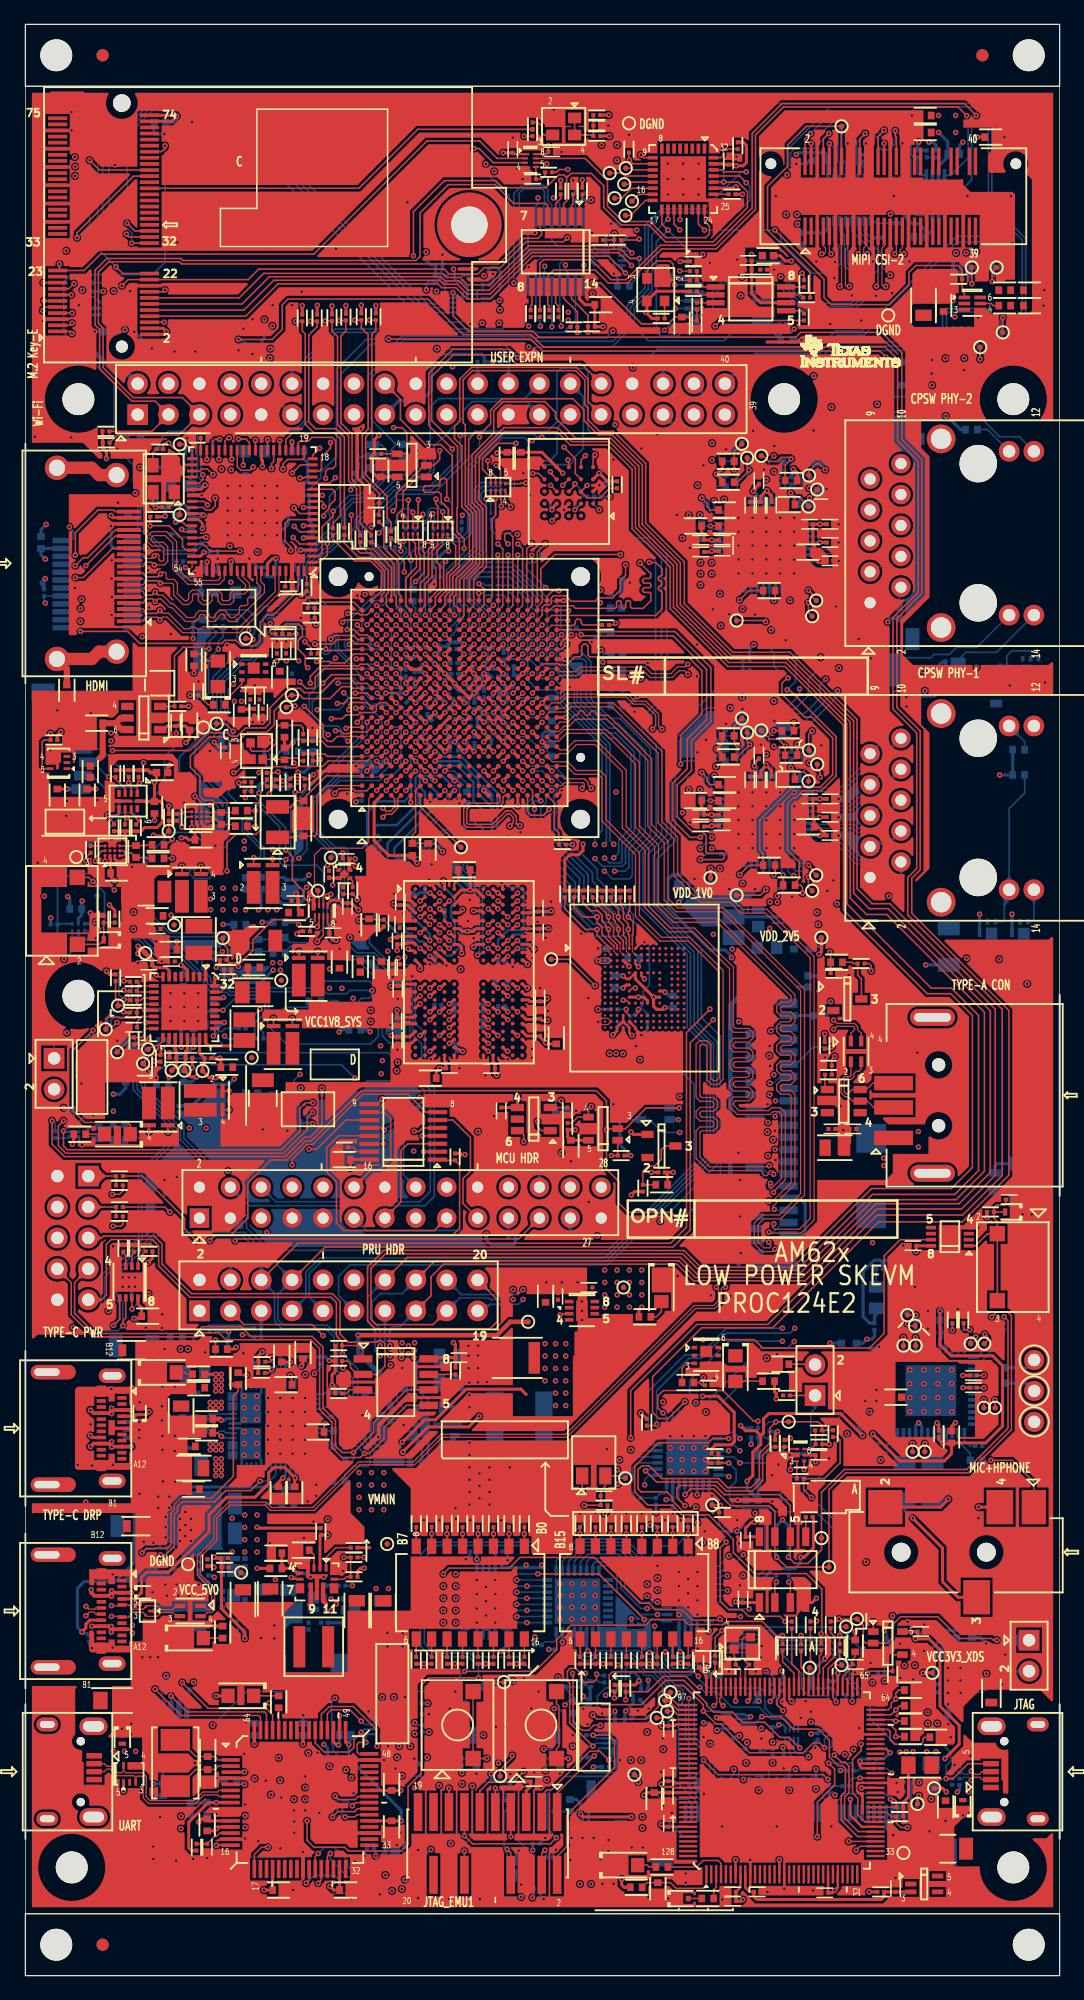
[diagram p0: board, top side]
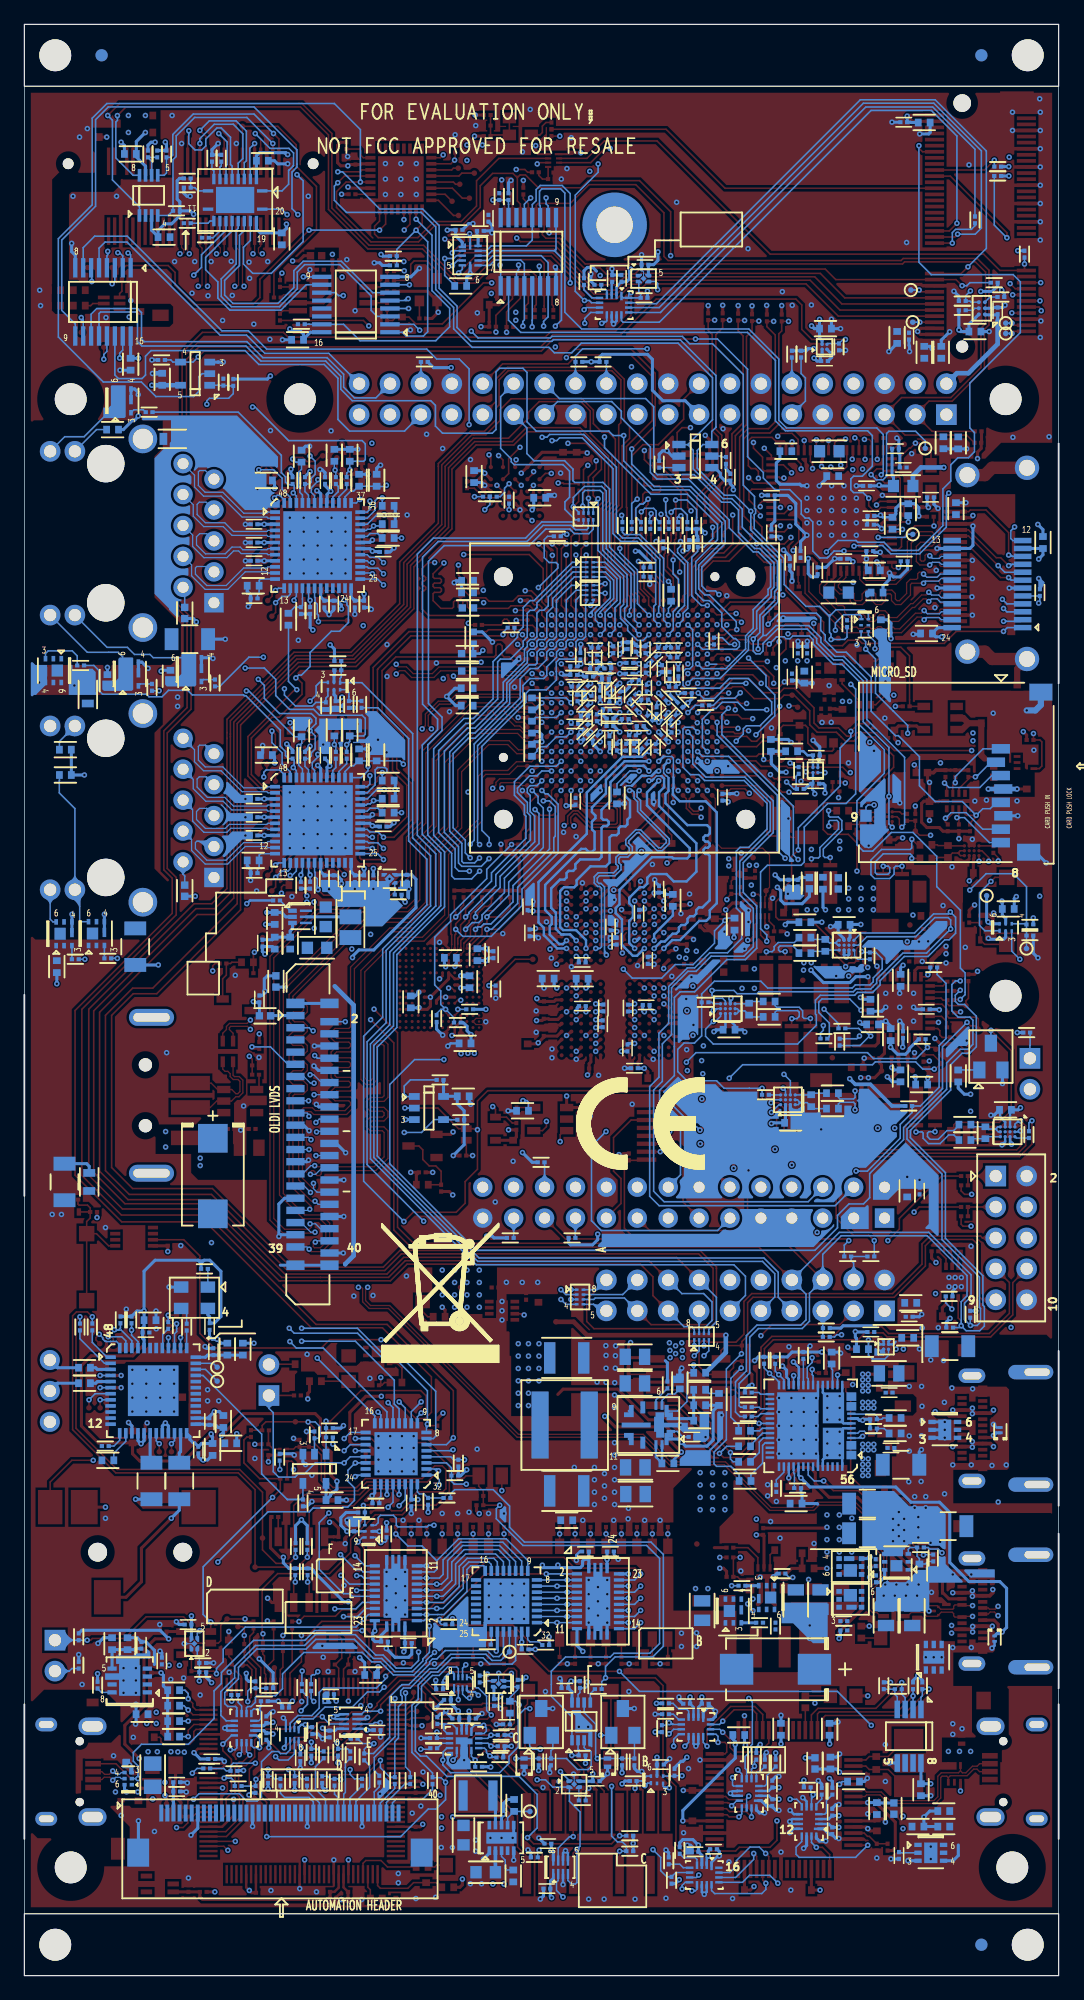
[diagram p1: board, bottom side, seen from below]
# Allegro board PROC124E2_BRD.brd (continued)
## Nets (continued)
LM61460_SW: C405.2 L9.1 U67.10(SW)
LM61460_VCC: C400.1 U67.2(VCC)
LPDDR4_CA0: U12.F5(DDR0_A0) U20.H2(CA0)
LPDDR4_CA1: U12.G5(DDR0_A1) U20.J2(CA1)
LPDDR4_CA2: U12.G4(DDR0_A2) U20.H9(CA2)
LPDDR4_CA3: U12.H4(DDR0_A3) U20.H10(CA3)
LPDDR4_CA4: U12.J5(DDR0_A4) U20.H11(CA4)
LPDDR4_CA5: U12.H5(DDR0_A5) U20.J11(CA5)
LPDDR4_CAL0: R375.1 U12.K4(DDR0_CAL0)
LPDDR4_CK_N: U12.K1(DDR0_CK0_N) U20.J9(CK_C)
LPDDR4_CK_P: U12.J1(DDR0_CK0) U20.J8(CK_T)
LPDDR4_CKE: U12.G3(DDR0_CKE0) U20.J4(CKE)
LPDDR4_CS: U12.H3(DDR0_CS0_N) U20.H4(CS)
LPDDR4_CS1_N: TP30.1(TP) U12.G1(DDR0_CS1_N)
LPDDR4_DMI0: U12.E3(DDR0_DM0) U20.C3(DMI0)
LPDDR4_DMI1: U12.R4(DDR0_DM1) U20.C10(DMI1)
LPDDR4_DQ0: U12.C2(DDR0_DQ0) U20.B2(DQ0)
LPDDR4_DQ1: U12.E4(DDR0_DQ1) U20.C2(DQ1)
LPDDR4_DQ2: U12.D3(DDR0_DQ2) U20.E2(DQ2)
LPDDR4_DQ3: U12.E5(DDR0_DQ3) U20.F2(DQ3)
LPDDR4_DQ4: U12.D2(DDR0_DQ4) U20.F4(DQ4)
LPDDR4_DQ5: U12.F3(DDR0_DQ5) U20.E4(DQ5)
LPDDR4_DQ6: U12.F1(DDR0_DQ6) U20.C4(DQ6)
LPDDR4_DQ7: U12.F2(DDR0_DQ7) U20.B4(DQ7)
LPDDR4_DQ8: U12.R3(DDR0_DQ8) U20.B11(DQ8)
LPDDR4_DQ9: U12.R2(DDR0_DQ9) U20.C11(DQ9)
LPDDR4_DQ10: U12.T2(DDR0_DQ10) U20.E11(DQ10)
LPDDR4_DQ11: U12.U2(DDR0_DQ11) U20.F11(DQ11)
LPDDR4_DQ12: U12.U3(DDR0_DQ12) U20.F9(DQ12)
LPDDR4_DQ13: U12.U4(DDR0_DQ13) U20.E9(DQ13)
LPDDR4_DQ14: U12.T4(DDR0_DQ14) U20.C9(DQ14)
LPDDR4_DQ15: U12.T5(DDR0_DQ15) U20.B9(DQ15)
LPDDR4_DQS0_N: U12.E1(DDR0_DQS0_N) U20.E3(DQS0_C)
LPDDR4_DQS0_P: U12.D1(DDR0_DQS0) U20.D3(DQS0_T)
LPDDR4_DQS1_N: U12.R1(DDR0_DQS1_N) U20.E10(DQS1_C)
LPDDR4_DQS1_P: U12.T1(DDR0_DQS1) U20.D10(DQS1_T)
LPDDR4_ODT_CA: R384.1 U20.G2(ODT_CA)
LPDDR4_RESET_N: R93.1 R94.2 U12.G2(DDR0_RESET0_N) U20.T11(RESET_N)
LPDDR4_ZQ: R100.2 U20.A5(ZQ)
LVDS_SHIELD: FL17.1 J22.SH1 J22.SH2 J22.SH3 J22.SH4
M2_LED1#: J2.6(LED_1#) TP94.1(TP)
M2_LED2#: J2.16(LED_2#) TP93.1(TP)
MCASP1_ACLKX: RA1.3 RA4.3 U12.K17(GPMC0_BE0N_CLE)
MCASP1_ACLKX_AUD: TP60.1(TP) U39.3(1B2) U66.38(BCLK)
MCASP1_ACLKX_BT: J2.8(PCM_CLK/I2S_SCK) U40.5(A4)
MCASP1_ACLKX_BUF: RA1.6 U39.4(1A) U40.7(B4)
MCASP1_ACLKX_HDMI: U11.45(SCK) U39.2(1B1)
MCASP1_AFSX: RA1.2 RA4.2 U12.P21(GPMC0_WAIT0)
MCASP1_AFSX_AUD: TP57.1(TP) U39.6(2B2) U66.39(WCLK)
MCASP1_AFSX_BT: J2.10(PCM_SYNC/I2S_WS) U40.4(A3)
MCASP1_AFSX_BUF: RA1.7 U39.7(2A) U40.8(B3)
MCASP1_AFSX_HDMI: U11.44(WS) U39.5(2B1)
MCASP1_AXR0: RA1.1 RA4.1 U12.J17(GPMC0_WEN)
MCASP1_AXR0_AUD: TP61.1(TP) U39.10(3B2) U66.40(DIN)
MCASP1_AXR0_BT: J2.12(PCM_IN/I2S_SD_IN) R281.2 U40.3(A2)
MCASP1_AXR0_BUF: RA1.8 U39.9(3A) U40.9(B2)
MCASP1_AXR0_HDMI: U11.41(SD0) U39.11(3B1)
MCASP1_AXR2: RA1.4 RA4.4 U12.K20(GPMC0_ADVN_ALE)
MCASP1_AXR2_AUD: R427.1 TP55.1(TP) U39.13(4B2)
MCASP1_AXR2_BT: J2.14(PCM_OUT/I2S_SD_OUT) U40.2(A1)
MCASP1_AXR2_BUF: RA1.5 U39.12(4A) U40.10(B1)
MCASP1_BUF_BT_EN: R10.2 U70.20(P23)
MCASP1_BUF_BT_EN_1V8: R10.1 R11.2 U40.12(OE)
MCASP1_FET_EN: R259.1 R260.2 U39.15(O\E\) U70.19(P22)
MCASP1_FET_SEL: J12.1 R172.1 U39.1(S) U70.21(P24)
MCU_GPIO0_15: J10.10 R584.2
MCU_GPIO0_15_R: R584.1 R585.2 U12.D5(MCU_MCAN1_TX)
MCU_GPIO0_16: J10.11 U12.D6(MCU_MCAN1_RX)
MCU_I2C0_SCL: J10.24 R416.2 U12.B9(MCU_I2C0_SCL)
MCU_I2C0_SDA: J10.21 R419.2 U12.A10(MCU_I2C0_SDA)
MCU_MCAN0_RX: J10.22 U12.C4(MCU_MCAN0_RX)
MCU_MCAN0_TX: J10.16 U12.C5(MCU_MCAN0_TX)
MCU_OSC0_XI: R70.2 R71.2 U12.A5(MCU_OSC0_XI)
MCU_OSC0_XO: R65.2 R66.2 U12.A6(MCU_OSC0_XO)
MCU_PORZ: R183.1 R471.2 TP71.1(TP) U12.B2(MCU_PORZ) U72.4(Y)
MCU_RESETSTATZ: J10.23 R420.1 TP20.1(TP) U12.A12(MCU_RESETSTATZ)
MCU_RESETZ: R496.2 TP82.1(TP) U12.C9(MCU_RESETZ) U81.7(1Y)
MCU_SAFETY_ERRORZ_1V8: TP36.1(TP) U12.B1(MCU_ERRORN) U19.3(A2)
MCU_SAFETY_ERRORZ_3V3: J10.26 U19.6(B2)
MCU_SPI0_CLK: J10.18 U12.B7(MCU_SPI0_CLK)
MCU_SPI0_CS1: J10.8 U12.C8(MCU_SPI0_CS1)
MCU_SPI0_D0: J10.6 U12.E8(MCU_SPI0_D0)
MCU_SPI0_D1: J10.4 U12.D8(MCU_SPI0_D1)
MCU_UART0_CTS: U12.B8(MCU_UART0_CTSN) U26.9(3A)
MCU_UART0_CTS_3V3: U26.11(3B1) U83.9(2A2)
MCU_UART0_CTS_CONN: J10.12 U26.10(3B2)
MCU_UART0_MUX_OE: R140.1 U26.15(O\E\)
MCU_UART0_MUX_SEL: J8.2 R142.2 U26.1(S)
MCU_UART0_RTS: U12.D7(MCU_UART0_RTSN) U26.12(4A)
MCU_UART0_RTS_3V3: U26.14(4B1) U83.7(1A2)
MCU_UART0_RTS_CONN: J10.17 U26.13(4B2)
MCU_UART0_RX_3V3: U26.2(1B1) U83.8(2A1)
MCU_UART0_RXD: U12.A8(MCU_UART0_RXD) U26.4(1A)
MCU_UART0_RXD_CONN: J10.13 U26.3(1B2)
MCU_UART0_TX_3V3: R516.2 U26.5(2B1) U83.6(1A1)
MCU_UART0_TXD: U12.B6(MCU_UART0_TXD) U26.7(2A)
MCU_UART0_TXD_CONN: J10.19 U26.6(2B2)
MFP0: R156.1 R426.2 U66.45(MFP0)
MFP1: R157.1 R425.2 U66.46(MFP1)
MFP2: TP58.1(TP) U66.47(MFP2)
MFP3: TP59.1(TP) U66.48(MFP3)
MIC_IN: C404.1 J14.1 R458.1 U66.12(MICDET)
MMC0_CLK: R91.1 R400.1 R401.2 U21.M6(CLK)
MMC1_CLK: J21.5(CLK) R49.1 R51.1 R88.1 U15.6(IO4)
MMC1_CLK_R: R49.2 U12.A20(MMC1_CLK)
MMC1_CMD: J21.3(CMD) R73.1 U12.C18(MMC1_CMD) U15.1(IO1)
MMC1_D0: J21.7(DAT0) R90.1 U12.A19(MMC1_DAT0) U15.8(IO6)
MMC1_D1: J21.8(DAT1) R89.1 U12.B19(MMC1_DAT1) U15.7(IO5)
MMC1_D2: J21.1(DAT2) R74.1 U12.B20(MMC1_DAT2) U15.2(IO2)
MMC1_D3: J21.2(CD/DAT3) R75.1 U12.C19(MMC1_DAT3) U15.3(IO3)
MMC1_SD_EN: R462.1 U52.1(A) U70.4(P03)
MMC1_SD_LS_EN: R61.1 U13.3(ON) U52.4(Y)
MMC1_SDCD: J21.9(CD) R67.1 U12.C15(MMC1_SDCD) U14.5(IO2)
MMC2_CLK: J2.9(SDIO_CLK/SYSCLK) R40.2 R272.1 R282.1
MMC2_CMD: R275.2 U12.C21(MMC2_CMD)
MMC2_D0: R277.2 U12.B21(MMC2_DAT0)
MMC2_D1: R276.2 U12.D21(MMC2_DAT1)
MMC2_D2: R274.2 U12.E19(MMC2_DAT2)
MMC2_D3: R273.2 U12.E20(MMC2_DAT3)
OLDI_RESETN: J22.8 R412.2 U62.4(Y)
OSC0: C154.2 U36.88(OSC0) Y3.3
OSC1: C153.2 U36.89(OSC1) Y3.1
OSPI0_CSN0: R334.2 U12.F19(OSPI0_CSN0)
OSPI0_LBCLK: R307.2 R318.1
OSPI0_LBCLKO_R: R318.2 U12.G18(OSPI0_LBCLKO)
OSPI_CLK: R309.1 R316.1 U10.B2(CLK)
OSPI_CS: R37.1 R334.1 U10.C2(C\S\)
OSPI_DQ0: R324.1 RA2.4 U10.D3(IO0)
OSPI_DQ1: R326.1 RA2.3 U10.D2(IO1)
OSPI_DQ2: R323.1 RA2.1 U10.C4(IO2/W\P\)
OSPI_DQ3: R325.1 RA2.2 U10.D4(IO3)
OSPI_DQ4: R321.1 RA3.4 U10.D5(IO4)
OSPI_DQ5: R322.1 RA3.2 U10.E3(IO5)
OSPI_DQ6: R320.1 RA3.3 U10.E2(IO6)
OSPI_DQ7: R319.1 RA3.1 U10.E1(IO7)
OSPI_DQS: R308.1 U10.C3(DS)
OSPI_DQS_SOC: R304.1 R305.1 R307.1 R308.2 U12.H20(OSPI0_DQS)
OSPI_RSTN: R35.1 U8.4(Y) U10.A4(R\E\S\E\T\)
P2_PP_EXT_ENABLE: R476.1 U68.49(GPIO17/PP_EXT2)
PD_GPIO0: R166.2 U68.16(GPIO0)
PD_HRESET: R466.1 U68.44(HRESET)
PD_M_I2C3_IRQ: R436.2 U68.23(I\2\C\3\_\I\R\Q\/GPIO7)
PD_M_I2C3_SCL: R146.1 R164.2 U68.21(I2C3_SCL/GPIO5)
PD_M_I2C3_SDA: R150.1 R161.2 U68.22(I2C3_SDA/GPIO6)
PD_MS_I2C1_IRQ: R443.2 U68.29(I\2\C\1\_\I\R\Q\)
PD_MS_I2C1_SCL: R144.1 R439.2 U68.27(I2C1_SCL)
PD_MS_I2C1_SDA: R148.1 R438.2 U68.28(I2C1_SDA)
PD_S_I2C2_SCL: R446.2 U68.32(I2C2_SCL)
PD_S_I2C2_SDA: R447.2 U68.33(I2C2_SDA)
PD_SPI_CLK: J23.7 R461.2 U30.6(CLK)
PD_SPI_MISO: J23.5 R160.2 R453.2 U30.2(DO(IO1))
PD_SPI_MOSI: J23.8 R459.2 U30.5(DI(IO0))
PD_SPI_SS: J23.9 R158.2 R464.2 U30.1(C\S\)
PD_VIN_3V3: C131.2 U68.5(VIN_3V3)
PMIC_GPO1: R577.2 U22.8(GPO1)
PMIC_INT_B: R122.1 R126.2 TP45.1(TP) U22.11(NINT)
PMIC_MODE: R117.1 R590.1 TP25.1(TP) TP42.1(TP) U12.C7(PMIC_LPM_EN0)
PMIC_POWERGOOD: R130.1 TP50.1(TP) U22.18(NRSTOUT) U89.1(A)
PMIC_STBY: R591.1 U22.31(MODE/STBY)
PORZ_OUT: R181.2 R345.1 TP18.1(TP) U12.E13(PORZ_OUT) U31.3(B) U52.6(C) U128.3(B)
PP1_CABLE: C125.1 U68.25(PP1_CABLE)
PP2_CABLE: R465.2 U68.46(PP2_CABLE)
PR0_PRU0_GPO0: J11.13 RA8.7 U12.K19(GPMC0_AD0)
PR0_PRU0_GPO1: J11.14 RA8.5 U12.L19(GPMC0_AD1)
PR0_PRU0_GPO2: J11.15 RA8.8 U12.L20(GPMC0_AD2)
PR0_PRU0_GPO3: J11.16 RA8.6 U12.L21(GPMC0_AD3)
PR0_PRU0_GPO4: J11.17 RA7.6 U12.M21(GPMC0_AD4)
PR0_PRU0_GPO5: J11.18 RA7.7 U12.L17(GPMC0_AD5)
PR0_PRU0_GPO6: J11.19 RA7.5 U12.L18(GPMC0_AD6)
PR0_PRU0_GPO7: J11.20 RA7.8 U12.M20(GPMC0_AD7)
PR0_PRU0_GPO11: J11.7 RA4.8
PR0_PRU0_GPO12: J11.9 RA4.7
PR0_PRU0_GPO14: J11.11 RA4.6
PRU_3V3_EN: R435.2 R589.1 U3.20(P23) U65.B2(ON)
PRU_DETECT: J11.3 R463.1 U70.3(P02)
PRU_INTN: J11.5 R432.2 R433.2
PRU_RESETZ: J11.4 R420.2 R421.2
PUSH BUTTON: SW1.3 U59.1(A)
RESETSTATZ: R174.1 R175.2 R403.1 R421.1 R455.1 R660.1 TP66.1(TP) U3.28(R\E\S\E\T\) U4.3(R\E\S\E\T\) U8.2(B) U12.E14(RESETSTATZ) U25.2(B) U47.2(B) U52.3(B) U62.2(B) U70.28(R\E\S\E\T\) U71.2(B)
SEL_XDS: U76.4(Y) U79.5(OE) U82.4(O\E\) U84.1(1\O\E\) U84.16(2\O\E\)
SEL_XDS110_INV: J19.8 R490.2 R492.1 U76.2(A) U80.2(A) U85.5(OE) U87.1(1\O\E\) U87.16(2\O\E\) U90.2(A) U95.4(O\E\)
SLOW_CLK: J2.50(SUSCLK_32KHZ) R1.2 R2.2
SOC_CLKIN: C16.1 R21.2 R28.2 R71.1
SOC_DVDD1V8: C86.1 C237.1 C238.1 C248.1 C293.1 C305.2 FL10.1 R121.3 U12.H9(VMON_1P8_SOC) U12.H15(VDDSHV6#H15) U12.H16(VDDSHV6#H16) U12.K15(VDDSHV1#K15) U12.K16(VDDSHV1#K16) U12.N7(VDDSHV4#N7) U12.P7(VDDSHV4#P7)
SOC_DVDD3V3: C71.1 C75.1 C236.1 C244.1 C247.1 C252.1 C259.1 C260.2 C261.1 C267.1 C272.1 C279.1 C289.1 C290.1 C291.1 R101.3 U12.F10(VDDSHV_MCU#F10) U12.F12(VDDSHV0#F12) U12.G10(VDDSHV_MCU#G10) U12.G13(VDDSHV0#G13) U12.K11(VMON_3P3_SOC) U12.N15(VDDSHV3#N15) U12.N16(VDDSHV3#N16) U12.R10(VDDA_3P3_USB) U12.R14(VDDSHV2#R14) U12.R15(VDDSHV2#R15)
SOC_EMU0: R239.2 U12.D9(EMU0) U79.2(A1) U85.2(A1)
SOC_EMU1: R238.2 U12.B10(EMU1) U79.3(A2) U85.3(A2)
SOC_GPIO1_49: R59.2 R60.1 U12.B15(MMC1_SDWP)
SOC_I2C0_SCL: J3.28 J11.6 J22.2 R125.1 R431.2 R446.1 U12.E12(I2C0_SCL) U28.6(SCL)
SOC_I2C0_SCL_PMIC: R125.2 U22.10(SCL)
SOC_I2C0_SDA: J3.27 J11.8 J22.3 R123.1 R424.2 R447.1 U12.D14(I2C0_SDA) U28.5(SDA)
SOC_I2C0_SDA_PMIC: R123.2 U22.9(SDA)
SOC_I2C1_SCL: R429.1 R474.2 TP74.1(TP) U3.29(SCL) U11.1(CSCL) U12.A17(I2C1_SCL) U16.A1(SCL) U16.C3(A1) U17.A1(SCL) U24.1(SCL) U32.7(SCLB) U48.1(SCL) U58.A1(SCL) U60.A1(SCL) U61.A1(SCL) U61.C3(A1) U63.A1(SCL) U70.29(SCL)
SOC_I2C1_SDA: R428.1 R473.2 TP72.1(TP) U3.30(SDA) U11.2(CSDA) U12.A16(I2C1_SDA) U16.A2(SDA) U17.A2(SDA) U24.6(SDA) U32.6(SDAB) U48.6(SDA) U58.A2(SDA) U60.A2(SDA) U60.B3(A0) U61.A2(SDA) U61.B3(A0) U63.A2(SDA) U70.30(SDA)
SOC_I2C1_TA_SCL: R480.2 R503.1 R540.1 U32.2(SCLA)
SOC_I2C1_TA_SDA: R479.2 R502.1 R545.1 U32.3(SDAA)
SOC_I2C2_SCL: R30.2 U4.12(SCL) U12.H18(GPMC0_CSN2)
SOC_I2C2_SDA: R29.2 U4.13(SDA) U12.H19(GPMC0_CSN3)
SOC_MMC0_CLK: R91.2 U12.Y1(MMC0_CLK)
SOC_MMC0_CMD: R398.2 U12.V3(MMC0_CMD) U21.M5(CMD)
SOC_MMC0_DAT0: R109.2 U12.V2(MMC0_DAT0) U21.A3(DAT0)
SOC_MMC0_DAT1: R111.2 U12.V1(MMC0_DAT1) U21.A4(DAT1)
SOC_MMC0_DAT2: R113.2 U12.W2(MMC0_DAT2) U21.A5(DAT2)
SOC_MMC0_DAT3: R107.2 U12.W1(MMC0_DAT3) U21.B2(DAT3)
SOC_MMC0_DAT4: R108.2 U12.Y2(MMC0_DAT4) U21.B3(DAT4)
SOC_MMC0_DAT5: R110.2 U12.W3(MMC0_DAT5) U21.B4(DAT5)
SOC_MMC0_DAT6: R112.2 U12.W4(MMC0_DAT6) U21.B5(DAT6)
SOC_MMC0_DAT7: R114.2 U12.V4(MMC0_DAT7) U21.B6(DAT7)
SOC_MMC2_CLK: R40.1 U12.E21(MMC2_CLK)
SOC_OSPI_DQ0: RA2.5 U12.F18(OSPI0_D0)
SOC_OSPI_DQ1: RA2.6 U12.G17(OSPI0_D1)
SOC_OSPI_DQ2: RA2.8 U12.F21(OSPI0_D2)
SOC_OSPI_DQ3: RA2.7 U12.F20(OSPI0_D3)
SOC_OSPI_DQ4: RA3.5 U12.G21(OSPI0_D4)
SOC_OSPI_DQ5: RA3.7 U12.H21(OSPI0_D5)
SOC_OSPI_DQ6: RA3.6 U12.G20(OSPI0_D6)
SOC_OSPI_DQ7: RA3.8 U12.J21(OSPI0_D7)
SOC_PORZ: R538.2 U72.3(B) U89.4(Y)
SOC_RGMII_MDC: R102.1 R644.1 U12.V17(MDIO0_MDC)
SOC_RGMII_MDIO: R98.1 R646.1 U12.U16(MDIO0_MDIO)
SOC_SPI0_CLK: U12.D12(SPI0_CLK) U43.4(1A)
SOC_SPI0_CS0: U12.C11(SPI0_CS0) U43.9(3A)
SOC_SPI0_D0: U12.C12(SPI0_D0) U43.7(2A)
SOC_SPI2_CLK: U12.D16(MCASP0_ACLKR) U42.7(2A) U44.8(2A1)
SOC_SPI2_CS0: U12.D15(MCASP0_AFSR) U42.4(1A) U44.6(1A1)
SOC_SPI2_D0: U12.B18(MCASP0_AXR3) U42.9(3A) U44.7(1A2)
SOC_SPI2_D1: U12.B17(MCASP0_AXR2) U42.12(4A) U44.9(2A2)
SOC_TCK: R508.1 R522.1 U12.C10(TCK)
SOC_TDI: U12.D10(TDI) U84.6(1A1) U87.9(2A2)
SOC_TDO: R359.1 U82.2(A1) U95.2(A1)
SOC_TDO_R: R359.2 U12.E10(TDO)
SOC_TMS: U12.B11(TMS) U84.8(2A1) U87.8(2A1)
SOC_TRST#: R519.1 U12.A11(TRSTN) U84.9(2A2) U87.6(1A1)
SOC_UART0_RX_3V3: U12.A13(UART0_RXD) U92.8(2A1)
SOC_UART0_TX_3V3: R554.2 U12.E11(UART0_TXD) U92.6(1A1)
SOC_UART1_CTS: TP12.1(TP) U42.10(3B2) U96.9(2A2)
SOC_UART1_CTS_BT: J2.34(UART_CTS) U44.14(1B2)
SOC_UART1_RTS: TP13.1(TP) U42.13(4B2) U96.7(1A2)
SOC_UART1_RTS_BT: J2.36(UART_RTS) U44.12(2B2)
SOC_UART1_RX_BT: J2.22(UART_RXD) U44.15(1B1)
SOC_UART1_RXD: TP9.1(TP) U42.3(1B2) U96.8(2A1)
SOC_UART1_TX_BT: R261.2 U44.13(2B1)
SOC_UART1_TXD: R566.2 TP10.1(TP) U42.6(2B2) U96.6(1A1)
SOC_USB0_DM: L5.4(OUT2) U12.AA11(USB0_DM)
SOC_USB0_DP: L5.1(IN1) U12.Y10(USB0_DP)
SOC_USB0_DRVVBUS: R166.1 R475.1 R592.1 U12.D17(USB0_DRVVBUS)
SOC_USB0_RCALIB: R366.1 U12.T8(USB0_RCALIB)
SOC_USB0_VBUS: R143.1 R145.1 U12.V10(USB0_VBUS)
SOC_USB1_DM: L4.1(IN1) U12.W8(USB1_DM)
SOC_USB1_DP: L4.4(OUT2) U12.W9(USB1_DP)
SOC_USB1_DRVVBUS: R131.1 R132.1 U12.E16(USB1_DRVVBUS)
SOC_USB1_RCALIB: R361.1 U12.V9(USB1_RCALIB)
SOC_USB1_VBUS: R118.1 R120.1 U12.U9(USB1_VBUS)
SOC_VDDSHV5_SDIO: C257.1 FL9.2 U12.F14(VDDSHV5#F14) U12.G14(VDDSHV5#G14)
SOC_VOUT0_DATA0: U11.32(D0) U12.R21(VOUT0_DATA0)
SOC_VOUT0_DATA1: U11.31(D1) U12.P18(VOUT0_DATA1)
SOC_VOUT0_DATA2: U11.30(D2) U12.R18(VOUT0_DATA2)
SOC_VOUT0_DATA3: U11.29(D3) U12.R19(VOUT0_DATA3)
SOC_VOUT0_DATA4: U11.28(D4) U12.R20(VOUT0_DATA4)
SOC_VOUT0_DATA5: U11.27(D5) U12.T20(VOUT0_DATA5)
SOC_VOUT0_DATA6: U11.25(D6) U12.T21(VOUT0_DATA6)
SOC_VOUT0_DATA7: U11.24(D7) U12.T19(VOUT0_DATA7)
SOC_VOUT0_DATA8: U11.23(D8) U12.U21(VOUT0_DATA8)
SOC_VOUT0_DATA9: U11.20(D9) U12.R17(VOUT0_DATA9)
SOC_VOUT0_DATA10: U11.19(D10) U12.T18(VOUT0_DATA10)
SOC_VOUT0_DATA11: U11.18(D11) U12.U20(VOUT0_DATA11)
SOC_VOUT0_DATA12: U11.17(D12) U12.U19(VOUT0_DATA12)
SOC_VOUT0_DATA13: U11.16(D13) U12.V21(VOUT0_DATA13)
SOC_VOUT0_DATA14: U11.15(D14) U12.U18(VOUT0_DATA14)
SOC_VOUT0_DATA15: U11.14(D15) U12.V20(VOUT0_DATA15)
SOC_VOUT0_DATA16: RA6.8 U11.13(D16) U12.N20(GPMC0_AD8)
SOC_VOUT0_DATA17: RA6.7 U11.11(D17) U12.N21(GPMC0_AD9)
SOC_VOUT0_DATA18: RA5.8 U11.10(D18) U12.M17(GPMC0_AD10)
SOC_VOUT0_DATA19: RA5.5 U11.9(D19) U12.N18(GPMC0_AD11)
SOC_VOUT0_DATA20: RA5.7 U11.8(D20) U12.N17(GPMC0_AD12)
SOC_VOUT0_DATA21: RA5.6 U11.7(D21) U12.N19(GPMC0_AD13)
SOC_VOUT0_DATA22: RA6.6 U11.6(D22) U12.P19(GPMC0_AD14)
SOC_VOUT0_DATA23: RA6.5 U11.4(D23) U12.P20(GPMC0_AD15)
SOC_VOUT0_DE: U11.33(DE) U12.T17(VOUT0_DE)
SOC_VOUT0_HSYNC: U11.34(HSYNC) U12.W21(VOUT0_HSYNC)
SOC_VOUT0_PCLK: R329.1 U12.U17(VOUT0_PCLK)
SOC_VOUT0_VSYNC: U11.35(VSYNC) U12.T16(VOUT0_VSYNC)
SOC_WARM_RESETZ: R527.1 TP89.1(TP) U12.E15(RESET_REQZ) U81.2(3Y)
SOC_WLAN_SDIO_RST: U2.7(B1) U3.24(P27)
SPI0_FET_OE: R292.2 U3.18(P21) U43.15(O\E\)
SPI0_FET_SEL: R263.1 R264.2 U3.17(P20) U43.1(S)
SPI_HOLDN: R163.2 U30.7(H\O\L\D\(IO3))
SPI_WPN: R171.2 U30.3(W\P\(IO2))
SW_2V5: L8.1 U57.5(SW)
SYS_BOOTMODE0: R191.1 SW3.1 U74.1(P00) U75.10(A8)
SYS_BOOTMODE1: R190.1 SW3.2 U74.2(P01) U75.9(A7)
SYS_BOOTMODE2: R189.1 SW3.3 U74.3(P02) U75.8(A6)
SYS_BOOTMODE3: R188.1 SW3.4 U74.4(P03) U75.7(A5)
SYS_BOOTMODE4: R187.1 SW3.5 U74.5(P04) U75.6(A4)
SYS_BOOTMODE5: R186.1 SW3.6 U74.6(P05) U75.5(A3)
SYS_BOOTMODE6: R185.1 SW3.7 U74.7(P06) U75.4(A2)
SYS_BOOTMODE7: R184.1 SW3.8 U74.8(P07) U75.3(A1)
SYS_BOOTMODE8: R199.1 SW4.1 U73.10(A8) U74.9(P10)
SYS_BOOTMODE9: R198.1 SW4.2 U73.9(A7) U74.10(P11)
SYS_BOOTMODE10: R197.1 SW4.3 U73.8(A6) U74.11(P12)
SYS_BOOTMODE11: R196.1 SW4.4 U73.7(A5) U74.12(P13)
SYS_BOOTMODE12: R195.1 SW4.5 U73.6(A4) U74.13(P14)
SYS_BOOTMODE13: R194.1 SW4.6 U73.5(A3) U74.14(P15)
SYS_BOOTMODE14: R193.1 SW4.7 U73.4(A2) U74.15(P16)
SYS_BOOTMODE15: R192.1 SW4.8 U73.3(A1) U74.16(P17)
SYSBOOT_BUF_ENZ: R175.1 R181.1 U34.1(A)
TCA6424_EXP_INT: R489.1 U74.32(I\N\T\)
TEMP_DIODE_P: TP21.1(TP) U12.F8(RSVD3)
TEST_GPIO1: Q12.1(G) R212.2 R543.1 R551.1
TEST_GPIO2: R216.2 R524.1 R526.1 U70.18(P21)
TEST_GPIO3: J16.1 R213.2 R485.1 R552.1 TP77.1(TP) U34.2(B)
TEST_GPIO4: R219.2 R520.1 R529.1 TP78.1(TP) U74.28(R\E\S\E\T\)
TEST_PORZN: R211.2 R542.1 R550.1 U72.6(C)
TEST_POWERDOWN: R207.1 R217.2 R541.1 R549.1 U59.3(B)
TEST_WARMRESETN: Q13.1(G) R218.2 R523.1 R525.1
TM4C129_TCK: TP86.1(TP) U36.100(PC0/TCK/SWCLK)
TM4C129_TDI: TP84.1(TP) U36.98(PC2/TDI)
TM4C129_TDO: TP83.1(TP) U36.97(PC3/TDO/SWO)
TM4C129_TMS: TP85.1(TP) U36.99(PC1/TMS/SWDIO)
TMP1_ADD0: R302.1 U48.5(ADD0)
TMP1_ADD1: R303.1 U48.3(ADD1)
TMP2_ADD1: R137.1 U24.3(ADD1)
TPS65219 EN: R379.1 R382.2 R405.1 TP100.1(TP) U59.4(Y)
TPS65219_GPO: R128.1 TP47.1(TP) U22.16(GPIO)
TPS65219_GPO2: R404.1 R411.2 R588.1 TP48.1(TP) U22.17(GPO2) U29.3(ON)
TPS630702_EN: R207.2 R210.1 R577.1 R578.1 U33.14(EN)
TS_INT#: J22.9 R151.2 U70.16(P17)
UART1_FET_BUF_EN: R289.1 U41.2(A) U44.1(1\O\E\) U44.16(2\O\E\) U70.11(P12)
UART1_FET_BUF_EN_INV: U41.4(Y) U42.15(O\E\)
UART1_FET_SEL: R179.1 R180.2 U42.1(S) U70.22(P25)
UART_SHIELD: J17.6(SH1) J17.7(SH2) J17.8(SH3) J17.9(SH4) R242.2
USB_DM: J2.5(USB_D-) TP95.1(TP)
USB_DP: J2.3(USB_D+) TP96.1(TP)
USB_TYPEA_EARTH: C376.1 J9.SH1 J9.SH2 R417.1
USB_TYPEACONN1_DM: J9.2(D-) L4.2(IN2) U23.5(D1)
USB_TYPEACONN1_DP: J9.3(D+) L4.3(OUT1) U23.6(D2)
USB_TYPEC1_EARTH: C387.1 J13.SH1 J13.SH2 J13.SH3 J13.SH4 R159.1
USB_TYPEC2_EARTH: C416.1 J15.SH1 J15.SH2 J15.SH3 J15.SH4 R201.1
USBC_CONN1_CC1: C121.1 D5.1(CATHODE) J13.A5(CC1) U68.24(C1_CC1)
USBC_CONN1_CC2: C120.1 D10.1(CATHODE) J13.B5(CC2) U68.26(C1_CC2)
USBC_CONN2_CC1: C139.1 D6.1(CATHODE) J15.A5(CC1) U68.45(C2_CC1)
USBC_CONN2_CC2: C138.1 D11.1(CATHODE) J15.B5(CC2) U68.47(C2_CC2)
USBC_CONN2_DM: D7.3(IO2) J15.A7(D-_1) J15.B7(D-_2) L5.3(OUT1)
USBC_CONN2_DP: D7.2(IO1) J15.A6(D+_1) J15.B6(D+_2) L5.2(IN2)
VHDMI_AVCC_1V2: C220.1 C221.1 C223.1 FB3.1 U11.60(AVCC12_1) U11.66(AVCC12_2)
VHDMI_CVCC_1V2: C197.1 C205.1 C206.1 C214.1 C215.1 C219.1 FB2.1 U11.5(CVCC12_1) U11.12(CVCC12_2) U11.26(CVCC12_3) U11.42(CVCC12_4) U11.47(CVCC12_5) U11.53(CVCC12_6)
VHDMI_IOVCC_3V3: C198.1 C213.1 C222.1 FB1.1 R41.1 R48.1 R310.1 R317.1 U11.3(IOVCC1) U11.21(IOVCC2) U11.46(IOVCC3)
VLDO_CSI_1V8: R19.1 U7.5(OUT2)
VLDO_CSI_3V3: R16.1 U7.6(OUT1)
VMAIN: C128.1 C136.1 C137.1 C147.1 C148.1 C391.1 C395.1 C406.1 C410.1 C422.1 C475.1 R203.1 R442.1 R565.1 TP73.1(TP) U33.12(VIN) U67.8(VIN1) U67.12(VIN2) U68.1(PP_HV2) U68.11(PP_HV1) U93.2(VIN)
VPHY_3V3_FT4232: C456.2 FL19.1 U37.4(VPHY)
VPLL_3V3_FT4232: C464.2 FL20.1 R251.2 U37.9(VPLL)
VPP_1V8: C68.2 TP33.1(TP) U12.F7(VPP) U18.1(OUT)
VPP_LDO_EN: R103.1 R104.1 U70.5(P04)
VSEL_SD_SOC: R127.1 TP46.1(TP) U12.M19(GPMC0_CLK) U22.12(VSEL_SD/VSEL_DDR)
WKUP_LFOSCO_XI: C62.1 U12.A2(WKUP_LFOSC0_XI) Y2.1
WKUP_LFOSCO_XO: C53.1 U12.A3(WKUP_LFOSC0_XO) Y2.2
WKUP_UART0_CTS_3V3: U12.A7(WKUP_UART0_CTSN) U91.9(2A2)
WKUP_UART0_RTS_3V3: U12.B4(WKUP_UART0_RTSN) U91.7(1A2)
WKUP_UART0_RX_3V3: U12.B5(WKUP_UART0_RXD) U91.8(2A1)
WKUP_UART0_TX_3V3: R528.2 U12.C6(WKUP_UART0_TXD) U91.6(1A1)
WL_LT_EN: R595.1 U3.9(P10)
WLAN_EN: J2.56(W_DISABLE1#) R257.1 U2.6(B2)
WLAN_EN_SOC: U2.3(A2) U12.D20(MMC2_SDCD)
WLAN_IRQ: J2.62(ALERT#) R333.1 U12.C20(MMC2_SDWP)
WLAN_SDIO_RST: J2.23(SDIO_RESET#/TX_BLANKING) R262.1 U2.2(A1)
XDS110_DIR: R509.2 U84.4(1DIR) U84.5(2DIR)
XDS110_EMU0: R250.2 U36.42(PF0) U85.7(B1)
XDS110_EMU1: R249.2 U36.43(PF1) U85.6(B2)
XDS110_TCK: U36.35(PA2/SSI0CLK) U84.14(1B2)
XDS110_TDI: U36.38(PA5/SSI0XDAT1) U84.15(1B1)
XDS110_TDO: U36.37(PA4/SSI0XDAT0) U82.7(B1)
XDS110_TMS: U36.36(PA3/SSI0FSS) U84.13(2B1)
XDS110_TRST#: U36.40(PA6) U84.12(2B2)
XDS_RSTN: R497.1 R504.1 TP79.1(TP) U36.70(R\S\T\)
XDS_SHIELD: C168.2 J18.6(SH1) J18.7(SH2) J18.8(SH3) J18.9(SH4) R241.2
XDS_USB_DM: J18.2(D-) U36.93(PL7/USB0DM) U88.5(IO4)
XDS_USB_DP: J18.3(D+) U36.94(PL6/USB0DP) U88.4(IO3)
XDS_USB_ID: J18.4(ID) R220.2 U88.2(IO2)
XDS_USB_VBUS: C163.1 C440.1 D9.2 J18.1(VBUS) R253.1 R493.1 R498.1 TP90.1(TP) U78.1(IN1) U78.2(IN2) U88.6(VCC)
XDS_VREF: C169.1 C173.2 R255.2 U36.9(VREFA+) U38.3(CATHODE)
N15951745: C5.1 R581.2 R582.2 U1.1(TRI-STATE) U1.4(VDD)
N15952254: R1.1 U1.3(OUTPUT)
N16839912: C341.1 R391.1 U58.D3(IN+)
N16839940: C371.1 R408.1 U61.D3(IN+)
N16839975: C358.1 R396.1 U60.D3(IN+)
N16856152: C157.1 U37.3(OSCO) Y4.2
N16856224: C156.1 U37.2(OSCI) Y4.1
N16857368: C474.2 U94.2(NR/FB)
N16878333: R556.2 U92.5(2DIR)
N16878339: R557.1 U92.4(1DIR)
N16878497: R124.1 TP43.1(TP) U21.H5(DS)
N16893179: R513.2 U83.5(2DIR)
N16893185: R510.1 U83.4(1DIR)
N16894003: R533.2 U91.5(2DIR)
N16894009: R534.1 U91.4(1DIR)
N16906426: C43.2 R70.1 Y1.1
N16906432: C41.2 R65.1 Y1.3
N16927060: R48.2 U11.72(CI2CA)
N16927228: R47.1 U11.69(IO_SEL)
N16927289: R32.2 U11.36(SPDIF)
N16929458: TP65.1(TP) U66.7(LINE2L+)
N16929460: TP64.1(TP) U66.8(LINE2L-)
N16929474: R427.2 U66.41(DOUT)
N16929699: C124.1 U66.4(LINE1L-)
N16929703: C126.1 U66.6(LINE1R-)
N16929744: TP69.1(TP) U66.19(HPLCOM)
N16929747: TP68.1(TP) U66.22(HPRCOM)
N16929749: TP102.1(TP) U66.35(GPIO1)
N16929751: TP103.1(TP) U66.34(GPIO2)
N16931396: R291.2 U45.B2(CL)
N16931420: R288.1 U45.C1(OC)
N16943223: R17.1 U6.2(1G)
N16947096: R27.1 U5.1(TRI-STATE)
N16990175: J24.27 R550.2
N16990176: J24.30 R551.2
N16990179: J24.31 R526.2
N16990180: J24.32 R552.2
N16990215: R200.1 U32.5(EN)
N16990246: J24.26 R549.2
N16990247: J24.28 R525.2
N16990252: J24.33 R529.2
N16994873: R494.2 U80.4(Y)
N16994875: R558.2 U90.4(Y)
N16995245: C444.1 R512.2
N16997746: R247.1 U36.59(RBAIS)
N17012627: R385.2 U57.1(EN)
N17029933: LD8.2(ANODE) R165.2
N17030208: R508.2 U84.7(1A2)
N17031262: LD9.2(ANODE) R214.2
N17078351: R225.1 SW3.13
N17078353: R226.1 SW3.14
N17078355: R227.1 SW3.15
N17078357: R228.1 SW3.16
N17078758: R231.1 SW4.11
N17078760: R232.1 SW4.12
N17078762: R233.1 SW4.13
N17078764: R234.1 SW4.14
N17078766: R229.1 SW4.9
N17078768: R230.1 SW4.10
N17078770: R235.1 SW4.15
N17078778: R236.1 SW4.16
N17078974: J16.2 R491.2
N17084256: R221.1 SW3.9
N17084257: R222.1 SW3.10
N17084258: R223.1 SW3.11
N17084259: R224.1 SW3.12
N17110597: TP34.1(TP) U55.13(VDDA1P8#13)
N17133547: FL16.2 J7.2(VCC)
N17137240: J7.11 R365.2
N17140854: R383.2 U56.3(EN)
N17153379: R92.2 R106.1
N17153381: R96.2 R106.4
N17153415: R136.1 R415.2
N17153417: R136.4 R413.2
N17153507: R84.2 R101.1
N17153509: R87.2 R101.4
N17153511: C58.2 R87.1 U16.D1(BUS) U16.D2(IN-)
N17153515: C58.1 R84.1 U16.D3(IN+)
N17153617: R121.1 R391.2
N17153619: R121.4 R388.2
N17153623: R134.1 R408.2
N17153625: R134.4 R410.2
N17153667: R129.1 R396.2
N17153669: R129.4 R399.2
N17153681: C65.1 R92.1 U17.D3(IN+)
N17153685: C65.2 R96.1 U17.D1(BUS) U17.D2(IN-)
N17153701: C374.2 R413.1 U63.D1(BUS) U63.D2(IN-)
N17153703: C374.1 R415.1 U63.D3(IN+)
N17153749: C341.2 R388.1 U58.D1(BUS) U58.D2(IN-)
N17153787: C371.2 R410.1 U61.D1(BUS) U61.D2(IN-)
N17153799: C358.2 R399.1 U60.D1(BUS) U60.D2(IN-)
N17153878: R414.1 U63.A3(ALERT)
N17153949: R392.1 U58.A3(ALERT)
N17153951: R409.1 U61.A3(ALERT)
N17154063: R397.1 U60.A3(ALERT)
N17167245: R377.2 U55.32(RX_CLK)
N17253649: L10.1 U93.9(SW)
N17253673: R559.1 TP104.1(TP) U93.7(PG)
N17253694: R565.2 U93.3(EN)
N17269599: R174.2 R178.1 U31.6(C)
N17275147: R430.2 U64.3(OUTPUT)
N17277957: C396.1 R444.2
N17285208: R342.1 U50.5(LS_OE) U50.12(CT_HPD)
N17337952: R103.2 U18.3(EN)
N17370891: R437.2 U68.17(GPIO1)
N17378539: LD10.1(CATHODE) R243.2
N17479799: R498.2 U78.8(EN)
N17479805: C429.2 R486.1 R487.2 U78.5(NR/FB)
N17479881: C152.2 R215.1 U36.68(VBAT)
N17481587: LD11.2(ANODE) R252.2
N17481598: C151.2 R493.2 U36.96(PB1/USB0VBUS)
N17481613: R220.1 U36.95(PB0/USB0ID)
N17481619: R253.2 R254.1 U36.1(PD0/AIN15)
N17481621: R246.2 R518.1 U36.60(PK7)
N17481627: R256.1 U36.3(PD2/AIN13)
N17481631: LD12.2(ANODE) R256.2
N17481633: R240.2 R507.1 U36.63(PK4)
N17481635: R245.2 R515.1 U36.61(PK6)
N17481637: R252.1 U36.4(PD3/AIN12)
N17481641: R244.2 R511.1 U36.62(PK5)
N17492093: R116.2 U19.5(OE)
N17492111: J8.1 R402.1
N17498937: R428.2 U66.2(SDA)
N17498940: R429.2 U66.1(SCL)
N17653582: Q5.3(G) R352.2
N17726648: D3.3(C) R145.2 R147.1
N17796705: Q6.3(G) R393.2
N17796716: Q7.3(G) R394.2
N17827086: J23.1 R144.2 R146.2
N17827089: J23.3 R148.2 R150.2
N17849698: C143.1 Q10.1(S1) Q10.2(S2) Q10.5(S3) Q10.6(S4) Q10.8(S5) Q11.1(S1) Q11.2(S2) Q11.5(S3) Q11.6(S4) Q11.8(S5) R477.1
N17850096: C143.2 C144.2 C425.2 Q10.3(G) Q11.3(G) R208.2 R477.2 R482.1 R484.2
N17935978: Q9.3(G) R475.2 R476.2 R478.1
N17936309: Q9.1(D1) Q9.2(D2) Q9.5(D3) Q9.6(D4) Q9.8(D5) R482.2
N18374616: R553.2 U36.49(PG0)
N18374619: R536.2 U36.50(PG1)
N18374622: R502.2 U36.81(PL0)
N18374625: R503.2 U36.82(PL1)
N18374804: J24.36 R540.2
N18374807: J24.37 R544.2
N18374810: J24.38 R545.2
N18374813: J24.39 R546.2
N18516151: R95.1 U17.A3(ALERT)
N18520654: R85.1 U16.A3(ALERT)
N18571509: R564.2 U96.5(2DIR)
N18571515: R561.1 U96.4(1DIR)
N18576337: R372.2 U55.39(GPIO_0)
N18576340: R371.2 U55.40(GPIO_1)
N18736007: C404.2 U66.14(MIC3R)
N18736028: R458.2 U66.13(MICBIAS)
N18902581: R422.2 U64.1(INH)
N18904630: LD3.1(CATHODE) Q1.1(D1) Q1.2(D2) Q1.5(D3) Q1.6(D4) Q1.8(D5)
N18904632: Q1.3(G) R60.2
N18904656: LD3.2(ANODE) R56.1
N18904815: LD7.1(CATHODE) Q3.1(D1) Q3.2(D2) Q3.5(D3) Q3.6(D4) Q3.8(D5)
N18904817: Q3.3(G) R168.2
N18904841: LD7.2(ANODE) R167.1
N19081973: R39.1 U9.1(INH)
N19082749: R34.1 U9.3(OUTPUT)
N19361213: R403.2 U22.28(MODE/RESET)
N19361868: L3.1 U22.27(LX_B3)
N19361874: L2.1 U22.29(LX_B2)
N19361880: L1.1 U22.2(LX_B1_1) U22.3(LX_B1_2)
N19361937: C69.2 D1.2 R105.2 SW1.2
N19362078: C96.1 U22.14(VDD1P8)
N19806973: R522.2 U87.7(1A2)
N20199452: D2.3(C) R118.2 R119.1
N20506305: L6.1 U33.11(L1)
N20506307: L6.2 U33.9(L2)
N20506388: R481.1 U33.6(FB2)
N20506392: R203.2 U33.1(PS/SYNC)
N20506511: C142.1 U33.3(VAUX)
N20878915: R8.2 U4.1(A0)
N20878927: R7.1 U4.2(A1)
N20878931: R25.2 U4.11(I\N\T\)
N20900570: R21.1 U6.3(Y0)
N20900572: R15.1 U6.8(Y1)
N20900574: R26.1 U6.5(Y2)
N20900809: R18.1 U6.7(Y3)
N20933818: R280.2 U44.4(1DIR)
N20933822: R278.1 U44.5(2DIR)
N20936712: J12.2 R162.2
N21016640: TP29.1(TP) U55.48(VDDA1P8#48)
N21029653: R5.2 R595.2 U2.5(OE)
N21030238: LD6.2(ANODE) R155.1
N21068099: R132.2 U23.1(EN)
N21079949: TP37.1(TP) U55.14(XO)
N21083676: R459.1 U68.37(SPI_MOSI/GPIO9)
N21083677: R453.1 U68.36(SPI_MISO/GPIO8)
N21083678: R464.1 U68.39(S\P\I\_\S\S\/GPIO11)
N21083679: R461.1 U68.38(SPI_CLK/GPIO10)
N21117349: LD5.1(CATHODE) Q8.3(COLLECTOR)
N21117357: LD5.2(ANODE) R139.1
N21117537: Q8.1(BASE) R406.2
N21197992: TP8.1(TP) U3.16(P17)
N21197993: TP7.1(TP) U3.15(P16)
N21197994: TP5.1(TP) U3.13(P14)
N21197995: TP6.1(TP) U3.14(P15)
N21197996: TP4.1(TP) U3.12(P13)
N21198784: TP3.1(TP) U3.11(P12)
N21608525: J2.32(UART_TXD) R261.1
N21763900: R570.2 U98.13(B7)
N21763905: R569.2 U98.12(B8)
N21763910: R572.2 U98.9(A8)
N21763915: R571.2 U98.8(A7)
N21834326: R217.1 U36.78(PM0)
N21834328: R211.1 U36.77(PM1)
N21834330: R218.1 U36.76(PM2)
N21834332: R212.1 U36.74(PM4)
N21834361: R216.1 U36.73(PM5)
N21834363: R213.1 U36.72(PM6)
N21834365: R219.1 U36.71(PM7)
N21834376: TP80.1(TP) U36.75(PM3)
N22163762: C507.1 R587.1 U125.B1(VOUT)
N22221349: Q15.3(G) R592.2
N22221705: C532.2 Q14.1(D1) Q14.2(D2) Q14.5(D3) Q14.6(D4) Q14.8(D5)
N22234960: Q15.1(D1) Q15.2(D2) Q15.5(D3) Q15.6(D4) Q15.8(D5) R593.1 R594.1
N22235133: Q14.3(G) R594.2
N22622854: FL22.2 J27.2(VCC)
N22622886: R628.2 U127.40(GPIO_1)
N22622904: R627.2 U127.39(GPIO_0)
N22623025: R632.2 U127.32(RX_CLK)
N22623655: TP125.1(TP) U127.48(VDDA1P8#48)
N22623691: TP126.1(TP) U127.14(XO)
N22623898: TP127.1(TP) U127.13(VDDA1P8#13)
N22624142: Q19.3(G) R629.2
N22624353: Q20.3(G) R641.2
N22624355: Q21.3(G) R651.2
N22624429: J27.11 R647.2
N22624465: R657.1 R660.2 U128.6(C)
N22727847: R316.2 U12.G19(OSPI0_CLK)

Pads without a net: D2 2; D3 2; J1 1 3 25 26 27 28 29 31 33 35 37 39; J2 21 35 37 38 40 41 42 43 44 46 47 48 49 52 53 55 58 59 60 61 64 65 66 67 68 70 71 73 SH3; J5 14; J11 10 12; J13 A2 A3 A6 A7 A8 A10 A11 B2 B3 B6 B7 B8 B10 B11; J15 A2 A3 A8 A10 A11 B2 B3 B8 B10 B11; J17 4; J19 17 18 19; J22 4 5; J23 4 6; J24 4 5 6 8 9 10 11 12 13 14 15 17 18 19 20 21 22 23 24 29 35; U3 1 2 3 4 5 6 7 8 21 22; U10 A2 A3 A5 B1 B5 C5; U12 A9 B3 C3 E6 E9 E17 H2 J2 J3 J4 K2 K5 L2 L3 L4 L5 M1 M2 M3 M4 M5 N1 N2 N3 N4 N5 P2 P4 P5 R6 T13 T14; U13 4; U14 2 3; U15 4 9; U16 B2 C2; U17 B2 C2; U20 A1 A2 A8 A11 A12 AA1 AA2 AA4 AA9 AA11 AA12 AB1 AB2 AB11 AB12 B1 B12 G11 H3 J5 K5 K8 N5 N8 P2 P4 P5 P8 P9 P11 R2 R3 R4 R9 R10 R11 T2 U2 U4 U9 U11 V2 V3 V4 V9 V10 V11 W3 W10 Y2 Y3 Y4 Y9 Y10 Y11; U21 A1 A2 A7 A8 A9 A10 A11 A12 A13 A14 B1 B7 B8 B9 B10 B11 B12 B13 B14 C1 C3 C5 C7 C8 C9 C10 C11 C12 C13 C14 D1 D2 D3 D4 D12 D13 D14 E1 E2 E3 E5 E8 E9 E10 E12 E13 E14 F1 F2 F3 F10 F12 F13 F14 G1 G2 G3 G10 G12 G13 G14 H1 H2 H3 H12 H13 H14 J1 J2 J3 J12 J13 J14 K1 K2 K3 K6 K7 K10 K12 K13 K14 L1 L2 L3 L12 L13 L14 M1 M2 M3 M7 M8 M9 M10 M11 M12 M13 M14 N1 N3 N6 N7 N8 N9 N10 N11 N12 N13 N14 P1 P2 P7 P8 P9 P10 P11 P12 P13 P14; U24 5; U27 2 3 5 6; U29 6; U35 2; U36 2 5 6 11 12 13 14 15 18 19 20 21 22 23 24 25 27 29 30 31 32 33 34 41 44 45 46 53 54 56 57 65 67 83 84 85 86 91 92 102 103 104 105 106 107 108 109 110 111 112 116 117 118 119 120 121 123 124 125 126 127 128; U37 18 19 21 22 23 24 30 32 33 34 36 43 44 45 46 55 57 58 59; U38 2 4 5; U39 14; U41 1; U43 12 13 14; U55 20 21 22 23; U58 B2 C2; U60 B2 C2; U61 B2 C2; U63 B2 C2; U66 9 10 11 27 28 29 30 31 32; U68 18 30 31 34 40 41 42 43 48 50 53 54 55; U70 23; U74 17 18 19 20 21 22 23 24; U76 1; U78 7; U86 6 7; U88 1; U93 4; U94 5; U127 20 21 22 23

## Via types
v1: diameter 0.457, hole 0.203, TOP to BOTTOM, 2718 vias

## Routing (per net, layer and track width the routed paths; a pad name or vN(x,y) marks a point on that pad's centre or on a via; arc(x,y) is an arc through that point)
3V3_SYS_EN: length 1.8
  BOTTOM w0.127: U67.7 33.09,47.28 32.15,48.22 R442.2
AGND_AUD: length 11.7
  TOP w0.254: v1(76.44,45.42) 76.11,45.09 C133.2 ; C126.2 v1(77.05,48.29) ; C124.2 v1(77.05,49.29) ; v1(74.91,45.4) 75.07,45.24 C132.2 ; J14.4 v1(78.33,38.48)
  BOTTOM w0.254: U66.20 73.66,45.15 v1(73.41,45.4) 73.16,45.15 U66.21 ; v1(76.44,45.42) 76.16,45.15 U66.15 ; C402.2 69.57,42.73 69.94,42.35 v1(70.3,42.35) 70.45,42.35 70.7,42.61 C403.2 ; C399.2 68.96,46.32 v1(69.38,46.32) 69.79,45.91 C398.2 U66.26
  vias: v1(72.7,49.76) v1(72.7,48.61) v1(72.7,47.47) v1(72.7,46.33) v1(73.84,49.76) v1(73.84,48.61) v1(73.84,47.47) v1(73.84,46.33) v1(74.98,49.76) v1(74.98,48.61) v1(74.98,47.47) v1(74.98,46.33) v1(76.12,49.76) v1(76.12,48.61) v1(76.12,47.47) v1(76.12,46.33)
DGND: length 883.2
  TOP w0.102: 47.36,78.62 47.87,78.62 U21.N2 47.88,78.11 47.3,78.11 v1(47.08,78.34) 47.36,78.62
  TOP w0.178: U2.4 40.55,148.55 v1(40.41,148.41)
  TOP w0.203: U36.10 v1(59.57,9.51) ; U36.17 v1(62.37,7.15) ; U21.N5 U21.P6 50.13,77.73 v1(50.62,77.24) ; U31.2 v1(62.82,42.75) ; U17.C1 7.35,91.69 7.99,91.04 C67.2 ; v1(50.88,84.87) 50.64,84.87 50.13,84.37 U21.A6 ; U36.80 62.37,22.68 v1(62.21,22.51) ; v1(50.88,81.86) 50.63,82.11 U21.E7 ; Y1.4 17.8,99.89 17.51,99.6 v1(17.27,99.6) ; U36.114 55.51,15.43 55.77,15.17 v1(55.77,14.94) ; U36.58 68.89,19.83 68.53,20.19 v1(68.53,20.33) ; U36.48 v1(71.61,15.83) ; U11.43 v1(14.49,121.58) ; U36.55 70.74,18.63 v1(71.06,18.31) ; D5.2 v1(9.39,47.09) ; v1(68.17,24.91) 67.97,24.71 U36.66 ; D6.2 v1(10.45,31.48) ; D7.1 v1(10.66,29.95)
  TOP w0.254: v1(13.9,115.2) 14.09,115.38 U11.55 ; v1(9.5,87.88) 9.5,87.44 9.91,87.04 C77.1 ; U21.G5 49.38,81.36 v1(49.13,81.11) ; U12.P15 v1(38.47,108.53) ; U12.W10 42.07,104.14 v1(42.47,104.54) U12.Y11 ; U12.K6 v1(34.47,100.54) U12.J6 ; v1(40.93,123.4) 40.83,123.4 40.73,123.5 C18.2 ; v1(55.9,42.38) 56.17,42.11 R180.1 ; J5.5 v1(7.12,113.24) ; U20.N9 v1(38.84,81.11) ; R206.2 v1(20.1,35.49) ; v1(78.29,136.18) 78.44,136.18 78.47,136.2 U7.4 ; v1(61.76,51.03) R162.1 61.26,50.22 61,49.97 57.62,49.97 57.54,50.05 57.54,50.05 57.3,50.29 Q3.4 Q3.7 56.05,49.61 v1(56.6,49.06) 56.41,48.86 R170.1 ; U12.A4 v1(27.16,99.34) ; C55.2 54.59,95.97 C52.2 ; C55.2 55.23,95.34 C60.2 ; C55.2 54.87,95.35 54.62,95.1 v1(54.62,94.7) ; v1(1.46,135.9) 1.6,136.04 J2.7 ; U20.V12 40.87,78.19 40.98,78.07 41.38,78.07 41.72,77.73 C97.1 42.69,77.73 v1(42.94,77.48) 42.96,77.5 C98.2 ; U12.AA12 44.1,105.74 44.19,105.82 v1(44.72,105.82) ; v1(68.17,24.91) 68.52,25.26 C152.1 ; v1(21.98,101.28) 21.54,100.84 C43.1 21.3,100.84 C41.1 ; C141.2 v1(58.63,35.48) ; R143.2 v1(51.44,65.97) ; U11.70 v1(21.91,114.53) 21.91,114.11 21.88,114.08 R47.2 ; v1(13.06,96.32) 13.76,96.32 14.08,96 U16.B3 ; U20.AB3 v1(33.32,75.26) 32.78,74.73 C106.2 ; C54.1 v1(10.61,94.88) ; v1(27.46,85.74) 27.46,85.82 R115.2 29.1,85.82 C533.2 ; J1.SH1 v1(61.67,146.14) ; Y3.2 60.24,26.81 v1(60.51,27.08) 60.51,28.24 60.17,28.58 58.44,28.58 58.24,28.39 Y3.4 ; R194.2 48.12,37.73 v1(48.46,38.06) 48.46,39.19 48.25,39.4 C140.1 ; U20.G1 30.63,85.34 C83.1 30.17,85.26 v1(30.01,85.1) ; C82.2 17.53,85.33 18.26,86.05 18.64,86.05 v1(18.75,86.16) ; v1(59.75,119.74) 59.53,119.96 C586.2 ; U20.Y1 31.71,76.56 C99.1 30.57,76.09 30.57,76.09 v1(30.57,76.05) ; C153.1 v1(57.82,24.98) ; R195.2 v1(49.39,37.96) ; U12.T9 v1(39.27,103.73) U12.T10 ; U20.T8 v1(38.04,79.16) ; U11.63 v1(18.41,116.38) ; U20.W9 v1(38.84,77.21) ; v1(74.31,11.84) C168.1 72.51,10.42 TP92.1 ; J2.57 v1(1.51,148.54) ; v1(35.67,74.53) 35.67,74.52 C104.1 35.12,74.91 35.24,75.03 U20.AB5 ; C587.2 64.17,117.78 63.84,117.46 C566.2 ; U33.10 23.96,32.72 23.94,32.75 ; v1(41.87,143.14) 41.63,143.37 U4.7 ; U20.T10 v1(39.64,79.16) ; C162.2 52.3,14.05 v1(52.41,13.93) 52.59,13.93 52.85,14.18 C161.2 ; J2.SH2 v1(1.56,154.14) ; J2.39 v1(1.51,144.04) ; U12.Y6 v1(42.47,101.33) ; SW6.1 41.11,17.39 v1(41.82,16.68) ; R633.1 62.27,120.34 62.04,120.11 v1(62.04,119.74) ; C57.2 66.41,95.14 v1(66.83,95.14) ; v1(33.39,91.26) 33.09,91.56 R94.1 ; v1(9.88,78.29) 9.88,78.29 U22.15 ; U20.J12 41.23,84.04 v1(41.69,83.57) ; U20.G5 v1(34.84,85.66) ; U24.2 44.06,70.35 44.45,70.74 R137.2 44.96,70.74 v1(45.25,71.03) ; U12.M11 U12.N12 v1(37.67,106.13) U12.P13 v1(37.67,106.94) ; U12.M11 U12.L12 v1(35.27,106.13) U12.K13 v1(34.47,106.93) 34.47,106.94 U12.J14 v1(33.67,107.73) ; U12.M11 v1(36.87,105.33) ; U12.F4 v1(31.27,98.94) ; R247.2 v1(76.05,19.58) ; U12.L16 v1(36.07,109.34) ; C103.1 16.06,75.27 v1(15.98,75.35) C102.2 ; v1(13.71,74.58) 13.73,74.59 C101.2 ; v1(72.97,24.33) 73.22,24.07 R240.1 R244.1 R245.1 R246.1 ; C14.2 75.46,139.01 75.45,139.02 75.45,139.07 75.7,139.33 R13.2 ; C14.2 75.15,137.96 C13.2 72.66,137.96 72.27,137.58 72.27,136.61 72.02,136.35 TP11.1 ; C14.2 76.16,137.65 v1(76.25,137.57) ; R198.2 v1(52.57,37.4) R197.2 ; C6.1 58.33,149.3 v1(58.43,149.4) ; v1(30.33,88.83) 30.33,88.73 30.59,88.48 C72.1 31.5,88.48 U20.C1 ; C39.2 v1(5.38,103.68) ; U37.1 v1(18,18.21) ; R5.1 v1(40.87,147.55) ; U12.F11 v1(32.07,104.54) ; C51.2 66.41,96.64 v1(66.83,96.64) ; U20.C5 35.67,88.36 v1(36.52,88.36) 36.94,87.94 U20.C8 ; J19.12 v1(37.35,6.28) ; U12.P16 v1(38.47,109.33) ; U20.G12 42.09,85.34 C80.1 42.57,85.42 v1(42.75,85.24) ; U37.13 15.82,12.21 v1(15.69,12.08) 15.5,11.89 C165.1 ; v1(30.01,78.08) C95.1 30.94,78.08 31.04,78.19 U20.V1 ; U12.V11 41.27,104.93 v1(40.87,104.53) U12.U10 ; C84.1 v1(11.48,84.93) ; C69.1 5.57,87.05 v1(5.34,87.27) ; C11.1 v1(61.53,140.11) ; R77.1 62.27,97.79 62.04,97.55 v1(62.04,97.18) ; U20.G10 v1(38.84,85.66) ; U20.E12 41.54,86.64 41.63,86.55 v1(42.09,86.55) ; R140.2 25.73,67.83 C113.1 25.73,66.37 v1(25.49,66.13) ; C158.2 52.42,16.54 v1(52.24,16.72) ; U20.J1 31.86,84.19 31.6,84.19 v1(31.45,84.34) ; v1(25.74,18.93) 25.59,18.93 25.32,19.2 U37.51 ; R637.1 R631.1 57.94,118.31 57.88,118.25 57.88,118.23 57.55,117.91 C569.2 C577.2 ; v1(36.13,67.43) 35.84,67.43 35.75,67.52 R142.1 ; U5.2 v1(52.53,140.22) ; v1(9.26,83.17) 9.28,83.17 9.46,82.99 C87.2 ; R254.2 51.42,6.66 v1(51.19,6.44) ; C174.2 64.92,6.81 v1(64.73,7) ; v1(32.27,10.32) J19.20 v1(32.27,6.36) ; C149.2 58.98,31.8 v1(58.72,32.05) ; U12.J12 v1(33.67,106.13) ; U12.F13 v1(31.27,106.13) ; v1(77.42,146.14) J1.SH3 v1(71.37,146.14) J1.SH2 ; v1(22.98,45.16) 23.48,44.65 C130.2 ; v1(50.2,76.34) 49.74,76.34 49.13,76.95 U21.P4 ; U12.P3 v1(37.67,98.93) ; U20.V8 v1(38.04,77.86) ; v1(7.56,76.79) 7.56,77.38 8.06,77.88 C96.2 ; U37.25 v1(22.82,10.15) ; U12.V19 v1(41.67,111.73) ; U12.W13 v1(42.47,106.93) 42.87,107.33 U12.Y14 ; U21.K8 51.13,80.08 50.85,80.36 v1(50.38,80.36) U21.J5 ; C164.2 52.85,13.07 v1(53.13,13.35) ; J18.5 v1(77.67,18.05) ; v1(32.87,106.94) U12.H13 v1(32.87,106.13) ; 23.94,32.75 24.5,32.75 v1(24.52,32.72) ; 23.94,32.75 v1(23.44,32.75) ; J2.45 v1(1.51,145.54) ; v1(7.18,41.95) J13.A12 v1(8.7,41.95) ; J1.24 v1(72.08,150.47) ; LD6.1 v1(53.6,57.46) ; v1(79.82,151.69) C4.2 v1(80.46,151) ; v1(39.27,105.34) U12.T12 v1(40.07,106.13) ; v1(34.6,82.95) 34.6,83.17 34.44,83.34 U20.K4 34.04,83.71 33.72,84.04 U20.J3 ; U18.5 25.89,90.15 U18.2 24.99,90.15 C68.1 ; v1(18.06,11.26) 18.01,11.21 U37.15 ; C574.2 66.41,117.69 v1(66.83,117.69) ; C59.2 C56.2 57.55,95.35 57.88,95.68 57.88,95.69 57.94,95.75 R83.1 R81.1 ; C568.2 60.44,120.19 v1(60.9,119.74) 61.33,120.17 C565.2 ; R153.2 R152.2 7.31,60.01 v1(7.2,59.9) ; C66.2 v1(26.09,92.2) ; C10.1 C8.1 59.06,140.93 v1(58.5,140.93) ; v1(10.73,84.95) 10.55,85.12 C79.1 ; U27.4 v1(78.33,61.44) ; C49.1 5.84,96.48 5.91,96.54 v1(5.93,96.54) ; C63.2 66.41,93.64 v1(66.83,93.64) ; U29.5 46.78,53.85 v1(45.74,53.85) ; U20.E5 36.36,86.64 v1(36.37,86.62) 36.39,86.64 U20.E8 ; R176.2 61.62,44.47 61.81,44.66 v1(61.81,44.69) ; C172.2 C175.2 57.41,6.12 v1(57.28,6.25) ; J13.B12 6.88,48 v1(7.07,48.19) 7.32,47.95 J13.A1 8.45,47.95 v1(8.77,48.27) ; U20.D9 v1(38.04,87.61) ; v1(8.76,91.06) 8.76,90.82 8.51,90.56 C67.2 ; v1(30.42,17) 30.1,16.68 C160.1 ; U12.M18 v1(36.87,110.93) ; v1(8,57.34) 7.76,57.58 U28.4 ; C18.2 C17.1 ; C18.2 42.43,124.13 U10.E5 ; C7.1 v1(44.07,149.78) ; v1(18.28,82.1) C89.1 ; v1(66.83,119.19) 66.41,119.19 C584.2 ; U12.F9 v1(32.07,102.94) ; v1(32.44,86.96) 32.52,86.96 U20.D2 ; C163.2 v1(75.62,12.71) ; D3.1 49.97,69.09 v1(49.77,69.29) ; U10.C1 v1(47.16,122.4) ; U12.H1 v1(33.27,96.4) ; U20.Y5 v1(34.84,76.56) ; C47.2 61.33,97.61 v1(60.9,97.18) 60.44,97.64 C46.2 ; v1(52.58,80.77) 52.58,80.77 52.49,80.86 U21.H10 ; J19.16 v1(34.81,6.28) ; U32.4 64.65,30.64 v1(65.01,31) ; v1(49.62,82.89) 49.14,83.36 U21.C4 ; U30.4 27.74,46.07 v1(27.71,46.03) ; v1(1.51,153.04) J2.75 v1(3.79,153.04) ; v1(70.55,23.05) 70.78,22.82 70.78,22.46 70.54,22.23 U36.64 ; C100.2 v1(11.85,75.8) ; U12.T3 39.31,98.17 v1(39.31,98.15) ; U12.M16 v1(36.87,109.33) ; v1(20.43,51.71) 20.73,51.71 C121.2 ; v1(41.64,76.11) 41.32,76.43 41.3,76.43 U20.Y12 ; U12.R5 v1(39.27,100.53) ; C115.2 72.19,59.95 72.19,59.96 v1(72.15,59.96) ; U20.N11 v1(40.44,81.11) ; 67.14,69.54 C109.2 ; 67.14,69.54 66.98,69.7 v1(66.98,71.42) 66.58,71.83 U23.2 ; 67.14,69.54 67.23,69.44 v1(67.22,69.44) 67.32,69.54 C110.2 67.73,68.4 C111.2 ; v1(53.54,119.96) 53.54,119.32 53.8,119.06 C572.2 ; 66.82,82.19 66.82,81.58 D2.1 ; 66.82,82.19 66.86,82.16 v1(67.67,82.16) ; 66.82,82.19 66.73,82.28 R120.2 ; C61.2 63.84,94.9 64.17,95.22 C50.2 ; R11.1 46.92,142.79 v1(46.57,143.14) ; U13.2 11.87,103.29 11.97,103.2 C38.2 13.42,103.2 C40.2 v1(14.28,103.28) ; v1(8.7,32.95) J15.A1 v1(7.18,32.95) 6.29,32.95 J15.B12 ; C3.1 v1(40.06,150.95) ; U20.A10 v1(39.14,89.74) ; U12.P6 v1(38.47,100.54) ; U12.W7 v1(41.67,102.13) ; v1(15.61,92.8) 15.4,92.8 C64.2 14.92,93.83 14.81,93.94 14.81,94.33 14.48,94.66 U16.C1 ; v1(3.79,151.54) J2.69 v1(1.51,151.54) ; v1(20.66,109.58) 20.67,109.57 C26.2 C27.2 21.43,109.57 v1(21.42,109.58) ; R156.2 76.19,54.48 76.44,54.73 v1(76.62,54.73) 76.89,54.73 77.1,54.52 R157.2 ; U12.T15 v1(40.07,108.53) ; C573.2 66.41,116.19 v1(66.83,116.19) ; v1(54.62,117.26) 54.62,117.65 54.87,117.91 C576.2 ; R183.2 58.18,38.04 58.48,37.74 v1(58.48,37.41) ; U20.P12 41.06,80.57 C93.1 v1(42.29,81.11) ; U12.D11 v1(30.47,104.54) ; C78.2 30.76,86.97 31.01,87.22 v1(31.04,87.22) ; C169.2 v1(71.51,8.02) 71.67,8.18 U38.1 ; v1(1.7,83.59) 1.73,83.62 SW1.1 ; R196.2 v1(50.66,37.96) ; U37.11 15.77,13.21 v1(15.69,13.29) 15.69,13.46 15.94,13.71 U37.10 ; C53.2 C62.2 ; v1(22.63,111.5) 22.63,111.5 R51.2 ; J5.11 v1(7.09,116.24) ; C90.1 30.18,82.01 v1(30.18,82.01) 30.12,82.01 29.82,82.31 C88.2 ; U12.K3 v1(35.27,98.13) ; U12.R8 39.27,102.14 v1(39.27,102.13) ; C159.2 42.38,15.64 v1(42.38,15.45) ; R184.2 v1(32.75,37.4) R185.2 v1(34.02,37.4) R186.2 ; J1.12 v1(67.58,150.47) ; C5.2 v1(47.9,151.94) ; U12.G9 v1(32.87,102.94) ; C135.2 65.78,42.75 v1(66.05,42.48) ; C171.1 v1(26.8,6.33) ; U12.L14 v1(36.07,107.73) ; R191.2 R190.2 v1(39.1,37.4) R189.2 ; U12.AA21 v1(44.24,112.94) ; U12.T6 v1(39.27,101.34) U12.R7 ; Q4.3 v1(47.79,43.24) ; v1(26.45,97.08) 26.91,97.08 27.05,96.94 U12.A1 ; U20.K2 v1(33.24,83.06) ; v1(55.33,146.28) 55.81,145.8 U3.25 ; 19.23,105.8 19.24,105.79 C34.1 C33.2 18.48,105.77 18.48,105.78 ; U20.K9 v1(38.84,83.71) ; R66.1 v1(23.6,102.47) ; R7.2 45.01,147.44 v1(45.01,147.44) ; U20.G8 36.96,85.34 v1(36.84,85.21) ; C155.1 52.4,19.52 v1(52.4,19.52) ; U12.J10 v1(34.47,104.53) ; U20.T5 v1(34.84,79.16) ; C81.1 25.55,86.48 v1(25.49,86.54) ; R187.2 v1(36.56,37.4) R188.2 ; C15.1 v1(47.77,136.56) ; v1(12.07,125) 12.24,124.84 U9.2 ; R237.1 v1(71.91,24.45) ; U12.J16 v1(33.67,109.33) ; v1(8.61,138.34) 9.06,138.79 J2.18 ; J5.17 7.23,119.24 v1(7.04,119.05) ; R199.2 v1(53.87,37.4) ; U12.U5 v1(40.07,100.53) ; U12.R16 v1(39.27,109.33) ; C48.1 v1(3.42,96.48) ; U20.A3 v1(33.2,90.01) ; U12.Y4 v1(43.27,98.94) ; Y1.2 19.96,101.24 v1(20.18,101.46) ; U20.J10 v1(39.64,84.36) ; R201.2 9.91,36.83 v1(11.53,36.83) ; C44.2 60.29,100.68 60.37,100.76 60.37,101.04 v1(60.44,101.11) ; C2.2 C1.2 v1(72.86,152.77) ; C75.2 22.43,87.49 C71.2 22.43,88.67 v1(22.25,88.85) ; U20.AB10 v1(39.64,75.26) ; v1(44.27,120.38) 44.27,120.5 U10.B3 ; U20.N4 v1(34.04,81.11) ; J13.B1 v1(5.48,41.9) ; v1(5.48,26.9) J15.B1 6.29,26.95 v1(7.18,26.95) J15.A12 v1(8.7,26.95) ; C151.1 55.46,26.01 55.46,26.63 55.26,26.83 v1(55.26,26.86) ; U20.W11 v1(40.44,77.21) ; C170.1 v1(22.01,7.03) ; C107.2 v1(19.52,69.5) ; J5.8 v1(7.09,114.74) ; v1(22.89,35.93) 22.61,35.93 22.35,35.68 C142.2 22.35,34.55 23.21,33.69 U33.4 ; C154.1 v1(60.03,24.98) ; v1(43.2,88.21) 42.96,88.21 42.7,87.95 C74.2 42.14,87.94 U20.C12 ; D9.1 v1(77.05,13.16) ; v1(25.49,87.49) 25.95,87.49 25.99,87.53 C73.2 ; v1(37.8,73.95) 38.03,74.17 C105.1 37.64,74.89 U20.AB8 ; C119.2 11.1,54.16 v1(11.25,54.31) ; v1(35.27,104.53) U12.L10 ; SW5.1 v1(34.25,16.77) ; v1(15.8,116.36) 15.41,115.97 U11.57 ; U12.AA15 v1(44.37,108.13) ; J2.1 v1(1.51,134.54) ; U12.A21 v1(27.27,113.33) ; v1(23.2,38.95) 22.97,39.17 C139.2 21.59,39.17 21.58,39.18 C138.2 ; C42.2 15.74,100.31 15.46,100.59 v1(15.17,100.59) ; U20.V5 v1(34.84,77.86) ; C125.2 20.93,47.98 20.95,47.96 v1(20.95,47.44) ; R192.2 v1(45.58,37.96) ; J9.4 v1(73.31,75.8) ; U14.4 v1(2.04,100.65) ; v1(56.25,140.67) 55.69,140.67 55.57,140.79 C9.1 ; v1(69.45,25.68) 69.68,25.91 U34.3 ; v1(43.42,153.27) 43.42,152.48 ; U17.C3 7.35,93.08 v1(7.1,93.33) 6.95,93.18 U17.B3 ; U12.Y3 v1(43.27,98.14) ; U12.P1 v1(37.67,97.34) ; U20.P3 v1(33.24,80.46) ; v1(1.02,91.39) 1.73,90.68 SW1.4 ; U12.AA9 v1(44.41,103.34) ; U12.U8 40.07,102.93 v1(40.07,102.94) ; SW5.4 v1(35.32,23.33) ; v1(31.79,82.07) 31.21,82.07 30.78,82.5 C91.1 ; C120.2 v1(22.16,51.65) ; v1(36.87,100.54) U12.M6 v1(36.07,100.53) U12.L6 ; U12.L1 v1(35.67,96.27) ; J1.16 v1(69.08,150.47) ; C108.1 38.66,70.74 v1(38.51,70.59) ; U12.T7 v1(40.07,101.34) ; U20.P1 31.04,80.79 31,80.75 C92.1 v1(30.61,80.21) ; SW6.4 v1(42.18,23.33) ; U20.W4 v1(34.04,77.21) ; R59.1 v1(14.23,106.29) ; U37.5 v1(15.72,16.21) 15.46,15.95 C157.2 v1(14.24,15.95) ; U12.V14 41.27,107.33 v1(40.87,106.93) U12.U13 ; C150.2 v1(73.87,28.84) ; U20.Y8 v1(38.04,76.56) ; U6.4 v1(57.82,136.74) ; U33.15 25.95,33.06 v1(26.12,33.23) ; C45.2 59.53,97.41 v1(59.75,97.18) ; J19.10 v1(38.62,6.28) ; U12.F15 v1(31.27,108.53) ; v1(83.67,137.16) R20.2 C12.2 v1(83.74,138.43) ; R193.2 v1(46.85,37.96) ; U12.N6 v1(37.67,100.54) ; U20.P10 v1(39.64,80.46) ; U20.G3 v1(34.04,85.01) ; v1(42.94,79.23) 42.4,79.23 C94.1 42.2,79.26 41.26,79.26 41.15,79.37 40.98,79.37 40.87,79.49 U20.T12 ; U12.N14 v1(37.67,107.73) ; U12.G6 v1(32.07,101.33) ; U20.D11 v1(40.44,87.61) ; J2.33 v1(1.51,142.54) ; U20.W2 v1(32.44,77.21) ; U20.D4 v1(34.04,87.61) ; U12.M9 v1(36.07,102.94) ; U20.T3 v1(33.24,79.16) ; U20.T1 v1(32.44,79.81) ; R32.1 v1(13.3,126.28) ; U15.5 v1(6.89,96.47) ; U12.G16 v1(32.07,109.33) ; U20.K11 v1(40.04,82.85) ; C85.2 v1(11.21,83.3) ; C563.2 60.29,123.23 60.37,123.31 60.37,123.44 60.62,123.7 v1(60.71,123.7) ; U26.8 v1(35.05,71.57) ; C173.1 v1(60.99,6.88) ; U20.N2 v1(32.44,81.11) ; R131.2 v1(65.71,75.41) ; J1.SH4 v1(81,146.14) ; v1(32.19,125.23) 32.43,124.99 U8.3 ; J2.51 v1(1.51,147.04) ; U12.K8 v1(34.47,102.14) ; v1(49.6,151.19) R4.2 ; v1(53.27,135.16) 53.35,135.24 R28.1 54.34,135.24 54.48,135.38 C16.2 ; C156.2 v1(14.24,18.98) ; U37.35 29.4,11.71 29.42,11.73 C166.1 v1(30.82,11.73) ; U12.P10 v1(37.67,103.74) ; U12.AA1 v1(44.07,97.33) ; U12.D4 v1(29.67,99.73) ; U12.E2 v1(30.47,97.34) ; LD12.1 v1(52.82,6.33) ; R241.1 v1(80.25,23.91) ; U37.47 v1(29.48,17.71) ; C112.2 v1(44.83,66.89) ; J2.63 v1(1.51,150.04) ; C167.1 v1(14.95,9.66) ; J5.2 v1(7.09,111.74) ; U12.H6 v1(32.87,100.54) ; U12.D19 v1(29.67,111.73)
  TOP w0.305: C78.2 31.18,86.61 31.2,86.64 U20.E1
  TOP w0.381: v1(25.82,84.33) 25.82,84.28 25.81,84.27 C86.2
  TOP w0.508: FL6.1 2.62,104.32 v1(2.62,103.91)
  BOTTOM w0.086: 71.71,27.27 U76.3 ; v1(39.86,16.55) 39.82,16.51 U90.3 ; U41.3 34.11,139.93 34.27,140.09 ; U80.3 v1(46.02,24.83)
  BOTTOM w0.178: U85.4 63.51,20.96 v1(63.72,21.17) ; U79.4 48.64,23.44 48.5,23.3 47.96,23.3 v1(47.69,23.03)
  BOTTOM w0.203: v1(4.66,68.23) 4.65,68.23 4.39,68.49 U63.C3 ; U92.10 21.9,12.86 v1(22.1,12.66) 21.9,12.46 U92.11 ; U95.6 40.73,10.06 v1(40.53,10.26) 40.33,10.06 U95.5 ; U95.3 v1(40.73,7.48) ; C418.1 39.34,34.83 39.63,34.54 v1(39.63,34.11) ; U82.6 59.4,21.07 v1(59.6,21.27) 59.52,21.36 59.3,21.36 59.29,21.37 59.19,21.37 59.08,21.47 U82.5 ; U63.C1 4.39,70.1 4.81,70.52 4.81,71.06 C372.2 ; v1(22.07,13.57) 21.76,13.26 U92.9 ; U91.10 26.41,15.17 26.43,15.15 26.8,15.15 v1(26.98,14.97) 26.78,14.77 U91.11 ; v1(50.2,76.34) 49.97,76.57 C365.2 ; U87.11 48.66,17.9 v1(48.86,17.7) 49.06,17.9 U87.10 ; D10.2 5.1,45.02 v1(5.35,45.28) ; U44.10 36.73,135.8 v1(36.58,135.65) 36.33,135.9 U44.11 ; v1(36.19,34.2) 36.19,34.24 36.55,34.6 C419.2 ; U92.7 20.71,14.31 v1(21.03,14.62) ; U83.11 29.61,19.04 v1(29.81,18.84) 30.01,19.04 U83.10 ; v1(22.1,11.75) 21.79,12.06 U92.12 ; U68.20 19.78,47.59 v1(19.93,47.44) ; R513.1 v1(33.16,21.47) ; U60.C1 26.99,78.42 26.6,78.03 C362.2 ; C507.2 19.63,99.77 19.79,99.62 U125.A1 ; v1(19.93,42.87) 19.78,42.72 U68.51 ; U96.11 28.92,6.88 v1(29.12,6.68) 29.32,6.88 U96.10 ; v1(56.8,21.21) 56.93,21.07 U82.3 ; D11.2 5.27,27.11 v1(5.48,26.9) ; U84.11 68.33,20.13 v1(68.53,20.33) 68.33,20.53 U84.10 ; U96.1 28.52,9.31 27.99,9.84 v1(27.88,9.84)
  BOTTOM w0.254: C432.1 40.86,24.27 v1(40.98,24.4) ; v1(57.59,125.35) R643.1 R649.1 ; v1(51.19,24.25) 51.19,23.56 C433.1 ; 28.77,22.27 v1(28.2,21.7) 28.2,21.29 28.46,21.03 U83.16 ; 28.77,22.27 28.77,22.08 29.21,21.64 U83.1 ; 28.77,22.27 C438.1 ; C324.2 v1(57.84,89.25) ; C345.2 49.5,83 v1(49.62,82.89) ; v1(18.06,11.26) 18.3,11.26 18.61,11.57 C469.1 18.86,11.62 19.3,12.06 U92.1 ; v1(9.99,117.21) U50.14 7.3,117.21 7.04,117.47 v1(7.04,119.05) ; v1(37.1,28.99) 37.11,28.98 U75.13 ; J21.6 v1(3.36,95.26) ; v1(71.87,27.27) 71.71,27.27 ; v1(8.96,135.01) 9.64,134.32 C191.2 ; v1(11.92,79.54) 11.75,79.36 C359.2 ; v1(36.07,102.94) 35.9,103.1 C295.2 ; C367.1 v1(35.67,74.53) ; C349.2 38.67,81.21 38.77,81.11 v1(38.84,81.11) ; C461.1 v1(10.51,14.78) ; C578.2 v1(57.84,111.81) ; C268.2 33.78,106.03 v1(33.67,106.13) ; v1(61.16,76.35) 61.16,76.35 J22.6 ; Q5.7 Q5.4 v1(83.79,106.21) ; R478.2 11.51,32.77 v1(11.51,32.12) ; v1(74.25,150.58) 74.59,150.58 74.84,150.33 R576.1 ; v1(61.75,12.25) J24.25 ; R488.2 47.24,27.44 47.13,27.55 U74.25 47.13,28.99 v1(46.83,29.3) ; C570.2 60.34,112.16 v1(59.96,111.78) 59.58,112.16 C583.2 ; Q6.7 Q6.4 v1(78.42,87.17) ; U73.13 55.22,33.17 v1(55.23,33.16) ; v1(56.32,89.25) C326.2 C325.2 ; C449.1 60.39,19.57 v1(60.49,19.47) 60.87,19.85 C448.1 ; C456.1 18.26,17.95 v1(18,18.21) ; v1(33.24,79.16) 33.32,79.16 33.62,79.46 C353.1 ; R635.1 56.05,123.8 55.79,124.05 v1(55.73,124.05) ; C564.2 56.64,112.37 v1(56.49,112.22) ; v1(13.7,152.23) 13.69,152.22 C176.1 ; v1(76.36,17.3) 76.17,17.1 U88.3 ; v1(56.25,140.67) 55.79,140.67 55.57,140.46 R264.1 ; v1(21.98,101.28) 22.23,101.53 C311.2 ; v1(15.72,16.21) 15.72,16.2 15.98,15.94 R548.1 ; J22.10 60.84,74.35 v1(61.2,74.71) ; v1(46.53,109.52) 47.37,110.36 C25.2 ; v1(47.16,122.4) 47.39,122.63 C203.2 ; C177.2 10.56,151.38 10.68,151.26 v1(11.42,151.26) ; J22.16 60.79,71.35 v1(61,71.56) ; C364.2 12.79,78.11 v1(13.07,78.39) ; C222.2 22.09,115.38 21.91,115.2 v1(21.91,114.53) ; C445.1 v1(22.82,21.38) ; v1(61.55,103.06) 61.89,103.06 R364.1 ; v1(24.17,13.36) 24.59,13.36 24.84,13.62 U91.16 ; v1(61.59,69.39) 62.05,69.85 J22.19 ; U92.16 19.91,11.31 19.66,11.05 v1(19.14,11.05) ; v1(18.06,14.06) 18.3,14.06 18.61,13.75 C466.1 ; J22.28 v1(58.75,65.35) ; C363.1 13.8,77.99 v1(14.21,78.39) 14.28,78.32 14.6,78.32 C361.1 ; v1(54.62,94.7) 54.95,94.37 C60.2 ; C334.1 22.26,86.52 22.46,86.32 v1(22.46,86.32) ; C476.1 42.33,6.55 v1(42.6,6.28) ; J24.7 70.75,12.1 v1(71.31,11.54) ; U61.C1 22.05,71.15 21.54,70.64 C373.2 21.54,69.77 21.53,69.77 v1(21.53,69.39) ; R303.2 32.83,124.95 32.55,125.23 v1(32.19,125.23) 31.76,124.8 U48.2 ; v1(54.62,117.26) 54.95,116.93 C567.2 ; R659.2 59.52,106.82 59.55,106.78 U128.2 ; v1(75.62,12.71) 75.62,10.13 J24.41 ; C181.1 v1(63.79,134.35) ; R571.1 R572.1 69.58,149.97 v1(69.08,150.47) ; C219.2 v1(15.8,116.36) 15.8,115.58 R339.2 ; C382.2 v1(74.18,54.58) ; v1(77.05,150.58) 76.78,150.31 C477.1 ; v1(39.27,109.33) 39.3,109.3 C244.2 ; C287.2 37.45,103.82 37.53,103.74 v1(37.67,103.74) ; v1(34.84,79.16) 34.92,79.16 34.94,79.19 C357.1 ; v1(54.99,90.08) 55.31,89.75 U56.2 ; v1(7.56,125.39) C196.2 9.46,125.39 C195.1 ; C412.2 v1(58.54,39.06) ; C480.1 64.44,149.06 64.18,148.8 v1(63.36,148.8) ; C285.2 v1(39.27,103.73) 39.27,103.43 C289.2 ; v1(20.69,122.36) 21.15,122.36 21.27,122.49 22.9,122.49 23.2,122.79 23.2,124.24 22.91,124.53 C198.2 ; v1(61.55,125.61) 61.89,125.61 R638.1 ; v1(61.65,66.98) 61.78,66.85 J22.25 ; C296.2 40.07,102.83 v1(40.07,102.94) ; C307.2 36.15,100.62 v1(36.07,100.53) 35.99,100.61 35.55,100.61 C309.2 ; v1(38.44,139.76) 38.44,139.16 R280.1 ; v1(16.63,122.36) 16.07,122.36 C205.2 ; v1(10.75,73.74) 10.77,73.73 C369.1 ; C270.2 36.7,105.51 v1(36.87,105.33) 36.89,105.32 ; J22.34 v1(58.75,62.35) ; v1(20.66,109.58) 20.67,109.57 C26.2 C27.2 21.43,109.57 v1(21.42,109.58) ; v1(42.75,85.24) 42.88,85.36 C337.1 ; v1(75.83,22.29) 75.81,22.27 C440.2 75.81,20.7 v1(75.86,20.66) ; v1(24.02,18.32) 24.14,18.2 R533.1 ; C360.2 37.94,77.89 37.95,77.88 38.02,77.88 v1(38.04,77.86) ; C247.2 37.88,107.94 v1(37.67,107.73) 37.67,107.65 ; R450.2 v1(29.01,44.23) 29.03,44.24 C400.2 ; Q20.7 Q20.4 75.34,107.88 v1(74.83,107.37) ; v1(13.71,74.58) 13.52,74.39 C368.1 ; v1(52.4,19.52) 52.39,19.51 R519.2 ; Q12.3 v1(41.58,21.94) ; v1(9.99,113.96) U50.19 ; v1(11.25,54.31) 11.45,54.11 C381.1 ; 34.27,140.09 C182.1 v1(34.27,141.33) ; v1(18.13,20.84) 18.25,20.72 C446.1 ; v1(61.89,41.97) 62.11,42.19 U71.3 ; C474.1 v1(13.78,9.59) ; C178.1 46.57,143.75 v1(46.57,143.14) 46.73,143.3 C180.1 ; R509.1 v1(64.12,22.54) 63.81,22.22 C439.2 ; J22.40 v1(58.79,59.35) ; v1(18.67,136.04) C186.2 v1(17.92,135.26) ; R338.2 12.42,115.49 13.03,114.87 13.58,114.87 v1(13.9,115.2) 13.9,114.66 14.43,114.13 C227.2 ; C574.2 66.78,117.7 66.79,117.69 v1(66.83,117.69) ; v1(76.85,24.24) 77.17,24.57 U78.6 ; v1(38.47,109.33) 38.44,109.31 38.39,109.26 C236.2 ; U43.8 53.23,139.52 v1(52.53,140.22) ; C430.1 v1(43.01,26.8) ; C383.2 69.78,53.02 69.78,52.49 69.57,52.27 v1(69.16,52.27) 68.83,51.94 C388.2 ; v1(7.62,120.97) C212.2 ; 39.27,102.14 39.49,101.92 39.49,101.56 v1(39.27,101.34) 39.09,101.51 C303.2 ; 39.27,102.14 v1(39.27,102.13) ; 39.27,102.14 39.27,102.18 C299.2 ; v1(12.25,133.38) 12.25,133.84 12.3,133.89 C188.1 ; C354.1 14.54,79.2 v1(14.21,79.54) ; R296.1 v1(74.52,132.69) ; C269.2 v1(39.27,105.34) ; v1(39.27,105.34) 39.43,105.34 C277.2 ; v1(39.27,105.34) 39.17,105.34 C275.2 ; v1(11.28,43.19) 11.28,43.18 11.45,43 C407.2 ; v1(20.96,10.45) 20.71,10.7 U92.14 ; C338.2 v1(73.99,83.01) ; C355.1 39.57,79.49 39.57,79.24 v1(39.64,79.16) ; C240.2 36.71,109.17 v1(36.87,109.33) ; C230.2 14.61,106.66 v1(14.23,106.29) ; v1(39.1,26.63) 39.58,27.11 U75.11 ; C192.2 18.66,132.91 v1(18.66,133.18) 19.04,133.57 U46.B1 ; R563.1 43.37,10.09 v1(43.61,10.34) ; U73.12 53.72,33.17 v1(53.71,33.16) ; C473.1 30.16,10.36 v1(30.52,10.72) ; C426.1 72.27,28.83 v1(72.51,29.07) ; R661.2 60.17,104.07 59.92,104.07 59.87,104.11 C588.2 59.03,104.11 v1(58.93,104.01) ; C208.1 10.25,120.84 v1(9.92,120.51) ; C281.2 34.3,104.7 v1(34.47,104.53) ; C378.2 v1(11.43,65.35) ; v1(41.82,16.68) 41.82,17.17 C454.1 ; R435.1 16.61,52.34 16.71,52.44 v1(16.71,52.9) 16.67,52.86 C384.2 ; v1(42.29,81.11) 42.44,81.26 C348.2 ; C465.1 10.59,13.52 v1(11.07,13.03) C467.2 C468.1 ; R305.2 33.55,114.33 v1(33.61,114.27) ; J22.37 63.94,60.85 v1(64.08,60.71) 64.08,63.37 63.61,63.85 J22.31 ; v1(34.25,16.77) 34.61,16.77 34.86,17.02 C455.1 ; v1(1.7,83.59) 2.08,83.97 R379.2 ; C249.2 35.99,107.81 v1(36.07,107.73) ; C460.1 23.53,16.06 23.23,16.37 v1(22.99,16.37) ; v1(47.38,21.53) 47.48,21.53 C442.1 ; v1(8.51,56.58) 8.56,56.53 8.56,56.39 8.72,56.22 R423.2 ; v1(66.83,95.14) 66.79,95.14 66.78,95.14 C57.2 ; R455.2 v1(61.81,44.69) ; v1(19.2,97.13) 19.2,97.76 19.33,97.89 C531.2 ; R362.1 R363.1 v1(57.59,102.8) ; v1(25.79,77.5) 25.97,77.68 C362.2 ; v1(69.5,108.18) 69.55,108.24 Q21.4 Q21.7 ; v1(49.13,81.11) 49.1,81.14 C351.2 ; C323.2 59.58,89.61 v1(59.96,89.23) 60.34,89.61 C322.2 ; U58.C1 17.66,85.06 17.66,85.18 18.12,85.64 C335.2 18.36,86.3 18.51,86.16 v1(18.75,86.16) ; C220.2 21.21,117.78 v1(20.69,118.3) 21.6,119.21 21.6,120.91 22.26,121.57 C206.2 23.33,119.45 23.61,119.17 C215.2 ; R375.2 35.7,96.24 v1(35.67,96.27) ; v1(71.06,18.31) 70.54,17.79 C453.1 ; C189.2 13.78,133.55 13.79,133.55 v1(13.95,133.38) ; v1(32.27,10.32) 32.04,10.09 R564.1 ; v1(58.6,67.59) 59.36,68.35 J22.22 ; C187.2 v1(5.71,135.03) ; v1(13.07,80.68) 13.07,81.18 C350.1 ; C300.2 31.81,102.67 v1(32.07,102.94) C291.2 ; C258.2 34.49,106.92 v1(34.47,106.93) ; v1(37.67,103.74) 37.17,103.24 C294.2 37.15,103.23 C297.2 ; v1(37.67,103.74) 37.82,103.59 C292.2 ; v1(55.94,101.5) 56.05,101.4 R368.1 ; U70.25 56.2,39.64 v1(56.43,39.42) 56.39,39.38 R470.1 ; C255.2 37.67,107.59 37.67,107.65 ; v1(66.83,96.64) 66.79,96.64 66.78,96.64 C51.2 ; C417.1 58.23,37.05 58.48,37.3 v1(58.48,37.41) ; U45.B1 5.4,136.94 5.34,137.01 C185.2 4.59,137.01 v1(4.4,137.19) ; v1(60.28,22.55) 60.11,22.72 C434.1 ; C343.2 46.84,84.13 v1(47.07,84.36) 47.09,84.34 C344.2 ; v1(71.69,15.08) 71.76,15.08 71.81,15.12 C462.2 ; C436.1 46.08,22.16 v1(45.85,21.93) ; C267.2 31.45,105.95 v1(31.27,106.13) 31.25,106.15 C257.2 ; C356.1 37.93,79.2 37.97,79.16 v1(38.04,79.16) ; U39.8 41.31,140.26 v1(41.36,140.32) ; C328.2 C327.2 22.2,88.9 v1(22.25,88.85) ; v1(32.07,101.33) 32.09,101.33 C302.2 ; J21.SH4 15.61,92.8 v1(15.61,92.8) ; U40.6 v1(48.36,139.78) 48.65,139.49 R281.1 ; C271.2 36.89,105.32 ; 36.89,105.32 36.89,104.62 36.92,104.59 C282.2 ; C444.2 v1(46.21,20.64) ; U42.8 80.81,141.29 81.11,141.59 v1(81.11,142.27) ; C202.2 19.06,122.98 v1(19.67,122.36) ; v1(36.84,85.21) 36.8,85.24 C339.1 ; C272.2 30.15,104.86 30.15,104.86 v1(30.47,104.54) 30.84,104.16 30.91,104.16 ; U72.2 v1(55.83,36.49) ; C563.2 60.29,123.44 60.54,123.7 v1(60.71,123.7) ; v1(34.84,76.56) 35.34,76.56 C366.2 ; C312.2 65.42,100.42 v1(65.42,101.03) ; v1(11.96,110.17) 11.41,110.17 C232.1 ; v1(20.18,101.46) 19.63,100.91 C507.2 ; v1(38.67,20.43) 38.49,20.25 U81.4 ; C308.2 34.72,100.62 34.67,100.57 34.64,100.57 34.55,100.47 34.48,100.54 v1(34.47,100.54) 34.24,100.76 C306.2 ; v1(33.67,109.33) 33.91,109.33 33.94,109.31 33.94,109.23 33.97,109.2 33.97,109.18 34.64,109.18 C238.2 34.97,109.51 C234.2 35.9,109.51 v1(36.07,109.34) ; v1(17.92,51.12) 17.93,51.12 17.93,51.08 18.06,51.21 R437.1 ; v1(1.71,119.19) 1.29,118.76 C217.2 ; C28.2 49.61,105.73 v1(50.29,105.05) 49.54,104.3 C31.2 ; v1(27.88,9.84) 27.88,10.18 C472.1 ; C273.2 37.68,106.13 v1(37.67,106.13) 37.53,106.28 C264.2 37.53,106.79 v1(37.67,106.94) 37.68,106.93 37.99,106.93 38.23,106.69 C261.2 ; C452.1 v1(62.32,17.03) ; C290.2 v1(32.87,102.94) 33.03,103.1 C293.2 33.04,103.45 C288.2 ; v1(57.25,12.25) J24.34 ; 50.62,77.33 v1(50.62,77.24) 51.12,77.74 R400.2 ; R411.1 44.55,71.03 v1(45.25,71.03) ; C266.2 40.07,105.91 v1(40.07,106.13) ; U62.3 v1(53.67,70.31) ; v1(73.85,26.65) 73.7,26.5 C431.2 ; C246.2 31.35,108.45 v1(31.27,108.53) ; v1(48.32,71.56) 48.44,71.68 C370.2 ; v1(23.44,32.75) 23.17,33.02 R481.2 ; v1(60.44,101.11) 60.29,100.95 C44.2 ; U47.3 69.07,132.52 69.07,132.52 v1(68.65,132.52) ; Q19.7 Q19.4 75.93,130.31 75.64,130.02 v1(75.64,129.84) ; C459.2 71.67,15.89 v1(71.61,15.83) ; R636.2 66.68,113.7 66.4,113.41 C562.1 66.4,112.65 v1(66.6,112.45) ; R290.1 8.2,137.93 v1(8.61,138.34) ; C265.2 35.06,106.34 v1(35.27,106.13) 35.27,105.84 35.65,105.47 C274.2 ; 37.67,107.65 37.62,107.65 C253.2 ; C336.1 36.59,86.41 v1(36.37,86.62) ; v1(40.87,106.93) 40.75,106.82 40.14,106.82 C259.2 C252.2 ; R354.2 v1(80.89,105.96) ; C377.1 v1(12.45,65.6) ; C213.2 15.71,119.2 C214.2 ; C389.2 70.01,51.52 v1(70.15,51.66) ; C286.2 v1(35.27,104.53) 35.17,104.63 C279.2 ; C190.1 10.57,133.81 v1(10.4,133.64) ; v1(49.67,114.41) 49.52,114.56 C225.2 C226.2 ; v1(65.84,122.1) 65.59,122.34 C579.2 ; Q8.2 v1(4.62,73.26) ; C201.2 13.05,124.94 13.13,125.02 C197.2 13.13,126.11 v1(13.3,126.28) ; C451.1 64.91,19.16 v1(64.91,18.72) ; v1(66.83,93.64) 66.79,93.64 66.78,93.64 C63.2 ; v1(20.27,106.15) 20.27,106.16 C263.2 21.22,106.16 21.42,106.36 21.51,106.36 21.52,106.37 C262.2 ; C310.2 32.93,100.59 v1(32.87,100.54) ; D12.1 v1(43.93,16.6) ; C278.2 v1(32.07,104.54) ; C450.2 25.82,19.75 25.82,19.01 v1(25.74,18.93) ; R456.1 v1(59.65,43.65) ; C413.1 v1(53.2,37.96) ; U93.1 46.78,10.06 v1(47.27,9.57) ; R491.1 v1(80.53,26.37) ; R441.2 31.13,49.75 v1(30.98,49.9) ; C76.2 3.65,88.45 v1(3.48,88.62) ; v1(53.4,89.24) 53.56,89.4 C321.2 ; R460.2 62.93,42.86 v1(62.82,42.75) ; v1(44.87,11.31) 44.78,11.4 U93.6 ; v1(34.04,87.61) 34.12,87.53 C332.1 ; U65.B1 14.38,51.44 14.64,51.19 v1(14.77,51.19) ; v1(31.2,22.88) 31.2,22.64 30.9,22.34 C437.1 ; R378.2 66.68,91.14 66.4,90.86 C320.1 66.4,89.96 v1(66.41,89.95) ; v1(78.95,27.29) 78.49,27.75 R486.2 ; v1(5.57,70.67) 5.29,70.67 C372.2 ; v1(61.37,38.94) 61.76,38.54 R469.1 ; v1(19.16,87.54) 19.36,87.74 C329.2 ; v1(33.24,83.06) 33.73,83.06 C346.1 ; C301.2 34.74,101.87 v1(34.47,102.14) 34.67,102.33 C298.2 ; C237.2 32.23,109.16 32.23,109.18 v1(32.07,109.33) 31.85,109.12 C235.2 ; U64.2 v1(73.11,56.55) ; v1(64.56,21.68) 64.59,21.64 64.75,21.64 65.1,21.3 C443.1 ; v1(5.77,85.2) 5.69,85.12 4.52,85.12 4.35,85.28 U59.2 ; C314.2 26.98,97.07 26.97,97.08 v1(26.45,97.08) ; v1(22.99,13.57) 23.23,13.57 23.53,13.88 C463.1 23.99,13.93 24.43,14.37 U91.1 ; v1(45.01,147.44) 45.21,147.24 R260.1 ; C471.1 v1(42.72,11.31) ; C193.1 v1(77.14,131.85) ; R504.2 64.55,24.88 v1(65.69,26.02) ; R574.1 71.89,146.39 71.64,146.14 v1(71.37,146.14) ; C457.1 v1(31.97,17.82) ; U69.2 v1(9.36,44.83) ; v1(32.87,106.94) 32.74,107.07 C254.2 32.59,107.07 C260.1 ; v1(38.62,28.99) 38.61,28.98 U75.12 ; v1(36.71,140.18) 36.71,140.16 36.69,140.16 C183.1 C184.1 ; R293.1 v1(17.51,133.49) ; v1(66.25,12.25) J24.16 ; v1(48.13,143.89) 48.49,143.89 C179.1 ; v1(52.58,80.77) 52.88,80.47 C352.2 ; FL17.2 65.03,82.11 65.28,81.86 65.28,80.89 v1(65.24,80.85) 65.25,80.85 65.25,80.71 65.46,80.5 C379.1 ; v1(20.46,28.76) 21.24,28.76 21.6,29.12 C420.2 C421.2 ; U94.3 v1(12.39,9.44) ; v1(1.02,91.39) 1.89,92.27 J21.SH2 ; R366.2 43.07,101.33 v1(42.47,101.33) 42.47,101.91 42.73,102.18 43.15,102.18 R361.2 ; v1(19.75,16.01) 19.47,15.73 R556.1 ; C571.2 v1(68.49,109.76) ; U67.3 v1(31.09,45.22) ; D13.1 v1(37.07,16.6) 37.7,15.97 C458.1 ; C573.2 66.78,116.2 66.79,116.19 v1(66.83,116.19) ; v1(42.47,104.54) 43.05,103.96 R356.1 ; C256.2 33.84,107.57 v1(33.67,107.73) 33.47,107.94 ; C428.1 53.16,26.41 53.43,26.15 54.54,26.15 v1(55.26,26.86) 55.23,26.9 55.23,27 55.12,27.1 C427.2 ; v1(66.83,119.19) 66.79,119.19 66.78,119.2 C584.2 ; U69.1 v1(9.36,45.48) ; R514.1 50.81,21.5 50.63,21.5 v1(50.34,21.78) 50.34,21.64 C441.1 ; R490.1 v1(69.45,25.68) ; C447.1 v1(55.73,19.59) ; v1(33.2,90.01) 33.12,89.93 33.12,89.79 C330.1 ; v1(37.67,100.54) 38.29,101.15 C304.2 ; U69.3 v1(9.36,44.18) ; R517.1 v1(44.98,19.76) ; v1(43.2,88.21) 43.5,88.21 C331.1 ; C204.1 26.97,123.38 27.34,123.75 R302.2 ; C221.2 18.39,116.37 v1(18.41,116.38) 19.13,115.66 C223.2 ; C305.1 36.9,101.22 36.9,100.57 v1(36.87,100.54) ; C347.1 38.87,83.61 38.84,83.64 v1(38.84,83.71) ; v1(81.09,87.17) Q7.4 Q7.7 ; U86.5 v1(13.92,17.46) ; Q13.3 v1(34.87,21.94) ; U93.5 v1(44.78,9.48) ; U73.11 v1(51.95,33.65) ; C435.1 v1(51.22,21.94) ; U50.6 v1(4.06,113.96)
  BOTTOM w0.381: v1(15.17,100.59) 15.29,100.59 15.61,100.27 J21.SH3 ; v1(74.47,131.58) 74.46,131.6 C194.2 ; v1(41.44,121.57) 41.96,121.57 C209.2
  BOTTOM w0.508: v1(2.62,103.91) 1.91,103.91 1.46,104.36 J21.SH1
  vias: v1(0.79,126.39) v1(3.76,126.34) v1(4.3,41.94) v1(4.97,38.9) v1(7.37,148.72) v1(7.67,84.46) v1(7.94,20.28) v1(8,56.58) v1(8.51,57.34) v1(8.7,20.69) v1(8.7,19.82) v1(9.01,57.34) v1(9.01,56.58) v1(9.38,39.57) v1(9.46,50.52) v1(9.61,26.15) v1(9.74,35.63) v1(9.89,53.22) v1(10.06,115.42) v1(10.17,112.35) v1(10.26,26.15) v1(10.51,50.57) v1(10.52,35.55) v1(10.51,10.6) v1(10.51,9.58) v1(10.92,39.34) v1(10.92,38.43) v1(10.91,26.15) v1(11.21,53.2) v1(11.26,48.4) v1(11.23,46.76) v1(11.23,45.59) v1(11.26,44.33) v1(11.3,40.59) v1(11.44,51.47) v1(11.53,37.67) v1(11.53,35.99) v1(11.63,31.21) v1(11.83,39.34) v1(11.83,38.43) v1(11.92,80.68) v1(11.92,78.39) v1(12.28,48.4) v1(12.28,44.33) v1(12.28,43.08) v1(12.32,40.56) v1(12.42,32.12) v1(12.5,142.34) v1(12.55,31.21) v1(12.7,37.51) v1(12.7,36.6) v1(12.7,35.68) v1(13.07,79.54) v1(13.13,38.07) v1(13.16,37.01) v1(13.13,36.09) v1(13.34,32.12) v1(13.46,31.21) v1(13.61,37.51) v1(13.61,36.6) v1(13.61,35.68) v1(14.21,80.68) v1(14.25,32.12) v1(14.38,31.21) v1(16.57,109.28) v1(16.63,121.35) v1(16.63,120.33) v1(16.63,119.31) v1(16.63,118.3) v1(17.64,122.36) v1(17.64,121.35) v1(17.64,120.33) v1(17.64,119.31) v1(17.64,118.3) v1(18.09,87.54) v1(18.66,122.36) v1(18.66,121.35) v1(18.66,120.33) v1(18.66,119.31) v1(18.66,118.3) v1(18.69,102.93) v1(18.86,105.95) v1(19.36,27.72) v1(19.44,102.92) v1(19.67,121.35) v1(19.67,120.33) v1(19.67,119.31) v1(19.67,118.3) v1(19.93,46.3) v1(19.93,45.16) v1(19.93,44.01) v1(20.03,22.39) v1(20.32,137.21) v1(20.46,27.69) v1(20.69,121.35) v1(20.69,120.33) v1(20.69,119.31) v1(20.95,46.3) v1(20.95,45.16) v1(20.95,44.01) v1(20.95,42.87) v1(21.89,137.19) v1(21.96,47.44) v1(21.96,46.3) v1(21.96,45.16) v1(21.96,44.01) v1(21.96,42.87) v1(22.21,95.03) v1(22.71,138.3) v1(22.98,47.44) v1(22.98,46.3) v1(22.98,44.01) v1(22.98,42.87) v1(23.51,88.49) v1(23.67,37.3) v1(23.92,40.32) v1(23.92,39.41) v1(25.12,30.94) v1(25.12,29.97) v1(25.26,89.57) v1(25.53,141.83) v1(25.55,30.53) v1(27.09,9.34) v1(27.58,127.05) v1(29.75,28.15) v1(29.75,27.03) v1(31,28.13) v1(31,27.03) v1(31.39,145.64) v1(35.1,132.13) v1(35.36,38.38) v1(35.38,37.52) v1(36.41,51.72) v1(36.42,50.91) v1(36.43,49.89) v1(36.48,48.7) v1(36.5,47.69) v1(36.5,46.67) v1(36.5,43.77) v1(36.5,42.76) v1(36.5,41.74) v1(36.5,40.73) v1(36.5,39.71) v1(36.5,38.69) v1(37.1,32.5) v1(37.1,31.33) v1(37.1,30.16) v1(37.21,51.74) v1(37.2,50.94) v1(37.2,49.89) v1(37.2,48.73) v1(37.32,41.23) v1(37.32,40.22) v1(37.32,39.2) v1(37.86,31.91) v1(37.86,30.74) v1(37.86,29.58) v1(37.93,48.75) v1(38.15,41.74) v1(38.15,40.73) v1(38.15,39.71) v1(38.15,38.69) v1(38.62,32.5) v1(38.62,31.33) v1(38.62,30.16) v1(39.43,20.43) v1(39.66,93.55) v1(39.8,41.74) v1(40.69,93.9) v1(41.64,75.38) v1(42.81,56.94) v1(43.93,32.19) v1(43.93,31.23) v1(43.93,30.26) v1(43.93,29.3) v1(44.08,56.94) v1(44.9,32.19) v1(44.9,31.23) v1(44.9,30.26) v1(44.9,29.3) v1(45.39,56.94) v1(45.68,85.58) v1(45.74,55.37) v1(45.74,54.61) v1(45.78,11.31) v1(45.86,32.19) v1(45.86,31.23) v1(45.86,30.26) v1(45.86,29.3) v1(46.26,80.28) v1(46.3,63.54) v1(46.7,11.31) v1(46.83,32.19) v1(46.83,31.23) v1(46.83,30.26) v1(47.43,7.55) v1(47.92,11.14) v1(47.92,10.22) v1(48.34,124.51) v1(48.34,7.55) v1(48.54,97.21) v1(49.82,10.53) v1(50.06,103.81) v1(50.62,125.43) v1(50.74,10.53) v1(51.14,107.81) v1(51.94,126.59) v1(52.79,148.82) v1(52.79,147.55) v1(52.79,146.28) v1(53,44.31) v1(53,43.34) v1(53,42.38) v1(53,41.41) v1(53.71,31.99) v1(53.71,30.82) v1(53.71,29.65) v1(53.97,44.31) v1(53.97,43.34) v1(53.97,42.38) v1(53.97,41.41) v1(54.06,148.82) v1(54.06,147.55) v1(54.06,146.28) v1(54.27,8.39) v1(54.27,7.63) v1(54.47,32.57) v1(54.47,31.4) v1(54.47,30.24) v1(54.93,44.31) v1(54.93,43.34) v1(54.93,42.38) v1(54.93,41.41) v1(55.19,109.32) v1(55.19,106.71) v1(55.23,100.47) v1(55.23,31.99) v1(55.23,30.82) v1(55.23,29.65) v1(55.33,148.82) v1(55.33,147.55) v1(55.9,44.31) v1(55.9,43.34) v1(55.9,41.41) v1(56.35,55.86) v1(56.54,85.52) v1(57.92,55.81) v1(58.61,119.74) v1(58.61,118.59) v1(58.61,117.45) v1(58.61,116.31) v1(58.61,115.16) v1(58.61,97.18) v1(58.61,96.04) v1(58.61,94.89) v1(58.61,93.75) v1(58.61,92.61) v1(59.75,118.59) v1(59.75,117.45) v1(59.75,116.31) v1(59.75,115.16) v1(59.75,96.04) v1(59.75,94.89) v1(59.75,93.75) v1(59.75,92.61) v1(59.79,126.87) v1(60.44,26.15) v1(60.9,118.59) v1(60.9,117.45) v1(60.9,116.31) v1(60.9,115.16) v1(60.9,96.04) v1(60.9,94.89) v1(60.9,93.75) v1(60.9,92.61) v1(61.17,86.01) v1(61.37,41.1) v1(62.04,118.59) v1(62.04,117.45) v1(62.04,116.31) v1(62.04,115.16) v1(62.04,96.04) v1(62.04,94.89) v1(62.04,93.75) v1(62.04,92.61) v1(62.48,109.68) v1(63.01,88.62) v1(63.18,119.74) v1(63.18,118.59) v1(63.18,117.45) v1(63.18,116.31) v1(63.18,115.16) v1(63.18,97.18) v1(63.18,96.04) v1(63.18,94.89) v1(63.18,93.75) v1(63.18,92.61) v1(64.77,126.9) v1(64.82,134.39) v1(65,140.78) v1(65.91,89.08) v1(66.14,135.64) v1(66.49,139.4) v1(66.53,140.73) v1(67.91,137.99) v1(68,140.8) v1(68.71,135.94) v1(69.03,47.2) v1(69.65,140.78) v1(69.62,60.2) v1(69.91,137.97) v1(69.94,48.12) v1(69.94,47.2) v1(71,140.78) v1(71.22,138.18) v1(72.4,105.01) v1(72.4,104.24) v1(72.65,140.78) v1(74.16,53.12) v1(75.83,25.26) v1(75.83,24.24) v1(75.83,23.23) v1(76.85,25.26) v1(76.85,23.23) v1(78.33,37.56) v1(81.95,62.52) v1(82.71,62.52)
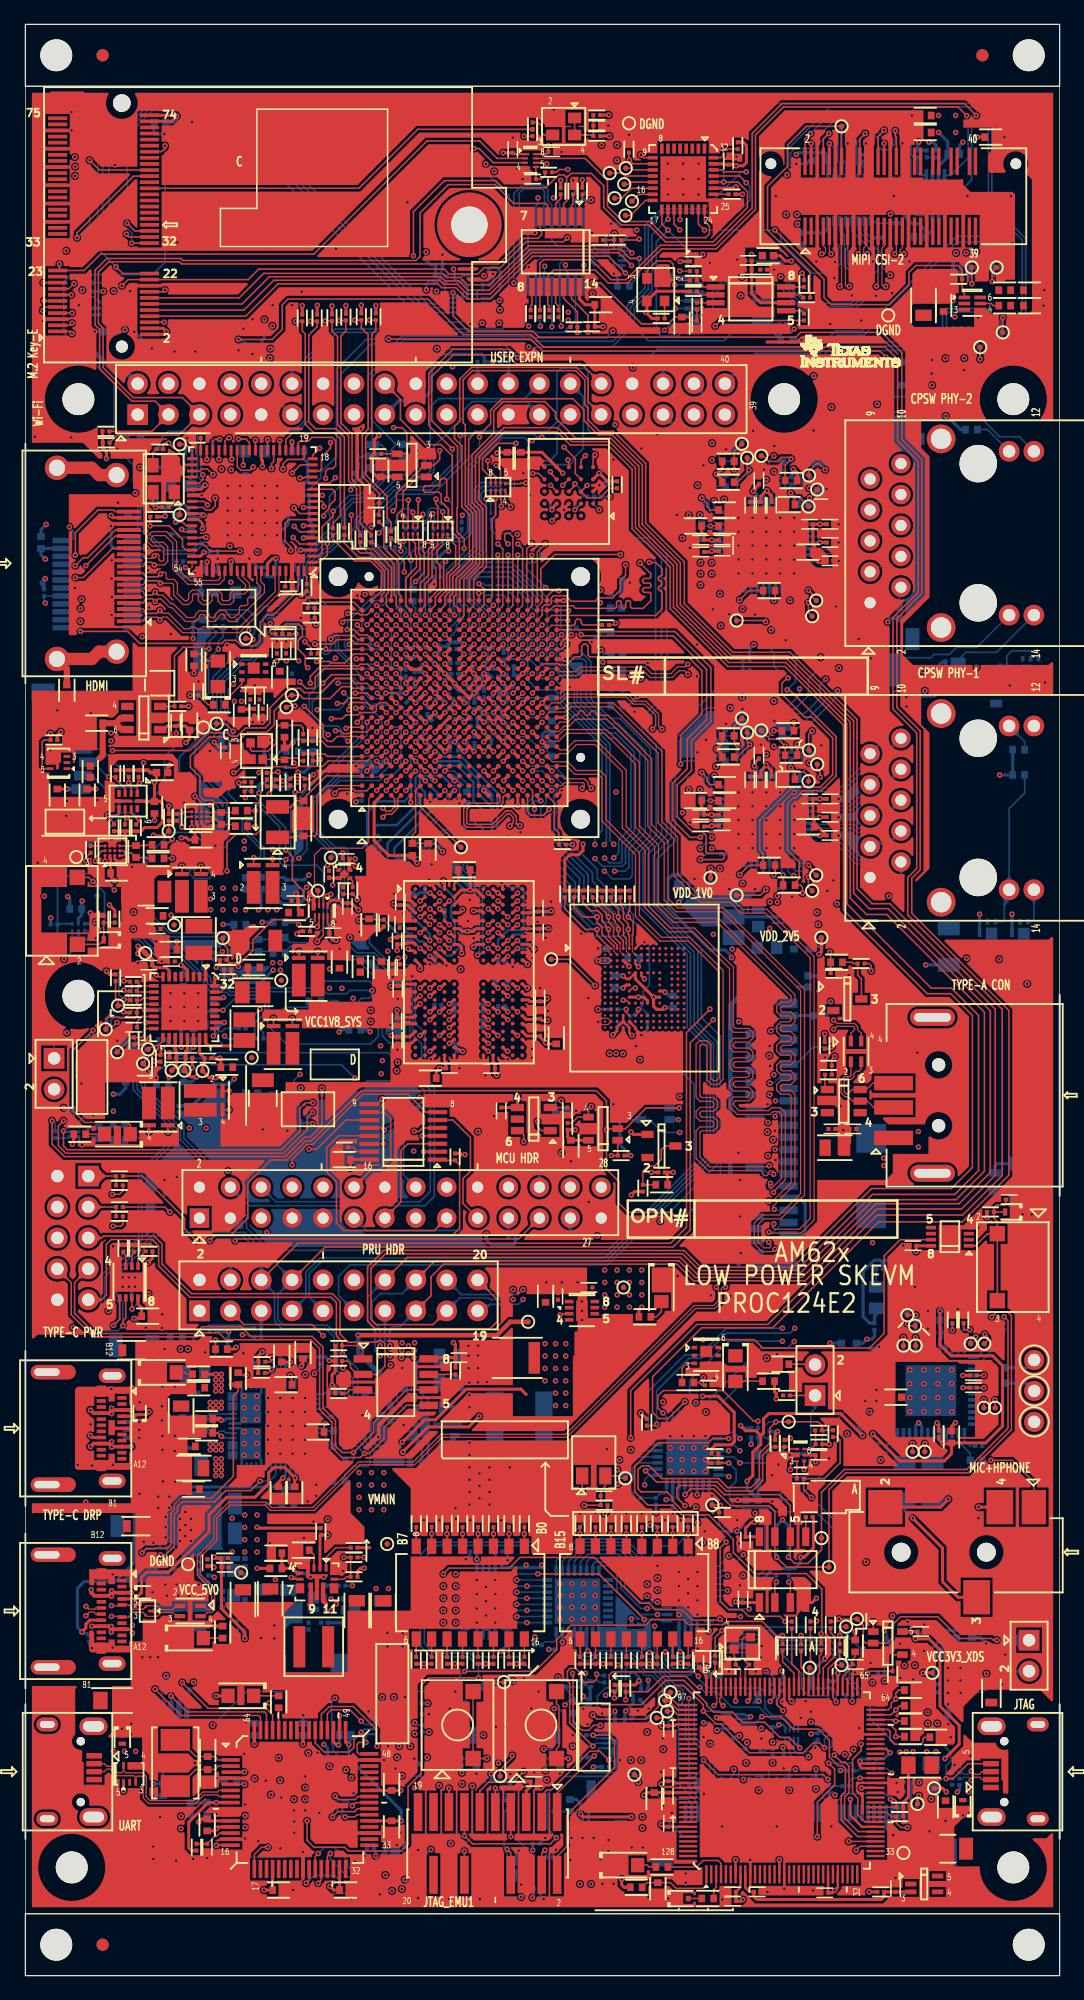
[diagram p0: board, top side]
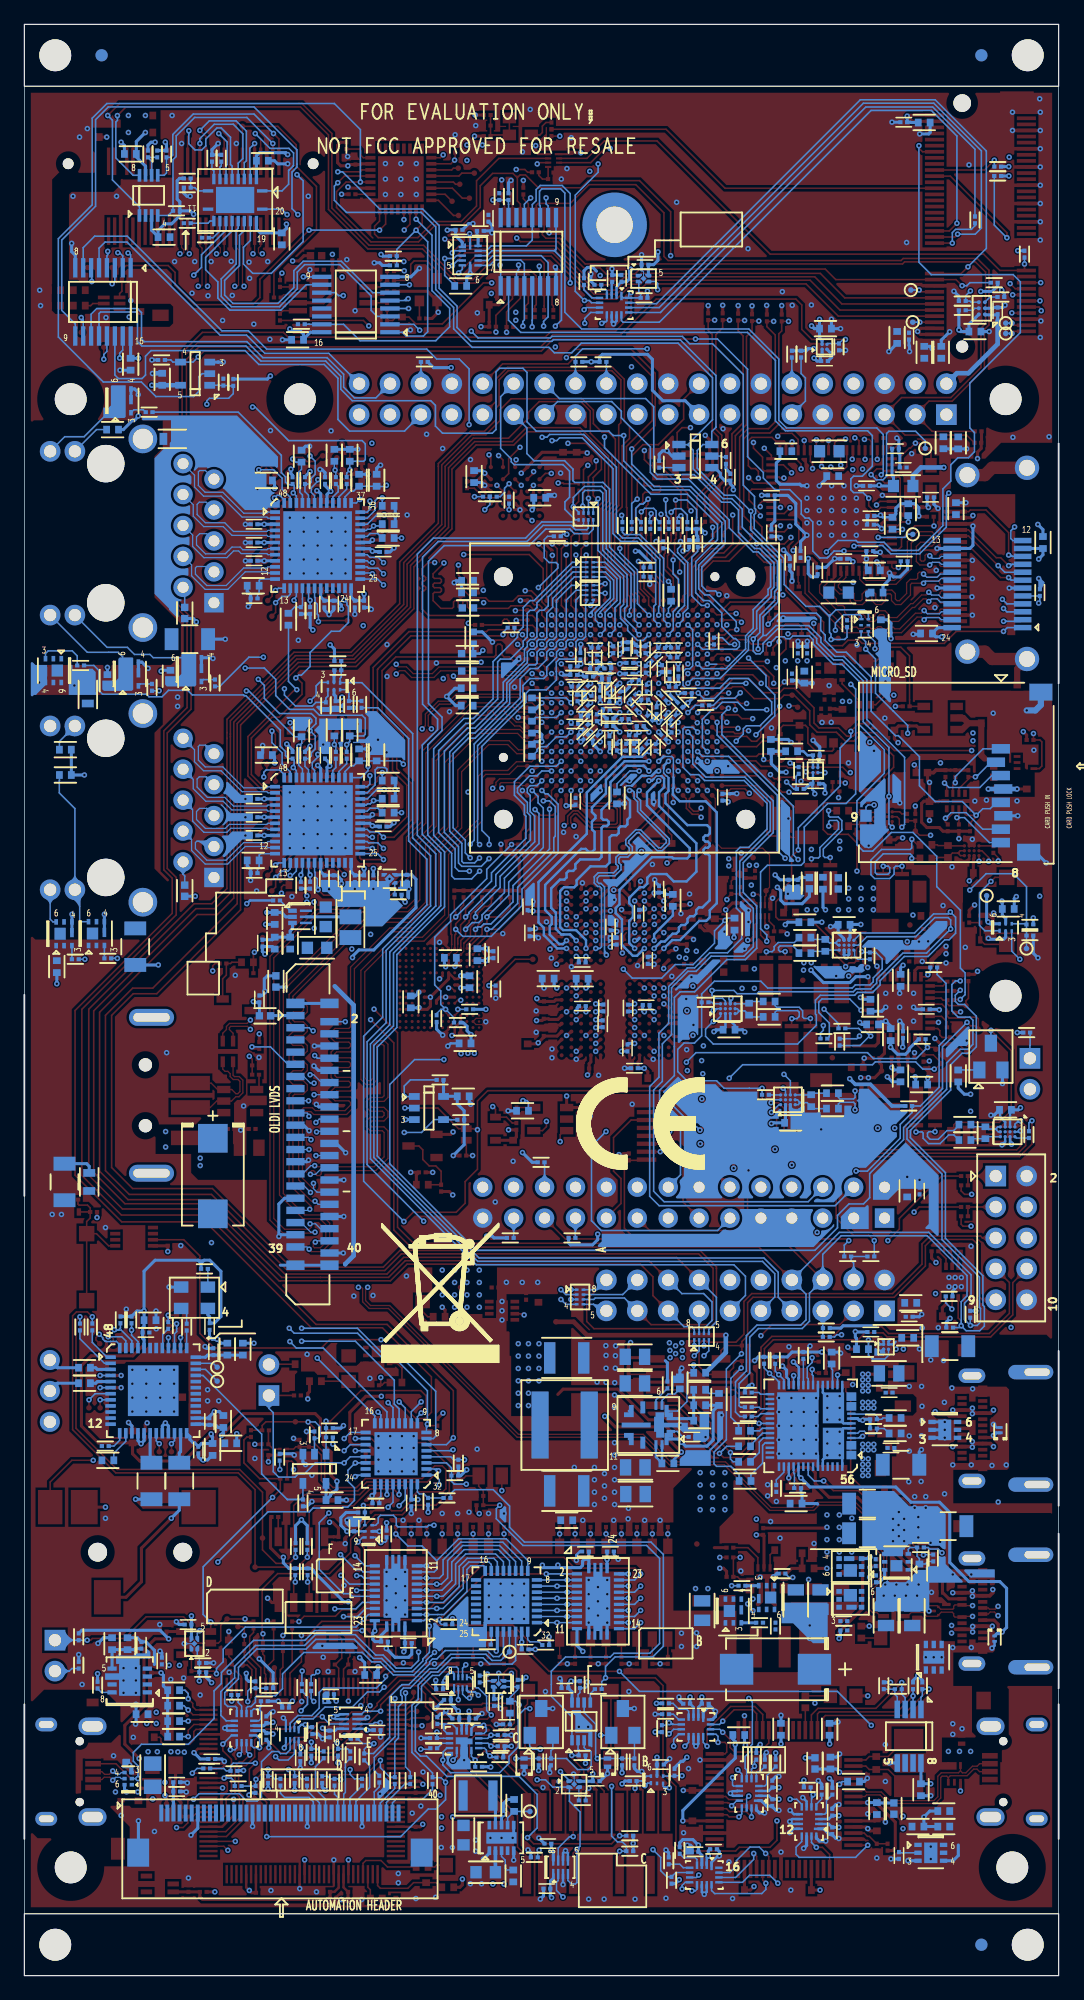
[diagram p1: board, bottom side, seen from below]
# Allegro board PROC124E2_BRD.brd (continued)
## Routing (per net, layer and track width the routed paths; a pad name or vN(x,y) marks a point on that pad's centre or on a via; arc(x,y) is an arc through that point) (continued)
VBUS_5V0_TYPEA1: length 1.1
  TOP w0.132: R119.2 69.32,83.13 69.52,82.93 v1(69.52,82.52)
  BOTTOM w0.132: C375.1 69.53,68.79
  vias: v1(73.39,69.33) v1(73.39,68.06)
VBUS_TYPEC1: length 8.5
  TOP w0.254: R165.1 v1(15.65,49.39) v1(16.1,49.39)
  TOP w0.305: v1(5.35,46.45) 5.6,46.2 J13.B9 6.88,46.2 7.13,46.45 J13.A4 v1(8.7,46.45) ; v1(5.35,43.45) 5.6,43.7 J13.B4 6.88,43.7 7.13,43.45 J13.A9 v1(8.7,43.45)
  vias: v1(7.09,46.61) v1(7.09,46.15) v1(7.09,43.86) v1(7.09,43.4) v1(15.65,48.94) v1(15.65,48.48) v1(15.65,48.02) v1(16.1,48.94) v1(16.1,48.48) v1(16.1,48.02)
VBUS_TYPEC2: length 8.6
  TOP w0.254: R214.1 v1(15.57,28.71) ; v1(49.79,64.12) 50.07,64.4 R147.2
  TOP w0.305: v1(8.7,31.45) J15.A4 7.09,31.45 6.84,31.2 J15.B9 5.67,31.2 5.41,31.45 v1(5.41,31.71) ; v1(5.45,28.7) J15.B4 6.84,28.7 7.09,28.45 J15.A9 8.48,28.45
  vias: v1(7.09,31.61) v1(7.09,31.15) v1(7.07,28.68) v1(7.07,28.22) v1(8.8,28.76) v1(8.8,28.13) v1(15.19,43.64) v1(15.19,43.18) v1(15.65,43.64) v1(15.65,43.18) v1(16.1,43.64) v1(16.1,43.18)
VCC1V1: length 8.1
  TOP w0.254: 16.86,76.36 15.07,76.36 14.82,76.62 U22.24
  BOTTOM w0.305: v1(17.17,73.66) 16.71,73.2 15.47,73.2 13.69,71.42 R578.2
VCC1V8_CLKBUF: length 12.7
  TOP w0.254: R17.2 54.19,138.33 54.18,138.34 51.87,138.34 U5.4 51.08,136.7 v1(50.99,136.61) 51.49,136.1 R27.2 ; v1(53.81,140.78) 53.86,140.78 53.88,140.79 C9.2 ; C8.2 C10.2 59.68,138.13 60.42,137.39 U6.6
  vias: v1(59.68,141.37)
VCC1V8_SYS: length 77.6
  TOP w0.152: 25.09,88.33 24.84,88.08 U19.1
  TOP w0.178: C3.2 40.17,149.6 U2.1
  TOP w0.203: v1(50.38,82.86) 50.13,83.11 U21.C6 ; U21.M4 U21.N4 ; U21.N4 U21.P3 48.63,77.57 48.35,77.28 v1(48.29,77.28) ; U21.N4 U21.P5 49.63,77.45 v1(49.86,77.22)
  TOP w0.254: v1(45.83,92.92) 45.83,92.41 45.48,92.06 44.74,92.06 44.33,91.65 R107.1 R108.1 R109.1 R110.1 R111.1 R112.1 R113.1 R114.1 ; C3.2 v1(39.27,149.71) ; FL1.1 62.02,141.25 62.45,140.83 v1(62.95,140.83) ; U25.5 C112.1 44.56,68.88 R138.1 v1(45.21,69.47) ; U22.32 15.57,81.92 v1(15.68,82.04) ; U10.D1 v1(47.16,123.4) 47.83,122.72 R37.2 ; v1(44.16,123.4) U10.E4 42.45,125.11 C18.1 C17.2 38.8,125.11 v1(38.74,125.06) ; R582.1 v1(48.01,151.08) ; U22.20 v1(12.82,76.26) ; U8.5 C19.1 28.91,123.09 28.43,123.56 28.43,124.74 R35.2 28.68,126.14 v1(29.04,126.5) ; v1(27.37,87.54) 26.81,88.09 C73.1 26.07,88.09 25.84,88.33 25.09,88.33 ; R283.2 v1(26.34,137.16) ; v1(23.99,137.18) 23.98,137.18 R285.2 ; R282.2 v1(27.61,137.19) ; v1(22.31,85.56) 22.52,85.77 R116.1 ; v1(43.27,120.38) 43.27,120.5 U10.B4 ; v1(25.2,137.13) R286.2 ; v1(28.8,137.16) R284.2 ; R287.2 v1(22.76,137.16)
  L05_PWR02 w0.254: v1(48.01,151.08) 44.35,151.08
  BOTTOM w0.203: U72.5 C417.2 ; U44.2 36.33,138.69 36.22,138.8 36.22,138.82 C184.2
  BOTTOM w0.254: R471.1 58.56,38.04 58.99,37.61 58.99,36.99 v1(58.48,36.49) C417.2 ; 48.92,78.27 48.61,77.96 48.61,77.61 v1(48.29,77.28) C365.1 ; v1(43.27,120.38) 43.14,120.51 C209.1 ; R332.2 30.35,117.88 R333.2 29.66,118.21 29.75,118.3 R326.2 ; C184.2 35.52,139.11 35.26,139.36 35.26,140.07 v1(35.18,140.15) ; R326.2 29.38,118.82 v1(29.06,118.5) ; R326.2 R325.2 ; v1(20.36,82.58) 19.33,81.56 17.15,81.56 16.67,82.04 v1(15.68,82.04) ; C364.1 12.79,76.29 v1(12.82,76.26) ; C203.1 47.37,123.61 v1(47.16,123.4) ; R398.1 v1(47.07,79.36) ; v1(50.38,82.86) 50.48,82.96 C345.1 ; U40.1 49.01,142.35 49.56,142.9 C179.2 50.22,143.38 v1(50.24,143.36) ; R434.2 v1(66.13,51.94) ; R262.2 v1(3.36,141.67) ; v1(34.78,116.99) 34.48,116.99 33.6,116.11 33.6,116.11 33.55,116.06 R304.2
  vias: v1(20.33,83.19) v1(20.94,83.19) v1(20.96,82.58) v1(48.02,75.75) v1(48.55,75.75) v1(49.11,75.73) v1(57.15,110.87)
VCC2V5_PG: length 14.7
  L05_PWR02 w0.381: v1(53.71,88.17) 57.85,88.17 58.71,87.31 64.54,87.31 64.55,87.32 v1(65.07,87.32)
  BOTTOM w0.254: U57.2 63.51,86.96 63.88,87.32 R386.1 v1(65.07,87.32) ; v1(53.71,88.17) 54,88.46 R383.1
VCC3V3_EXP: length 32.5
  L04_PWR01 w0.381: v1(49.92,132.06) 47.66,134.32 40.19,134.32 v1(38.41,132.55)
  BOTTOM w0.254: R294.1 R295.1 20.75,133.45 20.58,133.62 v1(20.12,133.62) ; R298.1 39.14,132.55 v1(38.41,132.55) 37.74,132.55 R299.1 37.73,132.93 37.5,133.16 33.79,133.16 33.39,132.75 33.39,130.21 32.52,129.35 30.69,129.35 J3.17 ; U46.A1 19.44,133.14 19.57,133 19.57,132.66 C192.1 19.85,132.6 v1(20.1,132.85) ; v1(49.92,132.06) 51.38,132.06 R297.1
VCC3V3_PRU: length 4.7
  BOTTOM w0.203: 14.8,51.95 14.69,51.85 U65.A1 14.38,52.13 14.5,52.25
  BOTTOM w0.254: R432.1 17.9,53.18 17.71,53.38 15.08,53.38
VCC3V3_TA: length 7.8
  TOP w0.254: v1(45.63,13.27) 45.86,13.04 v1(49.8,13.04) ; TP91.1 73.32,14.66 v1(73.44,14.78)
  BOTTOM w0.254: R559.2 45.3,14.47 45.63,14.14 v1(45.63,13.27) 45.78,13.12 U93.8
  vias: v1(50.71,13.04) v1(50.71,12.13) v1(73.44,15.88) v1(74.45,14.51)
VCC3V3_XDS: length 50.9
  TOP w0.203: U36.79 62.77,22.75 v1(62.97,22.55) ; U36.51 68.77,17.03 68.56,17.23 v1(68.56,17.6) 68.74,17.43 U36.52 ; U36.47 68.72,15.43 v1(68.71,15.42) ; U36.16 v1(61.97,9.51) ; C158.1 53.29,15.98 53.44,15.83 U36.113 ; U36.101 53.48,20.63 53.37,20.52 C155.2 ; U36.28 66.77,7.25 v1(66.51,7) ; C164.1 U36.122 ; U36.26 C174.1 ; C172.1 58.77,7.25 U36.8 ; U36.7 v1(58.37,9.51) ; U36.90 v1(58.37,22.55) ; v1(67.8,14.48) 67.8,13.17 68.74,12.23 U36.39 ; v1(66.76,24.82) 66.76,24.77 66.77,24.76 U36.69
  TOP w0.254: v1(58.96,6.25) 58.83,6.12 C175.1 C172.1 ; v1(52.26,12.43) 52.46,12.23 C164.1 ; v1(52.25,15.72) 52.5,15.98 C158.1 ; R248.1 72.57,14.67 72.12,14.22 R249.1 R250.1 ; C174.1 66.32,6.81 v1(66.51,7) ; TP81.1 v1(73.77,24.87) ; C155.2 v1(52.32,20.52) ; R255.1 v1(69.34,6.88) ; R215.2 v1(68.2,28.26)
  BOTTOM w0.178: U85.8 62.46,18.93 v1(62.26,18.73)
  BOTTOM w0.203: U82.8 59.31,20.27 59.45,20.13 C449.2
  BOTTOM w0.254: v1(66.76,24.82) 66.76,24.37 66.56,24.17 R497.2 ; v1(73.77,24.87) 73.58,24.68 73.58,23.8 R507.2 R511.2 R515.2 R518.2 ; C453.2 68.76,17.79 v1(68.56,17.6) ; v1(62.97,22.55) 63.25,22.27 C439.1 ; U84.2 65.32,20.13 C451.2 64.64,19.92 v1(64.57,19.85) ; v1(62.26,18.73) 62.32,18.66 C452.2 ; R487.1 75.71,27.75 C429.1 75.01,27.42 74.31,26.72 74.31,25.55 ; v1(60.49,20.33) 60.29,20.13 C449.2
  vias: v1(71.85,18.35) v1(72.25,25.49) v1(72.38,18.38) v1(72.95,18.39) v1(73.1,25.49)
VCC3V3_XDS_TA: length 66.1
  TOP w0.254: U32.1 58.99,30.64 C149.1 58.45,30.63 v1(58.37,30.71) ; v1(63.71,34.36) 64,34.36 64.77,35.13 64.77,37.59 R200.2 ; R231.2 v1(47.49,25.61) R230.2 R229.2 ; v1(75.56,17.83) 76.74,19.01 76.74,20.56 75.17,22.13 75.17,26.75 74.27,27.66 v1(73.14,27.66) 73.31,27.83 C150.1 U34.5 ; R221.2 v1(32.75,25.61) R222.2 ; R235.2 53.37,25.61 53.38,25.63 53.76,25.63 53.82,25.69 v1(53.85,25.69) 53.91,25.69 53.98,25.61 R236.2 ; R225.2 v1(37.83,25.61) R226.2 ; R234.2 v1(51.3,25.61) R233.2 R232.2 ; R228.2 v1(40.37,25.61) R227.2 ; R223.2 v1(35.29,25.61) R224.2
  BOTTOM w0.254: C418.2 38.61,34.19 ; 38.61,34.19 38.98,34.19 39.13,34.04 39.13,33.69 39.31,33.51 42.55,33.51 ; 38.61,34.19 U75.1 ; v1(49.81,29.31) 49.81,29.03 49.83,29.01 R483.2 ; R520.2 58.42,19.7 v1(58.67,19.7) ; R542.2 v1(62.78,15.23) ; v1(66.99,16.85) 67.46,16.85 R537.1 ; v1(63.71,34.36) 63.71,33.9 63.25,33.44 R479.1 R480.1 61.41,33.44 61.23,33.26 61.23,33.2 58.74,30.71 v1(58.37,30.71) ; U74.31 v1(44.13,27.39) C430.2 ; R541.2 v1(64.97,15.34) ; R524.2 v1(59.23,17.48) ; v1(66.54,14.84) 66.37,15.01 R555.1 ; U74.27 46.13,26.74 v1(46.22,26.65) ; R489.2 v1(41.87,27.82) ; v1(61.41,17.49) R523.2 ; J24.3 72.75,14.28 72.76,14.29 C462.1 C459.1 ; v1(73.14,27.66) 73.85,28.36 80.27,28.36 R485.2 ; R543.2 60.52,15.49 v1(60.26,15.22) ; U73.1 C428.2 53.72,26.7 v1(53.82,26.61)
  vias: v1(41.16,33.71) v1(42.43,33.71) v1(74.07,18.39) v1(74.83,18.39)
VCC5V0_EXP: length 9.1
  BOTTOM w0.254: U45.A1 6.02,136.4 5.06,136.4 C185.1 5.01,135.97
  BOTTOM w0.381: J3.2 8.36,131.61 7.41,131.61 5.01,134.01 5.01,135.97
VCC_0V85: length 3.6
  TOP w0.254: TP51.1 12.41,74.72 C100.1 12.41,75.88 12.37,75.91 12.37,76.04 12.32,76.1 U22.19
  BOTTOM w0.254: v1(11.8,73.82) 11.75,73.78 C369.2
VCC_1V8_AUD: length 3.9
  BOTTOM w0.254: R434.1 C388.1 C389.1 69.94,50.96 70.11,50.79 U66.36
VCC_1V8_FT4232: length 36.1
  TOP w0.254: v1(30.88,12.71) C166.2 U37.37 ; U37.49 26.32,19.19 26.53,18.98 v1(26.58,18.98) ; v1(14.24,12.62) 14.49,12.87 C165.2 15.1,12.71 U37.12 ; U37.64 v1(18.82,19.03)
  L05_PWR02 w0.254: v1(26.58,18.98) 25.46,20.1 22.64,20.1 21.57,19.03 v1(18.82,19.03) 16.68,19.03 13.78,16.14 13.78,13.07 v1(14.24,12.62)
  BOTTOM w0.254: v1(30.88,12.71) 30.88,13.56 26.58,17.87 v1(26.58,18.98) 26.58,19.24 26.78,19.44 C450.1 ; C446.2 v1(18.82,19.03)
VCC_3V3_AUD: length 80.4
  TOP w0.254: 60.43,44.36 60.43,43.64 59.78,42.99 59.78,41.07 v1(59.31,40.6) ; 60.43,44.36 60.03,44.76 59.19,44.76 v1(58.77,45.17) ; 60.43,44.36 60.66,44.59 60.66,45.73 61.1,46.16 67,46.16 v1(68.8,44.36) ; C133.1 78.92,43.76 80.31,45.14 80.31,50.1 79.5,50.9 76.08,50.9 75.16,51.83 v1(75.16,54.58) ; C133.1 76.04,43.69 v1(75.41,43.69) 75.07,44.03 C132.1 ; C133.1 76.11,42.86 75.51,42.27 71.87,42.27 v1(69.65,44.49)
  BOTTOM w0.254: v1(59.31,40.6) 59.31,39.95 59.56,39.71 59.64,39.71 59.84,39.51 59.84,39.43 C412.1 U71.5 ; v1(75.16,54.58) 75.16,57.85 74.25,58.76 70.73,58.76 70.48,58.5 ; v1(75.16,54.58) C382.1 75.16,53.32 75.29,53.2 C385.1 75.29,52.36 75.16,52.23 U66.44 ; v1(75.16,54.58) 75.74,54.58 R426.1 R425.1 ; U66.17 75.16,43.94 v1(75.41,43.69) 75.66,43.94 U66.16 ; R451.2 58.98,44.97 v1(58.77,45.17) ; U64.4 69.92,54.27 69.77,54.12 C383.1 69.38,53.59 68.84,54.13 68.84,57.84 69.76,58.76 70.22,58.76 70.48,58.5 ; v1(69.65,44.49) 69.65,44.33 69.53,44.21 C402.1 70.44,43.71 C403.1 70.7,43.46 71.03,43.78 71.14,43.78 71.39,44.04 71.39,44.27 U66.24 ; v1(68.8,44.36) 68.64,44.51 C399.1 69.07,45.02 69.28,45.23 C398.1 70.16,45.23 70.22,45.29 U66.25 ; 70.48,58.5 R422.1
VCC_3V3_FB: length 4.5
  BOTTOM w0.254: C396.2 R445.2 29.99,45.61 ; 29.99,45.61 30.13,45.75 U67.4 ; 29.99,45.61 R450.1
VCC_3V3_FT4232: length 23.7
  TOP w0.254: U37.20 C170.2 v1(19.61,7.03) ; U37.31 C171.2 25.33,7.03 v1(25.03,7.33) ; v1(30.85,15.21) C160.2 U37.42 ; LD10.2 v1(15.69,22.98) ; U37.50 v1(25.82,21.34) ; U37.56 v1(22.82,19.03)
  BOTTOM w0.203: C469.2 18.89,12.46 U92.2 ; U96.2 28.92,9.71 v1(28.79,9.84) ; U83.2 29.61,22.05 C438.2 ; U91.2 23.82,14.77 C463.2
  BOTTOM w0.254: C472.2 28.79,10.23 v1(28.79,9.84) ; C469.2 v1(18.06,12.18) ; R500.2 11.96,24.24 v1(11.57,24.64) 11.2,24.27 R501.2 ; FL19.2 v1(20.82,17.89) ; v1(10.51,15.76) C461.2 U86.8 ; R499.2 v1(13.82,24.09) ; C463.2 v1(22.99,14.49) ; C438.2 v1(29.33,22.88) ; C445.2 v1(22.82,19.03)
  vias: v1(12.79,13.09) v1(12.79,12.08)
VCC_3V3_MAIN: length 108.4
  TOP w0.254: v1(12.79,82.98) 12.81,82.98 12.82,82.97 12.94,82.97 13.32,82.59 U22.4 ; R105.1 7.35,87.49 v1(6.91,87.93) ; v1(27.85,33.46) 27.54,33.46 27.29,33.21 R210.2 ; U22.26 v1(16.35,78.29) ; v1(30.98,43.81) 32.82,45.65 33.72,45.65 36.23,48.17 40.73,48.17 41.16,47.74 ; U22.22 v1(13.82,76.25) ; U22.30 16.19,80.29 16.24,80.34 v1(16.29,80.34) ; v1(12.44,84.93) 12.46,84.91 C84.2 ; v1(9.81,79.32) 9.82,79.31 9.87,79.31 9.9,79.29 U22.13
  TOP w0.381: v1(27.35,52.6) 38.76,52.6 39.86,53.7 TP56.1
  L03_SIG1 w0.254: v1(26.68,85.26) 26.31,85.63 26.31,87.71 25.73,88.29 24.64,88.29 23.55,89.38 v1(23.11,89.38)
  L04_PWR01 w0.381: v1(16.35,78.29) 16.85,78.79 19.71,78.79 20.35,79.43 26.93,79.43 27.46,79.96 27.46,84.49 v1(26.68,85.26)
  L06_SIG2 w0.254: v1(27.85,33.46) 30.24,35.85 30.24,43.06 v1(30.98,43.81) ; v1(20.04,97.06) 20.04,97.05 20.9,96.19 20.9,90.35 21.87,89.38 v1(23.11,89.38)
  BOTTOM w0.203: v1(20.04,97.06) 20.04,97.21 20.24,97.41 C531.1 20.19,97.95 U125.B2
  BOTTOM w0.254: C361.2 16.18,78.12 v1(16.35,78.29) ; v1(12.79,82.98) 12.99,82.78 C350.2 ; R382.1 v1(2.08,86.87) ; C359.1 9.85,79.36 v1(9.81,79.32) ; R404.2 11.51,76.91 12.28,76.14 12.28,75.98 12.58,75.68 13.24,75.68 v1(13.82,76.25) 13.8,76.26 C363.2 ; v1(26.68,85.26) 26.68,85.83 R387.1 ; U67.1 31.24,44.07 v1(30.98,43.81) 30.66,43.49 28.9,43.49 28.39,43.99 28.39,46.39 27.95,46.83 R444.1 27.93,46.85 R445.1 ; C354.2 16.09,80.18 16.24,80.34 v1(16.29,80.34) ; v1(4.66,88.25) 4.63,88.25 C76.1 4.63,87.1 4.35,86.83 U59.5 ; v1(23.11,89.38) 22.83,89.1 22.83,88.32 22.56,88.04 21.08,88.04 20.48,88.64 FL14.1 ; C531.1 20.42,97.89 20.85,97.46 R586.1
  BOTTOM w0.381: R440.1 27.35,51.18 v1(27.35,52.6)
  vias: v1(42.71,51.9) v1(42.71,50.88) v1(42.71,49.87) v1(42.71,48.85) v1(43.57,51.9) v1(43.57,50.88) v1(43.57,49.87) v1(43.57,48.85) v1(43.57,47.84) v1(43.57,46.82) v1(44.41,51.9) v1(44.41,50.88) v1(44.41,49.87) v1(44.41,48.85) v1(44.41,47.84) v1(44.41,46.82)
VCC_3V3_MAIN_PG: length 148
  L03_SIG1 w0.254: v1(5.79,86.54) 3.71,86.54 0.71,83.54 0.71,55.47 2.95,53.24 v1(3.91,53.24)
  L04_PWR01 w0.381: v1(66.72,88.04) 66.72,87.52 66.74,87.5 66.74,83.96 64.75,81.97 58.96,81.97 57.64,80.65 57.64,69.12 56.83,68.31 42.02,68.31 40.34,66.63 34.6,66.63 33.38,65.41 33.38,50.83 31.86,49.31 30.83,49.31 v1(29.99,50.15)
  L05_PWR02 w0.254: v1(3.91,53.24) 4.41,52.74 11.95,52.74 12.56,53.35 25.86,53.35 29.07,50.15 v1(29.99,50.15)
  BOTTOM w0.127: U67.5 31.32,46.37 30.54,47.15 30.54,49.41 30.44,49.51 R440.2
  BOTTOM w0.132: v1(29.99,50.15) R440.2
  BOTTOM w0.203: R385.1 66.46,88.3 v1(66.72,88.04)
  BOTTOM w0.254: TP101.1 5.92,86.66 v1(5.79,86.54) 5.64,86.39 U59.6
VCC_3V3_SYS: length 277.9
  TOP w0.152: 24.99,86.28 24.84,86.43 U19.8
  TOP w0.178: C7.2 42.79,149.6 U2.8
  TOP w0.203: C81.2 24.99,86.28 ; v1(49.13,82.11) 49.38,81.86 U21.F5 U21.E6
  TOP w0.254: v1(7.34,89.92) 7.01,90.25 C67.1 7.01,91.48 7,91.49 7,91.71 6.95,91.77 U17.B1 ; J2.72 12.02,152.29 v1(12.45,152.72) 12.37,152.79 J2.74 ; C577.1 v1(56.4,116.99) 56.33,116.93 C567.1 ; v1(52.57,79.5) 52.42,79.36 51.88,79.36 51.63,79.61 U21.K9 v1(51.63,80.36) ; v1(59.82,121.9) 59.97,122.06 59.97,122.19 C563.1 ; v1(25.55,85.04) 25.3,85.04 24.99,85.35 C81.2 ; R645.2 57.28,123.79 v1(56.79,123.3) 57.28,122.82 R642.2 ; J2.4 11.33,135.29 v1(11.59,135.04) 11.35,134.79 J2.2 ; U31.5 C135.1 v1(64.94,42.21) ; v1(12.82,93.45) 12.83,93.46 13.24,93.46 13.42,93.28 C64.1 13.94,93.83 14.15,94.04 14.15,94.49 14.08,94.57 U16.B1 ; v1(40.43,72.24) U24.4 C108.2 ; v1(59.9,99.35) 59.97,99.42 59.97,99.63 C44.1 ; C59.1 v1(56.4,94.44) 56.33,94.37 C60.1 ; R56.2 v1(13.86,107) ; C7.2 v1(42.98,150.3) ; U3.27 58.31,146.8 v1(58.4,146.9) ; v1(10.63,75.12) 10.68,75.07 R130.2 ; R581.1 v1(47.95,152.81) ; U18.4 C66.1 ; U13.1 11.38,102.34 11.68,102.64 C38.1 13.16,102.64 C40.1 13.5,101.57 v1(13.19,101.27) ; v1(3.87,68.28) 3.98,68.39 R139.2 ; R182.1 47.84,38.17 v1(47.61,37.95) ; R64.2 57.28,101.23 v1(56.79,100.75) 57.28,100.27 R69.2 ; R589.2 17.17,51.46 v1(17.32,51.61) ; R591.2 16.89,82.35 17.15,82.09 v1(17.26,82.09) ; v1(50.43,24.23) 50.43,24.19 50.12,23.87 R239.1 R238.1 ; R8.1 v1(45.77,147.48) ; v1(55.66,47.58) 56.93,47.58 58.25,46.26 58.25,44.31 58.26,44.3 58.26,43.92 58.25,43.91 58.25,43.85 58,43.6 56.72,43.6 56.39,43.27 R179.2 ; R141.2 v1(49.75,67.35) ; U32.8 59.58,36.04 C141.1 59.18,36.75 59.66,37.24 v1(59.92,37.24) ; v1(51.63,80.36) 50.13,81.86 U21.E6 ; v1(51.63,80.36) U21.J10 ; R31.1 6.34,125.92 R33.1 6.36,125.43 6.67,125.13 v1(6.67,124.6) ; R39.2 10.72,120.6 v1(10.7,120.58) 10.49,120.8 U9.4 ; R128.2 9.69,76.49 v1(10.17,76.97) ; v1(6.66,82.48) 6.91,82.24 R122.2 ; U4.14 45.53,137.7 46.01,137.23 C15.2 46.79,135.83 46.8,135.82 R29.1 v1(47.47,135.43) ; R167.2 61.56,47.97 61.71,47.82 v1(61.71,47.37) ; R650.2 63.43,123.44 63.14,123.72 v1(63.09,123.72) ; R9.2 v1(58.93,146.3) ; v1(8.06,79.16) 8.12,79.1 R127.2 ; R68.2 63.43,101.14 v1(63.44,101.15) ; R86.2 v1(11.78,96.06) ; R154.1 10.44,58.93 v1(10.08,58.57) ; R61.2 v1(13.42,104.25) ; v1(26.71,66.32) C113.2 U26.16 ; U3.31 57.33,148.8 57.39,148.74 C6.2 58.31,148.74 v1(58.41,148.64) 59,148.64 59.26,148.9 59.26,150.32 59,150.57 R3.2 ; v1(2.91,102.17) 2.63,101.89 R67.2 ; U28.8 9.26,55.15 9.56,54.85 C119.1 9.4,54.01 8.95,54.01 v1(8.93,53.98) ; v1(41.06,15.95) C159.1 41.51,15.53 41.16,15.18 J19.5 ; R155.2 50.42,54.66 50.47,54.7 50.47,54.71 v1(50.66,54.9) ; v1(62.88,44.13) 62.74,44 R177.2 ; R6.1 v1(43.99,147.44) ; R178.2 v1(66.06,43.64) ; R173.2 v1(50.6,46.2) ; R151.1 v1(65.69,77.34)
  BOTTOM w0.178: 49.79,23.15 49.69,23.26 U79.1 ; 49.79,24.9 49.69,24.79 U79.8 ; U85.1 62.46,20.4 62.24,20.61 v1(61.91,20.61)
  BOTTOM w0.203: U83.3 30.01,22.05 C437.2 ; U63.B1 3.99,70.99 C372.1 ; U87.3 49.06,20.63 ; v1(3.87,68.28) 3.99,68.41 U63.B3 ; v1(50.43,24.23) 50.43,24.49 50.02,24.9 49.79,24.9 ; 13.8,52.27 13.98,52.09 U65.A2 13.61,51.85 13.4,52.05 ; v1(56.84,20.17) 56.95,20.27 U82.1 ; C460.2 23.82,15.17 U91.3 ; U44.3 36.73,139.07 C183.2 ; U87.2 48.66,20.6 ; C466.2 18.89,12.86 U92.3 ; U60.B1 27.39,77.88 C362.1 ; C476.2 41.77,7.78 41.53,8.02 U95.1 ; 47.71,142.07 U40.11
  BOTTOM w0.254: U84.3 65.32,20.53 C443.2 64.64,20.74 v1(64.57,20.81) ; v1(38.29,16.58) C458.2 U90.5 ; C437.2 v1(30.29,22.88) ; U128.5 59.55,105.21 59.43,105.08 C588.1 59.16,104.67 58.9,104.93 v1(58.9,105) ; U48.4 28.26,123.85 27.8,123.38 27.8,123.14 27.44,122.78 C204.2 26.99,122.51 26.76,122.28 26.76,122.06 v1(26.73,122.03) ; R531.1 42.74,16.85 v1(42.73,16.85) ; R647.1 76.86,126.97 76.07,127.76 75.92,127.76 75.64,128.04 v1(75.64,128.09) ; U55.19 60.65,90.68 C322.1 C323.1 59.31,90.37 58.94,90 v1(58.94,89.7) ; v1(48.45,21.72) C442.2 48.45,20.81 48.66,20.6 ; v1(28.33,77.53) 28.18,77.68 C362.1 ; v1(63.44,101.15) 62.95,100.67 R369.2 ; v1(8.93,53.98) 9.23,53.68 R431.1 ; 62.05,134.41 62.05,134.81 62.31,135.06 63,135.06 v1(63.18,135.24) ; 62.05,134.41 61.49,134.97 U43.16 ; 62.05,134.41 C181.2 ; R370.2 61.94,100.55 v1(61.52,100.97) ; U75.23 v1(35.37,32.99) ; 1.54,114.65 1.29,114.39 R342.2 1.54,114.65 ; 1.54,114.65 v1(1.64,114.74) ; R289.2 v1(33.79,138.34) ; R457.2 v1(67.54,44.51) ; v1(43.78,24.5) 43.99,24.29 R495.2 ; R557.2 18.59,15.95 v1(18.84,16.19) ; R652.2 R630.1 61.52,110.74 v1(61.29,110.52) ; U127.41 60.13,120.97 60.13,121.65 59.87,121.9 v1(59.82,121.9) 60.29,122.37 C563.1 ; v1(18.06,13.14) C466.2 ; C44.1 59.97,99.63 59.97,99.42 v1(59.9,99.35) 60.01,99.35 60.13,99.23 60.13,98.41 U55.41 ; v1(46.67,17.13) 46.69,17.15 46.89,17.15 46.9,17.15 R535.2 ; C230.1 14.06,111.35 13.78,111.07 13.78,110.27 13.78,110.27 v1(13.78,109.81) ; C180.2 47.8,142.9 47.71,142.81 47.71,142.07 ; C60.1 55.94,94.37 55.97,94.41 56.37,94.41 v1(56.4,94.44) 56.61,94.64 U55.30 ; v1(35.88,15.75) 35.64,15.99 R547.1 ; U89.5 C457.2 v1(33.01,17.93) ; 37.98,139.98 38.29,140.29 38.73,140.29 39.01,140.01 R278.2 ; R462.2 49.33,41.08 R463.2 49.13,41.07 v1(48.65,41.55) ; R554.1 v1(20.94,16.04) ; R648.2 62.95,123.22 63.09,123.36 63.09,123.72 v1(63.09,123.72) ; R468.2 v1(51.82,38.06) ; U127.19 60.65,113.23 C570.1 C583.1 59.31,112.93 58.94,112.56 v1(58.94,112.25) ; v1(26.93,80.27) 26.99,80.22 U60.C3 ; v1(70.87,111.18) 70.87,111.21 71.12,111.46 71.81,111.46 FL22.1 ; v1(47.01,60.73) 46.55,60.73 46.41,60.59 R418.2 ; R402.2 v1(3.4,77.45) ; 49.79,23.15 49.95,22.99 C435.2 49.95,22.35 v1(49.34,21.74) 49.26,21.66 C441.2 49.26,20.83 49.06,20.63 ; FL16.1 71.81,88.65 v1(70.95,88.65) ; R510.2 v1(33.05,22.36) ; v1(64.42,122.16) 64.42,122.21 64.44,122.22 64.44,122.63 C579.1 ; v1(75.62,132.83) C193.2 U42.16 ; C372.1 3.31,71.11 v1(3.14,71.28) ; R527.2 v1(38.88,17.44) ; v1(80.07,98.61) R373.2 R365.1 ; U50.24 9.88,110.71 9.89,110.71 9.93,110.71 10.37,110.27 C232.2 10.09,109.96 v1(9.61,109.96) ; C208.2 10.81,120.69 v1(10.7,120.58) ; U70.31 C413.2 v1(52.66,39.1) ; R474.1 61.75,36.96 v1(62.23,37.44) 62.71,36.96 R473.1 ; C433.2 50.59,24.09 50.46,24.23 v1(50.43,24.23) ; R634.2 61.94,123.11 v1(61.52,123.53) ; v1(75.05,151.38) 75.8,150.63 C477.2 75.8,149.37 75.04,148.61 U97.7 ; R407.2 50.56,72.72 50.55,72.71 U62.5 50.53,72.22 C370.1 49.42,71.59 48.85,71.03 48.85,70.68 R412.1 48.85,68.25 v1(49.75,67.35) ; R492.2 70.06,24.51 v1(69.61,24.06) ; v1(61.91,20.61) 61.71,20.41 C448.2 ; v1(23.61,69.99) 23.55,70.04 C373.1 22.45,70.11 U61.B1 ; R530.2 45.64,18.31 45.53,18.42 R521.2 v1(44.98,18.84) ; U98.19 65.93,143.44 65.61,143.13 C479.2 63.82,143.13 63.46,143.49 v1(63.46,143.85) ; R658.2 59.52,108.95 v1(59.87,109.3) ; 53.17,79.49 52.59,79.49 v1(52.57,79.5) ; R496.1 v1(40.07,24.19) 40.3,23.96 C432.2 39.99,23.31 U81.8 ; v1(73.76,107.14) 73.69,107.21 R655.2 ; v1(12.45,152.72) 12.45,152.72 C176.2 12.18,152.22 12.15,152.2 C177.1 ; v1(6.4,138.32) 5.46,138.32 5.01,138.77 R279.2 ; v1(44.06,67.6) 43.26,66.8 R416.1 ; U95.8 41.53,10.13 v1(41.69,10.3) C471.2 ; C186.1 19.65,134.51 19.44,134.3 U46.A2 ; C186.1 20.08,135.26 v1(20.31,135.49) ; C186.1 v1(19.65,136.02) ; v1(16.26,86.33) 17.11,86.33 C335.1 17.14,85.26 17.23,85.17 U58.B1 ; v1(71.27,29.54) C426.2 U76.5 ; R374.2 54.52,98.06 v1(54.52,97.41) 54.52,96.75 R376.2 ; U41.5 33.71,139.62 C182.2 33.28,140.52 32.93,140.88 v1(32.93,141.56) ; U73.24 55.22,28.4 55.68,27.94 C427.1 56.18,27.43 56.36,27.61 56.36,28.15 v1(56.2,28.32) U73.23 ; R263.2 55.55,141.22 v1(55.69,141.36) ; R654.1 v1(56.79,123.3) ; U58.B3 17.23,83.88 v1(17.45,83.66) 17.63,83.84 U58.C3 ; R257.2 v1(4.1,148.57) ; C460.2 v1(22.99,15.45) ; v1(66.18,80) 66.12,79.94 C379.2 FL18.2 ; v1(23.25,18.3) R534.2 ; v1(31.18,7.88) 31.51,7.55 R566.1 ; U80.5 C436.2 46.08,22.72 v1(45.85,22.95) ; C334.2 v1(19.46,86.52) ; R538.1 31.57,17.06 31.03,17.6 30.88,17.6 v1(30.55,17.93) ; R395.2 v1(82.33,81.46) ; R424.1 v1(6.82,54.6) ; C567.1 55.94,116.93 55.97,116.96 56.37,116.96 v1(56.4,116.99) 56.61,117.2 U127.30 ; R301.2 65.03,131.12 v1(64.78,131.38) ; R381.1 R380.2 ; v1(37.88,60.9) 37.88,60.44 38.31,60.02 40.11,60.02 40.27,60.19 R419.1 ; R562.1 v1(34.96,10.86) R560.1 ; R367.1 v1(56.79,100.75) ; R657.2 v1(57.93,104.13) ; R653.2 54.52,119.31 v1(54.52,119.96) 54.52,120.62 R640.2 ; R472.2 v1(55.23,37.2) ; R656.2 v1(78.17,107.44) ; v1(41.67,6.41) 41.77,6.52 C476.2 ; C419.1 v1(37.11,34.2) U75.24 ; R532.1 v1(35.88,16.66) ; v1(64.42,99.6) 64.42,99.65 64.44,99.67 64.44,100.07 C312.1 ; R561.2 31.14,10.92 30.89,11.17 30.06,11.17 v1(29.6,10.72) C473.2 29.32,9.89 U96.3 ; U70.27 v1(55.2,39.51) ; v1(56.84,20.17) C447.2 ; v1(4.09,147.8) R258.2
  BOTTOM w0.381: 53.17,79.49 C352.1 ; U47.5 C194.1 v1(74.53,130.62) ; C351.1 49.12,82.12 v1(49.13,82.11)
  vias: v1(12.76,51.46) v1(13.36,51.46) v1(16.11,123.73) v1(16.93,123.68) v1(27.11,91.73) v1(27.11,91.14) v1(37.68,139.63) v1(44.61,136.61) v1(44.61,135.96) v1(47.36,150.35) v1(47.61,57.95) v1(47.61,56.93) v1(47.61,55.91) v1(47.61,54.9) v1(48.63,150.35) v1(48.63,149.08) v1(48.63,57.95) v1(48.63,56.93) v1(48.63,55.91) v1(48.63,54.9) v1(49.64,57.95) v1(49.64,56.93) v1(49.64,55.91) v1(49.64,54.9) v1(50.66,57.95) v1(50.66,56.93) v1(50.66,55.91) v1(61.2,88.17) v1(61.78,88.68) v1(61.78,88.17) v1(75.05,152.77) v1(76.45,152.77) v1(76.45,151.38)
VCC_5V0: length 16.3
  TOP w0.254: v1(19.04,36.82) 19.11,36.76 R202.2 ; 19.28,33.45 R209.1
  BOTTOM w0.254: R291.1 v1(8.2,135.16) 8.06,135.03 C187.1 7.37,135.63 U45.A2 ; 19.8,38.72 19.85,38.77 C414.1 21.09,39.56 21.17,39.65 R465.1 ; v1(4.68,138.43) 4.68,138.36 4.47,138.15 R288.2 ; v1(1.64,116.34) 1.29,116.69 C217.1 U50.11
  vias: v1(16.99,37.57) v1(17.01,34.79) v1(18.02,37.84) v1(18.02,36.82) v1(18.02,35.81) v1(18.02,34.79) v1(19.04,37.84) v1(19.04,35.81) v1(19.04,34.79) v1(19.05,33.45) v1(20.55,32.54) v1(70.55,67.14) v1(70.55,66.53) v1(76.39,136.23)
VCC_5V0_FB: length 2.9
  TOP w0.254: R206.1 21.08,33.45 R209.2 21.94,33.45 22.33,33.06 U33.5
VCC_5V0_HDMICONN: length 1.5
  TOP w0.254: J5.18 7.23,119.74 v1(7.04,119.92)
VCC_5V0_PG: length 31.6
  TOP w0.254: U33.2 24.21,36.13 R202.1 v1(24.84,36.2)
  L04_PWR01 w0.254: v1(24.84,36.2) 30.43,36.2 31.98,34.65 31.98,22.4 32.56,21.82 32.56,19.76 32.44,19.63 32.44,15.87 v1(31.99,15.43)
  BOTTOM w0.127: 32.38,15.43 32.51,15.55 U89.3
  BOTTOM w0.254: v1(31.99,15.43) 32.38,15.43
VCC_CORE: length 6.6
  TOP w0.254: v1(14.94,82.91) 14.82,82.79 U22.1
  L06_SIG2 w0.254: v1(11.97,87.11) 15.24,83.84 15.24,83.21 v1(14.94,82.91)
VCC_CSI_IO: length 41.2
  TOP w0.254: C4.1 v1(78.23,151)
  L06_SIG2 w0.254: v1(63.36,149.56) 66.19,149.56 v1(71.09,144.66) 73.42,146.98 ; 73.42,146.98 73.81,146.59 76.24,146.59 78.23,148.59 v1(78.23,151) ; 73.42,146.98 v1(73.42,150.58)
  BOTTOM w0.254: v1(73.42,150.58) 73.32,150.48 R567.1 R575.2 ; v1(63.36,149.56) 63.51,149.72 65.67,149.72 65.93,149.46 C480.2 U98.2 ; R568.1 72.22,145.68 72.44,145.9 72.44,147.41 72.25,147.61 R573.2 ; R568.1 71.37,144.94 v1(71.09,144.66) ; R568.1 72.22,144.55 72.89,143.87 73.46,143.87 74.01,143.33 74.01,142.82 ; 74.01,142.82 74.54,143.35 U97.3 ; 74.01,142.82 C478.2
VDD1_LPDDR4_1V8: length 11.4
  TOP w0.254: U20.F12 41.28,85.99 41.28,85.98 C80.2 42.19,86 v1(42.99,86) ; v1(34.84,85.01) 34.52,85.34 U20.G4 ; U20.U12 41.15,78.53 41.87,78.53 41.92,78.58 C94.2 42.45,78.44 v1(42.91,78.44) ; U20.T9 v1(38.84,79.16) ; 31.45,85.99 U20.F1 ; v1(30.54,79.25) C95.2 30.94,78.64 31.02,78.72 31.9,78.72 32.02,78.84 U20.U1 ; U20.T4 v1(34.04,79.16) ; U20.G9 v1(38.04,85.01)
  BOTTOM w0.254: v1(34.04,79.16) 34.12,79.16 34.18,79.22 C353.2 ; v1(34.84,85.01) 34.67,85.01 34.46,85.21 ; C355.2 38.86,79.26 38.84,79.24 v1(38.84,79.16) ; v1(42.99,86) 43.07,85.92 C337.2
  vias: v1(29.78,84.13) v1(30.64,83.56) v1(31.18,83.66)
VDD_1V0: length 31.3
  TOP w0.254: C47.1 61.33,98.96 v1(60.89,99.4) 60.89,99.4 60.44,98.95 C46.1 C45.1 ; C572.1 55.57,118.55 55.77,118.35 C576.1 v1(56.4,117.91) C569.1 ; C586.1 C568.1 60.44,121.5 60.89,121.96 v1(60.96,121.96) 60.96,121.89 61.33,121.52 C565.1 ; TP35.1 56.3,90.91 v1(56.32,90.93) ; C57.1 v1(65.29,95.14) ; C52.1 55.57,95.99 55.77,95.79 C55.1 v1(56.4,95.35) C56.1 ; C574.1 v1(65.29,117.7)
  L05_PWR02 w0.254: v1(56.4,117.91) 56.72,117.91 57.71,116.92 57.71,115.49 57.08,114.86 v1(57.08,113.48)
  BOTTOM w0.254: U55.24 58.15,90.67 C324.1 C325.1 v1(57.08,90.93) ; C574.1 v1(65.29,117.7) U127.6 ; C326.1 v1(56.32,90.93) ; C57.1 v1(65.29,95.14) U55.6 ; v1(56.4,95.35) 56.59,95.16 57.38,95.16 U55.31 ; U127.31 57.38,117.72 56.59,117.72 v1(56.4,117.91) ; U127.24 58.15,113.23 C578.1 C564.1 v1(57.08,113.48) ; v1(60.89,99.4) 60.89,99.4 60.65,99.15 U55.42 ; U127.42 60.65,121.7 60.9,121.96 v1(60.96,121.96)
VDD_1V2: length 22.2
  TOP w0.254: v1(16.27,73.74) v1(15.63,73.74) 15.12,73.74 TP53.1 14.56,74.79 14.72,74.96 C102.1 14.71,75.35 14.32,75.75 U22.23
  L05_PWR02 w0.508: v1(9.44,123.87) 13.83,119.47 13.83,116.11 14.84,115.1 16.24,115.1 16.88,114.45 v1(16.88,114.44)
  BOTTOM w0.381: 15.72,113.59 15.72,113.36 ; FB2.2 11.97,123.2 11.31,123.87 v1(9.44,123.87)
  vias: v1(7.04,102.06) v1(7.04,101.42)
VDD_2V5: length 31.5
  TOP w0.254: v1(65.29,93.64) C63.1 65.13,94.35 C61.1 64.82,94.9 64.73,95 C50.1 v1(65.29,96.64) C51.1 ; v1(65.29,116.2) C573.1 65.13,116.91 C566.1 64.82,117.46 64.73,117.55 C587.1 v1(65.29,119.2) C584.1 ; v1(65.23,83.9) 65.41,84.08 TP40.1
  BOTTOM w0.254: R389.1 64.63,84.52 C340.1 65.44,84.11 v1(65.23,83.9) ; U127.9 v1(65.29,116.2) C573.1 ; U55.3 v1(65.29,96.64) C51.1 ; v1(58.03,83.61) 58.02,83.62 58.02,83.73 57.51,84.24 56.28,84.24 52.82,87.71 52.82,90.05 53.17,90.4 C321.1 54.46,90.4 ; C63.1 v1(65.29,93.64) U55.9 ; U127.3 v1(65.29,119.2) C584.1 ; R386.2 v1(65.17,86.34)
  vias: v1(58.09,84.32)
VDD_2V5_FB: length 3.6
  BOTTOM w0.254: C340.2 64.63,85.08 R389.2 R390.1 63.15,85.8 62.96,85.99 U57.3
VDD_CANUART: length 14.4
  TOP w0.254: C42.1 15.94,100.87 v1(15.52,101.3) ; U12.H8 v1(32.87,102.14)
  L06_SIG2 w0.254: v1(22.4,98.84) 22.66,99.09 22.66,99.67 21.99,100.34 18.77,100.34 17.81,101.3 v1(15.52,101.3)
  BOTTOM w0.254: C302.1 32.68,101.94 v1(32.87,102.14) ; 23.61,100.55 23.23,100.55 23.23,100.56 R587.2 ; 23.61,100.55 C311.1 ; 23.61,100.55 23.61,99.53 22.92,98.84 v1(22.4,98.84)
VDD_CANUART_EN: length 7
  L06_SIG2 w0.107: v1(19.2,98.81) 19.76,99.36 21.03,99.36 22.35,98.04 22.35,98.03 v1(22.36,98.03)
  BOTTOM w0.132: v1(19.2,98.81) 19.28,98.81 19.28,98.81 U125.A2 ; v1(22.36,98.03) 22.35,98.03 22.35,98.04 21.77,97.46 R586.2 21.57,97.52 21.57,98.49 R588.2
VDD_CORE: length 18.3
  TOP w0.254: U12.M12 v1(36.87,106.14) U12.N13 37.27,106.54 v1(36.87,106.94) U12.M14 ; U12.L11 v1(36.07,104.54) ; U12.P8 v1(38.47,102.14) ; U12.K14 v1(34.47,107.73) ; U12.J13 v1(33.67,106.93) ; U12.M8 v1(36.07,102.14) ; U12.M14 v1(36.87,107.74) ; U12.M14 v1(36.07,106.93) U12.L13 ; U12.N9 v1(37.67,102.94) ; U12.K10 v1(35.27,103.73) ; U12.P11 v1(38.47,104.54) ; U12.P12 v1(38.47,106.13) ; U12.J9 v1(34.47,103.73) ; U12.J11 v1(33.67,105.34) U12.H12 ; U12.N11 v1(37.67,104.54) ; U12.H14 v1(32.87,107.73)
  BOTTOM w0.254: C253.1 36.77,107.63 v1(36.87,107.74) ; v1(34.47,107.73) 34.55,107.81 C249.1 ; v1(36.07,102.14) 36.56,102.63 C297.1 ; v1(38.47,102.14) 38.47,102.09 C303.1 ; v1(33.67,106.93) 33.75,107.01 C256.1 ; v1(37.67,102.94) 37.76,103.03 C292.1 ; C282.1 v1(36.07,104.54) 36.05,104.55 C274.1 ; C254.1 32.76,107.63 v1(32.87,107.73) ; v1(33.67,105.34) 33.8,105.47 C268.1 ; v1(37.67,104.54) 37.68,104.54 C273.1 ; C258.1 36.05,106.92 v1(36.07,106.93) ; C285.1 v1(38.47,104.54) ; 38.67,105.93 v1(38.47,106.13) ; v1(34.47,103.73) 34.67,103.94 ; C271.1 37.13,105.88 v1(36.87,106.14) 36.97,106.23 C264.1
  vias: v1(15.22,89.32) v1(15.22,88.43) v1(15.22,87.54) v1(16.24,89.32) v1(16.24,88.43) v1(16.24,87.54) v1(17.26,89.32) v1(17.26,88.43) v1(17.26,87.54) v1(20.68,107.98) v1(21.45,107.98) v1(22.46,107.98)
VDD_LPDDR4: length 72.4
  TOP w0.254: v1(39.64,75.91) 39.57,75.91 U20.AA10 ; U20.N3 v1(33.24,81.11) ; U12.K9 33.99,102.46 v1(33.67,102.13) U12.J8 ; U20.N12 v1(41.24,81.11) ; U12.L8 v1(35.27,102.14) ; U12.K7 v1(34.47,101.34) ; U20.W8 v1(38.04,77.21) ; U20.A9 v1(38.84,88.91) U20.B10 ; v1(34.36,89.88) 34.44,89.79 U20.A4 ; U20.R1 v1(32.44,80.46) ; v1(36.56,89.15) 36.56,89.61 36.56,89.61 R100.1 ; v1(36.56,89.15) 35.81,89.15 U20.B5 ; v1(36.56,89.15) 37.06,89.15 37.32,88.89 37.34,88.89 U20.B8 ; U20.K10 v1(39.64,83.71) ; v1(32.46,82.71) 32.46,82.97 U20.K1 ; U20.U10 v1(39.64,78.51) ; U20.R8 37.97,79.81 v1(38.04,79.81) ; U20.AA8 v1(38.04,75.91) ; v1(42.88,80.25) 42.65,80.01 C93.2 41.46,80.01 41.34,80.14 U20.R12 ; U12.C1 28.66,96.33 28.66,93.2 29.85,92.01 31.26,92.01 31.26,92.01 R93.2 31.8,91.76 v1(32.18,91.38) ; U20.K12 40.95,83.39 v1(41.27,83.07) ; v1(30.55,84.2) C83.2 31.17,84.7 31.26,84.8 31.43,84.8 31.45,84.82 31.91,84.82 U20.H1 ; U20.D5 35.67,87.29 35.92,87.54 v1(35.92,87.55) ; v1(30.29,88.03) 30.34,88.03 30.45,87.92 C72.2 31.41,87.92 U20.D1 ; U20.AA5 v1(35.93,75.91) ; v1(30.06,77.22) 30.16,77.12 C99.2 31.62,77.12 U20.W1 ; U20.R5 v1(34.84,79.81) ; U20.F8 37.03,85.99 36.82,85.78 36.8,85.78 36.78,85.76 v1(36.32,85.76) 36.24,85.76 36.22,85.78 35.88,85.78 35.68,85.99 U20.F5 ; U20.D12 41.66,87.29 41.76,87.39 C74.1 43.16,87.39 v1(43.2,87.44) ; C98.1 42.86,76.52 v1(42.77,76.62) 42.32,77.07 C97.2 41.21,77.17 U20.W12 ; v1(30.06,81.26) 30.11,81.31 C92.2 31,81.31 31.13,81.44 U20.N1 ; U20.U8 v1(38.04,78.51) ; U20.H8 37.05,84.69 v1(36.85,84.48) ; U20.H12 41.42,84.69 v1(41.8,84.31) ; U12.L7 v1(35.27,101.34) ; v1(36.83,87.44) 37.49,87.44 U20.D8 ; U20.F3 v1(34.04,85.66) ; U20.K3 v1(33.24,83.71) ; U20.AB4 34.44,75.16 34.56,75.04 C104.2 v1(34.06,74.52) 33.76,74.23 C106.1 ; U20.H5 35.6,84.69 35.85,84.43 v1(35.85,83.99) ; U20.U3 v1(33.24,78.51) ; U20.W5 v1(34.84,77.21) ; U20.U5 v1(34.84,78.51) ; U20.AA3 v1(33.24,75.91) ; U20.F10 v1(38.84,86.31) ; v1(33.24,88.91) U20.B3 ; U20.N10 v1(39.64,81.11) ; v1(38.72,73.97) 38.59,74.11 C105.2 38.59,74.9 38.44,75.04 U20.AB9 ; U12.U1 v1(40.47,96.09)
  BOTTOM w0.203: C366.1 v1(35.93,75.91)
  BOTTOM w0.254: C309.1 35.43,101.17 v1(35.27,101.34) 35.04,101.34 C308.1 34.72,101.34 v1(34.47,101.34) ; C316.1 39.78,96.09 v1(40.47,96.09) ; C356.2 37.91,79.76 37.97,79.81 v1(38.04,79.81) ; v1(35.27,102.14) 35.3,102.11 C301.1 ; v1(39.64,83.71) 39.57,83.71 39.43,83.58 C347.2 ; v1(33.24,88.91) 33.21,88.95 C330.2 32.4,88.95 32.25,88.8 R384.2 ; v1(33.67,102.13) 34.11,102.57 C298.1 ; v1(34.84,79.81) 34.92,79.81 34.99,79.75 C357.2 ; C349.1 39.65,81.19 39.64,81.19 v1(39.64,81.11) ; v1(27.16,96.4) 27.27,96.51 C314.1 ; v1(43.2,87.44) 43.57,87.44 C331.2 ; C346.2 33.72,83.71 v1(33.24,83.71) ; v1(36.32,85.76) 36.41,85.76 36.49,85.85 C336.2 ; C360.1 37.91,78.45 37.97,78.51 v1(38.04,78.51) ; v1(34.06,74.52) 34.58,74.52 C367.2 ; C339.2 36.64,84.68 v1(36.85,84.48) ; v1(41.24,81.11) 41.46,81.33 C348.1
  vias: v1(29.19,76.36) v1(29.24,74.07) v1(29.34,75.15)
VDD_MMC1: length 6.4
  TOP w0.508: 7.41,102.86 C39.1 6.36,100.24 6.08,99.96 ; 7.41,102.86 7.93,102.34 U13.6 ; 7.41,102.86 7.84,103.29 U13.5
VDD_MMC1_SD: length 3.9
  TOP w0.254: C49.2 v1(5.78,97.46) ; C48.2 v1(3.42,97.46)
  BOTTOM w0.381: v1(3.42,97.46) J21.4 v1(5.78,97.46)
VDDA1V8: length 5.3
  TOP w0.254: v1(14.08,73.82) 13.59,73.82 TP52.1 13.08,74.79 13.17,74.88 C101.1 13.17,75.9 13.32,76.05 U22.21
  BOTTOM w0.254: C368.2 13.67,73.41 v1(14.08,73.82)
VDDA_1V8: length 0.9
  TOP w0.254: U12.R11 v1(39.27,104.54)
  BOTTOM w0.254: v1(39.27,104.54) 39.4,104.66 C277.1
  vias: v1(13.47,69.6) v1(14.87,69.6) v1(49.73,106.73) v1(50.57,106.53)
VDDA_1V8_FB1: length 5.3
  TOP w0.254: U12.M7 v1(36.07,101.34) ; U12.F16 v1(31.27,109.34) ; U12.K12 v1(34.47,106.13) ; U12.N10 v1(36.87,103.74) ; U12.H10 v1(33.67,104.53) ; U12.P14 v1(38.47,107.73)
  BOTTOM w0.254: C235.1 31.27,109.08 v1(31.27,109.34) ; v1(33.67,104.53) 33.74,104.6 C281.1 ; v1(36.07,101.34) 36.15,101.34 C307.1 ; v1(36.87,103.74) 36.87,104 C287.1 ; v1(38.47,107.73) 38.47,107.35 C255.1 ; v1(34.47,106.13) 34.5,106.17 C265.1
  vias: v1(47.28,113.78) v1(47.25,112.76)
VDDA_1V8_FB2: length 3.1
  TOP w0.254: v1(39.27,102.94) U12.R9 v1(38.47,102.94) U12.P9 ; U12.R12 v1(38.47,105.34)
  BOTTOM w0.254: v1(38.47,102.94) 38.66,102.75 C299.1 ; C296.1 39.35,102.94 v1(39.27,102.94) ; C275.1 38.47,105.2 v1(38.47,105.34)
  vias: v1(47.46,107.87)
VDDA_1V8_FB_OSC: length 2.6
  TOP w0.254: U12.J7 v1(33.67,101.34)
  BOTTOM w0.203: v1(47.32,108.84) 47.58,108.58 FL4.2 48.12,108.6 C25.1
  BOTTOM w0.254: C306.1 33.83,101.17 v1(33.67,101.34)
VDDA_DDR_PLL0: length 0.9
  TOP w0.254: U12.L9 v1(35.27,102.94)
  BOTTOM w0.254: C295.1 35.34,103.01 v1(35.27,102.94)
  vias: v1(17.99,93.18) v1(17.99,92.54)
VDDA_SYS_MON: length 34.2
  TOP w0.127: R115.1 27.56,86.8 v1(27.42,86.66) ; U12.F6 v1(32.07,100.53)
  TOP w0.132: C533.1 28.31,86.73 R115.1
  L06_SIG2 w0.107: v1(35.77,82.66) 35.43,83.01 35.43,90.12 32.45,93.09 32.45,100.15 v1(32.07,100.53)
  BOTTOM w0.127: v1(27.42,86.66) 27.23,86.85 R387.2
  BOTTOM w0.132: v1(27.42,86.66) 28.28,85.8 28.28,84.79 30.03,83.04 31.51,83.04 32.62,81.92 35.04,81.92 v1(35.77,82.66)
VDDC_1V2: length 5.6
  TOP w0.203: U36.87 59.57,22.75 v1(59.37,22.55)
  TOP w0.254: v1(50.84,14.82) 51.05,15.03 C162.1 C161.1 U36.115
  BOTTOM w0.254: v1(59.37,22.55) 59.55,22.73 C434.2
VDDIM: length 3.9
  TOP w0.102: 47.89,83.12 47.31,83.12 v1(47.07,83.36) 47.31,83.6 47.89,83.6 U21.C2 47.89,83.12
  BOTTOM w0.254: C344.1 v1(47.07,83.36) 46.86,83.57 C343.1
VDDR_CORE: length 5.9
  TOP w0.254: U12.H11 v1(32.87,104.54) ; C35.1 18.35,104.05 18.31,104 C37.1 ; U12.M10 v1(36.07,103.74) ; U12.M13 v1(36.07,106.14)
  BOTTOM w0.254: v1(32.87,104.54) 33.04,104.36 C288.1 ; v1(36.07,103.74) 36.09,103.74 C294.1 ; C270.1 36.24,105.96 v1(36.07,106.14) ; v1(7.23,72.39) 7.75,72.39 8.25,72.9 R406.1
  vias: v1(7.23,70.99) v1(17.18,104.66) v1(17.76,104.66)
VDDSHV_CANUART: length 224.1
  TOP w0.254: U27.8 73.23,59.94 C115.1 v1(73.21,59.47) ; U12.G7 v1(32.87,101.34) U12.H7 ; R80.1 21.04,98.23 v1(21.18,98.09) ; R149.1 v1(79.03,62.26) ; R117.2 15.99,83.1 15.69,82.8 v1(15.69,82.8)
  L03_SIG1 w0.254: v1(24.84,37.49) 24.84,41.55 23.9,42.49 23.9,47.52 23.34,48.08 21.97,48.08 21.26,48.79 21.26,52.17 20.65,52.79 20.65,57.54 19.47,58.72 17.66,58.72 17.66,58.73 13.62,58.73 10.9,61.45 10.9,65.96 14.25,69.32 14.25,72.62 14.94,73.3 14.94,82.14 15.59,82.8 v1(15.69,82.8)
  L04_PWR01 w0.254: 30.84,36.78 33.27,34.34 33.27,26.9 34.16,26.01 34.16,21.18 33.16,20.18 v1(33.16,20) ; 30.84,36.78 40.03,36.78 42.6,39.34 51.18,39.34 52.17,40.34 56.13,40.34 56.93,41.14 56.93,45.07 59.61,47.75 59.61,56.24 62.85,59.47 v1(73.21,59.47) ; 30.84,36.78 25.55,36.78 v1(24.84,37.49) 24.08,36.73 24.08,32.93 24.06,32.91 24.06,32.53 24.08,32.52 24.08,19.43 v1(24.52,18.98) ; 17.51,100.35 18.08,99.77 18.08,98.93 18.92,98.09 v1(21.18,98.09) ; v1(23.3,90.4) 23.3,90.08 24.21,89.18 24.21,86.97 25.12,86.06 27.13,86.06 27.27,86.2 28.03,86.2 28.4,85.83 28.4,82.12 27.99,81.71 27.99,79.65 26.64,78.31 23.7,78.31 22.86,77.47 18.92,77.47 18.76,77.63 15.92,77.63 15.22,78.32 15.22,82.34 v1(15.69,82.8)
  L05_PWR02 w0.254: v1(79.03,62.26) 76.01,62.26 v1(73.21,59.47)
  L06_SIG2 w0.254: v1(21.18,98.09) 21.18,97.54 23.04,95.68 23.04,90.67 v1(23.3,90.4)
  BOTTOM w0.254: R516.1 v1(33.16,20) ; v1(23.3,90.4) 22.9,90 C327.1 C328.1 21.25,90.18 FL14.2 ; v1(32.87,101.34) 33.05,101.15 C310.1 ; R528.1 24.85,18.69 24.59,18.95 24.54,18.95 24.54,18.98 v1(24.52,18.98)
VDDSHV_SDIO: length 19.2
  TOP w0.254: R89.2 R90.2 9.5,93.99 9.81,94.29 10.83,94.29 11.26,94.73 11.26,96.27 11.08,96.45 10.65,96.45 C54.2 ; R89.2 R88.2 ; R89.2 v1(8.2,93.38) ; R75.2 8.09,99 8.09,99 R74.2 8.89,99 8.89,99.01 R73.2 ; U22.7 11.82,82.55 11.58,82.79 10.63,82.79 C87.1 10.42,83.32 ; C54.2 9.86,96.42 9.82,96.47 U15.10 ; C54.2 v1(10.61,98) 10.78,98.17 FL9.1 ; v1(9.26,83.93) v1(9.26,84.54)
  TOP w0.305: FL9.1 10.29,98.8 10.09,99.01 R73.2
  TOP w0.381: 10.42,83.32 10.42,83.42 TP41.1 9.33,84.51 9.28,84.51 v1(9.26,84.54)
ADCIN1: length 3.8
  BOTTOM w0.127: R454.1 14.33,44.93 R452.2 14.94,44.64 15.06,44.52 15.78,44.52 15.97,44.71 16.34,44.71 16.5,44.56 U68.6
ADCIN2: length 3.5
  BOTTOM w0.127: R448.1 14.44,45.8 14.54,45.69 R449.2 14.94,45.95 15.11,46.12 17,46.12 U68.10
ADDR_IO_EXP: length 1.6
  BOTTOM w0.127: R470.2 55.83,39.24 55.7,39.36 U70.26
ADDR_IO_EXP1: length 1.2
  TOP w0.132: U3.26 R9.1
AUD_RSTN: length 17.5
  BOTTOM w0.127: U71.4 62.11,39.11 63.4,39.11 ; 65.49,41.21 65.49,44.47 69.36,48.33 69.36,48.33 69.65,48.62 69.65,48.63 70.31,49.29 U66.33
  BOTTOM w0.132: 65.49,41.21 63.39,39.1 R469.2
AUDIO_EXT_REFCLK1: length 1.1
  TOP w0.127: U12.C16 v1(28.87,109.33)
  BOTTOM w0.127: R348.2 28.86,109.33 v1(28.87,109.33)
AUDIO_MSTRCLK: length 1.4
  BOTTOM w0.127: R430.1 U66.37
BOOTMODE0: length 28.8
  L03_SIG1 w0.107: v1(34.35,28.99) 33.9,28.99 30.37,32.52 30.37,41.1 31.53,42.26 31.53,45.4 29.52,47.41 29.52,50.49 v1(29.95,50.91)
  BOTTOM w0.132: v1(29.95,50.91) 29.55,51.31 RA8.2 ; v1(34.35,28.99) 34.85,28.49 U75.14
BOOTMODE1: length 28.1
  L03_SIG1 w0.107: v1(29.15,50.91) 29.15,46.72 30.12,45.75 30.12,32.41 33.94,28.6 34.97,28.6 v1(35.37,28.99)
  BOTTOM w0.132: v1(29.15,50.91) 28.75,51.31 RA8.4 ; U75.15 v1(35.37,28.99)
BOOTMODE2: length 27.7
  L03_SIG1 w0.107: v1(29.95,51.73) 30.39,51.28 30.39,47.15 31.86,45.68 31.86,42.27 30.63,41.04 30.63,32.59 33.22,29.99 v1(34.35,29.99)
  BOTTOM w0.132: U75.16 34.85,29.49 v1(34.35,29.99) ; RA8.1 v1(29.95,51.73)
BOOTMODE3: length 30.4
  L03_SIG1 w0.107: v1(29.15,51.73) 28.69,51.27 28.69,46.68 29.89,45.47 29.89,32.32 33.84,28.37 35.31,28.37 35.77,28.83 35.77,29.6 v1(35.37,29.99)
  BOTTOM w0.132: RA8.3 v1(29.15,51.73) ; U75.17 v1(35.37,29.99)
BOOTMODE4: length 35.1
  L03_SIG1 w0.107: v1(40.09,55.54) 40.09,54.6 38.53,53.04 34.84,53.04 32.89,51.09 32.89,41.12 31.13,39.36 31.13,32.72 32.86,30.99 v1(34.35,30.99)
  BOTTOM w0.132: RA7.3 v1(40.09,55.54) ; v1(34.35,30.99) 34.85,30.49 U75.18
BOOTMODE5: length 36.5
  L03_SIG1 w0.107: v1(40.9,56.34) 40.5,55.94 40.5,54.66 38.63,52.79 34.95,52.79 33.15,50.99 33.15,41.02 31.39,39.26 31.39,32.89 32.78,31.5 34.86,31.5 v1(35.37,30.99)
  BOTTOM w0.132: RA7.2 40.5,55.94 v1(40.9,56.34) ; U75.19 v1(35.37,30.99)
BOOTMODE6: length 35
  L03_SIG1 w0.107: v1(40.9,55.54) 40.9,54.7 38.74,52.53 35.05,52.53 33.4,50.88 33.4,40.91 31.64,39.14 31.64,33.12 32.77,31.99 v1(34.35,31.99)
  BOTTOM w0.132: RA7.4 40.5,55.14 v1(40.9,55.54) ; v1(34.35,31.99) 34.85,31.49 U75.20
BOOTMODE7: length 38.2
  L03_SIG1 w0.107: v1(35.37,31.99) 35.77,31.59 35.77,30.67 35.65,30.54 33,30.54 30.88,32.66 30.88,39.47 32.64,41.23 32.64,51.2 34.74,53.3 38.42,53.3 39.69,54.56 39.69,55.94 v1(40.09,56.34)
  BOTTOM w0.132: U75.21 v1(35.37,31.99) ; RA7.1 v1(40.09,56.34)
BOOTMODE8: length 103.5
  L06_SIG2 w0.107: v1(48.36,91.8) 47.97,92.19 46.47,92.19 45.19,90.9 45.19,78.26 46.66,76.78 50.9,76.78 51.82,75.87 51.82,73.94 50.5,72.62 50.5,59.69 51.77,58.42 51.77,54.89 59.57,47.09 59.57,45.1 60.21,44.46 60.21,40.04 59.4,39.23 59.4,34.42 59.12,34.15 58.18,34.15 v1(57.83,34.49)
  BOTTOM w0.127: U73.14 57,33.65 v1(57.83,34.49)
  BOTTOM w0.132: RA6.1 40.04,114.18 41.27,112.95 41.27,109.97 41.51,109.73 41.83,109.73 42.07,109.49 42.07,109.17 42.31,108.93 42.63,108.93 42.87,108.7 42.87,107.79 43,107.65 43.52,107.65 45.12,106.06 45.12,104.46 47.96,101.63 48.51,101.63 49.76,100.38 49.76,94.27 48.76,93.27 48.76,92.21 v1(48.36,91.8)
BOOTMODE9: length 100.2
  L06_SIG2 w0.107: v1(59.01,34.58) 59.01,39.3 59.95,40.24 59.95,42.8 59.26,43.49 59.26,47.03 51.51,54.78 51.51,58.31 50.24,59.58 50.24,72.72 51.49,73.97 51.49,75.57 51.18,75.87 49.91,75.87 49.5,76.28 46.69,76.28 44.91,78.05 44.91,90.98 46.37,92.44 47.87,92.44 v1(48.35,92.92)
  BOTTOM w0.127: v1(59.01,34.58) 57.77,33.33 57.34,33.33 57.16,33.15 U73.15
  BOTTOM w0.132: RA6.2 39.65,113.78 40.47,112.97 40.47,110.07 40.47,110.06 40.47,109.97 40.71,109.73 41.03,109.73 41.27,109.49 41.27,109.17 41.51,108.93 41.83,108.93 42.07,108.69 42.07,108.09 42.81,107.35 43.42,107.35 44.25,106.52 44.25,104.93 48.01,101.18 48.01,101.16 48.03,101.13 48.03,93.24 v1(48.35,92.92)
BOOTMODE10: length 107.3
  L06_SIG2 w0.107: v1(47.58,90.71) 46.35,89.48 46.35,82.27 45.75,81.66 45.75,78.67 46.49,77.92 51.01,77.92 52.39,76.55 52.39,73.79 51.03,72.43 51.03,59.95 52.27,58.7 52.27,55.1 60.72,46.65 60.72,35.38 59,33.66 58.51,33.66 v1(57.69,32.85)
  BOTTOM w0.127: v1(57.69,32.85) 57.3,32.85 57.1,32.65 U73.16
  BOTTOM w0.132: RA5.1 39.97,116.08 43.11,112.93 43.43,112.93 44,112.36 44,110.76 44.47,110.29 44.47,109.93 46.48,107.92 46.48,104.86 48.09,103.25 48.87,103.25 51.36,100.76 51.36,93.66 49.88,92.18 49.88,90.32 49.64,90.08 48.24,90.08 47.61,90.71 v1(47.58,90.71)
BOOTMODE11: length 102.5
  L06_SIG2 w0.107: v1(58.99,32.88) 58.99,33.29 60.98,35.28 60.98,48.71 54.79,54.89 54.79,60.04 51.85,62.98 51.85,72.89 52.65,73.7 52.65,76.86 51.33,78.18 48.49,78.18 47.52,79.15 47.52,89.94 47.97,90.38 47.97,91.42 v1(47.59,91.79)
  BOTTOM w0.127: v1(58.99,32.88) 58.27,32.15 U73.17
  BOTTOM w0.132: RA5.4 39.8,114.88 41.58,113.1 41.58,112.39 42.07,111.9 42.07,109.92 42.26,109.73 42.73,109.73 42.87,109.59 42.87,109.17 43.11,108.94 43.43,108.94 43.67,108.7 43.67,107.84 45.35,106.15 45.35,104.66 47.96,102.06 48.48,102.06 50.04,100.49 50.04,93.99 49.04,92.99 49.04,91.52 48.91,91.39 48,91.39 v1(47.59,91.79)
BOOTMODE12: length 104.7
  L06_SIG2 w0.107: v1(57.69,31.63) 58.84,31.63 59.6,32.39 59.6,33.51 61.81,35.72 61.81,41.31 61.3,41.82 61.3,48.75 55.05,55 55.05,60.14 52.1,63.09 52.1,72.79 53.06,73.75 53.06,76.94 51.56,78.44 48.59,78.44 47.9,79.12 47.9,85.24 48.31,85.65 48.31,90.6 v1(48.42,90.71)
  BOTTOM w0.127: 57.09,31.65 U73.18
  BOTTOM w0.132: v1(57.69,31.63) 57.67,31.65 57.09,31.65 ; v1(48.42,90.71) 49.29,90.71 49.6,91.03 49.6,92.53 50.95,93.88 50.95,100.61 48.72,102.84 48.1,102.84 46.1,104.84 46.1,107.9 45.88,108.13 45.05,108.13 44,109.18 44,109.61 43.67,109.94 43.67,111.89 43.43,112.13 43.11,112.13 42.87,112.37 42.87,112.74 39.94,115.68 RA5.2
BOOTMODE13: length 108.4
  L06_SIG2 w0.107: v1(46.81,91.74) 46.1,91.04 46.1,82.37 45.49,81.76 45.49,78.56 46.39,77.67 50.8,77.67 52.13,76.34 52.13,73.9 50.77,72.54 50.77,59.84 52.02,58.6 52.02,55 59.82,47.19 59.82,45.25 60.47,44.6 60.47,39.92 59.97,39.42 59.97,38 v1(59.97,38)
  BOTTOM w0.127: 58.04,31.15 U73.19
  BOTTOM w0.132: v1(46.81,91.74) 47.44,91.11 49.05,91.11 49.32,91.38 49.32,92.74 50.48,93.9 50.48,100.57 48.59,102.46 47.96,102.46 45.64,104.78 45.64,106.22 43.9,107.97 43.9,108.92 43.67,109.16 43.67,109.5 43.43,109.74 43.11,109.74 42.87,109.97 42.87,111.91 42.64,112.14 42.31,112.14 41.95,112.5 41.95,113.24 39.91,115.28 RA5.3 ; v1(59.97,38) 60.77,37.21 60.77,33.37 58.76,31.37 58.26,31.37 58.04,31.15
BOOTMODE14: length 104.7
  L06_SIG2 w0.107: v1(59.49,30.12) 61.08,31.72 61.08,34.6 63.28,36.8 63.28,47.12 55.3,55.1 55.3,61.16 52.36,64.1 52.36,72.68 53.32,73.65 53.32,77.31 51.91,78.72 48.71,78.72 48.26,79.17 48.26,84.73 49.12,85.6 49.12,87.58 48.9,87.81 48.9,93.11 48.7,93.3 47.99,93.3 v1(47.58,92.9)
  BOTTOM w0.127: v1(59.49,30.12) 57.75,30.12 57.22,30.65 U73.20
  BOTTOM w0.132: v1(47.58,92.9) 47.75,93.06 47.75,101.02 44.02,104.75 44.02,105.96 43.45,106.53 42.31,106.53 42.07,106.78 42.07,107.48 41.27,108.28 41.27,108.7 41.03,108.93 40.67,108.93 40.47,109.12 40.47,109.56 40.3,109.73 39.87,109.73 39.67,109.92 39.67,112.97 39.26,113.38 RA6.3
BOOTMODE15: length 107.4
  L06_SIG2 w0.107: v1(46.8,92.9) 47.51,93.61 48.76,93.61 49.15,93.21 49.15,88.01 49.96,87.2 49.96,85.73 48.51,84.28 48.51,79.43 48.96,78.98 52.21,78.98 53.58,77.61 53.58,73.49 52.61,72.52 52.61,64.23 55.55,61.29 55.55,55.21 63.62,47.14 63.62,36.78 61.34,34.5 61.34,31.21 59.61,29.49 v1(58.77,29.49)
  BOTTOM w0.127: U73.21 56.96,30.15 57.62,29.49 v1(58.77,29.49)
  BOTTOM w0.132: v1(46.8,92.9) 46.8,93.46 47.4,94.06 47.4,100.97 43.78,104.58 43.78,105.31 43.49,105.6 42.1,105.6 41.27,106.42 41.27,107.1 41.28,107.11 41.28,107.88 41.03,108.13 39.82,108.13 39.67,108.28 39.67,109.55 39.48,109.74 39.11,109.74 38.87,109.97 38.87,112.73 38.79,112.81 RA6.4
BOOTMODE_I2C_SCL: length 34.4
  TOP w0.127: v1(55.74,17.69) 56.92,16.51 58.85,16.51 59.18,16.51 59.18,16.51 65.58,16.51 v1(65.97,16.12)
  BOTTOM w0.127: v1(65.97,16.12) 66,16.09 R555.2 R553.1 ; v1(55.74,17.69) 55.74,17.08 54.96,16.3 R544.1
  BOTTOM w0.132: R544.1 54.56,19.22 54.26,19.51 54.26,22.09 53.95,22.4 53.95,22.94 54.07,23.06 54.07,23.39 53.84,23.62 53.28,23.62 51.69,25.21 51.13,25.21 49.95,26.4 47.07,26.4 46.56,25.89 45.84,25.89 TP87.1 U74.29
BOOTMODE_I2C_SDA: length 50.7
  TOP w0.127: TP88.1 50.38,16.18 v1(50.38,15.89)
  TOP w0.132: v1(65.09,11.42) 65.09,11.81 65.08,11.81 65.08,14.23 66.51,15.66 66.51,16.96 v1(66.01,17.45)
  BOTTOM w0.127: R536.1 68.61,17.02 68.41,16.82 R537.2 68.06,17.23 67.84,17.45 v1(66.01,17.45) ; R546.1 51.42,16.26 50.75,16.26 v1(50.38,15.89)
  BOTTOM w0.132: v1(65.09,11.42) 54.07,11.42 51.81,13.68 51.15,13.68 50.38,14.45 v1(50.38,15.89) ; R546.1 51.46,16.64 53.15,18.33 53.15,22.2 52.98,22.36 52.98,22.36 52.64,22.71 52.64,23.87 51.57,24.93 51.02,24.93 49.85,26.1 47.29,26.1 46.78,25.59 44.91,25.59 44.63,25.88 U74.30
BOOTMODEON: length 47.6
  TOP w0.127: U34.4 71.45,26.36 71.27,26.18 R237.2 69.42,25.01 v1(69.21,24.79)
  TOP w0.132: v1(34.35,32.99) 34.82,33.47 39.77,33.47 40.65,34.35 46.75,34.35 50.51,30.59 51.25,30.59 51.78,30.06 53.97,30.06 54.83,29.2 57.02,29.2 v1(57.1,29.28)
  BOTTOM w0.127: U73.22 56.72,29.65 v1(57.1,29.28)
  BOTTOM w0.132: v1(57.1,29.28) 57.75,28.63 66.84,28.63 68.66,26.81 68.66,25.78 69.21,25.23 v1(69.21,24.79) ; U75.22 34.85,32.49 v1(34.35,32.99)
BT_EN_SOC: length 89.4
  TOP w0.127: U12.E7 v1(31.27,102.13)
  TOP w0.132: v1(4.25,142.73) 4.25,143.14 8.9,147.79 J2.54
  L06_SIG2 w0.107: v1(31.27,102.13) 31.27,102.39 30.89,102.78 30.89,103.06 30.61,103.34 30.33,103.34 30.08,103.58 30.08,103.86 29.83,104.12 29.17,104.12 28.45,103.41 28.45,102.78 28.23,102.55 27.11,102.55 26.5,103.16 25.89,103.16 25.43,103.62 24.99,103.62 24.1,102.73 24.1,101.35 24.8,100.64 24.8,99.88 24.32,99.4 23.93,99.4 23.72,99.6 23.72,100.3 22.16,101.86 18.42,101.86 17.68,102.6 16.83,102.6 16.65,102.42 13.53,102.42 12.54,103.41 10.02,103.41 2.93,110.5 2.93,120.28 1.36,121.85 1.36,131.2 2.42,132.26 2.42,141.33 3.82,142.73 v1(4.25,142.73)
  BOTTOM w0.132: R258.1 5.29,143.77 v1(4.25,142.73)
BT_UART_WAKE_SOC: length 170.1
  TOP w0.132: v1(44.54,142.71) 44.24,142.41 41.17,142.41 39.01,140.26 37.69,140.26 37.19,139.75 34.82,139.75 34.42,140.16 19.18,140.16 18.31,139.29 J2.20 8.43,139.29 v1(7.93,138.79)
  L06_SIG2 w0.107: v1(44.54,142.71) 46.47,144.64 59.69,144.64 65.61,138.72 65.61,127.61 67.22,126 67.22,114.92 65.96,113.67 65.96,107.49 66.16,107.29 66.16,106.01 66.11,105.97 66.11,91.39 67.48,90.02 67.48,88.67 68.85,87.31 68.85,58.24 63.26,52.65 62.76,52.65 v1(62.21,52.1)
  BOTTOM w0.132: U70.12 54.2,46.55 54.6,46.94 54.6,48.91 57.79,52.1 v1(62.21,52.1) ; v1(7.93,138.79) 7.54,138.79 7.29,139.04 R279.1
CAN_FD_WKUP_HDR_INH: length 38.8
  TOP w0.132: v1(18.08,96.75) 18.02,96.82 R82.1
  L06_SIG2 w0.107: v1(18.08,96.75) 18.49,96.34 19.02,96.34 19.85,95.52 19.85,89.29 21.46,87.68 21.46,80.87 18.93,78.34 18.93,72.35 18.04,71.46 18.04,63.56 J10.5
CAN_FD_WKUP_SW_INH: length 118.9
  TOP w0.132: U27.7 71.9,60.44 70.57,59.11 70.57,52.75 69.37,51.55 60.6,51.55 59.91,52.23 v1(55.69,52.23) ; v1(17.54,97.95) 17.56,97.95 17.64,98.03 R78.2
  L03_SIG1 w0.107: v1(55.69,52.23) 55.48,52.43 55.48,63.05 52.81,65.72 52.81,67.87 50.07,70.61 46.56,70.61 43.65,73.52 33,73.52 31.1,75.42 30.34,75.42 30.18,75.27 30.18,74.66 v1(30.52,74.33)
  L06_SIG2 w0.107: v1(30.52,74.33) 29.8,73.62 28.53,73.62 27.57,74.58 27.57,80.73 25.03,83.27 25.03,88.33 24.69,88.67 24.69,89.86 27.55,92.72 27.55,96.6 26.06,98.09 26.06,102.18 25.97,102.28 25.97,102.31 25.64,102.63 24.78,102.63 24.49,102.34 24.49,101.59 25.26,100.82 25.26,99.67 23.23,97.65 22.2,97.65 21.37,98.48 20.8,98.48 20.28,97.95 v1(17.54,97.95)
CAP_VDDS0: length 1.7
  TOP w0.254: U12.G12 v1(32.07,105.34)
  BOTTOM w0.254: C284.1 31.31,104.57 v1(32.07,105.34)
CAP_VDDS1: length 1.4
  TOP w0.254: U12.L15 v1(36.07,108.53)
  BOTTOM w0.254: v1(36.07,108.53) 35.66,108.95 C234.1
CAP_VDDS2: length 0.9
  TOP w0.254: U12.R13 v1(39.27,106.14)
  BOTTOM w0.254: C266.1 39.46,105.95 v1(39.27,106.14)
CAP_VDDS3: length 0.9
  TOP w0.254: U12.M15 v1(36.87,108.53)
  BOTTOM w0.254: C240.1 36.79,108.61 v1(36.87,108.53)
CAP_VDDS4: length 0.9
  TOP w0.254: U12.N8 v1(37.67,102.14)
  BOTTOM w0.254: C304.1 37.89,101.92 v1(37.67,102.14)
CAP_VDDS5: length 0.9
  TOP w0.254: U12.G15 v1(32.07,108.53)
  BOTTOM w0.254: v1(32.07,108.53) 31.91,108.37 C246.1
CAP_VDDS6: length 0.9
  TOP w0.254: U12.J15 v1(33.67,108.53)
  BOTTOM w0.254: v1(33.67,108.53) 33.75,108.62 C239.1
CAP_VDDS_CANUART: length 0.8
  TOP w0.254: U12.G8 v1(32.07,102.14)
  BOTTOM w0.254: v1(32.07,102.14) 31.85,102.14 C300.1
CAP_VDDS_MCU: length 0.9
  TOP w0.254: U12.G11 v1(32.87,105.33)
  BOTTOM w0.254: C278.1 v1(32.87,105.33)
CBOOT: length 3.3
  BOTTOM w0.203: 32.61,42.11 33.09,42.6 U67.13 ; 32.61,42.11 32.61,42.59 32.59,42.6 U67.14 ; 32.61,42.11 C405.1
CH1_LVDS_A0N: length 63.4
  TOP w0.105: U12.AA2 44.07,97.74 44.31,97.98 45.82,97.98 45.92,97.87 45.92,97.69 v1(45.75,97.52)
  L03_SIG1 w0.081: v1(61.19,73.3) 61.07,73.63 60.94,73.69 53.59,73.69 52.87,74.41 51.58,74.41 51.28,74.71 51.28,75.12 51.58,75.42 52.87,75.42 53.01,75.55 53.01,75.75 52.87,75.88 51.58,75.88 51.28,76.17 51.28,76.59 51.58,76.89 52.87,76.89 53.01,77.02 53.01,77.21 52.87,77.35 51.58,77.35 51.28,77.64 51.28,78.06 51.58,78.35 52.87,78.35 53.01,78.49 53.01,81.8 53.25,82.04 53.75,82.04 54.02,81.77 54.02,77.42 54.1,77.34 54.49,77.34 54.57,77.42 54.57,82.6 49.21,87.96 49.21,89.04 49.07,89.18 47.69,89.18 47.4,89.47 47.4,89.89 47.69,90.18 49.07,90.18 49.21,90.32 49.21,94.86 47.45,96.61 46.49,96.61 46.16,96.94 46.16,97.4 46.04,97.52 v1(45.75,97.52)
  BOTTOM w0.105: J22.11 62.04,73.85 61.49,73.3 v1(61.19,73.3)
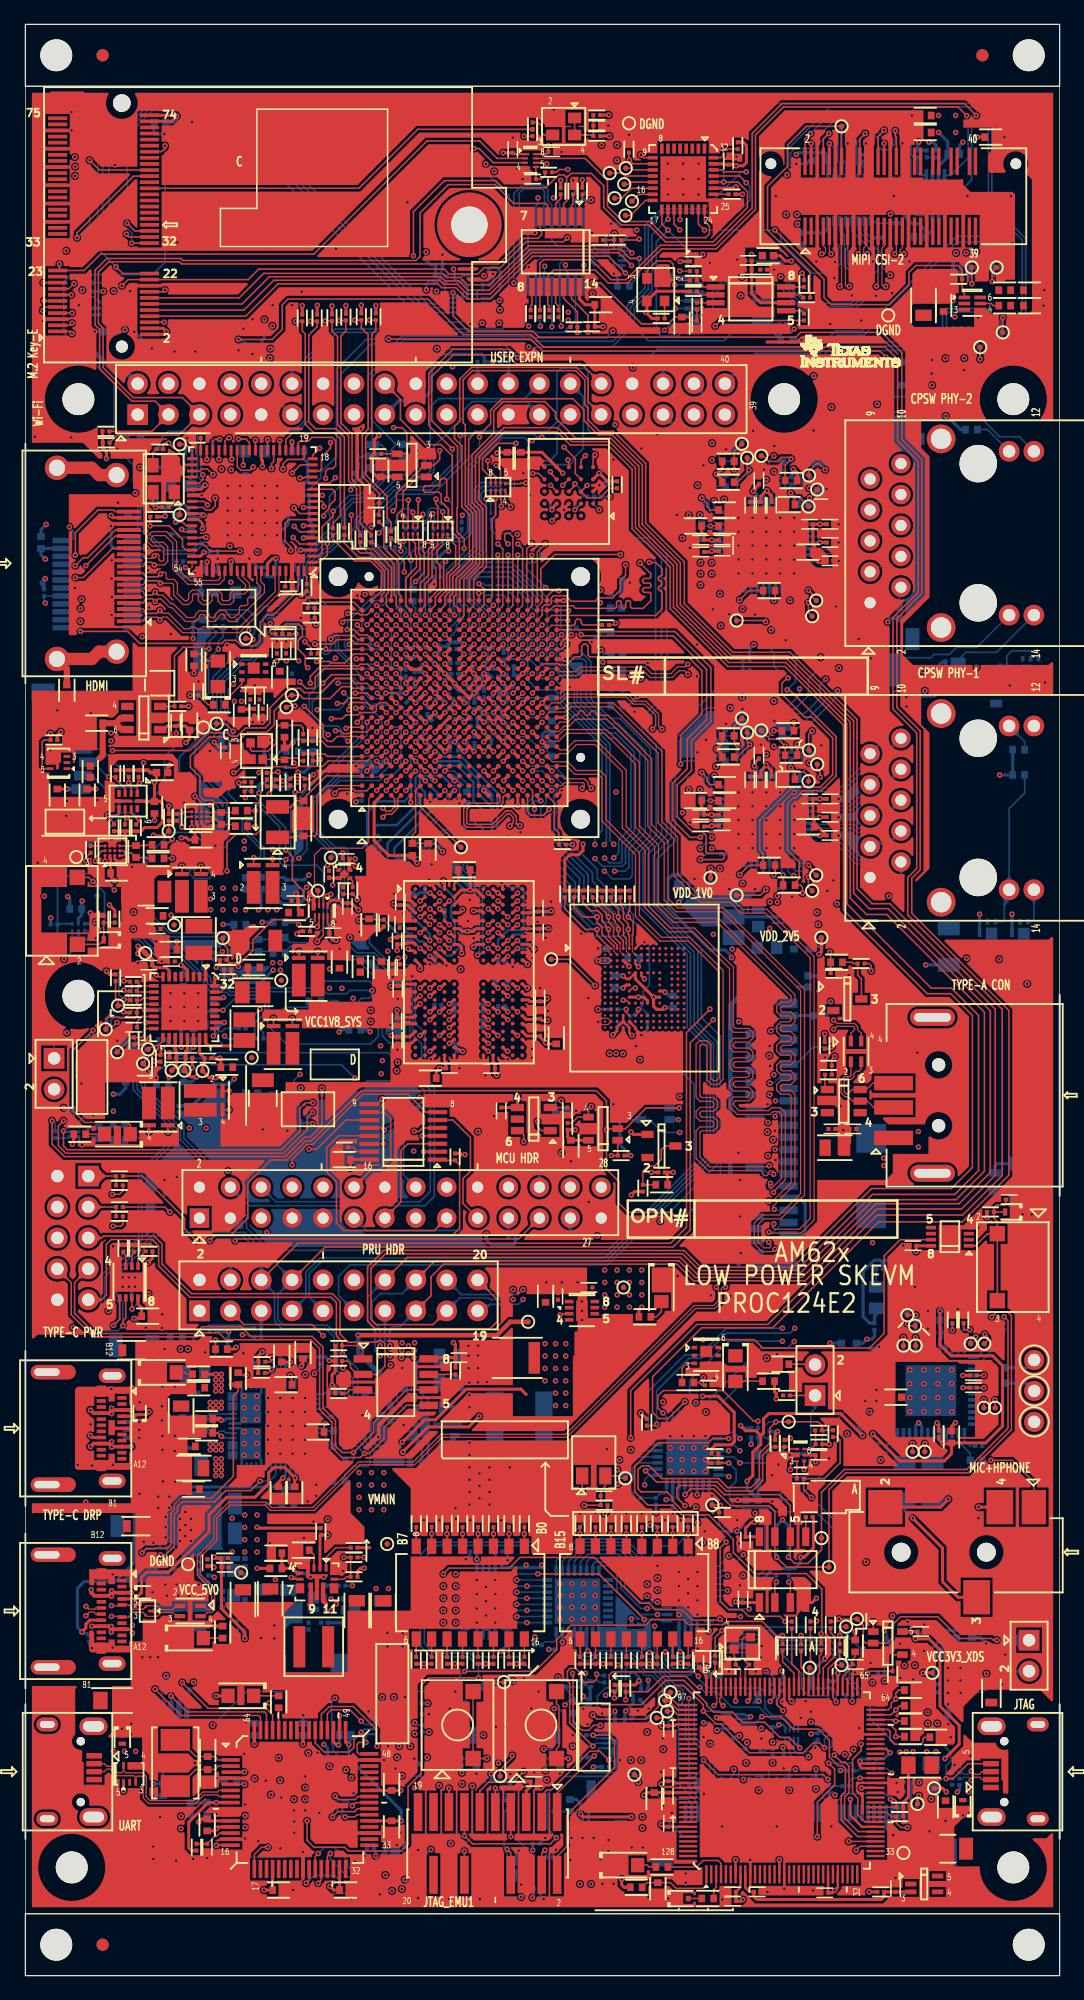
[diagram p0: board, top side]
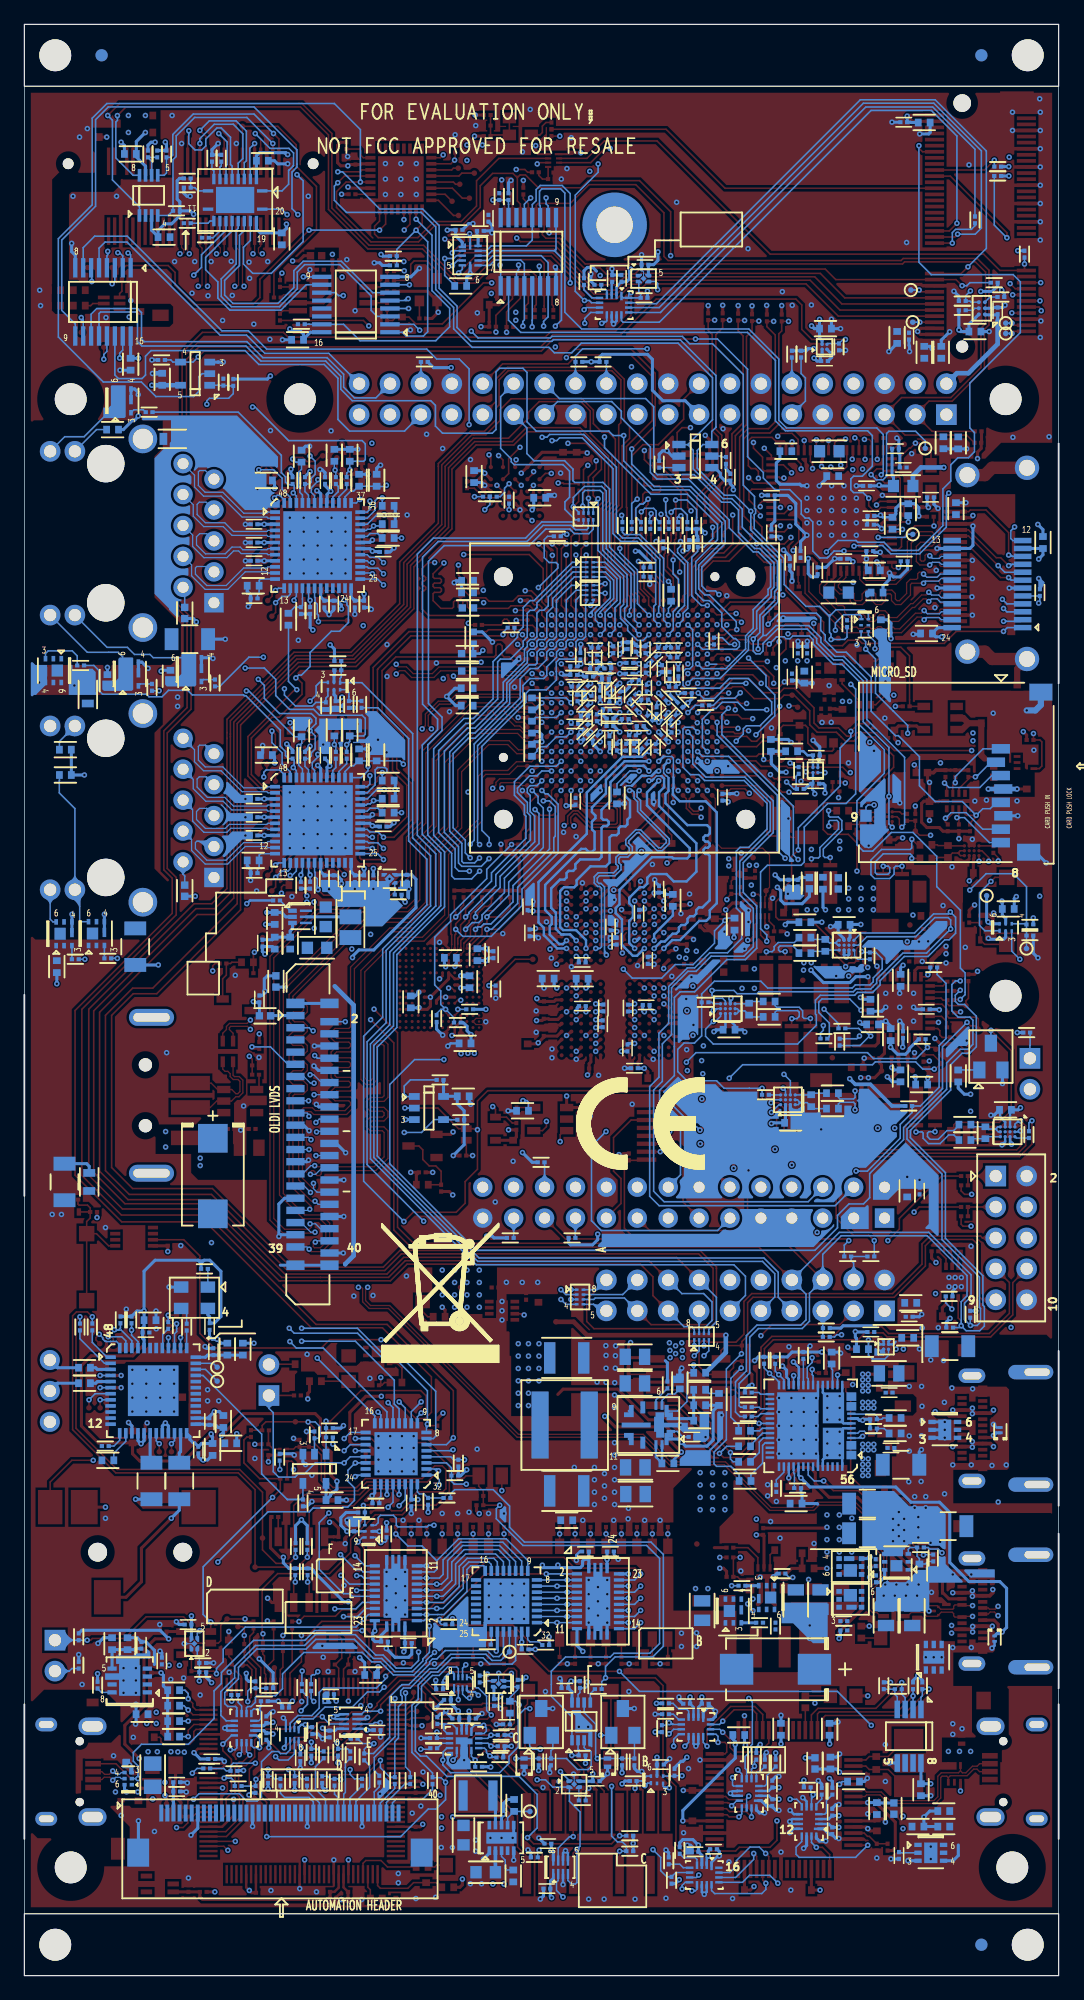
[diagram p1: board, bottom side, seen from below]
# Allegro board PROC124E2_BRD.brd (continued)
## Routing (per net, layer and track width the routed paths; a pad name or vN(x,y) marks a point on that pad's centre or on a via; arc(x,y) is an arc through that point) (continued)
CH1_LVDS_A0P: length 63.5
  TOP w0.105: v1(46.51,97.52) 46.24,97.79 46.24,98 45.95,98.29 44.31,98.29 44.07,98.53 U12.AA3
  L03_SIG1 w0.081: v1(46.51,97.52) 46.43,97.44 46.43,97.06 46.6,96.88 47.57,96.88 49.48,94.97 49.48,90.21 49.18,89.91 47.8,89.91 47.67,89.78 47.67,89.59 47.8,89.45 49.18,89.45 49.48,89.16 49.48,88.07 54.84,82.71 54.84,77.3 54.6,77.06 53.99,77.06 53.75,77.3 53.75,81.66 53.64,81.77 53.36,81.77 53.28,81.69 53.28,78.38 52.99,78.08 51.69,78.08 51.55,77.95 51.55,77.76 51.69,77.62 52.99,77.62 53.28,77.33 53.28,76.91 52.99,76.61 51.69,76.61 51.55,76.48 51.55,76.29 51.69,76.15 52.99,76.15 53.28,75.86 53.28,75.44 52.99,75.15 51.69,75.15 51.55,75.01 51.55,74.82 51.69,74.68 52.99,74.68 53.71,73.96 61,73.96 61.19,73.88 61.19,73.88 v1(61.52,73.99)
  BOTTOM w0.105: J22.12 60.57,73.35 61.21,73.99 v1(61.52,73.99)
CH1_LVDS_A1N: length 63.5
  TOP w0.102: U12.V5 41.27,100.13 v1(41.67,99.74)
  L03_SIG1 w0.081: v1(61.19,72.35) 61.19,72.3 61.27,72.22 61.55,72.22 61.68,72.36 61.68,72.58 61.82,72.72 62.01,72.72 62.14,72.58 62.14,72.36 62.28,72.22 62.52,72.22 62.64,72.34 62.64,73.67 62.36,73.95 62.36,74.67 62.64,74.95 62.64,75.59 61.39,76.84 60.45,76.84 60.32,76.7 60.32,74.74 60.02,74.45 59.61,74.45 59.31,74.74 59.31,76.7 59.18,76.84 58.98,76.84 58.85,76.7 58.85,74.74 58.55,74.45 58.14,74.45 57.84,74.74 57.84,76.7 57.71,76.84 57.52,76.84 57.38,76.7 57.38,74.74 57.09,74.45 56.67,74.45 56.37,74.74 56.37,76.7 56.24,76.84 55.7,76.84 55.35,77.18 55.35,82.85 50.07,88.14 50.07,96.82 48.29,98.6 44.42,98.6 44.15,98.88 44.15,100.81 43.99,100.97 43.38,100.97 43.27,100.86 43.27,99.48 42.78,98.99 42.16,98.99 41.67,99.48 v1(41.67,99.74)
  BOTTOM w0.105: J22.14 v1(61.19,72.35)
CH1_LVDS_A1P: length 63.5
  TOP w0.102: U12.V6 v1(41.67,100.54)
  L03_SIG1 w0.081: v1(41.67,100.54) 42.04,100.17 42.04,99.54 42.32,99.26 42.67,99.26 43,99.59 43,100.97 43.27,101.24 44.11,101.24 44.42,100.93 44.42,98.99 44.53,98.87 48.4,98.87 50.34,96.94 50.34,88.25 55.62,82.96 55.62,77.29 55.81,77.11 56.35,77.11 56.65,76.81 56.65,74.85 56.78,74.72 56.97,74.72 57.11,74.85 57.11,76.81 57.4,77.11 57.82,77.11 58.11,76.81 58.11,74.85 58.25,74.72 58.44,74.72 58.58,74.85 58.58,76.81 58.87,77.11 59.29,77.11 59.58,76.81 59.58,74.85 59.72,74.72 59.91,74.72 60.05,74.85 60.05,76.81 60.34,77.11 61.5,77.11 62.91,75.7 62.91,74.83 62.63,74.56 62.63,74.06 62.91,73.78 62.91,72.23 62.63,71.95 61.68,71.95 61.64,71.91 v1(61.64,71.85)
  BOTTOM w0.105: v1(61.64,71.85) 62.72,71.85 J22.15
CH1_LVDS_A2N: length 63.1
  TOP w0.102: v1(40.87,101.34) 40.47,101.73 U12.U7
  L03_SIG1 w0.081: v1(60.99,69.29) 61.11,69.29 61.24,69.17 61.24,68.98 60.88,68.62 55.41,68.62 55.09,68.94 55.09,70.49 55.27,70.67 61.05,70.67 61.42,71.04 61.97,71.04 62.03,71.1 63.25,71.1 63.87,71.72 63.87,71.95 63.87,76.01 51.07,88.81 51.07,97.67 46.79,101.95 42.08,101.95 41.2,101.07 41.13,101.07 v1(40.87,101.34)
  BOTTOM w0.105: J22.20 60.93,69.35 v1(60.99,69.29)
CH1_LVDS_A2P: length 63.1
  TOP w0.102: U12.U6 v1(40.87,100.54)
  L03_SIG1 w0.081: v1(40.87,100.54) 41.13,100.8 41.25,100.8 41.31,100.8 42.19,101.68 46.68,101.68 50.8,97.56 50.8,88.7 63.6,75.9 63.6,71.83 63.14,71.37 61.92,71.37 61.86,71.31 61.31,71.31 60.94,70.94 55.16,70.94 54.82,70.6 54.82,68.83 55.3,68.35 61.14,68.35 v1(61.44,68.66)
  BOTTOM w0.105: v1(61.44,68.66) 61.64,68.85 J22.21
CH1_LVDS_A3N: length 62.8
  TOP w0.102: U12.W6 42.07,100.94 v1(42.47,100.54)
  L06_SIG2 w0.081: v1(42.47,100.54) 42.75,100.25 43.1,100.25 44.46,101.62 48.07,101.62 50.16,99.52 50.16,90.91 55.47,85.61 55.47,76.89 55.6,76.75 56.7,76.75 57,76.46 57,76.04 56.7,75.75 55.6,75.75 55.47,75.61 55.47,75.42 55.6,75.29 56.7,75.29 57,74.99 57,74.58 56.7,74.28 55.6,74.28 55.47,74.15 55.47,73.95 55.6,73.82 56.7,73.82 57,73.52 57,73.11 56.7,72.81 55.6,72.81 55.47,72.68 55.47,72.49 55.6,72.35 56.7,72.35 57,72.06 57,71.64 56.7,71.34 55.6,71.34 55.47,71.21 55.47,71.02 55.6,70.88 56.7,70.88 57,70.59 57,70.17 56.7,69.88 55.6,69.88 55.47,69.74 55.47,69.38 56.47,68.38 60.99,68.38 61.49,67.88 61.49,67.88 61.51,67.85 v1(61.61,67.85)
  BOTTOM w0.105: J22.23 v1(61.61,67.85)
CH1_LVDS_A3P: length 62.9
  TOP w0.102: U12.W5 42.07,100.14 v1(42.47,99.74)
  L06_SIG2 w0.081: v1(61.03,67.35) 61.24,67.55 61.24,67.74 60.88,68.11 56.35,68.11 55.19,69.27 55.19,69.85 55.49,70.15 56.59,70.15 56.73,70.28 56.73,70.48 56.59,70.61 55.49,70.61 55.19,70.9 55.19,71.32 55.49,71.62 56.59,71.62 56.73,71.75 56.73,71.94 56.59,72.08 55.49,72.08 55.19,72.37 55.19,72.79 55.49,73.08 56.59,73.08 56.73,73.22 56.73,73.41 56.59,73.55 55.49,73.55 55.19,73.84 55.19,74.26 55.49,74.55 56.59,74.55 56.73,74.69 56.73,74.88 56.59,75.01 55.49,75.01 55.19,75.31 55.19,75.73 55.49,76.02 56.59,76.02 56.73,76.16 56.73,76.35 56.59,76.48 55.49,76.48 55.19,76.78 55.19,85.5 49.89,90.8 49.89,99.41 47.95,101.35 44.58,101.35 43.21,99.98 42.72,99.98 v1(42.47,99.74)
  BOTTOM w0.105: v1(61.03,67.35) 61.04,67.35 61.04,67.35 J22.24
CH1_LVDS_CLKN: length 63.1
  TOP w0.102: U12.V7 v1(40.87,102.13)
  L03_SIG1 w0.081: v1(61.61,70.57) 61.42,70.38 61.42,70.2 61.52,70.1 61.95,70.1 62.09,70.23 62.09,70.5 62.22,70.64 62.41,70.64 62.55,70.5 62.55,70.23 62.68,70.1 64.15,70.1 64.49,70.44 64.49,76.46 65,76.97 65,77.16 64.86,77.3 64.67,77.3 64.16,76.79 63.75,76.79 63.45,77.08 63.45,77.5 63.96,78.01 63.96,78.2 63.82,78.34 63.63,78.34 63.12,77.83 62.71,77.83 62.41,78.12 62.41,78.54 62.92,79.05 62.92,79.24 62.78,79.38 62.59,79.38 62.08,78.87 61.67,78.87 61.37,79.16 61.37,79.58 61.88,80.09 61.88,80.28 61.75,80.41 61.55,80.41 61.05,79.91 60.63,79.91 60.33,80.2 60.33,80.62 60.84,81.13 60.84,81.32 60.71,81.45 60.52,81.45 60.01,80.94 59.59,80.94 59.3,81.24 59.3,81.66 59.8,82.16 59.8,82.36 59.67,82.49 59.48,82.49 58.97,81.98 58.55,81.98 51.66,88.87 51.66,98.63 48.06,102.23 42.27,102.23 42.02,102.48 41.53,102.48 41.45,102.4 41.13,102.4 v1(40.87,102.13)
  BOTTOM w0.105: v1(61.61,70.57) 61.61,70.7 61.76,70.85 J22.17
CH1_LVDS_CLKP: length 63.2
  TOP w0.102: U12.V8 v1(40.87,102.93)
  L03_SIG1 w0.081: v1(40.87,102.93) 41.13,102.67 41.33,102.67 41.41,102.75 42.13,102.75 42.38,102.51 48.17,102.51 51.94,98.74 51.94,88.98 58.66,82.26 58.86,82.26 59.36,82.76 59.78,82.76 60.08,82.47 60.08,82.05 59.57,81.54 59.57,81.35 59.7,81.22 59.89,81.22 60.4,81.72 60.82,81.72 61.11,81.43 61.11,81.01 60.61,80.5 60.61,80.31 60.74,80.18 60.93,80.18 61.44,80.69 61.86,80.69 62.15,80.39 62.15,79.97 61.64,79.47 61.64,79.27 61.78,79.14 61.97,79.14 62.48,79.65 62.9,79.65 63.19,79.35 63.19,78.94 62.68,78.43 62.68,78.24 62.82,78.1 63.01,78.1 63.52,78.61 63.94,78.61 64.23,78.31 64.23,77.9 63.72,77.39 63.72,77.2 63.86,77.06 64.05,77.06 64.56,77.57 64.98,77.57 65.27,77.27 65.27,76.86 64.76,76.35 64.76,70.32 64.26,69.82 61.28,69.82 v1(61.04,70.07)
  BOTTOM w0.105: J22.18 60.76,70.35 v1(61.04,70.07)
CH2_LVDS_A0N: length 62.6
  TOP w0.105: U12.AA4 44.47,99.34 45.15,98.66 47.08,98.66 47.38,98.36 47.38,94.83 50.14,92.08 50.14,86.98 52.15,84.96 54.49,84.96 57.02,82.43 57.02,73.74 56.79,73.51 56.53,73.51 56.34,73.7 56.34,76.49 56.05,76.78 55.41,76.78 55.12,76.49 55.12,72.13 55.45,71.8 56.44,71.8 56.58,71.66 56.58,71.46 56.44,71.32 55.45,71.32 55.12,70.99 55.12,70.52 55.45,70.19 56.44,70.19 56.58,70.05 56.58,69.85 56.44,69.71 55.45,69.71 55.12,69.38 55.12,67.12 56.12,66.12 60.46,66.12 60.6,65.97 60.6,65.84 60.73,65.71 60.95,65.71 61.09,65.85 61.09,65.97 61.23,66.12 61.39,66.12 61.49,66.01 v1(61.49,65.81)
  BOTTOM w0.105: v1(61.49,65.81) 61.06,65.81 60.52,66.35 J22.26
CH2_LVDS_A0P: length 62.7
  TOP w0.105: v1(61.14,66.52) 61.05,66.43 56.25,66.43 55.43,67.25 55.43,69.25 55.58,69.39 56.57,69.39 56.9,69.72 56.9,70.18 56.57,70.51 55.58,70.51 55.43,70.65 55.43,70.86 55.58,71 56.57,71 56.9,71.33 56.9,71.79 56.57,72.12 55.58,72.12 55.43,72.26 55.43,76.36 55.54,76.47 55.92,76.47 56.02,76.36 56.02,73.57 56.4,73.19 56.93,73.19 57.34,73.6 57.34,82.56 54.62,85.28 52.29,85.28 50.46,87.11 50.46,92.21 47.7,94.96 47.7,98.49 47.21,98.98 45.28,98.98 44.56,99.69 43.31,99.69 U12.Y5
  BOTTOM w0.105: v1(61.14,66.52) 61.47,66.52 62.14,65.85 J22.27
CH2_LVDS_A1N: length 63.1
  TOP w0.105: U12.AA6 43.93,100.67 44.39,100.67 45.15,101.43 46.96,101.43 49.38,99.01 49.38,94.4 51.24,92.53 51.24,87.83 53.03,86.04 54.97,86.04 58.19,82.82 58.19,77.94 58.33,77.79 59.46,77.79 59.79,77.46 59.79,77 59.46,76.67 58.33,76.67 58.19,76.53 58.19,76.33 58.33,76.18 59.46,76.18 59.79,75.86 59.79,75.39 59.46,75.06 58.33,75.06 58.19,74.92 58.19,74.72 58.33,74.58 59.46,74.58 59.79,74.25 59.79,73.78 59.46,73.46 58.33,73.46 58.19,73.31 58.19,73.11 58.33,72.97 59.46,72.97 59.79,72.64 59.79,72.18 59.46,71.85 58.33,71.85 58.19,71.71 58.19,71.5 58.65,71.04 61.09,71.04 61.32,71.28 62.05,71.28 62.46,70.87 62.46,65.36 61.48,64.39 v1(61.48,64.32)
  BOTTOM w0.105: v1(61.48,64.32) 62.01,64.85 J22.29
CH2_LVDS_A1P: length 63.2
  TOP w0.105: U12.AA5 43.89,100.36 44.52,100.36 45.28,101.11 46.83,101.11 49.06,98.88 49.06,94.27 50.93,92.4 50.93,87.69 52.89,85.73 54.84,85.73 57.87,82.69 57.87,77.8 58.2,77.48 59.33,77.48 59.47,77.33 59.47,77.13 59.33,76.99 58.2,76.99 57.87,76.66 57.87,76.2 58.2,75.87 59.33,75.87 59.47,75.72 59.47,75.52 59.33,75.38 58.2,75.38 57.87,75.05 57.87,74.59 58.2,74.26 59.33,74.26 59.47,74.12 59.47,73.92 59.33,73.77 58.2,73.77 57.87,73.44 57.87,72.98 58.2,72.65 59.33,72.65 59.47,72.51 59.47,72.31 59.33,72.17 58.2,72.17 57.87,71.84 57.87,71.37 58.52,70.73 61.22,70.73 61.45,70.96 61.92,70.96 62.14,70.73 62.14,65.49 61.34,64.69 61.19,64.69 61.1,64.78 61.1,64.93 v1(61.24,65.07)
  BOTTOM w0.105: J22.30 60.95,64.35 61.24,64.64 v1(61.24,65.07)
CH2_LVDS_A2N: length 62.9
  TOP w0.105: v1(61.11,61.06) 61.19,60.99 63.75,60.99 64.82,62.06 64.82,83.71 60.95,87.58 58.92,87.58 58.02,88.48 55.59,88.48 53.6,90.47 53.6,93.51 52.32,94.79 52.32,100.53 48.33,104.53 44.7,104.53 44.26,104.1 43.71,104.1 U12.AA10
  BOTTOM w0.105: J22.35 62.26,61.85 61.47,61.06 v1(61.11,61.06)
CH2_LVDS_A2P: length 62.8
  TOP w0.105: v1(61.52,61.75) 61.4,61.63 61.4,61.48 61.58,61.3 63.61,61.3 64.5,62.19 64.5,83.58 60.82,87.26 58.79,87.26 57.89,88.16 55.46,88.16 53.28,90.34 53.28,93.38 52.01,94.66 52.01,100.4 48.2,104.21 44.83,104.21 44.39,103.78 43.07,103.78 42.87,103.58 U12.Y9
  BOTTOM w0.105: v1(61.52,61.75) 61.06,61.75 60.66,61.35 J22.36
CH2_LVDS_A3N: length 63
  TOP w0.105: v1(61.09,60.25) 61.15,60.25 61.26,60.14 61.26,59.88 61.15,59.78 60.69,59.78 60.22,60.24 60.22,61.68 60.7,62.16 62.08,62.16 64.03,64.11 64.03,81.03 57.36,87.69 53.6,87.69 52.82,88.48 52.82,93.18 51.47,94.53 51.47,99.94 47.9,103.51 47.06,103.51 46.92,103.66 46.92,103.74 46.77,103.89 46.57,103.89 46.43,103.74 46.43,103.66 46.29,103.51 46.08,103.51 45.94,103.66 45.94,103.74 45.8,103.89 45.6,103.89 45.46,103.74 45.46,103.66 45.31,103.51 45.13,103.51 44.57,102.95 43.92,102.95 43.67,102.7 U12.AA8
  BOTTOM w0.105: v1(61.09,60.25) 60.99,60.35 J22.38
CH2_LVDS_A3P: length 63
  TOP w0.105: v1(61.59,59.66) 61.39,59.46 60.55,59.46 59.91,60.11 59.91,61.81 60.57,62.47 61.95,62.47 63.71,64.24 63.71,80.9 57.23,87.38 53.47,87.38 52.5,88.35 52.5,93.05 51.16,94.4 51.16,99.8 47.76,103.2 45.27,103.2 44.7,102.63 44.28,102.63 43.82,102.18 43.23,102.18 U12.Y8
  BOTTOM w0.105: v1(61.59,59.66) 61.78,59.85 J22.39
CH2_LVDS_CLKN: length 63.3
  TOP w0.105: U12.Y7 43.23,101.38 43.82,101.38 44.47,102.03 47.61,102.03 50.14,99.5 50.14,94.3 51.71,92.73 51.71,88.02 53.22,86.51 56.85,86.51 62.93,80.44 62.93,80.08 62.78,79.94 62.08,79.94 61.75,79.61 61.75,79.15 62.08,78.82 62.78,78.82 62.93,78.68 62.93,78.48 62.78,78.33 62.08,78.33 61.75,78.01 61.75,77.54 62.08,77.21 62.78,77.21 62.93,77.07 62.93,76.87 62.78,76.73 62.08,76.73 61.75,76.4 61.75,75.93 62.08,75.6 62.78,75.6 62.93,75.46 62.93,75.26 62.78,75.12 62.08,75.12 61.75,74.79 61.75,74.33 62.08,74 62.78,74 62.93,73.85 62.93,73.65 62.78,73.51 62.08,73.51 61.75,73.18 61.75,72.72 62.08,72.39 62.78,72.39 62.93,72.25 62.93,65.13 61.4,63.6 v1(61.11,63.6)
  BOTTOM w0.105: v1(61.11,63.6) 60.86,63.35 J22.32
CH2_LVDS_CLKP: length 63.3
  TOP w0.105: U12.AA7 44.28,102.35 47.74,102.35 50.46,99.63 50.46,94.43 52.03,92.86 52.03,88.15 53.35,86.83 56.98,86.83 63.24,80.57 63.24,79.95 62.92,79.62 62.21,79.62 62.06,79.48 62.06,79.28 62.21,79.14 62.92,79.14 63.24,78.81 63.24,78.35 62.92,78.02 62.21,78.02 62.06,77.87 62.06,77.67 62.21,77.53 62.92,77.53 63.24,77.2 63.24,76.74 62.92,76.41 62.21,76.41 62.06,76.27 62.06,76.06 62.21,75.92 62.92,75.92 63.24,75.59 63.24,75.13 62.92,74.8 62.21,74.8 62.06,74.66 62.06,74.46 62.21,74.31 62.92,74.31 63.24,73.99 63.24,73.52 62.92,73.19 62.21,73.19 62.06,73.05 62.06,72.85 62.21,72.71 62.92,72.71 63.24,72.38 63.24,65 61.44,63.2 61.44,63.04 v1(61.54,62.94)
  BOTTOM w0.105: v1(61.54,62.94) 61.64,62.85 J22.33
CLKOUT0: length 2.5
  TOP w0.132: U6.1 55.73,138.69 55.19,139.23 R14.2 R12.2
CLKOUT_OSC: length 5.7
  TOP w0.132: U5.3 51.08,140.01 51.9,140.83 52.97,140.83 53.25,140.55 53.25,139.68 53.7,139.23 R14.1
COM_SDIO_CMD: length 49.7
  TOP w0.132: v1(1.43,136.74) 1.43,136.86 1.61,137.04 J2.11 ; v1(23.42,135.86) R285.1 23.98,135.43 23.29,134.75 23.29,127.61 23.85,127.05 25.53,127.05 26.21,126.37 R275.1
  L03_SIG1 w0.107: v1(23.42,135.86) 22.63,135.08 18.82,135.08 18.09,135.8 13.11,135.8 12.41,136.5 5.66,136.5 5.24,136.08 5.24,135.33 4.99,135.08 4.67,135.08 4.46,135.29 4.46,136.5 4.01,136.96 2.63,136.96 2.29,136.62 2.29,135.96 1.71,135.38 1.24,135.38 0.97,135.65 0.97,136.27 v1(1.43,136.74)
COM_SDIO_D0: length 48.2
  TOP w0.132: v1(22.2,135.86) R287.1 22.76,135.08 23,134.84 23,127.42 23.72,126.7 25.4,126.7 25.88,126.21 25.88,119.89 25.27,119.28 R277.1 ; v1(1.53,137.55) 1.54,137.54 J2.13
  L03_SIG1 w0.107: v1(22.2,135.86) 22.2,136.35 21.97,136.58 21.47,136.58 21.26,136.79 21.26,137.59 21.03,137.82 17.51,137.82 17.32,137.63 17.32,137.02 17.16,136.86 16.84,136.86 16.68,137.02 16.68,137.63 16.49,137.82 16.16,137.82 15.31,136.96 5.55,136.96 4.8,137.72 4.19,137.72 4.02,137.55 3.29,137.55 2.94,137.91 2.94,138.31 2.77,138.48 1.17,138.48 0.91,138.22 0.91,137.71 1.07,137.55 v1(1.53,137.55)
COM_SDIO_D1: length 51
  TOP w0.132: R276.1 27.51,118.59 27.23,118.87 27.23,122.1 26.57,122.76 26.57,126.47 25.65,127.38 25.65,134.62 25.2,135.08 R286.1 v1(24.64,135.89) ; J2.15 v1(3.78,138.04)
  L03_SIG1 w0.107: v1(24.64,135.89) 24.03,135.89 23.88,135.74 23.88,135.24 24,135.13 25.15,135.13 25.37,135.36 25.37,136.27 24.59,137.06 24.59,137.54 24.38,137.75 22.46,137.75 21.66,138.55 15.98,138.55 14.95,137.51 14.46,137.51 14.27,137.7 14.27,138.41 14.13,138.55 13.78,138.55 13.63,138.41 13.63,137.7 13.45,137.51 13.18,137.51 12.99,137.7 12.99,138.41 12.84,138.56 12.5,138.56 12.35,138.41 12.35,137.7 12.17,137.51 5.63,137.51 5.1,138.04 v1(3.78,138.04)
COM_SDIO_D2: length 46.7
  TOP w0.132: R274.1 30.05,119.38 29.72,119.71 29.72,121.51 27.97,123.27 27.97,126.37 28.47,126.87 28.47,134.8 28.8,135.13 R284.1 v1(28.27,135.97) ; v1(3.99,138.96) 3.57,138.54 J2.17
  L03_SIG1 w0.107: v1(28.27,135.97) 28.09,135.97 24.42,139.63 4.66,139.63 v1(3.99,138.96)
COM_SDIO_D3: length 49.6
  TOP w0.132: v1(25.81,135.94) R283.1 26.34,135.08 25.93,134.67 25.93,127.53 26.85,126.62 26.85,122.87 27.51,122.21 27.51,119.28 28.42,118.36 R273.1 ; J2.19 v1(1.47,139.04)
  L03_SIG1 w0.107: v1(25.81,135.94) 25.81,137.19 23.69,139.31 11,139.31 10.7,139.01 10.7,138.41 10.48,138.19 9.84,138.19 9.64,138.39 9.64,138.96 9.3,139.31 4.97,139.31 4.17,138.51 3.58,138.51 2.52,139.56 1.99,139.56 v1(1.47,139.04)
CONN_MCU_PORZ: length 40.5
  L03_SIG1 w0.107: J10.28 51.75,64.76 54.37,62.14 54.37,57.41 51.77,54.82 51.77,46.06 52.44,45.39 52.44,40.6 53.05,39.99 53.05,39.15 54.29,37.91 55.81,37.91 56.24,37.48 56.24,36.11 v1(55.7,35.57)
  BOTTOM w0.127: R472.1 55.23,35.7 55.33,35.6 55.52,35.6 55.55,35.57 v1(55.7,35.57) 56.11,35.99 U72.1
CONN_MCU_RESETZ: length 25.6
  TOP w0.127: Q4.1 v1(45.76,39.83)
  L03_SIG1 w0.107: v1(45.76,39.83) 44.97,40.62 44.97,59.36 44.79,59.55 J10.25
  BOTTOM w0.132: J10.25 R418.1
CPSW1_GPIO_0: length 3
  BOTTOM w0.127: Q7.6 82.65,86.54 82.88,86.78 J7.14
CPSW1_LED_ACT: length 13.4
  BOTTOM w0.127: Q6.6 80.36,86.56 80.45,86.65 80.45,88.79 J7.13
  BOTTOM w0.132: J7.13 80.85,95.86 82.13,97.14 82.13,98.11 82.12,98.12 R373.1
CPSW2_GPIO_0: length 7.8
  BOTTOM w0.127: 78.08,108.69 79.82,108.69 J27.14
  BOTTOM w0.132: Q20.6 76.92,108.32 77.29,108.69 78.08,108.69
CPSW2_LED_1000: length 6.9
  BOTTOM w0.127: 76.85,130.08 77.11,130.08
  BOTTOM w0.132: Q19.1 78.11,128.36 80.09,126.39 81.68,126.39 J27.12
CPSW2_LED_ACT: length 10.6
  BOTTOM w0.127: J27.13 78.2,109.09 76.53,109.09 75.95,108.51 74.68,108.51 74.41,108.24 Q21.6
CPSW_ETH1_D0N: length 10
  BOTTOM w0.105: U55.2 64.98,97.14 65.07,97.23 67.1,97.23 68.82,98.95 70.27,98.95 71.02,99.7 71.02,100.68 J7.10
CPSW_ETH1_D0P: length 10
  BOTTOM w0.105: U55.1 64.98,97.64 65.07,97.55 66.97,97.55 68.69,99.27 70.14,99.27 70.7,99.83 70.7,100.95 70.59,101.06 70.12,101.06 J7.9
CPSW_ETH1_D1M: length 9.4
  BOTTOM w0.105: J7.8 71.12,98.24 71.12,97.48 70.09,96.45 68.66,96.45 67.94,95.73 65.07,95.73 64.98,95.64 U55.5
CPSW_ETH1_D1P: length 9.5
  BOTTOM w0.105: U55.4 64.98,96.14 65.07,96.05 67.81,96.05 68.53,96.77 69.96,96.77 70.8,97.61 70.8,98.28 70.62,98.46 70.06,98.46 J7.7
CPSW_ETH1_D2M: length 9.4
  BOTTOM w0.105: J7.6 71.17,95.75 71.17,94.82 70.25,93.9 68.36,93.9 68.02,94.23 65.07,94.23 64.98,94.14 U55.8
CPSW_ETH1_D2P: length 9.4
  BOTTOM w0.105: U55.7 64.98,94.64 65.07,94.55 68.15,94.55 68.49,94.22 70.11,94.22 70.85,94.95 70.85,95.61 70.59,95.87 70.01,95.87 J7.5
CPSW_ETH1_D3M: length 9.8
  BOTTOM w0.105: U55.11 64.98,92.64 65.07,92.73 66.85,92.73 68.28,91.3 70.14,91.3 71.26,92.41 71.26,93.3 J7.4
CPSW_ETH1_D3P: length 9.8
  BOTTOM w0.105: U55.10 64.98,93.14 65.07,93.05 66.98,93.05 68.42,91.61 70.01,91.61 70.94,92.55 70.94,93.06 70.82,93.18 69.86,93.18 J7.3
CPSW_ETH1_GPIO_0: length 52.1
  TOP w0.132: v1(58.51,101.11) 58.26,101.36 R64.1 58.26,102.62 TP23.1
  L06_SIG2 w0.107: v1(80.02,83.48) 78.49,83.48 77.78,84.18 73.64,84.18 68.28,89.54 68.28,90.86 67.88,91.27 67.88,106.42 66.9,107.39 v1(66.85,107.39)
  BOTTOM w0.127: R372.1 v1(58.51,101.11)
  BOTTOM w0.132: v1(80.02,83.48) 80.14,83.48 80.14,83.48 R394.1 ; v1(66.85,107.39) 65.28,107.39 64.34,106.45 64.34,105.13 63.21,104 61.22,104 60.74,103.51 57.24,103.51 56.98,103.25 56.98,101.95 57.11,101.82 R64.1 58.26,101.36 v1(58.51,101.11)
CPSW_ETH1_GPIO_1: length 4.1
  TOP w0.132: TP26.1 59.32,101.31 v1(59.53,101.11) 58.51,100.09 R69.1
  BOTTOM w0.127: R362.2 v1(59.53,101.11) 59.4,100.98 R371.1
CPSW_ETH1_LED0: length 6.2
  TOP w0.132: v1(64.65,102.22) 64.37,101.94 64.37,100.68 TP27.1
  BOTTOM w0.132: U55.47 63.15,98.86 63.81,99.53 63.81,100.42 64.65,101.26 v1(64.65,102.22)
CPSW_ETH1_LED_1000: length 27.2
  TOP w0.132: 63.25,98.85 R77.2 ; 63.25,98.85 64.01,98.85 64.36,98.49 TP28.1 ; 63.25,98.85 63.25,98.87 v1(62.9,99.22)
  BOTTOM w0.132: R352.1 79.28,107.6 78.87,107.19 78.87,105.54 78.57,105.24 74.97,105.24 74.75,105.03 73.69,105.03 73.15,105.56 71.58,105.56 71.2,105.18 66.98,105.18 66.92,105.12 66.79,105.12 63.97,102.3 63.97,100.97 63.54,100.54 63.54,100.2 63.29,99.95 R369.1 62.82,99.82 62.82,99.3 v1(62.9,99.22) 62.65,98.97 U55.46
CPSW_ETH1_LED_ACT: length 41.9
  TOP w0.127: TP24.1 61.2,101.55 61.86,101.55 v1(62.45,100.96) R68.1
  L06_SIG2 w0.107: v1(77.35,83.55) 73.72,83.55 68.01,89.26 68.01,90.76 67.45,91.32 67.45,104.82 v1(66.75,105.51)
  BOTTOM w0.127: R364.2 62.2,101.73 62.2,101.21 v1(62.45,100.96) 62.45,99.4 62.15,99.1 U55.45
  BOTTOM w0.132: R364.2 62.78,101.75 66.55,105.51 v1(66.75,105.51) ; R393.1 v1(77.35,83.55)
CPSW_ETH2_D0N: length 10
  BOTTOM w0.105: U127.2 64.98,119.7 65.07,119.79 67.1,119.79 68.82,121.51 70.27,121.51 71.02,122.26 71.02,123.24 J27.10
CPSW_ETH2_D0P: length 10
  BOTTOM w0.105: U127.1 64.98,120.2 65.07,120.11 66.97,120.11 68.69,121.83 70.14,121.83 70.7,122.39 70.7,123.51 70.59,123.61 70.12,123.61 J27.9
CPSW_ETH2_D1M: length 9.5
  BOTTOM w0.105: U127.5 64.98,118.2 65.07,118.29 67.94,118.29 68.66,119.01 70.26,119.01 71.12,119.87 71.12,120.8 J27.8
CPSW_ETH2_D1P: length 9.6
  BOTTOM w0.105: U127.4 64.98,118.7 65.07,118.61 67.81,118.61 68.53,119.33 70.13,119.33 70.8,120 70.8,120.84 70.62,121.02 70.06,121.02 J27.7
CPSW_ETH2_D2M: length 9.6
  BOTTOM w0.105: J27.6 71.17,118.31 71.17,117.38 70.25,116.46 68.36,116.46 67.81,117.01 67.39,117.01 67.18,116.79 65.07,116.79 64.98,116.7 U127.8
CPSW_ETH2_D2P: length 9.6
  BOTTOM w0.105: J27.5 70.01,118.42 70.59,118.42 70.85,118.17 70.85,117.51 70.11,116.77 68.49,116.77 67.94,117.32 67.26,117.32 67.04,117.11 65.07,117.11 64.98,117.2 U127.7
CPSW_ETH2_D3M: length 9.8
  BOTTOM w0.105: J27.4 71.26,115.86 71.26,114.97 70.14,113.85 68.28,113.85 66.85,115.29 65.07,115.29 64.98,115.2 U127.11
CPSW_ETH2_D3P: length 9.8
  BOTTOM w0.105: J27.3 69.86,115.73 70.82,115.73 70.94,115.62 70.94,115.1 70.01,114.17 68.42,114.17 66.98,115.61 65.07,115.61 64.98,115.7 U127.10
CPSW_ETH2_GPIO_0: length 45.5
  TOP w0.132: TP121.1 58.26,125.18 R645.1 58.26,123.74 58.24,123.72 v1(58.24,123.67)
  L06_SIG2 w0.107: v1(66.24,128.83) 67.84,127.23 67.84,112.27 67.74,112.17 67.74,109.45 69.11,108.08 69.11,108.02 69.34,107.8 69.39,107.8 71.67,105.53 v1(73.93,105.53)
  BOTTOM w0.127: v1(58.24,123.67) 58.51,123.41 R627.1
  BOTTOM w0.132: v1(58.24,123.67) 58.24,123.72 58.26,123.74 R645.1 57.11,124.37 56.98,124.51 56.98,125.81 57.24,126.07 63.28,126.07 66.04,128.83 v1(66.24,128.83) ; R641.1 v1(73.93,105.53)
CPSW_ETH2_GPIO_1: length 4.1
  TOP w0.132: R642.1 58.51,122.65 59.46,123.6 v1(59.46,123.65) 59.46,123.73 59.32,123.87 TP122.1
  BOTTOM w0.127: R649.2 59.53,123.71 v1(59.46,123.65) 59.46,123.6 59.4,123.54 R628.1
CPSW_ETH2_LED0: length 6.7
  TOP w0.132: v1(65.74,123.67) 65.23,124.18 65.02,124.18 64.37,123.53 64.37,123.23 TP123.1
  BOTTOM w0.132: U127.47 63.15,121.41 63.81,122.08 63.81,122.98 64.51,123.67 v1(65.74,123.67)
CPSW_ETH2_LED_1000: length 19.4
  TOP w0.132: 63.25,121.4 R633.2 ; 63.25,121.4 63.66,121.4 64.36,120.7 TP119.1 ; 63.25,121.4 63.25,121.43 v1(62.9,121.78)
  BOTTOM w0.132: U127.46 62.65,121.52 v1(62.9,121.78) 62.82,121.85 62.82,122.38 R648.1 63.01,122.45 63.32,122.45 63.54,122.67 63.54,123.1 63.88,123.44 63.88,124.87 67.42,128.41 R629.1
CPSW_ETH2_LED_ACT: length 32.2
  TOP w0.132: TP120.1 60.62,124.82 61.09,124.36 61.8,124.36 62.13,124.69 62.81,124.69 v1(62.94,124.56) 62.45,124.07 R650.1
  L06_SIG2 w0.107: v1(62.94,124.56) 64.92,122.58 64.92,119.35 64.64,119.08 64.64,117.63 65.94,116.33 65.94,114 65.71,113.77 65.71,108.63 v1(65.35,108.28)
  BOTTOM w0.132: R651.1 68.94,105.88 66.55,108.28 v1(65.35,108.28) ; U127.45 62.15,121.61 62.36,121.82 62.36,122.17 62.45,122.27 62.45,123.48 62.23,123.7 62.23,124.29 R638.2 62.68,124.3 v1(62.94,124.56)
CPSW_RGMII1_ETH1_CLK: length 64.4
  TOP w0.132: v1(63.83,139.83) 63.99,139.67 R15.2
  L06_SIG2 w0.107: v1(63.15,90.36) 62.57,90.94 62.57,97.64 62.42,97.79 62.42,99.42 64.27,101.28 64.27,103.57 62.61,105.23 62.45,105.23 62.23,105.45 62.23,105.62 60.06,107.78 58.84,107.78 53.26,113.36 53.26,118.74 53.98,119.46 53.98,122.71 54.76,123.49 54.76,124.46 55.58,125.27 56.57,125.27 56.85,125.55 56.85,126.48 56.3,127.03 56.3,131.71 58.3,133.71 60.17,133.71 63.83,137.37 v1(63.83,139.83)
  BOTTOM w0.127: v1(63.15,90.36) 63.12,90.4 62.97,90.4 62.65,90.72 U55.15
CPSW_RGMII1_ETH1_CLK_OUT: length 4.9
  TOP w0.132: v1(60.86,89.19) 60.4,88.74 TP38.1
  BOTTOM w0.127: U55.18 61.15,90.66 61.1,90.61 61.1,90.26 60.93,90.08 60.93,89.26 v1(60.86,89.19)
CPSW_RGMII1_ETH1_RBIAS: length 2.9
  BOTTOM w0.132: U55.12 65.58,92.14 65.69,92.03 65.69,91.61 R378.1 65.7,91.01 65.84,90.88 C320.2
CPSW_RGMII1_ETH2_RBIAS: length 2.9
  BOTTOM w0.132: C562.2 65.84,113.44 65.7,113.57 R636.1 65.69,114.16 65.69,114.59 65.58,114.7 U127.12
CPSW_RGMII1_MDC: length 2.4
  TOP w0.127: R102.2 v1(62.28,90.4)
  BOTTOM w0.127: R380.1 v1(62.28,90.4) 62.15,90.53 U55.16
CPSW_RGMII1_MDIO: length 2.5
  TOP w0.132: R98.2 61.61,90.49 v1(61.52,90.4)
  BOTTOM w0.127: U55.17 61.65,90.53 v1(61.52,90.4) R381.2
CPSW_RGMII1_RD0: length 32.2
  TOP w0.127: R83.2 v1(56.3,96.51) ; v1(42.47,108.53) U12.W15
  L06_SIG2 w0.107: v1(42.47,108.53) 42.47,107.97 42.8,107.65 45.03,107.65 45.69,108.31 47.9,108.31 48.04,108.16 48.04,107.86 48.19,107.72 48.39,107.72 48.53,107.86 48.53,108.16 48.68,108.31 48.88,108.31 49.02,108.16 49.02,107.86 49.16,107.72 49.37,107.72 49.51,107.86 49.51,108.16 49.65,108.31 50.01,108.31 51,107.32 51.2,107.32 51.36,107.47 51.56,107.47 51.7,107.33 51.7,107.12 51.55,106.97 51.55,106.77 51.69,106.63 51.89,106.63 52.05,106.78 52.25,106.78 52.39,106.64 52.39,106.43 52.24,106.28 52.24,106.08 52.38,105.94 52.58,105.94 52.74,106.09 52.94,106.09 53.08,105.95 53.08,105.75 52.93,105.59 52.93,105.39 53.07,105.25 53.27,105.25 53.43,105.4 53.63,105.4 53.77,105.26 53.77,105.06 53.62,104.9 53.62,104.7 54.31,104.01 54.31,98.42 54.13,98.25 54.13,96.56 54.46,96.24 56.16,96.24 56.3,96.38 v1(56.3,96.51)
  BOTTOM w0.127: R376.1 55.74,96.51 v1(56.3,96.51) 56.57,96.24 56.8,96.24 56.89,96.14 U55.33
CPSW_RGMII1_RD1: length 30.3
  TOP w0.127: U12.Y16 v1(43.27,109.33)
  L06_SIG2 w0.107: v1(55.43,97.41) 55.45,97.38 56.01,97.38 56.21,97.59 56.21,98.22 56.03,98.4 55.35,98.4 55.17,98.58 55.17,99.8 56.54,101.17 56.54,104.17 56.07,104.64 55.87,104.64 55.84,104.61 55.64,104.61 55.5,104.75 55.5,104.95 55.52,104.98 55.52,105.18 55.38,105.33 55.18,105.33 55.15,105.3 54.95,105.3 54.81,105.44 54.81,105.64 54.83,105.67 54.83,105.87 54.69,106.02 54.49,106.02 54.46,105.99 54.26,105.99 54.12,106.13 54.12,106.33 54.14,106.36 54.14,106.56 54,106.71 53.8,106.71 53.77,106.68 53.57,106.68 53.43,106.82 53.43,107.02 53.45,107.05 53.45,107.25 53.31,107.4 53.11,107.4 53.08,107.37 52.88,107.37 52.74,107.51 52.74,107.71 52.76,107.74 52.76,107.94 52.62,108.09 52.42,108.09 52.39,108.06 52.19,108.06 52.05,108.2 52.05,108.4 52.07,108.43 52.07,108.63 51.93,108.77 51.73,108.77 51.7,108.75 51.5,108.75 51.36,108.89 51.36,109.09 51.38,109.12 51.38,109.32 51.24,109.46 51.04,109.46 51.01,109.44 50.81,109.44 50.67,109.58 50.67,109.78 50.69,109.81 50.69,110.01 50.57,110.13 46.38,110.13 46,109.75 43.69,109.75 v1(43.27,109.33)
  BOTTOM w0.127: v1(55.43,97.41) 56.05,97.41 56.81,96.64 U55.34
CPSW_RGMII1_RD2: length 33.5
  TOP w0.127: R81.2 56.3,97.81 ; U12.AA17 v1(44.07,110.13)
  TOP w0.132: v1(55.59,98.81) 56.02,98.38 56.02,98.09 56.3,97.81
  L06_SIG2 w0.107: v1(55.59,98.81) 55.59,99.75 55.94,100.1 56.79,100.1 57.2,100.51 57.2,105.27 55.15,107.32 54.28,107.32 50.91,110.69 50.53,110.69 50.39,110.83 50.39,111.13 50.25,111.28 50.04,111.28 49.9,111.13 49.9,110.83 49.76,110.69 49.56,110.69 49.41,110.83 49.41,111.13 49.27,111.28 49.07,111.28 48.93,111.13 48.93,110.83 48.78,110.69 47.9,110.69 47.57,111.02 46.88,111.02 46.74,110.88 46.74,110.66 46.59,110.52 46.39,110.52 46.25,110.66 46.25,110.88 46.11,111.02 44.96,111.02 v1(44.07,110.13)
  BOTTOM w0.127: U55.35 56.82,97.14 56.17,97.79 56.17,97.94
  BOTTOM w0.132: R374.1 v1(55.59,98.81) 55.58,98.8 55.3,98.8 55.2,98.89 55.2,99.09 55.33,99.22 55.97,99.22 56.17,99.02 56.17,97.94
CPSW_RGMII1_RD3: length 30.7
  TOP w0.127: v1(43.27,108.53) U12.Y15
  L06_SIG2 w0.107: v1(56.6,98.56) 56.6,97.09 56.41,96.9 55.29,96.9 54.9,97.29 54.9,97.95 54.69,98.16 54.69,100.48 55.35,101.14 55.2,101.29 55.08,101.29 54.94,101.43 54.94,101.63 55.08,101.77 55.2,101.77 55.35,101.92 55.35,102.12 55.2,102.26 55.08,102.26 54.94,102.4 54.94,102.61 55.08,102.75 55.2,102.75 55.35,102.89 55.35,103.09 55.2,103.24 55.08,103.24 54.94,103.38 54.94,103.58 55.08,103.72 55.2,103.72 55.35,103.87 55.35,104.34 50.32,109.37 49.49,109.37 49.35,109.23 49.35,108.91 49.21,108.76 49,108.76 48.86,108.91 48.86,109.23 48.72,109.37 48.52,109.37 48.37,109.23 48.37,108.91 48.23,108.76 48.03,108.76 47.89,108.91 47.89,109.23 47.74,109.37 47.04,109.37 46.41,108.75 44.18,108.75 43.97,108.53 v1(43.27,108.53)
  BOTTOM w0.127: U55.36 56.82,97.64 56.6,97.87 v1(56.6,98.56)
CPSW_RGMII1_RESETN: length 69.1
  TOP w0.127: v1(64,41.56) U31.4
  L03_SIG1 w0.107: v1(64,41.56) 64,42.67 67.63,46.3 67.63,73.86 68.96,75.19 68.96,80.29 65.89,83.36 65.05,83.36 62.45,85.97 62.45,88.2 62.26,88.4 62.26,88.75 61.82,89.19 61.43,89.19 60.16,90.46 60.16,99.06 60.39,99.29 60.39,99.81 v1(60.88,100.31)
  BOTTOM w0.127: U55.43 61.15,98.99 61.34,99.18 61.34,99.62 60.88,100.07 v1(60.88,100.31) ; v1(64,41.56) 64.02,41.58 R460.1
CPSW_RGMII1_RX_CTL: length 30.4
  TOP w0.127: 42.47,107.73 U12.W14
  TOP w0.132: 42.47,107.73 43.82,107.73 43.91,107.64 44.47,107.64 45.14,108.31 45.58,108.31 45.73,108.46 45.73,109.2 45.88,109.35 46.09,109.35 46.24,109.2 46.24,108.46 46.39,108.31 54.47,108.31 55.6,107.17 55.6,103.58 53.85,101.83 v1(53.85,99.49)
  BOTTOM w0.127: U55.38 58.65,98.89 58.17,99.37 57.93,99.37 57.53,99.77 R367.2 R368.2 55.36,99.77 55.36,99.77 54.13,99.77 v1(53.85,99.49)
CPSW_RGMII1_RXC: length 28.6
  TOP w0.132: v1(44.46,109.33) 44.06,108.94 U12.AA16
  L06_SIG2 w0.107: v1(54,95.51) 53.48,96.04 53.48,97.68 53.11,98.04 53.11,100.01 53.55,100.44 53.55,103.45 50.88,106.12 47.57,106.12 47.18,106.52 42.31,106.52 42.07,106.75 42.07,107.12 41.29,107.91 41.29,108.69 41.52,108.92 43.66,108.92 44.07,109.33 v1(44.46,109.33)
  BOTTOM w0.127: R377.1 v1(54,95.51)
CPSW_RGMII1_TD0: length 37.5
  TOP w0.127: U12.U14 v1(40.87,107.73)
  L06_SIG2 w0.107: v1(40.87,107.73) 41.29,107.32 41.29,105.93 41.47,105.75 43.77,105.75 44.23,106.21 46.92,106.21 47.34,105.79 50.67,105.79 53.22,103.25 53.22,100.58 52.79,100.14 52.79,94.25 54.96,92.08 58.01,92.08 58.16,92.22 58.16,93.59 58.02,93.73 57.64,93.73 57.49,93.58 57.49,92.69 57.39,92.58 57.09,92.58 56.96,92.72 56.96,93.36 56.82,93.49 v1(56.4,93.49)
  BOTTOM w0.127: v1(56.4,93.49) 56.68,93.49 56.83,93.64 U55.28
CPSW_RGMII1_TD1: length 37.5
  TOP w0.127: v1(44.58,111.3) 44.55,111.34 U12.AA19
  L06_SIG2 w0.107: v1(44.58,111.3) 44.91,111.63 50.53,111.63 53.93,108.23 54.7,108.23 57.53,105.4 57.53,103.76 58.01,103.28 58.01,98.34 57.68,98.01 57.68,95.94 56.57,94.82 55.78,94.82 55.25,95.34 54.6,95.34 54.25,95 53.4,95 53.17,94.78 53.17,94.32 54.92,92.58 v1(55.48,92.58)
  BOTTOM w0.127: U55.27 56.82,93.14 56.71,93.04 55.94,93.04 v1(55.48,92.58)
CPSW_RGMII1_TD2: length 37.9
  TOP w0.127: U12.Y17 v1(43.27,110.13)
  L06_SIG2 w0.107: v1(43.27,110.13) 43.99,110.86 43.99,112.15 44.38,112.53 46.65,112.53 46.96,112.22 51.18,112.22 58.47,104.93 58.47,102.51 58.89,102.09 58.89,100.79 58.38,100.28 58.38,98.96 58.74,98.61 59.46,98.61 59.68,98.39 59.68,98.05 59.48,97.85 58.52,97.85 58.14,97.47 58.14,95.5 56.69,94.05 56.23,94.05 56.01,93.84 56.01,92.96 v1(56.4,92.58)
  BOTTOM w0.127: U55.26 56.46,92.64 v1(56.4,92.58)
CPSW_RGMII1_TD3: length 37.7
  TOP w0.127: 44.29,110.53 U12.AA18
  TOP w0.132: v1(55.48,91.66) 57.3,91.66 57.44,91.8 57.44,92.02 57.29,92.18 56.08,92.18 55.94,92.32 55.94,93.64 55.66,93.92 54.82,93.92 53.57,95.17 53.57,97.79 54.74,98.97 54.74,101.4 56.33,102.99 56.33,107.44 53.38,110.39 47.02,110.39 46.87,110.53 44.29,110.53
  BOTTOM w0.127: v1(55.48,91.66) 55.96,92.14 U55.25
CPSW_RGMII1_TX_CTL: length 37.6
  TOP w0.127: U12.V15 v1(41.67,108.53)
  L06_SIG2 w0.107: v1(56.76,99.32) 56.76,99.61 56.93,99.79 57.4,99.79 57.63,99.56 57.63,98.69 56.97,98.03 56.97,96.48 56.4,95.91 54.2,95.91 53.81,96.31 53.81,97.82 53.44,98.18 53.44,99.87 53.87,100.3 53.87,103.89 50.39,107.37 49.04,107.37 48.92,107.24 48.92,106.97 48.79,106.85 48.61,106.85 48.49,106.97 48.49,107.24 48.36,107.37 48.19,107.37 48.06,107.24 48.06,106.97 47.94,106.85 47.76,106.85 47.64,106.97 47.64,107.24 47.51,107.37 47.33,107.37 47.21,107.24 47.21,106.97 47.08,106.85 46.91,106.85 46.78,106.97 46.78,107.24 46.66,107.37 46.48,107.37 46.36,107.24 46.36,106.97 46.23,106.85 46.05,106.85 45.93,106.97 45.93,107.24 45.8,107.37 45.63,107.37 45.5,107.24 45.5,106.97 45.38,106.85 45.2,106.85 45.08,106.97 45.08,107.24 44.95,107.37 44.77,107.37 44.65,107.24 44.65,106.97 44.52,106.85 44.35,106.85 44.22,106.97 44.22,107.24 44.1,107.37 42.29,107.37 41.67,107.99 v1(41.67,108.53)
  BOTTOM w0.127: U55.37 57.31,98.39 56.99,98.71 56.99,98.72 56.76,98.95 v1(56.76,99.32)
CPSW_RGMII1_TXC: length 30.8
  TOP w0.132: v1(45.67,110.13) 45.77,110.03 53.24,110.03 55.95,107.32 55.95,107.29 55.98,107.26 55.98,103.14 54.39,101.55 54.39,99.12 53.22,97.94 53.22,94.91 54.63,93.49 v1(55.48,93.49)
  BOTTOM w0.127: U55.29 56.82,94.14 56.6,93.93 55.92,93.93 v1(55.48,93.49) ; v1(45.67,110.13) 45.67,110.31 R346.2
CPSW_RGMII2_ETH2_CLK: length 39.8
  TOP w0.132: v1(56.69,135.49) 57.14,135.94 R26.2
  L03_SIG1 w0.107: v1(56.44,124.49) 56.02,124.9 56.02,134.82 v1(56.69,135.49)
  L06_SIG2 w0.107: v1(56.44,124.49) 56.44,123.49 56.41,123.46 56.41,123.15 56.44,123.12 56.44,122.43 55.96,121.95 55.96,121.54 55.97,121.53 55.97,121.21 55.96,121.19 55.96,119.26 55.92,119.22 55.92,119.04 55.45,118.57 55.45,116.64 55.02,116.21 55.02,113.82 55.68,113.16 56.86,113.16 56.92,113.1 57.24,113.1 57.29,113.16 57.91,113.16 58.27,113.51 62.28,113.51 v1(62.84,112.95)
  BOTTOM w0.127: U127.15 62.65,113.27 62.84,113.08 v1(62.84,112.95)
CPSW_RGMII2_ETH2_CLK_OUT: length 5.3
  TOP w0.132: v1(60.83,111.2) 60.74,111.29 TP124.1
  BOTTOM w0.127: v1(60.83,111.2) 60.83,111.72 60.93,111.82 60.93,112.64 61.1,112.81 61.1,113.17 61.15,113.21 U127.18
CPSW_RGMII2_MDC: length 2.8
  BOTTOM w0.127: U127.16 62.15,112.52 R652.1
  BOTTOM w0.132: R652.1 62.79,112.39 R644.2
CPSW_RGMII2_MDIO: length 2.5
  TOP w0.132: R646.2 61.61,113.05 v1(61.52,112.95)
  BOTTOM w0.127: U127.17 61.65,113.08 v1(61.52,112.95) R630.2
CPSW_RGMII2_RD0: length 31.1
  TOP w0.127: R631.2 v1(56.3,119.06) ; U12.W18 v1(42.47,110.93)
  L03_SIG1 w0.107: v1(42.47,110.93) 42.11,110.58 41.52,110.58 41.31,110.79 41.31,111.97 43.18,113.84 43.18,115.44 44.81,117.07 47.7,117.07 48.49,116.28 49.5,116.28 50.29,115.49 51.28,115.49 52.13,116.34 52.13,117.07 51.8,117.4 50.24,117.4 49.94,117.7 49.94,118.11 50.24,118.41 52.07,118.41 52.48,118.82 56.06,118.82 v1(56.3,119.06)
  BOTTOM w0.127: R653.1 55.74,119.06 v1(56.3,119.06) 56.57,118.79 56.8,118.79 56.89,118.7 U127.33
CPSW_RGMII2_RD1: length 30.2
  TOP w0.127: U12.Y20 43.1,112.13 43.46,112.5 45.01,112.5 45.22,112.29 48.47,112.29 48.58,112.4 48.58,112.82 48.7,112.93 48.85,112.93 48.97,112.82 48.97,112.4 49.08,112.29 49.23,112.29 49.35,112.4 49.35,112.82 49.46,112.93 49.62,112.93 49.73,112.82 49.73,112.4 49.84,112.29 50.77,112.29 51.41,112.93 51.41,113.5 51.3,113.61 50.84,113.61 50.72,113.72 50.72,113.88 50.84,113.99 51.3,113.99 51.41,114.1 51.41,114.26 51.3,114.37 50.84,114.37 50.72,114.48 50.72,114.64 50.84,114.75 51.3,114.75 51.41,114.86 51.41,115.13 v1(50.52,116.02)
  L03_SIG1 w0.107: v1(50.52,116.02) 50.19,116.02 49.2,117.02 49.2,119.3 50.11,120.22 52.02,120.22 52.53,120.73 54.67,120.73 v1(55.43,119.96)
  BOTTOM w0.127: U127.34 56.81,119.2 56.05,119.96 v1(55.43,119.96)
CPSW_RGMII2_RD2: length 32.5
  TOP w0.127: U12.Y19 43.24,111.71 ; R637.2 56.3,120.37
  TOP w0.132: 56.3,120.37 56.02,120.65 56.02,120.94 v1(55.59,121.37) ; v1(51.28,116.06) 51.81,116.06 52.32,115.54 52.32,115.05 52.21,114.94 52.14,114.94 52.02,114.82 52.02,114.66 52.14,114.54 52.21,114.54 52.32,114.43 52.32,114.26 52.21,114.15 52.14,114.15 52.02,114.03 52.02,113.87 52.14,113.75 52.21,113.75 52.32,113.63 52.32,112.24 51.79,111.71 43.24,111.71
  L03_SIG1 w0.107: v1(55.59,121.37) 56.01,120.95 56.01,119.91 55.32,119.23 52.22,119.23 51.77,118.77 49.89,118.77 49.61,118.49 49.61,117.5 51.05,116.06 v1(51.28,116.06)
  BOTTOM w0.127: U127.35 56.82,119.7 56.17,120.35 56.17,120.5
  BOTTOM w0.132: R640.1 v1(55.59,121.37) 55.93,121.37 56.17,121.13 56.17,120.5
CPSW_RGMII2_RD3: length 29.7
  TOP w0.127: 42.47,112.83 42.07,112.43 U12.W20
  TOP w0.132: 42.47,112.83 42.47,113.73 42.36,113.84 42.36,115.56 43.51,116.71 v1(48.89,116.71)
  L03_SIG1 w0.107: v1(56.6,121.11) 55.77,121.95 55.18,121.95 55.09,121.85 55.09,121.23 54.99,121.13 54.86,121.13 54.77,121.23 54.77,121.85 54.67,121.95 54.54,121.95 54.45,121.85 54.45,121.23 54.35,121.13 54.22,121.13 54.13,121.23 54.13,121.85 54.03,121.95 53.9,121.95 53.81,121.85 53.81,121.23 53.71,121.13 53.58,121.13 53.49,121.23 53.49,121.85 53.39,121.95 53.24,121.95 51.77,120.47 49.91,120.47 48.89,119.46 48.89,119.24 48.8,119.15 48.53,119.15 48.44,119.06 48.44,118.92 48.53,118.83 48.8,118.83 48.89,118.74 48.89,118.6 48.8,118.51 48.53,118.51 48.44,118.42 48.44,118.28 48.53,118.19 48.8,118.19 48.89,118.1 v1(48.89,116.71)
  BOTTOM w0.127: v1(56.6,121.11) 56.6,120.42 56.82,120.2 U127.36
CPSW_RGMII2_RESETN: length 27.2
  L06_SIG2 w0.107: v1(63.63,105.69) 62.99,106.32 62.99,106.34 63.07,106.42 63.07,106.74 62.99,106.82 62.99,110.72 63.68,111.4 63.68,114.1 64.11,114.53 64.11,119.46 63.37,120.19 63.37,120.65 61.16,122.86 v1(60.88,122.86)
  BOTTOM w0.127: U127.43 61.15,121.55 61.42,121.82 61.42,122.2 60.88,122.73 v1(60.88,122.86)
  BOTTOM w0.132: U128.4 60.05,105.09 60.22,104.92 R661.1 61.03,104.57 61.32,104.28 61.35,104.28 61.35,104.28 62.72,104.28 63.63,105.18 v1(63.63,105.69)
CPSW_RGMII2_RX_CTL: length 30.1
  TOP w0.127: 42.47,111.73 U12.W19
  TOP w0.132: 42.47,111.73 42.47,112.37 42.68,112.58 43.09,112.58 43.23,112.73 43.23,113.16 43.41,113.33 44.4,113.33 44.85,112.88 46.81,112.88 47.09,113.16 48.26,113.16 48.89,113.79 48.89,114.58 49.33,115.01 v1(49.33,115.85)
  L03_SIG1 w0.107: v1(55.24,122.4) 55.35,122.3 56.11,122.3 57.02,121.39 57.02,119.13 56.39,118.49 53.67,118.49 52.53,117.35 52.53,116.26 51.44,115.17 50.03,115.17 49.35,115.85 v1(49.33,115.85)
  BOTTOM w0.127: R635.2 R654.2 57.53,122.32 57.93,121.93 58.17,121.93 58.65,121.45 U127.38
  BOTTOM w0.132: R635.2 56.02,122.3 55.35,122.3 v1(55.24,122.4)
CPSW_RGMII2_RXC: length 27.7
  TOP w0.127: U12.V18 v1(41.67,110.93)
  L03_SIG1 w0.107: v1(54,118.07) 54,117.35 53.92,117.26 53.92,117.13 54.2,116.84 54.2,116.71 54.11,116.62 53.98,116.62 53.69,116.91 53.56,116.91 53.46,116.81 53.46,116.68 53.75,116.39 53.75,116.26 53.66,116.17 53.52,116.17 53.24,116.45 53.1,116.45 53.01,116.36 53.01,116.23 53.3,115.94 53.3,115.81 53.2,115.71 53.07,115.71 52.78,116 52.65,116 52.56,115.91 52.56,115.77 52.84,115.49 52.84,115.35 52.75,115.26 52.62,115.26 52.33,115.55 52.2,115.55 52.11,115.45 52.11,115.32 52.39,115.03 52.39,114.9 52.3,114.81 52.17,114.81 51.88,115.09 51.75,115.09 51.49,114.83 49.48,114.83 49.01,115.31 48.87,115.31 48.59,115.02 48.45,115.02 48.36,115.11 48.36,115.25 48.65,115.53 48.65,115.67 48.55,115.76 48.42,115.76 48.13,115.47 48,115.47 47.91,115.57 47.91,115.7 48.19,115.99 48.19,116.12 48.1,116.21 47.97,116.21 47.68,115.93 47.55,115.93 47.46,116.02 47.46,116.15 47.74,116.44 47.74,116.57 47.57,116.74 45.03,116.74 43.46,115.17 43.46,112.57 41.82,110.93 v1(41.67,110.93)
  BOTTOM w0.127: R632.1 v1(54,118.07)
CPSW_RGMII2_TD0: length 21.3
  TOP w0.132: v1(44.65,112.11) 44.65,112.11 44.65,112.13 U12.AA20
  L03_SIG1 w0.107: v1(44.65,112.11) 44.65,112.11 44.89,112.34 47.59,112.34 47.68,112.44 47.68,112.83 47.77,112.93 47.91,112.93 48,112.83 48,112.44 48.09,112.34 48.23,112.34 48.32,112.44 48.32,112.89 48.41,112.98 48.55,112.98 48.64,112.89 48.64,112.44 48.73,112.34 48.87,112.34 48.96,112.44 48.96,112.89 49.05,112.98 49.19,112.98 49.28,112.89 49.28,112.44 49.37,112.34 49.51,112.34 49.6,112.44 49.6,112.89 49.69,112.98 49.83,112.98 49.92,112.89 49.92,112.44 50.01,112.34 50.15,112.34 50.24,112.44 50.24,112.96 50.33,113.06 50.47,113.06 50.56,112.96 50.56,112.44 50.65,112.34 50.93,112.34 55.22,116.64 55.81,116.64 v1(56.4,116.05)
  BOTTOM w0.127: U127.28 56.83,116.2 56.68,116.05 v1(56.4,116.05)
CPSW_RGMII2_TD1: length 21.4
  TOP w0.127: v1(40.87,108.53) U12.U15
  L03_SIG1 w0.107: v1(40.87,108.53) 41.31,108.98 41.31,109.48 41.61,109.78 41.82,109.78 42.11,110.07 42.11,110.28 42.41,110.58 42.62,110.58 42.99,110.94 44.85,110.94 45.95,112.04 51.54,112.04 52.05,112.55 52.18,112.55 52.29,112.44 52.42,112.44 52.52,112.54 52.52,112.67 52.41,112.78 52.41,112.91 52.5,113 52.63,113 52.74,112.9 52.87,112.9 52.97,112.99 52.97,113.12 52.86,113.23 52.86,113.36 54.63,115.13 v1(55.48,115.13)
  BOTTOM w0.127: v1(55.48,115.13) 55.94,115.59 56.71,115.59 56.82,115.7 U127.27
CPSW_RGMII2_TD2: length 21.5
  TOP w0.127: U12.W17 v1(42.47,110.13)
  L03_SIG1 w0.107: v1(56.4,115.13) 55.95,114.68 55.3,114.68 54.33,113.72 54.33,113.59 54.73,113.18 54.73,113.05 54.64,112.96 54.51,112.96 54.11,113.36 53.97,113.36 53.88,113.27 53.88,113.13 54.28,112.73 54.28,112.6 54.19,112.51 54.05,112.51 53.65,112.91 53.52,112.91 53.43,112.81 53.43,112.68 53.83,112.28 53.83,112.15 53.73,112.05 53.6,112.05 53.2,112.45 53.07,112.45 52.35,111.73 46.58,111.73 45.39,110.54 42.88,110.54 v1(42.47,110.13)
  BOTTOM w0.127: v1(56.4,115.13) 56.46,115.2 U127.26
CPSW_RGMII2_TD3: length 21.4
  TOP w0.127: U12.V16 v1(41.67,109.33)
  L03_SIG1 w0.107: v1(41.67,109.33) 42.03,108.98 45.15,108.98 47.65,111.48 49.72,111.48 49.81,111.39 49.81,111.14 49.9,111.05 50.04,111.05 50.13,111.14 50.13,111.39 50.22,111.48 50.36,111.48 50.45,111.39 50.45,111.14 50.54,111.05 50.68,111.05 50.77,111.14 50.77,111.39 50.86,111.48 51,111.48 51.09,111.39 51.09,111.14 51.18,111.05 51.32,111.05 51.41,111.14 51.41,111.39 51.5,111.48 53.9,111.48 55.48,113.07 v1(55.48,114.22)
  BOTTOM w0.127: U127.25 55.96,114.7 v1(55.48,114.22)
CPSW_RGMII2_TX_CTL: length 21.6
  TOP w0.132: v1(43.84,113.74) 43.33,113.74 42.87,113.28 U12.Y21
  L03_SIG1 w0.107: v1(43.84,113.74) 44.17,113.74 45.09,112.83 46.41,112.83 46.81,113.23 47.6,113.23 48.16,113.79 51.84,113.79 55.52,117.48 56.69,117.48 57.43,118.21 v1(57.43,121.23)
  BOTTOM w0.127: v1(57.43,121.23) 57.71,120.95 U127.37
CPSW_RGMII2_TXC: length 16
  TOP w0.132: R43.2 48.38,110.93 48.51,111.06 v1(48.51,111.07)
  L03_SIG1 w0.107: v1(48.51,111.07) 48.92,110.67 53.49,110.67 57.12,114.3 57.12,115.24 56.77,115.6 55.94,115.6 v1(55.48,116.05)
  BOTTOM w0.127: v1(55.48,116.05) 55.92,116.48 56.6,116.48 56.82,116.7 U127.29
CPSW_RGMII2_TXC_R: length 5.3
  TOP w0.127: R43.1 45.82,110.93 45.7,111.06 45.7,111.26 45.55,111.4 45.34,111.4 45.19,111.26 45.19,111.05 45.04,110.9 43.23,110.9 U12.Y18
CPSW_RGMII_INTN: length 38.4
  TOP w0.127: v1(61.52,102.25) R63.2
  L06_SIG2 w0.107: v1(61.52,124.8) 61.52,124.74 63.83,122.43 63.83,120.75 64.36,120.22 64.36,114.43 63.93,114 63.93,112.09 64.82,111.2 64.82,107.42 v1(65.77,106.46)
  BOTTOM w0.127: v1(61.52,102.25) 61.1,101.83 61.1,100.75 61.42,100.43 61.42,100.18 61.64,99.95 R370.1 61.94,99.32 61.65,99.03 U55.44 ; U127.44 61.65,121.59 61.94,121.88 R634.1 61.58,122.51 61.43,122.65 61.43,122.97 61.1,123.3 61.1,124.38 v1(61.52,124.8)
  BOTTOM w0.132: v1(65.77,106.46) 65.28,105.97 65.28,104.9 64.03,103.66 61.42,103.66 61.04,103.28 61.04,102.82 61.52,102.34 v1(61.52,102.25)
CPSW_RGMII_INTN/PRU_INTN: length 224.4
  TOP w0.127: v1(63.16,102.9) R63.1
  TOP w0.132: R55.1 23.46,109.07 v1(22.97,109.56)
  L03_SIG1 w0.107: 7.86,94.54 8.08,94.32 9.84,94.32 10.17,94.65 10.17,98.68 10.43,98.95 10.43,104.48 14.44,108.49 16.34,108.49 16.97,109.11 18.96,109.11 19.82,109.97 21.59,109.97 22,109.56 v1(22.97,109.56) ; 7.86,94.54 7.86,96.17 6.46,97.57 6.46,99.09 7.91,100.55 7.91,105.91 11.15,109.14 11.15,110.31 14.49,113.65 14.49,115.32 13.98,115.83 13.98,119.89 13.01,120.85 13.01,125.31 15.78,128.07 15.78,128.65 16.48,129.35 27.37,129.35 28.18,130.16 28.18,131.2 30.83,133.85 30.83,141.5 31.22,141.89 32.23,141.89 32.51,141.61 32.51,137.87 32.73,137.65 35.44,137.65 36.91,139.12 38.81,139.12 39.78,140.08 40.99,140.08 43.55,137.52 48.15,137.52 49.57,136.1 57.03,136.1 57.26,135.87 57.26,135.44 56.31,134.49 56.31,125.98 v1(56.44,125.86) ; 7.86,94.54 7.61,94.29 6.51,94.29 4.12,91.9 4.12,89.47 6.3,87.29 6.3,83.46 7.29,82.47 7.29,79.87 7.05,79.62 7.05,76.28 7.75,75.58 7.75,59.15 7.14,58.54 7.14,56.44 7.75,55.83 9.93,55.83 v1(10.12,56.02)
  L06_SIG2 w0.107: v1(10.12,56.02) 12.79,53.35 17.13,53.35 v1(17.84,52.64) ; v1(63.16,102.9) 63.16,104.12 62.38,104.9 62.32,104.9 61.9,105.32 61.9,105.38 60.27,107.01 58.93,107.01 52.93,113 52.93,117 52.58,117.36 52.58,121.97 54.08,123.47 54.08,124.49 55.45,125.86 v1(56.44,125.86)
  BOTTOM w0.127: R433.1 18.41,52.46 18.23,52.64 v1(17.84,52.64)
CPSW_RGMII_TXC_R: length 3.9
  TOP w0.127: U12.W16 v1(42.47,109.33)
  L03_SIG1 w0.107: v1(44.87,110.13) 44.47,109.74 42.87,109.74 v1(42.47,109.33)
  BOTTOM w0.132: v1(44.87,110.13) 44.72,110.28 R346.1
CSI0_RXCLKN: length 68.1
  TOP w0.105: U12.AA14 43.91,107.09 45.22,107.09 45.61,107.48 50.92,107.48 51.47,106.93 53.04,106.93 53.6,107.49 54.23,107.49 v1(54.44,107.7) ; v1(66.21,141.42) 66.08,141.55 J1.7
  L03_SIG1 w0.081: v1(54.44,107.7) 54.75,107.39 56.11,107.39 60.4,111.68 60.4,114.48 60.2,114.68 60.2,122.4 60.02,122.58 60.02,125.48 61.18,126.64 63.54,126.64 65.25,128.35 65.25,132.29 65.08,132.46 64.39,132.46 64.02,132.83 64.02,133.31 64.3,133.59 65.24,133.59 65.38,133.73 65.38,134.86 65.08,135.16 63.86,135.16 63.53,135.49 63.53,138.48 63.86,138.81 64.33,138.81 64.66,138.48 64.66,136.46 64.84,136.29 65.08,136.29 65.25,136.46 65.25,138.91 64.3,139.86 64.3,141.95 64.75,142.39 65.63,142.39 66.12,141.91 66.12,141.51 v1(66.21,141.42)
CSI0_RXCLKP: length 68.1
  TOP w0.105: v1(54.44,106.91) 54.17,107.18 53.73,107.18 53.17,106.62 51.34,106.62 50.79,107.16 45.74,107.16 45.35,106.78 43.91,106.78 U12.AA13 ; v1(65.45,141.42) 65.65,141.42 65.76,141.52 65.76,141.88 65.58,142.06 J1.5
  L03_SIG1 w0.081: v1(65.45,141.42) 65.68,141.42 65.76,141.5 65.76,141.88 65.52,142.12 64.86,142.12 64.58,141.84 64.58,139.97 65.52,139.02 65.52,136.35 65.19,136.02 64.72,136.02 64.39,136.35 64.39,138.37 64.22,138.54 63.97,138.54 63.8,138.37 63.8,135.6 63.97,135.43 65.19,135.43 65.65,134.97 65.65,133.62 65.35,133.32 64.41,133.32 64.29,133.2 64.29,132.95 64.5,132.73 65.19,132.73 65.52,132.4 65.52,128.23 63.66,126.37 61.29,126.37 60.29,125.37 60.29,122.69 60.47,122.52 60.47,114.79 60.67,114.59 60.67,111.57 56.22,107.12 54.65,107.12 v1(54.44,106.91)
CSI0_RXN0: length 68.1
  TOP w0.102: U12.Y13 v1(43.27,106.93)
  TOP w0.105: v1(67.71,138.75) 67.5,138.75 67.39,138.85 67.39,141.74 67.58,141.93 J1.11
  L03_SIG1 w0.081: v1(67.71,138.75) 67.71,138.44 67.6,138.33 67.44,138.33 67.34,138.44 67.34,139.04 67.54,139.25 68.39,139.25 68.59,139.05 68.59,137.52 68.88,137.22 69.95,137.22 70.09,137.09 70.09,136.9 69.95,136.76 67.32,136.76 66.8,136.25 66.8,135.73 67.13,135.4 68.08,135.4 68.26,135.23 68.26,134.98 68.08,134.81 67.13,134.81 66.8,134.48 66.8,128.37 63.97,125.54 62.9,125.54 62.05,124.69 62.05,122.02 61.29,121.26 61.29,114.5 61.98,113.82 61.98,110.16 60.17,108.36 58.47,108.36 56.34,106.22 52.02,106.22 50.76,107.49 49.52,107.49 48.71,106.67 43.44,106.67 43.27,106.84 v1(43.27,106.93)
CSI0_RXN1: length 68.2
  TOP w0.102: U12.V13 v1(41.67,106.93)
  TOP w0.105: v1(69.21,141.42) 69,141.42 68.89,141.52 68.89,141.88 69.08,142.07 J1.15
  L03_SIG1 w0.081: v1(69.21,141.42) 69.21,141.59 69.1,141.7 68.92,141.7 68.84,141.62 68.84,140.59 68.38,140.13 67.59,140.13 66.96,140.76 66.96,142.16 66.11,143.01 63.84,143.01 62.55,141.72 62.55,140.27 62.84,139.99 62.84,136.78 62.48,136.42 61.98,136.42 61.62,136.78 61.35,136.78 61.15,136.58 61.15,136.31 61.51,135.95 61.51,135.45 61.15,135.09 60.65,135.09 60.29,135.45 60.02,135.45 59.23,134.66 59.23,125.69 58.89,125.36 58.89,121.75 59.3,121.35 59.3,114.72 59.58,114.44 59.58,111.95 56.15,108.52 49.64,108.52 48.26,107.13 46.91,107.13 46.72,107.33 41.79,107.33 41.67,107.2 v1(41.67,106.93)
CSI0_RXN2: length 68.2
  TOP w0.102: U12.U12 v1(40.07,105.34)
  TOP w0.105: v1(70.71,138.75) 70.5,138.75 70.39,138.85 70.39,141.87 70.58,142.06 J1.19
  L03_SIG1 w0.081: v1(70.71,138.75) 70.55,138.75 70.35,138.95 70.35,139.82 70.56,140.03 71.35,140.03 71.7,139.67 71.7,136.88 67.74,132.92 67.74,128.09 63.65,124 63.65,121.72 62.48,120.55 62.48,114.66 63.3,113.84 63.3,109.86 60.8,107.36 58.76,107.36 56.81,105.41 51.16,105.41 50.77,105.79 45.69,105.79 45.38,105.48 44.1,105.48 43.87,105.71 42.33,105.71 42,106.04 41.27,106.04 40.95,105.71 40.45,105.71 v1(40.07,105.34)
CSI0_RXN3: length 68.1
  TOP w0.102: U12.W12 v1(41.67,105.34)
  TOP w0.105: v1(72.21,141.42) 72,141.42 71.89,141.52 71.89,141.74 72.08,141.93 J1.23
  L03_SIG1 w0.081: v1(41.67,105.34) 41.67,105.15 41.75,105.07 42.13,105.07 42.21,105.15 43.39,105.15 43.61,104.93 48.09,104.93 48.45,104.56 57.22,104.56 59.1,106.45 61.11,106.45 64.83,110.17 64.83,114.06 63.93,114.96 63.93,119.84 64.93,120.84 64.93,124.04 68.66,127.76 68.66,131.57 69.65,132.56 69.65,133.3 73.13,136.78 73.13,142.03 72.73,142.43 72.01,142.43 71.83,142.24 71.83,141.13 71.91,141.05 72.13,141.05 72.21,141.13 v1(72.21,141.42)
CSI0_RXP0: length 68.1
  TOP w0.102: U12.Y12 v1(43.27,106.13)
  TOP w0.105: v1(66.95,138.75) 67.08,138.88 J1.9
  L03_SIG1 w0.081: v1(66.95,138.75) 67.06,138.87 67.06,139.16 67.43,139.52 68.5,139.52 68.86,139.17 68.86,137.63 68.99,137.49 70.06,137.49 70.36,137.2 70.36,136.78 70.06,136.49 67.43,136.49 67.07,136.13 67.07,135.84 67.25,135.67 68.2,135.67 68.53,135.34 68.53,134.87 68.2,134.54 67.25,134.54 67.07,134.36 67.07,128.26 64.09,125.27 63.02,125.27 62.32,124.58 62.32,121.91 61.56,121.15 61.56,114.62 62.25,113.93 62.25,110.05 60.29,108.08 58.58,108.08 56.45,105.95 51.91,105.95 50.64,107.21 49.64,107.21 48.82,106.4 43.53,106.4 v1(43.27,106.13)
CSI0_RXP1: length 68.2
  TOP w0.102: U12.V12 v1(40.87,106.13)
  TOP w0.105: v1(68.45,141.42) 68.58,141.55 J1.13
  L03_SIG1 w0.081: v1(68.45,141.42) 68.56,141.3 68.56,140.7 68.27,140.4 67.7,140.4 67.23,140.87 67.23,142.27 66.22,143.28 63.73,143.28 62.28,141.84 62.28,140.16 62.56,139.87 62.56,136.89 62.37,136.69 62.09,136.69 61.73,137.05 61.23,137.05 60.88,136.7 60.88,136.2 61.24,135.84 61.24,135.56 61.04,135.37 60.77,135.37 60.41,135.73 59.91,135.73 58.95,134.77 58.95,125.81 58.62,125.48 58.62,121.64 59.03,121.23 59.03,114.6 59.31,114.33 59.31,112.06 56.03,108.79 49.53,108.79 48.15,107.4 47.03,107.4 46.83,107.6 41.66,107.6 41.25,107.19 41.25,106.51 v1(40.87,106.13)
CSI0_RXP2: length 68.1
  TOP w0.102: U12.U11 v1(40.87,105.33)
  TOP w0.105: J1.17 70.08,138.88 v1(69.95,138.75)
  L03_SIG1 w0.081: v1(40.87,105.33) 40.97,105.33 41.4,105.77 41.88,105.77 42.21,105.44 43.76,105.44 43.99,105.2 45.49,105.2 45.81,105.52 50.66,105.52 51.04,105.14 56.93,105.14 58.87,107.09 60.91,107.09 63.57,109.74 63.57,113.96 62.76,114.77 62.76,120.44 63.92,121.6 63.92,123.89 68.01,127.98 68.01,132.81 71.98,136.77 71.98,139.79 71.46,140.3 70.45,140.3 70.08,139.93 70.08,138.88 v1(69.95,138.75)
CSI0_RXP3: length 68.1
  TOP w0.102: U12.W11 v1(41.67,104.54)
  TOP w0.105: J1.21 71.58,141.55 v1(71.45,141.42)
  L03_SIG1 w0.081: v1(71.45,141.42) 71.56,141.53 71.56,142.36 71.9,142.7 72.85,142.7 73.4,142.14 73.4,136.67 69.92,133.19 69.92,132.45 68.93,131.46 68.93,127.65 65.2,123.92 65.2,120.72 64.2,119.72 64.2,115.07 65.1,114.18 65.1,110.05 61.23,106.18 59.22,106.18 57.33,104.29 48.34,104.29 47.97,104.66 43.5,104.66 43.27,104.88 42.33,104.88 42.25,104.8 41.93,104.8 v1(41.67,104.54)
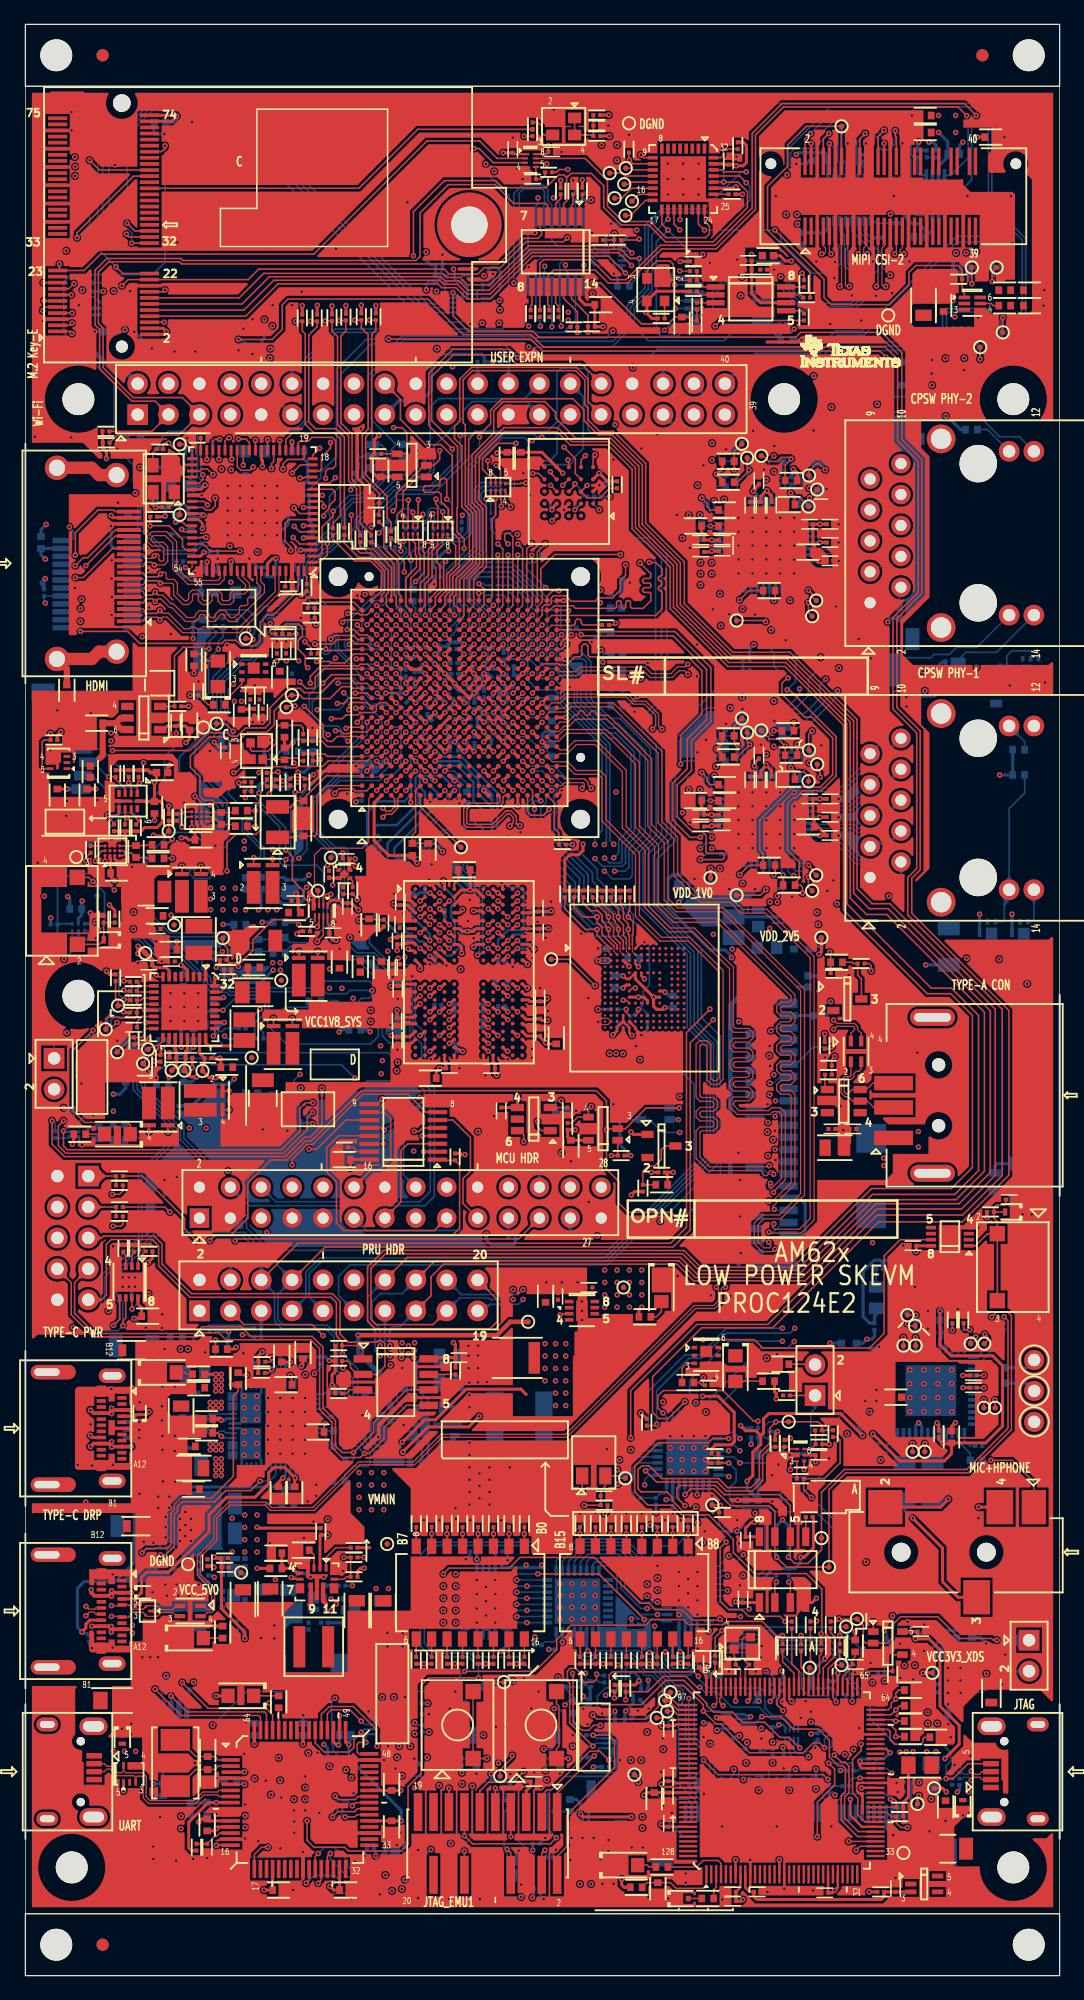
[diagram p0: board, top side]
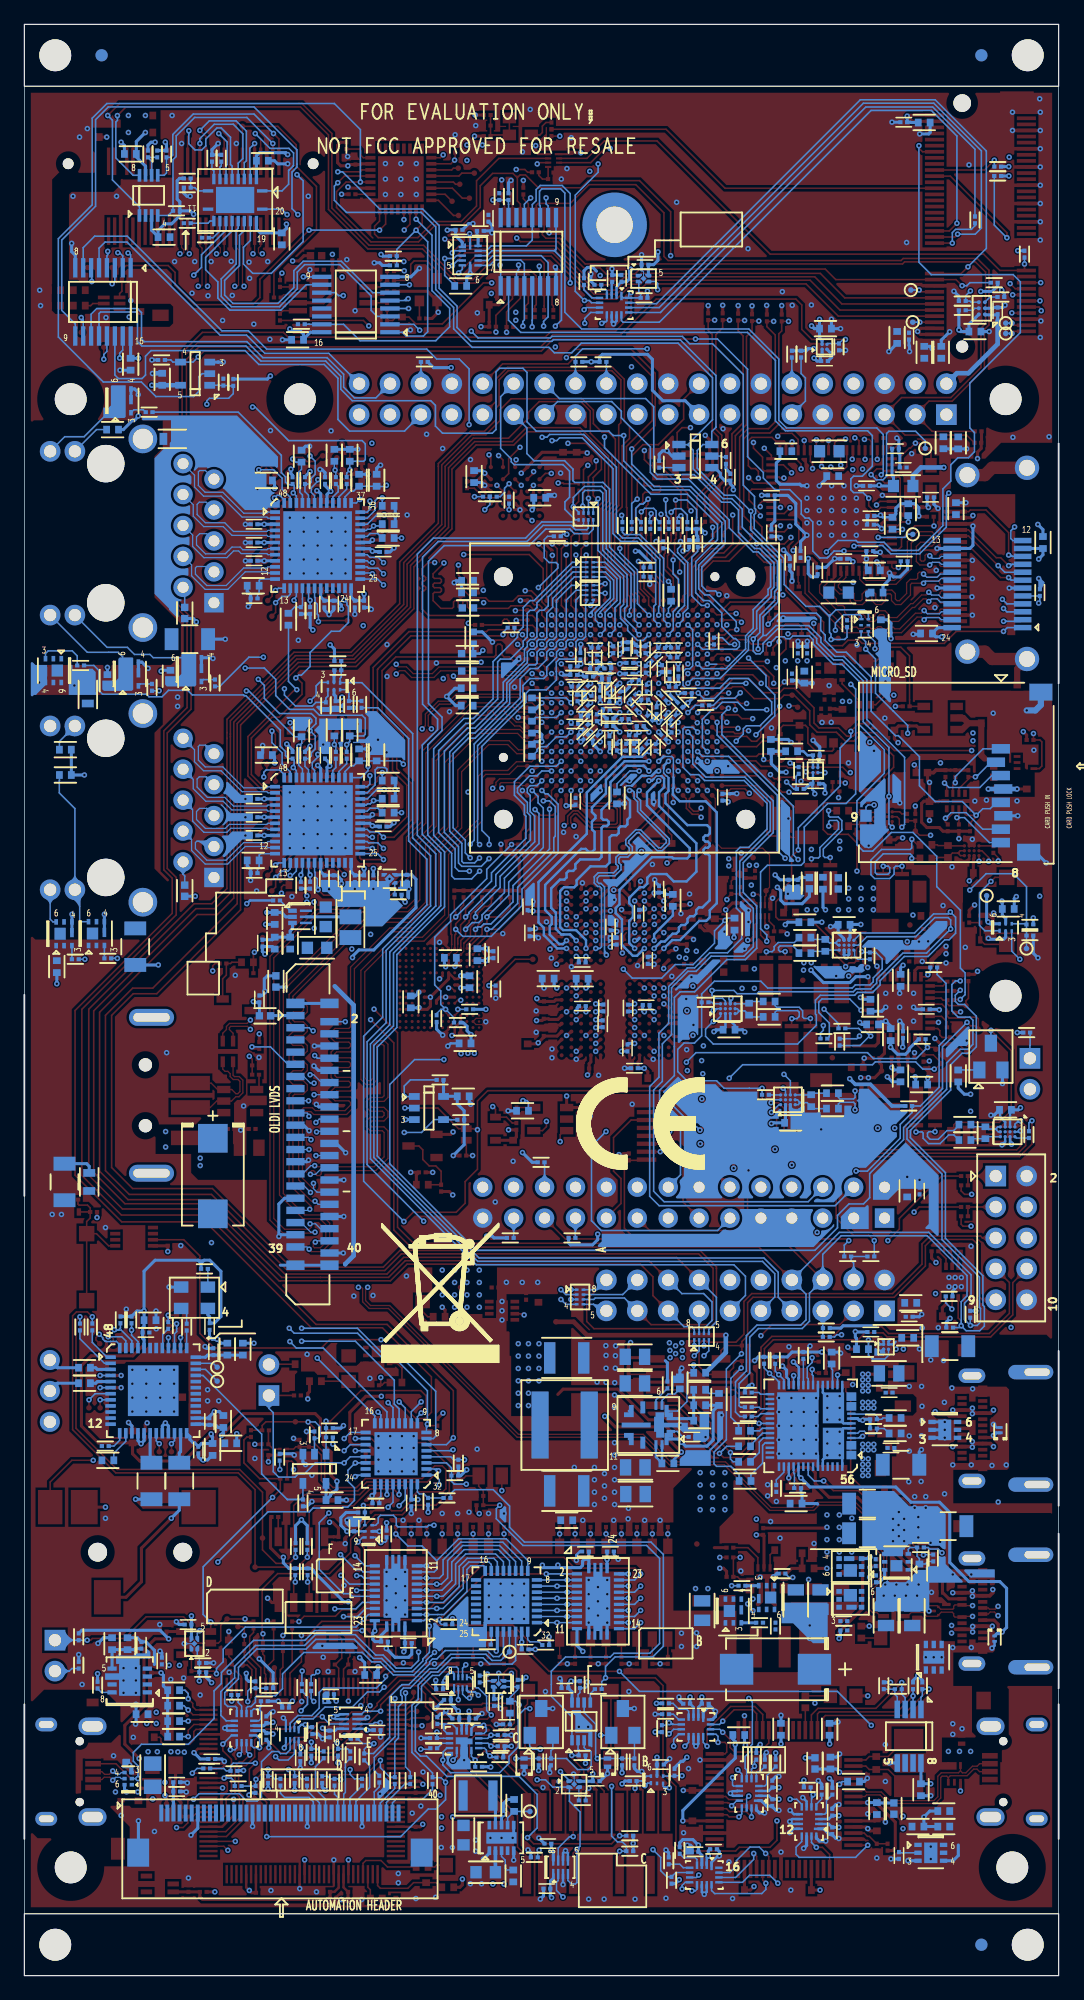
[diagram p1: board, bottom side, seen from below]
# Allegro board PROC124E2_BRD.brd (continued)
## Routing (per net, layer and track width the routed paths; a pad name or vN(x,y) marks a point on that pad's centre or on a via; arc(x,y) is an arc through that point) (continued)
CSI0_RXRCALIB: length 3.9
  TOP w0.132: v1(40.07,104.54) U12.T11
  BOTTOM w0.132: R356.2 40.47,104.94 v1(40.07,104.54)
CSI_GPIO0: length 134
  L06_SIG2 w0.107: v1(63.18,52.08) 63.79,52.08 69.1,57.39 69.1,87.59 67.75,88.94 67.75,90.13 66.37,91.51 66.37,105.86 66.47,105.97 66.47,107.34 66.22,107.59 66.22,113.56 67.51,114.86 67.51,126.62 65.86,128.27 65.86,130.27 70.52,134.93 75.63,134.93 78.88,138.18 78.88,142.4 77.89,143.39 64.65,143.39 v1(63.41,144.64)
  BOTTOM w0.132: U70.14 55.2,46.31 60.44,51.55 62.65,51.55 v1(63.18,52.08) ; U98.20 63.85,145.08 v1(63.41,144.64)
CSI_GPIO0_BUFF: length 11.4
  TOP w0.132: v1(66.02,151.29) 65.58,150.84 J1.6
  BOTTOM w0.132: U98.1 63.83,146.58 63.28,147.13 63.28,148.26 63.27,148.27 63.26,148.27 62.91,148.62 62.91,148.63 62.87,148.66 62.87,149.69 63.26,150.07 64.81,150.07 v1(66.02,151.29)
CSI_GPIO1: length 165
  L03_SIG1 w0.107: v1(62.6,147.91) 62.87,147.63 71.85,147.63 75.84,143.64 75.84,136.23 76.56,135.52 76.56,131.66 74.87,129.98 73.14,129.98 71.97,128.8 71.97,126.63 70.54,125.2 70.54,112.29 69.95,111.71 69.95,110.44 70.27,110.12 70.27,106.03 65.92,101.69 65.92,100.47 64.88,99.42 64.88,92.83 65.24,92.47 65.24,88.81 70.59,83.46 70.59,75.23 68.75,73.39 68.75,59.31 73.67,54.39 73.67,51.29 70.72,48.34 70.72,44.89 66.02,40.19 57.93,40.19 56.51,41.61 56.51,45.72 v1(55.94,46.29)
  BOTTOM w0.132: v1(62.6,147.91) 62.09,147.4 62.09,142.43 64.7,139.81 66.23,139.81 66.99,140.57 66.99,141.94 66.43,142.51 U98.18 ; U70.15 55.7,46.05 v1(55.94,46.29)
CSI_GPIO1_BUFF: length 4.6
  TOP w0.132: J1.8 v1(66.08,150.47)
  BOTTOM w0.132: U98.3 66.43,148.44 66.47,148.49 66.47,150.07 v1(66.08,150.47)
CSI_GPIO2: length 23.9
  BOTTOM w0.132: U98.17 66.93,143.33 67.32,142.93 67.32,140.45 68.54,139.23 68.54,138.02 67.86,137.35 64.15,137.35 62.85,138.64 62.85,140.03 62.08,140.8 58.95,140.8 56.37,138.22 U43.6
CSI_GPIO2_BUFF: length 11.2
  TOP w0.132: J1.18 70.08,151.05 v1(70.58,151.55)
  BOTTOM w0.132: U98.4 66.93,148.88 66.75,149.06 66.75,151.49 67.6,152.33 69.79,152.33 v1(70.58,151.55)
CSI_GPIO3: length 25.7
  BOTTOM w0.132: U43.3 56.01,136.27 56.5,136.76 56.5,137.96 59.06,140.52 61.96,140.52 62.57,139.91 62.57,138.53 64.03,137.07 67.98,137.07 68.82,137.91 68.82,139.35 67.6,140.57 67.6,143.33 67.43,143.51 U98.16
CSI_GPIO3_BUFF: length 10.1
  TOP w0.132: J1.20 v1(70.58,150.47)
  BOTTOM w0.132: U98.5 67.43,148.85 67.04,149.24 67.04,151.27 67.83,152.05 69.39,152.05 70.58,150.87 v1(70.58,150.47)
CSI_GPIO4: length 17.5
  BOTTOM w0.132: U43.10 61.83,138.87 63.92,136.79 68.11,136.79 69.1,137.78 69.1,139.1 70.1,140.1 70.1,141.12 67.93,143.29 U98.15
CSI_GPIO4_BUFF: length 12.1
  TOP w0.132: v1(71.49,151.52) 71.49,151.12 71.58,151.03 J1.22
  BOTTOM w0.132: v1(71.49,151.52) 71.49,150.45 70.98,149.94 70.42,149.94 70.09,150.28 70.09,150.83 69.17,151.75 68.82,151.75 68.06,150.99 68.06,148.75 67.93,148.62 U98.6
CSI_I2C2_NINT1: length 1.9
  TOP w0.132: R22.2 41.52,137.13 41.63,137.24 U4.8
CSI_I2C2_SCL: length 53.9
  TOP w0.132: R24.2 43.05,137.13 42.93,137.24 U4.10 42.93,139.6 43.42,140.09 46.82,140.09 47.9,139.01 49.48,139.01 52.28,141.81 56.76,141.81 60,145.05 60,151.18 62.3,153.48 76.64,153.48 v1(77.35,152.76)
  BOTTOM w0.132: v1(77.35,152.76) 77.35,152.37 77.48,152.24 77.48,149.28 76.06,147.86 U97.8
CSI_I2C2_SCL_BUFF: length 16.5
  TOP w0.132: J1.2 64.08,150.84 v1(64.52,151.29)
  BOTTOM w0.132: U97.5 73.51,147.86 73.32,148.05 R567.2 72.99,149.33 72.8,149.52 72.8,151.21 71.12,152.89 66.12,152.89 v1(64.52,151.29)
CSI_I2C2_SDA: length 59.8
  TOP w0.132: v1(78.15,152.77) 77.17,153.75 62.42,153.75 62.42,153.76 62.19,153.76 59.73,151.29 59.73,145.17 56.67,142.11 52.19,142.11 49.36,139.29 48.13,139.29 46.49,140.93 42.58,140.93 42.28,140.64 U4.9 42.28,137.13 42.29,137.13 R23.2
  BOTTOM w0.132: v1(78.15,152.77) 77.76,152.38 77.76,147.48 75.54,145.26 U97.1
CSI_I2C2_SDA_BUFF: length 18.6
  TOP w0.132: J1.4 v1(64.58,150.47)
  BOTTOM w0.132: U97.4 73.17,144.56 72.79,144.94 R568.2 72.78,149.14 72.52,149.41 72.52,151.09 71,152.61 66.72,152.61 v1(64.58,150.47)
CSI_I2C_LT_EN: length 2.4
  BOTTOM w0.132: R575.1 R576.2 74.84,149.32 74.54,149.02 U97.6
CSI_LT_EN: length 2.3
  BOTTOM w0.132: R573.1 R574.2 70.99,146.85 70.72,146.58 U98.10
CSI_REFCLK: length 22.6
  TOP w0.132: J1.10 TP2.1 64.18,151.88 62.66,150.37 62.66,148.61 61,146.95 61,143.37 64.49,139.88 R18.2
CSI_RSTZ: length 50.4
  TOP w0.132: U3.10 49.95,148.8 v1(49.64,149.11) 49.6,149.15 R4.1
  L06_SIG2 w0.107: v1(49.64,149.11) 49.64,147.18 51.1,145.72 60.78,145.72 63.62,142.88 78.04,142.88 78.62,142.3 78.62,141.28 77,139.66 v1(71.08,139.66)
  BOTTOM w0.132: v1(71.08,139.66) 70.44,140.29 70.44,141.33 68.43,143.35 U98.14
CSI_RSTZ_BUFF: length 6.5
  TOP w0.132: J1.14 68.58,150.84 v1(69.02,151.29)
  BOTTOM w0.132: v1(69.02,151.29) 68.34,150.6 68.34,148.74 68.43,148.65 U98.7
CSI_VLDO_SEL: length 30.9
  TOP w0.132: U3.23 55.31,143.86 v1(55.81,143.36) ; v1(61.61,143.36) 65.64,139.32 65.64,137.82 66.21,137.24 71.03,137.24 72.61,138.83 72.61,139.88 73.18,140.45 76.63,140.45 76.98,140.1 R13.1 76.98,138.34 77.17,138.15 U7.1
  BOTTOM w0.132: v1(55.81,143.36) v1(61.61,143.36)
DEBOUNCE_CAN_FD_WKUP: length 12.9
  TOP w0.127: U27.1 78.07,59.94 79.07,60.94 SW2.2 ; SW2.2 SW2.3 ; SW2.2 79.88,61.93
  TOP w0.132: 79.88,61.93 79.59,62.22 R149.2 ; D4.2 R149.2 ; R149.2 79.59,63.05 79.81,63.28 80.5,63.28 80.6,63.37 80.6,63.72 C114.2
DEBOUNCE_GPIO_INT_MCU: length 17.8
  TOP w0.127: v1(44.62,17.83) 44.54,17.83 44.53,17.83 SW6.2 43.65,18.63 43.85,18.83 43.85,22.1 43.65,22.3 SW6.3
  BOTTOM w0.127: v1(44.62,17.83) 44.54,17.83 44.53,17.83 D12.2 R531.2 C454.2 ; U81.3 38.99,18.72 38.82,18.55 38.57,18.55 38.42,18.4 38.42,17.18 38.67,16.93 39.54,16.93 40.44,17.83 C454.2 ; C454.2 41.72,18.48 41.57,18.63 Q12.2
DEBOUNCE_MCU_RESETZ: length 44.8
  TOP w0.127: v1(45.93,38.64) R182.2 C140.2 47.28,39.81 47.66,40.19 Q4.2 48.7,41.04 48.9,40.85 TP70.1
  BOTTOM w0.127: 41.7,23.91 41.7,22.95 39.99,21.24 U81.1
  BOTTOM w0.132: 41.7,23.91 41.7,25 40.52,26.17 36.85,26.17 36.54,26.48 33.6,26.48 32.79,27.28 32.79,34.26 33.86,35.33 44.02,35.33 46.21,37.52 46.21,38.36 v1(45.93,38.64)
DEBOUNCE_SOC_WARMRESETN: length 16.6
  TOP w0.127: v1(37.91,17.83) SW5.2 SW5.3
  BOTTOM w0.127: U81.6 38.99,21.6 38.05,20.66 38.05,17.97 v1(37.91,17.83) D13.2 R532.2 C455.2 Q13.2
DIR: length 15.6
  TOP w0.132: v1(42.11,32.99) 47.13,32.99 v1(50.87,29.25)
  BOTTOM w0.127: U73.2 52.16,29.15 52.06,29.25 v1(50.87,29.25) 50.87,28.99 50.72,28.85 R483.1 ; U75.2 v1(42.11,32.99)
DRAIN1: length 3.2
  BOTTOM w0.203: U68.19 19.38,47.88 19.09,47.6 v1(19.01,47.6) ; v1(18,47.6) 17.78,47.81 U68.15 ; v1(18,45.66) 17.69,45.36 U68.8
  vias: v1(18,46.63) v1(19.01,46.63) v1(19.01,45.66)
DRAIN2: length 3.2
  BOTTOM w0.203: v1(18,42.74) 17.78,42.52 U68.56 ; v1(19.01,42.74) 19.38,42.37 U68.52 ; U68.7 17.71,44.96 v1(18,44.67)
  vias: v1(18,43.71) v1(19.01,44.67) v1(19.01,43.71)
EEPROM_A0: length 1.5
  TOP w0.132: R154.2 9.87,59.49 9.26,58.88 U28.1
EEPROM_A1: length 1.3
  TOP w0.132: R153.1 8.92,59.36 8.76,59.19 U28.2
EEPROM_A2: length 1.3
  TOP w0.132: U28.3 8.26,59.13 8.03,59.36 R152.1
EEPROM_VDD: length 2.1
  BOTTOM w0.254: J22.1 64.74,78.85 FL18.1
EEPROM_WP: length 2.2
  TOP w0.132: U28.7 8.76,54.76 v1(8.77,54.75)
  BOTTOM w0.132: v1(8.77,54.75) 9.28,55.25 R423.1
EMMC_RSTN: length 13.3
  TOP w0.127: U21.K5 49.38,80.11 v1(49.13,80.11)
  TOP w0.132: R138.2 44.9,70.03 45.38,70.51 U25.4 46.28,71.14 v1(46.51,71.37)
  L03_SIG1 w0.107: v1(49.13,80.11) 47.78,78.76 47.78,77.72 46.51,76.46 v1(46.51,71.37)
ETH_CAN_INH: length 0.8
  TOP w0.132: R78.1 R82.2
ETH_CAN_INH_PMIC: length 54.8
  TOP w0.127: v1(15.44,77.17) 15.44,77.22 15.57,77.34 U22.25
  TOP w0.132: R76.1 20.69,98.79 v1(20.76,98.87)
  L06_SIG2 w0.107: v1(15.44,77.17) 15.44,77.01 15.98,76.48 16.94,76.48 17.12,76.66 17.12,81.69 16.88,81.94 16.88,85.56 17.66,86.34 17.66,92.16 16.65,93.18 16.65,95.64 14.67,97.62 11.95,97.62 10.63,98.94 9.76,98.94 9.28,99.42 9.28,102.09 9.97,102.78 12.46,102.78 13,102.23 13,102.23 13.16,102.07 13.69,101.54 13.92,101.31 13.92,100.33 15.9,98.35 20.24,98.35 v1(20.76,98.87)
  BOTTOM w0.132: 15.48,77.17 15.85,77.53 16.17,77.53 16.44,77.8 R590.2 ; 15.48,77.17 v1(15.44,77.17) ; 15.48,77.17 15.54,77.17 16.32,76.39 17.66,76.39 17.66,76.39 R405.2
ETH_CAN_INH_SOC: length 2
  TOP w0.132: R585.1 21.7,97.67 R80.2 R79.1
EXP_CLKOUT0: length 22
  TOP w0.132: R52.1 20.26,110.19 20.13,110.32 v1(20.13,111.06)
  L06_SIG2 w0.107: v1(20.13,111.06) 20.13,113.55 15.38,118.3 15.38,119.84 14.1,121.12 14.1,124.44 15.12,125.46 15.12,126.35 15.95,127.18 15.95,127.3 J3.7
EXP_EHRPWM1_B: length 68.7
  TOP w0.127: U12.D18 v1(29.67,110.93)
  L03_SIG1 w0.107: v1(29.67,110.93) 30.03,111.29 30.03,111.88 28.98,112.94 25,112.94 23.85,114.09 17.92,114.09 16.2,115.81 16.2,116.84 15.69,117.35 15.69,120.73 16.01,121.05 16.01,121.51 15.5,122.02 14.34,122.02 13.9,122.46 13.9,124.81 14.66,125.57 23.14,125.57 23.87,126.3 26.07,126.3 28.95,123.41 38.95,123.41 39.32,123.78 39.32,124.21 40.24,125.13 42.52,125.13 43.71,126.32 49.09,126.32 49.87,127.1 J3.33
EXP_GPIO0_14: length 84
  TOP w0.132: U19.7 24.49,85.45 v1(23.99,84.95)
  L06_SIG2 w0.107: v1(17.08,106.05) 15.2,107.93 13.2,107.93 9.15,111.98 9.15,120.96 10.03,121.84 10.03,126.71 10.71,127.39 10.71,128.64 11.44,129.37 12.18,129.37 13.03,130.22 13.03,131.32 14.18,132.47 19.94,132.47 20.05,132.36 33.01,132.36 J3.22
  BOTTOM w0.132: v1(17.08,106.05) 16.68,105.66 16.68,97.06 17.48,96.27 18.97,96.27 20.9,94.34 20.9,91.46 21.17,91.19 23.94,91.19 24.5,90.64 24.5,85.99 23.99,85.48 v1(23.99,84.95)
EXP_GPIO0_14_LT: length 35.7
  TOP w0.127: U19.2 24.49,88.62 24.67,88.81 v1(25.1,88.81) ; U12.E18 v1(30.47,110.93)
  L06_SIG2 w0.107: v1(25.1,88.81) 25.51,88.81 27.82,91.12 27.82,96.68 26.5,98 v1(26.5,101.38)
  BOTTOM w0.132: v1(26.5,101.38) 25.92,101.96 25.92,102.4 25.66,102.65 24.55,102.65 23.58,103.62 23.58,104.61 25.51,106.53 27.06,106.53 27.86,105.74 30.63,105.74 30.87,105.97 30.87,107.1 30.63,107.33 30.31,107.33 30.07,107.57 30.07,110.54 v1(30.47,110.93)
EXP_GPIO0_32: length 17.1
  BOTTOM w0.132: RA4.5 39.72,119.57 40.57,120.42 40.57,121.04 40.19,121.42 40.19,123.55 40.74,124.1 44.75,124.1 44.98,124.33 44.98,124.56 45.86,125.43 45.86,129.67 J3.30
EXP_GPIO0_33: length 34.3
  TOP w0.132: U12.K21 34.87,113.29 35.11,113.53 35.11,114.85 36.49,116.23 36.49,120.01 35.87,120.63 35.87,125.64 35.26,126.25 35.26,127.24 35.7,127.67 35.7,131.12 36.67,132.09 45.29,132.09 46.26,131.12 46.26,129.27 J3.31
EXP_GPIO0_36: length 24.9
  TOP w0.127: U12.K18 v1(34.47,110.93)
  BOTTOM w0.132: v1(34.47,110.93) 34.87,111.33 34.87,115.29 36.9,117.32 36.9,122.09 37.45,122.64 39.78,122.64 39.91,122.77 39.91,123.67 39.91,123.73 40.6,124.42 43.11,124.42 43.7,125 43.7,127.11 J3.29
EXP_GPIO0_38: length 59.5
  TOP w0.127: U12.P17 v1(38.47,110.13)
  L06_SIG2 w0.107: v1(38.47,110.13) 38.47,110.39 38.85,110.78 38.85,112.7 38.46,113.09 35.85,113.09 31.9,117.04 31.9,118.13 30.54,119.49 30.54,119.92 30.68,120.06 30.68,120.47 30.4,120.75 30.17,120.75 30.08,120.66 26.62,120.66 26.39,120.43 26.39,118.63 24.97,117.22 23.34,117.22 22.98,117.58 20.95,117.58 20.72,117.82 16.56,117.82 16.19,118.19 16.19,123.1 15.45,123.84 15.45,126.22 16.38,127.15 25.81,127.15 26.29,126.66 27.74,126.66 28.06,126.99 28.06,129.69 J3.16
EXP_GPIO0_39: length 22.5
  TOP w0.127: U12.J20 34.47,112.53
  TOP w0.132: 34.47,112.53 34.47,113.27 34.87,113.67 34.87,114.95 35.66,115.74 35.66,117.96 35.08,118.54 35.08,124.82 34.16,125.74 32.9,125.74 30.82,127.82 30.82,129.47 J3.18
EXP_GPIO0_40/PR0_ECAP0_IN_APWM_: length 37.9
  TOP w0.127: U12.J19 v1(33.67,111.73)
  TOP w0.132: v1(36.06,117.21) 36.06,117.99 35.48,118.58 35.48,120.56 35.52,120.6 35.52,125.59 33.39,127.72 33.39,131.33 35.16,133.1 39.58,133.1 40.31,132.37 45.7,132.37 J3.32
  BOTTOM w0.127: v1(36.06,117.21) 36.06,116.89 34.62,115.44 34.62,112.68 v1(33.67,111.73)
EXP_GPIO0_41: length 76.1
  TOP w0.127: U12.J18 v1(33.67,110.93)
  L03_SIG1 w0.107: v1(33.67,110.93) 33.24,111.36 31.84,111.36 31.68,111.52 31.68,111.9 29.3,114.29 29.3,115.25 27.92,116.63 25.15,116.63 25.04,116.51 24.79,116.51 23.33,115.05 17.35,115.05 16.5,115.9 16.5,117.01 16.1,117.41 16.1,120.83 16.23,120.96 16.23,121.62 15,122.85 14.43,122.85 14.18,123.1 14.18,124.52 14.98,125.32 23.54,125.32 23.83,125.03 26.95,125.03 28.8,123.19 39.04,123.19 39.54,123.69 39.54,123.97 40.48,124.91 42.67,124.91 43.67,125.92 52.66,125.92 J3.37
EXP_GPIO0_42: length 48.2
  TOP w0.127: U12.H17 v1(32.87,110.13)
  L06_SIG2 w0.107: J3.13 23.2,129.47 16.32,129.47 15.58,128.73 15.58,127.64 14.54,126.6 14.54,125.84 13.35,124.65 13.35,120.65 13.67,120.33 13.67,116.58 19.39,110.86 19.39,110.13 20.57,108.95 23.93,108.95 24.37,109.39 25.47,109.39 25.83,109.75 29.83,109.75 30.05,109.98 30.05,110.26 30.31,110.52 30.63,110.52 30.85,110.29 30.85,110.01 31.11,109.75 31.43,109.75 31.68,110.01 31.68,110.29 31.91,110.52 32.49,110.52 v1(32.87,110.13)
EXP_GPIO1_22: length 54.5
  TOP w0.132: v1(23.42,106.14) 23.42,106.71 24.29,107.58 27.39,107.58 27.52,107.71 28.1,107.71 U12.B14
  L06_SIG2 w0.107: J3.15 25.54,129.68 24.04,129.68 23.12,130.59 23.12,131.04 22.36,131.81 18.62,131.81 18.42,132.01 16.32,132.01 15.58,131.27 15.58,130.52 14.74,129.69 14,129.69 13.03,128.72 13.03,127.68 12.2,126.85 11.49,126.85 10.88,126.23 10.88,124.44 11.24,124.07 11.24,120.34 11.08,120.18 11.08,115.96 20.22,106.82 22.55,106.82 22.83,106.53 23.02,106.53 v1(23.42,106.14)
EXP_HAT_DETECT: length 104.1
  TOP w0.127: R173.1 51.75,45.17 v1(51.88,45.3)
  L06_SIG2 w0.107: J3.39 57.49,125.89 57.17,125.58 57.17,125.42 56.63,124.87 55.89,124.87 55.09,124.07 55.09,123.36 54.74,123.01 54.74,120.29 54.9,120.12 54.9,118.76 54.74,118.59 54.74,118.11 53.9,117.27 53.9,113.28 58.9,108.28 60.09,108.28 62.38,106 62.77,106 62.99,105.77 62.99,105.38 65.86,102.51 65.86,91.28 67.23,89.91 67.23,88.5 68.59,87.14 68.59,58.53 v1(63.23,53.17)
  BOTTOM w0.127: v1(51.88,45.3) 51.95,45.22 U70.8
  BOTTOM w0.132: v1(51.88,45.3) 51.88,48.04 54.54,50.71 55.56,50.71 57.62,52.76 62.82,52.76 v1(63.23,53.17)
EXP_I2C2_NINT0: length 2
  TOP w0.132: R6.2 43.99,145.94 43.58,145.53 U4.4
EXP_I2C2_SCL: length 65.3
  TOP w0.127: J3.5 12.63,126.53 7.56,126.53 R33.2
  TOP w0.132: J3.5 12.91,129.61 8.85,129.61 6.38,132.07 6.38,135.31 6,135.69 6,139.91 6.84,140.75 12.66,140.75 12.83,140.58 38.91,140.58 41.01,142.69 42.13,142.69 42.43,142.99 42.43,143.21 42.28,143.36 U4.6
EXP_I2C2_SDA: length 64.9
  TOP w0.127: J3.3 10.4,126.83 R31.2
  TOP w0.132: U4.5 42.93,145.4 42.78,145.55 40.13,145.55 38.59,147.09 34.75,147.09 32.44,144.78 32.44,141.2 32.1,140.86 12.94,140.86 12.78,141.03 6.69,141.03 5.72,140.06 5.72,135.57 6.1,135.19 6.1,131.96 8.75,129.31 10.66,129.31 J3.3
EXP_PS_3V3_EN: length 177.5
  TOP w0.132: v1(49.74,44.17) 49.74,48.04 55.19,53.49 61.03,53.49 70.01,62.47 77.02,62.47 80.27,65.72 80.27,66.86 80.27,79.37 72.52,87.12 72.52,90.2 73.26,90.93 73.26,102.05 71.3,104.01 71.3,111.55 73.38,113.63 73.38,124.36 71.68,126.06 71.68,132.74 70.65,133.77 42.57,133.77 41.56,134.77 35.99,134.77 33.07,137.69 21.59,137.69 21.11,137.21 21.11,135.2 20.28,134.38 v1(17.52,134.38)
  BOTTOM w0.127: v1(17.52,134.38) 17.72,134.38 R293.2 18.97,134.05 U46.B2 ; U70.6 50.31,43.61 v1(49.74,44.17)
EXP_PS_5V0_EN: length 191.1
  L06_SIG2 w0.107: v1(7.25,138.36) 7.25,138.95 12.7,144.4 31.75,144.4 32.46,143.69 32.46,139.95 33.22,139.19 38.41,139.19 41.14,141.92 60.9,141.92 62.97,139.85 62.97,137.84 59.84,134.72 56.97,134.72 53.82,131.57 53.82,123.57 52.32,122.07 52.32,117.25 52.68,116.89 52.68,112.81 59.11,106.38 60.45,106.38 62.33,104.5 62.33,101.56 61.9,101.13 61.9,99.77 61.52,99.39 61.52,91.87 61.13,91.48 61.13,90.23 61.44,89.92 64.09,89.92 64.53,89.48 66.51,89.48 66.88,89.1 66.88,88.43 68.34,86.97 68.34,59.29 v1(62.21,53.17)
  BOTTOM w0.127: U45.C2 7.2,137.44 7.29,137.53 R290.2
  BOTTOM w0.132: R290.2 7.64,137.97 v1(7.25,138.36) ; v1(62.21,53.17) 57.63,53.17 55.44,50.99 54.19,50.99 51.19,47.99 51.19,44.31 51.39,44.11 U70.7
EXP_SPI0_CLK: length 24.2
  L03_SIG1 w0.107: J3.23 38.41,129.45 38.41,131.53 38.87,131.99 42.68,131.99 44.66,133.97 44.66,134.98 46.64,136.97 48.22,136.97 49.56,135.62 52.03,135.62 v1(52.51,135.14)
  BOTTOM w0.132: v1(52.51,135.14) 53,135.62 U43.2
EXP_SPI0_CS0: length 28.3
  L06_SIG2 w0.107: J3.24 40.62,134.2 46.8,134.2 48.22,135.62 55.76,135.62 58.12,137.98 v1(58.79,137.98)
  BOTTOM w0.127: R299.2 J3.24
  BOTTOM w0.132: v1(58.79,137.98) 59.18,137.98 59.42,138.22 U43.11
EXP_SPI0_CS1: length 87
  TOP w0.127: U12.D13 v1(29.67,106.93)
  L06_SIG2 w0.107: v1(29.67,106.93) 30.05,106.55 30.05,105.23 29.78,104.96 26.03,104.96 26.01,104.98 26,104.98 25.87,105.12 25.37,105.12 25.22,104.96 21.93,104.96 20.96,103.99 17.05,103.99 16.79,104.25 15.2,104.25 13.75,105.7 12.96,105.7 8.04,110.63 8.04,111.47 6.03,113.48 6.03,125.74 7.93,127.64 7.93,131.09 9.67,132.83 10.83,132.83 13.66,135.65 18.38,135.65 19.18,134.85 21.01,134.85 21.91,133.95 33.48,133.95 v1(33.82,133.61)
  BOTTOM w0.127: J3.26 R298.2
  BOTTOM w0.132: v1(33.82,133.61) 39.12,133.61 39.71,133.02 R298.2
EXP_SPI0_D0: length 31.9
  L06_SIG2 w0.107: J3.19 33.16,127.14 35.49,127.14 35.8,127.44 35.8,131.81 38.44,134.45 44.08,134.45 45.52,135.9 53.43,135.9 54.06,136.53 54.06,137.18 53.52,137.73 v1(53.45,137.73)
  BOTTOM w0.132: v1(53.45,137.73) 53.61,137.57 U43.5
EXP_SPI0_D1: length 67.5
  TOP w0.132: v1(22.54,106.26) 23.07,105.72 23.68,105.72 23.82,105.86 23.82,106.64 24.51,107.34 U12.A14
  L06_SIG2 w0.107: J3.21 33.28,129.55 33.28,131.04 32.26,132.06 18.66,132.06 18.5,132.22 14.29,132.22 13.24,131.17 13.24,130.13 12.82,129.71 12.82,127.77 12.16,127.11 11.39,127.11 10.28,126 10.28,121.66 9.41,120.78 9.41,112.09 13.31,108.19 18.45,108.19 20.08,106.56 22.23,106.56 v1(22.54,106.26)
EXP_SPI2_CLK: length 28
  BOTTOM w0.127: U42.5 78.86,141.88
  BOTTOM w0.132: J3.40 59.98,133.24 65.24,133.24 66.74,134.73 68.91,134.73 76.56,142.38 78.36,142.38 78.86,141.88
EXP_SPI2_CS0/EHRPWM0_A: length 75.7
  L03_SIG1 w0.107: J3.12 21.93,132.39 22.59,133.05 29.6,133.05 30.61,134.06 30.61,142.06 32.57,144.02 32.57,145.83 34.92,148.18 v1(38.53,148.18)
  L06_SIG2 w0.107: v1(77.32,141.5) 77.22,141.5 76.6,142.12 63.62,142.12 60.55,145.19 49.76,145.19 48.41,146.53 40.18,146.53 v1(38.53,148.18)
  BOTTOM w0.127: R294.2 J3.12
  BOTTOM w0.132: v1(77.32,141.5) 77.17,141.5 76.91,141.24 U42.2
EXP_SPI2_CS1: length 45
  TOP w0.127: U12.C17 v1(29.67,110.13)
  L06_SIG2 w0.107: v1(29.67,110.13) 29.29,110.52 28.53,110.52 28.16,110.15 22.86,110.15 22.47,109.77 21.95,109.77 21.42,110.29 20.09,110.29 19.64,110.74 19.64,112.76 16.29,116.11 16.29,116.42 15.39,117.32 15.01,117.32 14.12,118.21 14.12,120.41 13.76,120.77 13.76,124.63 14.79,125.66 14.79,126.49 15.79,127.49 15.79,128.64 16.41,129.26 20.87,129.26 J3.11
  BOTTOM w0.127: J3.11 20.81,129.32 20.81,131.23 21.16,131.58 R295.2
EXP_SPI2_CS2: length 76.8
  TOP w0.127: U12.A18 v1(27.27,110.93)
  L03_SIG1 w0.107: J3.36 51.14,129.47 49.63,129.47 48.59,128.44 48.59,127.76 48.82,127.53 48.82,127.03 48.39,126.6 43.68,126.6 42.45,125.37 40.16,125.37 39.09,124.3 39.09,123.87 38.86,123.64 29.14,123.64 25.9,126.88 15.31,126.88 13.57,125.14 13.57,121.89 14.27,121.19 15.14,121.19 15.37,120.96 15.37,114.95 16.52,113.8 23.76,113.8 25.08,112.48 27.09,112.48 27.44,112.12 28.99,112.12 29.23,111.88 29.23,111.59 29.02,111.38 28.7,111.38 28.56,111.51 27.85,111.51 27.27,110.94 v1(27.27,110.93)
  BOTTOM w0.127: J3.36 R297.2
EXP_SPI2_D0: length 32
  BOTTOM w0.127: 79.05,136.91 79.51,136.46 U42.11
  BOTTOM w0.132: 79.05,136.91 75.7,136.91 75.37,136.59 75.37,134.43 75.14,134.2 66.71,134.2 65.4,132.88 60.13,132.88 58.76,131.52 58.76,130.46 57.88,129.58 56.11,129.58 J3.38
EXP_SPI2_D1/ECAP2_IN_APWM_OUT: length 35.6
  BOTTOM w0.132: U42.14 77.56,131.46 77.27,131.17 75.33,131.17 75.04,131.45 75.04,133 74.58,133.46 66.87,133.46 65.73,132.32 60.36,132.32 59.23,131.19 59.23,127.81 58.28,126.86 53.75,126.86 J3.35
EXP_UART5_RXD: length 43.8
  TOP w0.127: U12.B13 v1(28.07,106.93)
  L06_SIG2 w0.107: J3.10 18.33,131.8 16.41,131.8 15.79,131.18 15.79,130.44 14.83,129.48 14.09,129.48 13.24,128.63 13.24,127.53 12.31,126.6 11.6,126.6 11.13,126.13 11.13,124.54 12.06,123.61 12.06,119.68 11.72,119.34 11.72,115.68 20.31,107.09 22.63,107.09 22.94,106.79 23.46,106.79 23.61,106.93 v1(28.07,106.93)
EXP_UART5_TXD: length 38.8
  TOP w0.132: U12.A15 v1(27.19,108.13)
  L06_SIG2 w0.107: J3.8 15.37,129.27 15.37,127.79 15.36,127.78 15.36,127.77 14.79,127.19 14.77,127.19 14.64,127.05 13.12,127.05 12.41,126.34 11.71,126.34 11.39,126.02 11.39,124.65 12.39,123.64 12.39,120.19 12.74,119.84 12.74,119.23 12.43,118.92 12.43,115.33 20.41,107.35 22.74,107.35 23.04,107.04 23.36,107.04 23.59,107.27 26.32,107.27 v1(27.19,108.13)
EXT_CLKOUT0: length 72.2
  TOP w0.102: v1(53.78,140.01) 53.8,139.99 54.29,139.99 R12.1
  TOP w0.132: v1(22.24,110.2) 22.24,110.19 R53.1
  L03_SIG1 w0.107: v1(22.24,110.2) 22.67,110.63 25.08,110.63 25.97,109.73 33.87,109.73 35.39,108.21 35.39,107.84 35.87,107.35 39.71,107.35 40.49,108.13 43.74,108.13 44.2,108.59 46.28,108.59 47.96,110.26 55.09,110.26 58.04,113.21 58.04,121.21 57.45,121.79 57.45,124.51 57.15,124.82 57.15,125.99 58.59,127.43 58.59,136.98 56.25,139.33 54.47,139.33 v1(53.78,140.01)
EXT_CLKOUT0_R: length 14
  TOP w0.127: U12.C14 v1(28.87,107.73)
  TOP w0.132: v1(23.2,107.43) 23,107.63 23,108.37 22.41,108.95 22.41,109.64 22.77,109.99 22.77,110.68 22.44,111.01 21.4,111.01 21.12,110.73 R52.2
  L06_SIG2 w0.107: v1(23.2,107.43) 23.3,107.53 26.04,107.53 27.03,108.52 27.35,108.52 27.7,108.52 28.49,107.73 v1(28.87,107.73)
  BOTTOM w0.132: 28.1,107.71 28.84,107.71 v1(28.87,107.73)
EXTINTN: length 52.4
  TOP w0.127: v1(8.08,80.17) 8.54,80.17 R126.1
  TOP w0.132: U12.B16 28.04,109.36 27.16,109.36 26.79,109.73 25.61,109.73 25.24,109.36 v1(23.78,109.36) 24.02,109.12 R55.2
  BOTTOM w0.132: v1(8.08,80.17) 7.69,80.57 7.69,80.77 7.69,82.36 8.08,82.75 8.08,87.5 10.02,89.44 10.02,91.93 11.97,93.89 13.75,93.89 15.28,92.36 16.06,92.36 16.58,92.88 16.58,96.49 14.33,98.75 14.33,100.69 16.38,102.74 16.38,106.27 17.81,107.7 18.52,107.7 20.18,109.36 20.18,109.71 20.48,110.02 21.86,110.02 22.08,109.8 22.41,109.8 22.56,109.96 23.18,109.96 v1(23.78,109.36)
FT4232_DO: length 2.7
  BOTTOM w0.127: R499.1 R506.2 13.46,23.12 13.46,23.11 13.26,22.91 U86.4
FT4232_EECLK: length 11.5
  TOP w0.127: v1(11.96,22.97) 13.27,21.66 19.66,21.66 19.82,21.5 U37.62
  BOTTOM w0.127: U86.2 v1(11.96,22.97) R500.1
FT4232_EECS: length 12.9
  TOP w0.127: v1(10.66,23.53) 12.82,21.36 19.17,21.36 19.32,21.22 U37.63
  BOTTOM w0.127: U86.1 11.31,22.87 11.2,22.98 R501.1 v1(10.66,23.53)
FT4232_EEDATA: length 12.1
  TOP w0.127: v1(12.9,24.07) 15.02,21.95 19.78,21.95 20.32,21.42 U37.61
  BOTTOM w0.127: U86.3 12.61,22.83 12.9,23.12 R506.1 v1(12.9,24.07)
FT4232_MCU_UART0_CTS_3V3: length 9.2
  TOP w0.127: v1(28.89,18.84) 28.89,20.17 26.95,22.11 24.98,22.11 24.32,21.45 U37.53
  BOTTOM w0.127: U83.12 29.21,19.16 v1(28.89,18.84)
FT4232_MCU_UART0_RTS_3V3: length 7.3
  TOP w0.127: U37.54 23.82,19.11 24.56,18.36 26.62,18.36 27,18.74 27,19.38 v1(27.6,19.99)
  BOTTOM w0.127: U83.14 27.85,20.23 v1(27.6,19.99)
FT4232_MCU_UART0_RX_3V3: length 3.7
  TOP w0.127: U37.48 27.42,18.21 27.28,18.36 27.28,19.02 27.42,19.16 v1(27.99,19.16)
  BOTTOM w0.127: U83.13 28.17,19.83 27.99,19.66 v1(27.99,19.16)
FT4232_MCU_UART0_TX_3V3: length 5.8
  TOP w0.127: v1(27.6,20.9) 26.67,21.83 25.14,21.83 24.82,21.51 U37.52
  BOTTOM w0.127: U83.15 27.87,20.63 v1(27.6,20.9)
FT4232_REF: length 1.9
  TOP w0.127: U37.6 v1(18.01,15.71)
  BOTTOM w0.127: R548.2 17.78,15.94 v1(18.01,15.71)
FT4232_RESET: length 3.2
  TOP w0.127: U37.14 15.98,11.71 15.71,11.44 15.56,11.44 C167.2 R251.1
FT4232_SOC_UART0_RX_3V3: length 9.3
  TOP w0.147: U37.16 v1(15.69,10.71)
  BOTTOM w0.127: v1(15.69,10.71) 16.69,9.71 21.32,9.71 21.58,9.97 21.58,10.55 21.11,11.02 U92.13
FT4232_SOC_UART0_TX_3V3: length 3.6
  TOP w0.127: U37.17 18.82,9.95 19.41,10.54 v1(19.91,10.54)
  BOTTOM w0.127: U92.15 20.31,10.94 v1(19.91,10.54)
FT4232_SOC_UART1_CTS_3V3: length 7
  TOP w0.127: v1(24.06,7.59) 24.32,7.85 U37.28
  BOTTOM w0.127: v1(24.06,7.59) 24.06,7.08 24.4,6.74 28.27,6.74 28.52,6.99 U96.12
FT4232_SOC_UART1_RTS_3V3: length 5.3
  TOP w0.127: v1(25.06,10.04) 24.82,9.79 U37.29
  BOTTOM w0.127: U96.14 26.54,8.06 25.06,9.55 v1(25.06,10.04)
FT4232_SOC_UART1_RX_3V3: length 6.6
  TOP w0.127: v1(23.08,7.59) 23.32,7.83 U37.26
  BOTTOM w0.127: v1(23.08,7.59) 23.73,8.24 25.41,8.24 25.98,7.66 U96.13
FT4232_SOC_UART1_TX_3V3: length 6.6
  TOP w0.127: v1(24.08,10.04) 23.82,9.78 U37.27
  BOTTOM w0.127: U96.15 27.02,8.46 26.48,9 26.48,9.45 25.36,10.56 24.61,10.56 v1(24.08,10.04)
FT4232_USB_DM: length 14.4
  TOP w0.11: 8.07,16.82 U35.5 ; 8.07,16.82 8.23,16.66 9.64,16.66 9.93,16.37 9.93,14.69 10.25,14.38 13.87,14.38 14.58,15.08 15.79,15.08 15.92,15.21 U37.7 ; 8.07,16.82 7.9,16.66 7.62,16.66 7.08,17.2 6.7,17.2 6.5,17.4 J17.2
FT4232_USB_DP: length 14.3
  TOP w0.11: U37.8 15.92,14.71 15.79,14.84 14.68,14.84 13.97,14.14 10.15,14.14 9.69,14.59 9.69,16.27 9.58,16.38 9.19,16.38 9.07,16.26 ; 9.07,16.26 8.9,16.42 7.52,16.42 6.98,16.96 6.7,16.96 6.5,16.75 J17.3 ; 9.07,16.26 U35.3
FT4232_USB_VBUS: length 3
  TOP w0.254: U35.1 v1(8.07,15.17)
  BOTTOM w0.254: 8.24,10.73 8.24,9.87 8.67,9.44 U94.4
  vias: v1(7.23,18.42) v1(8.15,18.42) v1(9.06,18.42)
FT4232_WKUP_UART0_CTS_3V3: length 2.3
  TOP w0.127: v1(26.88,13.95) 27.12,14.19 27.19,14.19 27.22,14.21 U37.40
  BOTTOM w0.127: v1(26.88,13.95) 26.45,14.37 U91.12
FT4232_WKUP_UART0_RTS_3V3: length 4.1
  TOP w0.127: U37.41 27.35,14.71 27.11,14.46 25.74,14.46 v1(25.46,14.74)
  BOTTOM w0.127: U91.14 25.64,14.57 v1(25.46,14.74)
FT4232_WKUP_UART0_RX_3V3: length 2.9
  TOP w0.127: v1(26.28,13.04) 27.07,13.04 27.24,13.21 U37.38
  BOTTOM w0.127: U91.13 26.04,13.28 v1(26.28,13.04)
FT4232_WKUP_UART0_TX_3V3: length 4
  TOP w0.127: v1(25.24,13.04) 25.68,13.47 27.06,13.47 27.3,13.71 U37.39
  BOTTOM w0.127: U91.15 v1(25.24,13.04)
FT_PWREN#: length 1.8
  TOP w0.127: U37.60 R243.1
GPIO1_23_INTN: length 191.9
  TOP w0.127: U12.C13 v1(28.87,106.93)
  TOP w0.132: v1(37.24,24.46) 33.15,24.46 32.51,23.82 32.51,16.6 31.45,15.54 31.45,10.79 30.9,10.24 26.55,10.24 26.24,10.55 23.72,10.55 23.15,11.11 v1(23.15,12.71)
  L03_SIG1 w0.107: v1(23.15,12.71) 22.72,12.28 19.68,12.28 18.38,13.57 18,13.57 16.94,14.64 16.94,32.6 16.15,33.39 16.15,39.17 14.29,41.02 14.29,41.04 14.29,41.05 14.29,46.93 10.93,50.28 10.93,50.84 10.29,51.49 10.29,55.62 10.52,55.85 10.52,56.51 7.97,59.06 7.97,77.69 8.52,78.24 8.52,81.18 8.73,81.39 8.73,82.2 7.27,83.66 7.27,87.36 7.92,88.01 7.92,89.66 11.09,92.82 12.74,92.82 14.64,94.72 14.64,97.7 12.01,100.33 12.01,104.19 13.38,105.56 14.41,105.56 17.29,108.44 19.24,108.44 19.4,108.6 23.91,108.6 24.66,107.85 26.91,107.85 27.47,107.29 28.22,107.29 28.58,106.93 v1(28.87,106.93)
  BOTTOM w0.127: v1(37.24,24.46) 37.55,24.14 R505.2
  BOTTOM w0.132: R467.1 49.98,39.56 49.63,39.91 46.47,39.91 45.12,38.57 45.12,36.83 43.9,35.61 33.5,35.61 32.49,34.59 32.49,27.05 33.36,26.17 36.45,26.17 37.24,25.39 v1(37.24,24.46)
GPIO_AUD_RSTN: length 14.7
  TOP w0.127: v1(52.38,46.21) 51.98,46.61 51.98,47.61 52.42,48.05 57.33,48.05 59.85,45.54 v1(60.21,45.54)
  BOTTOM w0.127: v1(52.38,46.21) 52.7,45.9 U70.9 ; v1(60.21,45.54) R451.1 R456.2 U71.1
GPIO_CPSW1_RST: length 17
  TOP w0.127: 56.85,40.55 57.59,39.81 59.75,39.81 60.59,40.66 60.59,42.75 61.28,43.44 R176.1 R177.1 62.68,43.44 62.87,43.25 U31.1
  TOP w0.132: 56.85,40.55 51.87,40.55 v1(50.96,41.46)
  BOTTOM w0.127: U70.2 51.11,41.61 v1(50.96,41.46)
GPIO_CPSW2_RST: length 78.1
  L03_SIG1 w0.107: v1(50.9,40.31) 51.48,40.89 51.48,61.26 v1(52.18,61.96)
  BOTTOM w0.127: U70.1 51.27,41.11 50.9,40.74 v1(50.9,40.31)
  BOTTOM w0.132: R658.1 R659.1 58.96,106.63 59.05,106.53 U128.1 57.27,106.19 53.09,102.01 53.09,93.45 51.61,91.97 51.61,87.86 55.27,84.2 55.27,78.26 56.83,76.69 56.83,66.61 v1(52.18,61.96)
GPIO_EMMC_RSTN: length 28.5
  TOP w0.132: U25.1 R141.1 v1(48.16,67.35)
  L03_SIG1 w0.107: v1(48.16,67.35) 49.21,66.3 50.57,66.3 54.59,62.28 54.59,57.31 52.38,55.11 v1(52.38,47.13)
  BOTTOM w0.127: v1(52.38,47.13) 53.2,46.31 U70.10
GPIO_HDMI_RSTN: length 120.3
  L03_SIG1 w0.107: v1(70,129.06) 70,127.37 66.7,124.06 66.7,121.01 65.93,120.25 65.93,108.01 64.55,106.62 64.55,105.8 63.83,105.08 61.09,105.08 57.26,101.25 57.26,98.59 55.87,97.19 55.87,90.67 64.47,82.07 65.55,82.07 67.72,79.9 67.72,75.53 65.54,73.36 65.54,54.62 66.51,53.65 66.51,47.36 65.42,46.27 58.77,46.27 58.2,46.84 58.2,49.18 57.49,49.89 55.79,49.89 55.11,49.21 v1(55.11,47.06)
  BOTTOM w0.127: v1(70,129.06) 70,129.34 69.79,129.55 68.21,129.55 67.83,129.93 R301.1 68.17,130.56 68.2,130.59 R300.2 68.98,130.59 69.01,130.62 U47.1
  BOTTOM w0.132: U70.13 54.7,46.65 v1(55.11,47.06)
GPIO_MCU: length 1.3
  BOTTOM w0.127: U81.5 38.49,23.15 R505.1
GPIO_OLDI_RSTN: length 178.3
  TOP w0.132: U3.19 53.31,143.84 v1(53.78,143.37)
  L03_SIG1 w0.107: v1(53.78,72.2) 54.34,71.64 54.34,68.34 60.3,62.38 63.07,62.38 64.34,63.65 64.34,68.73 65.25,69.65 65.25,73.48 67.44,75.67 67.44,79.78 65.41,81.81 64.41,81.81 64.38,81.84 64.37,81.84 55.64,90.57 55.64,90.58 55.05,91.18 55.05,97.55 54.85,97.75 54.85,101.23 56.83,103.21 58.89,103.21 61.04,105.36 61.77,105.36 62.59,106.18 62.85,106.18 64.82,108.15 64.82,108.36 65.71,109.25 65.71,120.35 66.47,121.11 66.47,124.16 69.6,127.28 69.6,129.62 73.41,133.43 73.41,135.51 74.05,136.15 74.05,142.86 71.85,145.06 62.08,145.06 57.09,140.07 55.06,140.07 53.85,141.28 52.16,141.28 49.46,138.59 43.92,138.59 40.9,141.61 40.9,145.73 43.06,147.89 48.27,147.89 52.38,143.77 53.38,143.77 v1(53.78,143.37)
  BOTTOM w0.132: U62.1 52.96,72.2 v1(53.78,72.2) 53.78,73.06 53.27,73.57 R407.1
GPIO_OSPI_RSTN: length 16.7
  TOP w0.127: U12.F17 v1(31.27,110.13)
  TOP w0.132: U8.1 32.24,123.09 31.04,121.88 31.04,120.47 30.57,120 30.57,117.7 30.87,117.4 v1(30.87,117)
  L06_SIG2 w0.107: v1(30.87,117) 30.87,116.47 31.73,115.6 31.73,114.79 30.87,113.93 30.87,110.7 31.27,110.3 v1(31.27,110.13)
  BOTTOM w0.132: v1(30.87,117) 30.85,117.03 30.46,117.03 30.37,117.12 R332.1
HDMI_AUDD1: length 3.9
  TOP w0.132: TP16.1 12.68,120.6 13.02,120.93 13.02,122.98 13.12,123.08 U11.40
HDMI_AUDD2: length 11.2
  TOP w0.132: U11.39 14.33,123.58 14.5,123.75 14.94,123.75 v1(15.41,123.28)
  BOTTOM w0.132: TP15.1 10.97,126.05 11.75,126.84 13.96,126.84 14.14,126.66 14.14,123.15 14.43,122.85 14.99,122.85 v1(15.41,123.28)
HDMI_AUDD3: length 1.9
  TOP w0.127: U11.37 13.71,125.23 13.3,125.64 ; 13.17,125.77 13.16,125.78
  TOP w0.132: 13.3,125.64 13.17,125.77 TP14.1
HDMI_CEC: length 24.7
  TOP w0.132: U11.71 22.41,113.77 20.38,111.74 19.9,111.74 19.31,111.16 19.31,109.58 18.96,109.23 17.76,109.23 17.32,109.68 16.41,109.68 16.15,109.42 9.4,109.42 8.41,110.4 v1(4.53,110.4)
  BOTTOM w0.132: U50.1 4.22,110.71 v1(4.53,110.4)
HDMI_CEC_D: length 4.1
  TOP w0.132: U11.50 14.39,118.08 14.44,118.13 v1(14.83,118.13)
  BOTTOM w0.132: v1(14.83,118.13) 12.63,118.13 12.38,118.38 TP17.1
HDMI_CLK+: length 18.5
  TOP w0.105: J5.10 9.68,115.74 9.78,115.84 9.78,115.97 9.89,116.08 10.37,116.08 v1(10.6,115.86) 11.41,115.86 11.7,116.15 11.7,117.37 11.34,117.72 10.54,117.72 10.34,117.92 10.34,118.07 10.54,118.27 11.49,118.27 12.11,117.65 12.11,115.52 13.37,114.27 15.95,114.27 16.34,114.67 16.34,115.31 U11.59
  BOTTOM w0.105: v1(10.6,115.86) 10.37,116.08 9.81,116.08 9.64,115.91 U50.16
HDMI_CLK-: length 18.5
  TOP w0.105: U11.58 15.92,115.38 16.02,115.27 16.02,114.8 15.81,114.59 13.5,114.59 12.43,115.65 12.43,117.78 11.62,118.59 10.41,118.59 10.03,118.2 10.03,117.79 10.41,117.41 11.21,117.41 11.38,117.24 11.38,116.28 11.27,116.17 11.09,116.17 10.98,116.28 10.98,116.64 10.87,116.75 10.73,116.75 v1(10.6,116.62) 10.37,116.4 9.89,116.4 9.78,116.5 9.78,116.63 9.68,116.74 J5.12
  BOTTOM w0.105: U50.15 9.64,116.56 9.81,116.4 10.37,116.4 v1(10.6,116.62)
HDMI_CONN_I2CSCL: length 6.8
  TOP w0.127: J5.15 7.41,118.24 v1(4.97,115.8)
  BOTTOM w0.127: v1(4.97,115.8) 4.43,115.26 U50.8
HDMI_CONN_I2CSDA: length 6.8
  TOP w0.127: J5.16 7.41,118.74 5.13,116.45 4.76,116.45 v1(4.11,115.8)
  BOTTOM w0.127: v1(4.11,115.8) 4,115.91 U50.9
HDMI_CONNCEC: length 6.6
  TOP w0.127: v1(4.11,114.82) 4.77,114.82 7.18,117.24 J5.13
  BOTTOM w0.127: v1(4.11,114.82) 3.9,114.61 U50.7
HDMI_EARTH: length 40
  TOP w0.508: FL6.2 3.41,107.33 J5.22
  TOP w1.016: J5.23 5.46,123.84 6.06,123.24 J5.21 ; J5.20 6.06,108.74 5.46,108.14 J5.22
  L03_SIG1 w0.508: J5.20 6.04,108.74 5.44,108.14 J5.22 1.03,109.71 1.03,122.26 J5.23 5.44,123.84 6.04,123.24 J5.21
HDMI_EXTSWING: length 1.6
  TOP w0.127: U11.56 14.91,116.05 14.9,116.06 14.9,116.07 v1(14.94,116.11)
  BOTTOM w0.127: v1(14.94,116.11) 14.66,115.83 R339.1
HDMI_HPD: length 16.2
  TOP w0.102: U11.54 13.71,115.69 13.57,115.55 13.29,115.55 13.2,115.65 v1(13.17,115.65)
  L03_SIG1 w0.107: v1(13.17,115.65) 11.15,117.66 7.56,117.66 6.45,116.56 6.45,114.07 5.42,113.04 v1(4.62,113.04)
  BOTTOM w0.132: U50.4 4.24,112.66 v1(4.62,113.04) ; v1(13.17,115.65) 13.17,115.68 12.98,115.87 R338.1
HDMI_I2C_SCL: length 19.7
  TOP w0.127: U11.49 13.04,118.58 v1(12.84,118.78)
  L03_SIG1 w0.107: v1(12.84,118.78) 12.84,119.62 12.63,119.82 12.2,119.82 10.49,118.11 7.32,118.11 6.01,116.8 6.01,116.61 6.01,114.34 5.46,113.8 4.44,113.8 3.97,113.33 3.97,111.79 v1(4.53,111.23)
  BOTTOM w0.127: v1(12.84,118.78) 12.86,118.75 13.04,118.75 13.08,118.79 R317.2
  BOTTOM w0.132: U50.2 3.09,111.23 v1(4.53,111.23)
HDMI_I2C_SDA: length 16.9
  TOP w0.127: 13.22,119.08 U11.48
  TOP w0.132: 13.22,119.08 13.01,119.28 13.01,119.29 12.91,119.39 v1(12.35,119.39)
  L03_SIG1 w0.107: v1(4.53,112.28) 4.2,112.61 4.2,113.19 4.58,113.57 5.55,113.57 6.23,114.25 6.23,116.71 7.41,117.89 10.85,117.89 v1(12.35,119.39)
  BOTTOM w0.127: R310.2 12.36,119.4 v1(12.35,119.39)
  BOTTOM w0.132: U50.3 2.96,112 4.25,112 v1(4.53,112.28)
HDMI_INTN: length 210.5
  TOP w0.132: v1(10.25,119.06) 10.27,119.08 ; 10.27,119.08 R41.2 ; 10.27,119.08 11.81,119.08 12.91,117.98 12.91,117.37 13.2,117.08 U11.52
  L03_SIG1 w0.107: v1(10.25,119.06) 9.52,118.34 7.23,118.34 5.75,116.86 5.75,115.65 5.42,115.32 3.87,115.32 3.49,114.94 3.49,110.52 4.02,109.99 5.12,109.99 5.62,110.5 10.09,110.5 10.57,110.03 10.57,109.38 7.34,106.15 7.34,103.02 5.19,100.87 5.19,93.79 3.63,92.23 3.63,90.73 v1(1.56,88.65)
  L06_SIG2 w0.107: v1(58.72,44.11) 58.3,43.7 58.3,40.78 57.82,40.29 57.82,38.59 57.13,37.91 57.13,30.11 58.95,28.3 58.95,25.5 54.42,20.97 54.42,19.69 52.69,17.96 51.41,17.96 50.14,19.23 41.93,19.23 40.41,17.7 39.86,17.7 39.64,17.93 39.64,19.44 39.08,20 37.94,20 37.81,20.13 35.95,20.13 35.32,19.49 35.32,15.15 34.33,14.16 28.41,14.16 27.01,15.55 25.31,15.55 17.33,23.53 17.33,29.94 13.28,33.99 9.42,33.99 8.62,34.79 8.62,41.05 7.14,42.53 5.73,42.53 4.97,43.29 4.97,53.48 6.23,54.75 6.23,66.3 5.29,67.24 2.58,67.24 1.15,68.66 1.15,85.05 2.83,86.72 2.83,88.27 2.45,88.65 v1(1.56,88.65)
  BOTTOM w0.127: U70.17 58.22,44.61 v1(58.72,44.11)
HDMI_MSTRCLK: length 33.6
  TOP w0.127: U11.38 13.15,124.08 12.99,124.24 12.99,124.75 12.28,125.46 12.18,125.46 v1(11.77,125.86)
  TOP w0.132: R34.2 11.32,125.73 11.45,125.86 v1(11.77,125.86)
  L06_SIG2 w0.107: v1(26.63,109.33) 25.77,109.33 24.84,108.4 24.44,108.4 24.22,108.63 23.53,108.63 23.39,108.49 20.49,108.49 19.01,109.97 19.01,110.73 13.29,116.46 13.29,120.04 12.81,120.52 12.81,125.17 12.11,125.86 v1(11.77,125.86)
  BOTTOM w0.132: v1(26.63,109.33) 27.09,109.33 27.64,109.89 R348.1
HDMI_PCLK: length 25.7
  TOP w0.127: U11.22 21.41,126.16 21.91,126.66 22.84,126.66 v1(23.08,126.42)
  L06_SIG2 w0.107: v1(40.42,118.37) 40.42,118.76 38.24,120.94 38.24,122.06 35.63,124.67 34.79,124.67 34.59,124.87 33.89,124.87 33.14,125.61 32.03,125.61 31.47,125.05 24.04,125.05 23.81,125.28 23.81,125.7 v1(23.08,126.42)
  BOTTOM w0.132: R329.2 40.76,118.37 v1(40.42,118.37)
HDMI_RSTN: length 75
  TOP w0.132: v1(70.71,132.94) 70.23,133.43 42.51,133.43 41.52,134.42 v1(29.84,134.42) ; v1(17.64,117) 15.2,117 14.62,117.58 U11.51
  BOTTOM w0.127: R296.2 72.98,132.69 72.97,132.7 72.79,132.52 U47.4
  BOTTOM w0.132: U47.4 71.14,132.52 v1(70.71,132.94) ; v1(29.84,134.42) 28.04,134.42 25.56,131.94 25.56,124.75 24.27,123.45 24.27,123 23.31,122.04 22.09,122.04 21.15,121.1 21.15,120.03 20.83,119.71 20.52,119.71 20.2,119.39 20.2,117 19.64,116.43 19.02,116.43 18.92,116.53 18.92,116.53 18.69,116.76 18.69,116.76 18.45,117 v1(17.64,117)
HDMI_TX0+: length 19.1
  TOP w0.105: U11.62 17.8,115.28 17.8,114.96 18.42,114.35 18.42,113.9 18.01,113.49 17.24,113.49 17.13,113.38 17.13,112.9 16.84,112.61 16.12,112.61 15.83,112.9 15.83,113.34 15.69,113.48 15.49,113.48 15.35,113.34 15.35,112.93 15.02,112.61 14.55,112.61 14.22,112.93 14.22,113.34 14.08,113.48 13.84,113.48 13.74,113.38 13.74,112.93 13.41,112.61 12.96,112.61 12.18,113.38 12.18,114.25 12.07,114.36 v1(11.1,114.36) 10.88,114.58 9.89,114.58 9.78,114.47 9.78,114.34 9.68,114.24 J5.7
  BOTTOM w0.105: U50.18 8.9,114.76 9.64,114.76 9.86,114.53 10.93,114.53 v1(11.1,114.36)
HDMI_TX0-: length 19.1
  TOP w0.105: U11.61 17.48,115.3 17.48,114.83 18.1,114.22 18.1,114.03 17.88,113.8 17.11,113.8 16.81,113.51 16.81,113.03 16.71,112.92 16.25,112.92 16.15,113.03 16.15,113.47 15.82,113.8 15.36,113.8 15.03,113.47 15.03,113.07 14.89,112.92 14.68,112.92 14.54,113.07 14.54,113.47 14.21,113.8 13.71,113.8 13.42,113.51 13.42,113.07 13.28,112.92 13.09,112.92 12.49,113.52 12.49,114.38 12.2,114.67 11.69,114.67 11.58,114.78 11.58,115.14 11.46,115.27 11.25,115.27 v1(11.1,115.12) 10.88,114.9 9.89,114.9 9.78,115 9.78,115.11 9.66,115.24 J5.9
  BOTTOM w0.105: U50.17 8.78,115.26 8.93,115.11 9.73,115.11 10,114.85 10.83,114.85 v1(11.1,115.12)
HDMI_TX1+: length 18.6
  TOP w0.105: U11.65 19.34,115.31 19.34,114.5 19.64,114.2 19.64,113.57 17.29,111.22 16.73,111.22 16.4,111.55 16.4,111.65 16.23,111.82 16.08,111.82 15.91,111.65 15.91,111.55 15.58,111.22 15.12,111.22 14.79,111.55 14.79,111.68 14.68,111.78 14.41,111.78 14.3,111.68 14.3,111.55 13.98,111.22 13.16,111.22 12.02,112.36 11.84,112.36 11.13,113.08 10.9,113.08 v1(10.67,112.86) 10.45,113.08 9.89,113.08 9.78,112.97 9.78,112.84 9.68,112.74 J5.4
  BOTTOM w0.105: v1(10.67,112.86) 10.46,113.07 9.99,113.07 9.73,112.81 8.93,112.81 8.78,112.66 U50.21
HDMI_TX1-: length 18.6
  TOP w0.105: U11.64 19.02,115.26 19.02,114.37 19.33,114.07 19.33,113.71 18.83,113.21 18.63,113.21 18.61,113.22 18.41,113.22 18.26,113.08 18.26,112.88 18.28,112.86 18.28,112.66 18.14,112.52 17.73,112.52 17.59,112.38 17.59,111.97 17.16,111.54 16.86,111.54 16.72,111.68 16.72,111.78 16.36,112.14 15.95,112.14 15.59,111.78 15.59,111.68 15.45,111.54 15.25,111.54 15.11,111.68 15.11,111.81 14.82,112.1 14.28,112.1 13.99,111.81 13.99,111.68 13.84,111.54 13.29,111.54 12.15,112.68 11.97,112.68 11.26,113.4 10.9,113.4 v1(10.67,113.62) 10.45,113.4 9.84,113.4 9.74,113.5 9.74,113.61 9.61,113.74 J5.6
  BOTTOM w0.105: U50.20 8.9,113.17 9.64,113.17 9.86,113.39 10.44,113.39 v1(10.67,113.62)
HDMI_TX2+: length 18.9
  TOP w0.105: J5.1 9.68,111.24 9.78,111.34 9.78,111.47 9.89,111.58 10.83,111.58 v1(11.05,111.36) 11.28,111.58 11.64,111.58 12.92,110.29 17.59,110.29 20.84,113.54 20.84,115.02 20.91,115.09 U11.68
  BOTTOM w0.105: v1(11.05,111.36) 10.88,111.53 9.81,111.53 9.64,111.36 U50.23
HDMI_TX2-: length 19
  TOP w0.105: U11.67 20.41,115.2 20.52,115.08 20.52,113.67 17.46,110.61 17.06,110.61 16.92,110.75 16.59,110.75 16.45,110.61 16.02,110.61 15.88,110.75 15.54,110.75 15.4,110.61 15.04,110.61 14.87,110.79 14.61,110.79 14.43,110.61 14.07,110.61 13.94,110.75 13.59,110.75 13.46,110.61 13.05,110.61 11.77,111.9 11.28,111.9 v1(11.05,112.12) 10.83,111.9 9.89,111.9 9.78,112 9.78,112.13 9.68,112.24 J5.3
  BOTTOM w0.105: v1(11.05,112.12) 10.78,111.85 9.81,111.85 9.64,112.01 U50.22
HDMICONN_HPD: length 8.3
  TOP w0.127: v1(4.11,116.67) 4.11,118.51 5.97,120.37 7.25,120.37 7.39,120.24 J5.19
  BOTTOM w0.127: v1(4.11,116.67) 4,116.56 U50.10
HFOSC0_CLKOUT_32K: length 102.4
  TOP w0.127: 28.07,106.13 U12.B12
  TOP w0.132: R2.1 v1(41,151.08) ; 28.07,106.13 27.13,106.13 26.73,106.53 25.46,106.53 24.29,105.37 22.93,105.37 22.57,105.72 21.7,105.72 20.1,104.13 20.1,102.88 19.69,102.47 18.09,102.47 17.42,101.8 16.91,101.8 16.63,102.08 14.96,102.08 13.5,100.62 v1(7.15,100.62)
  L03_SIG1 w0.107: v1(41,151.08) 41,150.34 39.9,149.25 37.44,149.25 36.9,148.71 34.76,148.71 32.28,146.23 32.28,144.14 30.32,142.18 30.32,134.18 29.69,133.55 22.12,133.55 20.9,132.33 14,132.33 13.07,131.4 13.07,127.26 12.72,126.91 12.72,120.74 13.6,119.86 13.6,115.51 13.45,115.35 13.45,113.02 10.86,110.43 10.86,109.26 7.62,106.03 7.62,101.1 v1(7.15,100.62)
HPLOUT: length 6.8
  TOP w0.254: v1(75.86,39.13) 75.21,38.48 J14.2
  BOTTOM w0.254: C408.2 v1(75.86,39.13)
HPLOUT_C: length 2.5
  BOTTOM w0.254: U66.18 74.66,42.23 C408.1
HPROUT: length 11.4
  TOP w0.254: J14.3 76.64,31.08 75.38,32.34 75.38,35.11 v1(72.92,37.56)
  BOTTOM w0.254: v1(72.92,37.56) 72.27,38.22 C409.2
HPROUT_C: length 2.5
  BOTTOM w0.254: U66.23 72.16,43.03 72.27,42.93 C409.1
INA_ALERT: length 87.7
  TOP w0.127: v1(4.96,91.55) 4.96,91.81 R95.2 ; R85.2 11.78,94.85 R86.1 11.78,94.4 11.78,94.4 TP31.1
  TOP w0.132: TP31.1 11.43,93.66 v1(10.53,93.66) ; v1(2.19,70.21) 2.19,68.29 3.21,67.27 21.36,67.27 22.96,68.87 23.4,68.87 24.37,69.84 v1(24.37,72.88)
  L06_SIG2 w0.107: v1(16.19,84.11) 15.73,84.56 15.73,90.48 13.45,92.77 11.41,92.77 v1(10.53,93.66) 9.64,92.77 6.18,92.77 v1(4.96,91.55)
  BOTTOM w0.127: v1(2.19,70.21) 2.27,70.21 2.44,70.04 R414.2 ; R409.2 v1(24.37,72.88) ; R397.2 29.34,80.27
  BOTTOM w0.132: 29.34,80.27 29.34,80.62 28.29,81.67 24.47,81.67 23.91,81.11 16.96,81.11 16.71,81.36 15.5,81.36 15.23,81.63 15.23,81.94 14.5,82.67 14.5,83.51 15.02,84.03 R392.2 16.11,84.03 v1(16.19,84.11) ; R397.2 29.34,77.18 29.93,76.59 30.79,76.59 31.3,76.08 31.3,74.25 30.54,73.49 28.1,73.49 27.49,72.88 25.41,72.88 25.41,72.88 v1(24.37,72.88)
IO_EXP1_INTN: length 2.5
  TOP w0.132: R3.1 57.45,150.01 57.35,149.91 57.35,149.51 57.14,149.3 U3.32
IO_EXP_ADDR: length 1.1
  BOTTOM w0.127: U74.26 46.63,27.24 R488.1
IO_EXP_INTN: length 3
  BOTTOM w0.127: R467.2 R468.1 52.15,39.56 52.53,39.56 52.7,39.73 U70.32
IO_EXP_TEST_LED: length 11.6
  TOP w0.132: 55.84,48.49 55.71,48.62 v1(55.71,49.12) ; 55.84,48.49 R170.2 ; 55.84,48.49 55.62,48.49 55.4,48.71 R168.1
  L03_SIG1 w0.107: v1(55.71,49.12) 56.73,48.1 56.73,42.07 v1(57.81,40.99)
  BOTTOM w0.127: v1(57.81,40.99) 57.69,41.11 U70.24
JTAG_CTI_RTCK: length 3.1
  TOP w0.127: J19.9 v1(38.62,15.39)
  BOTTOM w0.127: R558.1 38.87,15.15 v1(38.62,15.39)
JTAG_CTI_TCK: length 17.5
  TOP w0.132: v1(40.94,16.75) 40.08,15.89 38.08,15.89 37.35,15.16 J19.11
  L03_SIG1 w0.107: v1(44.34,22.24) 40.94,18.84 v1(40.94,16.75)
  BOTTOM w0.127: v1(40.94,16.75) 40.21,16.02 U90.1 ; v1(44.34,22.24) 44.64,22.54 R512.1 45.09,22.85 44.46,23.49 R495.1 U80.1
JTAG_DIR: length 3.1
  BOTTOM w0.127: U87.5 50.24,19.89 50.52,20.16 50.52,20.68 ; 50.52,20.68 50.01,20.68 50.01,20.67 49.86,20.67 49.46,20.27 U87.4 ; 50.52,20.68 R514.2
JTAG_EMU0: length 35.9
  TOP w0.127: J19.13 v1(36.08,11.49)
  TOP w0.132: v1(43.65,11.34) 43.14,10.83 36.74,10.83 v1(36.08,11.49)
  BOTTOM w0.127: U79.7 49.34,25.22 49.46,25.35 50.22,25.35 50.9,24.66 51.46,24.66 52.36,23.76 52.36,22.59 52.87,22.09 ; R560.2 v1(36.08,11.49)
  BOTTOM w0.132: 52.87,22.09 52.87,18.45 52.45,18.03 51.94,18.03 50.28,16.37 44.33,16.37 42.86,14.89 42.86,12.12 v1(43.65,11.34)
JTAG_EMU1: length 27.1
  TOP w0.127: J19.14 v1(36.08,10.22)
  L03_SIG1 w0.107: v1(36.74,15.55) 37.07,15.88 39,15.88 39.46,16.34 39.46,18.53 45.18,24.25 47.43,24.25 v1(48.72,25.54)
  BOTTOM w0.127: v1(36.08,10.22) R562.2
  BOTTOM w0.132: v1(48.72,25.54) 48.72,25.52 48.99,25.25 U79.6 ; v1(36.74,15.55) 36.74,11.46 36.26,10.98 35.85,10.98 35.52,10.66 R562.2
JTAG_EMU_RSTN: length 3.9
  TOP w0.127: J19.15 v1(34.81,15.38)
  BOTTOM w0.127: v1(34.81,15.38) 34.68,15.5 R547.2 34.25,15.99 33.85,16.39 U89.6
JTAG_TCK: length 13.1
  TOP w0.132: v1(46.65,18.84) 44.73,20.76 44.73,24.02 44.55,24.21 44.55,25.01 44.77,25.23 45.23,25.23 45.62,24.84 45.62,24.38 45.91,24.1 46.67,24.1 46.95,24.37 v1(46.95,24.77)
  BOTTOM w0.127: R494.1 47.07,24.64 v1(46.95,24.77) ; R521.1 v1(46.65,18.84) 46.9,19.09 U87.14
JTAG_TDI: length 10.2
  TOP w0.127: v1(47.94,17.7) 47.21,18.44 46.4,18.44 43.23,15.26 42.87,15.26 42.43,14.82 J19.3
  BOTTOM w0.127: R535.1 v1(47.94,17.7) 48.26,18.02 U87.12
JTAG_TDIS: length 2.8
  TOP w0.127: J19.4 42.43,10.04 v1(42.7,10.31)
  BOTTOM w0.127: R563.2 42.81,10.2 v1(42.7,10.31)
JTAG_TDO: length 4.7
  TOP w0.127: J19.7 v1(39.89,11.41)
  BOTTOM w0.127: U95.7 41.13,10.48 40.2,11.41 v1(39.89,11.41)
JTAG_TMS: length 7.8
  TOP w0.127: J19.1 43.7,15 v1(46.75,18.04)
  BOTTOM w0.127: U87.13 47.19,18.69 47.02,18.52 47.02,18.32 v1(46.75,18.04) 46.63,17.93 46.21,17.93 R530.1
JTAG_TRST#: length 16.6
  TOP w0.127: J19.2 43.7,9.79 44.48,10.57 44.48,13.16 46.41,15.1
  TOP w0.132: v1(46.65,19.76) 47.94,19.76 48.42,19.27 48.42,17.1 46.41,15.1
  BOTTOM w0.127: U87.15 46.92,19.49 v1(46.65,19.76) R517.2
LDO_1V8: length 1.6
  TOP w0.127: v1(24.63,45.36) 24.55,45.28 C130.1
  BOTTOM w0.127: U68.35 v1(24.63,45.36)
LDO_3V3: length 20.9
  TOP w0.254: R160.1 25.47,49.62 25.21,49.36 v1(25.21,48.49) 25.47,48.23 R171.1 ; R160.1 25.02,50.48 v1(24.98,50.51) ; R160.1 R158.1 ; 35.34,50.75 33.25,50.75 U30.8 ; 35.34,50.75 35.34,51.83 v1(35.18,51.99) ; 35.34,50.75 C122.1 35.35,50.36 35.35,50.36 35.35,50.35 35.35,50.35 R163.1 ; v1(19.46,51.22) 19.13,50.89 19.13,50.45 R161.1 19.16,50.03 19.13,50 R164.1
  TOP w0.381: C129.2 15.99,45.73 v1(16.11,45.61)
  BOTTOM w0.254: v1(25.21,48.49) 25.44,48.49 25.78,48.14 R443.1 ; R452.1 R449.1 16.02,45.69 v1(16.11,45.61) 16.38,45.61 16.52,45.76 U68.9 ; v1(19.46,51.22) R436.1 21.9,51.22 22.3,50.81 R439.1 R438.1 24.68,50.81 v1(24.98,50.51)
LINE1L+: length 2.6
  BOTTOM w0.254: C392.1 82.27,49.93 TP62.1
LINE1L+_C: length 1.7
  BOTTOM w0.254: C392.2 79.14,49.93 79,49.79 U66.3
LINE1R+: length 2.6
  BOTTOM w0.254: C394.1 82.27,48.66 TP63.1
LINE1R+_C: length 1.7
  BOTTOM w0.254: C394.2 79.13,48.66 78.99,48.79 U66.5
LM61460_RT: length 2.3
  BOTTOM w0.127: R441.1 31.55,47.76 32.09,47.76 32.59,47.26 U67.6
LM61460_SW: length 8.7
  TOP w0.254: v1(31.01,43) 33.08,45.07 36.44,45.07 v1(37.3,45.93)
  BOTTOM w0.203: C405.2 31.63,42.38 v1(31.01,43)
LM61460_VCC: length 1.7
  BOTTOM w0.127: C400.1 30.89,44.24 31.34,44.7 U67.2
LPDDR4_CA0: length 23.5
  TOP w0.203: U12.F5 v1(32.07,99.74) ; U20.H2 v1(33.24,84.36)
  BOTTOM w0.127: 32.45,99.17 32.45,99.11 32.46,99.1 32.46,98.77 32.23,98.54 32.21,98.54 32.06,98.39 32.06,98.37
  BOTTOM w0.203: 32.06,98.37 32.06,97.3 32.31,97.04 32.31,96.3 30.5,94.49 28.88,94.49 28.66,94.27 28.66,93.81 28.83,93.65 29.04,93.65 29.18,93.5 29.18,93.29 29.04,93.14 28.83,93.14 28.68,92.99 28.68,92.78 28.83,92.63 29.04,92.63 29.18,92.48 29.18,92.27 29.04,92.12 28.83,92.12 28.68,91.97 28.68,88.32 29.27,87.73 29.57,87.73 29.78,87.52 29.78,87.22 29.99,87.01 30.29,87.01 30.5,86.8 30.5,86.5 30.71,86.29 31.01,86.29 31.22,86.08 31.22,85.78 31.43,85.57 31.72,85.57 32.37,84.93 32.68,84.93 v1(33.24,84.36) ; v1(32.07,99.74) 32.08,99.74 32.45,99.36 32.45,99.17
LPDDR4_CA1: length 23.4
  TOP w0.203: U12.G5 v1(32.87,99.74) ; v1(32.44,84.36) U20.J2
  BOTTOM w0.127: 31.65,98.42 31.66,98.43 31.66,99.1 31.66,99.1 31.66,100 31.8,100.13 32.48,100.13
  BOTTOM w0.203: v1(32.44,84.36) 31.75,85.05 31.11,85.05 29.54,86.63 28.96,86.63 28.67,86.91 28.67,87.49 28.1,88.07 28.1,95.54 29,96.45 31.15,96.45 31.7,97 31.7,97.51 31.65,97.57 31.65,98.42 ; 32.48,100.13 v1(32.87,99.74)
LPDDR4_CA2: length 23.4
  TOP w0.203: U20.H9 v1(38.84,84.36) ; U12.G4 v1(32.87,98.94)
  BOTTOM w0.127: 35.55,96.82 35.59,96.86 35.59,96.9 35.67,96.98 35.67,97.57 35.51,97.73 35.07,97.73 ; 33.44,98.55 33.5,98.55 33.51,98.54 33.83,98.54 33.84,98.55 33.89,98.55
  BOTTOM w0.203: v1(38.84,84.36) 38.84,85.05 39.66,85.87 40.72,85.87 40.96,86.11 40.96,89.08 40.66,89.39 39.81,89.39 39.61,89.58 39.61,89.96 38.47,91.1 37.21,91.1 36.9,91.4 36.9,93.48 36.71,93.67 36.32,93.67 36.16,93.83 36.16,94.22 35.99,94.39 35.6,94.39 35.44,94.55 35.44,94.94 35.22,95.16 35.22,96.49 35.55,96.82 ; 35.07,97.73 34.25,98.55 33.89,98.55 ; v1(32.87,98.94) 33.05,98.94 33.44,98.55
LPDDR4_CA3: length 23.5
  TOP w0.203: U12.H4 v1(33.67,98.94) ; U20.H10 v1(39.64,85.01)
  BOTTOM w0.203: v1(39.64,85.01) 40.14,85.51 40.7,85.51 40.87,85.51 41.32,85.96 41.32,87.31 41.7,87.69 41.7,89.29 40.98,90.01 40.61,90.01 40.44,90.19 40.44,90.56 40.26,90.73 39.89,90.73 39.72,90.91 39.72,91.28 39.32,91.67 37.77,91.67 37.57,91.88 37.57,94.27 37.42,94.42 37.13,94.42 36.98,94.56 36.98,94.77 37.13,94.92 37.42,94.92 37.57,95.07 37.57,95.75 36.83,96.48 36.83,98.02 35.48,99.37 34.1,99.37 v1(33.67,98.94)
LPDDR4_CA4: length 23.4
  TOP w0.203: U12.J5 v1(33.67,99.74) ; U20.H11 v1(40.44,85.01)
  BOTTOM w0.203: v1(40.44,85.01) 40.74,84.72 41.04,84.72 41.83,85.5 41.83,86.2 41.66,86.37 41.66,86.97 42.2,87.51 42.2,89.58 39.24,92.54 38.87,92.54 38.63,92.3 38.34,92.3 38.14,92.5 38.14,93.93 38.35,94.15 38.35,94.77 38.07,95.06 38.07,95.28 38.35,95.57 38.35,95.94 37.21,97.09 37.21,98.2 35.67,99.74 v1(33.67,99.74)
LPDDR4_CA5: length 23.4
  TOP w0.203: U12.H5 v1(33.67,100.53) ; U20.J11 v1(40.44,84.36)
  BOTTOM w0.203: v1(40.44,84.36) 41.21,84.36 42.31,85.46 42.31,86.06 42.75,86.49 42.75,89.81 38.78,93.77 38.78,97.17 35.84,100.11 34.65,100.11 34.65,100.1 34.29,100.1 34.29,100.11 34.24,100.11 33.82,100.53 v1(33.67,100.53)
LPDDR4_CAL0: length 3.5
  TOP w0.127: U12.K4 v1(34.47,98.94)
  BOTTOM w0.132: R375.1 36.29,97.89 35.25,98.94 v1(34.47,98.94)
LPDDR4_CK_N: length 23.5
  TOP w0.131: U20.J9 v1(38.04,84.36)
  TOP w0.135: U12.K1 v1(35.27,97.34)
  BOTTOM w0.135: v1(35.27,97.34) 35.02,97.34 34.89,97.2 34.89,96.7 34.6,96.42 34.6,95.62 32.24,93.26 32.24,93.07 32.69,92.63 32.88,92.63 34.36,94.11 34.75,94.11 35.57,93.29 35.57,92.9 35.28,92.61 35.28,92.34 35.5,92.12 36.11,92.12 36.39,91.84 36.39,91.31 36.21,91.12 36.21,90.93 36.57,90.58 37.84,90.58 38.16,90.25 38.16,89.73 37.88,89.46 37.72,89.46 37.57,89.31 37.57,84.5 37.7,84.36 v1(38.04,84.36)
LPDDR4_CK_P: length 23.4
  TOP w0.131: U20.J8 v1(37.17,83.82)
  TOP w0.135: U12.J1 v1(34.47,97.34)
  BOTTOM w0.135: v1(34.47,97.34) 34.64,97.16 34.64,96.8 34.36,96.52 34.36,95.72 32,93.36 32,92.97 32.58,92.38 32.98,92.38 34.46,93.87 34.65,93.87 35.33,93.19 35.33,93 35.04,92.71 35.04,92.24 35.4,91.87 36.01,91.87 36.15,91.74 36.15,91.41 35.96,91.22 35.96,90.83 36.46,90.33 37.74,90.33 37.92,90.15 37.92,89.84 37.78,89.7 37.62,89.7 37.32,89.41 37.32,83.98 v1(37.17,83.82)
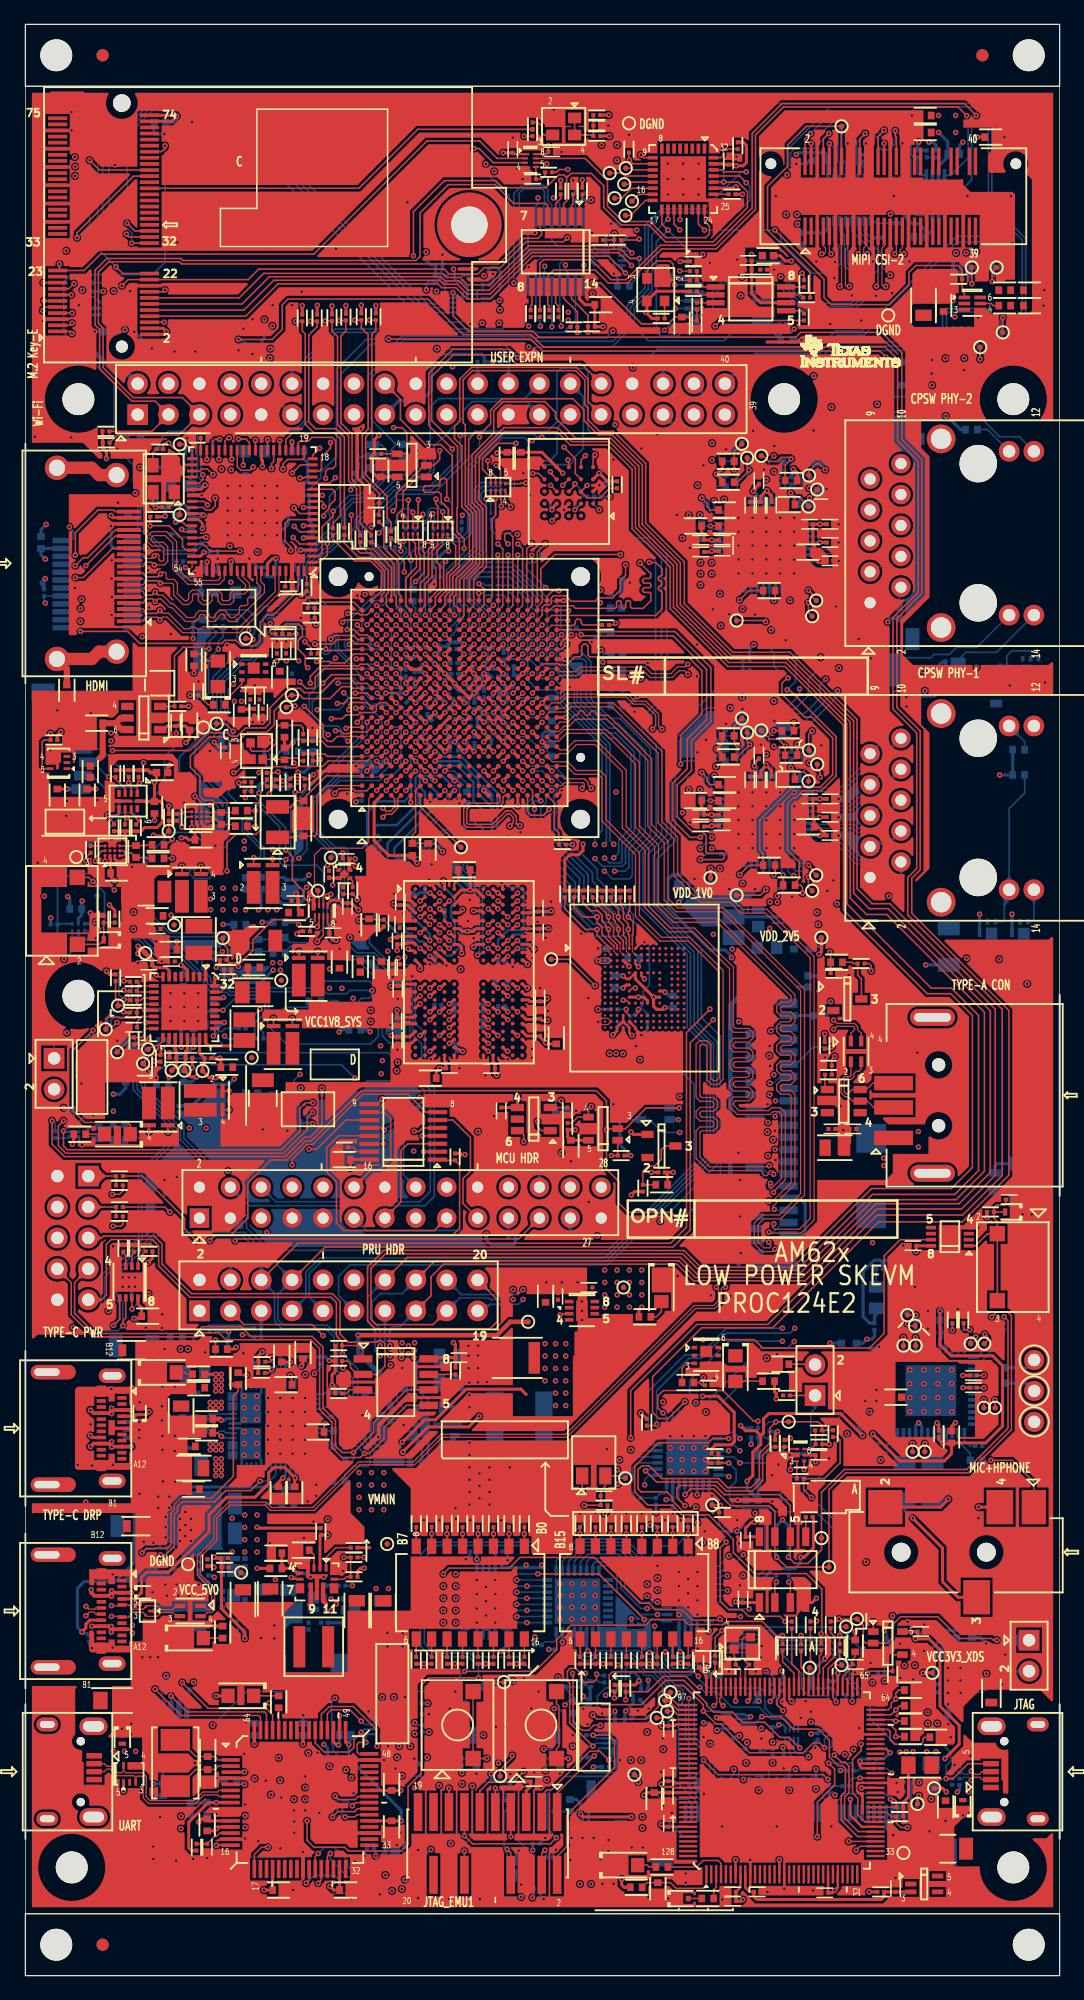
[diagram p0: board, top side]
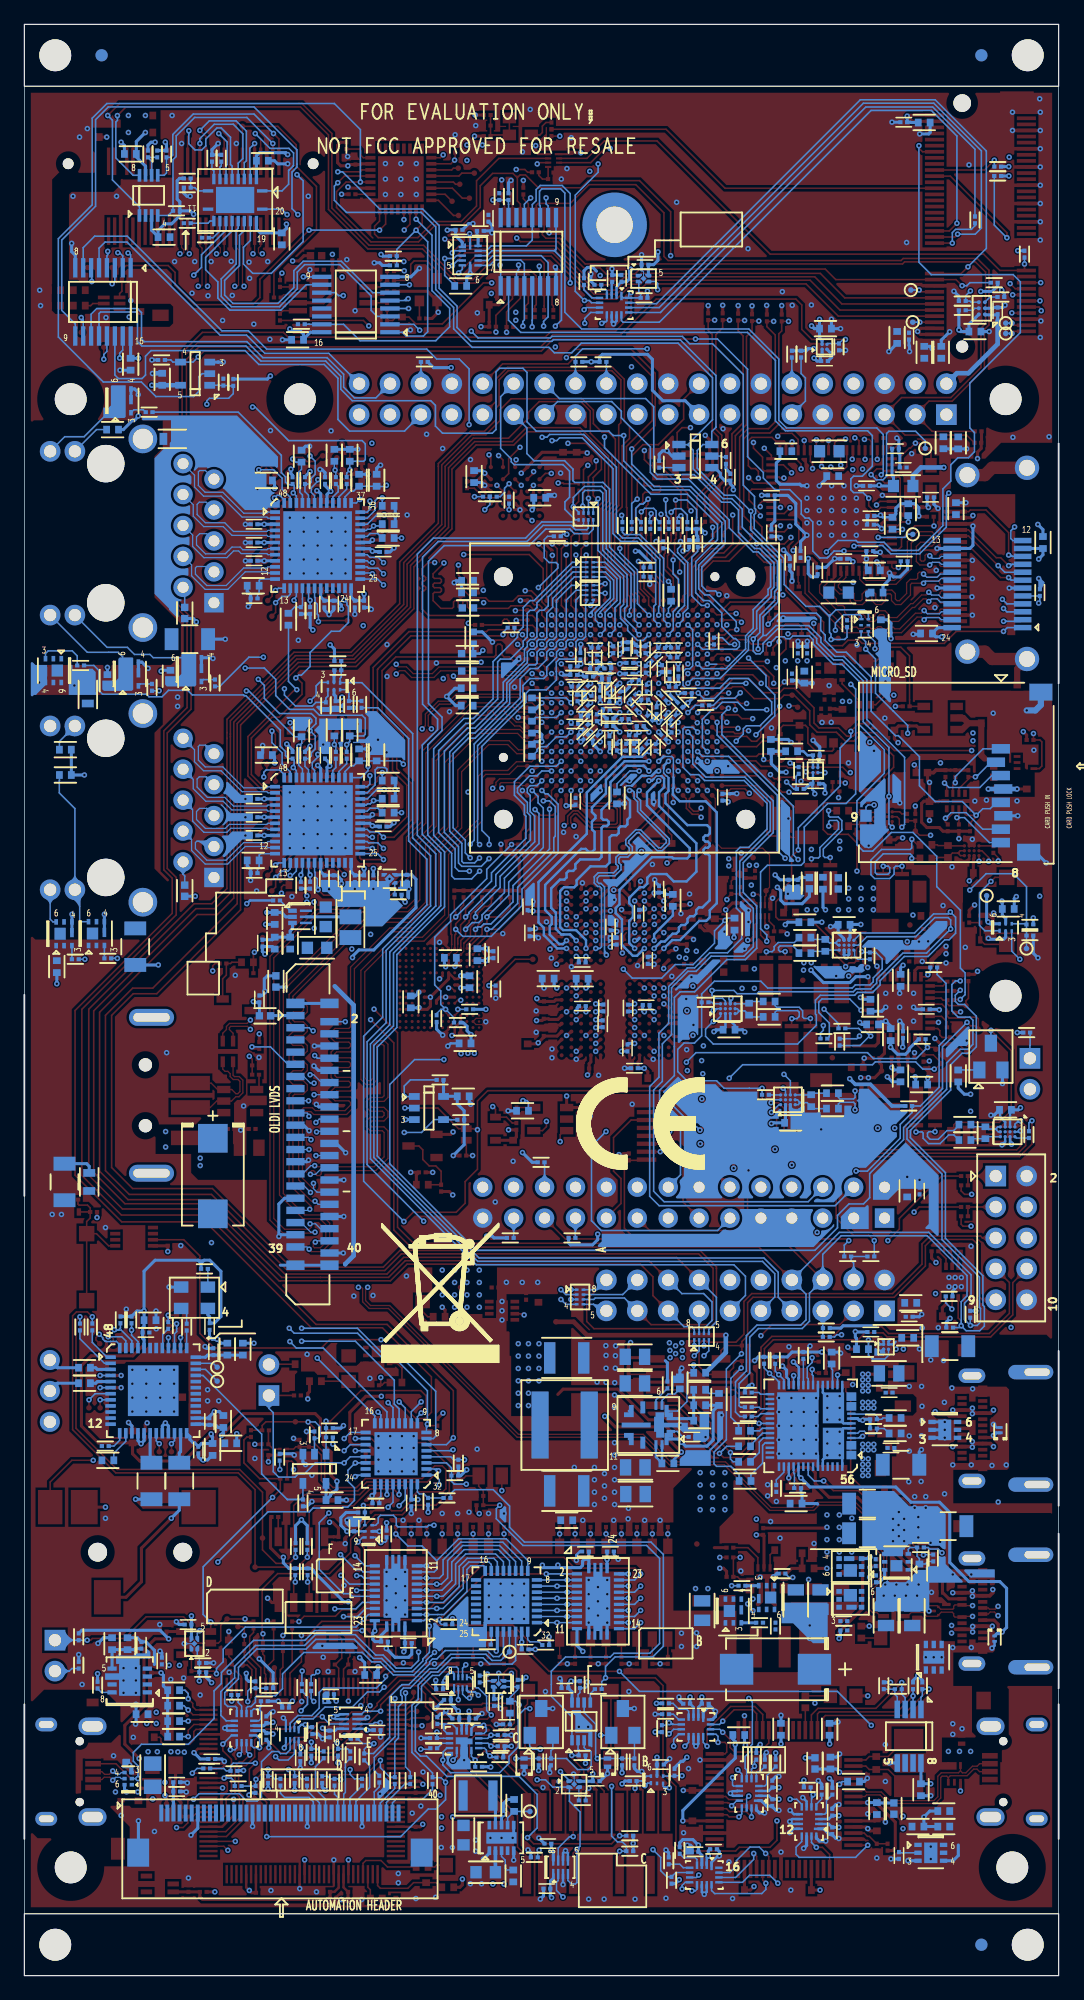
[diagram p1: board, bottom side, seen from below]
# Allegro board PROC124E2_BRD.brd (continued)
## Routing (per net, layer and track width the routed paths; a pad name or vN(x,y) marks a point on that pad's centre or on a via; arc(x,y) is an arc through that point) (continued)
LPDDR4_CKE: length 23.4
  TOP w0.203: U20.J4 v1(34.04,84.36) ; U12.G3 v1(32.87,98.14)
  BOTTOM w0.203: v1(34.04,84.36) 34.64,83.76 34.99,83.76 35.89,84.66 35.89,86.75 36.4,87.26 36.4,87.68 36.09,87.99 36.09,89.18 33.41,91.85 31.76,91.85 31.66,91.75 30.52,91.75 30.32,91.96 30.32,92.6 33.83,96.11 33.83,97.17 v1(32.87,98.14)
LPDDR4_CS: length 23.4
  TOP w0.203: U12.H3 v1(33.67,98.14) ; U20.H4 v1(34.84,84.36)
  BOTTOM w0.127: 32.63,98.52 32.7,98.52 32.71,98.53 33.03,98.53 33.3,98.26
  BOTTOM w0.203: 32.63,98.52 32.42,98.32 32.42,97.61 32.84,97.19 32.84,96.07 29.77,93 29.77,90.67 30.57,89.87 31.63,89.87 32.23,90.47 33.51,90.47 33.81,90.17 33.81,89.69 34.11,89.39 34.42,89.39 35.29,88.52 35.29,88.08 34.99,87.78 34.99,86.92 35.29,86.63 35.29,84.81 v1(34.84,84.36) ; 33.3,98.26 33.43,98.14 v1(33.67,98.14)
LPDDR4_CS1_N: length 5.6
  TOP w0.132: U12.G1 32.47,96 TP30.1
LPDDR4_DMI0: length 21.1
  TOP w0.203: U12.E3 v1(30.47,98.14) ; U20.C3 v1(34.04,88.26)
  L03_SIG1 w0.173: v1(30.47,98.14) 30.83,97.78 31.43,97.78 31.71,97.49 31.71,97.15 31.09,96.53 31.09,94.15 31.28,93.96 31.56,93.96 31.95,94.35 31.95,94.79 32.09,94.93 32.36,94.93 32.49,94.79 32.49,94.38 32.68,94.2 32.84,94.2 32.97,94.06 32.97,93.79 32.83,93.65 32.01,93.65 31.87,93.51 31.87,93.27 32.04,93.1 32.94,93.1 33.13,92.91 33.13,92.76 32.85,92.48 31.86,92.48 31.71,92.33 31.71,92.1 31.9,91.91 32.64,91.91 32.83,91.72 32.83,90.8 33.02,90.61 33.56,90.61 33.87,90.3 34.52,90.3 34.77,90.05 34.77,88.99 v1(34.04,88.26)
LPDDR4_DMI1: length 20.4
  TOP w0.203: U20.C10 v1(38.84,88.26) ; U12.R4 v1(38.47,98.94)
  L03_SIG1 w0.173: v1(38.47,98.94) 38.26,98.94 37.79,98.47 37.79,97.98 38.31,97.47 38.31,97.12 38.03,96.84 37.6,96.84 37.49,96.73 37.49,96.46 37.6,96.35 38.19,96.35 38.42,96.58 38.69,96.58 38.86,96.41 38.86,96.11 38.67,95.92 37.81,95.92 37.68,95.78 37.68,95.59 37.87,95.4 39.13,95.4 39.32,95.2 39.32,95.02 39.23,94.92 38.83,94.92 38.67,94.76 38.67,94.58 38.92,94.33 39.26,94.33 39.45,94.14 39.45,93.96 39.35,93.86 39.18,93.86 39.03,93.7 39.03,93.41 39.24,93.2 39.38,93.2 39.55,93.02 39.55,92.78 39.31,92.54 39.31,92.3 39.62,91.99 39.62,91.75 39.33,91.46 39.33,91.22 39.59,90.96 39.59,90.71 39.39,90.5 39.39,90.18 39.65,89.92 39.65,89.61 39.26,89.22 39.26,88.59 39.5,88.35 39.5,88.1 39.36,87.97 39.14,87.97 v1(38.84,88.26)
LPDDR4_DQ0: length 21.1
  TOP w0.203: U20.B2 v1(32.44,88.26) ; U12.C2 v1(28.87,97.34)
  L03_SIG1 w0.173: v1(28.87,97.34) 28.87,97.08 29.06,96.89 29.47,96.89 29.64,96.72 29.64,96.45 29.54,96.34 28.76,96.34 28.57,96.15 28.57,88.97 29.07,88.46 29.57,88.46 29.79,88.24 29.79,87.77 29.98,87.58 30.36,87.58 30.59,87.35 30.59,86.81 30.91,86.49 31.35,86.49 31.56,86.7 31.56,87.27 31.4,87.43 31.4,87.64 31.54,87.78 31.73,87.78 31.87,87.92 31.87,88.14 31.68,88.33 31.4,88.33 31.24,88.18 30.97,88.18 30.76,88.39 30.76,88.66 30.95,88.85 31.85,88.85 v1(32.44,88.26)
LPDDR4_DQ1: length 21.1
  TOP w0.203: U20.C2 v1(32.44,87.61) ; U12.E4 v1(31.27,99.73)
  L03_SIG1 w0.173: v1(31.27,99.73) 30.85,99.31 29.03,99.31 28.09,98.38 28.09,88.79 30.78,86.11 31.57,86.11 31.92,86.45 31.92,87.45 32.08,87.61 v1(32.44,87.61)
LPDDR4_DQ2: length 21.1
  TOP w0.203: U12.D3 v1(29.67,98.14) ; U20.E2 v1(33.22,86.34)
  L03_SIG1 w0.173: v1(29.67,98.14) 30.08,98.55 30.64,98.55 31.01,98.18 31.45,98.18 32.01,97.62 32.01,97.01 32.22,96.8 32.22,96.62 32.53,96.32 32.7,96.32 33.06,95.96 33.82,95.96 35.72,94.06 35.72,93.39 35.44,93.11 34.83,93.11 34.7,92.97 34.7,92.78 34.84,92.63 35.53,92.63 35.7,92.47 35.7,92.24 35.54,92.09 35.13,92.09 34.94,91.9 34.94,91.34 35.77,90.51 35.77,89.86 35.48,89.57 35.48,88.85 35.26,88.62 35.26,87.99 34.3,87.04 33.92,87.04 v1(33.22,86.34)
LPDDR4_DQ3: length 21.1
  TOP w0.203: U12.E5 v1(30.47,99.74) ; U20.F2 v1(32.44,85.66)
  L03_SIG1 w0.173: v1(30.47,99.74) 30.07,100.13 28.67,100.13 27.62,99.08 27.62,88.61 30.56,85.66 v1(32.44,85.66)
LPDDR4_DQ4: length 21.1
  TOP w0.203: U12.D2 v1(29.67,97.34) ; U20.F4 v1(34.04,86.31)
  L03_SIG1 w0.173: v1(34.04,86.31) 35.58,87.85 35.58,88.36 35.8,88.59 35.8,89.41 36.22,89.83 36.22,94.14 33.52,96.85 32.77,96.85 32.29,97.33 32.29,97.73 32.12,97.9 32.12,98.13 31.74,98.51 31.08,98.51 30.7,98.89 29.25,98.89 28.98,98.62 28.98,98.02 v1(29.67,97.34)
LPDDR4_DQ5: length 21.1
  TOP w0.203: U20.E4 v1(34.84,86.31) ; U12.F3 31.67,98.54 v1(32.07,98.93)
  L03_SIG1 w0.173: v1(34.84,86.31) 35,86.15 35.25,86.15 35.42,86.32 35.42,86.93 35.59,87.1 35.79,87.1 35.93,86.96 35.93,86.38 36.12,86.18 36.6,86.18 36.79,86.38 36.79,86.85 36.41,87.22 36.41,87.88 36.11,88.19 36.11,89.28 36.78,89.96 36.78,94.22 34.95,96.06 34.95,96.33 35.19,96.58 35.19,96.78 34.99,96.98 34.72,96.98 34.43,96.68 34.16,96.68 33.12,97.72 32.7,97.72 32.46,97.96 32.46,98.55 v1(32.07,98.93)
LPDDR4_DQ6: length 21.1
  TOP w0.203: U12.F1 v1(31.67,96.35) ; U20.C4 v1(34.84,88.26)
  L03_SIG1 w0.173: v1(31.67,96.35) 31.43,96.11 31.43,95.37 31.59,95.21 31.83,95.21 32.03,95.4 32.03,95.76 32.17,95.9 32.55,95.9 32.82,95.64 32.82,94.98 33.01,94.79 33.2,94.79 33.29,94.88 33.29,95.39 33.48,95.58 33.68,95.58 34.03,95.24 34.03,94.97 33.81,94.75 33.81,94.55 34,94.36 34.3,94.36 34.44,94.51 34.7,94.51 34.8,94.41 34.8,94.13 34.93,94.01 35.21,94.01 35.3,93.91 35.3,93.63 35.17,93.5 34.67,93.5 34.31,93.86 33.5,93.86 33.38,93.74 33.38,93.49 33.54,93.34 34.09,93.34 34.23,93.19 34.23,92.96 34.04,92.77 33.79,92.77 33.49,92.47 33.49,92.02 33.69,91.83 34.33,91.83 34.47,91.69 34.47,91.45 34.38,91.35 34.13,91.35 33.94,91.16 33.94,90.95 34.13,90.76 34.77,90.76 35.26,90.27 35.26,90 35.12,89.86 35.12,88.88 34.84,88.61 v1(34.84,88.26)
LPDDR4_DQ7: length 21.1
  TOP w0.203: U20.B4 v1(34.04,88.91) ; U12.F2 v1(31.27,97.34)
  L03_SIG1 w0.173: v1(31.27,97.34) 30.83,96.89 30.25,96.89 30.11,96.76 30.11,96.49 30.22,96.38 30.48,96.38 30.67,96.18 30.67,96 30.53,95.85 30.53,95.64 30.67,95.5 30.67,94.1 30.48,93.91 29.81,93.91 29.65,93.76 29.65,93.54 29.81,93.39 31.02,93.39 31.21,93.19 31.21,92.93 31.02,92.73 29.84,92.73 29.65,92.54 29.65,92.27 29.84,92.08 31.08,92.08 31.32,91.84 31.32,91.57 31.11,91.37 31.11,91.09 31.3,90.9 32.16,90.9 32.35,90.7 32.35,90.51 32.16,90.32 31.25,90.32 31.07,90.14 31.07,89.96 31.25,89.78 32.4,89.78 32.79,89.4 33.32,89.4 33.63,89.7 33.9,89.7 34.23,89.37 34.23,89.1 v1(34.04,88.91)
LPDDR4_DQ8: length 20.4
  TOP w0.203: v1(38.46,98.12) U12.R3 ; U20.B11 v1(40.44,88.91)
  L03_SIG1 w0.173: v1(40.44,88.91) 40.69,89.16 41.76,89.16 41.88,89.28 41.88,89.46 41.76,89.58 40.88,89.58 40.74,89.73 40.74,89.9 40.86,90.03 41.61,90.03 41.76,90.18 41.76,90.32 41.62,90.45 40.88,90.45 40.69,90.65 40.69,93.35 41.15,93.81 41.15,94.08 41.35,94.27 41.35,94.57 40.74,95.18 40.48,95.18 40.23,94.93 39.84,94.93 39.67,95.1 39.67,95.33 39.33,95.66 39.33,96.58 38.7,97.21 38.7,97.5 38.94,97.74 39.59,97.74 39.78,97.93 40.23,97.93 40.4,98.1 40.4,98.3 40.26,98.44 39.98,98.44 39.85,98.57 38.67,98.57 38.46,98.36 v1(38.46,98.12)
LPDDR4_DQ9: length 20.4
  TOP w0.203: v1(39.27,97.33) 38.87,97.73 U12.R2 ; U20.C11 v1(40.44,88.26)
  L03_SIG1 w0.173: v1(39.27,97.33) 39.5,97.33 39.69,97.14 39.69,96.63 39.86,96.46 39.86,96.13 39.74,96.01 39.74,95.74 40.02,95.46 40.33,95.46 40.49,95.62 40.76,95.62 41.88,94.51 41.88,94.12 41.18,93.42 41.18,93.03 41.37,92.84 42.24,92.84 42.43,92.65 42.43,92.43 42.28,92.28 41.35,92.28 41.16,92.09 41.16,91.97 41.29,91.83 42.25,91.83 42.43,91.65 42.43,91.52 42.29,91.38 41.29,91.38 41.15,91.24 41.15,91.1 41.31,90.95 42.2,90.95 42.41,90.74 42.41,90.35 42.22,90.17 42.22,89.8 42.39,89.62 42.39,89.27 42.04,88.92 42.04,88.22 41.91,88.09 41.71,88.09 41.56,88.24 41.56,88.58 41.4,88.74 40.92,88.74 v1(40.44,88.26)
LPDDR4_DQ10: length 20.4
  TOP w0.203: U20.E11 v1(40.44,86.96) ; v1(40.07,97.33) 40.07,97.34 U12.T2
  L03_SIG1 w0.173: v1(40.44,86.96) 40.72,86.96 40.88,86.8 40.88,86.38 41,86.26 41.19,86.26 41.32,86.39 41.32,86.95 40.87,87.4 40.87,88.13 40.99,88.25 41.15,88.25 41.33,88.07 41.33,87.64 41.52,87.45 42.18,87.45 42.37,87.64 42.37,88.68 42.89,89.2 42.89,93.12 42.7,93.31 42.03,93.31 41.87,93.47 41.87,93.69 42.01,93.84 42.19,93.84 42.32,93.96 42.32,94.61 42.18,94.75 42.18,95.15 41.99,95.34 41.54,95.34 41.01,95.87 41.01,96.14 41.2,96.33 41.39,96.33 41.51,96.45 41.51,96.62 41.26,96.86 40.83,96.86 40.56,96.6 40.26,96.6 40.07,96.79 v1(40.07,97.33)
LPDDR4_DQ11: length 20.4
  TOP w0.203: U12.U2 40.49,97.74 v1(40.9,97.33) ; U20.F11 v1(40.44,86.31)
  L03_SIG1 w0.173: v1(40.44,86.31) 40.36,86.31 40.24,86.2 40.24,86.01 40.43,85.82 40.81,85.82 40.92,85.93 41.19,85.93 41.27,85.85 41.5,85.85 41.67,86.03 41.67,86.78 41.96,87.07 42.23,87.07 42.42,86.88 42.59,86.88 42.75,87.04 42.75,88.4 43.38,89.03 43.38,93.47 43.19,93.66 42.87,93.66 42.68,93.85 42.68,94.25 42.77,94.34 43.17,94.34 43.36,94.53 43.36,94.66 43.17,94.85 42.71,94.85 42.59,94.96 42.59,95.13 42.72,95.25 43.29,95.25 43.53,95.5 43.53,95.85 43.11,96.27 42.82,96.27 42.52,95.97 42.25,95.97 41.86,96.37 41.86,96.78 41.3,97.33 v1(40.9,97.33)
LPDDR4_DQ12: length 20.4
  TOP w0.203: U12.U3 v1(40.87,98.14) ; U20.F9 v1(38.04,85.66)
  L03_SIG1 w0.173: v1(40.87,98.14) 41.06,98.14 42.27,96.92 42.92,96.92 43.84,96 43.84,87.45 41.85,85.46 39.37,85.46 39.1,85.19 38.51,85.19 v1(38.04,85.66)
LPDDR4_DQ13: length 20.4
  TOP w0.203: U12.U4 v1(40.87,98.94) ; U20.E9 v1(38.04,86.31)
  L03_SIG1 w0.173: v1(38.04,86.31) 37.33,87.03 37.33,94.35 36.3,95.38 36.3,99.65 36.69,100.04 38.72,100.04 38.81,100.13 39.67,100.13 v1(40.87,98.94)
LPDDR4_DQ14: length 20.4
  TOP w0.203: U12.T4 v1(40.07,98.94) ; v1(38.84,87.61) 38.52,87.94 U20.C9
  L03_SIG1 w0.173: v1(40.07,98.94) 39.99,98.85 39.14,98.85 38.62,99.37 37.45,99.37 37.22,99.14 37.22,98.68 37.45,98.45 37.45,97.82 37.08,97.44 37.08,95.65 37.68,95.04 38.05,95.04 38.28,94.82 38.28,94.45 38.66,94.06 38.66,93.13 38.87,92.92 38.87,90.28 38.73,90.14 38.73,89.39 38.44,89.1 38.44,88.26 38.25,88.07 38.1,88.07 37.96,88.2 37.76,88.2 37.63,88.08 37.63,87.23 38.12,86.74 38.39,86.74 38.65,87 38.65,87.42 v1(38.84,87.61)
LPDDR4_DQ15: length 20.4
  TOP w0.203: U12.T5 v1(39.27,99.74) ; U20.B9 v1(38.04,88.91)
  L03_SIG1 w0.173: v1(39.27,99.74) 39.58,99.74 39.75,99.56 39.75,99.32 39.57,99.14 39.26,99.14 38.65,99.75 36.99,99.75 36.66,99.43 36.66,98.69 37.04,98.31 37.04,97.92 36.69,97.56 36.69,95.54 37.72,94.51 37.72,94.2 37.91,94.01 38.12,94.01 38.27,93.87 38.27,93.52 38.12,93.38 37.98,93.38 37.78,93.19 37.78,93.03 37.96,92.86 38.13,92.86 38.28,92.71 38.28,92.51 38.13,92.36 37.94,92.36 37.8,92.22 37.8,92.01 37.94,91.87 38.24,91.87 38.38,91.72 38.38,91.52 38.24,91.37 37.94,91.37 37.8,91.23 37.8,91.02 37.94,90.88 38.24,90.88 38.38,90.73 38.38,90.53 38.21,90.36 37.97,90.36 37.83,90.21 37.83,90.01 37.97,89.86 38.2,89.86 38.34,89.72 38.34,89.57 38.23,89.46 37.91,89.46 37.8,89.35 37.8,89.16 v1(38.04,88.91)
LPDDR4_DQS0_N: length 21.1
  TOP w0.131: v1(29.38,95.13) 29.63,95.38 30.1,95.38 30.59,95.87 30.59,96.66 U12.E1 ; U20.E3 v1(33.24,86.96)
  L03_SIG1 w0.114: v1(33.24,86.96) 32.87,87.34 32.87,88.43 32.07,89.23 30.7,89.23 30.41,89.52 30.41,91.32 30.32,91.42 30.02,91.42 29.93,91.32 29.93,89.15 29.68,88.9 29.25,88.9 28.99,89.16 28.99,89.39 28.99,89.39 28.99,94.37 29.24,94.62 29.91,94.62 30.02,94.73 30.02,95.23 29.91,95.34 29.59,95.34 v1(29.38,95.13)
LPDDR4_DQS0_P: length 21.1
  TOP w0.131: U12.D1 30.35,96.66 30.35,95.98 30,95.63 29.65,95.63 v1(29.38,95.9) ; U20.D3 v1(33.24,87.61)
  L03_SIG1 w0.114: v1(33.24,87.61) 33.29,87.57 33.49,87.57 33.6,87.68 33.6,87.89 33.49,88 33.21,88 33.1,88.11 33.1,88.53 32.16,89.46 30.79,89.46 30.64,89.61 30.64,91.42 30.41,91.64 29.93,91.64 29.7,91.42 29.7,89.24 29.59,89.13 29.34,89.13 29.22,89.25 29.22,89.3 29.22,94.27 29.33,94.39 30,94.39 30.25,94.64 30.25,95.32 30,95.57 29.71,95.57 v1(29.38,95.9)
LPDDR4_DQS1_N: length 20.4
  TOP w0.131: U20.E10 v1(39.64,86.31) ; v1(39.83,94.43) 40.1,94.71 40.1,95.12 39.79,95.43 39.61,95.43 38.49,94.31 36.3,94.31 36.03,94.59 36.03,95.89 36.43,96.29 38.87,96.29 39,96.42 39,96.81 U12.R1
  L03_SIG1 w0.114: v1(39.64,86.31) 39.64,86.47 39.53,86.59 39.16,86.59 38.95,86.8 38.95,87.16 39.43,87.65 39.6,87.65 39.81,87.86 39.81,89.26 40.05,89.49 40.05,94.21 v1(39.83,94.43)
LPDDR4_DQS1_P: length 20.4
  TOP w0.131: v1(40.64,94.46) 40.49,94.46 40.35,94.61 40.35,95.22 39.89,95.67 39.69,95.67 39.69,95.67 39.51,95.67 38.39,94.56 36.4,94.56 36.27,94.69 36.27,95.79 36.53,96.05 38.97,96.05 39.24,96.32 39.24,96.78 39.4,96.94 U12.T1 ; U20.D10 v1(39.64,86.96)
  L03_SIG1 w0.114: v1(39.64,86.96) 39.5,86.81 39.26,86.81 39.18,86.89 39.18,87.07 39.53,87.42 39.69,87.42 40.04,87.77 40.04,89.15 40.27,89.39 40.27,94.24 40.49,94.46 v1(40.64,94.46)
LPDDR4_ODT_CA: length 4
  TOP w0.203: U20.G2 v1(33.24,85.01)
  BOTTOM w0.203: v1(33.24,85.01) 33.24,85.53 31.7,87.07 R384.1
LPDDR4_RESET_N: length 24.8
  TOP w0.127: U20.T11 v1(40.44,79.16) ; v1(34.28,92.32) 33.62,92.99 R94.2 R93.1 31.8,93.68 32.07,93.94 32.07,97.33 U12.G2
  L06_SIG2 w0.107: v1(40.44,79.16) 39.92,79.69 39.3,79.69 38.44,80.55 38.44,86.6 37.53,87.51 37.53,89.9 35.1,92.32 v1(34.28,92.32)
LPDDR4_ZQ: length 1.7
  TOP w0.203: U20.A5 35.24,89.7 35.58,90.03 R100.2
LVDS_SHIELD: length 31.5
  BOTTOM w0.254: 63.45,81.2 63.46,81.19 FL17.1 ; J22.SH2 J22.SH1 ; J22.SH4 J22.SH3 63.96,58.35
  BOTTOM w0.381: 59.49,81.25 57.94,79.71 57.94,59.13 58.62,58.45 58.62,58.42
M2_LED1#: length 1.8
  TOP w0.132: J2.6 v1(11.41,135.79)
  BOTTOM w0.132: v1(11.41,135.79) 11.99,135.79 TP94.1
M2_LED2#: length 2
  TOP w0.132: v1(11.47,138.44) 11.32,138.29 J2.16
  BOTTOM w0.132: v1(11.47,138.44) TP93.1
MCASP1_ACLKX: length 18.4
  TOP w0.127: U12.K17 v1(34.47,110.13)
  TOP w0.132: RA1.3 39.05,121.26 39.12,121.19 v1(39.12,120.68)
  BOTTOM w0.132: v1(34.47,110.13) 34.75,110.42 34.75,110.54 35.67,111.46 35.67,112.29 35.47,112.49 35.47,115.06 37.46,117.06 37.46,121.76 37.68,121.98 38.91,121.98 39.12,121.77 v1(39.12,120.68) 39.12,120.67 39.05,120.61 RA4.3
MCASP1_ACLKX_AUD: length 147.9
  TOP w0.127: TP60.1 v1(72.16,52.41)
  L03_SIG1 w0.107: v1(44.38,140.5) 44.08,140.8 44.08,144.92 45.39,146.23 48.42,146.23 52.36,142.29 57.27,142.29 61.65,146.67 71.55,146.67 72.31,145.91 72.31,145.86 74.95,143.23 74.95,135.78 74.42,135.26 74.42,133.54 74.42,133.17 71.07,129.82 71.07,127.17 67.63,123.73 67.63,111.39 67.71,111.31 67.71,104.97 65.36,102.62 65.32,102.62 65.32,102.62 65.13,102.62 65.13,102.62 64.36,102.62 62.84,101.1 62.84,100.16 60.44,97.75 60.44,90.5 61.52,89.42 62.04,89.42 62.63,88.83 62.63,88.34 69.22,81.75 69.22,75.12 67.85,73.76 67.85,56.71 v1(72.16,52.41)
  BOTTOM w0.127: U66.38 v1(72.16,52.41)
  BOTTOM w0.132: v1(44.38,140.5) 44.38,140.1 44.56,139.93 U39.3
MCASP1_ACLKX_BT: length 43.5
  TOP w0.132: J2.8 18.11,136.29 20.75,138.94 33.91,138.94 34.21,138.63 35.38,138.63 36.32,137.69 38.18,137.69 41.71,141.22 47.92,141.22 v1(49.31,139.84)
  BOTTOM w0.132: U40.5 49.01,140.14 v1(49.31,139.84)
MCASP1_ACLKX_BUF: length 43.4
  TOP w0.132: v1(38.69,124.04) 39.05,123.68 RA1.6
  L03_SIG1 w0.107: v1(44.03,135.47) 44.03,136.4 40.94,139.48 40.01,139.48 39.14,138.61 37.2,138.61 30.88,132.29 30.88,127.65 32.88,125.65 34.21,125.65 36,123.86 38.14,123.86 38.31,124.04 v1(38.69,124.04)
  BOTTOM w0.132: U40.7 46.75,140.46 46.31,140.9 44.21,140.9 43.91,140.6 U39.4 43.91,135.98 44.03,135.86 v1(44.03,135.47)
MCASP1_ACLKX_HDMI: length 49.7
  TOP w0.132: v1(15.61,121.33) 15.61,120.72 15.27,120.38 14.82,120.38 14.62,120.58 U11.45
  BOTTOM w0.132: v1(15.61,121.33) 16.07,121.8 16.85,121.8 17.08,122.03 17.08,122.92 16.85,123.15 16.14,123.15 15.31,123.97 15.31,126.49 15.7,126.88 22.26,126.88 22.46,126.88 23.28,127.69 23.28,132.66 25.58,134.96 44.21,134.96 45.21,135.96 U39.2
MCASP1_AFSX: length 10.5
  TOP w0.132: RA1.2 38.65,121.34 v1(38.64,121.33) 38.64,119.94 38.37,119.67 38.37,113.23 U12.P21
  BOTTOM w0.132: RA4.2 38.64,120.12 v1(38.64,121.33)
MCASP1_AFSX_AUD: length 153.4
  TOP w0.127: v1(72.49,53.54) 72.65,53.38 TP57.1
  L03_SIG1 w0.107: v1(42.68,140.39) 41.12,141.95 41.12,145.62 42.53,147.02 48.57,147.02 52.64,142.96 56.8,142.96 61.25,147.4 71.76,147.4 75.62,143.55 75.62,136.14 76.27,135.49 76.27,131.69 74.78,130.2 73.05,130.2 71.74,128.89 71.74,126.86 68.3,123.42 68.3,111.77 70.05,110.02 70.05,106.27 63.97,100.19 63.97,92.73 64.96,91.73 64.96,88.61 70.37,83.2 70.37,75.33 68.53,73.49 68.53,57.5 v1(72.49,53.54)
  BOTTOM w0.127: U66.39 72.66,52.71 72.48,52.89 72.48,53.14 72.49,53.15 v1(72.49,53.54)
  BOTTOM w0.132: v1(42.68,140.39) 42.68,140 42.61,139.92 U39.6
MCASP1_AFSX_BT: length 43.9
  TOP w0.132: v1(49.82,140.45) 48.76,141.5 41.59,141.5 38.19,138.1 36.31,138.1 35.5,138.91 34.37,138.91 34.04,139.24 20.42,139.24 17.97,136.79 J2.10
  BOTTOM w0.132: U40.4 49.4,140.86 v1(49.82,140.45)
MCASP1_AFSX_BUF: length 38.8
  TOP w0.132: RA1.7 38.65,123.09 38.01,123.73 v1(38.01,124.42)
  L03_SIG1 w0.107: v1(42.33,135.47) 39.44,138.35 37.36,138.35 33.16,134.15 33.16,127.05 34.42,125.78 36.64,125.78 v1(38.01,124.42)
  BOTTOM w0.132: v1(42.33,135.47) 42.33,135.86 41.96,136.23 U39.7 41.96,140.69 42.53,141.26 46.49,141.26 46.89,140.86 U40.8
MCASP1_AFSX_HDMI: length 65.6
  TOP w0.132: U11.44 14.68,121.08 v1(14.97,120.79)
  L03_SIG1 w0.107: v1(43.27,135.41) 43.62,135.06 44.28,135.06 45.02,135.8 45.02,136.91 44.64,137.3 43.44,137.3 40.94,139.8 39.9,139.8 38.93,138.83 37.03,138.83 35.62,137.42 32.63,137.42 32.29,137.77 32.29,141.42 32.04,141.66 31.43,141.66 31.17,141.4 31.17,133.87 28.48,131.19 28.48,126.93 28.08,126.53 26.56,126.53 25.99,127.1 15.12,127.1 13.24,125.21 13.24,121.91 14.36,120.79 v1(14.97,120.79)
  BOTTOM w0.132: v1(43.27,135.41) 43.27,135.95 43.26,135.96 U39.5
MCASP1_AXR0: length 17.1
  TOP w0.127: U12.J17 v1(33.67,110.13)
  TOP w0.132: v1(37.86,121.29) 37.98,121.29 38.25,121.56 RA1.1
  BOTTOM w0.132: RA4.1 38.25,120.9 v1(37.86,121.29) 37.86,117.05 35.75,114.94 35.75,112.62 36,112.37 36,111.46 35.42,110.88 35.42,110.47 34.6,109.66 34.14,109.66 v1(33.67,110.13)
MCASP1_AXR0_AUD: length 147
  TOP w0.127: TP61.1 v1(73.16,52.41)
  L03_SIG1 w0.107: v1(42.12,146.01) 42.53,145.6 43.8,145.6 44.65,146.45 48.51,146.45 52.46,142.51 57.13,142.51 61.57,146.95 71.58,146.95 75.17,143.37 75.17,132.75 74.57,132.16 74.14,132.16 71.3,129.31 71.3,127.07 67.85,123.63 67.85,111.5 69.04,110.32 69.04,108.58 68.74,108.28 68.74,105.67 61.38,98.31 61.38,91.98 62.72,90.64 62.72,89.47 63.5,88.69 63.5,88.29 64.94,86.85 65.96,86.85 69.92,82.89 69.92,75.51 68.08,73.67 68.08,56.86 72.05,52.89 72.68,52.89 v1(73.16,52.41)
  BOTTOM w0.127: U66.40 v1(73.16,52.41)
  BOTTOM w0.132: v1(42.12,146.01) 42.12,145.51 41.96,145.35 U39.10
MCASP1_AXR0_BT: length 47.5
  TOP w0.132: J2.12 17.81,137.29 20.04,139.52 34.16,139.52 34.49,139.19 35.61,139.19 36.38,138.43 38.12,138.43 41.47,141.78 48.94,141.78 49.69,141.03 v1(50.45,141.03)
  BOTTOM w0.132: U40.3 49.48,141.26 49.72,141.03 v1(50.45,141.03) 50.45,139.64 49.63,138.81 R281.2
MCASP1_AXR0_BUF: length 46.8
  TOP w0.132: v1(40.33,125.85) 38.85,125.85 37.58,124.57 37.58,123.71 38.24,123.05 38.25,123.05 RA1.8
  L03_SIG1 w0.107: v1(40.33,125.85) 37.31,125.85 37.15,126.01 34.52,126.01 33.38,127.14 33.38,134.05 37.38,138.05 39.16,138.05 41.36,135.85 v1(41.36,135.47)
  BOTTOM w0.132: U40.9 46.97,141.26 46.57,141.66 41.45,141.66 ; v1(41.36,135.47) 40.86,135.97 40.86,141.07 41.45,141.66 ; 41.45,141.66 41.31,141.8 U39.9
MCASP1_AXR0_HDMI: length 52.3
  TOP w0.127: U11.41 14.29,122.58 14.58,122.87 v1(14.58,123.27)
  BOTTOM w0.132: v1(14.58,123.27) 14.42,123.43 14.42,126.58 14.94,127.11 22.36,127.11 23,127.75 23,132.77 25.46,135.24 39.2,135.24 40.58,136.62 40.58,146.4 40.92,146.74 42.47,146.74 42.66,146.56 42.66,145.4 42.61,145.35 U39.11
MCASP1_AXR2: length 17.9
  TOP w0.127: U12.K20 v1(35.27,111.74)
  TOP w0.132: v1(39.89,120.63) 39.45,121.07 RA1.4
  BOTTOM w0.132: v1(35.27,111.74) 35.27,112.22 35.15,112.34 35.15,115.16 37.18,117.2 37.18,121.94 37.55,122.31 38.97,122.31 39.89,121.4 39.89,121.03 39.89,121.03 v1(39.89,120.63) 39.45,120.19 RA4.4
MCASP1_AXR2_AUD: length 145
  TOP w0.127: v1(73.18,54.24) 73.17,54.25 TP55.1
  L03_SIG1 w0.107: v1(73.18,54.24) 73.18,53.29 73.03,53.14 72.23,53.14 68.3,57.07 68.3,73.58 70.14,75.42 70.14,83.11 64.3,88.96 64.3,89.47 63.74,90.02 63.74,100.28 68.96,105.5 68.96,108.19 69.27,108.49 69.27,110.49 68.08,111.68 68.08,123.53 71.52,126.97 71.52,129.15 73.46,131.09 74.9,131.09 76.05,132.23 76.05,135.39 75.39,136.05 75.39,143.46 71.68,147.18 61.48,147.18 57.03,142.73 52.55,142.73 48.48,146.8 44.19,146.8 v1(43.39,146)
  BOTTOM w0.127: R427.1 v1(73.18,54.24)
  BOTTOM w0.132: U39.13 43.91,145.49 v1(43.39,146)
MCASP1_AXR2_BT: length 43.3
  TOP w0.132: J2.14 17.57,137.79 19.58,139.8 34.28,139.8 34.61,139.47 35.73,139.47 36.34,138.86 38.16,138.86 41.36,142.06 49.27,142.06 v1(49.84,141.49)
  BOTTOM w0.132: U40.2 49.67,141.66 v1(49.84,141.49)
MCASP1_AXR2_BUF: length 40.1
  TOP w0.132: v1(41.13,122.59) 40.74,122.59 40.68,122.53 RA1.5
  L03_SIG1 w0.107: v1(41.36,133.77) 42.83,135.24 42.83,136.33 v1(40.14,139.02)
  L06_SIG2 w0.107: v1(41.36,133.77) 41.36,132.62 40.88,132.14 40.88,124.14 40.55,123.81 40.55,123.18 v1(41.13,122.59)
  BOTTOM w0.132: U40.10 47.03,141.66 46.63,142.06 43.74,142.06 43.26,142.55 U39.12 43.26,145.46 42.94,145.77 42.94,146.68 42.6,147.02 40.81,147.02 40.14,146.36 v1(40.14,139.02)
MCASP1_BUF_BT_EN: length 152.1
  TOP w0.132: v1(50.44,142.62) 50.36,142.54 R10.2
  L03_SIG1 w0.107: v1(50.44,142.62) 51.3,141.77 58.15,141.77 61.89,145.5 72.04,145.5 74.5,143.04 74.5,135.97 73.97,135.44 73.97,133.36 70.62,130.01 70.62,127.36 67.18,123.92 67.18,120.73 66.42,119.96 66.42,113.23 67.01,112.65 67.01,111.38 67.26,111.12 67.26,105.22 65.2,103.16 64.22,103.16 62.91,101.85 59.7,101.85 59.13,101.27 59.13,90.32 59.45,90 59.45,88.92 62,86.36 62,85.68 64.81,82.88 65.68,82.88 68.45,80.11 68.45,75.32 66.27,73.14 66.27,54.83 67.18,53.92 67.18,46.48 63.92,43.21 59.35,43.21 59.05,43.51 58.2,43.51 v1(57.8,43.11)
  BOTTOM w0.127: U70.20 v1(57.8,43.11)
MCASP1_BUF_BT_EN_1V8: length 2.5
  TOP w0.132: v1(48.41,143.07) 48.4,143.07 48.41,143.06 48.41,142.56 R10.1 48.04,142.54 48.03,142.54 R11.2
  BOTTOM w0.132: U40.12 48.36,143.03 48.4,143.07 v1(48.41,143.07)
MCASP1_FET_EN: length 158.7
  L03_SIG1 w0.107: v1(58.72,43.11) 59.46,42.37 63.39,42.37 67.41,46.39 67.41,54.05 66.5,54.96 66.5,73.05 68.71,75.26 68.71,80.23 65.8,83.13 64.9,83.13 62.23,85.8 62.23,86.6 60.34,88.49 60.34,89.61 59.37,90.59 59.37,94.73 59.35,94.75 59.35,99.89 60.06,100.59 60.06,101.27 60.34,101.55 62.98,101.55 64.27,102.84 65.22,102.84 67.48,105.1 67.48,111.22 67.41,111.29 67.41,123.83 70.85,127.27 70.85,129.92 74.2,133.27 74.2,133.45 74.2,135.35 74.72,135.87 74.72,143.14 72.13,145.73 61.8,145.73 58.14,142.06 52.22,142.06 50.16,144.13 49.23,144.13 47.53,145.83 v1(46.49,145.83)
  BOTTOM w0.127: v1(58.72,43.11) 58.22,43.61 U70.19
  BOTTOM w0.132: v1(46.49,145.83) R259.1 R260.2 45.21,145.49 45.21,145.48 U39.15
MCASP1_FET_SEL: length 176.7
  TOP w0.132: R172.1 64.89,47.65 J12.1
  L03_SIG1 w0.107: v1(45.91,140.5) 47.02,139.39 49.85,139.39 52,141.54 53.91,141.54 55.16,140.29 56.99,140.29 61.99,145.28 71.95,145.28 74.28,142.95 74.28,136.06 73.66,135.44 73.66,133.36 71.15,130.85 71.15,130.85 70.4,130.1 70.4,127.45 66.95,124.01 66.95,120.9 66.16,120.11 66.16,107.91 64.77,106.53 64.77,105.69 63.09,104.01 60.85,104.01 57.92,101.08 57.92,90.12 61.78,86.26 61.78,85.59 64.74,82.63 65.62,82.63 68.22,80.02 68.22,75.41 66.05,73.24 66.05,54.74 66.96,53.83 66.96,46.78 63.68,43.5 60.5,43.5 59.49,44.51 57.64,44.51 57.4,44.28 57.4,42.95 57.73,42.62 58.21,42.62 v1(58.72,42.11)
  BOTTOM w0.127: U70.21 58.22,42.61 v1(58.72,42.11)
  BOTTOM w0.132: v1(58.72,42.11) 61.09,42.11 61.99,41.21 62.48,41.21 62.74,40.95 64.1,40.95 64.55,41.39 64.55,46.24 64.9,46.59 J12.1 ; v1(45.91,140.5) 45.91,140.1 45.86,140.05 U39.1
MCU_GPIO0_15: length 39.2
  TOP w0.132: R584.2 22.96,97.43 22.72,97.2 v1(22.16,97.2)
  L03_SIG1 w0.107: J10.10 23.2,66.02 21.22,66.02 20.39,66.85 20.39,76.73 19.99,77.13 19.99,82.41 19.61,82.79 19.61,83.92 18.19,85.34 18.19,86.33 18.48,86.63 18.48,87.93 18.27,88.13 18.27,92.03 20.7,94.45 20.7,94.98 22.16,96.44 v1(22.16,97.2)
MCU_GPIO0_15_R: length 12.1
  TOP w0.127: U12.D5 v1(30.47,100.53)
  TOP w0.132: R585.2 21.89,98.43 22.84,98.43 R584.1 23.37,98.3 23.7,98.63 23.7,98.64 v1(23.69,98.64)
  L03_SIG1 w0.107: v1(30.47,100.53) 30.07,100.94 28.7,100.94 28.5,101.14 28.5,101.14 28.47,101.17 28.47,101.5 28.47,101.51 28.47,101.51 28.24,101.73 27.79,101.73 27.53,101.47 27.53,100.51 27.41,100.38 26.04,100.38 24.28,98.63 23.7,98.63 23.7,98.64 v1(23.69,98.64)
MCU_GPIO0_16: length 55.3
  TOP w0.127: U12.D6 v1(30.47,101.33)
  L06_SIG2 w0.107: v1(30.47,101.33) 30.89,100.92 30.89,90.57 32.84,88.61 32.84,86.5 32.84,86.5 32.84,86.18 32.84,86.17 32.84,74.73 37.2,70.38 v1(37.2,69.33)
  BOTTOM w0.132: J10.11 28.03,61.2 37.59,61.2 38.39,62 38.39,68.13 v1(37.2,69.33)
MCU_I2C0_SCL: length 62.8
  TOP w0.132: U12.B9 v1(28.07,102.94)
  L03_SIG1 w0.107: v1(22.48,91.77) 21.72,91.01 21.72,88.84 21.93,88.63 21.93,83.96 22.98,82.91 22.98,77.35 21.49,75.86 21.49,71.17 23.33,69.34 24.21,69.34 25.72,70.85 33.82,70.85 38.87,65.79 41.21,65.79 J10.24
  BOTTOM w0.132: R416.2 42.25,66.47 42.25,66.46 J10.24 ; v1(28.07,102.94) 28.07,101.9 23.12,96.95 23.12,92.41 v1(22.48,91.77)
MCU_I2C0_SDA: length 63.8
  TOP w0.132: U12.A10 27.31,104.13 27.26,104.09 v1(27.14,104.09)
  L03_SIG1 w0.107: J10.21 38.46,63.46 38.46,65.69 33.56,70.6 25.78,70.6 24.3,69.12 23.08,69.12 21.27,70.93 21.27,75.95 22.62,77.3 22.62,82.87 22.6,82.88 22.6,82.91 21.69,83.83 21.69,88.52 21.38,88.82 21.38,91.64 v1(21.41,91.67)
  BOTTOM w0.132: v1(21.41,91.67) 21.8,92.06 21.8,96.05 27.67,101.91 27.67,103.56 v1(27.14,104.09) ; J10.21 39.71,60.93 39.71,60.92 R419.2
MCU_MCAN0_RX: length 41.2
  TOP w0.127: U12.C4 v1(28.87,99.73)
  L06_SIG2 w0.107: v1(28.87,99.73) 29.27,99.33 29.27,96.4 28.97,96.1 28.97,84.34 31.82,81.48 31.82,76.97 31.99,76.8 31.99,71.92 32.68,71.23 34.3,71.23 39.71,65.82 J10.22
MCU_MCAN0_TX: length 47.7
  TOP w0.127: U12.C5 v1(29.67,100.53)
  BOTTOM w0.132: J10.16 31.07,65.77 31.07,69.43 32.79,71.14 32.79,72.71 31.58,73.92 31.58,76.28 31.58,76.29 31.58,80.33 31.11,80.8 29.91,80.8 27.26,83.45 25.74,83.45 24.81,84.38 24.81,87.85 25.92,88.96 25.92,91.41 23.45,93.87 23.45,96.48 27.12,100.14 29.27,100.14 v1(29.67,100.53)
MCU_OSC0_XI: length 4.9
  TOP w0.127: R70.2 R71.2
  TOP w0.132: U12.A5 24.83,100.13 24.63,100.33 R71.2
MCU_OSC0_XO: length 5
  TOP w0.127: U12.A6 24.81,100.94 24.35,101.4 R66.2 R65.2
MCU_PORZ: length 91.6
  TOP w0.127: TP71.1 57.11,38.65 v1(57.14,38.62) 57.01,38.49 R183.1
  TOP w0.132: v1(25.42,97.11) 25.78,97.48 26.93,97.48 27.1,97.31 28.04,97.31 U12.B2
  L03_SIG1 w0.107: v1(57.14,38.62) 57.14,39.41 55.4,41.15 55.4,44.41 54.62,45.19 54.62,56.4 55.26,57.04 55.26,62.96 52.59,65.63 52.59,67.77 49.98,70.38 44.91,70.38 42.22,73.07 29.67,73.07 28.33,74.41 28.33,76.72 29.21,77.6 29.21,83.44 26.87,85.79 26.87,88.62 23.81,91.68 23.81,96.45 24.47,97.11 v1(25.42,97.11)
  BOTTOM w0.127: v1(57.14,38.62) 57.01,38.49 R183.1 U72.4
MCU_RESETSTATZ: length 93.4
  TOP w0.132: v1(16.57,90.71) 16.57,93.02 17.29,93.73 18.96,93.73 19.35,94.12 19.35,96.19 19.21,96.33 15.55,96.33 15.33,96.54 14.68,96.54 14.35,96.88 14.35,98.45 13.56,99.24 13.56,100.18 15.11,101.73 16.48,101.73 16.81,101.4 17.53,101.4 17.87,101.73 17.87,101.74 18.03,101.89 18.27,102.12 19.84,102.12 20.46,102.74 20.46,103.89 21.73,105.16 TP20.1 22.56,105.16 22.85,104.88 25.03,104.88 26,105.86 26.79,105.86 26.92,105.74 27.28,105.74 U12.A12 ; v1(17.24,60.37) 17.38,60.5 40.53,60.5 J10.23
  L03_SIG1 w0.107: v1(17.24,60.37) 17.96,61.09 17.96,80.06 16.33,81.69 16.33,83.34 15.65,84.02 15.65,89.79 v1(16.57,90.71)
  BOTTOM w0.132: R420.1 17.62,59.99 v1(17.24,60.37)
MCU_RESETZ: length 119
  TOP w0.132: v1(28.89,102.98) 28.92,102.98 U12.C9 ; TP82.1 39.31,24.11 v1(38.72,24.11)
  L06_SIG2 w0.107: v1(28.89,102.98) 29.27,102.6 29.27,100.26 29.16,100.15 28.68,100.15 28.48,99.96 28.48,97.06 28.58,96.96 28.58,84.24 31.63,81.19 31.63,76.82 31.74,76.71 31.74,71.81 33.69,69.86 33.69,67.88 31.68,65.87 26.27,65.87 25.96,65.56 25.96,52.54 33.08,45.42 49.04,45.42 50.15,44.31 50.15,40.5 49.95,40.3 49.95,32.65 49.36,32.06 49.36,29.04 45.55,25.23 39.84,25.23 v1(38.72,24.11)
  BOTTOM w0.127: v1(38.72,24.11) 38.72,23.76 38.85,23.63 R496.2 39.34,23.24 39.49,23.09 U81.7
MCU_SAFETY_ERRORZ_1V8: length 13.1
  TOP w0.102: U12.B1 28.22,96.68 28.22,93.11 27.7,92.59 24.32,92.59 23.76,92.03 23.76,89.39 TP36.1
  TOP w0.127: TP36.1 24.04,88.71 24.14,88.61 U19.3
MCU_SAFETY_ERRORZ_3V3: length 43.8
  TOP w0.127: U19.6 24.14,86.29 v1(23.99,86.14)
  L03_SIG1 w0.107: J10.26 43.54,66 38.98,66 33.91,71.07 25.63,71.07 24.12,69.56 23.42,69.56 21.71,71.27 21.71,75.76 23.21,77.25 23.21,85.36 v1(23.99,86.14)
MCU_SPI0_CLK: length 57.5
  TOP w0.132: v1(28.08,101.35) 28.09,101.35 U12.B7
  L03_SIG1 w0.107: v1(28.08,101.35) 28.08,101.14 28.46,100.77 28.46,100.39 27.98,99.91 26.36,99.91 21.21,94.77 21.21,94.24 19.56,92.59 19.56,90.23 21.4,88.4 21.4,83.71 22.31,82.79 22.31,77.4 20.98,76.07 20.98,70.78 22.94,68.83 24.42,68.83 25.9,70.31 33.33,70.31 34.63,69.01 J10.18
MCU_SPI0_CS1: length 48.5
  TOP w0.127: U12.C8 28.88,102.14 v1(28.86,102.14)
  L03_SIG1 w0.107: v1(28.86,102.14) 28.47,102.54 27.1,102.54 26.57,102.01 26.07,102.01 25.37,101.3 25.33,101.3 25.32,101.3 23.34,101.3 22.07,100.03 21.36,100.03 20.16,98.83 20.16,98.39 19.63,97.87 19.63,96.97 18.06,95.4 18.06,94.29 17.02,93.24 17.02,91.77 17.7,91.08 17.7,87.15 17.53,86.97 17.53,85.62 19.38,83.77 19.38,82.7 19.76,82.32 19.76,77.05 20.17,76.64 20.17,66.52 J10.8
MCU_SPI0_D0: length 64.6
  TOP w0.127: U12.E8 v1(30.47,102.14)
  BOTTOM w0.132: v1(30.47,102.14) 30.07,101.73 30.07,99.51 28.99,98.43 25.79,98.43 23.71,96.35 23.71,94.01 26.2,91.52 26.2,88.76 25.09,87.65 25.09,84.49 25.86,83.73 28.55,83.73 29.8,82.48 30.46,82.48 31.81,81.13 31.81,77.28 32.57,76.53 32.57,73.44 33.28,72.73 33.28,64.42 32.42,63.56 20.58,63.56 J10.6
MCU_SPI0_D1: length 69.2
  TOP w0.127: U12.D8 v1(29.67,102.14)
  BOTTOM w0.132: J10.4 18.37,63.24 32.83,63.24 33.61,64.01 33.61,73.02 32.85,73.78 32.85,77.41 32.05,78.21 32.05,81.23 30.52,82.76 29.92,82.76 28.67,84.01 27.21,84.01 26.05,85.17 26.05,87.24 26.48,87.68 26.48,92.36 26.18,92.67 25.46,92.67 23.97,94.16 23.97,96.28 25.84,98.15 29.09,98.15 29.57,98.64 30.26,98.64 30.87,99.25 30.87,102.39 30.73,102.53 30.07,102.53 v1(29.67,102.14)
MCU_UART0_CTS: length 38
  TOP w0.132: U26.9 28.89,71.57 v1(29.32,72) ; U12.B8 28.08,102.14 26.73,102.14 26.6,102.01 26.12,102.01 25.88,102.24 v1(25.49,102.24)
  L06_SIG2 w0.107: v1(29.32,72) 26.29,75.04 26.29,79.15 24.57,80.86 24.57,88.41 24.36,88.62 24.36,90.81 23.88,91.29 23.88,96.72 25.82,98.66 25.82,100.3 25.82,101.91 v1(25.49,102.24)
MCU_UART0_CTS_3V3: length 66.5
  TOP w0.132: U26.11 26.33,70.27 23.93,67.87 v1(23.31,67.87)
  L03_SIG1 w0.107: v1(30.72,18.84) 30.45,18.84 27.19,22.11 24.77,22.11 24.09,22.79 24.09,30.62 26.58,33.11 26.58,34.78 26.04,35.31 26.04,46.15 26.98,47.09 26.98,51.65 28.13,52.79 28.13,66.76 27.02,67.87 v1(23.31,67.87)
  BOTTOM w0.127: U83.9 30.41,19.16 v1(30.72,18.84)
MCU_UART0_CTS_CONN: length 9.2
  TOP w0.132: J10.12 28.48,66.23 29.15,66.23 30.02,67.1 30.02,70.38 29.48,70.92 U26.10
MCU_UART0_MUX_OE: length 1.9
  TOP w0.132: R140.1 26.93,68.04 27.3,67.67 U26.15
MCU_UART0_MUX_SEL: length 49.1
  TOP w0.132: v1(19.85,61.04) 20.11,60.78 35.08,60.78 35.69,61.39 35.69,66.59 R142.2 33.92,66.96 U26.1
  L06_SIG2 w0.107: v1(19.85,61.04) 18.39,59.59 13.92,59.59 6.01,67.5 6.01,71.23 5.27,71.97 3.19,71.97 J8.2
MCU_UART0_RTS: length 36.4
  TOP w0.127: U12.D7 v1(29.67,101.34)
  TOP w0.132: v1(29.48,69.44) 29.3,69.62 U26.12
  L06_SIG2 w0.107: v1(29.67,101.34) 30.05,100.95 30.05,90.64 31.91,88.78 31.91,82.49 32.17,82.23 32.17,81.53 32.04,81.39 32.04,77.07 32.54,76.57 32.54,72.29 v1(32.39,72.14)
  BOTTOM w0.132: v1(32.39,72.14) 29.97,69.72 29.76,69.72 v1(29.48,69.44)
MCU_UART0_RTS_3V3: length 56.6
  TOP w0.132: U26.14 29.45,68.32 v1(29.45,68.32)
  L03_SIG1 w0.107: v1(29.45,68.32) 30.77,67 30.77,54.09 30.03,53.35 29.52,53.35 27.87,51.69 27.87,46.94 26.49,45.57 26.49,36.29 28.31,34.47 28.31,33.06 27.83,32.57 27.83,23.14 31.11,19.86 v1(32.01,19.86)
  BOTTOM w0.127: U83.7 31.64,20.23 v1(32.01,19.86)
MCU_UART0_RTS_CONN: length 20.1
  TOP w0.132: U26.13 25.74,68.97 24.77,68 24.77,66 25.57,65.2 25.57,61.82 26.19,61.2 33.61,61.2 J10.17
MCU_UART0_RX_3V3: length 59.5
  TOP w0.132: v1(32.74,67.67) U26.2
  L03_SIG1 w0.107: v1(31.64,18.84) 32.5,19.7 32.5,20.87 32.2,21.17 30.49,21.17 28.36,23.31 28.36,32.44 28.87,32.96 28.87,42.9 28.31,43.46 28.31,51.5 29.37,52.56 32.9,52.56 33.59,53.25 33.59,66.82 v1(32.74,67.67)
  BOTTOM w0.127: v1(31.64,18.84) 31.64,19.42 31.22,19.83 U83.8
MCU_UART0_RXD: length 38.7
  TOP w0.132: U12.A8 26.45,102.53 v1(26.35,102.44) ; U26.4 v1(32.62,68.97)
  L06_SIG2 w0.107: v1(32.62,68.97) 32.62,69.35 31.23,70.75 31.23,76.42 30.71,76.94 30.71,78.13 29.37,79.47 29.37,80.58 28.08,81.87 28.08,96.78 27.57,97.29 27.57,101.22 v1(26.35,102.44)
MCU_UART0_RXD_CONN: length 9.3
  TOP w0.132: J10.13 30.86,63.53 30.86,67.76 31.42,68.32 U26.3
MCU_UART0_TX_3V3: length 60.1
  TOP w0.132: v1(31.96,69.34) 32.35,69.34 32.63,69.62 U26.5
  L03_SIG1 w0.107: v1(32.01,20.77) 30.57,20.77 28.13,23.21 28.13,32.55 28.54,32.96 28.54,34.6 27.9,35.24 27.9,41.58 28.4,42.08 28.4,42.98 28.09,43.29 28.09,51.6 29.33,52.84 32.47,52.84 33.31,53.68 33.31,65.24 32.31,66.23 32.31,68.54 31.96,68.89 v1(31.96,69.34)
  BOTTOM w0.127: R516.2 32.22,20.56 v1(32.01,20.77) 31.87,20.63 U83.6
MCU_UART0_TXD: length 56
  TOP w0.127: v1(28.08,100.54) U12.B6
  TOP w0.132: U26.7 32.9,70.92 31.42,72.4 27.74,72.4 23.6,68.27 23.15,68.27 21.93,67.05 v1(21.93,66.58)
  L03_SIG1 w0.107: v1(28.08,100.54) 27.7,100.16 26.19,100.16 20.92,94.89 20.92,94.36 19.27,92.71 19.27,90.11 21.09,88.29 21.09,83.61 21.42,83.28 21.42,77.35 20.69,76.62 20.69,67.82 v1(21.93,66.58)
MCU_UART0_TXD_CONN: length 10.7
  TOP w0.132: J10.19 35.97,63.42 35.97,65.46 36.58,66.08 36.58,68.82 35.13,70.27 U26.6
MFP0: length 2.8
  TOP w0.127: R156.1 v1(76.19,53.02)
  BOTTOM w0.127: U66.45 75.66,52.07 76.19,52.6 v1(76.19,53.02) R156.1
MFP1: length 4
  TOP w0.127: R157.1 77.1,53.15 77.21,53.04 v1(77.61,53.04)
  BOTTOM w0.127: 77.28,53.02 77.04,53.02 76.16,52.14 U66.46 ; 77.28,53.02 77.58,53.02 v1(77.61,53.04) ; 77.28,53.02 77.1,53.19 R157.1
MFP2: length 3.1
  TOP w0.127: v1(78.11,52.47) 77.82,52.47 77.69,52.33 TP58.1
  BOTTOM w0.127: v1(78.11,52.47) 76.99,52.47 76.66,52.14 U66.47
MFP3: length 3.4
  TOP w0.127: TP59.1 79.12,52.21 79.12,52.4 v1(78.84,52.67)
  BOTTOM w0.127: v1(78.84,52.67) 78.56,52.4 78.56,52.29 78.38,52.11 78.3,52.11 78.27,52.07 77.94,52.07 77.93,52.09 77.43,52.09 77.16,51.82 U66.48
MIC_IN: length 6.3
  TOP w0.127: v1(79.34,42.32) 81.09,42.32 82.88,40.54 J14.1
MMC0_CLK: length 20.1
  TOP w0.127: v1(50.38,79.36) 50.38,79.11 U21.M6
  TOP w0.132: R91.1 v1(44.96,92.9)
  BOTTOM w0.127: R400.1 51.12,79.01 50.77,79.36 v1(50.38,79.36) 49.69,78.67 R401.2
  BOTTOM w0.132: v1(44.96,92.9) 47,90.86 47,90.1 49.97,87.13 49.97,86.59 51.28,85.28 51.28,81.37 50.78,80.87 50.78,79.76 v1(50.38,79.36)
MMC1_CLK: length 34.5
  TOP w0.127: R88.1 7.28,94.67 6.78,95.17 v1(6.78,95.29) 7.57,95.29 7.7,95.42 U15.6
  TOP w0.132: v1(23.88,110.98) 23.88,111.4 R51.1 23.78,112.3 R49.1
  BOTTOM w0.127: v1(6.78,95.29) 6.23,95.84 5.62,95.84 5.11,96.36 J21.5
  BOTTOM w0.132: v1(23.88,110.98) 22.96,111.9 19.91,111.9 19.55,111.54 19.55,110.48 19.18,110.11 19.18,109.66 18.22,108.7 17.46,108.7 15.41,106.64 15.41,103.84 13.41,101.84 13.17,101.84 11.44,100.11 11.44,97.72 10.14,96.43 7.91,96.43 v1(6.78,95.29)
MMC1_CLK_R: length 5.1
  TOP w0.132: U12.A20 27,112.81 23.35,112.81 23.2,112.66 R49.2
MMC1_CMD: length 37.9
  TOP w0.127: U12.C18 v1(28.87,110.93) ; R73.1 9.3,98.03 v1(9.38,97.95) 9.2,97.77 U15.1
  L03_SIG1 w0.107: v1(9.38,97.95) 9.38,99.29 9.33,99.34 9.33,104.6 15.52,110.79 17.83,110.79 18.98,111.94 24.35,111.94 26.1,110.19 27.03,110.19 27.67,110.83 27.67,111.06 27.93,111.31 28.4,111.31 28.78,110.93 v1(28.87,110.93)
  BOTTOM w0.127: v1(9.38,97.95) 9.01,97.58 6.47,97.58 5.5,98.56 J21.3
MMC1_D0: length 39.6
  TOP w0.127: U15.8 8.7,95.46 9.1,95.06 v1(9.3,95.06) 9.3,94.74 R90.1
  TOP w0.132: v1(26.07,111.15) 26.25,111.34 U12.A19
  L03_SIG1 w0.107: v1(9.3,95.06) 9,95.36 9,105.59 14.48,111.08 17.71,111.08 18.86,112.23 24.34,112.23 25.42,111.15 v1(26.07,111.15)
  BOTTOM w0.127: v1(9.3,95.06) 8.85,95.51 7.59,95.51 6.24,94.16 J21.7
MMC1_D1: length 40.1
  TOP w0.127: U15.7 8.2,95.28 v1(8.37,95.11) 8.2,94.94 R89.1
  TOP w0.132: v1(28.08,110.96) 28.09,110.96 U12.B19
  L03_SIG1 w0.107: v1(28.08,110.96) 28.08,110.95 27.12,109.99 26.02,109.99 24.58,111.43 23.36,111.43 22.95,111.03 21.78,111.03 21.32,111.49 19.9,111.49 18.4,109.99 15.54,109.99 10.14,104.6 10.14,99.07 9.88,98.8 9.88,95.09 9.46,94.67 8.8,94.67 v1(8.37,95.11)
  BOTTOM w0.127: J21.8 5.69,93.06 7.74,95.11 v1(8.37,95.11)
MMC1_D2: length 37.5
  TOP w0.127: U15.2 8.7,97.77 v1(8.49,97.98) 8.49,97.98 R74.1
  TOP w0.132: U12.B20 28.1,111.76 27.52,111.76 27.41,111.87 v1(26.5,111.87)
  L03_SIG1 w0.107: v1(8.49,97.98) 8.49,105.55 15.47,112.52 24.46,112.52 25.1,111.87 v1(26.5,111.87)
  BOTTOM w0.127: J21.1 6.21,100.76 8.49,98.47 v1(8.49,97.98)
MMC1_D3: length 37.6
  TOP w0.127: U12.C19 v1(28.87,111.73) ; U15.3 8.2,97.49 7.42,98.26 R75.1 7.4,98.46 v1(6.84,98.46)
  L03_SIG1 w0.107: v1(28.87,111.73) 27.32,111.73 26.78,112.28 24.98,112.28 24.42,112.83 14.08,112.83 11.44,110.19 11.44,109.03 8.2,105.79 8.2,99.82 v1(6.84,98.46)
  BOTTOM w0.127: J21.2 5.57,99.66 6.77,98.46 v1(6.84,98.46)
MMC1_SD_EN: length 115.5
  L03_SIG1 w0.107: v1(20.32,92.49) 20.89,93.07 21.94,93.07 22.93,92.07 22.93,91.39 22.63,91.09 22.63,88.52 24.41,86.74 24.41,86 23.43,85.02 23.43,77.16 21.94,75.67 21.94,71.63 23.13,70.44 24.67,70.44 25.53,71.3 34,71.3 39.07,66.23 44.89,66.23 45.92,65.2 45.92,61.93 46.62,61.22 46.62,44.99 48.82,42.79 v1(48.82,42.37) ; v1(18.35,110.5) 15.64,110.5 9.71,104.57 v1(9.71,99.6)
  L06_SIG2 w0.107: v1(20.32,92.49) 20.32,92.51 20.5,92.68 20.5,95.75 19.5,96.75 18.77,96.75 18.25,97.27 15.54,97.27 12.9,99.9 10.01,99.9 v1(9.71,99.6)
  BOTTOM w0.127: v1(48.82,42.37) 48.82,42.37 R462.1 49.71,42.37 49.95,42.61 U70.4
  BOTTOM w0.132: U52.1 16.21,111.66 16.32,111.77 17.66,111.77 18.35,111.08 v1(18.35,110.5)
MMC1_SD_LS_EN: length 10.2
  TOP w0.127: 12.25,104.78 R61.1 12.25,104.24 U13.3
  TOP w0.132: v1(15.1,108.98) 14.7,108.98 14.58,109.1 12.96,109.1 12.25,108.39 12.25,104.78
  BOTTOM w0.132: U52.4 15.64,110.1 15.1,109.56 v1(15.1,108.98)
MMC1_SDCD: length 55.8
  TOP w0.127: U12.C15 v1(28.87,108.53)
  TOP w0.132: v1(2.07,102.01) R67.1 1.54,101.48 1.38,101.33 1.38,99.34 1.59,99.13 U14.5
  L03_SIG1 w0.107: v1(28.87,108.53) 29.31,108.09 29.82,108.09 30.11,107.8 30.11,107.59 30.32,107.37 30.54,107.37 30.83,107.08 30.83,105.99 30.62,105.78 30.32,105.78 30.03,106.07 30.03,106.28 29.8,106.51 27.9,106.51 26.86,107.55 23.73,107.55 23.46,107.82 22.86,107.82 22.51,107.48 16.95,107.48 14.79,105.31 14.79,99.15 15.17,98.77 v1(15.17,96.15)
  L06_SIG2 w0.107: v1(2.07,102.01) 2.88,102.83 7.83,102.83 8.43,102.23 8.43,98.88 8.88,98.44 8.88,97.78 9.95,96.7 13.43,96.7 13.99,96.15 v1(15.17,96.15)
  BOTTOM w0.127: v1(15.17,96.15) 15.66,96.15 15.84,95.98 J21.9
MMC2_CLK: length 49.5
  TOP w0.132: v1(27.05,135.97) R282.1 27.61,135.33 28.17,134.77 28.17,127 27.69,126.52 27.69,123.14 29.08,121.74 R272.1 29.06,120.93 R40.2 ; J2.9 3.83,136.54 v1(3.85,136.56)
  L03_SIG1 w0.107: v1(3.85,136.56) 3.49,136.56 3.27,136.34 3.27,135.91 2.62,135.26 2.62,134.01 2.98,133.64 5.48,133.64 7.7,135.87 9.34,135.87 11.12,134.1 16.27,134.1 17,134.82 26.72,134.82 27.05,135.15 v1(27.05,135.97)
MMC2_CMD: length 7.5
  TOP w0.132: R275.2 26.21,117.65 27.38,116.48 28.41,116.48 29.49,115.41 29.49,113.59 29.27,113.37 U12.C21
MMC2_D0: length 8.1
  TOP w0.132: U12.B21 29.25,113.72 29.25,115.31 28.39,116.18 27.08,116.18 25.27,117.98 R277.2
MMC2_D1: length 6.4
  TOP w0.132: R276.2 27.51,117.36 27.67,117.19 28.54,117.19 30.07,115.67 30.07,113.31 30.07,113.31 U12.D21
MMC2_D2: length 7.6
  TOP w0.127: U12.E19 v1(30.47,111.73)
  TOP w0.132: v1(31.14,115.28) 31.14,115.28 31.14,116.1 30.04,117.2 30.04,118.06 R274.2
  L06_SIG2 w0.107: v1(30.47,111.73) 30.47,114.61 v1(31.14,115.28)
MMC2_D3: length 6.7
  TOP w0.132: U12.E20 30.48,112.53 30.48,113.23 30.3,113.4 30.3,115.93 28.51,117.73 R273.2
Net_4: length 91.1
  TOP w0.132: 27.67,103.34 v1(27.27,102.94)
  L06_SIG2 w0.107: v1(46.62,138.16) 46.21,138.57 39.42,138.57 37.53,136.68 13.87,136.68 11.82,134.63 10.65,134.63 7.51,131.49 7.51,127.96 5.52,125.97 5.52,108.84 10.29,104.07 12.86,104.07 13.21,103.72 16.57,103.72 16.85,103.44 20.51,103.44 20.97,102.98 23.96,102.98 24.8,103.82 25.9,103.82 26.35,103.36 26.84,103.36 v1(27.27,102.94)
OLDI_RESETN: length 29
  L06_SIG2 w0.107: v1(61.14,75.57) 62.53,74.17 62.53,64.47 62.01,63.94 61.32,63.94 61.08,64.19 58.84,64.19 v1(53.78,69.25)
  BOTTOM w0.132: v1(61.14,75.57) 60.92,75.35 J22.8 ; v1(53.78,69.25) 52.36,69.25 51.3,70.31 U62.4 49.94,70.31 49.92,70.29 R412.2
OSC0: length 5
  TOP w0.127: U36.88 59.17,25.25 C154.2 59.43,25.55 58.92,26.07 58.92,27.66 59.06,27.8 Y3.3
OSC1: length 3.3
  TOP w0.127: Y3.1 58.24,26.21 58.38,26.07 C153.2 58.77,25.17 U36.89
OSPI0_CSN0: length 7.3
  TOP w0.127: U12.F19 v1(31.27,111.73)
  BOTTOM w0.132: R334.2 32.06,117.23 30.74,115.91 30.74,112.53 31.27,112.01 v1(31.27,111.73)
OSPI0_LBCLK: length 15.6
  L03_SIG1 w0.107: v1(35.91,119.93) 40.15,119.93 41.28,121.06 41.47,121.06 41.89,121.49 41.89,121.69 43.03,122.83 44.66,122.83 44.79,122.96 46.22,122.96 46.72,122.46 46.72,122.11 47.36,121.47 v1(48.01,121.47)
  BOTTOM w0.132: R318.1 35.85,119.87 v1(35.91,119.93) ; R307.2 v1(48.01,121.47)
OSPI0_LBCLKO_R: length 10.7
  TOP w0.127: U12.G18 v1(32.07,110.93)
  BOTTOM w0.132: v1(32.07,110.93) 32.47,111.33 32.47,116.4 34.42,118.35 35.66,118.35 35.85,118.54 R318.2
OSPI_CLK: length 25.4
  TOP w0.132: v1(32.07,114.5) 32.78,115.21 32.78,116.87 32.68,116.97 32.68,118.05 32.67,118.06 v1(32.67,120.02) ; U10.B2 v1(45.16,120.4)
  L03_SIG1 w0.107: v1(45.16,120.4) 45.5,120.73 45.5,121.15 45.18,121.47 44.15,121.47 43.45,120.76 43.11,120.76 42.83,120.49 42.83,120.13 43.03,119.94 43.53,119.94 43.69,119.77 43.69,119.26 43.43,119 41.55,119 41.3,119.25 33.23,119.25 32.67,119.8 v1(32.67,120.02)
  BOTTOM w0.132: R309.1 v1(45.16,120.4) ; v1(32.07,114.5) 31.85,114.29 R316.1
OSPI_CS: length 21.3
  TOP w0.132: v1(46.16,122.4) U10.C2 46.19,121.37 47.23,121.37 48.03,122.16 R37.1
  L03_SIG1 w0.107: v1(46.16,122.4) 46.16,120.09 45.35,119.27 44.71,119.27 43.79,118.35 40.96,118.35 40.59,117.97 40.26,117.97 40.03,118.19 34.17,118.19 33.77,117.79 v1(33.08,117.79)
  BOTTOM w0.132: R334.1 33.03,117.79 v1(33.08,117.79)
OSPI_DQ0: length 21.7
  TOP w0.132: U10.D3 v1(44.16,122.4) ; v1(31.05,119.9) RA2.4
  L03_SIG1 w0.107: v1(31.05,119.9) 31.56,119.9 31.7,119.75 32.01,119.75 32.85,118.92 40.96,118.92 41.22,118.66 43.65,118.66 44.7,119.71 45.28,119.71 45.84,120.28 45.84,121.67 45.47,122.05 44.51,122.05 v1(44.16,122.4)
  BOTTOM w0.132: v1(31.05,119.9) 31.17,119.91 31.34,119.76 31.34,119.44 R324.1
OSPI_DQ1: length 23.5
  TOP w0.132: v1(44.26,125.52) 45.2,124.59 45.2,123.36 U10.D2 ; v1(31.48,121.19) 31.48,120.8 31.45,120.76 RA2.3
  L03_SIG1 w0.107: v1(31.48,121.19) 31.48,121.58 32.82,122.92 39.09,122.92 39.85,123.68 39.85,123.93 40.61,124.69 43.43,124.69 v1(44.26,125.52)
  BOTTOM w0.132: R326.1 29.75,119.78 29.75,119.78 29.75,120.41 30.54,121.19 v1(31.48,121.19)
OSPI_DQ2: length 29
  TOP w0.132: v1(32.29,121.22) 32.29,120.82 32.27,120.8 32.27,119.3 32.25,119.28 RA2.1 ; U10.C4 v1(43.16,122.4)
  L03_SIG1 w0.107: v1(43.16,122.4) 43.46,122.1 43.46,121.23 43.37,121.14 43.24,121.14 43.14,121.25 43.14,121.8 43.06,121.88 42.91,121.88 42.86,121.83 42.86,120.92 42.79,120.85 42.67,120.85 42.61,120.91 42.61,121.83 42.55,121.88 42.4,121.88 42.31,121.79 42.31,119.63 42.22,119.54 42.12,119.54 42.05,119.62 42.05,120.84 41.98,120.9 41.83,120.9 41.77,120.84 41.77,120.45 41.63,120.31 40.99,120.31 40.88,120.2 40.88,120.03 40.98,119.93 41.66,119.93 41.77,119.82 41.77,119.64 41.66,119.54 33.38,119.54 33.08,119.84 33.08,120.18 32.99,120.27 32.99,121.86 32.87,121.99 32.66,121.99 32.29,121.62 v1(32.29,121.22)
  BOTTOM w0.132: R323.1 32.04,119.72 32.24,119.92 32.24,120.15 32.29,120.2 v1(32.29,121.22)
OSPI_DQ3: length 28.3
  TOP w0.132: v1(31.84,120.19) 31.84,119.64 31.85,119.64 RA2.2 ; v1(43.15,123.52) 43.15,123.52 43.16,123.5 43.16,123.39 U10.D4
  L03_SIG1 w0.107: v1(43.15,123.52) 42.84,123.83 42.66,123.83 42.55,123.71 42.55,123.32 42.46,123.23 42.25,123.23 42.13,123.36 42.13,123.72 41.95,123.9 40.88,123.9 40.52,123.54 40.52,123.4 39.35,122.23 35.31,122.23 35.17,122.09 35.17,121.15 34.88,120.86 33.54,120.86 33.33,121.07 33.33,122.39 33.14,122.58 32.87,122.58 31.89,121.6 31.89,120.91 31.75,120.77 31.32,120.77 31.07,121.01 31.07,121.63 31.95,122.51 31.95,122.67 31.8,122.82 31.64,122.82 30.63,121.82 30.63,121.09 31.53,120.19 v1(31.84,120.19)
  BOTTOM w0.132: v1(31.84,120.19) 31.55,120.48 31.02,120.48 30.51,119.97 R325.1
OSPI_DQ4: length 27.9
  TOP w0.132: v1(33.49,120.07) 33.48,120.07 33.3,119.89 33.3,119.58 33.49,119.39 RA3.4 ; U10.D5 42.18,123.38 v1(41.69,123.38)
  L03_SIG1 w0.107: v1(33.49,120.07) 34.05,120.63 34.97,120.63 35.42,121.08 35.42,121.75 35.64,121.98 38.39,121.98 38.44,121.93 38.44,121.8 38.36,121.73 35.94,121.73 35.82,121.61 35.82,121.5 35.92,121.4 37.37,121.4 37.46,121.31 37.46,121.17 37.4,121.12 35.85,121.12 35.8,121.07 35.8,120.95 35.85,120.89 36.64,120.89 36.74,120.8 36.74,120.54 36.83,120.45 36.96,120.45 37.06,120.54 37.06,120.8 37.15,120.89 37.28,120.89 37.38,120.8 37.38,120.54 37.47,120.45 37.6,120.45 37.7,120.54 37.7,120.8 37.79,120.89 37.92,120.89 38.02,120.8 38.02,120.54 38.11,120.45 38.25,120.45 38.34,120.54 38.34,120.8 38.43,120.89 38.76,120.89 39.51,121.64 39.51,122.02 39.61,122.12 39.77,122.12 39.85,122.04 39.85,121.46 39.93,121.39 40.03,121.39 40.11,121.46 40.11,122.28 40.2,122.37 40.33,122.37 40.42,122.28 40.42,121.91 40.52,121.8 40.67,121.8 40.78,121.91 40.78,122.38 40.73,122.42 40.73,122.78 40.94,122.99 41.3,122.99 v1(41.69,123.38)
  BOTTOM w0.132: R321.1 33.63,119.44 33.63,119.67 33.48,119.93 33.49,119.97 33.47,120.01 v1(33.49,120.07)
OSPI_DQ5: length 29.3
  TOP w0.132: v1(44.59,124.49) 44.66,124.42 U10.E3 ; v1(34.3,120.23) 34.3,119.78 34.3,119.77 34.3,119.59 34.29,119.59 RA3.2
  L03_SIG1 w0.107: v1(44.59,124.49) 45.07,124.01 48.68,124.01 49,124.32 49.63,124.32 49.87,124.08 49.87,123.63 49.67,123.43 47.99,123.43 47.46,122.89 46.82,122.89 46.28,123.43 45.16,123.43 44.6,124 43.91,124 43.54,123.64 43.54,123.36 43.28,123.09 42.91,123.09 41.91,122.09 41.41,122.09 40.29,120.97 40.29,120.47 40.05,120.23 36.18,120.23 36.08,120.33 35.74,120.33 35.29,119.89 34.64,119.89 v1(34.3,120.23)
  BOTTOM w0.132: v1(34.3,120.23) 34.02,120.51 33.28,120.51 33.08,120.31 33.08,119.67 32.8,119.39 R322.1
OSPI_DQ6: length 28.6
  TOP w0.132: v1(46.03,124.84) 45.66,124.48 U10.E2 ; RA3.3 33.89,120.69 33.77,120.82 33.77,120.85 33.74,120.87 v1(33.74,121.27)
  L03_SIG1 w0.107: v1(46.03,124.84) 46.48,124.38 47.42,124.38 48.03,124.99 49.25,124.99 49.41,125.15 49.41,125.5 49.25,125.65 45.54,125.65 45.01,125.12 44.22,125.12 43.56,124.46 43.53,124.46 40.82,124.46 40.08,123.72 40.08,123.59 39.18,122.7 34.05,122.7 33.74,122.38 v1(33.74,121.27)
  BOTTOM w0.132: R320.1 34.32,119.39 34.74,119.81 34.74,120.52 34.4,120.86 34.15,120.86 34.05,120.96 v1(33.74,121.27)
OSPI_DQ7: length 28.8
  TOP w0.132: v1(46.81,124.91) 46.66,124.76 U10.E1 ; RA3.1 34.69,119.25 34.78,119.34 34.78,120.43 34.17,121.04 34.17,121.65 33.99,121.83 32.83,121.83 32.72,121.93 32.72,122.23 32.85,122.36 33.97,122.36 34.07,122.46 34.07,122.83 34.2,122.96 34.5,122.96 34.63,122.83 v1(34.63,121.27)
  L03_SIG1 w0.107: v1(34.63,121.27) 34.34,121.27 34.08,121.52 34.08,122.21 34.33,122.46 39.26,122.46 40.3,123.5 40.3,123.63 40.81,124.14 43.58,124.14 44.34,124.9 45.29,124.9 45.82,125.42 47.11,125.42 47.27,125.26 47.27,125.04 47.14,124.91 v1(46.81,124.91)
  BOTTOM w0.132: R319.1 35.09,120.91 v1(34.63,121.27)
OSPI_DQS: length 2.5
  TOP w0.132: U10.C3 45.16,122.4 v1(45.16,122.53)
  BOTTOM w0.132: R308.1 45.89,121.47 45.53,121.82 45.53,122.16 v1(45.16,122.53)
OSPI_DQS_SOC: length 29.4
  TOP w0.132: U12.H20 33.69,112.56 33.69,113.21 34.38,113.9 34.38,115.99 v1(34.53,116.15)
  L03_SIG1 w0.107: v1(34.53,116.15) 34.17,116.51 34.17,117.36 34.79,117.97 39.83,117.97 40.09,117.71 40.09,117.42 40.31,117.2 40.63,117.2 41.44,118.02 44.69,118.02 44.83,118.16 44.83,118.48 44.98,118.62 45.18,118.62 45.32,118.49 45.32,118.16 45.46,118.02 45.66,118.02 45.81,118.16 45.81,118.48 45.95,118.62 46.16,118.62 46.29,118.49 46.29,118.16 46.44,118.02 47.42,118.02 47.73,118.33 47.73,118.96 47.54,119.15 46.89,119.15 46.75,119.29 46.75,119.52 46.91,119.67 47.55,119.67 47.73,119.85 47.73,120.22 47.55,120.4 v1(47.16,120.4)
  BOTTOM w0.132: v1(34.53,116.15) 34.24,116.15 34.11,116.01 R304.1 R305.1 ; R308.2 46.74,120.82 v1(47.16,120.4)
OSPI_RSTN: length 23
  TOP w0.132: v1(30.26,127.14) 30.95,127.14 31.35,126.73 31.35,125.17 31.17,124.99 U8.4 R35.1 ; U10.A4 43.27,119.51 v1(43.27,119.5)
  L06_SIG2 w0.107: v1(43.27,119.5) 42.51,119.5 41.82,120.19 41.82,121.73 41.6,121.96 40.77,121.96 39.22,123.51 39.22,124.05 38.85,124.42 38.55,124.42 36.04,126.93 30.85,126.93 30.64,127.14 v1(30.26,127.14)
P2_PP_EXT_ENABLE: length 15.4
  TOP w0.132: v1(11.11,34.55) 11.51,34.55 12.24,35.29 12.24,37.88 12.51,38.15 12.51,38.54 12.88,38.91 15.54,38.91 16.47,39.84 18.51,39.84 v1(19.3,40.63)
  BOTTOM w0.127: v1(11.11,34.55) 11.09,34.58 R476.1 ; U68.49 20.58,41.12 20.08,40.63 v1(19.3,40.63)
PD_GPIO0: length 1.6
  TOP w0.132: R166.2 17.68,49.34 v1(18.17,49.34)
  BOTTOM w0.132: U68.16 18.17,48.51 v1(18.17,49.34)
PD_HRESET: length 1.8
  BOTTOM w0.127: R466.1 23.2,40.72 22.58,41.34 U68.44
PD_M_I2C3_IRQ: length 2.2
  BOTTOM w0.127: R436.2 U68.23
PD_M_I2C3_SCL: length 28.5
  TOP w0.132: R146.1 8.01,64.45 7.73,64.17 v1(7.15,64.17) ; v1(20.25,49.79) 19.95,49.49 R164.2
  L06_SIG2 w0.107: v1(20.25,49.79) 17.74,49.79 16.01,51.52 15.33,51.52 14.51,52.33 9.59,52.33 8.09,53.84 8.09,54.49 6.56,56.02 6.56,63.58 v1(7.15,64.17)
  BOTTOM w0.127: U68.21 20.18,49.28 20.25,49.36 v1(20.25,49.79)
PD_M_I2C3_SDA: length 26.4
  TOP w0.132: v1(20.26,50.75) 20.23,50.73 20.23,50.55 20.1,50.42 R161.2 ; R150.1 8.01,61.71 7.86,61.55 v1(7.2,61.55)
  L06_SIG2 w0.107: v1(7.2,61.55) 6.82,61.17 6.82,56.12 8.34,54.6 8.34,53.95 9.67,52.61 14.68,52.61 15.47,51.82 16.29,51.82 17.37,50.74 20.24,50.74 v1(20.26,50.75)
  BOTTOM w0.127: v1(20.26,50.75) 20.26,50.36 20.66,49.95 20.66,49.11 20.58,49.03 U68.22
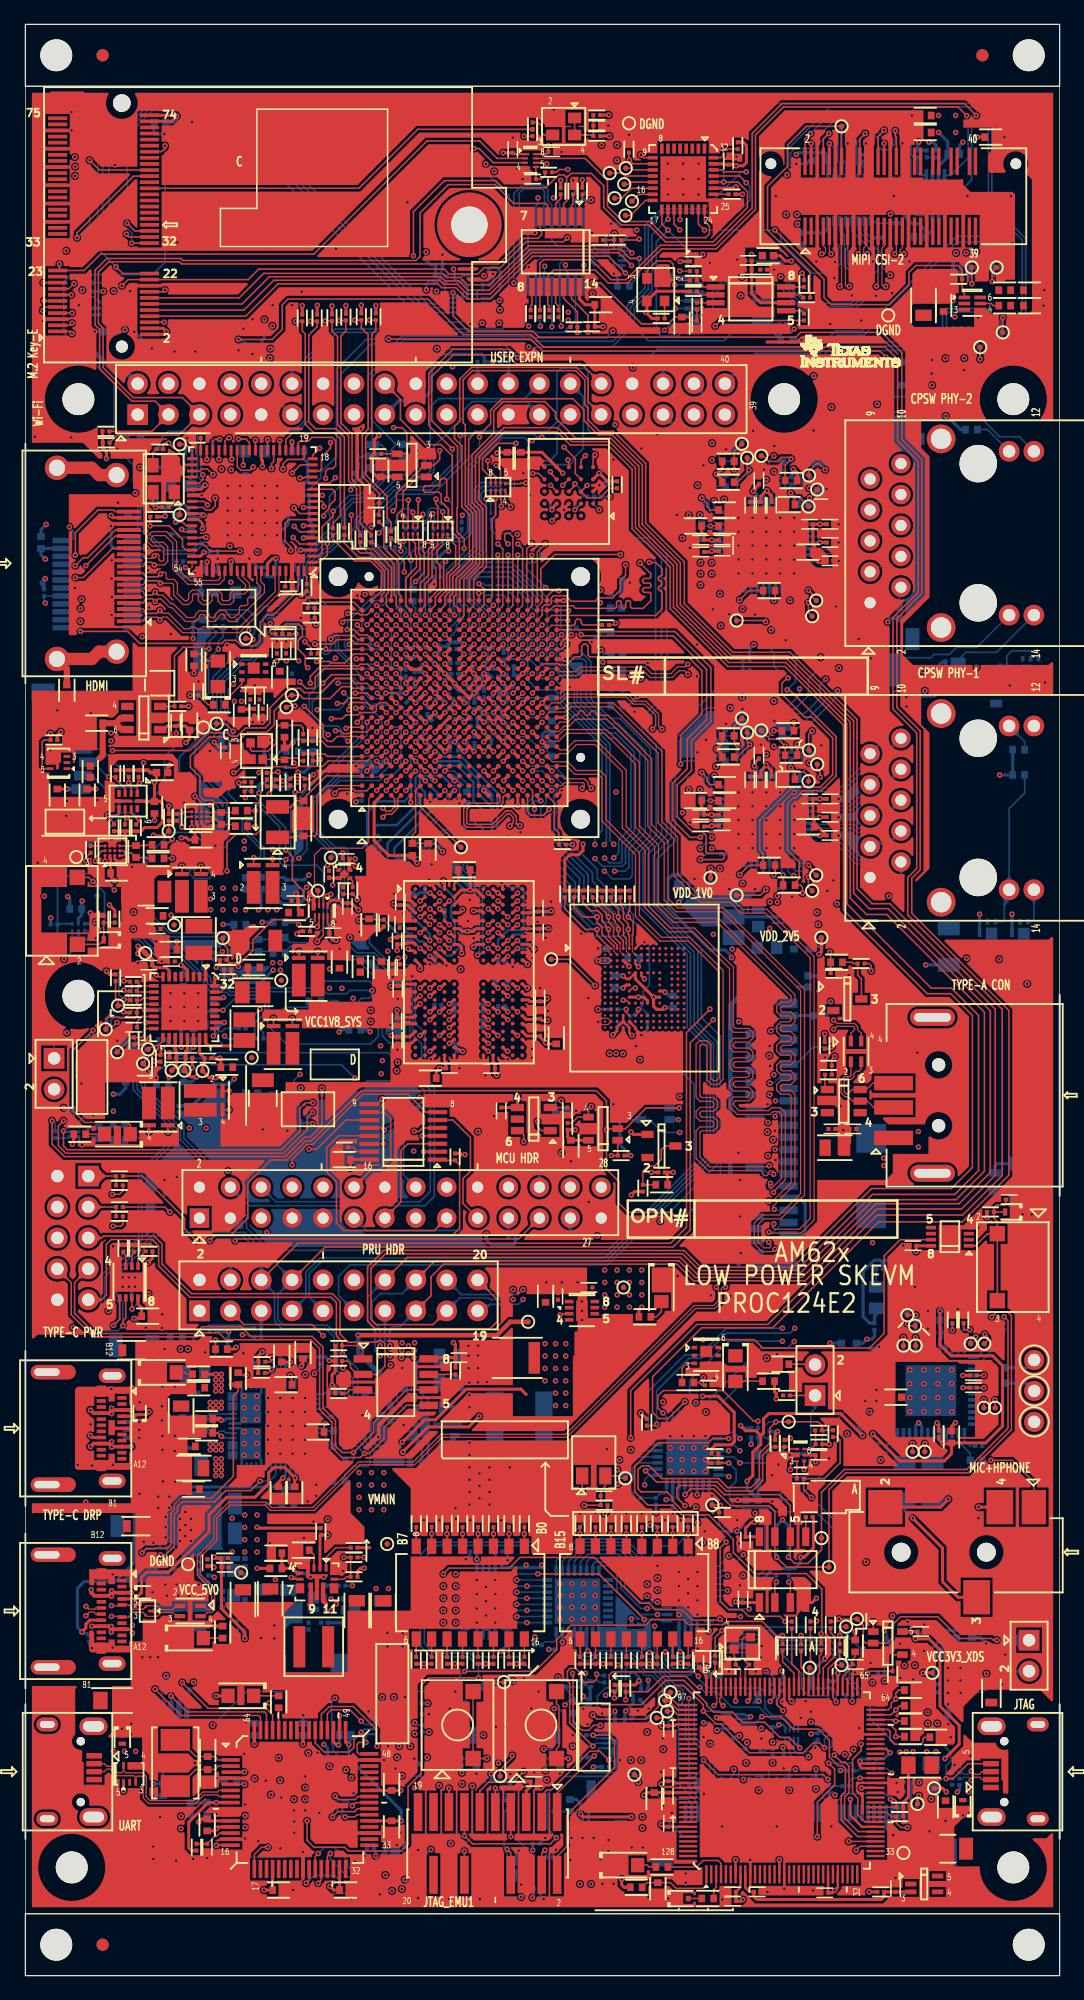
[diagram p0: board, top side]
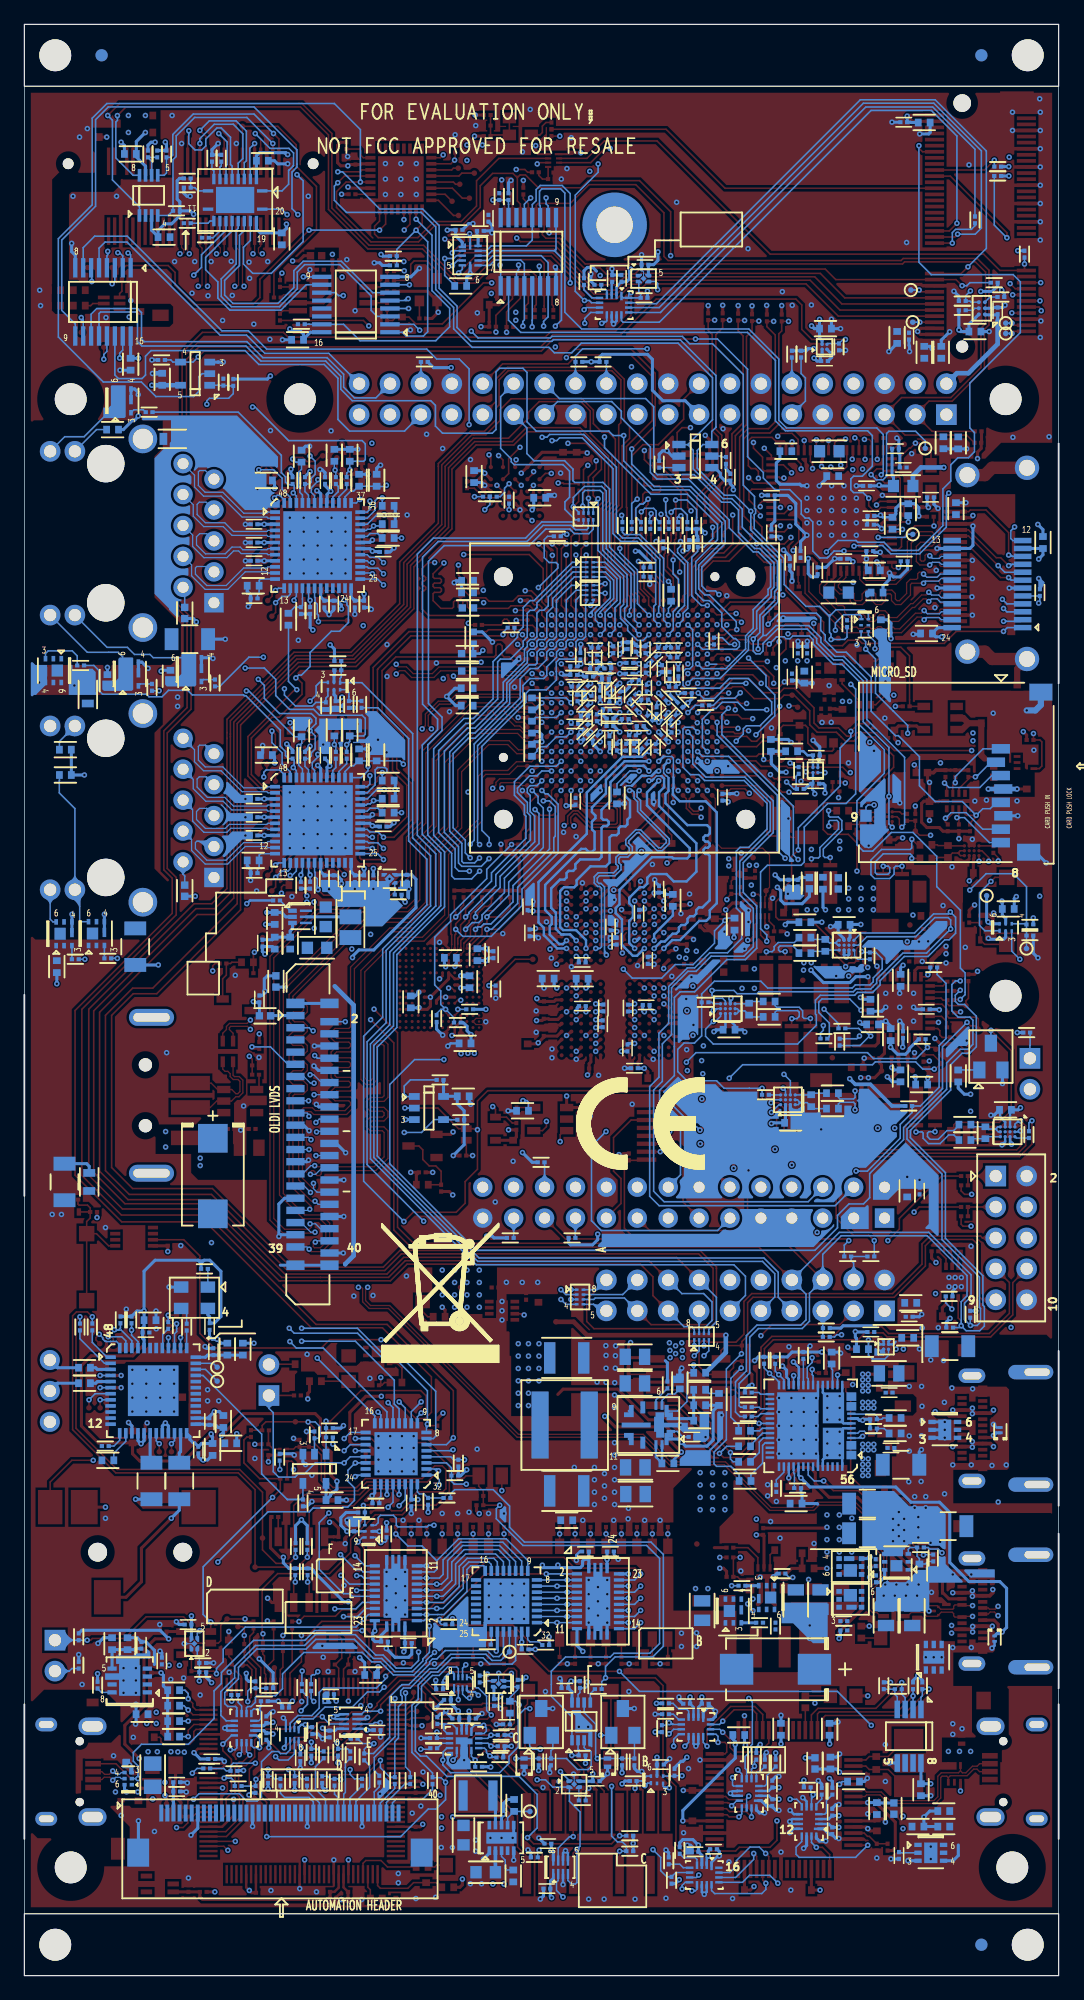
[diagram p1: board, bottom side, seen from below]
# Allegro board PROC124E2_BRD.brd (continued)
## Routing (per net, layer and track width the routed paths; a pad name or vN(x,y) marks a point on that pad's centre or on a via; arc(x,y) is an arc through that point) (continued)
PD_MS_I2C1_IRQ: length 1.5
  BOTTOM w0.127: U68.29 24.5,47.76 24.64,47.89 R443.2
PD_MS_I2C1_SCL: length 30.4
  TOP w0.132: R144.1 9.61,65.67 13.09,62.19 13.09,61.31 v1(14.04,60.37)
  L03_SIG1 w0.107: v1(23,49.36) 23,49.36 23.4,49.77 23.4,58.89 22.79,59.5 14.9,59.5 v1(14.04,60.37)
  BOTTOM w0.127: U68.27 22.58,48.94 v1(23,49.36)
  BOTTOM w0.132: R439.2 23.29,49.65 v1(23,49.36)
PD_MS_I2C1_SDA: length 31.4
  TOP w0.132: R148.1 11.46,63.13 v1(11.88,62.71)
  L03_SIG1 w0.107: v1(23.76,49.46) 23.25,48.95 22.6,48.95 22.3,49.26 22.3,50.23 23.1,51.03 23.1,58.85 22.67,59.28 14.81,59.28 14.81,59.28 14.47,59.28 11.88,61.87 11.88,62.33 v1(11.88,62.71)
  BOTTOM w0.127: U68.28 22.98,48.76 23.4,49.18 23.48,49.18 v1(23.76,49.46) 24.21,49.91 R438.2
PD_S_I2C2_SCL: length 1.5
  BOTTOM w0.127: R446.2 24.61,46.68 24.48,46.56 U68.32
PD_S_I2C2_SDA: length 1.6
  BOTTOM w0.127: U68.33 24.47,46.16 24.71,45.92 R447.2
PD_SPI_CLK: length 46.4
  TOP w0.127: U30.6 31.32,48.11 29.87,46.65
  TOP w0.132: J23.7 4.05,56.93 4.05,54.39 5.7,52.74 13.98,52.74 14.53,53.29 17.75,53.29 18.54,52.5 23.57,52.5 24.46,51.61 24.46,46.61 25.48,45.59 25.48,43.52 26.04,42.97 v1(26.97,42.97) 28.62,44.61 28.62,45.41 29.87,46.65
  BOTTOM w0.132: R461.2 26.75,42.2 26.97,42.43 v1(26.97,42.97)
PD_SPI_MISO: length 43.4
  TOP w0.127: U30.2 27.27,49.38 26.72,49.93 26.72,50.22 26.46,50.48 R160.2 26.03,49.96 v1(26.08,49.91)
  TOP w0.132: J23.5 6.26,60.59 6.42,60.74 10.58,60.74 11.23,60.09 11.23,58.43 13.65,56.02 25.22,56.02 25.86,55.37 25.86,52.68 26.52,52.03 28.89,52.03 28.98,52.12 29.31,52.12 29.55,51.88 29.55,50.05 28.88,49.38 U30.2
  BOTTOM w0.127: 26.94,45.87 26.94,49.06 v1(26.08,49.91)
  BOTTOM w0.132: R453.2 26.3,45.23 26.94,45.87
PD_SPI_MOSI: length 47
  TOP w0.127: U30.5 31.32,46.84
  TOP w0.132: 31.32,46.84 29.47,44.99 29.47,44.09 28.27,42.89 v1(27.87,42.89) 27.54,42.55 26.02,42.55 25.2,43.37 25.2,45.47 24.18,46.49 24.18,51.49 23.45,52.22 16.48,52.22 15.91,52.79 14.43,52.79 14.1,52.46 5.58,52.46 3.77,54.27 3.77,56.91 J23.8
  BOTTOM w0.132: R459.2 27.29,43.47 27.59,43.17 v1(27.87,42.89)
PD_SPI_SS: length 47.9
  TOP w0.127: U30.1 27.74,51.35 27.34,51.75 R158.2 26.03,51.11 v1(26.06,51.08)
  TOP w0.132: R158.2 26.03,52.08 25.56,52.55 25.56,55.27 25.12,55.72 13.52,55.72 10.95,58.28 10.95,59.94 10.43,60.46 7.06,60.46 6.65,60.05 6.65,55.9 6.26,55.51 J23.9
  BOTTOM w0.127: v1(26.06,51.08) 27.31,49.83 27.31,44.01 28.32,43 28.32,42.03 28.12,41.83 26.92,41.83 26.81,41.71 26.81,41.71 26.26,41.17
  BOTTOM w0.132: 26.26,41.17 R464.2
PD_VIN_3V3: length 1.8
  TOP w0.132: v1(16.11,44.29) 15.81,44.58 C131.2
  BOTTOM w0.127: U68.5 16.26,44.16 16.12,44.29 v1(16.11,44.29)
PMIC_GPO1: length 1.3
  TOP w0.132: U22.8 10.92,82.04 v1(10.75,82.2)
  BOTTOM w0.132: R577.2 10.54,82.42 v1(10.75,82.2)
PMIC_INT_B: length 5.5
  TOP w0.127: TP45.1 9.01,79.67 9.15,79.81 R126.2 9.5,80.11 9.67,80.29 U22.11
  TOP w0.132: R122.1 7.41,80.27 7.62,80.06 TP45.1
PMIC_MODE: length 55.7
  TOP w0.127: U12.C7 v1(28.87,101.34)
  TOP w0.132: 17.51,82.89 v1(17.51,82.87) ; 17.51,82.89 17.21,83.19 16.78,83.19 R117.1 16.61,83.49 16.61,84.35 16.23,84.73 TP42.1 ; 17.51,82.89 17.51,83.01 18.69,84.2 18.69,85.06 20.35,86.72 23.02,86.72 23.24,86.95 23.24,88.2 22.89,88.56 22.89,89.05 21.95,89.99 21.95,91.91 v1(21.4,92.46) ; v1(17.08,102.19) 16.45,102.82 TP25.1
  L03_SIG1 w0.107: v1(19.28,79.38) 17.78,80.87 17.78,82.6 v1(17.51,82.87)
  L06_SIG2 w0.107: v1(17.08,102.19) 17.54,102.19 18.96,100.77 22.39,100.77 23.09,100.07 23.09,99.42 23.47,99.04 24.27,99.04 25,99.78 25,100.75 24.29,101.45 24.29,102.55 24.57,102.83 26.53,102.83 27.39,101.96 28.24,101.96 v1(28.87,101.34)
  BOTTOM w0.132: v1(17.08,102.19) 17.08,101.71 17.96,100.83 17.96,97.71 21.4,94.28 v1(21.4,92.46) ; v1(19.28,79.38) 18.09,78.19 R590.1
PMIC_POWERGOOD: length 91.8
  TOP w0.127: TP50.1 9.67,75 10.3,75.62 R130.1 11.11,75.9 11.82,76.61 U22.18
  TOP w0.132: TP50.1 10.12,74.46 v1(10.22,74.46)
  L06_SIG2 w0.107: v1(27.07,73.71) 25.1,71.74 25.1,68.36 23.25,66.51 23.25,52.21 24.39,51.06 24.39,47.99 25.33,47.05 25.33,36.24 27.33,34.24 27.33,29.33 25.03,27.03 25.03,18.86 27.91,15.98 33.63,15.98 v1(34,15.61)
  BOTTOM w0.127: v1(34,15.61) 33.79,15.81 U89.1
  BOTTOM w0.132: v1(27.07,73.71) 25.97,74.81 15.3,74.81 15.07,75.04 11.74,75.04 11.16,74.46 v1(10.22,74.46)
PMIC_STBY: length 2.5
  TOP w0.132: U22.31 16.07,80.79 16.33,81.05 R591.1
PORZ_OUT: length 198.7
  TOP w0.127: U31.3 63.03,42.25 62.88,42.1 v1(62.88,41.56) ; U12.E13 v1(30.47,106.93)
  TOP w0.132: TP18.1 18.61,109.83 v1(18.7,109.74) ; U31.3 63.4,41.15 63.41,41.15 R181.2
  L03_SIG1 w0.107: v1(62.88,41.56) 57.78,41.56 57.18,42.16 57.18,42.85 57.18,42.85 57.18,44.37 57.54,44.73 59.58,44.73 60.59,43.72 63.59,43.72 66.74,46.87 66.74,53.74 65.76,54.71 65.76,73.27 67.97,75.47 67.97,79.96 65.59,82.35 64.62,82.35 61.56,85.41 61.56,86.17 57.59,90.14 57.59,101.18 61.09,104.67 v1(61.52,104.67)
  L06_SIG2 w0.107: v1(48.27,135.06) 51.25,132.08 51.25,117.96 52.43,116.79 52.43,112.7 59.08,106.05 59.08,106.02 60.7,104.4 61.25,104.4 v1(61.52,104.67) ; v1(30.47,106.93) 30.29,106.93 29.88,107.35 29.51,107.35 29.27,107.59 29.27,107.88 29.01,108.14 28.66,108.14 28.08,108.72 26.65,108.72 25.76,107.83 24.58,107.83 24.09,108.32 23.7,108.32 23.32,107.94 23.07,107.94 22.73,107.6 20.52,107.6 19.08,109.04 19.08,109.36 v1(18.7,109.74)
  BOTTOM w0.132: 18.83,111.64 18.3,112.18 15.99,112.18 15.64,111.83 U52.6 ; 18.83,111.64 18.83,110.32 18.7,110.19 v1(18.7,109.74) 17.59,109.74 17.39,109.93 R345.1 ; 18.83,111.64 19.64,112.45 20.76,112.45 22.56,114.25 22.56,116.38 25.02,118.85 25.02,119.99 24.9,120.1 24.9,120.43 24.99,120.52 24.99,121.49 25.92,122.41 25.92,131.5 28.43,134.02 30.31,134.02 30.92,134.63 41.64,134.63 41.77,134.5 47.71,134.5 v1(48.27,135.06) ; v1(61.52,104.67) 61.02,105.17 61.02,105.93 60.73,106.21 U128.3
PP1_CABLE: length 1.6
  TOP w0.132: C125.1 21.91,49.16 v1(21.78,49.28)
  BOTTOM w0.132: v1(21.78,49.28) U68.25
PP2_CABLE: length 1.8
  BOTTOM w0.127: R465.2 21.73,40.17 21.71,40.19 21.71,41.23 21.78,41.3 U68.46
PR0_PRU0_GPO0: length 72.7
  TOP w0.127: U12.K19 v1(34.47,111.73)
  L06_SIG2 w0.107: J11.13 30.59,55.64 30.59,58.07 32.17,59.65 40.55,59.65 41.16,60.26 41.16,65.09 41.64,65.57 41.64,69.35 40.83,70.16 40.83,89.24 34.09,95.98 34.09,111.35 v1(34.47,111.73)
  BOTTOM w0.132: J11.13 29.55,53.09 RA8.7
PR0_PRU0_GPO1: length 166.3
  TOP w0.132: U12.L19 36.04,111.71 36.04,114.64 37.33,115.92 37.33,120.36 36.71,120.98 36.71,124.91 38.49,126.69 38.49,128.5 39.26,129.27 42.69,129.27 43.57,128.39 43.57,127.91 45.21,126.27 48.1,126.27 50.42,123.96 50.42,119.05 53.54,115.93 53.54,112.5 57.92,108.13 62.61,108.13 67.79,102.95 67.79,88.5 69.14,87.15 70.79,87.15 78.82,79.12 78.82,66.07 76.48,63.73 69.7,63.73 63.59,57.63 55.19,57.63 53.82,59 31.41,59 J11.14
  BOTTOM w0.132: J11.14 28.13,55.72 28.13,53.7 28.75,53.08 RA8.5
PR0_PRU0_GPO2: length 171.6
  TOP w0.127: U12.L20 35.24,112.57 35.24,113.24 35.39,113.39 35.39,114.69
  TOP w0.132: 35.39,114.69 36.77,116.08 36.77,120.13 36.15,120.74 36.15,127.37 35.98,127.54 35.98,131.07 36.72,131.81 45.23,131.81 45.98,131.06 45.98,129 46.23,128.75 46.23,127.79 47.19,126.83 48.17,126.83 48.17,126.83 48.34,126.83 50.98,124.19 50.98,123.96 50.98,119.28 54.15,116.11 54.15,112.68 58.15,108.69 62.84,108.69 68.35,103.18 68.35,102.09 68.35,89.28 69.59,88.04 71.04,88.04 79.71,79.38 79.71,65.74 76.94,62.97 69.98,62.97 64.07,57.07 63.97,57.07 63.96,57.07 60.55,57.07 60.55,57.07 54.91,57.07 53.55,58.44 34.38,58.44 33.34,57.4 33.34,55.85 J11.15
  BOTTOM w0.132: RA8.8 29.95,53.08 30.16,53.3 30.79,53.3 J11.15
PR0_PRU0_GPO3: length 166
  TOP w0.132: U12.L21 35.67,114.62 37.05,116 37.05,120.24 36.43,120.86 36.43,126.19 37.01,126.77 37.54,126.77 38.24,127.47 38.24,128.58 39.17,129.51 45,129.51 45.91,128.59 45.91,127.71 47.07,126.55 48.05,126.55 48.22,126.55 50.7,124.07 50.7,119.17 53.82,116.04 53.82,112.62 58.03,108.41 62.72,108.41 68.07,103.06 68.07,101.97 68.07,88.9 69.34,87.63 70.9,87.63 79.3,79.23 79.3,65.96 76.73,63.4 69.9,63.4 63.85,57.35 60.66,57.35 55.07,57.35 53.7,58.71 33.66,58.71 J11.16
  BOTTOM w0.132: J11.16 30.97,56.02 29.17,56.02 28.49,55.34 28.49,53.8 29.15,53.14 RA8.6
PR0_PRU0_GPO4: length 171.6
  TOP w0.132: J11.17 33.5,53.47 28.83,53.47 28.4,53.9 28.4,58.1 29.58,59.28 54.01,59.28 55.38,57.91 63.37,57.91 69.62,64.16 76.38,64.16 78.33,66.12 78.33,78.87 76.1,81.1 74.44,81.1 67.51,88.04 67.51,102.83 62.49,107.85 57.8,107.85 53.26,112.38 53.26,115.81 50.14,118.94 50.14,123.84 47.99,125.99 44.89,125.99 43.75,127.13 39.33,127.13 36.99,124.79 36.99,121.09 37.61,120.47 37.61,115.87 36.47,114.73 U12.M21
  BOTTOM w0.132: J11.17 35.68,55.65 38.08,55.65 38.2,55.54 RA7.6
PR0_PRU0_GPO5: length 70.3
  TOP w0.127: U12.L17 v1(36.07,110.13)
  L06_SIG2 w0.107: J11.18 36.53,59.04 42.23,59.04 43.57,60.38 43.57,75.68 43.93,76.03 43.93,88.58 43.29,89.21 41.57,89.21 36.23,94.56 36.23,99.45 35.65,100.03 35.65,109.72 v1(36.07,110.13)
  BOTTOM w0.132: J11.18 35.83,55.94 RA7.7
PR0_PRU0_GPO6: length 78.4
  TOP w0.127: U12.L18 v1(36.07,110.93)
  L06_SIG2 w0.107: v1(36.07,110.93) 34.88,109.75 34.88,95.54 41.47,88.96 43.14,88.96 43.67,88.43 43.67,76.14 43.29,75.76 43.29,60.46 42.12,59.29 34.45,59.29 33.31,58.15 33.31,53.83 33.92,53.22 35.79,53.22 J11.19
  BOTTOM w0.132: RA7.5 38.22,55.14 37.68,54.6 J11.19
PR0_PRU0_GPO7: length 177
  TOP w0.132: J11.20 38.78,55.52 38.78,53.73 38.19,53.14 28.75,53.14 28.12,53.77 28.12,58.08 28.12,58.21 29.47,59.56 54.13,59.56 55.5,58.19 63.09,58.19 69.55,64.64 76.1,64.64 77.83,66.37 77.83,78.87 76.05,80.65 74.12,80.65 67.23,87.53 67.23,102.72 62.43,107.52 57.73,107.52 52.98,112.27 52.98,115.7 49.86,118.82 49.86,123.72 47.87,125.71 44.78,125.71 43.69,126.8 39.39,126.8 37.32,124.73 37.32,124.71 37.3,124.69 37.3,121.19 37.89,120.6 37.89,115.72 36.84,114.67 36.84,112.51 U12.M20
  BOTTOM w0.132: J11.20 37.97,56.34 RA7.8
PR0_PRU0_GPO11: length 108.9
  BOTTOM w0.132: RA4.8 38.25,118.79 38.61,118.43 39.79,118.43 40.17,118.8 42.16,118.8 43.51,117.45 50.5,117.45 51.79,116.15 51.79,104.48 50.67,103.36 50.67,102.26 51.84,101.09 51.84,93.67 50.47,92.3 50.47,87.78 54.38,83.86 54.38,77.88 56,76.26 56,67.31 47.63,58.94 24.22,58.94 23.05,57.77 23.05,55.72 J11.7
PR0_PRU0_GPO12: length 109.3
  BOTTOM w0.132: RA4.7 38.65,118.89 38.78,118.75 39.71,118.75 40.07,119.11 42.36,119.11 43.68,117.79 50.99,117.79 52.27,116.51 52.27,104.42 51.04,103.19 51.04,102.33 52.3,101.07 52.3,93.73 50.77,92.21 50.77,87.87 54.66,83.98 54.66,78 56.28,76.39 56.28,67.2 47.74,58.66 24.34,58.66 23.33,57.65 23.33,55.74 J11.9
PR0_PRU0_GPO14: length 106
  BOTTOM w0.132: RA4.6 39.05,119.19 39.18,119.06 39.61,119.06 39.94,119.39 42.48,119.39 43.8,118.07 51.38,118.07 52.7,116.74 52.7,93.65 51.18,92.13 51.18,87.85 54.97,84.07 54.97,78.1 56.56,76.52 56.56,67.08 47.86,58.38 26.68,58.38 25.74,57.44 25.74,55.86 J11.11
PRU_3V3_EN: length 142.6
  TOP w0.132: v1(53.81,144.22) 53.81,145.05 U3.20 ; v1(15.63,52.2) 15.62,52.19 R589.1
  L04_PWR01 w0.381: v1(53.81,144.22) 53.81,144.34 53.33,144.81 50.91,144.81 49.49,143.39 49.49,142.6 47.76,140.88 47.76,137.56 53.68,131.64 53.68,126.78 51.7,124.8 51.7,118.86 52.83,117.72 52.83,87.22 53.3,86.75 53.3,75.65 50.35,72.7 43.8,72.7 39.35,68.26 32.06,68.26 32.05,68.25 31.7,68.25 31.39,67.94 31.39,67.59 31.02,67.22 15.02,67.22 13.01,65.21 13.01,53.32 14.13,52.2 v1(15.63,52.2)
  BOTTOM w0.127: 15.46,50.79 15.31,50.64 14.28,50.64 13.98,50.95 U65.B2
  BOTTOM w0.132: 15.46,50.79 15.63,50.97 R435.2 v1(15.63,52.2)
PRU_DETECT: length 42.4
  TOP w0.132: v1(24.47,52.56) 23.56,53.48 17.97,53.48 J11.3
  L06_SIG2 w0.107: v1(48.68,40.37) 46.85,40.37 42.66,44.56 33.16,44.56 25.16,52.56 v1(24.47,52.56)
  BOTTOM w0.127: R463.1 49.9,41.71 50.3,42.11 U70.3
  BOTTOM w0.132: R463.1 49.9,40.6 49.67,40.37 v1(48.68,40.37)
PRU_INTN: length 2.1
  BOTTOM w0.127: J11.5 19.39,53.2 R432.2 19.37,52.81 19.38,52.8 R433.2
PRU_RESETZ: length 3.4
  BOTTOM w0.127: J11.4 16.85,58.52 17.06,58.73 R420.2 R421.2
PUSH BUTTON: length 7.3
  TOP w0.132: SW1.3 5.23,90.2 v1(5.56,89.87)
  BOTTOM w0.132: U59.1 6.06,85.81 6.5,86.26 6.5,88.93 v1(5.56,89.87)
RESETSTATZ: length 416.5
  TOP w0.127: U12.E14 v1(30.47,107.73)
  TOP w0.132: U3.28 v1(57.38,147.3) 58.56,147.3 59.34,146.52 59.34,145.22 56.52,142.39 52.61,142.39 51.22,143.78 48.99,143.78 48.99,143.79 48.96,143.79 47.53,145.22 47.53,147 46.52,148.01 44.84,148.01 44.49,147.66 ; v1(55.11,38.47) 54.82,38.18 54,38.18 53.17,39.01 53.17,39.28 52.71,39.73 50.61,39.73 50.35,39.99 50.35,41.56 50.66,41.87 51.27,41.87 52.31,40.83 56.97,40.83 57.71,40.09 59.63,40.09 60.32,40.77 60.32,42.89 61.17,43.75 61.17,44.66 61.17,44.97 v1(61.68,45.47) 61.7,45.49 TP66.1 65.15,45.49 65.45,45.18 R174.1 65.47,44.8 R175.2 ; v1(47.76,69.47) 47.85,69.56 U25.2 49.32,69.56 51.01,71.26 v1(53.73,71.26) ; v1(47.76,69.47) 47.76,71.84 46.92,72.68 27.62,72.68 23.49,68.55 23.03,68.55 21.47,66.99 20.18,66.99 18.28,65.1 18.28,62.21 16.89,60.82 15.6,60.82 v1(15.15,60.37) ; v1(47.76,69.47) 47.76,66.23 48.78,65.21 48.78,63.43 49.51,62.7 53.04,62.7 v1(53.81,61.93) ; 44.49,147.66 44.49,145.75 44.23,145.5 U4.3 ; 44.49,147.66 44.26,147.89 43.81,147.89 42.76,146.84 39.24,146.84 38.66,147.42 34.44,147.42 31.89,144.86 v1(31.89,141.26) ; v1(34.05,125.26) 34.05,124.51 33.57,124.04 U8.2 32.79,124.04 30.49,121.73 30.49,120.58 v1(30.21,120.3)
  L03_SIG1 w0.107: v1(19.34,78.04) 18.37,77.07 18.37,60.22 18.12,59.97 15.55,59.97 v1(15.15,60.37) ; v1(30.47,107.73) 30.08,108.12 30.08,108.63 29.74,108.97 25.21,108.97 24.22,109.96 22.57,109.96 22.41,109.8 22.08,109.8 21.27,110.6 20.13,110.6 18.87,109.34 18.16,109.34 17.82,109.69 16.19,109.69 15.86,109.36 v1(15.86,108.95) ; v1(31.89,141.26) 31.93,141.21 31.93,133.81 30.65,132.53 30.65,127.54 32.94,125.26 v1(34.05,125.26)
  L06_SIG2 w0.107: v1(30.47,107.73) 30.47,107.99 30.09,108.38 30.09,108.69 30.31,108.92 32.24,108.92 32.45,109.14 32.45,109.47 32.72,109.74 33.01,109.74 33.25,109.98 33.25,112.2 32.53,112.93 32.53,116.01 31.51,117.02 31.51,117.94 30.21,119.24 v1(30.21,120.3) ; v1(19.34,78.04) 19.34,78.11 23.11,81.89 23.11,88.84 23.5,89.22 23.5,89.54 21.83,91.21 21.83,96.06 20.34,97.54 16.21,97.54 12.4,101.35 v1(12.4,102.03) ; v1(47.76,69.47) 47.76,66.13 48.56,65.33 48.56,60.81 51.09,58.28 51.09,53.18 56.87,47.4 56.87,39.09 56.25,38.47 v1(55.11,38.47)
  BOTTOM w0.127: U70.28 54.7,38.88 v1(55.11,38.47) ; v1(61.68,45.47) 61.1,45.47 60.69,45.07 60.69,44.28 60.84,44.13 R455.1 U71.2
  BOTTOM w0.132: R660.1 55.94,104.13 53.42,101.6 53.42,93.19 51.92,91.69 51.92,87.95 55.55,84.31 55.55,78.71 57.11,77.15 57.11,65.24 v1(53.81,61.93) ; v1(12.4,102.03) 12.4,102.68 13.58,103.85 13.58,103.85 13.81,104.08 13.81,104.08 15.05,105.32 15.05,108.14 v1(15.86,108.95) 15.86,109.56 16.24,109.94 U52.3 ; R403.1 19.57,77.41 19.34,77.64 v1(19.34,78.04) ; U47.2 70.38,131.57 70.65,131.3 70.65,130.13 71.09,129.69 74.19,129.69 75.39,130.89 78.51,130.89 82.2,134.58 82.2,142.66 79.42,145.44 79.42,152.55 78.22,153.75 59.52,153.75 57.38,151.62 v1(57.38,147.3) ; U62.2 v1(53.73,71.26) ; v1(15.15,60.37) R421.1
SEL_XDS: length 44.9
  TOP w0.127: v1(46.63,21.4) 46.96,21.07 51,21.07 52.03,22.1 52.03,23.12 52.72,23.8 54.14,23.8 55.72,22.23 v1(55.72,21.72) 56.77,20.67 57.15,20.67 59.51,18.31 63.94,18.31 64.74,19.12 65.28,19.12 v1(65.67,18.72)
  L06_SIG2 w0.107: v1(70.59,28.33) 68.83,26.57 68.83,22.26 65.67,19.11 v1(65.67,18.72)
  BOTTOM w0.127: v1(46.63,21.4) 47.01,21.78 47.01,22.95 47.69,23.64 47.86,23.64 48.02,23.8 48.02,24.13 48.4,24.5 U79.5 ; v1(55.72,21.72) 56.77,21.72 56.78,21.73 57.04,21.73 57.29,21.47 U82.4 ; v1(70.59,28.33) 70.79,28.13 U76.4 ; U84.1 65.96,19.73 65.67,19.44 v1(65.67,18.72) 66.16,18.72 66.34,18.9 U84.16
SEL_XDS110_INV: length 69
  TOP w0.127: v1(39.59,10.37) 39.89,10.07 J19.8
  TOP w0.132: v1(44.97,24.83) 45.01,24.79 45.01,22.52 45.17,22.36 ; 45.17,22.36 45.02,22.21 45.01,22.21 45.01,20.88 45.74,20.15 46.3,20.15 46.7,20.56 v1(47.25,20.56) ; 45.17,22.36 47.33,22.36 47.43,22.26 50.63,22.26 52.62,24.25 54.12,24.25 56.01,22.36 56.01,22.19 56.55,21.65 58.1,21.65 58.94,20.81 60.76,20.81 62,19.57 62.77,19.57 v1(63.64,18.7)
  L03_SIG1 w0.107: v1(47.25,20.56) 47.25,17.96 46.85,17.56 45.2,17.56 45.02,17.38 43.62,17.38 43.29,17.05 43.29,16.52 v1(42.86,16.09)
  L06_SIG2 w0.107: v1(70.62,24.21) 69.87,23.46 69.87,22.63 66.05,18.82 66.05,18.56 65.83,18.34 64.75,18.34 64.38,18.7 v1(63.64,18.7)
  BOTTOM w0.127: U87.16 47.22,19.89 47.03,20.08 47.03,20.34 v1(47.25,20.56) 48,20.56 48.26,20.3 U87.1 ; U80.2 45.12,24.21 44.97,24.35 v1(44.97,24.83) ; U76.2 70.79,26.28 70.62,26.12 R490.2 R492.1 v1(70.62,24.21) ; U90.2 40.21,14.32 39.33,13.45 39.33,10.63 v1(39.59,10.37) 39.59,7.65 39.71,7.53 40.04,7.53 40.33,7.82 U95.4
  BOTTOM w0.132: v1(42.86,16.09) 42.17,16.09 41.57,15.49 U90.2
  BOTTOM w0.147: v1(63.64,18.7) 63.51,18.84 U85.5
SLOW_CLK: length 33.5
  TOP w0.132: J2.50 27.41,146.79 32.26,151.64 R2.2
SOC_CLKIN: length 104.8
  TOP w0.127: R71.1 24.13,99.77 v1(24.24,99.88)
  TOP w0.132: R21.2 C16.1 54.73,135.93 54.45,136.22 R28.2 53.39,136.22 52.83,135.66 50.65,135.66 47.28,139.02 v1(46.59,139.02)
  L06_SIG2 w0.107: v1(24.24,99.88) 24.24,100.24 22.09,102.4 18.61,102.4 18.08,102.93 16.7,102.93 16.52,102.75 13.71,102.75 12.72,103.74 10.16,103.74 5.19,108.7 5.19,114.77 4.59,115.37 4.59,116.25 5.19,116.85 5.19,126.11 5.41,126.32 5.41,126.34 7.19,128.11 7.19,131.49 6.59,132.09 6.59,134.6 9.75,137.77 31.14,137.77 31.39,137.52 37.8,137.52 39.73,139.45 46.16,139.45 v1(46.59,139.02)
SOC_DVDD1V8: length 5.6
  TOP w0.254: U12.H15 v1(32.87,108.53) ; U12.K15 v1(34.47,108.53) 34.87,108.93 U12.K16 ; U12.H9 v1(33.67,103.73) ; U12.P7 v1(37.67,101.34) ; U12.N7 v1(36.87,102.13) ; U12.H16 v1(32.87,109.33)
  BOTTOM w0.254: v1(33.67,103.73) 33.67,103.61 C293.1 ; C237.1 32.87,109.08 v1(32.87,109.33) ; C248.1 v1(32.87,108.53) ; v1(36.87,102.13) 36.92,102.09 C305.2 ; C238.1 34.68,108.74 v1(34.47,108.53)
  vias: v1(25,82.69) v1(25,81.09) v1(26.02,81.09)
SOC_DVDD3V3: length 11
  TOP w0.254: U12.G13 v1(32.07,106.13) ; U12.R10 v1(38.47,103.74) ; U12.K11 v1(34.47,105.33) ; U12.F10 v1(31.27,103.74) ; U12.N15 v1(37.67,108.53) ; U12.N16 v1(37.67,109.33) ; U12.R15 v1(39.27,107.74) ; U12.R14 v1(39.27,106.94) ; U12.G10 v1(32.07,103.74) ; U12.F12 v1(31.27,105.34)
  L03_SIG1 w0.254: v1(34.47,105.33) 34.47,105.53 34.3,105.7
  BOTTOM w0.254: v1(34.47,105.33) 34.58,105.23 C279.1 ; C236.1 37.83,109.17 v1(37.67,109.33) ; C260.2 31.98,106.23 v1(32.07,106.13) 32.01,106.08 C267.1 ; C261.1 39.02,106.69 v1(39.27,106.94) 39.38,106.83 C259.1 ; v1(38.47,103.74) 38.69,103.51 C289.1 ; C252.1 39.47,107.54 v1(39.27,107.74) 39.3,107.77 C244.1 ; C272.1 v1(31.27,105.34) ; C290.1 v1(32.07,103.74) ; C291.1 v1(31.27,103.74) ; v1(37.67,108.53) 37.7,108.5 C247.1
  vias: v1(19.92,87.54) v1(20.66,87.54)
SOC_EMU0: length 159.5
  TOP w0.127: v1(55.43,23.69) 55.2,23.69 54.31,24.57 52.41,24.57 51.15,23.31 R239.2 v1(49.34,22.65)
  TOP w0.132: v1(29.7,102.9) 29.7,102.96 U12.D9
  L03_SIG1 w0.107: v1(29.7,102.9) 27.48,105.12 27.48,105.49 27.27,105.7 26.78,105.7 26.59,105.51 26.59,105.07 26.43,104.92 25.44,104.92 24.09,103.56 23.38,103.56 22.82,103.01 22.27,103.01 20.05,100.79 19.66,100.79 16.95,98.07 16.95,94.76 13.8,91.61 13.8,90.78 13.16,90.15 13.16,84.33 12.34,83.52 12.34,82.37 10.72,80.74 10.72,76.97 9.54,75.79 9.54,60.66 12.17,58.02 12.17,55.67 12.57,55.27 12.57,53.95 15.39,51.14 16.73,51.14 17.98,49.89 18.21,49.89 18.6,49.49 18.6,47.85 18.6,47.85 18.6,41.04 18.85,40.79 18.85,38.71 19.47,38.09 19.47,31.6 19.76,31.31 19.76,23.2 24.85,18.12 25.71,18.12 29.89,13.94 41.95,13.94 44.48,16.47 48.83,16.47 49.24,16.88 49.24,17.86 48.96,18.14 48.96,22.28 v1(49.34,22.65)
  BOTTOM w0.127: U85.2 62.81,20.7 62.42,21.09 61.26,21.09 60.3,22.05 58.06,22.05 56.81,23.3 55.82,23.3 v1(55.43,23.69) ; U79.2 v1(49.34,22.65)
SOC_EMU1: length 155.5
  TOP w0.127: v1(48.41,22.8) 48.41,22.88 48.42,22.88 R238.2 48.32,23.42 48.14,23.42 47.98,23.58 47.98,24.69 48.24,24.94 54.95,24.94 v1(55.31,24.58)
  TOP w0.132: v1(26.58,103.96) 26.58,104.36 26.77,104.55 28.05,104.55 U12.B10
  L03_SIG1 w0.107: v1(48.41,22.8) 47.95,22.34 46.91,22.34 42.32,17.74 42.32,16.35 40.35,14.38 30.5,14.38 27.04,17.84 27.04,19.06 26.22,19.88 25.65,19.88 21,24.53 21,35.21 20.32,35.9 20.32,47.68 19.05,48.94 19.05,50.8 17.83,52.02 16.92,52.02 16.66,51.77 15.43,51.77 13.01,54.18 13.01,55.5 12.9,55.62 12.9,55.64 12.62,55.92 12.62,58.23 9.98,60.87 9.98,67.26 11.24,68.51 11.24,74.2 12.43,75.4 12.43,81.54 13.69,82.8 13.69,89.83 16.35,92.48 16.35,93.53 17.39,94.58 17.39,96.91 18.24,97.76 18.24,97.82 18.25,97.83 18.25,98.66 19.92,100.34 20.24,100.34 22.44,102.55 23.05,102.55 23.48,102.98 24.65,102.98 24.83,102.8 25.42,102.8 v1(26.58,103.96)
  BOTTOM w0.127: U85.3 63.16,20.74 62.53,21.36 61.38,21.36 60.77,21.97 60.77,23.26 60.41,23.62 56.06,23.62 55.83,23.85 55.83,23.86 55.6,24.09 55.59,24.09 55.31,24.37 v1(55.31,24.58) ; U79.3 48.99,23.12 48.67,22.8 v1(48.41,22.8)
SOC_GPIO1_49: length 19.2
  TOP w0.132: v1(13.55,105.16) 14.22,105.16 R59.2 15.03,104.38 R60.1 ; U12.B15 28.06,108.54 26.98,108.54 26.25,107.81 25.1,107.81 24.98,107.93 v1(23.94,107.93)
  L03_SIG1 w0.107: v1(13.55,105.16) 14.32,105.16 17.38,108.22 19.33,108.22 19.48,108.37 23.33,108.37 23.77,107.93 v1(23.94,107.93)
SOC_I2C0_SCL: length 232.3
  TOP w0.127: R125.1 8.14,80.88 v1(8.08,80.93) ; U12.E12 v1(30.47,106.13)
  TOP w0.132: U28.6 8.26,54.02 8.01,53.77 v1(8.01,53.37) ; v1(56.26,79.38) 54.33,77.44 54.33,61.47 53.01,60.15 22.4,60.15 J11.6
  L03_SIG1 w0.107: v1(30.47,106.13) 30.11,106.49 30.11,107 29.82,107.29 28.62,107.29 27.34,108.57 25.11,108.57 24.93,108.39 24.4,108.39 23.99,108.8 23.55,108.8 23.44,108.92 19.4,108.92 19.15,108.67 17.15,108.67 14.39,105.9 12.49,105.9 11.31,104.72 11.31,94.72 10.84,94.25 10.53,94.25 10.09,93.81 6.66,93.81 4.56,91.72 4.56,89.7 6.82,87.44 6.82,83.75 8.49,82.08 8.49,81.56 8.48,81.56 8.48,81.53 8.29,81.34 8.29,81.14 v1(8.08,80.93)
  L06_SIG2 w0.107: v1(56.26,79.38) 57.6,79.38 v1(58.62,78.35)
  BOTTOM w0.132: v1(8.01,53.37) 7.6,52.97 6.49,52.97 6.11,53.35 6.11,54.95 6.23,55.07 6.23,57.48 9.31,60.56 9.31,65.95 12.18,68.82 12.18,69.42 8.87,72.73 8.87,74.81 7.93,75.75 7.52,75.75 7.3,75.75 6.77,76.28 6.77,78.8 7.73,79.76 8.24,79.76 8.49,80.02 8.49,80.52 v1(8.08,80.93) ; v1(8.01,53.37) 8.01,55.34 7.53,55.83 7.53,57.5 10.79,60.77 17.87,60.77 19.39,59.24 J11.6 20.48,56.04 20.48,53.74 21.08,53.15 24.67,53.15 25.38,52.43 25.38,49.49 26.26,48.62 26.26,46.81 26.13,46.68 R446.1 ; v1(8.01,53.37) 8.16,53.23 R431.2 ; J22.2 v1(58.62,78.35) ; v1(30.47,106.13) 30.07,106.54 27.83,106.54 25.49,108.87 25.49,109.61 25.49,109.94 24.81,110.61 24.81,112.05 23.62,113.24 23.62,113.79 23.39,114.02 23.39,116.04 24.56,117.21 24.98,117.21 26.31,118.53 26.31,120.37 26.96,121.01 27.69,121.01 29.95,123.28 32.98,123.28 33.27,123.57 33.27,128.85 33.94,129.52 41.03,129.52 J3.28
SOC_I2C0_SCL_PMIC: length 1.5
  TOP w0.127: U22.10 9.24,80.79 R125.2
SOC_I2C0_SDA: length 228.2
  TOP w0.127: U12.D14 v1(29.67,107.73) ; v1(8.08,81.7) 8.54,81.7 R123.1
  TOP w0.132: U28.5 7.76,53.91 v1(7.25,53.4) ; J11.8 24.63,59.84 53.24,59.84 54.64,61.24 54.64,76.61 v1(56.54,78.51)
  L03_SIG1 w0.107: v1(8.08,81.7) 8.08,82.08 6.59,83.57 6.59,87.32 4.34,89.56 4.34,91.81 6.57,94.04 10.01,94.04 10.44,94.47 10.75,94.47 11.03,94.76 11.03,104.76 14.54,108.26 16.43,108.26 17.06,108.89 19.05,108.89 19.31,109.14 23.49,109.14 23.64,109 24.14,109 24.55,108.59 24.85,108.59 25.02,108.77 27.85,108.77 28.46,108.16 28.96,108.16 29.39,107.73 v1(29.67,107.73)
  L06_SIG2 w0.107: v1(56.54,78.51) 57.2,77.85 60.83,77.85 61.09,77.6 v1(61.26,77.6)
  BOTTOM w0.132: R424.2 7.27,53.42 ; 7.27,53.42 7.73,53.88 7.73,55.23 7.2,55.76 7.2,57.57 10.68,61.04 18.02,61.04 J11.8 20.76,55.97 20.76,53.86 21.19,53.42 24.8,53.42 25.66,52.56 25.66,49.66 26.56,48.77 26.56,46.29 26.19,45.92 R447.1 ; 7.27,53.42 v1(7.25,53.4) 6.69,53.4 6.42,53.67 6.42,54.8 6.51,54.89 6.51,57.37 9.59,60.45 9.59,65.83 12.46,68.71 12.46,69.54 9.2,72.79 9.2,74.96 8.09,76.08 7.45,76.08 7.05,76.49 7.05,78.47 7.3,78.72 8.26,78.72 8.77,79.23 8.77,81.4 8.48,81.7 v1(8.08,81.7) ; J22.3 61.59,77.85 61.34,77.6 v1(61.26,77.6) ; J3.27 41.18,129.27 36.72,129.27 35.94,128.49 35.94,127.94 33.55,125.55 33.55,123.46 33.01,122.92 30.43,122.92 27.08,119.57 27.08,118.91 25.1,116.93 24.68,116.93 23.67,115.92 23.67,114.07 23.88,113.86 23.88,113.41 25.1,112.19 25.1,110.66 25.73,110.03 25.73,109.51 25.73,109.51 25.73,108.97 27.36,107.34 29.27,107.34 v1(29.67,107.73)
SOC_I2C0_SDA_PMIC: length 1.6
  TOP w0.127: U22.9 9.5,81.29 R123.2
SOC_I2C1_SCL: length 320.1
  TOP w0.127: v1(13.94,96.85) 14.48,96.32 U16.C3 ; U24.1 42.42,69.4 42.09,69.73 v1(42.09,70.16) ; U16.A1 v1(13.68,94.32) ; U17.A1 v1(6.55,91.52)
  TOP w0.132: v1(23.61,70.9) 23.17,70.47 23.17,69.5 21.22,67.55 3.33,67.55 2.71,68.17 2.71,69.79 v1(3.13,70.21) ; v1(79.41,54.11) 79.81,54.51 80.71,54.51 81.03,54.19 81.03,44.84 77.48,41.29 67.42,41.29 66.04,39.91 TP74.1 62.56,33.55 v1(61.75,34.36) 61.59,34.51 U32.7 61.59,38.13 61.14,38.58 58.44,38.58 58.43,38.59 57.96,38.59 56.58,39.98 54.67,39.98 v1(54.2,39.51) ; v1(59.24,147.25) 58.69,147.8 U3.29 ; v1(25.1,109.77) 25.39,110.07 26.97,110.07 27.3,109.74 U12.A17 ; U11.1 24.19,116.08 24.82,116.7 v1(24.82,117.6)
  L03_SIG1 w0.107: v1(13.68,94.32) 13.23,93.87 11.67,93.87 10.52,92.72 7.75,92.72 v1(6.55,91.52) ; v1(22.58,74.02) 22.58,75.61 26.02,79.06 27.69,79.06 v1(28.38,78.37) ; v1(23.61,70.9) 23.23,71.28 23.23,72.02 23.4,72.2 28.23,72.2 28.88,72.85 38.53,72.85 41.22,70.16 v1(42.09,70.16) 43.53,68.72 49.82,68.72 52.37,66.18 52.37,65.54 55.04,62.87 55.04,57.13 53.8,55.9 53.8,45.24 54.35,44.69 54.35,40.94 54.2,40.79 v1(54.2,39.51)
  L06_SIG2 w0.107: v1(23.61,70.9) 22.26,72.25 22.26,73.71 v1(22.58,74.02) ; v1(8.9,87.36) 8.9,87.75 7.88,88.77 7.15,88.77 6.55,89.37 v1(6.55,91.52)
  BOTTOM w0.127: R429.1 v1(79.41,54.11) ; U70.29 v1(54.2,39.51) ; U61.A1 22.97,71.53 v1(23.61,70.9) ; U60.A1 27.79,78.79 28.15,78.42 28.33,78.42 v1(28.38,78.37) ; v1(3.13,70.21) 3.31,70.21 3.59,69.93 U63.A1 ; U61.C3 22.05,73.5 v1(22.58,74.02) ; R474.2 v1(61.75,34.36)
  BOTTOM w0.132: U58.A1 16.23,85.63 11.85,85.63 10.28,87.2 9.06,87.2 v1(8.9,87.36) 8.47,86.93 8.47,85.61 9,85.07 9.36,85.07 10.73,83.7 12.68,83.7 14.68,81.71 14.68,81.36 15.28,80.76 15.86,80.76 16.53,80.76 16.77,80.52 19.58,80.52 19.99,80.11 19.99,78.98 19.91,78.9 19.91,78.05 21.45,76.51 28.38,76.51 29.02,77.15 29.02,77.73 v1(28.38,78.37) ; U48.1 31.19,125.74 30.49,125.74 ; 30.49,125.74 28.44,127.79 28.44,131.24 31.28,134.07 39.23,134.07 40.01,133.28 41.44,133.28 41.89,133.73 48.2,133.73 49.72,135.25 49.72,137 51.19,138.48 51.19,143.62 52.38,144.81 58.53,144.81 59.52,145.81 59.52,146.97 v1(59.24,147.25) ; 30.49,125.74 30.03,125.28 30.03,123.75 27.59,121.3 26.85,121.3 26,120.45 26,118.96 24.82,117.78 v1(24.82,117.6) 24.56,117.6 23.11,116.15 23.11,113.9 23.34,113.67 23.34,112.94 24.56,111.73 24.56,110.31 v1(25.1,109.77) 25.1,108.79 24.86,108.55 24.53,108.55 24.29,108.8 24.29,109.41 23.11,110.59 20.66,110.59 19.88,109.82 19.88,109.46 18.49,108.06 17.78,108.06 16.06,106.35 16.06,102.98 13.94,100.86 v1(13.94,96.85) 13.94,94.59 v1(13.68,94.32)
SOC_I2C1_SDA: length 315.6
  TOP w0.127: U24.6 40.63,69.4 40.96,69.07 v1(40.96,68.5) ; U16.A2 13.29,95.18 13.09,94.99 13.09,94.53 v1(12.88,94.32) ; U17.A2 6.31,92.39 5.75,91.83 v1(5.75,91.52)
  TOP w0.132: v1(3.13,69.38) 3.13,68.14 3.45,67.83 21.04,67.83 22.56,69.35 22.56,71.23 23.02,71.69 v1(23.63,71.69) ; v1(59.24,148.14) 57.41,148.14 57.25,148.3 U3.30 ; v1(80.43,54.11) 80.75,53.79 80.75,44.96 77.37,41.57 67.3,41.57 65.43,39.7 TP72.1 65.43,34.97 64.31,33.86 63.22,33.86 v1(62.71,34.36) 62.86,34.51 U32.6 62.86,38.6 61.96,39.51 57.44,39.51 56.69,40.26 53.76,40.26 53.55,40.05 53.55,39.25 v1(54.2,38.6) ; v1(24.7,108.95) 24.81,108.84 26.7,108.84 26.79,108.94 U12.A16 ; U11.2 24.12,116.58 24.38,116.84 24.38,118.97 25.3,119.89 v1(25.3,120.27)
  L03_SIG1 w0.107: v1(28.49,80.91) 28.76,80.64 28.76,79.66 v1(28.38,79.28) 25.87,79.28 22.16,75.58 22.16,73.36 v1(22.64,72.88) ; v1(5.75,91.52) 7.17,92.95 10.43,92.95 11.8,94.32 v1(12.88,94.32) ; v1(54.2,38.6) 53.67,39.13 53.67,40.92 53.47,41.12 53.47,55.88 54.81,57.22 54.81,62.77 52.14,65.44 52.14,66.09 49.73,68.5 v1(40.96,68.5) 40.96,70.02 38.36,72.62 29.09,72.62 28.15,71.69 v1(23.63,71.69)
  L06_SIG2 w0.107: v1(23.63,71.69) 23.18,71.69 22.64,72.22 v1(22.64,72.88) ; v1(8.87,85.96) 8.52,86.32 8.52,87.42 7.49,88.44 7.06,88.44 5.95,89.56 5.95,91.33 v1(5.75,91.52)
  BOTTOM w0.127: U70.30 53.7,39.1 v1(54.2,38.6) ; R473.2 v1(62.71,34.36) ; v1(3.13,69.38) 3.21,69.3 U63.A2 ; R428.1 v1(80.43,54.11) ; v1(22.64,72.88) 22.45,72.69 U61.B3 ; v1(28.38,79.28) 28.25,79.41 U60.A2 ; U61.A2 23.39,71.93 v1(23.63,71.69)
  BOTTOM w0.132: U60.B3 27.39,80.04 27.62,80.27 28.24,80.27 28.49,80.52 v1(28.49,80.91) 26.68,80.91 26.42,80.65 24.79,80.65 24.63,80.81 16.87,80.81 16.64,81.03 15.43,81.03 14.96,81.51 14.96,81.83 12.8,83.98 10.86,83.98 v1(8.87,85.96) 8.87,86.7 9.07,86.89 10.18,86.89 11.74,85.33 15.76,85.33 16.46,84.63 U58.A2 ; 24.29,110.07 24.04,110.07 23.22,110.88 20.53,110.88 19.54,109.88 19.54,109.51 18.37,108.34 17.66,108.34 15.76,106.44 15.76,103.16 12.66,100.06 12.66,94.54 v1(12.88,94.32) ; 24.29,110.07 24.7,109.66 v1(24.7,108.95) ; 24.29,110.07 24.29,111.6 23.06,112.83 23.06,113.56 22.83,113.79 22.83,116.27 25.3,118.73 v1(25.3,120.27) 26.61,121.58 27.47,121.58 29.7,123.81 29.7,125.27 29.22,125.75 U48.6 28.5,126.82 28.15,127.18 28.16,127.2 28.16,131.41 31.1,134.35 41.52,134.35 41.65,134.22 48.3,134.22 49.44,135.37 49.44,137.12 50.91,138.59 50.91,143.74 52.27,145.09 55.79,145.09 58.85,148.14 v1(59.24,148.14)
SOC_I2C1_TA_SCL: length 26.6
  TOP w0.132: U32.2 61.59,32.2 v1(61.72,32.32)
  L03_SIG1 w0.107: v1(54.53,22.76) 55.51,22.76 56.4,23.65 56.4,24.16 57.7,25.46 60.39,25.46 v1(60.88,24.96)
  L06_SIG2 w0.107: v1(60.88,24.96) 61.05,25.13 61.05,29.32 61.72,30 v1(61.72,32.32)
  BOTTOM w0.127: v1(54.53,22.76) 54.53,19.63 56.25,17.92 56.25,16.85 55.83,16.43 R540.1 ; v1(60.88,24.96) 61.14,24.71 61.32,24.71 61.43,24.61 R503.1 ; R480.2 v1(61.72,32.32)
SOC_I2C1_TA_SDA: length 28.4
  TOP w0.132: U32.3 62.86,32.2 v1(62.74,32.32)
  L03_SIG1 w0.107: v1(62.17,25.01) 61.5,25.69 57.61,25.69 56.17,24.25 56.17,23.75 55.65,23.23 v1(53.68,23.23)
  L06_SIG2 w0.107: v1(62.17,25.01) 61.8,25.39 61.8,29.49 62.74,30.43 v1(62.74,32.32)
  BOTTOM w0.127: v1(53.68,23.23) 53.68,17.15 53.29,16.76 R545.1 ; R479.2 v1(62.74,32.32)
  BOTTOM w0.132: v1(62.17,25.01) 62.19,24.99 R502.1
SOC_I2C2_SCL: length 36.9
  TOP w0.127: U12.H18 v1(32.87,110.93)
  TOP w0.132: U4.12 44.23,137.76 45.37,136.63 R30.2 v1(45.37,134.96)
  L03_SIG1 w0.107: v1(41.64,126.07) 41.64,126.53 42.15,127.03 42.61,127.03 43.37,127.8 43.37,131.63 45.37,133.63 v1(45.37,134.96)
  BOTTOM w0.132: v1(32.87,110.93) 33.27,111.34 33.27,112.46 33.11,112.62 33.11,116.26 34.65,117.79 35.98,117.79 36.62,118.43 36.62,123.77 39.15,126.29 41.02,126.29 41.24,126.07 v1(41.64,126.07)
SOC_I2C2_SDA: length 36.8
  TOP w0.127: U12.H19 v1(32.87,111.73)
  TOP w0.132: U4.13 44.88,137.72 46.24,136.36 R29.2 v1(46.24,134.99)
  L03_SIG1 w0.107: v1(46.24,134.99) 46.24,133.95 43.7,131.4 43.7,127.59 v1(42.45,126.35)
  BOTTOM w0.132: v1(42.45,126.35) 42.06,126.35 41.83,126.58 39.02,126.58 36.34,123.89 36.34,118.58 35.84,118.07 34.53,118.07 32.78,116.31 32.78,112.53 32.87,112.43 v1(32.87,111.73)
SOC_MMC0_CLK: length 4.4
  TOP w0.132: R91.2 43.85,93.84 43.48,94.2 43.48,96.32 U12.Y1
SOC_MMC0_CMD: length 28.2
  TOP w0.127: U12.V3 v1(41.67,98.14) ; v1(49.38,79.36) 49.38,79.11 U21.M5
  L06_SIG2 w0.107: v1(49.38,79.36) 49.66,79.64 49.66,82.31 49.23,82.73 49.23,84.28 50.32,85.37 50.32,87.68 49.53,88.47 49.53,94.92 47.52,96.93 42.04,96.93 41.67,97.29 v1(41.67,98.14)
  BOTTOM w0.127: R398.2 v1(49.38,79.36)
SOC_MMC0_DAT0: length 20.7
  TOP w0.127: v1(41.84,95.8) 41.84,96.2 41.68,96.36 41.68,97.33 U12.V2
  TOP w0.132: U21.A3 48.63,84.65 47.93,85.35 v1(47.93,85.93) 47.73,86.12 47.73,86.24 47.38,86.59 47.38,87.11 47.03,87.46 46.44,87.46 45.86,88.05 R109.2
  BOTTOM w0.132: v1(47.93,85.93) 47.73,86.13 47.48,86.13 47.24,86.37 46.65,86.37 44.84,88.18 44.84,89.52 41.84,92.52 v1(41.84,95.8)
SOC_MMC0_DAT1: length 21.1
  TOP w0.132: U21.A4 49.13,85.01 48.74,85.4 v1(48.74,85.93) 48.74,86.2 48.44,86.5 48.44,86.63 48.32,86.75 48.32,87.17 47.38,88.11 R111.2 ; v1(43.03,95.77) 42.56,95.3 41.58,95.3 41.27,95.61 U12.V1
  BOTTOM w0.132: v1(48.74,85.93) 48.18,86.49 47.66,86.49 47.38,86.77 47.38,87.11 45.55,88.95 45.55,90.13 42.71,92.97 42.71,95.45 v1(43.03,95.77)
SOC_MMC0_DAT2: length 23.2
  TOP w0.127: U12.W2 v1(42.47,97.34)
  TOP w0.132: U21.A5 49.63,85.46 49.55,85.54 v1(49.55,85.93) 49.55,86.39 49.15,86.79 49.15,87.67 48.9,87.91 R113.2
  BOTTOM w0.132: v1(42.47,97.34) 42.19,97.05 41.98,97.05 41.13,96.21 41.13,92.21 44.1,89.24 44.1,87.89 46.64,85.36 48.98,85.36 v1(49.55,85.93)
SOC_MMC0_DAT3: length 21.2
  TOP w0.081: 47.88,84.55 47.88,84.11 U21.B2
  TOP w0.127: U12.W1 42.07,96.77 v1(42.35,96.48)
  TOP w0.132: R107.2 44.33,87.61 46.01,85.93 v1(46.99,85.93) 46.99,85.45 47.88,84.55
  BOTTOM w0.132: v1(46.99,85.93) 46.59,85.93 44.46,88.06 44.46,89.38 41.49,92.35 41.49,93.46 41.37,93.58 41.37,96 41.85,96.48 v1(42.35,96.48)
SOC_MMC0_DAT4: length 20.1
  TOP w0.081: U21.B3 48.38,84.11 48.38,84.54
  TOP w0.127: U12.Y2 v1(43.27,97.34)
  TOP w0.132: R108.2 45.09,87.69 45.84,86.95 v1(46.99,86.95) 46.99,86.49 47.38,86.1 47.38,85.54 48.38,84.54
  BOTTOM w0.132: v1(46.99,86.95) 45.19,88.74 45.19,89.81 42.35,92.65 42.35,95.89 42.78,96.32 42.78,96.85 v1(43.27,97.34)
SOC_MMC0_DAT5: length 20.8
  TOP w0.081: U21.B4 48.88,84.11 48.88,84.79
  TOP w0.127: U12.W3 v1(42.47,98.14)
  TOP w0.132: R110.2 46.62,88.07 46.87,87.81 47.18,87.81 47.73,87.26 47.73,87.14 v1(47.93,86.95) 47.93,86.55 48.09,86.39 48.09,86.35 48.34,86.09 48.34,85.33 48.88,84.79
  BOTTOM w0.132: v1(42.47,98.14) 42.87,97.73 43.43,97.73 43.67,97.5 43.67,97.17 43.43,96.93 43.43,95.61 43.06,95.24 43.06,93.12 45.9,90.28 45.9,89.37 47.93,87.34 v1(47.93,86.95)
SOC_MMC0_DAT6: length 22.5
  TOP w0.081: 49.38,84.74 49.38,84.11 U21.B5
  TOP w0.127: U12.W4 v1(41.67,98.94)
  TOP w0.132: 49.38,84.74 49.38,85.2 49.15,85.43 49.15,86.29 48.79,86.64 48.79,86.89 v1(48.74,86.95) 48.74,87.58 48.14,88.17 R112.2
  BOTTOM w0.132: v1(48.74,86.95) 48.46,87.23 48.46,87.31 46.25,89.52 46.25,90.43 43.41,93.27 43.41,95.26 43.66,95.51 43.66,96.36 44.47,97.17 44.47,97.53 43.47,98.53 42.87,98.53 42.47,98.94 v1(41.67,98.94)
SOC_MMC0_DAT7: length 24
  TOP w0.081: 49.88,84.69 49.88,84.11 U21.B6
  TOP w0.127: U12.V4 v1(40.87,99.73)
  TOP w0.132: 49.88,84.69 49.88,85.49 49.95,85.56 49.95,86.55 v1(49.55,86.95) 49.55,87.34 49.67,87.46 R114.2
  BOTTOM w0.132: v1(49.55,86.95) 46.61,89.89 46.61,90.57 43.78,93.4 43.78,95.23 43.9,95.36 43.9,96.13 44.72,96.94 44.72,98.06 43.45,99.33 41.27,99.33 v1(40.87,99.73)
SOC_MMC2_CLK: length 7.2
  TOP w0.132: R40.1 29.46,119 29.46,117.27 30.66,116.08 30.66,113.52 30.87,113.31 U12.E21
SOC_OSPI_DQ0: length 8.8
  TOP w0.127: U12.F18 v1(31.27,110.93)
  TOP w0.132: v1(31.07,117.79) 31.08,117.79 31.08,118.18 31.05,118.21 RA2.5
  BOTTOM w0.132: v1(31.27,110.93) 30.87,111.34 30.87,111.9 30.48,112.29 30.48,116.05 31.27,116.84 31.27,116.84 31.32,116.89 31.32,117.17 31.07,117.41 v1(31.07,117.79)
SOC_OSPI_DQ1: length 9.5
  TOP w0.127: U12.G17 v1(32.07,110.13)
  TOP w0.132: RA2.6 31.45,118.02 31.56,117.91 31.56,116.79 31.68,116.66 v1(31.68,116.26)
  BOTTOM w0.132: v1(31.68,116.26) 31.68,115.12 31.24,114.68 31.24,112.46 31.67,112.02 31.67,110.53 v1(32.07,110.13)
SOC_OSPI_DQ2: length 5.9
  TOP w0.132: U12.F21 31.67,114.76 32.43,115.52 32.43,116.72 32.33,116.82 32.33,117.9 32.25,117.99 RA2.8
SOC_OSPI_DQ3: length 6.9
  TOP w0.132: RA2.7 31.85,117.83 32.05,117.62 32.05,116.7 32.15,116.61 32.15,115.69 31.28,114.82 31.28,112.53 U12.F20
SOC_OSPI_DQ4: length 5.9
  TOP w0.132: RA3.5 33.49,117.55 33.13,117.19 33.13,115.03 32.47,114.37 U12.G21
SOC_OSPI_DQ5: length 6.1
  TOP w0.132: U12.H21 33.27,113.13 34.07,113.92 34.07,115.81 33.83,116.05 33.83,117.06 34.29,117.52 RA3.7
SOC_OSPI_DQ6: length 6.8
  TOP w0.132: RA3.6 33.89,117.52 33.42,117.05 33.42,114.89 32.87,114.33 32.87,112.53 U12.G20
SOC_OSPI_DQ7: length 6.3
  TOP w0.132: RA3.8 34.69,118.13 35.36,117.46 35.36,115.82 34.62,115.07 34.62,113.76 34.07,113.22 U12.J21
SOC_PORZ: length 42.3
  L03_SIG1 w0.107: v1(30.95,16.42) 31.83,17.29 34.57,17.29 44.51,27.23 44.51,36.41 45.09,36.99 50.95,36.99 50.95,36.99 v1(51.33,36.99)
  BOTTOM w0.127: U72.3 56.13,36.99 55.92,37.2 55.92,37.61 ; U89.4 31.6,16.39 R538.2 v1(30.95,16.42)
  BOTTOM w0.132: 55.92,37.61 55.73,37.81 54.67,37.81 54.44,37.57 54.44,36.99 54.3,36.85 51.9,36.85 51.76,36.99 v1(51.33,36.99)
SOC_RGMII_MDC: length 71.9
  TOP w0.127: U12.V17 v1(41.67,110.13)
  TOP w0.132: v1(63.87,88.9) 63.87,89.4 63.7,89.56 R102.1 63.26,89.77 63.59,90.1 63.59,90.97 63.6,90.98 63.6,91.47 62.64,92.43 62.64,96.27 63.12,96.75 63.32,96.75 63.91,97.33 64.03,97.33 64.04,97.32 64.69,97.32 64.7,97.33 65.43,97.33 66.62,98.53 66.62,101.76 62.77,105.61 v1(62.61,105.61)
  L06_SIG2 w0.107: v1(63.87,88.9) 63.18,89.59 61.14,89.59 60.4,90.32 60.4,99.44 59.99,99.85 59.99,104.47 58.88,105.59 58.32,105.59 50.62,113.28 46.99,113.28 46.8,113.09 44.62,113.09 44.39,113.32 43.98,113.32 43.54,112.88 43.54,111.02 42.86,110.34 42.86,109.89 42.71,109.74 42.07,109.74 v1(41.67,110.13)
  BOTTOM w0.132: R644.1 63.29,106.3 v1(62.61,105.61)
SOC_RGMII_MDIO: length 69.7
  TOP w0.127: U12.U16 v1(40.87,109.33)
  TOP w0.132: v1(62.69,106.58) 62.61,106.58 62.18,106.15 62.18,105.23 64.06,103.35 64.64,103.35 66.34,101.65 66.34,98.64 65.31,97.61 64.59,97.61 64.57,97.6 64.16,97.6 64.14,97.61 63.17,97.61 63.13,97.58 63.02,97.58 60.35,94.91 60.35,92.43 60.63,92.15 R98.1 59.47,91.19 v1(58.71,90.43) ; v1(58.71,112.99) 59.47,113.75 R646.1
  L06_SIG2 w0.107: v1(58.71,90.43) 58.35,90.43 57.47,91.31 56.03,91.31 55.92,91.19 55.37,91.19 52.46,94.1 52.46,100.28 52.82,100.64 52.82,102.5 50.77,104.55 49.86,104.55 49.47,104.94 40.73,104.94 40.49,105.18 40.49,108.95 v1(40.87,109.33)
  BOTTOM w0.132: v1(62.69,106.58) 62.46,106.81 62.23,106.81 61.52,107.52 61.52,108.66 59.77,110.41 59.08,110.41 58.37,111.12 58.37,112.45 58.49,112.57 58.49,112.74 58.71,112.96 v1(58.71,112.99)
SOC_SPI0_CLK: length 93.3
  TOP w0.132: U12.D12 v1(29.67,106.13)
  L06_SIG2 w0.107: v1(29.67,106.13) 29.29,105.75 27.59,105.75 26.82,106.52 25.5,106.52 24.44,105.47 21.35,105.47 21.19,105.31 16.38,105.31 14.27,107.43 12.89,107.43 8.54,111.77 8.54,120.36 8.53,120.37 8.53,122.1 8.7,122.26 8.7,126.18 10.29,127.78 10.29,129.39 10.71,129.81 10.71,131.31 11.97,132.57 12.58,132.57 13.88,133.87 18.8,133.87 18.94,134 20.57,134 21.6,132.98 34.75,132.98 36.74,134.96 39.43,134.96 41.49,137.02 52.94,137.02 53.04,136.92 v1(53.42,136.92)
  BOTTOM w0.132: U43.4 v1(53.42,136.92)
SOC_SPI0_CS0: length 105.7
  TOP w0.132: U12.C11 29.27,104.99 v1(28.92,105.34)
  L06_SIG2 w0.107: v1(28.92,105.34) 27.7,105.34 27.29,105.75 25.32,105.75 24.78,105.22 21.5,105.22 21.34,105.06 14.79,105.06 13.85,106 13.02,106 8.29,110.73 8.29,112.66 6.28,114.67 6.28,125.59 8.14,127.44 8.14,128.61 9.01,129.48 9.75,129.48 10.5,130.23 10.5,131.63 11.79,132.93 12.4,132.93 14.24,134.76 17.68,134.76 17.97,134.47 20.68,134.47 21.91,133.23 34.5,133.23 36.51,135.24 39.28,135.24 41.46,137.42 50.76,137.42 52.59,139.25 58.02,139.25 58.2,139.07 61.63,139.07 v1(62.07,139.52)
  BOTTOM w0.132: U43.9 v1(62.07,139.52)
SOC_SPI0_D0: length 93.8
  TOP w0.132: U12.C12 v1(28.87,106.13)
  L06_SIG2 w0.107: v1(53.35,138.87) 53.07,138.59 53.07,137.57 53.32,137.32 53.56,137.32 53.81,137.07 53.81,136.64 53.33,136.15 45.4,136.15 43.95,134.7 36.99,134.7 34.98,132.69 20.8,132.69 20.26,133.23 19.25,133.23 18.82,132.8 14.15,132.8 12.82,131.47 12.82,130.31 12.2,129.69 11.46,129.69 10.5,128.73 10.5,127.57 9.05,126.12 9.05,122.28 9.41,121.93 9.41,121.61 8.9,121.1 8.9,111.88 13.09,107.68 14.38,107.68 16.49,105.57 21.06,105.57 21.22,105.72 23.55,105.72 23.8,105.98 23.8,106.04 24.48,106.72 27.08,106.72 27.67,106.13 v1(28.87,106.13)
  BOTTOM w0.132: U43.7 v1(53.35,138.87)
SOC_SPI2_CLK: length 97.6
  TOP w0.127: U12.D16 v1(29.67,109.33)
  L03_SIG1 w0.107: v1(38.95,135.71) 36.08,132.83 36.08,127.62 v1(37.32,126.37) 40.4,126.37 41.11,125.66 42.33,125.66 43.58,126.92 48.18,126.92 48.45,127.19 v1(48.45,127.38)
  BOTTOM w0.132: U42.7 80.16,141.92 79.22,142.86 76.54,142.86 68.77,135.09 66.58,135.09 65.09,133.59 51.93,133.59 51.11,132.77 49.26,132.77 48.45,131.96 v1(48.45,127.38) ; v1(38.95,135.71) 38.95,136.1 38.45,136.6 U44.8 ; v1(37.32,126.37) 37.32,125.49 33.5,121.66 30.5,121.66 28.04,119.2 28.04,117.93 29.83,116.13 29.83,113.58 29.19,112.93 28.71,112.93 27.68,111.91 27.68,110.78 26.71,109.81 26.55,109.81 26.23,109.49 26.23,109.17 26.46,108.93 29.27,108.93 v1(29.67,109.33)
SOC_SPI2_CS0: length 145.5
  TOP w0.127: U12.D15 v1(29.67,108.53)
  L06_SIG2 w0.107: v1(37.85,148.79) 39.04,148.79 40.87,146.96 48.84,146.96 50.37,145.44 60.7,145.44 63.77,142.38 77.39,142.38 v1(78.15,141.61) ; v1(29.67,108.53) 29.89,108.32 29.89,108.29 30.09,108.1 30.09,107.58 30.34,107.32 30.62,107.32 30.85,107.09 30.85,105.67 29.89,104.7 25.96,104.7 25.8,104.87 25.48,104.87 25.32,104.71 22.03,104.71 21.06,103.74 16.94,103.74 16.68,104 15.09,104 14.46,104.63 13.54,104.63 5.78,112.39 5.78,125.87 7.72,127.81 7.72,131.24 9.56,133.08 10.73,133.08 14.07,136.42 37.82,136.42 v1(38.97,137.58)
  BOTTOM w0.132: v1(37.85,148.79) 37.85,148.11 39.73,146.23 39.73,138.33 v1(38.97,137.58) 38.58,137.58 38.39,137.4 U44.6 ; v1(78.15,141.61) 78.15,141.33 78.21,141.26 U42.4
SOC_SPI2_D0: length 118.9
  TOP w0.127: U12.B18 v1(28.87,110.14)
  TOP w0.132: v1(35.09,125.38) 33.16,127.31 33.16,131.61 35.11,133.56 39.78,133.56 v1(40.45,132.89)
  L03_SIG1 w0.107: v1(62.52,144.64) 62.52,143.7 60.33,141.51 60.33,140.95 v1(58.89,139.51) ; v1(28.87,110.14) 29.28,110.55 30.67,110.55 30.87,110.75 30.87,112.12 29.56,113.43 v1(27.91,113.43) ; v1(40.45,132.89) 40.45,135.36 v1(39,136.82)
  L06_SIG2 w0.107: v1(58.89,139.51) 58.5,139.51 58.38,139.63 52.53,139.63 50.61,137.7 39.88,137.7 v1(39,136.82)
  BOTTOM w0.132: v1(27.91,113.43) 28.2,113.72 28.91,113.72 29.32,114.14 29.32,115.7 27.4,117.62 27.4,119.46 30.24,122.3 33.23,122.3 35.09,124.15 v1(35.09,125.38) ; v1(39,136.82) 38.82,137 U44.7 ; U42.9 80.81,135.65 81.92,136.76 81.92,142.54 79.14,145.32 79.14,152.43 78.1,153.48 66.13,153.48 62.6,149.94 62.6,148.78 62.59,148.78 62.59,148.55 62.63,148.51 62.63,148.5 63,148.13 63,145.12 v1(62.52,144.64)
SOC_SPI2_D1: length 98.4
  TOP w0.132: v1(26.45,110.55) 27.02,110.55 27.46,110.11 28.1,110.11 U12.B17
  L03_SIG1 w0.107: v1(35.74,126.49) 35.74,133.9 v1(37.55,135.71)
  BOTTOM w0.132: v1(37.55,135.71) 37.55,135.74 37.44,135.85 37.19,135.85 37.13,135.9 U44.9 ; v1(26.45,110.55) 26.49,110.59 26.49,111.2 28.69,113.4 29.08,113.4 29.58,113.9 29.58,115.84 27.68,117.73 27.68,119.34 30.36,122.02 33.35,122.02 35.74,124.41 v1(35.74,126.49) 36.6,126.49 36.97,126.86 42.93,126.86 43.69,127.61 43.69,131.67 44.03,132.01 45.94,132.01 46.24,131.71 46.24,126.98 46.54,126.68 50.63,126.68 51.22,127.26 51.22,128.96 51.6,129.35 58.05,129.35 58.99,130.29 58.99,131.36 60.24,132.6 65.55,132.6 66.79,133.84 75.35,133.84 75.7,134.2 75.7,136.5 75.83,136.64 78.73,136.64 78.86,136.5 U42.12
SOC_TCK: length 143.6
  TOP w0.127: U12.C10 v1(29.67,103.74)
  L03_SIG1 w0.107: v1(52.42,18.6) 54.02,18.6 54.61,19.18 54.61,21.43 57.27,24.1 66.41,24.1 v1(67.96,22.55)
  L06_SIG2 w0.107: v1(29.67,103.74) 29.78,103.63 29.78,103.41 30.08,103.11 30.08,102.68 30.24,102.52 30.63,102.52 30.85,102.29 30.85,102.01 31.11,101.75 31.54,101.75 31.68,101.61 31.68,98.21 32.09,97.8 32.09,92.02 33.23,90.88 34.2,90.88 34.78,90.3 34.78,88.74 34.46,88.42 34.46,87.24 35.23,86.47 35.23,72.81 40.71,67.33 40.71,61.39 39.58,60.26 29.63,60.26 28.15,58.78 28.15,50.81 31.81,47.15 37.12,47.15 38.26,46.01 48.92,46.01 50.47,44.45 50.47,40.36 50.28,40.17 50.28,25.71 52.79,23.2 52.79,18.96 v1(52.42,18.6)
  BOTTOM w0.127: R522.1 51.72,18.6 v1(52.42,18.6) ; v1(67.96,22.55) 67.96,23.02 R508.1
SOC_TDI: length 171.7
  TOP w0.132: U12.D10 29.65,104.56 29.1,104.56 28.84,104.29 28.84,103.89 28.69,103.74 27.53,103.74 27.33,103.54 26.34,103.54 26.03,103.23 v1(25.15,103.23)
  L03_SIG1 w0.107: v1(51.29,26.55) 51.75,26.08 51.75,24.2 50.93,23.38 49.85,23.38 49.77,23.3 ; 49.77,23.3 49.7,23.38 49.06,23.38 48.83,23.15 48.83,22.65 48.07,21.89 48.07,21.44 48.34,21.17 48.34,17.54 47.55,16.74 46.19,16.74 45.96,16.98 43.77,16.98 43.55,16.75 43.55,15.85 41.86,14.16 30.41,14.16 26.18,18.39 26.18,19.03 19.99,25.23 19.99,31.4 19.72,31.67 19.72,42.54 19.44,42.82 19.44,48.22 18.83,48.83 18.83,49.68 18.34,50.16 18.19,50.16 16.99,51.36 15.52,51.36 12.79,54.09 12.79,55.36 12.4,55.76 12.4,58.14 9.76,60.78 9.76,73.43 11.45,75.12 11.45,80.88 13.47,82.89 13.47,90.14 14.02,90.69 14.02,91.28 15.11,92.37 15.73,92.37 16.12,92.77 16.12,93.62 17.17,94.67 17.17,97 18.02,97.85 18.02,98.79 19.79,100.56 20.14,100.56 22.36,102.78 22.95,102.78 23.4,103.23 v1(25.15,103.23) ; 49.77,23.3 v1(49.77,17.7)
  BOTTOM w0.127: U87.9 49.46,18.02 v1(49.77,17.7)
  BOTTOM w0.132: U84.6 66.74,22 66.64,22.1 66.36,22.1 66.01,22.45 66.01,22.86 65.88,22.99 64.35,22.99 63.78,23.57 63.78,24.79 62.02,26.54 57.22,26.54 56.45,25.77 55.75,25.77 54.67,24.7 53,24.7 51.97,25.72 51.97,25.89 51.6,26.27 51.57,26.27 v1(51.29,26.55)
SOC_TDO: length 169.1
  L03_SIG1 w0.107: v1(26.16,105.36) 26.16,106.17 25.84,106.49 24.3,106.49 23.54,105.74 21.24,105.74 19.32,103.82 17.69,103.82 16.11,102.24 16.11,100.94 15.6,100.44 15.6,95.37 12.84,92.6 11.24,92.6 8.2,89.56 8.2,83.04 8.96,82.29 8.96,81.3 8.74,81.08 8.74,78.13 8.19,77.58 8.19,59.15 10.78,56.57 10.78,55.71 10.52,55.45 10.52,51.69 11.23,50.98 11.23,50.31 14.51,47.02 14.51,41.16 14.52,41.15 14.52,41.11 16.37,39.26 16.37,33.48 17.16,32.69 17.16,15.36 18.02,14.5 19.27,14.5 20.61,13.17 23.26,13.17 24.66,11.76 24.66,9.06 27.43,6.29 31.49,6.29 32.09,6.89 40.3,6.89 v1(40.73,6.46) 41.28,7.02 41.28,11.69 44.93,15.33 50.4,15.33 50.78,15.72 50.78,15.91 53.18,18.31 54.14,18.31 54.9,19.06 54.9,19.94 v1(55.74,20.79)
  BOTTOM w0.127: v1(40.73,6.46) 41.26,6.99 41.26,7.68 41.13,7.81 U95.2 ; v1(55.74,20.79) 56.22,20.79 56.34,20.67 U82.2
  BOTTOM w0.132: v1(26.16,105.36) 26.62,104.91 27.79,104.91 28.37,104.33 R359.1
SOC_TDO_R: length 2
  TOP w0.132: U12.E10 v1(30.47,103.74)
  BOTTOM w0.132: v1(30.47,103.74) 30.47,103.74 29.87,104.33 R359.2
SOC_TMS: length 182
  TOP w0.132: U12.B11 28.07,105.34 v1(27.12,105.34)
  L03_SIG1 w0.107: v1(43.46,21.93) 40.54,19.02 40.54,16.69 38.68,14.83 30.69,14.83 27.54,17.98 27.54,19.19 26.4,20.33 25.83,20.33 21.45,24.71 21.45,35.39 20.78,36.06 20.78,41.04 21.33,41.59 21.33,48.01 20.83,48.51 20.83,51.99 20.32,52.5 19.56,52.5 17.93,54.13 17.93,57.84 17.48,58.29 13.21,58.29 10.43,61.07 10.43,67.07 12.68,69.32 12.68,74.12 14.37,75.81 14.37,77.38 13.78,77.97 13.78,82.25 14.14,82.61 14.14,89.64 16.79,92.3 16.79,93.34 17.84,94.39 17.84,95.62 18.71,96.49 18.71,97.26 19.93,98.48 19.93,99.08 21.23,100.38 22.05,100.38 23.19,101.53 25.28,101.53 25.84,102.1 25.84,102.55 26.66,103.36 27.32,103.36 27.72,103.77 27.72,103.79 27.76,103.83 27.76,104.35 27.72,104.39 27.72,104.45 27.12,105.05 v1(27.12,105.34) ; v1(50.61,17.7) 50.61,20.16 50.79,20.35 50.79,22.83 52.14,24.17 52.14,28.29 v1(51.71,28.71)
  BOTTOM w0.127: v1(50.61,17.7) 50.59,17.73 50.59,18.37 50.27,18.69 U87.8
  BOTTOM w0.132: v1(50.61,17.7) 50.61,17.3 49.98,16.67 45.94,16.67 45.17,17.44 45.17,18.02 44.41,18.78 44.41,21.37 43.85,21.93 v1(43.46,21.93) ; U84.8 67.54,22 67.65,22.11 68.29,22.11 68.53,22.34 68.53,23.25 67.4,24.37 67.4,25.32 65.9,26.82 61.84,26.82 61.05,27.62 57.88,27.62 56.31,26.05 55.63,26.05 54.56,24.98 53.11,24.98 52.25,25.84 52.25,26.01 51.71,26.55 v1(51.71,28.71)
SOC_TRST#: length 180.4
  TOP w0.132: v1(25.64,104.48) 26.14,104.48 26.59,104.94 U12.A11
  L03_SIG1 w0.107: v1(51.1,20) 51.37,20.27 51.37,21.52 51.4,21.54 51.4,21.55 51.64,21.79 51.64,23.33 52.6,24.29 v1(52.6,26.58) 52.6,28.82 52.31,29.11 51.29,29.11 51.03,28.85 51.03,26.85 48.2,24.02 46.39,24.02 45.23,22.86 45.23,22.42 41.44,18.64 41.44,16.52 41.44,16.52 41.44,15.79 40.26,14.61 30.6,14.61 27.26,17.94 27.26,19.15 26.31,20.11 25.74,20.11 21.23,24.62 21.23,35.3 20.54,35.99 20.54,47.77 19.68,48.62 19.68,50.67 19.87,50.86 19.87,51.55 18.08,53.34 16.08,53.34 15.47,53.95 15.47,55.55 15.14,55.88 13.41,55.88 12.88,56.42 12.88,58.29 10.21,60.96 10.21,67.17 12.46,69.42 12.46,74.69 13.2,75.43 13.2,76.19 13.55,76.54 13.55,82.34 13.91,82.7 13.91,89.73 16.57,92.39 16.57,93.43 17.62,94.48 17.62,95.72 18.48,96.58 18.48,97.35 19.71,98.58 19.71,99.24 21.21,100.74 22.05,100.74 23.13,101.82 24.23,101.82 25.01,102.6 25.56,102.6 26.55,103.59 27.14,103.59 27.25,103.69 27.3,103.69 27.54,103.93 27.54,104.26 27.3,104.49 27.25,104.49 27.11,104.62 25.78,104.62 v1(25.64,104.48)
  BOTTOM w0.127: 50.55,19.49 51.08,19.49 R519.1 v1(51.1,20)
  BOTTOM w0.132: U84.9 68.41,20.93 68.41,20.94 68.84,21.37 68.84,21.72 68.85,21.73 68.85,23.33 67.72,24.46 67.72,25.4 66,27.12 61.96,27.12 61.08,28 57.79,28 56.12,26.33 55.51,26.33 54.44,25.26 53.23,25.26 52.6,25.88 v1(52.6,26.58) ; 50.55,19.49 U87.6
SOC_UART0_RX_3V3: length 115.3
  TOP w0.132: v1(24.44,106.14) 25.15,106.84 27.36,106.84 U12.A13
  L03_SIG1 w0.107: v1(24.44,106.14) 23.65,105.34 21.16,105.34 19.41,103.59 18,103.59 17.61,103.21 17.61,102.12 15.83,100.33 15.83,95.27 12.93,92.38 11.48,92.38 8.48,89.37 8.48,83.09 9.18,82.38 9.18,81.21 8.96,80.99 8.96,78.03 8.42,77.49 8.42,59.25 11,56.66 11,55.4 10.74,55.14 10.74,52.88 11.84,51.79 11.84,50.01 14.74,47.11 14.74,41.21 16.6,39.35 16.6,33.57 17.39,32.78 17.39,15.45 18.08,14.76 19.58,14.76 20.1,14.24 21.82,14.24 v1(22.07,14.49)
  BOTTOM w0.127: v1(22.07,14.49) 21.53,14.49 21.11,14.07 U92.8
SOC_UART0_TX_3V3: length 117.4
  TOP w0.132: U12.E11 30.46,105.34 v1(29.63,105.34)
  L03_SIG1 w0.107: v1(25.69,106.14) 24.67,105.11 21.25,105.11 19.49,103.36 18.47,103.36 18.13,103.02 18.13,102.3 16.05,100.23 16.05,95.18 13.02,92.15 11.69,92.15 9.97,90.44 9.97,81.68 9.19,80.9 9.19,77.94 8.64,77.4 8.64,59.43 11.28,56.79 11.28,54.83 11.66,54.44 11.66,52.34 12.06,51.95 12.06,50.78 12.75,50.09 16.2,50.09 16.5,49.78 16.5,48.37 16.92,47.96 16.92,40.55 17.39,40.07 17.39,33.09 17.61,32.88 17.61,15.55 18.15,15.01 20.03,15.01 v1(20.17,14.86)
  BOTTOM w0.127: R554.2 20.38,15.07 v1(20.17,14.86) 20.31,14.72 U92.6
  BOTTOM w0.132: v1(25.69,106.14) 27.03,106.14 28.28,104.89 29.17,104.89 v1(29.63,105.34)
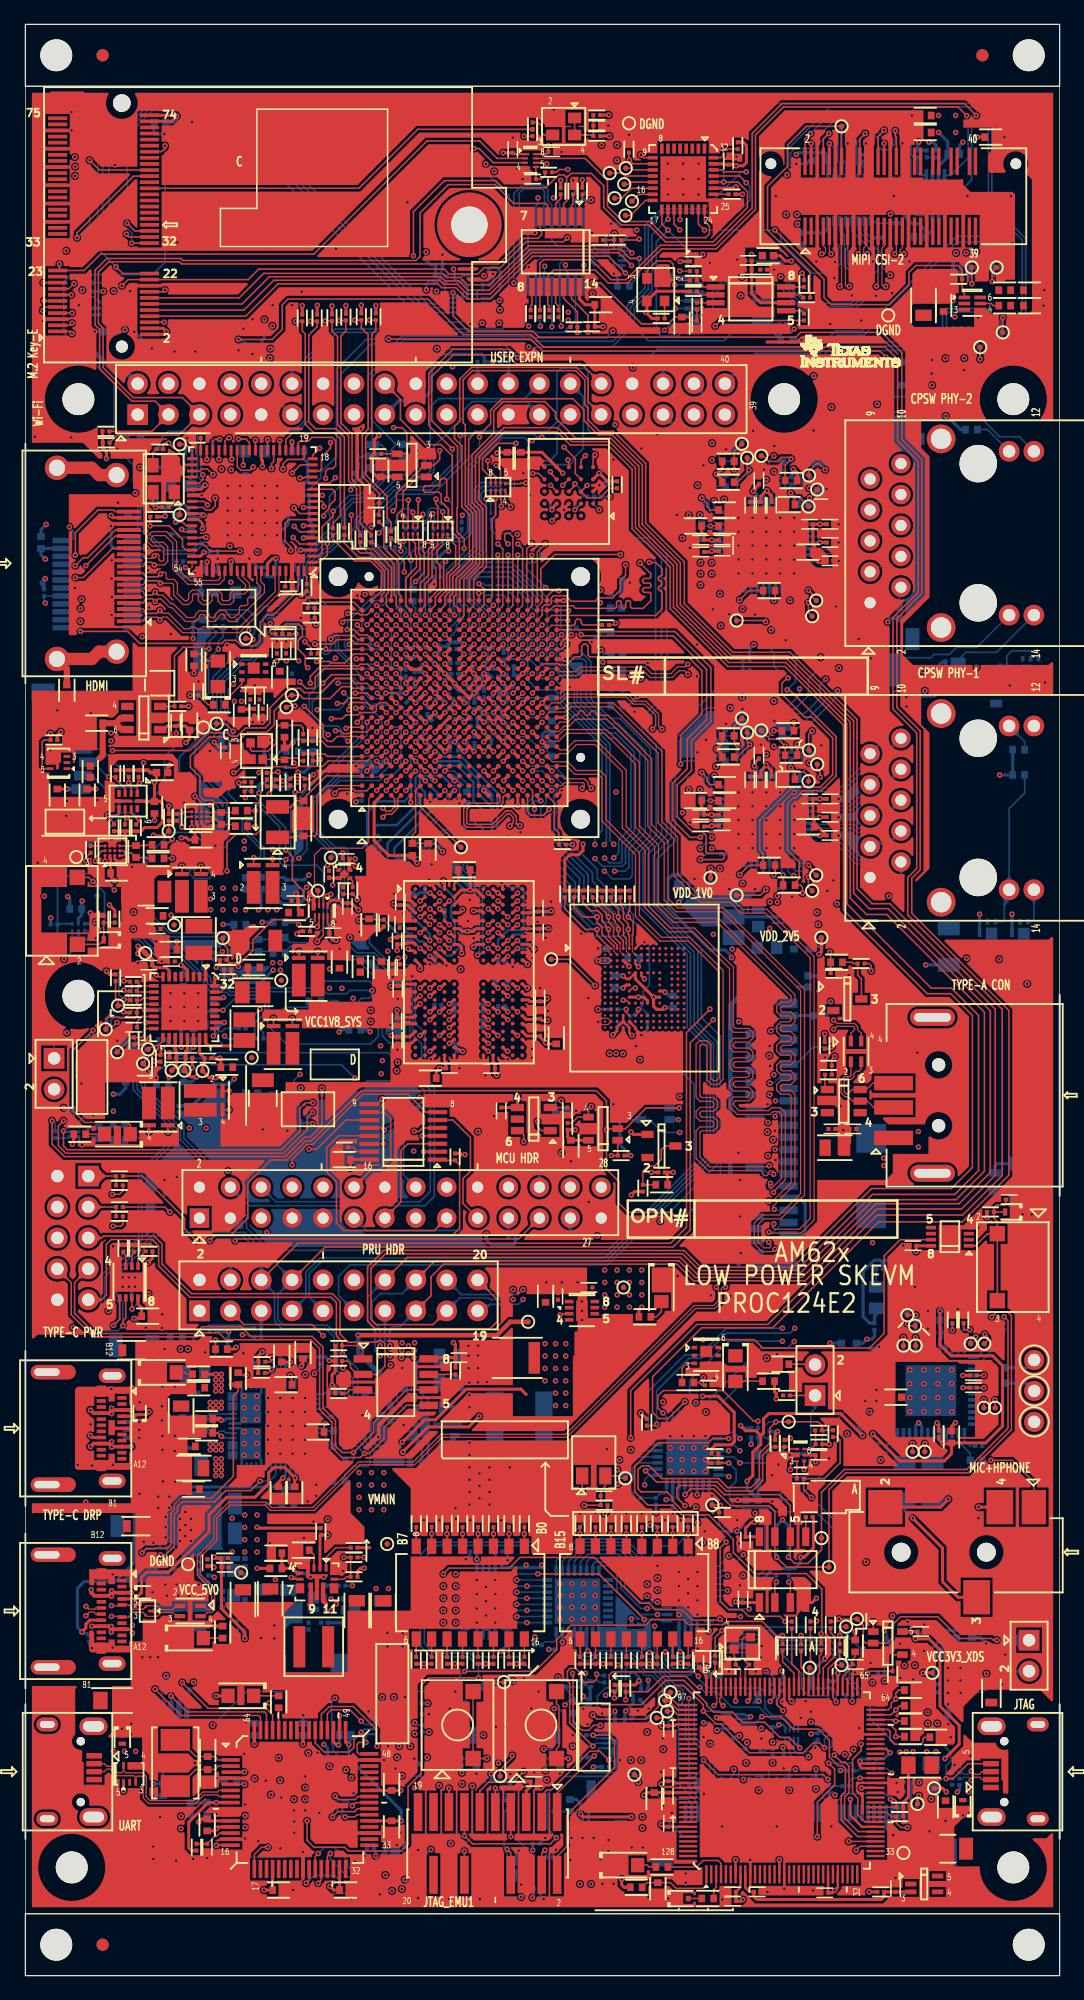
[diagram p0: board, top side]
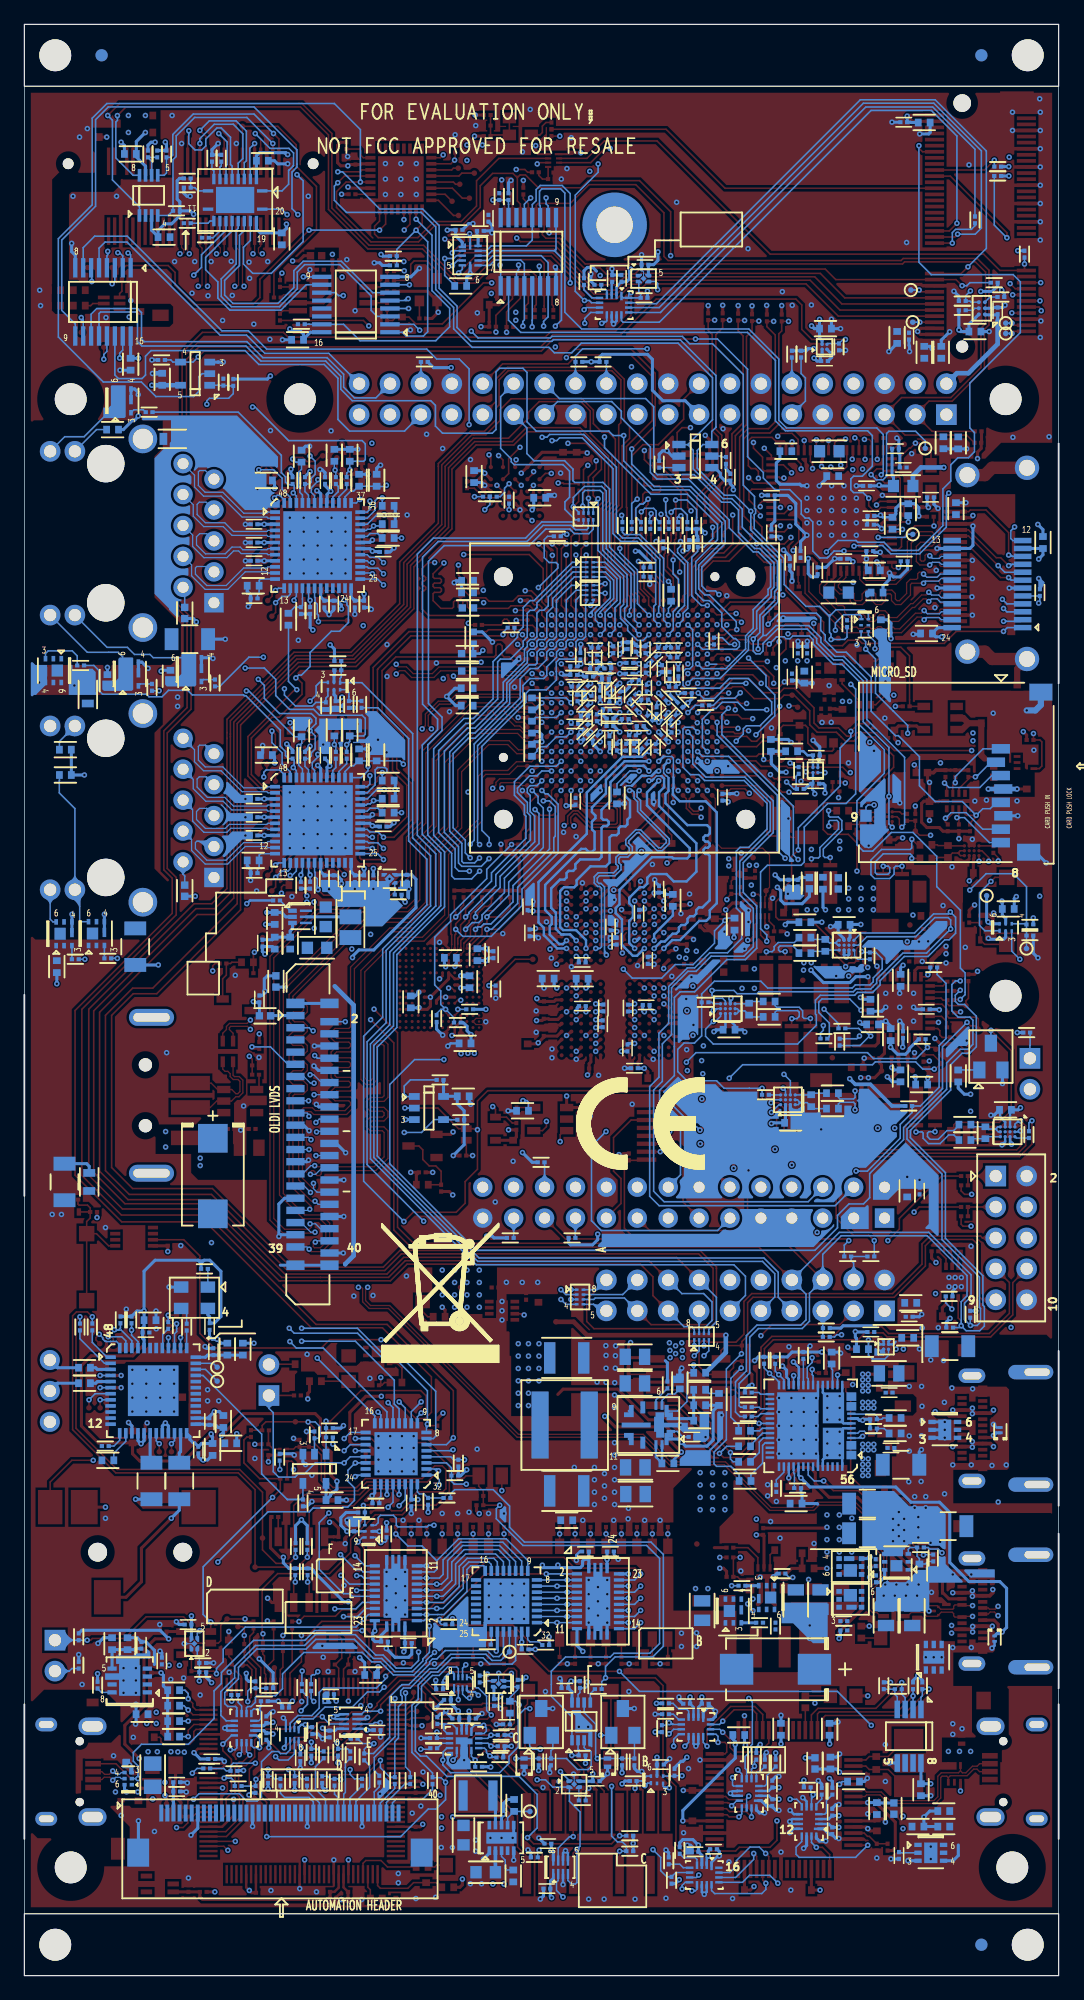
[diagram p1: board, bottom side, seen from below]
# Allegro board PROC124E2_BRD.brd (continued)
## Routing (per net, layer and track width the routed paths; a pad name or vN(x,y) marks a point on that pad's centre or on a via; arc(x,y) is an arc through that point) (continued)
SOC_UART1_CTS: length 177.9
  TOP w0.132: v1(80.32,136.18) TP12.1
  L03_SIG1 w0.107: v1(80.32,136.18) 80.32,133.09 76.09,128.85 73.78,128.85 72.86,127.94 72.86,125.45 73.77,124.54 73.77,113.52 71.56,111.31 71.56,106 68.01,102.45 68.01,88.27 72.02,84.26 72.02,75.4 69.66,73.04 69.66,61.88 76.02,55.52 76.02,54.07 77.21,52.88 77.21,49.86 77.63,49.44 77.63,44.31 64.65,31.33 63.55,31.33 59.59,27.36 54.72,27.36 54.54,27.19 54.54,24.75 52.66,22.87 52.66,21.58 52.97,21.26 52.97,19.35 52.69,19.07 52.26,19.07 51.81,18.62 51.81,17.26 50.83,16.29 50.22,16.29 49.49,15.56 44.84,15.56 41.77,12.49 41.75,12.49 41.75,12.49 34.44,12.49 33.75,11.8 33.75,10.1 33.03,9.39 31.54,9.39 30.13,7.98 v1(30.13,6.97)
  BOTTOM w0.127: v1(30.13,6.97) 29.85,6.97 29.72,7.1 U96.9
  BOTTOM w0.132: U42.10 80.16,136.02 v1(80.32,136.18)
SOC_UART1_CTS_BT: length 48.1
  TOP w0.132: J2.34 8.54,142.79 v1(8.3,143.02)
  BOTTOM w0.132: U44.14 32.83,137 16.04,153.78 10.26,153.78 6.35,149.87 6.35,143.53 6.85,143.02 v1(8.3,143.02)
SOC_UART1_RTS: length 170.9
  TOP w0.132: v1(78.47,132.75) TP13.1
  L03_SIG1 w0.107: v1(78.47,132.75) 78.47,131.87 75.93,129.33 73.25,129.33 72.41,128.5 72.41,125.25 73.28,124.38 73.28,113.79 71.6,112.12 71.07,112.12 70.45,111.5 70.45,110.57 70.72,110.3 70.72,105.82 67.56,102.67 67.56,87.3 71.17,83.69 71.17,75.18 69.2,73.21 69.2,61.71 75.57,55.33 75.57,44.99 74.99,44.41 74.99,42.76 65.49,33.26 62.04,33.26 58.66,29.89 56.73,29.89 55.61,28.76 54.39,28.76 53.4,27.77 53.4,24.38 52.16,23.14 52.16,21.59 51.93,21.36 51.93,19.9 51.36,19.33 51.36,17.45 50.64,16.73 50.03,16.73 49.31,16.01 44.66,16.01 41.59,12.94 41.57,12.94 41.56,12.94 34.25,12.94 v1(29.58,8.27)
  BOTTOM w0.127: v1(29.58,8.27) 29.78,8.06 U96.7 ; U42.13 78.21,133.4 78.47,133.14 v1(78.47,132.75)
SOC_UART1_RTS_BT: length 45.4
  TOP w0.132: J2.36 8.98,143.29 v1(8.36,143.92)
  BOTTOM w0.132: U44.12 35.93,135.93 35.8,135.8 32.81,135.8 15.42,153.19 10.46,153.19 8.36,151.09 v1(8.36,143.92)
SOC_UART1_RX_BT: length 51.2
  TOP w0.132: J2.22 8,139.79 v1(7.45,140.34)
  BOTTOM w0.132: v1(7.45,140.34) 5.94,141.85 5.94,149.86 10.14,154.06 16.3,154.06 33.05,137.31 34.59,137.31 34.68,137.4 U44.15
SOC_UART1_RXD: length 179.9
  TOP w0.132: v1(77.78,138.95) TP9.1
  L03_SIG1 w0.107: v1(30.95,7.12) 30.39,6.56 29.91,6.56 29.02,7.45 29.02,8.27 33.91,13.16 41.5,13.16 44.57,16.23 49.22,16.23 49.94,16.96 50.55,16.96 51.13,17.54 51.13,19.46 51.62,19.94 51.62,21.46 51.9,21.74 51.9,23.27 53.09,24.45 53.09,27.9 54.26,29.08 55.43,29.08 56.56,30.21 58.56,30.21 61.92,33.58 65.41,33.58 74.46,42.62 74.46,50.96 74.78,51.28 74.78,55.81 68.97,61.62 68.97,73.3 70.95,75.27 70.95,83.56 67.27,87.24 67.27,89.72 66.35,90.64 66.35,97.06 67.06,97.76 67.06,102.48 70.5,105.91 70.5,110.21 70.23,110.48 70.23,111.59 70.76,112.13 70.76,124.94 72.19,126.37 72.19,128.71 73.24,129.75 74.96,129.75 76.44,131.24 77.49,131.24 77.78,131.53 v1(77.78,138.95)
  BOTTOM w0.127: U96.8 30.69,7.66 30.95,7.4 30.95,7.12 v1(30.95,7.12)
  BOTTOM w0.132: U42.3 77.56,139.17 v1(77.78,138.95)
SOC_UART1_TX_BT: length 42.4
  BOTTOM w0.132: U44.13 32.72,136.6 15.85,153.47 10.34,153.47 6.88,150 R261.2
SOC_UART1_TXD: length 178.2
  TOP w0.132: v1(79.46,139.13) 79.46,139.93 TP10.1
  L03_SIG1 w0.107: v1(79.46,139.13) 79.86,138.73 79.86,132.94 75.99,129.08 73.68,129.08 72.64,128.03 72.64,125.36 73.54,124.45 73.54,113.61 71.32,111.39 71.32,106.08 67.79,102.54 67.79,88.18 71.76,84.2 71.76,75.46 69.44,73.14 69.44,61.78 75.8,55.43 75.8,53.97 76.66,53.11 76.66,45.86 76.97,45.55 76.97,44.06 64.53,31.62 63.4,31.62 59.44,27.66 54.6,27.66 54.25,27.31 54.25,24.82 52.4,22.97 52.4,21.45 52.71,21.13 52.71,20.37 51.58,19.24 51.58,17.36 50.73,16.51 50.13,16.51 49.4,15.78 44.75,15.78 41.68,12.72 41.66,12.72 41.66,12.71 34.35,12.71 33.34,11.71 v1(33.34,10.35)
  BOTTOM w0.127: U96.6 31.46,8.46 R566.2 32.2,8.11 32.7,8.62 32.7,9.71 v1(33.34,10.35)
  BOTTOM w0.132: U42.6 79.46,140.21 v1(79.46,139.13)
SOC_USB0_DM: length 136.9
  TOP w0.11: v1(52.31,102.4) 52.04,102.66 52.04,103.61 50.98,104.67 50.08,104.67 49.51,105.24 44.34,105.24 44.03,104.94 U12.AA11 ; v1(57.55,56.54) 57.31,56.54 57.2,56.43 57.2,55.34 56.65,54.8 55.08,54.8 44.5,44.22 34.25,44.22 31.99,41.96 27.48,41.96 23.73,38.21 20.13,38.21 19.69,38.64 16.81,38.64 15.73,37.56 15.73,35.74 14.37,34.38 14.37,32.98 15.55,31.8 15.55,30.08 15.3,29.83 14.94,29.83 14.64,29.52 L5.4
  L06_SIG2 w0.097: v1(57.55,56.54) 57.21,56.87 57.21,57.03 57.38,57.19 63.13,57.19 67.86,61.92 67.86,81.09 67.06,81.89 67.06,87.01 66.11,87.96 63.09,87.96 62.76,87.63 58.27,87.63 57.38,88.52 57.38,89.2 56.25,90.33 55.77,90.33 52.02,94.08 52.02,102.11 v1(52.31,102.4)
SOC_USB0_DP: length 136.8
  TOP w0.11: v1(56.79,56.54) 56.96,56.37 56.96,55.44 56.55,55.04 54.98,55.04 44.4,44.46 34.15,44.46 31.89,42.2 27.38,42.2 23.63,38.45 20.23,38.45 19.79,38.88 16.71,38.88 15.49,37.66 15.49,35.84 14.13,34.48 14.13,32.88 15.31,31.7 15.31,30.18 15.2,30.07 14.96,30.07 14.65,30.37 L5.1 ; U12.Y10 43.27,104.53 43.97,104.53 44.44,105 49.41,105 49.98,104.43 50.88,104.43 51.8,103.51 51.8,102.65 v1(51.55,102.4)
  L06_SIG2 w0.097: v1(51.55,102.4) 51.77,102.17 51.77,93.98 55.67,90.08 56.15,90.08 57.13,89.1 57.13,88.41 58.17,87.38 62.87,87.38 63.2,87.71 66.01,87.71 66.81,86.91 66.81,81.79 67.61,80.99 67.61,62.02 63.03,57.44 57.28,57.44 56.96,57.12 56.96,56.71 v1(56.79,56.54)
SOC_USB0_DRVVBUS: length 119.8
  TOP w0.127: U12.D17 v1(30.47,110.13)
  TOP w0.132: v1(16.93,48.55) 16.93,48.54 R166.1 17.49,47.99 17.09,47.59 17.09,41.02 15.29,39.22 12.79,39.22 12.23,38.66 12.23,38.26 11.96,38 11.96,35.4 11.65,35.09 9.94,35.09 v1(9.59,34.73)
  L06_SIG2 w0.107: v1(16.93,48.55) 17.48,47.99 23.53,47.99 24.14,48.6 24.14,50.94 22.97,52.1 22.97,66.61 24.75,68.39 24.75,78.01 23.6,79.16 23.6,87.15 24.05,87.6 24.05,90.42 23.47,91.01 23.47,96.88 25.56,98.97 25.56,100.2 25.56,101.23 v1(24.88,101.91) ; v1(26.87,32.02) 18.95,32.02 15.93,35.05 9.91,35.05 v1(9.59,34.73) ; v1(30.47,110.13) 30.47,110 30.08,109.61 30.08,109.21 29.82,108.95 26.47,108.95 26.47,108.95 26.22,108.95 v1(25.49,108.21)
  BOTTOM w0.132: R475.1 10.73,35.17 10.6,35.04 9.89,35.04 v1(9.59,34.73) ; R592.1 v1(26.87,32.02) ; v1(25.49,108.21) 24.05,106.77 24.05,105.91 23.33,105.19 23.33,103.46 v1(24.88,101.91)
SOC_USB0_RCALIB: length 4.7
  TOP w0.127: U12.T8 v1(40.07,102.14)
  BOTTOM w0.127: v1(40.07,102.14) 40.47,101.74 41.28,101.74 41.88,101.14
  BOTTOM w0.132: 41.88,101.14 42.09,100.93 42.64,100.93 42.87,100.7 42.87,100.56 R366.1
SOC_USB0_VBUS: length 67.8
  TOP w0.254: U12.V10 v1(41.67,103.74) ; v1(53.25,65.97) R143.1 52.57,65.97 52.78,65.76 R145.1
  L06_SIG2 w0.254: v1(41.67,103.74) 41.67,102.91 42.11,102.46 48.59,102.46 50.69,100.37 50.69,93.1 63.6,80.19 63.6,63.35 62.64,62.38 59.36,62.38 55.77,65.97 v1(53.25,65.97)
SOC_USB1_DM: length 43.7
  TOP w0.107: v1(42.47,102.94) 42.47,102.94 U12.W8
  TOP w0.11: L4.1 67.84,77.4 68.15,77.7 68.15,77.85 68.04,77.97 66.67,77.97 v1(66.42,77.72)
  L03_SIG1 w0.097: v1(66.42,77.72) 66.15,77.99 65.23,77.99 52.81,90.4 52.81,98.98 48.79,103 47.31,103 46.61,103.7 43.98,103.7 43.49,103.21 42.75,103.21 v1(42.47,102.94)
SOC_USB1_DP: length 44.1
  TOP w0.107: v1(42.47,103.74) 42.47,103.74 U12.W9
  TOP w0.11: v1(66.42,78.48) 66.69,78.21 68.14,78.21 68.39,77.95 68.39,77.7 68.69,77.4 L4.4
  L03_SIG1 w0.097: v1(42.47,103.74) 42.75,103.46 43.39,103.46 43.88,103.95 46.71,103.95 47.41,103.24 48.9,103.24 53.06,99.08 53.06,90.5 65.33,78.23 66.17,78.23 v1(66.42,78.48)
SOC_USB1_DRVVBUS: length 62.6
  TOP w0.127: U12.E16 v1(30.47,109.33)
  TOP w0.132: R132.1 R131.1 66.27,75.27 v1(66.51,75.5)
  L03_SIG1 w0.107: v1(66.51,75.5) 67.01,76 67.01,79.83 65.41,81.43 62.86,81.43 53.47,90.83 53.47,99.7 49.48,103.68 47.73,103.68 47.26,104.15 39.84,104.15 39.66,104.33 39.66,106.31 39.39,106.58 39.12,106.58 39.11,106.59 37.83,106.59 37.82,106.58 37.52,106.58 37.51,106.59 37.03,106.59 37.02,106.58 36.22,106.58 36.22,106.58 35.92,106.58 35.92,106.58 35.53,106.58 35.24,106.87 35.24,107.53 34.6,108.16 30.97,108.16 30.82,108.31 30.82,108.38 30.83,108.39 30.83,108.68 30.82,108.69 30.82,108.99 v1(30.47,109.33)
SOC_USB1_RCALIB: length 3.3
  TOP w0.127: U12.V9 v1(40.87,103.73)
  BOTTOM w0.127: R361.1 42.98,103.33 41.28,103.33 v1(40.87,103.73)
SOC_USB1_VBUS: length 42.8
  TOP w0.127: U12.U9 v1(40.07,103.74)
  TOP w0.132: R120.1 R118.1 66.17,83.89 66.12,83.95 66.12,84.05 v1(66.09,84.05)
  L06_SIG2 w0.107: v1(40.07,103.74) 40.45,104.12 48.61,104.12 51.21,101.52 51.21,93.32 57.66,86.87 65.33,86.87 66.05,86.15 66.05,84.09 v1(66.09,84.05)
SOC_VDDSHV5_SDIO: length 48.9
  TOP w0.254: U12.G14 32.32,107.34 32.26,107.28 31.88,107.28 31.82,107.34 U12.F14 v1(31.27,107.73) ; v1(11.86,99.44) 11.7,99.27 FL9.2
  L04_PWR01 w0.107: v1(31.27,107.73) 32.15,107.73 32.56,108.15 35.07,108.15 35.32,108.39
  L04_PWR01 w0.254: 36.05,111.72 35.32,110.98 35.32,108.39
  L04_PWR01 w0.381: 36.05,111.72 36.05,113.14 35.7,113.5 28.94,113.5 28.18,112.73 24.01,112.73 23.58,112.3 14.16,112.3 12.74,110.88 12.74,103.77 11.36,102.4 11.36,99.77 11.74,99.39 11.86,99.39 v1(11.86,99.44)
  BOTTOM w0.254: v1(31.27,107.73) 31.25,107.72 C257.1
SOC_VOUT0_DATA0: length 38.4
  TOP w0.127: v1(38.83,116.67) 38.83,116.28 38.87,116.24 U12.R21
  TOP w0.132: v1(16.75,126.3) 16.7,126.25 16.6,126.25 16.41,126.06 U11.32
  L06_SIG2 w0.107: v1(38.83,116.67) 36.3,119.21 36.3,120.35 35.34,121.31 35.34,121.67 33.78,123.23 33.21,123.23 33.03,123.41 23.22,123.41 22.14,124.49 17.99,124.49 17.74,124.75 17.74,125.29 17.62,125.41 17.47,125.41 17.35,125.3 17.35,124.28 17.18,124.11 16.82,124.11 16.52,124.42 16.52,124.8 16.4,124.91 15.87,124.91 15.78,125.01 15.78,125.12 15.86,125.21 16.82,125.21 16.9,125.28 16.9,125.41 16.85,125.46 16.06,125.46 15.99,125.53 15.99,125.69 16.06,125.76 16.6,125.76 16.75,125.91 v1(16.75,126.3)
SOC_VOUT0_DATA1: length 40.4
  TOP w0.127: U12.P18 v1(38.47,110.93)
  TOP w0.132: U11.31 16.91,124.69 16.93,124.67 16.93,124.58 v1(16.96,124.54)
  L03_SIG1 w0.107: v1(16.96,124.54) 16.75,124.75 16.51,124.75 16.39,124.63 16.39,124.12 16.52,123.99 16.52,123.42 16.84,123.1 18.56,123.1 18.9,122.76 22,122.76 22.18,122.58 22.76,122.58 23.02,122.83 23.02,123.53 23.35,123.86 26.37,123.86 29.11,121.12 29.11,119.99 30.57,118.53 31.31,118.53 31.78,118.06 31.78,117.15 32.72,116.2 32.72,116.02 33.68,115.06 35.53,115.06 36.77,116.3 37.84,116.3 38.84,115.3 40.83,115.3 41.13,115 41.13,114.54 38.83,112.24 38.83,111.29 v1(38.47,110.93)
SOC_VOUT0_DATA2: length 40.6
  TOP w0.127: U12.R18 v1(39.27,110.93)
  TOP w0.132: U11.30 17.41,123.94 17.72,123.63 18.44,123.63 v1(18.72,123.91)
  L03_SIG1 w0.107: v1(18.72,123.91) 19.25,123.39 20.4,123.39 20.71,123.69 20.71,123.85 21.3,124.44 26.66,124.44 28.59,122.52 29.41,122.52 29.79,122.14 29.79,120.12 30.81,119.1 31.55,119.1 32.36,118.3 32.36,117.39 33.47,116.27 33.47,116.13 34.06,115.53 35.22,115.53 36.66,116.97 37.96,116.97 38.95,115.97 42.16,115.97 42.43,115.71 42.43,114.88 39.63,112.08 39.63,111.29 v1(39.27,110.93)
SOC_VOUT0_DATA3: length 40.4
  TOP w0.127: U12.R19 v1(39.27,111.73)
  TOP w0.132: U11.29 v1(17.91,124.06)
  L03_SIG1 w0.107: v1(39.27,111.73) 39.27,112.26 42.07,115.07 42.07,115.4 41.85,115.63 38.9,115.63 37.98,116.55 36.62,116.55 35.38,115.3 33.85,115.3 33.11,116.05 33.11,116.23 32.07,117.27 32.07,118.18 31.43,118.81 30.69,118.81 29.4,120.1 29.4,121.25 26.5,124.15 22,124.15 21.6,123.75 21.6,123.63 21.06,123.09 19.11,123.09 18.8,123.39 17.83,123.39 17.32,123.89 17.32,124.2 17.88,124.76 18.06,124.76 18.23,124.59 18.23,124.38 v1(17.91,124.06)
SOC_VOUT0_DATA4: length 38.4
  TOP w0.127: v1(38.83,117.59) 39.24,117.18 39.24,112.5 U12.R20
  TOP w0.132: v1(17.51,126.2) 17.91,126.2 17.91,126.2 18.13,126.2 18.41,125.92 U11.28
  L06_SIG2 w0.107: v1(17.51,126.2) 17.51,126.2 17.26,126.2 17.15,126.09 17.15,125.82 17.23,125.74 17.75,125.74 18.67,124.82 22.28,124.82 23.36,123.74 33.16,123.74 33.34,123.56 33.92,123.56 34.18,123.3 35.67,121.81 35.67,121.44 36.62,120.49 36.62,119.34 38.02,117.95 38.17,117.95 38.21,117.99 38.21,118.14 37.05,119.3 37.05,119.45 37.15,119.55 37.29,119.55 38.44,118.4 38.44,117.64 38.55,117.53 38.77,117.53 v1(38.83,117.59)
SOC_VOUT0_DATA5: length 38.4
  TOP w0.127: U12.T20 40.07,112.53 40.07,118.17 39.76,118.48 39.52,118.48 39.39,118.35 39.39,117.87 v1(39.67,117.59)
  TOP w0.132: v1(18.91,126.09) U11.27
  L06_SIG2 w0.107: v1(18.91,126.09) 19.28,126.09 19.46,125.91 19.46,125.54 19.3,125.38 18.58,125.38 18.01,125.95 18.01,126.41 18.12,126.52 20.27,126.52 20.45,126.34 20.45,125.76 20.67,125.54 22.63,125.54 23.77,124.4 33.44,124.4 33.61,124.22 34.19,124.22 34.45,123.95 36.32,122.08 36.32,121.71 37.28,120.76 37.28,120.49 39.67,118.09 v1(39.67,117.59)
SOC_VOUT0_DATA6: length 38.4
  TOP w0.127: v1(39.67,116.67) U12.T21
  TOP w0.132: v1(19.91,126.14) U11.25
  L06_SIG2 w0.107: v1(19.91,126.14) 19.91,125.41 20.14,125.18 22.52,125.18 23.63,124.07 33.3,124.07 33.48,123.89 34.05,123.89 34.32,123.63 36,121.95 36,121.58 36.95,120.62 36.95,120.35 39.25,118.05 39.25,116.11 41.78,113.58 42.02,113.58 42.21,113.76 42.21,114 40.81,115.39 40.81,116.09 40.61,116.29 40.05,116.29 v1(39.67,116.67)
SOC_VOUT0_DATA7: length 40.6
  TOP w0.127: U12.T19 v1(40.07,111.73)
  TOP w0.132: v1(20.23,123.78) 20.23,124.17 20.41,124.36 U11.24
  L03_SIG1 w0.107: v1(20.23,123.78) 21.18,124.73 26.78,124.73 28.66,122.85 29.78,122.85 30.15,122.48 30.15,121.13 30.64,120.64 30.64,119.77 30.99,119.41 31.66,119.41 32.65,118.42 32.65,117.57 33.83,116.39 33.83,116.25 34.34,115.74 35,115.74 35.32,116.06 35.32,117.35 35.6,117.64 38.12,117.64 38.62,117.14 38.96,117.14 39.25,116.85 39.25,116.41 39.4,116.26 40.69,116.26 41.01,116.58 41.01,116.87 41.28,117.14 42.81,117.14 43.28,116.67 43.28,116.04 42.9,115.66 42.9,114.94 40.07,112.11 v1(40.07,111.73)
SOC_VOUT0_DATA8: length 38.4
  TOP w0.127: U12.U21 v1(40.47,116.67)
  TOP w0.132: U11.23 v1(20.91,126.08)
  L06_SIG2 w0.107: v1(40.47,116.67) 40.05,117.09 40.05,117.9 40,117.96 40,118.23 39.66,118.57 39.66,118.96 39.51,119.11 39.12,119.11 38.97,119.26 38.97,119.65 38.82,119.8 38.43,119.8 38.28,119.95 38.28,120.34 38.13,120.49 37.74,120.49 37.61,120.62 37.61,120.9 36.66,121.84 36.66,122.21 35.15,123.72 35.15,123.83 35.23,123.91 35.41,123.91 37.42,121.9 37.58,121.9 37.68,122 37.68,122.15 35.49,124.34 34.66,124.34 34.46,124.54 33.75,124.54 33.57,124.72 23.9,124.72 23.28,125.35 23.28,125.77 23.18,125.86 22.36,125.86 22.29,125.94 22.29,126.05 22.36,126.12 22.62,126.12 22.69,126.2 22.69,126.37 22.55,126.52 20.96,126.52 20.91,126.47 v1(20.91,126.08)
SOC_VOUT0_DATA9: length 38.4
  TOP w0.127: U12.R17 v1(39.27,110.13)
  TOP w0.132: v1(24.67,122.98) 24.67,123.55 24.9,123.77 25.27,123.77 25.5,124.01 25.5,126.05 25.22,126.33 23.55,126.33 23.25,126.03 22.57,126.03 22.41,125.87 U11.20
  L06_SIG2 w0.107: v1(39.27,110.13) 39.65,109.75 41.03,109.75 41.26,109.98 41.26,110.27 41.54,110.55 41.87,110.55 42.09,110.76 42.09,111.17 42.23,111.32 42.96,111.32 43.16,111.52 43.16,112.68 42.9,112.94 41.51,112.94 35.17,119.28 35.17,120.03 34.22,120.98 34.22,121.76 33.4,122.58 32.94,122.58 32.77,122.74 26.44,122.74 26.34,122.65 24.78,122.65 24.67,122.75 v1(24.67,122.98)
SOC_VOUT0_DATA10: length 38.5
  TOP w0.127: U12.T18 v1(40.07,110.93)
  TOP w0.132: U11.19 22.91,124.66 22.78,124.52 21.55,124.52 21.17,124.14 v1(21.17,123.75)
  L06_SIG2 w0.107: v1(21.17,123.75) 21.17,123.38 20.66,122.87 20.43,122.87 20.25,122.69 20.25,122 20.48,121.78 20.99,121.78 21.17,121.6 21.17,121.14 20.96,120.94 20.46,120.94 20.28,120.76 20.28,120.13 20.52,119.89 20.88,119.89 21.22,119.55 21.22,119.13 21.79,118.55 23.12,118.55 23.43,118.25 25.27,118.25 26.06,119.04 26.06,120.57 26.49,120.99 29.94,120.99 30.05,121.1 30.52,121.1 31.46,120.17 31.46,119.11 32.26,118.3 32.26,117.2 34.68,114.77 37.64,114.77 40.45,111.96 40.45,111.32 v1(40.07,110.93)
SOC_VOUT0_DATA11: length 38.5
  TOP w0.127: v1(40.47,117.59) 40.86,117.19 40.86,112.53 U12.U20
  TOP w0.132: U11.18 23.61,124.86 v1(24.19,125.44)
  L06_SIG2 w0.107: v1(40.47,117.59) 40.88,117.18 40.88,116.7 40.95,116.62 41.11,116.62 41.22,116.73 41.22,117.4 41.02,117.6 41.02,117.88 41.12,117.99 41.43,117.99 41.54,118.1 41.54,118.28 41.45,118.37 41.02,118.37 40.8,118.59 40.8,119.8 40.35,120.26 40.2,120.26 40.12,120.18 40.12,119.97 40.55,119.54 40.55,119.43 40.43,119.31 40.33,119.31 39.51,120.13 39.51,121.26 35.76,125 34.93,125 33.99,125.94 31.9,125.94 31.33,125.38 31.12,125.38 30.98,125.52 30.98,125.6 30.84,125.74 30.63,125.74 30.49,125.6 30.49,125.52 30.35,125.38 30.15,125.38 30,125.52 30,125.6 29.86,125.74 29.66,125.74 29.52,125.6 29.52,125.52 29.37,125.38 29.17,125.38 29.03,125.52 29.03,125.6 28.88,125.74 28.68,125.74 28.54,125.6 28.54,125.52 28.4,125.38 28.09,125.38 27.89,125.59 27.61,125.59 27.4,125.38 27.12,125.38 26.91,125.59 26.63,125.59 26.42,125.38 26.14,125.38 25.94,125.59 25.65,125.59 25.45,125.38 24.78,125.38 24.67,125.48 24.67,126.27 24.43,126.52 23.88,126.52 23.79,126.44 23.79,126.22 24.19,125.83 v1(24.19,125.44)
SOC_VOUT0_DATA12: length 38.5
  TOP w0.127: U12.U19 v1(40.87,111.73)
  TOP w0.132: U11.17 22.62,124.08 22.25,123.71 22.23,123.71 v1(21.95,123.43)
  L06_SIG2 w0.107: v1(21.95,123.43) 21.95,122.95 21.81,122.8 21.79,122.8 21.65,122.66 21.65,122.46 21.79,122.32 21.81,122.32 21.95,122.17 21.95,121.24 21.6,120.89 21.6,119.92 21.79,119.73 22.25,119.73 22.46,119.95 22.46,120.81 22.69,121.04 23.53,121.04 23.76,120.81 23.76,120.46 23.58,120.28 23.29,120.28 23.16,120.14 23.16,119.97 23.3,119.82 23.65,119.82 23.76,119.71 23.76,119.44 23.65,119.34 23.38,119.34 23.25,119.21 23.25,118.89 23.41,118.73 25.09,118.73 25.7,119.34 25.7,120.88 26.14,121.32 29.81,121.32 29.96,121.47 30.63,121.47 31.4,120.7 31.98,120.7 32.29,120.39 32.29,119.5 33.97,117.82 33.97,116 34.84,115.13 37.68,115.13 40.56,112.25 40.74,112.25 40.87,112.12 v1(40.87,111.73)
SOC_VOUT0_DATA13: length 38.3
  TOP w0.127: v1(41.61,117.59) 41.21,117.19 41.21,113.75 41.27,113.69 U12.V21
  TOP w0.132: v1(25.08,125.92) 25.08,125.46 24.33,124.71 24.33,123.72 24.19,123.58 U11.16
  L06_SIG2 w0.107: v1(25.08,125.92) 28.26,125.92 28.46,126.12 31.61,126.12 31.76,126.27 34.96,126.27 41.13,120.09 41.13,119.15 42.22,118.06 42.22,117.41 42.43,117.2 44,117.2 44.13,117.08 44.13,116.22 44.02,116.11 43.8,116.11 43.7,116.22 43.7,116.54 43.59,116.65 43.42,116.65 43.34,116.57 43.34,116.19 43.24,116.09 43.04,116.09 42.94,116.19 42.94,116.54 42.83,116.65 42.69,116.65 42.58,116.54 42.58,116.19 42.47,116.09 42.25,116.09 42.15,116.19 42.15,117.05 v1(41.61,117.59)
SOC_VOUT0_DATA14: length 38.5
  TOP w0.127: U12.U18 v1(40.87,110.93)
  TOP w0.132: U11.15 22.97,123.08 22.89,123 v1(22.58,123)
  L06_SIG2 w0.107: v1(22.58,123) 22.28,122.7 22.28,122.47 22.41,122.34 23.25,122.34 23.38,122.21 23.38,121.99 23.25,121.86 22.43,121.86 22.31,121.74 22.31,121.5 22.42,121.39 23.68,121.39 23.82,121.54 23.82,121.84 23.96,121.98 24.83,121.98 25.01,121.8 25.01,121.3 24.83,121.12 24.2,121.12 24.09,121.01 24.09,119.31 24.27,119.13 24.71,119.13 24.91,119.34 24.91,120.6 25.96,121.65 27.23,121.65 27.37,121.79 27.37,121.91 27.51,122.06 27.71,122.06 27.86,121.91 27.86,121.79 28,121.65 28.2,121.65 28.34,121.79 28.34,121.91 28.49,122.06 28.69,122.06 28.83,121.91 28.83,121.79 28.97,121.65 29.42,121.65 29.68,121.9 32.22,121.9 32.68,121.45 32.68,120.62 33.06,120.24 33.06,119.36 35.28,117.14 35.28,116.26 35.98,115.56 37.71,115.56 41.25,112.02 41.25,111.46 40.87,111.07 v1(40.87,110.93)
SOC_VOUT0_DATA15: length 38.4
  TOP w0.127: U12.V20 41.68,112.54 41.68,116.19 41.61,116.25 v1(41.61,116.65)
  TOP w0.132: v1(25.48,123.03) 25.03,122.58 U11.14
  L06_SIG2 w0.107: v1(41.61,116.65) 41.61,116.13 41.32,115.84 41.32,115.65 41.48,115.5 41.67,115.5 41.83,115.66 42.07,115.66 42.21,115.51 42.21,114.94 42.34,114.82 42.53,114.82 42.64,114.92 42.64,115.56 42.75,115.67 42.9,115.67 43,115.56 43,114.92 43.11,114.82 43.26,114.82 43.37,114.92 43.37,115.53 43.49,115.65 43.69,115.65 43.88,115.46 43.88,114.46 42.59,113.17 41.79,113.17 35.49,119.47 35.49,120.69 35.01,121.17 35.01,121.43 33.53,122.91 33.07,122.91 32.91,123.07 26.3,123.07 26.26,123.03 v1(25.48,123.03)
SOC_VOUT0_DATA16: length 41.5
  TOP w0.132: U11.13 25.21,122.08 25.45,121.84 25.45,121.2 24.96,120.72 24.96,120.49 24.51,120.04 v1(24.51,119.89) ; v1(37.27,114.32) 37.68,113.91 37.68,112.55 U12.N20
  L03_SIG1 w0.107: v1(24.51,119.89) 24.6,119.8 25.45,119.8 25.73,120.08 25.73,120.48 25.37,120.84 25.37,122.5 25.48,122.61 25.68,122.61 25.79,122.5 25.79,121.1 25.89,121 26.1,121 26.22,121.12 26.22,122.63 26.37,122.78 26.69,122.78 28.59,120.88 28.59,119.51 30.47,117.63 30.47,116.84 31.41,115.9 31.68,115.9 32.9,114.68 32.9,114.22 33.29,113.83 33.71,113.83 34.44,114.57 35.68,114.57 36.91,115.8 37.66,115.8 38.56,114.9 40.4,114.9 40.52,114.78 40.52,114.62 40.41,114.51 38.33,114.51 37.68,115.16 37.53,115.16 37.41,115.04 37.41,114.88 37.74,114.55 37.74,114.39 37.67,114.32 v1(37.27,114.32)
  BOTTOM w0.132: v1(37.27,114.32) 37.67,114.32 37.8,114.18 RA6.8
SOC_VOUT0_DATA17: length 41.5
  TOP w0.132: v1(24.52,120.65) 24.52,120.93 24.37,121.08 U11.11 ; v1(37.27,113.54) U12.N21
  L03_SIG1 w0.107: v1(24.52,120.65) 24.92,120.65 25.15,120.87 25.15,121.99 24.61,122.53 23.51,122.53 23.41,122.64 23.41,122.75 23.53,122.88 24.1,122.88 24.21,123 24.21,123.15 24.13,123.23 23.55,123.23 23.45,123.33 23.45,123.46 23.56,123.57 25.67,123.57 25.86,123.38 25.86,123.06 25.97,122.95 26.16,122.95 26.24,123.03 26.24,123.29 26.31,123.36 26.45,123.36 28.82,121 28.82,119.82 30.41,118.22 31.21,118.22 31.49,117.94 31.49,117 32.18,116.3 32.18,115.97 33.34,114.82 35.57,114.82 36.8,116.05 37.72,116.05 38.68,115.1 40.72,115.1 40.93,114.89 40.93,114.62 40.56,114.25 37.99,114.25 37.88,114.14 37.88,113.99 37.98,113.89 39.69,113.89 39.79,113.8 39.79,113.65 39.68,113.54 v1(37.27,113.54)
  BOTTOM w0.132: RA6.7 37.91,113.78 37.67,113.54 v1(37.27,113.54)
SOC_VOUT0_DATA18: length 48.3
  TOP w0.127: U12.M17 v1(36.87,110.13)
  TOP w0.132: U11.10 v1(22.86,120.58)
  L03_SIG1 w0.107: v1(36.87,110.13) 36.58,110.13 36.19,110.52 35.93,110.52 35.69,110.76 35.69,111.94 34.93,112.7 31.73,112.7 29.89,114.53 29.89,115.82 28.25,117.47 25.53,117.47 25,118 24.5,118 24.33,117.83 24.33,117.24 23.65,116.55 23.31,116.55 23.05,116.82 23.05,117.26 22.84,117.47 21.65,117.47 21.45,117.27 19.43,117.27 19.23,117.47 18.67,117.47 18.17,117.97 18.17,121.48 18.51,121.82 20.81,121.82 21.28,122.29 24.41,122.29 24.9,121.8 24.9,121.25 24.7,121.05 24.19,121.05 23.46,120.32 23.12,120.32 v1(22.86,120.58)
  BOTTOM w0.132: v1(36.87,110.13) 36.46,110.55 36.46,110.76 36.47,110.77 36.47,111.1 36.46,111.11 36.46,112.34 36.02,112.77 36.02,114.83 37.27,116.08 RA5.8
SOC_VOUT0_DATA19: length 46.4
  TOP w0.127: U12.N18 v1(37.67,110.93)
  TOP w0.132: v1(22.08,120.56) 22.55,120.08 U11.9
  L03_SIG1 w0.107: v1(22.08,120.56) 22.08,120.94 22.28,121.15 22.92,121.15 23.09,121.31 23.09,121.65 23.2,121.76 23.37,121.76 23.48,121.65 23.48,121.12 23.59,121.01 23.77,121.01 23.92,121.16 23.92,121.82 23.68,122.06 21.42,122.06 21.08,121.72 21.08,121.19 20.75,120.86 19.55,120.86 19.31,121.09 19.12,121.09 18.89,120.86 18.89,120.66 19.17,120.38 19.17,118.15 19.82,117.5 21.36,117.5 21.56,117.7 22.97,117.7 23.27,117.4 23.27,116.91 23.4,116.78 23.56,116.78 24.11,117.33 24.11,117.99 24.38,118.27 25.09,118.27 25.63,117.73 28.3,117.73 30.09,115.94 30.09,114.62 31.81,112.9 35.18,112.9 35.99,112.08 35.99,111.6 36.43,111.16 36.43,110.8 36.71,110.52 37.26,110.52 v1(37.67,110.93)
  BOTTOM w0.132: RA5.5 37.23,114.88 36.84,114.49 36.84,113.17 38.07,111.93 38.07,111.34 v1(37.67,110.93)
SOC_VOUT0_DATA20: length 47.9
  TOP w0.127: U12.N17 v1(37.67,110.13)
  TOP w0.132: U11.8 21.65,119.58 21.35,119.29 21.35,117.79 21.82,117.33 v1(21.82,117.05)
  L03_SIG1 w0.107: v1(21.82,117.05) 20.58,117.05 19.86,116.33 19.09,116.33 18.52,116.9 18.22,116.9 17.77,116.45 17.77,116.17 18.18,115.76 21.13,115.76 21.22,115.86 21.22,116.49 21.32,116.59 21.45,116.59 21.54,116.49 21.54,115.86 21.64,115.76 21.77,115.76 21.86,115.86 21.86,116.49 21.96,116.59 22.09,116.59 22.18,116.49 22.18,115.86 22.28,115.76 22.41,115.76 22.5,115.86 22.5,116.49 22.6,116.59 22.73,116.59 22.82,116.49 22.82,115.86 22.92,115.76 23.18,115.76 24.47,117.06 24.74,117.06 24.89,117.21 28.2,117.21 29.69,115.71 29.69,114.45 31.65,112.5 34.31,112.5 34.88,111.93 34.88,110.08 35.23,109.73 37.27,109.73 v1(37.67,110.13)
  BOTTOM w0.132: v1(37.67,110.13) 37.27,110.53 37.27,111.97 36.3,112.94 36.3,114.74 37.24,115.68 RA5.7
SOC_VOUT0_DATA21: length 45.7
  TOP w0.127: U12.N19 v1(37.67,111.73)
  TOP w0.132: U11.7 v1(22.86,119.08)
  L03_SIG1 w0.107: v1(37.67,111.73) 38.1,112.16 38.1,112.64 37.86,112.88 37.08,112.88 37.06,112.91 37.03,112.91 36.63,113.3 36.63,114.54 36.55,114.62 36.4,114.62 36.3,114.52 36.3,113.13 36.85,112.59 37.43,112.59 37.55,112.47 37.55,112.31 37.44,112.21 36.71,112.21 35.98,112.94 35.98,113.92 35.8,114.1 34.62,114.1 33.89,113.37 33.1,113.37 32.46,114.01 31.83,114.01 31.52,114.32 31.52,114.54 31.84,114.85 31.84,115.04 31.74,115.14 31.59,115.14 31.25,114.8 31.04,114.8 30.73,115.11 30.73,115.93 30,116.67 30,117.44 29.59,117.85 28.82,117.85 28.33,118.33 28.17,118.33 27.78,118.73 27.78,119.26 28.14,119.62 28.14,120.58 27.97,120.76 27.8,120.76 27.63,120.58 27.63,119.62 27.16,119.15 26.76,119.15 26.64,119.26 26.64,119.41 26.77,119.54 27,119.54 27.21,119.75 27.21,120.11 26.98,120.34 26.98,120.55 27.37,120.94 27.37,121.16 27.26,121.27 27.03,121.27 26.19,120.43 26.19,119.84 25.61,119.26 24.16,119.26 23.64,119.78 22.75,119.78 22.61,119.91 22.61,119.91 21.97,119.91 21.87,119.81 21.87,119.63 21.97,119.52 22.41,119.52 v1(22.86,119.08)
  BOTTOM w0.132: RA5.6 37.25,115.28 36.58,114.61 36.58,113.1 37.67,112 v1(37.67,111.73)
SOC_VOUT0_DATA22: length 42.8
  TOP w0.127: U12.P19 v1(38.47,111.73)
  TOP w0.132: U11.6 22.55,118.58 v1(22.09,119.03)
  L03_SIG1 w0.107: v1(38.47,111.73) 38.11,111.38 36.63,111.38 36.36,111.65 36.36,112 35.26,113.09 34.77,113.09 34.65,113.21 34.65,113.37 34.77,113.49 35.55,113.49 35.68,113.62 35.68,113.77 35.55,113.9 34.72,113.9 33.91,113.09 32.64,113.09 32.55,113.19 32.55,113.39 32.45,113.48 32.32,113.48 32.23,113.39 32.23,113.19 32.13,113.09 31.89,113.09 31.7,113.29 31.7,113.42 31.84,113.56 31.84,113.69 31.75,113.79 31.62,113.79 31.47,113.65 31.34,113.65 31.25,113.74 31.25,113.87 31.39,114.01 31.39,114.15 31.3,114.24 31.16,114.24 31.02,114.1 30.89,114.1 30.8,114.19 30.8,114.32 30.94,114.47 30.94,114.6 30.84,114.69 30.71,114.69 30.57,114.55 30.44,114.55 30.29,114.7 30.29,116.06 28.24,118.11 25.6,118.11 25.5,118.22 25.5,118.38 25.62,118.5 27.36,118.5 27.48,118.62 27.48,118.82 27.37,118.93 24.4,118.93 23.83,118.35 23.83,117.75 23.71,117.63 23.55,117.63 23.45,117.74 23.45,118.44 23.8,118.79 23.8,119.27 23.52,119.54 23.27,119.54 23.2,119.47 23.2,119.3 23.35,119.14 23.35,118.88 23.05,118.58 21.84,118.58 21.6,118.34 21.21,118.34 21.07,118.48 21.07,119.71 21.21,119.85 21.4,119.85 21.55,119.7 21.55,119.16 21.68,119.03 v1(22.09,119.03)
  BOTTOM w0.132: RA6.6 37.86,113.38 37.74,113.27 37.74,112.67 38.47,111.94 v1(38.47,111.73)
SOC_VOUT0_DATA23: length 41
  TOP w0.132: v1(22,118.12) 22.54,117.58 U11.4 ; v1(38.47,112.54) 38.47,112.53 U12.P20
  L03_SIG1 w0.107: v1(38.47,112.54) 38.47,112.88 38.23,113.11 37.11,113.11 36.83,113.39 36.83,114.82 37.14,115.13 37.14,115.28 36.98,115.44 36.83,115.44 35.71,114.32 34.49,114.32 33.79,113.62 33.14,113.62 32.61,114.15 32.61,114.63 31.59,115.66 31.33,115.66 30.22,116.76 30.22,117.56 29.67,118.11 28.87,118.11 28.42,118.56 28.27,118.56 28.03,118.79 28.03,118.8 28.03,119.16 28.37,119.49 28.37,120.78 27.6,121.55 26.65,121.55 26.46,121.36 26.46,121.01 25.97,120.52 25.97,119.94 25.52,119.49 24.31,119.49 23.8,120 22.84,120 22.68,120.16 21.91,120.16 21.68,120.39 21.68,121.06 22.01,121.39 22.56,121.39 22.67,121.5 22.67,121.71 22.56,121.82 21.6,121.82 21.31,121.53 21.31,120.31 20.92,119.92 20.31,119.92 20.12,119.73 20.12,117.95 20.35,117.72 21,117.72 21.4,118.12 v1(22,118.12)
  BOTTOM w0.132: v1(38.47,112.54) 38.47,112.56 38.24,112.78 RA6.5
SOC_VOUT0_DE: length 38.5
  TOP w0.127: v1(15.91,124.53) U11.33 ; U12.T17 v1(40.07,110.13)
  L06_SIG2 w0.107: v1(15.91,124.53) 16.52,123.92 16.52,123.43 16.72,123.22 17.38,123.22 17.64,123.48 17.87,123.48 18.13,123.22 18.36,123.22 18.61,123.48 18.85,123.48 19.1,123.22 20.3,123.22 20.69,123.61 20.69,123.87 20.98,124.16 21.95,124.16 22.74,123.38 22.74,123.38 22.96,123.16 22.96,123.16 23.08,123.04 23.55,123.04 24.26,122.32 26.48,122.32 26.57,122.41 32.22,122.41 33.02,121.62 33.02,120.8 33.36,120.46 33.65,120.46 33.87,120.24 33.87,120.08 41.41,112.54 41.95,112.54 42.24,112.25 42.24,111.77 41.81,111.34 41.53,111.34 41.26,111.07 41.26,110.78 41,110.52 40.45,110.52 v1(40.07,110.13)
SOC_VOUT0_HSYNC: length 38.4
  TOP w0.127: v1(15.96,126.17) 15.57,126.17 15.41,126.01 U11.34 ; U12.W21 42.07,116.94 v1(42.72,117.59)
  L06_SIG2 w0.107: v1(42.72,117.59) 42.72,118.03 41.46,119.29 41.46,120.23 35.09,126.6 30.25,126.6 29.97,126.88 28.77,126.88 28.18,126.29 26.2,126.29 25.65,126.85 16.64,126.85 v1(15.96,126.17)
SOC_VOUT0_PCLK: length 12.2
  TOP w0.127: U12.U17 v1(40.87,110.13)
  L03_SIG1 w0.107: v1(42.76,114) 42.4,114 40.46,112.07 40.46,110.29 40.61,110.13 v1(40.87,110.13)
  BOTTOM w0.132: v1(42.76,114) 41.15,115.61 41.15,115.91 41.3,116.06 41.87,116.06 42.28,116.46 42.28,117.94 42,118.21 R329.1
SOC_VOUT0_VSYNC: length 40.6
  TOP w0.127: U11.35 v1(14.91,124.53) ; U12.T16 v1(40.07,109.34)
  L03_SIG1 w0.107: v1(14.91,124.53) 14.65,124.28 14.65,124.01 14.94,123.72 15.57,123.72 15.91,123.39 15.91,122.4 16.46,121.85 16.77,121.85 17.23,121.39 17.23,116.68 17.41,116.49 17.41,115.74 17.77,115.38 23.26,115.38 24.64,116.77 24.87,116.77 25.02,116.92 28.05,116.92 29.5,115.47 29.5,114.37 31.68,112.19 33.77,112.19 34.04,111.91 34.04,109.98 35.08,108.94 39.67,108.94 v1(40.07,109.34)
SOC_WARM_RESETZ: length 146.6
  TOP w0.127: v1(40.02,18.09) 40.02,17.9 39.02,16.9 TP89.1 ; U12.E15 v1(30.47,108.53)
  L06_SIG2 w0.107: v1(40.02,18.09) 42.07,20.14 49.58,20.14 51.51,18.21 52.58,18.21 53.19,18.82 53.19,27.33 52.7,27.81 52.7,36.37 51.34,37.73 51.34,44.41 49.31,46.44 44.57,46.44 44.57,46.44 44.25,46.44 44.25,46.44 43.73,46.44 43.73,46.44 43.41,46.44 43.41,46.44 38.64,46.44 36.92,48.17 31.28,48.17 28.48,50.96 28.48,58.15 30.26,59.93 39.76,59.93 40.95,61.12 40.95,65.31 41.18,65.54 41.18,67.32 36.99,71.51 36.99,81.16 37.6,81.77 37.6,84.18 37.22,84.57 37.22,89.65 34.99,91.88 34.07,91.88 33.66,92.29 33.66,97.44 33.28,97.82 33.28,107.17 33.14,107.32 31.05,107.32 30.87,107.5 U12.E15 v1(30.47,108.53)
  BOTTOM w0.127: v1(40.02,18.09) R527.1 39.44,18.56 39.49,18.61 U81.2
SOC_WLAN_SDIO_RST: length 20.5
  TOP w0.132: U3.24 55.81,144.1 56.22,143.69 56.22,143.04 55.92,142.74 52.66,142.74 51.33,144.06 49.11,144.06 47.84,145.33 47.84,147.41 46,149.25 U2.7
SPI0_FET_OE: length 23.7
  TOP w0.132: U3.18 v1(52.81,144.25)
  BOTTOM w0.132: R292.2 61.61,135.63 61.6,135.62 U43.15 58.76,135.62 57.41,134.27 51.19,134.27 50.05,135.42 50.05,136.94 51.5,138.38 51.5,142.94 v1(52.81,144.25)
SPI0_FET_SEL: length 17.6
  TOP w0.132: v1(52.81,143.36) 52.31,143.86 U3.17
  BOTTOM w0.132: R264.2 R263.1 54.39,141.77 v1(52.81,143.36) 51.85,142.4 51.85,135.01 52.21,134.65 53.63,134.65 53.95,134.97 U43.1
SPI_HOLDN: length 2.2
  TOP w0.127: U30.7 35.29,49.38 35.3,49.38 R163.2
SPI_WPN: length 1.8
  TOP w0.127: U30.3 26.67,48.11 26.37,47.81 R171.2
SW_2V5: length 3.7
  BOTTOM w0.254: L8.1 U57.5
SYS_BOOTMODE0: length 14.3
  TOP w0.127: R191.1 v1(41.01,36.28) SW3.1
  L03_SIG1 w0.107: v1(41.01,36.28) 41.35,36.28 43.48,34.15 43.48,31.25 v1(41.22,28.99)
  BOTTOM w0.127: U75.10 v1(41.22,28.99) U74.1
SYS_BOOTMODE1: length 15.6
  TOP w0.127: R190.1 v1(39.74,36.28) SW3.2
  L03_SIG1 w0.107: v1(39.74,36.28) 40.45,36.28 40.84,35.88 41.43,35.88 43.26,34.06 43.26,31.47 41.29,29.49 v1(40.38,29.49)
  BOTTOM w0.127: U75.9 v1(40.38,29.49) U74.2
SYS_BOOTMODE2: length 15.1
  TOP w0.127: SW3.3 v1(38.47,36.28) R189.1
  L03_SIG1 w0.107: v1(38.47,36.28) 38.88,35.87 40.54,35.87 40.75,35.66 41.34,35.66 43.03,33.97 43.03,31.81 v1(41.22,29.99)
  BOTTOM w0.127: U75.8 v1(41.22,29.99) U74.3
SYS_BOOTMODE3: length 16.4
  TOP w0.127: SW3.4 v1(37.2,36.28) R188.1
  L03_SIG1 w0.107: v1(37.2,36.28) 37.87,35.61 40.48,35.61 40.66,35.44 41.25,35.44 42.81,33.87 42.81,32.02 41.29,30.49 v1(40.38,30.49)
  BOTTOM w0.127: U74.4 v1(40.38,30.49) U75.7
SYS_BOOTMODE4: length 15
  TOP w0.127: R187.1 v1(35.93,36.28) SW3.5
  L03_SIG1 w0.107: v1(35.93,36.28) 36.82,35.39 40.34,35.39 41.76,33.97 41.76,33.21 41.71,33.16 41.71,32.83 41.84,32.7 41.84,31.62 v1(41.22,30.99)
  BOTTOM w0.127: U74.5 v1(41.22,30.99) U75.6
SYS_BOOTMODE5: length 16.2
  TOP w0.127: SW3.6 v1(34.66,36.28) R186.1
  L03_SIG1 w0.107: v1(34.66,36.28) 35.79,35.15 40.26,35.15 41.54,33.87 41.54,33.3 41.49,33.25 41.49,32.74 41.62,32.6 41.62,31.83 41.29,31.49 v1(40.38,31.49)
  BOTTOM w0.127: U74.6 v1(40.38,31.49) U75.5
SYS_BOOTMODE6: length 15.1
  TOP w0.127: SW3.7 v1(33.39,36.28) R185.1
  L03_SIG1 w0.107: v1(33.39,36.28) 34.74,34.93 39.36,34.93 41.22,33.06 v1(41.22,31.99)
  BOTTOM w0.127: U74.7 v1(41.22,31.99) U75.4
SYS_BOOTMODE7: length 14.7
  TOP w0.127: SW3.8 v1(32.12,36.28) R184.1
  L03_SIG1 w0.107: v1(32.12,36.28) 33.69,34.71 38.17,34.71 v1(40.38,32.49)
  BOTTOM w0.127: U75.3 v1(40.38,32.49) U74.8
SYS_BOOTMODE8: length 18.1
  TOP w0.127: SW4.1 v1(54.47,36.28) R199.1
  BOTTOM w0.127: U73.10 51.31,33.15 51.11,33.36 51.11,34.08 49.31,35.87 45.4,35.87 43.63,34.1 U74.9
  BOTTOM w0.132: v1(54.47,36.28) 53.48,35.29 52.32,35.29 51.11,34.08
SYS_BOOTMODE9: length 17.7
  TOP w0.127: R198.1 v1(53.2,36.28) SW4.2
  L03_SIG1 w0.107: v1(51.95,32.65) 52.77,33.48 52.77,35.85 v1(53.2,36.28)
  BOTTOM w0.127: U73.9 v1(51.95,32.65) 50.88,32.65 50.59,32.95 50.59,34.15 49.13,35.6 45.68,35.6 44.13,34.05 U74.10
SYS_BOOTMODE10: length 17.6
  TOP w0.127: R197.1 v1(51.93,36.28) SW4.3
  L03_SIG1 w0.107: v1(51.93,36.28) 51.11,35.46 v1(51.11,32.15)
  BOTTOM w0.127: U74.11 44.63,34.01 45.95,35.32 48.98,35.32 50.21,34.09 50.21,32.66 50.72,32.15 v1(51.11,32.15) U73.8
SYS_BOOTMODE11: length 18.4
  TOP w0.127: R196.1 v1(50.66,36.28) SW4.4
  L03_SIG1 w0.107: v1(50.66,36.28) 50.66,32.03 51.04,31.65 v1(51.95,31.65)
  BOTTOM w0.127: U73.7 v1(51.95,31.65) 50.68,31.65 49.87,32.46 49.87,33.97 48.86,34.99 46.04,34.99 45.13,34.08 U74.12
SYS_BOOTMODE12: length 17.9
  TOP w0.127: R195.1 v1(49.39,36.28) SW4.5
  L03_SIG1 w0.107: v1(51.11,31.15) 49.39,32.87 v1(49.39,36.28)
  BOTTOM w0.127: U74.13 45.63,33.99 46.27,34.63 48.73,34.63 49.56,33.8 49.56,32.19 50.59,31.15 v1(51.11,31.15) U73.6
SYS_BOOTMODE13: length 19.3
  TOP w0.127: SW4.6 v1(48.12,36.28) R194.1
  L03_SIG1 w0.107: v1(51.95,30.65) 50.93,30.65 48.12,33.47 v1(48.12,36.28)
  BOTTOM w0.127: U74.14 46.13,33.98 46.42,34.27 48.6,34.27 49.26,33.61 49.26,31.95 50.56,30.65 v1(51.95,30.65) U73.5
SYS_BOOTMODE14: length 19
  TOP w0.127: SW4.7 v1(46.85,36.28) R193.1
  L03_SIG1 w0.107: v1(46.85,36.28) 46.85,34.03 50.73,30.15 v1(51.11,30.15)
  BOTTOM w0.127: U73.4 v1(51.11,30.15) 50.59,30.15 48.93,31.81 48.93,33.51 48.48,33.97 46.82,33.97 46.63,33.77 U74.15
SYS_BOOTMODE15: length 20.2
  TOP w0.127: SW4.8 v1(45.58,36.28) R192.1
  L03_SIG1 w0.107: v1(45.58,36.28) 45.58,34.83 50.75,29.65 v1(51.95,29.65)
  BOTTOM w0.127: U74.16 47.13,33.54 47.26,33.66 48.32,33.66 48.62,33.36 48.62,31.55 50.52,29.65 50.7,29.65 50.7,29.66 51.04,29.66 51.04,29.65 v1(51.95,29.65) U73.3
SYSBOOT_BUF_ENZ: length 21.5
  TOP w0.132: v1(64.6,39.28) 63.96,39.91 R181.1 65.66,40.81 66.95,42.11 66.95,43.99 66.71,44.24 R175.1 ; v1(69.68,29.04) U34.1
  BOTTOM w0.132: v1(69.68,29.04) 70.3,29.66 70.3,33.57 v1(64.6,39.28)
TCA6424_EXP_INT: length 2
  BOTTOM w0.127: R489.1 42.7,27.42 43.45,27.42 43.63,27.6 U74.32
TEMP_DIODE_P: length 13.1
  TOP w0.127: U12.F8 v1(31.27,102.93)
  TOP w0.132: v1(22.16,104.28) 21.56,104.28 TP21.1
  L06_SIG2 w0.107: v1(22.16,104.28) 22.86,103.58 24.16,103.58 24.59,104.01 25.98,104.01 26.42,103.58 27.4,103.58 28.14,104.32 30.07,104.32 30.24,104.15 31.4,104.15 31.65,103.89 31.65,103.32 v1(31.27,102.93)
TEST_GPIO1: length 41.9
  TOP w0.127: v1(65.02,29.13) 64.97,29.08 R212.2
  L06_SIG2 w0.107: v1(42.6,18.59) 42.76,18.43 50.58,18.43 51.3,17.7 52.81,17.7 55.36,20.25 56.19,20.25 57.69,18.75 57.69,16.85 58.43,16.11 v1(59.01,16.11) 59.01,16.5 59.01,16.5 59.01,16.93 58.28,17.66 58.28,20.51 59.54,21.76 60.23,21.76 60.83,22.36 60.83,22.68 62.91,24.76 62.91,28.2 63.84,29.13 v1(65.02,29.13)
  BOTTOM w0.127: Q12.1 43.47,18.85 43.21,18.59 v1(42.6,18.59) ; R551.1 59.86,16.17 60.07,16.38 R543.1
  BOTTOM w0.132: R551.1 59.17,16.17 59.12,16.11 v1(59.01,16.11)
TEST_GPIO2: length 50.6
  TOP w0.127: v1(65.39,28.08) 65.39,27.68 65.4,27.67 R216.2
  TOP w0.132: v1(57.8,44.11) 56.48,44.11 56.14,43.77 52.03,43.77 50.07,41.82 50.07,39.73 51.17,38.64 53.15,38.64 53.93,37.85 56.15,37.85 58.18,35.82 58.18,34.76 59.92,33.02 64.18,33.02 65.46,31.74 65.46,28.14 v1(65.39,28.08)
  L06_SIG2 w0.107: v1(65.39,28.08) 64.86,28.61 63.7,28.61 63.16,28.07 63.16,24.63 61.67,23.14 61.67,21.79 60.68,20.8 60.13,20.8 59.29,19.95 v1(59.29,19.14)
  BOTTOM w0.127: U70.18 v1(57.8,44.11) ; v1(59.29,19.14) 59.23,19.08 R524.1 58.42,18.63 R526.1
TEST_GPIO3: length 40.7
  TOP w0.127: U34.2 69.06,27.31 68.86,27.51 68.86,28.78 TP77.1 v1(66.86,29.29) 66.65,29.08 R213.2
  TOP w0.132: v1(79.84,27.55) 79.55,27.55 79.41,27.69 76.77,27.69 74.99,29.47 71.92,29.47 71.21,28.76 71.21,27.69 70.82,27.31 U34.2
  L06_SIG2 w0.107: v1(66.86,29.29) 66.51,29.64 63.72,29.64 62.61,28.54 62.61,24.89 61.81,24.09 61.17,24.09 59.84,22.75 59.84,22.42 57.96,20.54 57.96,17.2 v1(58.23,16.93)
  BOTTOM w0.127: J16.1 R485.1 ; v1(58.23,16.93) 58.23,16.53 57.86,16.17 R552.1
  BOTTOM w0.132: R485.1 v1(79.84,27.55)
TEST_GPIO4: length 45.2
  TOP w0.127: R219.2 v1(66.93,27.94) 66.93,28.51 67.07,28.66 TP78.1
  L06_SIG2 w0.107: v1(66.93,27.94) 63.74,24.75 63.74,21.75 62.7,20.71 62.7,19.92 60.49,17.71 60.49,16.14 59.78,15.43 58.15,15.43 57.13,16.45 57.13,18.2 v1(56.27,19.06)
  BOTTOM w0.127: R520.1 57.6,19.46 57.2,19.06 v1(56.27,19.06) 56.55,18.78 56.88,18.78 57.07,18.59 R529.1
  BOTTOM w0.132: R529.1 56.31,18.25 54.98,19.58 54.98,22.89 53.98,23.88 53.97,23.88 53.96,23.9 53.4,23.9 51.69,25.61 51.69,25.78 51.46,26.01 51.1,26.01 50.41,26.69 46.95,26.69 46.46,26.2 45.99,26.2 45.63,26.57 U74.28
TEST_PORZN: length 34.6
  TOP w0.132: v1(57.58,35.61) 57.1,35.13 57.1,30.76 57.81,30.05 58.9,30.05 59.44,29.51 62,29.51 v1(62.43,29.08) R211.2
  L06_SIG2 w0.107: v1(63.29,16.93) 62.95,17.26 62.95,19.71 64.12,20.88 64.12,21.8 64.98,22.66 64.98,24.67 67.43,27.12 67.43,29.48 66.86,30.05 63.46,30.05 62.5,29.08 v1(62.43,29.08)
  BOTTOM w0.127: v1(63.29,16.93) 62.93,16.93 62.78,16.78 R542.1 62.45,16.38 62.24,16.17 R550.1 ; v1(57.58,35.61) 57.2,35.99 U72.6
TEST_POWERDOWN: length 182.5
  TOP w0.127: R207.1 v1(27.85,34.35) ; v1(62.23,27.94) R217.2
  TOP w0.132: v1(36.09,24.99) 41.87,24.99 43.67,26.79 43.67,27.61 44.85,28.78 50.97,28.78 51.43,29.24 54.07,29.24 54.48,28.84 57.36,28.84 57.62,29.09 60.56,29.09 61.71,27.94 v1(62.23,27.94)
  L03_SIG1 w0.107: v1(15.4,20.56) 15.13,20.83 15.13,24.7 16.04,25.61 16.04,31.43 14.23,33.23 14.23,34.83 15.15,35.75 15.15,38.72 12.68,41.18 12.68,46.24 8.84,50.08 8.84,53.41 6.66,55.58 6.66,75.27 4.96,76.97 3.18,76.97 1.47,78.68 1.47,81.76 v1(3.19,83.48) ; v1(36.09,24.99) 36.09,19.71 34.71,18.32 31.48,18.32 31.15,18.65 31.15,19.39 27.06,23.48 27.06,31.02 27.38,31.34 27.38,33.88 v1(27.85,34.35)
  L06_SIG2 w0.107: v1(64.97,16.93) 64.01,16.93 63.2,17.74 63.2,18.87 63.73,19.4 65.19,19.4 65.68,19.88 65.68,24.86 67.68,26.86 67.68,29.78 67,30.45 63.14,30.45 62.05,29.36 62.05,28.12 v1(62.23,27.94)
  BOTTOM w0.127: 35,23.9 v1(36.09,24.99) ; R549.1 64.43,16.17 64.64,16.38 R541.1 v1(64.97,16.93) ; U59.3 3.85,84.14 v1(3.19,83.48)
  BOTTOM w0.132: v1(15.4,20.56) 18.18,23.34 34.45,23.34 35,23.9
TEST_WARMRESETN: length 45.4
  TOP w0.127: v1(63.75,27.94) R218.2
  L06_SIG2 w0.107: v1(37.65,19.75) 38.97,19.75 39.3,19.41 39.3,17.77 39.63,17.44 46.44,17.44 46.51,17.51 47.59,17.51 47.78,17.32 52.78,17.32 55.46,20 56.09,20 57.44,18.65 57.44,16.54 58.3,15.68 59.67,15.68 60.23,16.24 60.23,18 v1(61.41,19.18) 62.44,20.21 62.44,20.81 63.49,21.86 63.49,27.29 63.75,27.56 v1(63.75,27.94)
  BOTTOM w0.127: R525.1 60.74,18.41 60.95,18.63 R523.1 v1(61.41,19.18) ; Q13.1 37.62,19.74 37.63,19.75 v1(37.65,19.75)
TM4C129_TCK: length 2.6
  TOP w0.132: TP86.1 53.2,21.17 53.34,21.03 U36.100
TM4C129_TDI: length 2.2
  TOP w0.127: TP84.1 52.85,22.59 53.61,21.83 U36.98
TM4C129_TDO: length 2.1
  TOP w0.127: U36.97 53.63,22.23 53.01,22.84 TP83.1
TM4C129_TMS: length 1.8
  TOP w0.127: U36.99 53.6,21.43 53.32,21.71 TP85.1
TMP1_ADD0: length 1.2
  BOTTOM w0.132: U48.5 27.76,124.8 27.67,124.72 R302.1
TMP1_ADD1: length 1.6
  BOTTOM w0.127: U48.3 R303.1
TMP2_ADD1: length 1.4
  TOP w0.127: U24.3 R137.1
TPS65219 EN: length 30.5
  L06_SIG2 w0.107: v1(16.37,77.17) 16.37,77.59 15.3,78.65 15.3,80.81 13.84,82.26 13.84,84.45 9.14,89.16 7.31,89.16 v1(7.31,89.15)
  BOTTOM w0.132: v1(16.37,77.17) 16.59,76.95 R405.1 ; R382.2 2.7,86.39 U59.4 ; R382.2 2.64,89.43 3.71,90.5 5.96,90.5 v1(7.31,89.15) ; R382.2 R379.1 TP100.1
TPS65219_GPO: length 4
  TOP w0.132: TP47.1 8.75,77.05 8.93,77.05 R128.1 9.57,77.05 9.76,77.25 9.76,77.61 9.94,77.79 U22.16
TPS65219_GPO2: length 114.5
  TOP w0.127: U22.17 11.32,76.77 v1(10.78,76.23) 10.24,76.23 TP48.1 ; v1(43.93,54.26) 44.02,54.36 U29.3
  L03_SIG1 w0.107: v1(30.59,75.01) 32.31,73.29 42.6,73.29 v1(44.03,71.87)
  L06_SIG2 w0.107: v1(43.93,54.26) 44.89,55.23 44.89,60.38 45.91,61.4 45.91,69.73 44.03,71.61 v1(44.03,71.87) ; v1(10.78,76.23) 11.54,76.23 13,77.7 15.65,77.7 15.9,77.44 15.9,76.94 16.05,76.79 16.67,76.79 16.87,76.99 16.87,81.53 16.62,81.78 16.62,85.76 16.75,85.89 16.75,89.75 17.09,90.09 17.09,92.02 16.05,93.07 16.05,95.81 14.53,97.33 10.74,97.33 8.86,99.21 8.86,102.39 9.51,103.03 12.56,103.03 14.27,101.32 14.27,100.88 15,100.15 16.1,100.15 16.74,100.79 17.7,100.79 18.8,99.7 21.97,99.7 v1(22.07,99.59)
  BOTTOM w0.127: v1(10.78,76.23) 10.93,76.39 R404.1
  BOTTOM w0.132: v1(30.59,75.01) 29.8,75.8 15.71,75.8 15.22,75.32 11.69,75.32 v1(10.78,76.23) ; v1(44.03,71.87) 43.7,71.87 43.57,71.73 R411.2 ; R588.1 21.67,99.26 22,99.59 v1(22.07,99.59)
TPS630702_EN: length 71.1
  TOP w0.127: U33.14 26.2,32.56 26.39,32.75 R210.1 26.73,34.35 R207.2
  TOP w0.132: v1(26.17,34.35) R207.2
  L03_SIG1 w0.107: v1(26.17,34.35) 25.51,35.01 25.51,45.93 26.73,47.15 26.73,52.43 25.69,53.48 25.69,57.92 23.89,59.72 15.1,59.72 14.44,60.38 14.44,60.56 13.12,61.88 13.12,65.46 13.73,66.07 v1(16.65,66.07)
  BOTTOM w0.132: v1(16.65,66.07) 15.72,66.07 13.02,68.78 13.02,69.91 12.04,70.89 R578.1 11.36,71.42 9.82,72.96 9.82,76.39 9.26,76.96 9.26,81.49 9.98,82.22 R577.1
TS_INT#: length 48.1
  TOP w0.132: v1(66.29,76.28) 66.13,76.11 R151.2
  L06_SIG2 w0.107: v1(60.93,50.72) 55.88,55.77 55.88,57.66 56.46,58.24 62.97,58.24 65.28,60.55 65.28,75.64 65.91,76.28 v1(66.29,76.28)
  BOTTOM w0.132: v1(66.29,76.28) 64.77,76.28 63.34,74.85 J22.9 ; v1(60.93,50.72) 56.34,46.12 56.2,45.99 U70.16
UART1_FET_BUF_EN: length 161.8
  TOP w0.132: v1(35.14,138.23) 35.14,136.34 36.4,135.07 41.69,135.07 42.19,134.57 63.32,134.57 63.71,134.96 70.37,134.96 72.03,133.29 72.03,126.16 73.66,124.54 73.66,113.51 71.63,111.48 71.63,104.14 73.54,102.23 73.54,90.82 72.85,90.13 72.85,87.25 80.83,79.26 80.83,67.09 80.83,65.75 77,61.91 70.11,61.91 61.41,53.21 57.84,53.21 55.57,53.21 51.55,49.18 51.55,46.26 52.05,45.75 52.83,45.75 v1(54.2,47.13)
  BOTTOM w0.127: U70.11 53.7,46.63 v1(54.2,47.13)
  BOTTOM w0.132: v1(35.14,138.23) 35.33,138.03 U44.16 ; U44.1 35.78,137.8 U44.16 ; U44.16 35.33,137.79 R289.1 34.35,138.08 34.5,138.23 U41.2
UART1_FET_BUF_EN_INV: length 69.4
  L03_SIG1 w0.107: v1(32.95,138.46) 33.25,138.76 36.04,138.76 37.52,140.23 39.07,140.23 40.56,141.73 40.56,145.77 43.65,148.86 46.78,148.86 47.85,149.93 49.85,149.93 51.97,152.05 61.91,152.05 66.11,147.86 71.95,147.86 76.06,143.74 76.06,138.41 77.48,136.99 77.48,133.16 v1(77.17,132.85)
  BOTTOM w0.127: U42.15 76.91,133.5 77.17,133.24 v1(77.17,132.85)
  BOTTOM w0.132: U41.4 33.12,139.14 32.95,138.97 v1(32.95,138.46)
UART1_FET_SEL: length 147.2
  TOP w0.132: v1(57.8,42.11) R180.2 R179.1
  L03_SIG1 w0.107: v1(76.48,141.48) 77.44,140.52 78.75,140.52 80.95,138.32 80.95,133.4 76.18,128.63 73.87,128.63 73.08,127.85 73.08,125.54 73.99,124.64 73.99,113.31 71.78,111.1 71.78,105.91 68.23,102.36 68.23,88.55 72.24,84.54 72.24,63.34 77.81,57.77 77.81,54.27 79.49,52.59 79.49,50.57 78.09,49.17 78.09,44.36 69.1,35.37 v1(69.1,33.97)
  BOTTOM w0.127: U42.1 76.26,141.35 76.39,141.48 v1(76.48,141.48) ; R180.2 v1(57.8,42.11)
  BOTTOM w0.132: v1(57.8,42.11) 58.4,41.51 58.4,40.6 57.87,40.06 57.87,39.03 58.41,38.49 58.82,38.49 58.9,38.4 61.27,38.4 61.58,38.09 64.97,38.09 v1(69.1,33.97)
USB_DM: length 1.8
  TOP w0.132: J2.5 3.66,135.54 v1(3.83,135.72)
  BOTTOM w0.132: TP95.1 v1(3.83,135.72)
USB_DP: length 1.8
  TOP w0.132: v1(3.83,134.87) 3.83,134.91 3.7,135.04 J2.3
  BOTTOM w0.132: TP96.1 v1(3.83,134.87)
USB_TYPEA_EARTH: length 2.7
  BOTTOM w0.254: R417.1 79.67,66.47 79.88,66.69 C376.1
USB_TYPEACONN1_DM: length 7.9
  TOP w0.11: J9.2 69.72,71.3 69.19,71.83 U23.5 67.97,71.83 67.62,72.18 67.37,72.18 67.04,72.5 67.04,73.55 67.34,73.84 67.73,73.84 67.84,73.95 L4.2
USB_TYPEACONN1_DP: length 7.9
  TOP w0.11: L4.3 68.69,74.46 68.51,74.27 68.28,74.27 68.09,74.08 68.09,73.85 67.83,73.6 67.44,73.6 67.28,73.45 67.28,72.6 67.45,72.43 67.61,72.43 67.95,72.78 U23.6 69.12,72.78 69.65,73.3 J9.3
USBC_CONN1_CC1: length 21.6
  TOP w0.254: C121.1 21.78,50.39 v1(21.8,50.4) ; J13.A5 8.99,45.95 9.12,46.08 D5.1 9.91,46.08 v1(10.15,46.32)
  L06_SIG2 w0.254: v1(21.8,50.4) 21.63,50.4 20.1,48.88 17.84,48.88 16.06,50.66 11.85,50.66 10.15,48.96 v1(10.15,46.32)
  BOTTOM w0.203: v1(21.8,50.4) 21.35,49.96 21.35,49.11 21.38,49.07 U68.24
USBC_CONN1_CC2: length 29.5
  TOP w0.254: v1(22.69,50.06) 22.81,50.18 C120.1 ; v1(5.35,44.36) 5.52,44.2 J13.B5
  L06_SIG2 w0.254: v1(22.69,50.06) 22.48,49.85 21.7,49.85 20.27,48.42 17.73,48.42 15.89,50.25 12.01,50.25 10.63,48.87 10.63,43.7 9.79,42.86 6.86,42.86 v1(5.35,44.36)
  BOTTOM w0.203: 22.36,49.41 22.36,49.16 22.18,48.98 U68.26
  BOTTOM w0.254: 22.36,49.41 22.36,49.73 v1(22.69,50.06) ; D10.1 5.14,44.58 v1(5.35,44.36)
USBC_CONN2_CC1: length 22.8
  TOP w0.254: J15.A5 9.01,30.95 D6.1 9.55,32.71 9.97,33.13 11.77,33.13 15.09,36.45 15.09,37.83 16.54,39.29 18.87,39.29 20,40.42 20,41.31 20.43,41.74 21.32,41.74 v1(22.18,40.88) 22.13,40.83 C139.1
  BOTTOM w0.203: U68.45 v1(22.18,40.88)
USBC_CONN2_CC2: length 31.6
  TOP w0.254: C138.1 20.79,40.49 v1(21.18,40.88) ; v1(4.65,28.23) 4.97,28.55 4.97,28.87 5.3,29.2 J15.B5
  BOTTOM w0.203: v1(21.18,40.88) 21.38,41.08 U68.47
  BOTTOM w0.254: D11.1 5.07,28.09 4.78,28.09 v1(4.65,28.23) 4.28,28.6 4.28,31.81 4.84,32.37 7.38,32.37 8.95,33.94 8.95,38.05 9.79,38.88 12.14,38.88 13.39,40.13 20.43,40.13 v1(21.18,40.88)
USBC_CONN2_DM: length 13.4
  TOP w0.107: v1(7.07,29.51) 7.88,29.51 J15.A7 8.52,29.45 8.63,29.55 8.63,29.73 8.75,29.85 9.64,29.85 D7.3 9.98,29.51 10.84,29.51 11.15,29.83 12.11,29.83 12.41,29.52 L5.3 ; v1(4.98,30.33) 5.21,30.1 5.69,30.1 5.79,30.2 J15.B7
  L03_SIG1 w0.097: v1(4.98,30.33) 4.98,30.1 4.88,30.01 4.32,30.01 4.23,30.1 4.23,30.77 4.35,30.9 5.37,30.9 6.26,30.01 7.11,30.01 7.27,29.84 7.27,29.71 v1(7.07,29.51)
USBC_CONN2_DP: length 13.4
  TOP w0.107: J15.B6 5.79,29.7 5.62,29.86 5.28,29.86 v1(4.98,29.57) ; v1(7.07,30.39) 7.88,30.39 J15.A6 8.52,30.45 8.63,30.34 8.63,30.16 8.7,30.09 9.69,30.09 D7.2 9.98,30.38 10.84,30.38 11.15,30.07 12.12,30.07 12.42,30.37 L5.2
  L03_SIG1 w0.097: v1(7.07,30.39) 6.94,30.25 6.36,30.25 5.47,31.14 4.25,31.14 3.98,30.87 3.98,30 4.22,29.76 4.79,29.76 v1(4.98,29.57)
VHDMI_AVCC_1V2: length 4.9
  TOP w0.254: v1(16.91,116.13) U11.60 ; U11.66 19.91,115.98 20.31,116.39 v1(20.58,116.39)
  BOTTOM w0.254: v1(16.91,116.13) 17.14,116.37 C221.1 ; v1(20.58,116.39) 20.58,115.13 20.34,114.89 19.8,114.89
  BOTTOM w0.381: 20.56,116.41 v1(20.58,116.39)
VHDMI_CVCC_1V2: length 23
  TOP w0.203: U11.47 14.24,119.58 14.54,119.28 v1(14.54,118.85)
  TOP w0.254: v1(19.48,123.95) 19.48,124.41 19.41,124.48 U11.26 ; v1(14.76,122.42) 14.76,122.4 14.44,122.08 U11.42 ; v1(14.67,116.9) 14.67,116.85 14.4,116.58 U11.53 ; U11.5 v1(22.86,118.08) ; U11.12 v1(24.41,121.58)
  L04_PWR01 w0.381: 13.67,119.18 13.67,121.93 14.16,122.42 v1(14.76,122.42) ; v1(24.41,121.58) 23.91,121.08 23.91,118.45 23.54,118.08 v1(22.86,118.08)
  BOTTOM w0.203: v1(14.54,118.85) 14.86,119.17 C214.1
  BOTTOM w0.254: C215.1 22.98,118.21 v1(22.86,118.08) ; C197.1 13.69,123.19 13.57,123.08 FB2.1 14.68,122.34 v1(14.76,122.42) 14.82,122.35 C205.1 ; v1(24.41,121.58) 23.89,121.58 C206.1 ; v1(14.67,116.9) 15.14,116.9 C219.1
VHDMI_IOVCC_3V3: length 10.2
  TOP w0.203: v1(14.64,119.95) 14.51,120.08 U11.46
  TOP w0.254: R48.1 22.8,113.39 v1(22.67,113.39) ; v1(11.49,119.87) 11.44,119.82 R41.1 ; v1(21.9,125.97) 21.91,125.96 U11.21 ; U11.3 v1(22.61,117.08)
  BOTTOM w0.203: R317.1 14.47,119.77 v1(14.64,119.95) 14.7,119.89 C213.1
  BOTTOM w0.254: v1(11.49,119.87) 11.49,120.56 11.82,120.89 R310.1 13,120.89 13.38,120.52 13.38,120.31 13.38,120.3 13.38,120.05 R317.1 ; C222.1 22.09,116.56 v1(22.61,117.08)
VLDO_CSI_1V8: length 1.6
  TOP w0.132: R19.1 79.55,137.16 79.37,137.33 U7.5
VMAIN: length 4.5
  TOP w0.254: R203.1 28.29,35.15
  BOTTOM w0.254: R442.1 32.15,50.34 32.32,50.5
  BOTTOM w0.305: U93.2 C475.1
  vias: v1(15.19,47.09) v1(15.19,46.63) v1(15.65,47.09) v1(15.65,46.63) v1(15.65,42.45) v1(15.65,41.99) v1(15.65,41.53) v1(15.65,41.08) v1(16.1,47.09) v1(16.1,46.63) v1(16.1,42.45) v1(16.1,41.99) v1(16.1,41.53) v1(16.1,41.08) v1(27.43,41.31) v1(27.43,40.3) v1(27.43,39.28) v1(27.43,38.27) v1(28.44,41.31) v1(28.44,40.3) v1(28.44,39.28) v1(28.44,38.27) v1(28.83,31.79) v1(29.46,41.31) v1(29.46,40.3) v1(29.46,39.28) v1(29.46,38.27) v1(29.84,31.79) v1(30.97,51.98) v1(30.93,51.35) v1(30.91,50.76) v1(31.48,51.72) v1(31.48,51.09) v1(31.99,51.98) v1(31.95,51.35) v1(31.93,50.76) v1(45.58,7.53) v1(46.5,7.53)
VPHY_3V3_FT4232: length 3.3
  TOP w0.254: U37.4 v1(18.01,16.71)
  BOTTOM w0.254: v1(18.01,16.71) 18.26,16.97 C456.2 FL19.1
VPLL_3V3_FT4232: length 9.1
  TOP w0.254: R251.2 13.65,10.27 13.42,10.5 13.42,12.61 15.03,14.21 v1(15.69,14.21) U37.9
  BOTTOM w0.254: FL20.1 14.91,14.18 C464.2 v1(15.69,14.21)
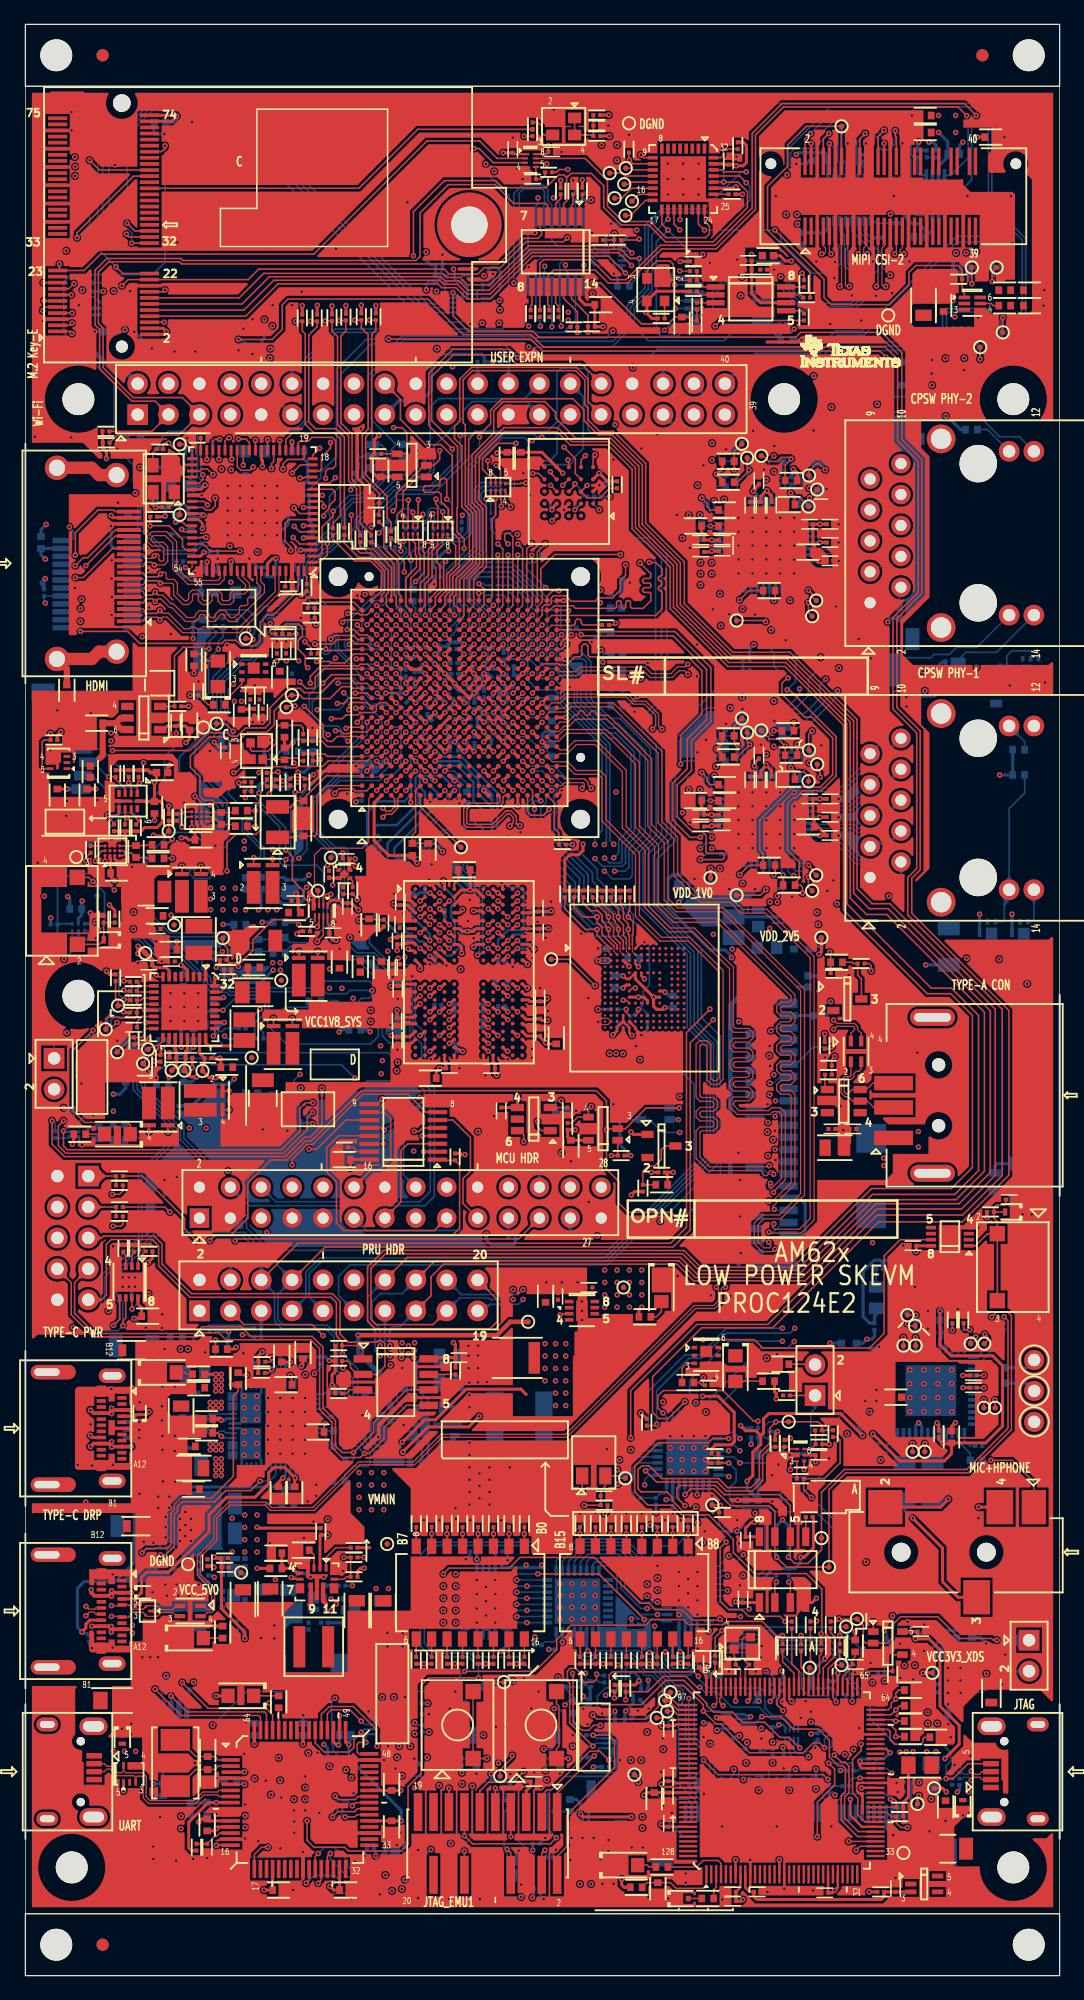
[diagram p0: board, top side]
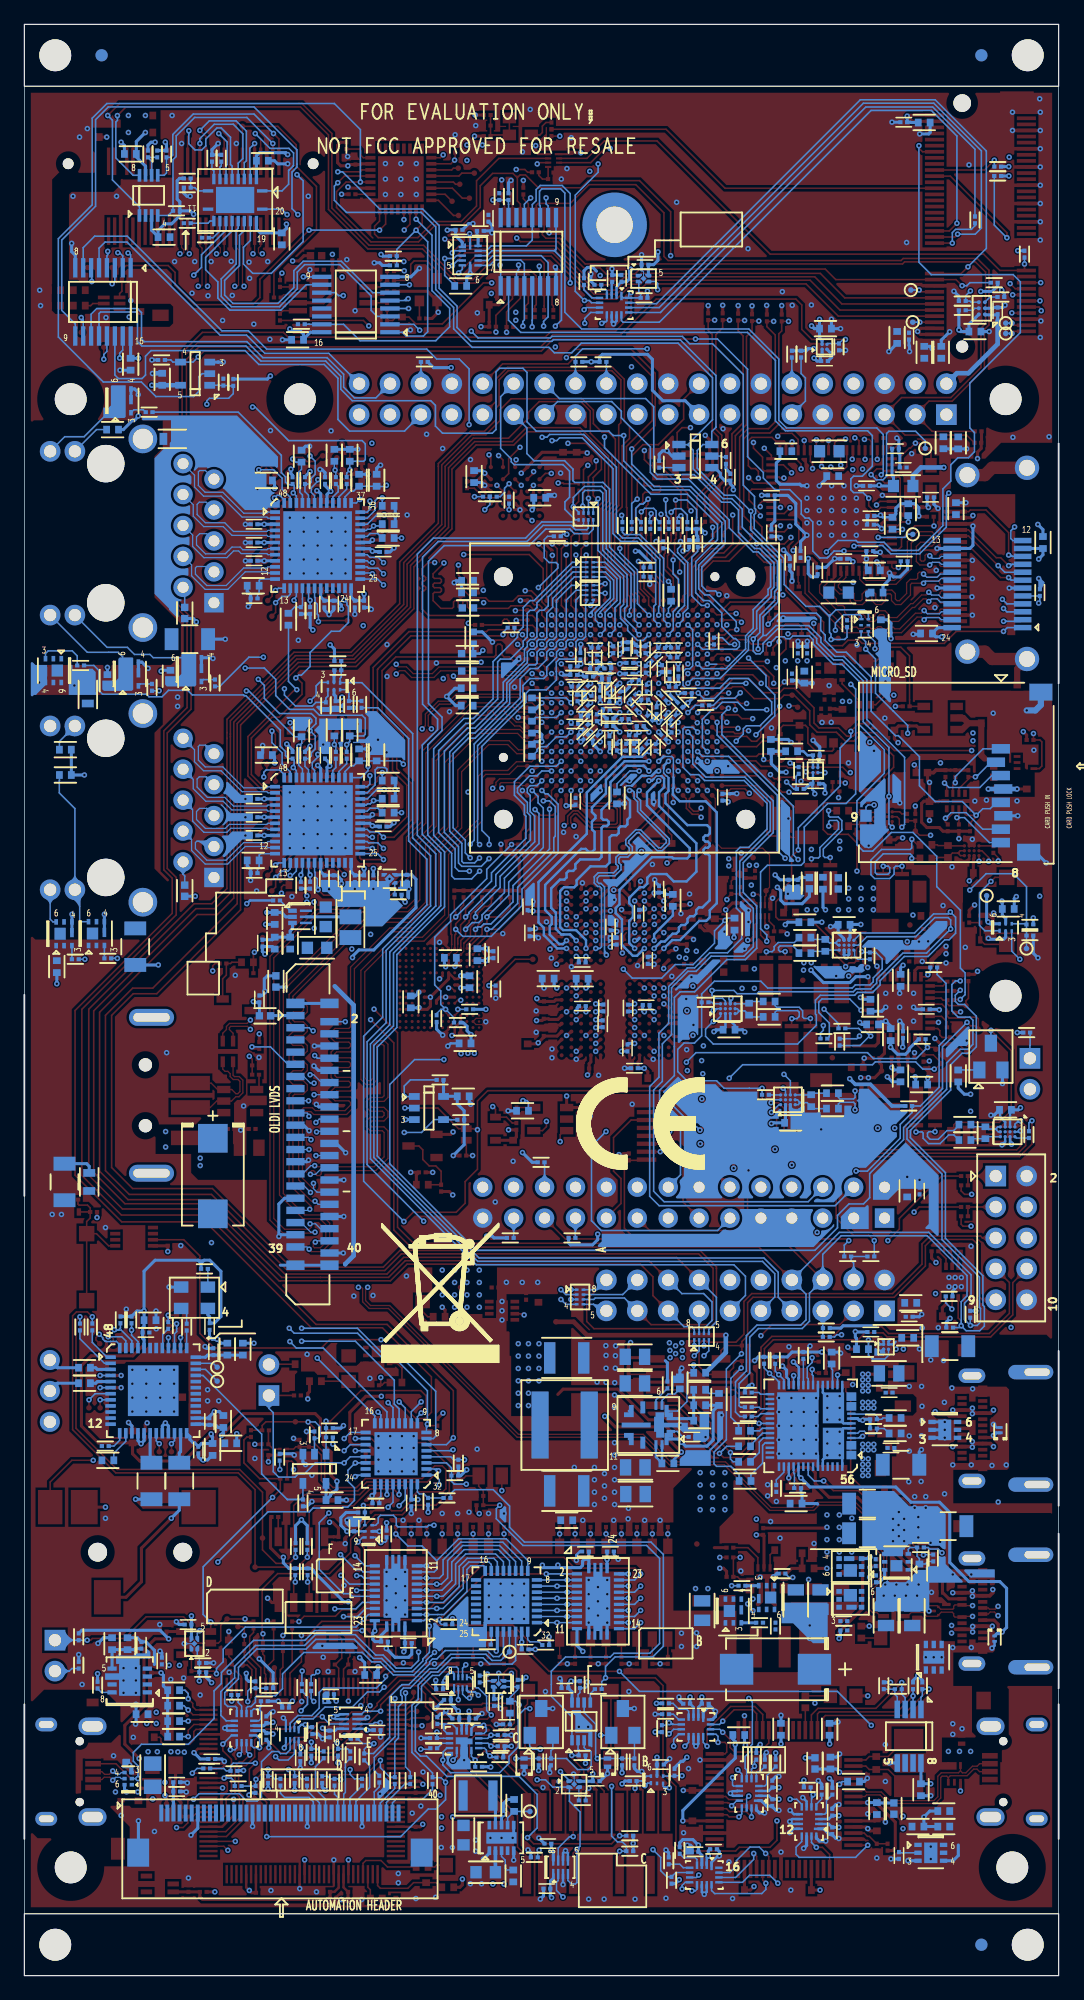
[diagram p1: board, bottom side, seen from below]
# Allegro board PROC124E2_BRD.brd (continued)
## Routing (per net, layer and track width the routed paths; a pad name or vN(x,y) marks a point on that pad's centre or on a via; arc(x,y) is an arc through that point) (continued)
VPP_1V8: length 0.6
  TOP w0.254: U12.F7 v1(31.27,101.34)
  vias: v1(24.84,91.19) v1(25.42,91.19)
VPP_LDO_EN: length 72.7
  TOP w0.127: R104.1 26.57,88.84 26.57,88.84 R103.1
  TOP w0.132: R103.1 27.26,88.48 v1(27.26,88.38)
  L06_SIG2 w0.107: v1(49.76,43.19) 49.38,42.81 46.68,42.81 44.35,45.14 32.99,45.14 25.71,52.43 25.71,65.66 26.02,65.97 26.02,68.16 30.97,73.11 30.97,76.18 30.32,76.84 29.74,76.84 29.09,77.49 29.09,79.76 26.25,82.61 26.25,87.36 v1(27.26,88.38)
  BOTTOM w0.127: U70.5 49.84,43.11 v1(49.76,43.19)
VSEL_SD_SOC: length 128.3
  TOP w0.127: R127.1 9.15,79.35 9.59,79.79 9.92,79.79 ; U12.M19 v1(36.87,111.73)
  TOP w0.132: R127.1 9.15,79.1 9.15,78.8 9.01,78.65 7.73,78.65 7.67,78.71 6.74,78.71 6.6,78.58 TP46.1 6.89,78.01 7.25,78.01 v1(7.53,78.29) ; 9.92,79.79 U22.12
  L06_SIG2 w0.107: v1(50.52,75.23) 45.21,75.23 44.49,75.96 44.49,88.4 43.42,89.47 41.68,89.47 36.48,94.66 36.48,111.35 v1(36.87,111.73)
  BOTTOM w0.132: v1(50.52,75.23) 52.93,75.23 54.97,73.2 54.97,66.68 47.86,59.57 20.02,59.57 18.17,61.43 18.17,62.44 17.23,63.38 16.04,63.38 15.53,63.89 15.53,65.87 12.74,68.66 12.74,69.65 9.54,72.85 9.54,76.27 v1(7.53,78.29)
WKUP_LFOSCO_XI: length 10.5
  TOP w0.127: U12.A2 24.81,97.74 24.25,97.17
  TOP w0.132: 24.25,97.17 23.97,96.89 23.97,93.79 23.78,93.6 C62.1 22.09,93.6 21.98,93.49 Y2.1
WKUP_LFOSCO_XO: length 8.1
  TOP w0.132: Y2.2 21.85,95.99 22.35,96.48 C53.1 22.86,96.67 24.72,98.53 U12.A3
WKUP_UART0_CTS_3V3: length 113.5
  TOP w0.132: v1(22.92,104.25) 24.47,102.7 24.47,101.74 24.83,101.38 25.23,101.38 25.63,101.78 27.26,101.78 27.3,101.74 U12.A7
  L03_SIG1 w0.107: v1(22.92,104.25) 22.49,103.82 21.29,103.82 19.63,102.16 18.67,102.16 16.5,99.99 16.5,95 13.35,91.84 13.35,90.97 12.47,90.09 12.47,85.8 11.91,85.24 11.91,84.12 11.73,83.95 11.73,82.55 10.27,81.08 10.27,78.03 9.09,76.85 9.09,60.47 11.72,57.83 11.72,55.23 12.12,54.84 12.12,53.29 13.74,51.66 13.74,51.36 14.55,50.55 16.54,50.55 17.32,49.77 17.32,49.07 17.59,48.8 17.59,40.57 18.41,39.75 18.41,32.71 18.74,32.38 18.74,21.04 22.18,17.6 25.16,17.6 25.39,17.36 25.39,17.04 26.17,16.27 v1(26.8,16.27)
  BOTTOM w0.127: v1(26.8,16.27) 26.8,15.66 26.71,15.57 U91.9
WKUP_UART0_RTS_3V3: length 92.6
  TOP w0.132: U12.B4 v1(28.07,98.94)
  L03_SIG1 w0.107: v1(25.46,22.77) 25.98,23.29 25.98,31.92 26.83,32.76 26.83,35.63 26.27,36.2 26.27,45.88 27.24,46.85 27.24,51.52 28.43,52.71 28.43,68.18 29.04,68.79 30.85,68.79 v1(31.91,67.73)
  L06_SIG2 w0.107: v1(31.91,67.73) 32.77,68.59 32.78,68.59 33.01,68.81 33.01,68.82 33.03,68.84 33.03,69.83 31.48,71.38 31.48,76.52 31.06,76.94 31.06,78.18 29.75,79.49 29.75,80.63 28.33,82.05 28.33,96.88 28.07,97.14 v1(28.07,98.94)
  BOTTOM w0.127: U91.7 25.64,16.9 25.77,17.03 25.77,18 25.29,18.47 25.29,18.88 25.17,19 25.17,22.48 v1(25.46,22.77)
WKUP_UART0_RX_3V3: length 108.1
  TOP w0.127: v1(17.12,98.81) 17.31,98.81 17.74,99.24 19.96,99.24 20.01,99.29 21.36,99.29 21.45,99.2 22.24,99.2 22.35,99.31 24.44,99.31 24.89,99.77 28.1,99.77 U12.B5
  L03_SIG1 w0.107: v1(17.12,98.81) 17.14,98.81 17.14,98.78 17.09,98.78 16.72,98.41 16.72,94.85 13.57,91.7 13.57,90.88 12.85,90.16 12.85,84.51 12.07,83.72 12.07,82.47 10.49,80.9 10.49,77.94 9.31,76.76 9.31,60.56 11.82,58.05 11.82,58.05 11.95,57.92 11.95,55.49 12.34,55.09 12.34,53.38 13.97,51.75 13.97,51.45 14.65,50.77 16.63,50.77 17.54,49.86 17.54,49.26 18.38,48.42 18.38,47.76 18.38,47.75 18.38,42.58 18.37,42.57 18.37,40.96 18.63,40.7 18.63,32.8 18.96,32.47 18.96,21.13 22.23,17.86 25.4,17.86 v1(26.37,16.89)
  BOTTOM w0.127: v1(26.37,16.89) 26.04,16.57 U91.8
WKUP_UART0_TX_3V3: length 117.6
  TOP w0.127: U12.C6 v1(28.87,100.54)
  L03_SIG1 w0.107: v1(24.99,17.2) 22.15,17.2 18.52,20.83 18.52,32.28 17.62,33.19 17.62,40.17 17.32,40.46 17.32,48.71 17.09,48.94 17.09,49.68 16.45,50.32 12.84,50.32 12.28,50.87 12.28,52.04 11.89,52.44 11.89,54.58 11.5,54.97 11.5,57.74 8.86,60.38 8.86,77.3 9.41,77.85 9.41,80.71 10.31,81.61 10.31,89.13 12.82,91.64 12.83,91.64 16.28,95.09 16.28,100.1 18.56,102.38 18.93,102.38 19.53,102.38 21.83,104.68 23.27,104.68 v1(23.99,103.97)
  BOTTOM w0.127: v1(24.99,17.2) 24.99,17.19 25.24,16.95 U91.6
  BOTTOM w0.132: R528.2 24.99,17.59 v1(24.99,17.2) ; v1(23.99,103.97) 25.76,103.97 26.37,104.58 27.64,104.58 28.15,104.07 28.4,104.07 29.29,103.18 29.29,102.82 29.27,102.8 29.27,100.94 v1(28.87,100.54)
WL_LT_EN: length 9
  TOP w0.132: U3.9 50.82,149.3 v1(50.58,149.54) ; v1(44.58,148.34) 43.87,148.34 43.64,148.11 R595.1
  L03_SIG1 w0.107: v1(50.58,149.54) 47.96,149.54 46.76,148.34 v1(44.58,148.34)
WLAN_EN: length 47.7
  TOP w0.132: v1(42.85,148.79) 42.75,148.9 U2.6 ; J2.56 6.09,148.29 v1(5.28,149.1)
  L03_SIG1 w0.107: v1(5.28,149.1) 5.46,149.28 27.87,149.28 30.48,151.89 41.5,151.89 42.34,151.05 42.34,149.3 v1(42.85,148.79)
  BOTTOM w0.132: R257.1 v1(5.28,149.1)
WLAN_EN_SOC: length 127.5
  TOP w0.132: v1(36.86,150.06) 37.29,150.06 38.45,148.9 U2.3 ; U12.D20 29.67,112.54 29.67,113.43 29.82,113.59 29.82,115.41 28.39,116.84 27.52,116.84 26.79,117.58 v1(26.79,119.96)
  L03_SIG1 w0.107: v1(4.06,149.35) 4.22,149.35 5.61,147.95 27.71,147.95 30.69,150.93 36.38,150.93 36.86,150.45 v1(36.86,150.06) 36.24,149.45 33.82,149.45 29.42,145.05 29.42,135.66 28,134.24 18.94,134.24 17.54,132.84 14,132.84 13.64,132.48 8.7,132.48 7.69,131.48 7.69,127.13 10.12,124.7 10.12,122.85 v1(9.03,121.76)
  L06_SIG2 w0.107: v1(26.79,119.96) 26.79,118.59 25.15,116.95 23.37,116.95 23.06,116.64 21.44,116.64 20.6,117.48 16.92,117.48 16.81,117.37 16.81,117.4 v1(16.82,117.4)
  BOTTOM w0.132: v1(9.03,121.76) 9.23,121.56 9.23,118.97 11.43,116.77 11.66,116.77 11.66,116.77 13.79,116.77 14.46,117.45 16.77,117.45 v1(16.82,117.4)
WLAN_IRQ: length 74.3
  TOP w0.127: U12.C20 v1(28.87,112.53)
  TOP w0.132: v1(11.48,150.29) 11.49,150.28 11.49,150.1 11.19,149.79 J2.62
  L06_SIG2 w0.107: v1(28.43,118.96) 26.14,116.66 23.61,116.66 23.25,116.3 21.36,116.3 20.73,116.92 v1(19.09,116.92)
  BOTTOM w0.132: v1(19.09,116.92) 18.14,117.87 16.65,117.87 16.51,117.72 14.35,117.72 13.67,117.05 11.54,117.05 9.51,119.08 9.51,122.1 8.86,122.75 8.86,124.08 8.28,124.66 7.41,124.66 6.92,125.15 6.92,126.73 7.3,127.11 7.3,130.79 3.15,134.94 3.15,139.11 3.73,139.7 10.47,139.7 11.48,140.71 v1(11.48,150.29) ; v1(28.43,118.96) 28.43,118.04 29.16,117.32 R333.1 29.66,116.97 30.15,116.48 30.15,113.32 29.36,112.53 v1(28.87,112.53)
WLAN_SDIO_RST: length 44.5
  TOP w0.132: 2.67,140.04 4.83,140.04 6.17,141.39 23.71,141.39 33,150.68 37.33,150.68 38.76,149.25 U2.2 ; 2.67,140.04 2.8,140.18 v1(2.8,140.57) ; 2.67,140.04 J2.23
  BOTTOM w0.132: R262.1 2.8,141.1 v1(2.8,140.57)
XDS110_DIR: length 3.1
  BOTTOM w0.127: 65.75,21.9 65.56,21.71 65.56,21.11 65.73,20.93 U84.4 ; 65.75,21.9 66.16,21.9 66.34,21.72 U84.5 ; 65.75,21.9 65.56,22.1 R509.2
XDS110_EMU0: length 22.9
  TOP w0.127: v1(72.49,12.16) 71.95,12.16 71.57,12.55 R250.2 71.14,13.07 70.78,13.43 U36.42
  L06_SIG2 w0.107: v1(64.35,17.99) 66.06,17.99 66.32,17.74 66.63,17.74 66.86,17.97 66.86,19.16 67.42,19.73 69.29,19.73 70.2,18.82 70.2,12.7 70.74,12.16 v1(72.49,12.16)
  BOTTOM w0.127: U85.7 62.81,18.22 63.32,17.71 64.07,17.71 v1(64.35,17.99)
XDS110_EMU1: length 15.5
  TOP w0.127: v1(71.1,14.48) 71.42,14.48 71.57,14.34 R249.2 U36.43
  BOTTOM w0.127: U85.6 63.16,18.55 63.47,18.23 63.94,18.23 64.11,18.41 64.67,18.41 65.51,17.56 65.51,14.69 65.87,14.33 66.72,14.33 67.32,14.94 70.64,14.94 v1(71.1,14.48)
XDS110_TCK: length 15.7
  TOP w0.127: v1(68.28,10.3) 68.61,10.63 U36.35
  L06_SIG2 w0.107: v1(68.28,10.3) 69.7,11.72 69.7,18.89 69.13,19.46 67.7,19.46 67.34,19.1 v1(67.34,18.15)
  BOTTOM w0.127: v1(67.34,18.15) 67.14,18.34 U84.14
XDS110_TDI: length 10.1
  TOP w0.127: U36.38 68.45,11.83 67.32,12.95 67.32,14.67 67.69,15.03 67.69,17.2 67.34,17.55 67.05,17.55 v1(66.47,18.13)
  BOTTOM w0.127: v1(66.47,18.13) 66.74,18.39 U84.15
XDS110_TDO: length 19.3
  TOP w0.132: U36.37 68.39,11.43 67.04,12.78 67.04,14.78 67.39,15.13 67.39,17.02 67.15,17.25 66.78,17.25 66.07,17.96 66.07,19.34 65.17,20.25 63.11,20.25 62.09,21.27 v1(60.52,21.27)
  BOTTOM w0.127: U82.7 59.92,20.67 v1(60.52,21.27)
XDS110_TMS: length 12.3
  TOP w0.127: U36.36 v1(67.66,11.03)
  L06_SIG2 w0.107: v1(67.66,11.03) 69.29,12.66 69.29,17.98 68.72,18.55 v1(68.07,18.55)
  BOTTOM w0.127: U84.13 67.54,18.7 67.69,18.55 v1(68.07,18.55)
XDS110_TRST#: length 9.2
  TOP w0.132: U36.40 69,12.63 68.41,13.22 68.41,14.56 67.98,14.99 67.98,17.77 68.69,18.48 v1(68.69,19.01)
  BOTTOM w0.127: v1(68.69,19.01) 67.97,19.73 U84.12
XDS_RSTN: length 6.2
  TOP w0.127: TP79.1 66.68,25.51 66.3,25.13 66.3,24.65 66.37,24.59 U36.70 66.37,22.85 66.64,22.58 v1(66.64,22.5)
  BOTTOM w0.127: R504.1 R497.1 66.4,23.61 66.64,23.37 v1(66.64,22.5)
XDS_USB_DM: length 30.5
  TOP w0.107: v1(77.73,16.05) 77.98,16.3 78.44,16.3 78.63,16.1 J18.2 ; v1(57.35,22.18) 57.07,22.45 57.07,22.79 57.17,22.89 U36.93
  L03_SIG1 w0.097: v1(77.73,16.05) 77.73,16.24 77.64,16.34 76.26,16.34 75.81,16.79 71.65,16.79 68.93,19.5 67.88,19.5 66.13,21.26 66.13,22.06 64.64,23.55 57.48,23.55 56.96,23.02 56.96,22.27 57.06,22.18 v1(57.35,22.18)
  BOTTOM w0.107: v1(77.73,16.05) 77.49,16.29 77.14,16.29 77.03,16.18 U88.5
XDS_USB_DP: length 30.5
  TOP w0.107: v1(56.59,22.18) 56.83,22.42 56.83,22.82 56.77,22.89 U36.94 ; v1(77.73,16.81) 78.01,16.53 78.41,16.53 78.63,16.75 J18.3
  L03_SIG1 w0.097: v1(56.59,22.18) 56.71,22.3 56.71,23.13 57.38,23.79 64.74,23.79 66.37,22.16 66.37,21.36 67.98,19.75 69.03,19.75 71.75,17.03 75.92,17.03 76.36,16.59 77.51,16.59 v1(77.73,16.81)
  BOTTOM w0.107: v1(77.73,16.81) 77.45,16.53 77.18,16.53 77.03,16.68 U88.4
XDS_USB_ID: length 34.1
  TOP w0.127: J18.4 77.47,17.4 76.24,16.18 v1(75.66,16.18) ; R220.2 56.68,27.79 v1(57.24,28.34)
  BOTTOM w0.127: U88.2 v1(75.66,16.18)
  BOTTOM w0.132: v1(57.24,28.34) 61.14,28.34 61.95,27.54 66.16,27.54 68.81,24.89 68.81,23.99 69.41,23.38 69.41,21.12 71.52,19 75.37,19 76.05,18.33 76.05,17.62 75.66,17.23 v1(75.66,16.18)
XDS_USB_VBUS: length 5.3
  TOP w0.254: R253.1 49.21,7.26 49,7.46 v1(49,7.93) ; TP90.1 75.38,15.39 v1(75.68,15.09)
  BOTTOM w0.254: U88.6 76.77,15.26 v1(76.6,15.09) ; R493.1 57.03,25.71 v1(57.44,26.12) ; R498.1 v1(78.98,24.8)
  vias: v1(74.16,21.63) v1(74.16,20.71) v1(74.94,20.71) v1(77.51,15.09)
XDS_VREF: length 15.8
  TOP w0.203: C173.2 59.51,6.88 59.17,7.23 U36.9
  TOP w0.254: U38.3 C169.1 R255.2 70.58,6.48 70.35,6.26 60.11,6.26 59.87,6.49 C173.2
N15951745: length 4.7
  TOP w0.132: U1.1 U1.4 46.59,151.17 R582.2 C5.1 46.68,152.81 R581.2
N15952254: length 2.4
  TOP w0.132: R1.1 42.13,152.2 42.43,151.9 42.43,151.37 42.63,151.17 U1.3
N16839912: length 2.4
  BOTTOM w0.127: U58.D3 19.07,84.23 C341.1 20.22,84.12 R391.1
N16839940: length 2.6
  BOTTOM w0.127: R408.1 20.2,72.48 C371.1 20.35,72.33 U61.D3
N16839975: length 2.4
  BOTTOM w0.127: U60.D3 25.49,79.81 C358.1 25.3,80.01 R396.1
N16856152: length 5.2
  TOP w0.127: Y4.2 12.63,15.56 14,16.93 C157.1 15.56,16.93 15.84,17.21 U37.3
N16856224: length 5.2
  TOP w0.127: Y4.1 12.64,19.36 14.01,18 C156.1 15.56,18 15.84,17.71 U37.2
N16857368: length 1.6
  BOTTOM w0.127: U94.2 13.06,10.09 C474.2
N16878333: length 1.2
  BOTTOM w0.127: R556.2 19.47,14.51 19.91,14.07 U92.5
N16878339: length 2.4
  BOTTOM w0.127: U92.4 19.23,13.26 19.08,13.41 19.08,14.37 18.59,14.86 R557.1
N16878497: length 9.3
  TOP w0.127: v1(50.13,81.11) 49.88,81.11 U21.H5
  TOP w0.132: v1(46.82,81.31) 44.66,83.47 TP43.1
  L03_SIG1 w0.107: v1(46.82,81.31) 47.14,81.63 49.62,81.63 v1(50.13,81.11)
  BOTTOM w0.132: R124.1 v1(46.82,81.31)
N16893179: length 1.2
  BOTTOM w0.127: R513.2 31.66,21.47 31.22,21.03 U83.5
N16893185: length 2.4
  BOTTOM w0.127: U83.4 30.41,21.72 30.57,21.88 31.2,21.88 31.69,22.36 R510.1
N16894003: length 1.4
  BOTTOM w0.127: 24.84,16.38 U91.5
  BOTTOM w0.132: 24.84,16.38 24.84,16.64 24.74,16.75 24.56,16.75 24.14,17.17 R533.2
N16894009: length 2.5
  BOTTOM w0.127: U91.4 24.15,15.57 23.99,15.73 23.99,16.37
  BOTTOM w0.132: 23.99,16.37 23.99,16.43 23.25,17.17 R534.1
N16906426: length 3.5
  TOP w0.132: R70.1 22.63,99.77 22.4,100 21.44,100 C43.2 21.26,99.89 Y1.1
N16906432: length 7.2
  TOP w0.132: Y1.3 18.5,100.69 18.63,100.57 19.95,100.57 20.61,101.23 20.61,102.48 20.81,102.69 C41.2 22.63,102.69 22.84,102.48 R65.1
N16927060: length 1.2
  TOP w0.127: R48.2 23.13,114.86 22.91,115.08 U11.72
N16927228: length 1.3
  TOP w0.127: 21.41,114.46 U11.69
  TOP w0.132: R47.1 21.35,114.41 21.41,114.46
N16927289: length 1
  TOP w0.127: R32.2 14.41,125.95 14.41,125.95 U11.36
N16929458: length 2.6
  TOP w0.127: TP65.1 v1(79.69,47.29)
  BOTTOM w0.127: U66.7 79.19,47.79 v1(79.69,47.29)
N16929460: length 1.5
  TOP w0.127: TP64.1 v1(78.77,47.29)
  BOTTOM w0.127: U66.8 v1(78.77,47.29)
N16929474: length 1.8
  BOTTOM w0.127: U66.41 73.62,51.58 73.62,52.68 R427.2
N16929699: length 1.4
  TOP w0.127: C124.1 v1(78.77,49.29)
  BOTTOM w0.127: U66.4 v1(78.77,49.29)
N16929703: length 1.4
  TOP w0.127: C126.1 v1(78.77,48.29)
  BOTTOM w0.127: U66.6 v1(78.77,48.29)
N16929744: length 1.6
  TOP w0.127: TP69.1 v1(73.91,43.69)
  BOTTOM w0.127: U66.19 74.16,43.94 v1(73.91,43.69)
N16929747: length 1.6
  TOP w0.127: TP68.1 v1(72.91,43.69)
  BOTTOM w0.127: U66.22 72.66,43.94 v1(72.91,43.69)
N16929749: length 1.9
  BOTTOM w0.127: TP102.1 69.47,50.29 U66.35
N16929751: length 2.2
  BOTTOM w0.127: U66.34 70.12,49.79 TP103.1
N16931396: length 1.1
  BOTTOM w0.127: U45.B2 6.89,136.94 7.06,136.77 R291.2
N16931420: length 1.2
  BOTTOM w0.127: R288.1 5.63,137.86 U45.C1
N16943223: length 1.7
  TOP w0.132: U6.2 55.47,138.04 R17.1
N16947096: length 1.4
  TOP w0.132: R27.1 U5.1
N16990175: length 2.7
  BOTTOM w0.127: J24.27 60.75,14.19 61.77,15.21 R550.2
N16990176: length 2.4
  BOTTOM w0.127: J24.30 59.25,14.64 59.51,14.9 R551.2
N16990179: length 4.7
  BOTTOM w0.127: R526.2 58.21,17.84 58.62,17.44 58.62,17.09 58.62,17.09 58.62,16.76 58.62,16.76 58.62,15.05 58.75,14.92 J24.31
N16990180: length 2.7
  BOTTOM w0.127: R552.2 57.25,15.59 58.25,14.59 J24.32
N16990215: length 1.6
  TOP w0.132: R200.1 U32.5
N16990246: length 4.5
  BOTTOM w0.127: R549.2 63.95,14.98 63.61,14.64 61.61,14.64 61.25,14.28 J24.26
N16990247: length 5.1
  BOTTOM w0.127: R525.2 60.4,17.84 61.08,17.16 61.08,15.33 60.25,14.5 J24.28
N16990252: length 5
  BOTTOM w0.127: J24.33 57.75,14.32 56.63,15.44 56.63,17.24 R529.2
N16994873: length 1.2
  BOTTOM w0.127: U80.4 47.06,24.21 47.19,24.08 R494.2
N16994875: length 1.1
  BOTTOM w0.102: R558.2 U90.4
N16995245: length 0.9
  BOTTOM w0.127: R512.2 C444.1
N16997746: length 5.8
  TOP w0.127: R247.1 73.88,19.58 73.77,19.46 73.77,19.21 73.57,19.01 71.42,19.01 71.07,19.35 71.07,20.05 70.89,20.23 U36.59
N17012627: length 1.4
  BOTTOM w0.127: R385.2 63.14,87.46 U57.1
N17029933: length 1.4
  TOP w0.127: R165.2 13.26,49.39 13.12,49.54 LD8.2
N17030208: length 1.6
  BOTTOM w0.127: U84.7 67.14,22.15 67.43,22.43 R508.2
N17031262: length 1.6
  TOP w0.127: LD9.2 R214.2
N17078351: length 1.5
  TOP w0.127: SW3.13 R225.1
N17078353: length 1.5
  TOP w0.127: SW3.14 R226.1
N17078355: length 1.5
  TOP w0.132: SW3.15 R227.1
N17078357: length 1.5
  TOP w0.102: R228.1 41.01,27.42
  TOP w0.127: 41.01,27.42 SW3.16
N17078758: length 1.5
  TOP w0.127: SW4.11 R231.1
N17078760: length 1.5
  TOP w0.127: SW4.12 R232.1
N17078762: length 1.5
  TOP w0.127: SW4.13 R233.1
N17078764: length 1.5
  TOP w0.127: SW4.14 R234.1
N17078766: length 1.5
  TOP w0.127: SW4.9 R229.1
N17078768: length 1.5
  TOP w0.127: SW4.10 R230.1
N17078770: length 1.5
  TOP w0.127: SW4.15 R235.1
N17078778: length 1.5
  TOP w0.127: SW4.16 R236.1
N17078974: length 2
  BOTTOM w0.127: R491.2 81.1,25.22 81.31,25.01 J16.2
N17084256: length 1.5
  TOP w0.132: SW3.9 R221.1
N17084257: length 1.5
  TOP w0.127: SW3.10 R222.1
N17084258: length 1.5
  TOP w0.127: SW3.11 R223.1
N17084259: length 1.5
  TOP w0.127: SW3.12 R224.1
N17110597: length 1.9
  TOP w0.132: v1(64.36,91.21) 64.64,90.93 64.64,90.73 TP34.1
  BOTTOM w0.132: v1(64.36,91.21) 64.3,91.21 64.12,91.39 U55.13
N17133547: length 2
  BOTTOM w0.132: J7.2 71.96,90.46 71.82,90.32 FL16.2
N17137240: length 2.5
  BOTTOM w0.132: J7.11 82.12,101.36 R365.2
N17140854: length 1
  BOTTOM w0.127: U56.3 R383.2
N17153379: length 10.6
  TOP w0.127: R106.1 v1(12.87,91.12) ; R92.2 11.6,92.87 v1(12.07,93.34)
  BOTTOM w0.127: v1(12.07,93.34) 12.07,93.33 12.07,92.62 12.2,92.49 14.56,92.49 15.43,91.62 15.43,90.41 15.12,90.1 13.88,90.1 13.52,90.46 13.52,90.99 13.4,91.12 v1(12.87,91.12)
N17153381: length 8.1
  TOP w0.127: R106.4 v1(14.42,91.12) ; R96.2 v1(12.07,91.75)
  BOTTOM w0.127: v1(14.42,91.12) 14.01,91.12 13.88,90.99 13.88,90.61 14.03,90.46 14.94,90.46 15.07,90.59 15.07,91.47 14.41,92.13 12.2,92.13 12.07,92.01 v1(12.07,91.75)
N17153415: length 5.2
  TOP w0.127: R136.1 11.71,69.49 11.73,69.47 v1(11.73,69.29)
  BOTTOM w0.127: R415.2 8.61,69.05 9.03,69.05 9.74,68.33 10.7,68.33 11.13,68.77 11.13,69.2 11.23,69.29 v1(11.73,69.29)
N17153417: length 4.7
  TOP w0.127: R136.4 v1(10.16,69.31)
  BOTTOM w0.127: v1(10.16,69.31) 10.67,69.31 10.78,69.2 10.78,68.91 10.56,68.69 9.89,68.69 9.17,69.4 8.62,69.4 8.19,69.83 R413.2
N17153507: length 7.1
  TOP w0.127: R84.2 v1(18.91,95.68) ; R101.1 v1(18.77,91.83)
  BOTTOM w0.127: v1(18.91,95.68) 18.91,95.26 18.81,95.16 18.11,95.16 17.82,94.87 17.82,94.14 17.82,94.14 17.82,94.05 19.34,92.53 19.34,91.96 19.21,91.83 v1(18.77,91.83)
N17153509: length 6.7
  TOP w0.127: R101.4 v1(20.32,91.72) ; R87.2 v1(18.9,94.41)
  BOTTOM w0.127: v1(18.9,94.41) 18.9,94.79 18.81,94.88 18.22,94.88 18.09,94.75 18.09,94.17 19.62,92.64 19.62,91.92 19.75,91.79 20.24,91.79 v1(20.32,91.72)
N17153511: length 3.3
  TOP w0.127: 15.41,94.99 15.22,95.18 U16.D2 ; 15.41,94.99 15.66,94.99 C58.2 17.11,94.55 R87.1 ; 15.41,94.99 15.2,94.78 U16.D1
N17153515: length 2.5
  TOP w0.127: U16.D3 14.93,95.53 C58.1 17.11,95.53 R84.1
N17153617: length 3.4
  TOP w0.127: R121.1 v1(22.47,84.11)
  BOTTOM w0.127: v1(22.47,84.11) 22.9,84.11 23.02,84.24 23.02,84.44 22.9,84.57 21.83,84.57 21.34,84.08 R391.2
N17153619: length 3.8
  TOP w0.127: R121.4 v1(24.02,84.1)
  BOTTOM w0.127: R388.2 21.34,85.23 21.73,84.84 23.05,84.84 23.38,84.51 23.38,84.26 23.54,84.1 v1(24.02,84.1)
N17153623: length 2.9
  TOP w0.127: R134.1 v1(16.73,72.66)
  BOTTOM w0.127: v1(16.73,72.66) 16.73,72.12 16.85,72 17.97,72 18.1,72.13 R408.2
N17153625: length 2.9
  TOP w0.127: R134.4 v1(16.73,71.11)
  BOTTOM w0.127: v1(16.73,71.11) 16.73,71.61 16.85,71.72 17.97,71.72 18.1,71.6 R410.2
N17153667: length 4.6
  TOP w0.127: R129.1 v1(20.4,78.61)
  BOTTOM w0.127: v1(20.4,78.61) 20.91,78.61 21.04,78.74 21.04,79.25 21.33,79.54 23.17,79.54 23.3,79.66 R396.2
N17153669: length 4.1
  TOP w0.127: R129.4 21.95,78.58 v1(21.93,78.6)
  BOTTOM w0.127: R399.2 23.3,79.13 23.17,79.26 21.45,79.26 21.32,79.13 21.32,78.77 21.5,78.6 v1(21.93,78.6)
N17153681: length 2.7
  TOP w0.127: R92.1 9.97,92.87 9.91,92.81 C65.1 9.07,92.79 U17.D3
N17153685: length 3.6
  TOP w0.127: 8.28,92.2 8.09,92.39 U17.D2 ; 8.28,92.2 8.07,91.99 U17.D1 ; 8.28,92.2 8.73,92.2 C65.2 9.89,91.83 9.97,91.75 R96.1
N17153701: length 3.1
  BOTTOM w0.127: U63.D1 5.02,69.7 5.19,69.53 ; 5.19,69.53 5.83,69.53 C374.2 7.03,69.72 R413.1 ; 5.19,69.53 4.97,69.3 U63.D2
N17153703: length 2.5
  BOTTOM w0.127: U63.D3 5.86,68.9 C374.1 7.1,68.74 R415.1
N17153749: length 3
  BOTTOM w0.127: 18.34,84.82 18.15,84.63 U58.D2 ; 18.34,84.82 18.13,85.03 U58.D1 ; 18.34,84.82 18.83,84.82 19.12,85.1 C341.2 20.22,85.1 R388.1
N17153787: length 3.4
  BOTTOM w0.127: 21.23,71.7 21.46,71.93 U61.D2 ; 21.23,71.7 21.4,71.53 U61.D1 ; 21.23,71.7 20.67,71.7 C371.2 20.18,71.21 R410.1
N17153799: length 3
  BOTTOM w0.127: R399.1 25.3,78.74 C358.2 25.79,79.23 26.22,79.23 ; 26.22,79.23 26.4,79.41 U60.D2 ; 26.22,79.23 26.44,79.01 U60.D1
N17153878: length 1.2
  BOTTOM w0.127: R414.1 3.48,68.79 U63.A3
N17153949: length 1.9
  BOTTOM w0.127: U58.A3 16.77,84.17 16.77,83.72 16.52,83.48 R392.1
N17153951: length 1
  BOTTOM w0.127: U61.A3 23.8,72.33 R409.1
N17154063: length 1
  BOTTOM w0.127: R397.1 28.51,79.94 28.38,79.81 U60.A3
N17167245: length 2.1
  BOTTOM w0.127: R377.2 55.96,95.88 56.58,95.88 56.82,95.64 U55.32
N17253649: length 2.5
  BOTTOM w0.254: U93.9 46.28,14.59 L10.1
N17253673: length 2.7
  BOTTOM w0.127: TP104.1 R559.1 45.28,12.96 U93.7
N17253694: length 2.3
  BOTTOM w0.127: U93.3 45.78,9.79 45.48,9.48 45.48,8.8 45.36,8.68 R565.2
N17269599: length 2.3
  TOP w0.127: U31.6 64.55,43.25 R178.1
  TOP w0.132: R178.1 64.94,44.74 R174.2
N17275147: length 1.4
  BOTTOM w0.132: R430.2 71.66,54.35 U64.3
N17277957: length 1.2
  BOTTOM w0.127: R444.2 28.71,47.81 C396.1
N17285208: length 11.2
  L03_SIG1 w0.107: v1(1.64,112.73) 2.96,114.05 2.96,118.32 v1(3.62,118.98)
  BOTTOM w0.127: v1(3.62,118.98) 3.93,118.68 3.93,118.02 3.77,117.86 U50.12 ; R342.1 U50.5
  BOTTOM w0.132: v1(1.64,112.73) 1.54,112.83 R342.1
N17337952: length 0.8
  TOP w0.127: R103.2 26.9,89.89 U18.3
N17370891: length 1.8
  BOTTOM w0.127: R437.2 18.66,49.82 18.58,49.74 U68.17
N17378539: length 2.1
  TOP w0.127: R243.2 LD10.1
N17479799: length 1.3
  BOTTOM w0.127: R498.2 78.67,23.27 U78.8
N17479805: length 4
  BOTTOM w0.254: C429.2 75.89,26.86 75.97,26.77 R487.2 R486.1 U78.5
N17479881: length 3.3
  TOP w0.127: R215.1 68.2,26.21 67.96,25.97 C152.2 67.95,25.56 67.66,25.28 67.66,25.07 67.17,24.57 U36.68
N17481587: length 1.6
  TOP w0.127: R252.2 51.27,8.93 51.12,9.08 LD11.2
N17481598: length 3.2
  TOP w0.203: C151.2 55.36,25.23 55.97,24.62 U36.96
  TOP w0.254: v1(55.93,25.37) 55.84,25.28 55.43,25.28 C151.2
  BOTTOM w0.254: v1(55.93,25.37) 55.93,25.12 56.05,25 R493.2
N17481613: length 2.1
  TOP w0.127: R220.1 56.68,25.14 56.37,24.82 U36.95
N17481619: length 6.6
  TOP w0.127: R253.2 51.08,7.64 R254.1 53.02,7.64 53.48,7.17 55.74,7.17 55.97,7.4 U36.1
N17481621: length 3.8
  TOP w0.127: R246.2 v1(71.53,19.63) 71.53,20.15 71.06,20.63 U36.60
  BOTTOM w0.127: R246.2 v1(71.53,19.63)
N17481627: length 2.1
  TOP w0.127: R256.1 56.57,7.06 56.77,7.26 U36.3
N17481631: length 1.1
  TOP w0.127: R256.2 LD12.2
N17481633: length 4.8
  TOP w0.127: U36.63 70.9,21.83 71.16,22.08 71.16,22.36 v1(71.53,22.73) 71.53,23.22 71.76,23.44 R240.2
  BOTTOM w0.127: v1(71.53,22.73) 71.53,23.17 71.81,23.44 R240.2
N17481635: length 3.1
  TOP w0.127: R245.2 v1(71.53,20.9) 71.41,21.03 U36.61
  BOTTOM w0.127: R245.2 v1(71.53,20.9)
N17481637: length 5.6
  TOP w0.127: R252.1 55.16,8.93 55.69,9.46 56.94,9.46 57.17,9.23 U36.4
N17481641: length 3.5
  TOP w0.127: R244.2 71.89,22.17 v1(71.53,21.82) 71.14,21.43 U36.62
  BOTTOM w0.127: R244.2 71.89,22.17 v1(71.53,21.82)
N17492093: length 1.4
  TOP w0.127: U19.5 23.79,86.59 23.38,86.19 R116.2
N17492111: length 2.1
  BOTTOM w0.132: J8.1 2.36,76.39 2.35,76.41 R402.1
N17498937: length 4
  BOTTOM w0.127: U66.2 78.41,50.29 80.43,52.31 R428.2
N17498940: length 3
  BOTTOM w0.127: U66.1 78.2,50.79 79.41,52 R429.2
N17653582: length 4.1
  BOTTOM w0.132: Q5.3 83.26,108.58 83.04,108.8 81.07,108.8 80.66,108.39 R352.2
N17726648: length 6.2
  TOP w0.132: R145.2 R147.1 50.75,66.07 51.18,66.5 51.73,66.5 52.25,67.03 52.25,67.82 52.57,68.14 D3.3
N17796705: length 1.1
  BOTTOM w0.132: R393.2 78.42,83.88 Q6.3
N17796716: length 1.1
  BOTTOM w0.132: R394.2 81.09,83.81 81.09,83.81 Q7.3
N17827086: length 3
  TOP w0.132: J23.1 R144.2 R146.2
N17827089: length 3
  TOP w0.132: J23.3 R148.2 R150.2
N17849698: length 0.6
  TOP w0.254: v1(15.5,33.54) 15.42,33.54 15.32,33.64 C143.1
N17850096: length 10.1
  TOP w0.254: v1(18.04,27.69) 18.04,28.21 16.11,30.14 16.11,33.02 16.06,33.07 16.13,33.14 C144.2 16.08,33.59 R208.2 16.08,34.3 15.57,34.3 v1(15.5,34.38)
  BOTTOM w0.254: v1(18.04,27.69) 17.93,27.8 R484.2 ; v1(15.53,32.72) 15.39,32.87 R482.1 ; v1(15.5,34.38) 15.62,34.25 Q10.3
N17935978: length 3.8
  BOTTOM w0.127: R478.1 10.96,33.81 10.75,34.02 R476.2
  BOTTOM w0.132: R478.1 11.44,34.26 11.63,34.45 R475.2 12.2,35.17 12.35,35.02 Q9.3
N17936309: length 1.5
  BOTTOM w0.254: R482.2 14.73,32.31 14.3,32.74 Q9.6
N18374616: length 2.6
  TOP w0.127: v1(68.59,16.23) U36.49
  BOTTOM w0.127: v1(68.59,16.23) 67.99,16.23 67.71,15.95 R553.2
N18374619: length 2.4
  TOP w0.127: v1(71.2,16.63) U36.50
  BOTTOM w0.127: R536.2 70.8,17.02 v1(71.2,16.63)
N18374622: length 4.3
  TOP w0.132: U36.81 61.97,22.86 61.78,22.67 61.78,22.24 v1(62.26,21.75)
  BOTTOM w0.132: R502.2 61.73,22.92 61.73,22.29 v1(62.26,21.75)
N18374625: length 2.3
  TOP w0.127: v1(61.21,22.52) 61.57,22.88 U36.82
  BOTTOM w0.127: R503.2 61.43,22.74 v1(61.21,22.52)
N18374804: length 2.7
  BOTTOM w0.127: J24.36 56.25,15.1 55.83,15.52 R540.2
N18374807: length 2.9
  BOTTOM w0.127: J24.37 55.75,14.18 54.56,15.37 R544.2
N18374810: length 3.5
  BOTTOM w0.127: R545.2 53.73,15.74 55.25,14.22 J24.38
N18374813: length 5
  BOTTOM w0.127: J24.39 54.75,14.19 54.45,14.49 52.26,14.49 51.46,15.29 R546.2
N18516151: length 1.2
  TOP w0.127: U17.A3 5.38,92.79 R95.1
N18520654: length 1.3
  TOP w0.127: R85.1 12.89,95.41 13.07,95.59 13.67,95.59 U16.A3
N18571509: length 1.8
  BOTTOM w0.127: U96.5 30.85,8.86 31.14,9.15 R564.2
N18571515: length 2.1
  BOTTOM w0.127: U96.4 29.72,9.54 29.87,9.69 30.82,9.69 R561.1
N18576337: length 1.8
  BOTTOM w0.127: R372.2 58.51,99.53 59.15,98.89 U55.39
N18576340: length 1.7
  BOTTOM w0.127: U55.40 59.65,98.97 59.4,99.22 R371.2
N18736007: length 2.6
  BOTTOM w0.127: U66.14 76.66,43.89 77.65,42.9 C404.2
N18736028: length 1.7
  BOTTOM w0.127: U66.13 77.16,43.97 77.64,43.49 R458.2
N18902581: length 1.5
  BOTTOM w0.127: U64.1 R422.2
N18904632: length 2.6
  TOP w0.132: R60.2 16.43,104.73 17.79,106.1 Q1.3
N18904656: length 2.2
  TOP w0.132: R56.1 14.4,108.55 14.99,107.97 LD3.2
N18904817: length 2.4
  TOP w0.132: R168.2 53.97,49.9 54.35,50.29 Q3.3
N18904841: length 2.2
  TOP w0.127: R167.1 58.38,48.82 LD7.2
N19081973: length 1.4
  TOP w0.132: R39.1 11.81,120.6 12.24,121.02 U9.1
N19082749: length 1.4
  TOP w0.132: R34.1 10.49,125.09 U9.3
N19361213: length 8.1
  TOP w0.127: U22.28 v1(16.24,79.29)
  BOTTOM w0.132: R403.2 18.85,77.12 18.85,78.23 19.71,79.1 19.71,79.96 19.46,80.21 17.17,80.21 v1(16.24,79.29)
N19361937: length 4.7
  TOP w0.132: SW1.2 6.08,84.7 D1.2 6.44,86.47 C69.2 R105.2
N19362078: length 2
  TOP w0.127: C96.1 9.18,78.34 9.62,78.79 U22.14
N19806973: length 1.2
  BOTTOM w0.127: R522.2 51.06,18.68 50.65,19.09 U87.7
N20199452: length 4.3
  TOP w0.132: D2.3 68.7,81.87 68.4,82.17 R119.1 68.05,83.13 67.95,83.23 R118.2
N20506305: length 1.1
  TOP w0.356: U33.11 24.46,30.77 24.71,30.52
N20506307: length 1.2
  TOP w0.33: U33.9 23.46,30.62 23.31,30.46
N20506388: length 1.5
  TOP w0.127: U33.6 21.99,32.56 v1(21.85,32.7)
  BOTTOM w0.132: v1(21.85,32.7) 22.14,32.7 R481.1
N20506392: length 3.2
  TOP w0.127: U33.1 24.71,34.33 25.53,35.15 R203.2
N20506511: length 1.6
  TOP w0.127: C142.1 23.71,34.56 U33.3
N20878915: length 1.9
  TOP w0.132: R8.2 45.77,145.74 45.53,145.5 U4.1
N20878927: length 1.9
  TOP w0.132: U4.2 44.88,145.4 45.01,145.52 R7.1
N20878931: length 2
  TOP w0.132: R25.2 43.81,137.13 43.58,137.36 U4.11
N20900570: length 1.5
  TOP w0.132: U6.3 R21.1
N20900572: length 1.5
  TOP w0.132: U6.8 R15.1
N20900574: length 1.6
  TOP w0.132: U6.5 63.75,136.74 R26.1
N20900809: length 1.5
  TOP w0.102: U6.7 63.71,138.04 R18.1
N20933818: length 1.2
  BOTTOM w0.132: R280.2 37.59,138.54 37.58,138.53 37.58,138.51 37.53,138.46 37.22,138.46 37.13,138.37 U44.4
N20933822: length 2
  BOTTOM w0.132: R278.1 39.01,138.45 38.36,137.8 U44.5
N20936712: length 2.2
  TOP w0.132: R162.2 64.86,50.22 J12.2
N21016640: length 3.7
  TOP w0.132: v1(65.32,98.44) 65.32,98.81 65.07,99.06 TP29.1
  BOTTOM w0.127: v1(65.32,98.44) 65.32,98.83 65.14,99.02 64.02,99.02 63.65,98.64 U55.48
N21029653: length 2.1
  TOP w0.132: R595.2 42.72,147.85 42.42,147.55 R5.2 41.95,147.56 U2.5
N21030238: length 1.9
  TOP w0.132: R155.1 51.85,54.11 52.27,54.53 LD6.2
N21068099: length 1.3
  TOP w0.132: R132.2 65.71,72.97 U23.1
N21079949: length 3.2
  TOP w0.132: TP37.1 64.35,89.4 v1(64.35,90.2)
  BOTTOM w0.132: v1(64.35,90.2) 63.83,90.72 63.33,90.72 63.15,90.9 U55.14
N21083676: length 2.1
  BOTTOM w0.132: U68.37 24.33,44.56 25.32,43.56 R459.1
N21083677: length 1.7
  BOTTOM w0.132: R453.1 24.57,44.74 24.36,44.96 U68.36
N21083678: length 4
  BOTTOM w0.132: R464.1 25.28,41.13 24.33,42.09 24.33,43.55 24.12,43.76 U68.39
N21083679: length 2.9
  BOTTOM w0.132: R461.1 25.32,42.24 24.6,42.96 24.6,43.83 24.28,44.16 U68.38
N21117349: length 14.3
  TOP w0.132: LD5.1 8.62,69.87 8.41,70.08 4.87,70.08 3.89,71.05 3.89,75.97 v1(5.57,77.64)
  BOTTOM w0.132: Q8.3 v1(5.57,77.64)
N21117357: length 1.6
  TOP w0.132: R139.1 LD5.2
N21117537: length 1.7
  BOTTOM w0.132: Q8.1 R406.2
N21197992: length 2.8
  TOP w0.132: U3.16 50.97,145.8 49.73,144.56 TP8.1
N21197993: length 1.9
  TOP w0.132: U3.15 50.42,146.3 TP7.1
N21197994: length 2.4
  TOP w0.132: U3.13 49.74,147.3 49.56,147.12 TP5.1
N21197995: length 3.5
  TOP w0.132: U3.14 49.83,146.8 49,145.98 TP6.1
N21197996: length 3.6
  TOP w0.132: U3.12 49.28,147.8 49.04,148.04 TP4.1
N21198784: length 2.3
  TOP w0.132: U3.11 49.88,148.3 49.74,148.45 TP3.1
N21608525: length 4.6
  TOP w0.132: J2.32 v1(8.74,142.29)
  BOTTOM w0.132: v1(8.74,142.29) 8.74,143.15 8.47,143.42 7.18,143.42 6.88,143.72 R261.1
N21763900: length 2
  BOTTOM w0.132: U98.13 68.93,143.29 69.49,142.73 R570.2
N21763905: length 2
  BOTTOM w0.132: R569.2 69.91,143.93 69.73,144.11 U98.12
N21763910: length 1.5
  BOTTOM w0.132: R572.2 69.58,148.37 69.43,148.22 U98.9
N21763915: length 1.5
  BOTTOM w0.132: R571.2 68.82,148.63 68.93,148.53 U98.8
N21834326: length 3.4
  TOP w0.127: R217.1 62.23,25.78 63.17,24.84 U36.78
N21834328: length 5
  TOP w0.127: R211.1 62.99,25.6 63.57,25.03 U36.77
N21834330: length 3
  TOP w0.127: R218.1 63.75,25.32 63.97,25.11 U36.76
N21834332: length 5.1
  TOP w0.127: U36.74 64.77,24.88 64.96,25.08 64.96,25.49 64.51,25.94 R212.1
N21834361: length 3.1
  TOP w0.127: R216.1 65.4,26.4 65.26,26.26 65.26,24.85 65.17,24.75 U36.73
N21834363: length 5.3
  TOP w0.127: U36.72 65.57,25.28 66.48,26.2 66.48,27.86 66.16,28.18 R213.1
N21834365: length 3.3
  TOP w0.127: U36.71 65.97,25.19 66.93,26.15 R219.1
N21834376: length 1.6
  TOP w0.127: U36.75 64.37,25.2 TP80.1
N22163762: length 2.4
  BOTTOM w0.203: U125.B1 20.19,100.22 C507.1 20.64,100.23 20.97,100.56 R587.1
N22221349: length 1.1
  BOTTOM w0.254: Q15.3 24.65,32.02 R592.2
N22235133: length 1.2
  BOTTOM w0.254: Q14.3 24.87,28.98 R594.2
N22622854: length 1.7
  BOTTOM w0.132: J27.2 71.82,113.88 FL22.2
N22622886: length 1.8
  BOTTOM w0.127: R628.2 59.21,122.32 59.21,121.87 59.65,121.43 U127.40
N22622904: length 1.8
  BOTTOM w0.127: U127.39 59.15,121.45 58.51,122.09 R627.2
N22623025: length 2.1
  BOTTOM w0.127: U127.32 56.82,118.2 56.58,118.44 55.96,118.44 R632.2
N22623655: length 2.2
  TOP w0.132: TP125.1 65.07,122 v1(64.44,121.36)
  BOTTOM w0.127: U127.48 63.65,121.2 64.02,121.58 64.23,121.58 v1(64.44,121.36)
N22623691: length 3.2
  TOP w0.132: TP126.1 64.35,111.96 v1(64.35,112.76)
  BOTTOM w0.132: v1(64.35,112.76) 63.83,113.27 63.33,113.27 63.15,113.45 U127.14
N22623898: length 1.9
  TOP w0.132: v1(64.36,113.77) 64.64,113.49 64.64,113.29 TP127.1
  BOTTOM w0.132: U127.13 64.12,113.95 64.3,113.77 v1(64.36,113.77)
N22624142: length 1.4
  BOTTOM w0.132: R629.2 75.22,128.6 76,128.6 Q19.3
N22624353: length 1.2
  BOTTOM w0.132: Q20.3 75.47,106.08 R641.2
N22624355: length 1.2
  BOTTOM w0.132: Q21.3 70.29,106.44 R651.2
N22624429: length 3.3
  BOTTOM w0.132: J27.11 79.06,126.97 R647.2
N22624465: length 2.6
  BOTTOM w0.132: U128.6 58.55,105.61 58.33,105.39 58.33,105.03 58.33,105.03 R657.1 R660.2
N22727847: length 1.8
  TOP w0.127: U12.G19 v1(32.07,111.73)
  BOTTOM w0.132: R316.2 31.85,112.52 32.07,112.3 v1(32.07,111.73)

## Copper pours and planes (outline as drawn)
AGND_AUD on TOP: 71.82,50.1 71.82,44.55 77.74,44.55 77.74,49.95 76.65,49.95 76.49,50.1
AGND_AUD on L06_SIG2: 83.96,50.28 83.96,29.86 74.6,29.86 68.77,35.69 68.77,46.62 72.04,46.62 72.32,46.9 72.32,50.15 77.2,50.15 77.35,50 78.98,50 79.26,50.28
AGND_AUD on L07_GND02: 83.96,50.28 83.96,29.86 74.6,29.86 68.77,35.69 68.77,46.64 68.79,46.62 72.04,46.62 72.32,46.9 72.32,50.15 77.2,50.15 77.35,50 78.98,50 79.26,50.28
DGND on TOP (solid shape): 20.17,102.06 20.28,102.08 20.34,101.99 20.34,101.34 19.84,100.84 19.06,100.84 19.06,101.85 19.95,101.85
DGND on TOP (solid shape): 58.18,149.63 58.93,149.63 58.93,149.03 58.87,148.97 58.55,148.97 58.45,149.07 58.15,149.07 58.15,149.12 57.47,149.12 57.47,149.13 57.44,149.13 57.42,149.2 57.62,149.39 57.62,149.74 58.18,149.74
DGND on TOP (solid shape): 33.69,115.68 33.72,115.73 33.78,115.72 33.8,115.7 33.8,114.04 33.31,113.55 33.2,113.52 33.14,113.62 33.14,114.22 33.69,114.78
DGND on TOP (solid shape): 48.98,139.78 49,139.73 49.01,139.7 49,139.61 48.92,139.56 48.24,139.56 47.02,140.78 47,140.89 47.09,140.95 47.81,140.95
DGND on TOP (solid shape): 63.41,97.34 63.46,97.31 63.45,97.26 63.21,97.02 63.01,97.02 62.37,96.38 62.37,92.32 63.33,91.36 63.33,91.09 63.32,91.08 63.32,90.95 62.1,90.95 62.1,91.72 60.9,91.72 60.9,92.26 60.62,92.54 60.62,94.8 63.13,97.31 63.24,97.31 63.28,97.34
DGND on TOP (solid shape): 14.64,116.24 14.63,116.21 14.62,116.14 14.62,116 14.58,116 14.58,114.84 13.6,114.84 13.32,115.13 13.3,115.24 13.39,115.3 13.68,115.3 13.96,115.58 13.96,115.75 14.33,115.75 14.33,116.25 14.53,116.25 14.58,116.3
DGND on TOP (solid shape): 23.91,36.3 23.88,36.27 23.88,35.47 22.85,35.47 22.85,34.43 23.45,34.43 23.45,33.99 23.38,33.99 23.38,32.98 24.86,32.98 24.86,32.78 24.67,32.78 24.67,32.62 23.07,32.62 23.07,33.39 22.47,33.39 22.08,33.78 21.56,33.78 21.56,33.97 21.41,33.97 21.41,34.17 21.57,34.17 21.57,35.21 20.6,35.21 20.6,34.17 20.75,34.17 20.75,33.97 19.87,33.97 19.87,36.43 23.91,36.43
DGND on TOP (solid shape): 65.9,28.07 66.21,27.75 66.21,26.31 65.7,25.79 65.59,25.77 65.53,25.87 65.53,26.15 65.67,26.29 65.67,26.36 65.77,26.36 65.77,27.69 65.67,27.69 65.67,27.78 65.66,27.79 65.66,27.88 65.66,27.89 65.7,27.95 65.73,28.04 65.73,28.14 65.9,28.14
DGND on TOP (solid shape): 23.47,89.26 23.56,89.23 23.62,89.17 23.61,89.15 23.65,88.93 23.78,88.76 23.78,88.59 23.87,88.5 23.87,88.37 23.85,88.37 23.85,87.47 23.51,87.47 23.51,88.31 23.16,88.67 23.16,89.05 23.19,89.06 23.31,89.12 23.4,89.21
DGND on TOP (solid shape): 71.76,133.18 71.76,133.16 71.73,133.11 71.68,133.12 70.76,134.04 60.93,134.04 60.86,134.07 60.83,134.14 60.83,134.2 60.86,134.27 60.94,134.3 63.43,134.3 63.82,134.69 70.26,134.69
DGND on TOP (solid shape): 55.93,145.95 57.18,145.95 57.18,146.03 57.41,146.03 57.41,145.93 58.73,145.93 58.73,145.97 58.93,145.97 58.96,145.97 59.04,145.95 59.07,145.87 59.07,145.33 56.4,142.66 56.34,142.66 56.3,142.69 56.31,142.75 56.49,142.93 56.49,143.8 56.08,144.21 56.08,144.43 56.16,144.43 56.16,145.68 52.18,145.68 52.18,149.43 55.93,149.43
DGND on TOP (solid shape): 23.52,96.95 23.63,96.98 23.7,96.88 23.7,93.9 23.67,93.87 23.38,93.87 23.38,94.08 22.34,94.08 22.34,93.87 21.98,93.87 21.97,93.86 21.92,93.85 21.89,93.9 21.89,94.25 21.87,94.25 21.87,95.22 21.89,95.22 21.89,95.72 21.96,95.72 22.27,96.03 22.34,96 23.38,96 23.38,96.81
DGND on TOP (solid shape): 54.07,108.04 54.16,107.98 54.16,107.88 54.13,107.84 54.12,107.79 54.11,107.75 53.5,107.75 52.94,107.19 51.58,107.19 51.03,107.74 47.89,107.74 47.82,107.77 47.79,107.85 47.79,107.88 47.79,107.92 47.81,108 47.89,108.04
DGND on TOP (solid shape): 52.98,140.44 52.98,139.57 53.22,139.33 53.25,139.24 53.2,139.16 53.05,139.01 53.03,138.79 53.01,138.71 52.93,138.67 51.68,138.67 51.68,140.04 51.62,140.04 51.57,140.07 51.59,140.13 52.01,140.56 52.86,140.56
DGND on TOP (solid shape): 62.59,38.49 62.59,37.78 62.54,37.69 62.43,37.7 62.23,37.77 62.03,37.7 61.92,37.69 61.86,37.78 61.86,38.24 61.25,38.85 58.55,38.85 58.54,38.86 58.07,38.86 57.87,39.06 57.85,39.17 57.94,39.24 61.85,39.24
DGND on TOP (solid shape): 26.35,34.66 26.29,34.66 26.28,34.66 25.84,34.35 26.28,34.04 26.29,34.04 26.35,34.04 26.35,33.98 26.46,33.98 26.46,33.12 26.35,33.12 26.35,33.02 26.28,33.02 26.08,32.83 25.87,32.83 25.87,32.89 25.05,32.89 25.05,33.99 24.98,33.99 24.98,34.22 25.64,34.88 26.35,34.88
DGND on TOP (solid shape): 22.15,106.54 22.23,106.49 22.24,106.39 22.21,106.26 22.23,106.13 22.22,106.04 22.14,105.99 21.59,105.99 20.55,104.96 20.44,104.94 20.38,105.03 20.38,105.39 17.72,105.39 17.62,105.46 17.65,105.57 18.06,105.98 18.06,106.06 18.23,106.06 18.23,106.53 20.08,106.53 20.08,106.54
DGND on TOP (solid shape): 10.78,114.28 11,114.04 11.31,114.1 11.92,114.1 11.92,113.28 12.17,113.02 12.18,112.97 12.14,112.94 12.08,112.94 11.37,113.65 11,113.65 11,113.69 10.67,113.95 10.35,113.69 10.34,113.65 9.99,113.65 9.99,113.71 9.76,113.95 10.04,114.24 10.04,114.32 10.77,114.32
DGND on TOP (solid shape): 64.59,32.22 64.62,32.15 64.59,32.08 64.57,32.05 64.56,32.01 64.56,30.77 63.55,29.76 63.55,29.75 63.49,29.61 63.38,29.52 63.36,29.51 63.36,29.47 62.62,29.47 62.62,29.39 62.56,29.39 62.49,29.41 62.33,29.57 62.31,29.6 62.31,29.67 63.37,29.67 63.37,31.62 63.13,31.62 63.13,32.31 63.06,32.38 63.06,32.39 63.02,32.49 62.96,32.57 62.93,32.68 63.02,32.75 64.07,32.75
DGND on TOP (solid shape): 19.62,111.09 19.73,111.11 19.8,111.03 19.82,110.94 19.86,110.87 19.86,110.21 20.15,109.92 20.18,109.92 20.18,109.82 22.13,109.82 22.16,109.76 22.14,109.75 22.14,109.05 20.03,109.05 20.03,108.31 17.36,108.31 16.79,107.74 16.68,107.71 16.61,107.81 16.61,108.72 16.27,108.72 16.19,108.76 16.18,108.85 16.19,108.96 16.16,109.08 16.16,109.09 16.16,109.15 16.26,109.15 16.52,109.41 17.21,109.41 17.65,108.96 19.07,108.96 19.58,109.47 19.58,111.05
DGND on TOP (solid shape): 57.97,26.1 58.07,26.01 58.08,25.95 58.03,25.92 58,25.92 58,25.18 58.37,25.18 58.5,25.06 58.5,24.68 56.85,24.68 56.75,24.74 56.77,24.85 56.95,25.03 56.95,25.33 57.05,25.33 57.05,25.8 57.11,25.9 57.22,25.88 57.58,25.82 57.77,26.14 57.8,26.21 57.87,26.25 57.97,26.25
DGND on TOP (solid shape): 31.62,126.39 31.69,126.49 31.8,126.46 31.98,126.28 31.98,126.26 32.23,126.01 32.25,126.01 32.79,125.47 33.63,125.47 33.71,125.43 33.73,125.34 33.72,125.2 33.78,125.06 33.78,124.62 33.67,124.52 32.31,124.52 32.31,123.94 31.38,123.01 31.27,122.98 31.21,123.08 31.21,123.57 29.91,123.57 29.91,123.42 29.72,123.42 29.72,123.57 28.89,123.57 28.76,123.7 28.76,124.6 28.78,124.62 29.62,124.62 29.62,124.72 29.91,124.72 29.91,124.5 31.21,124.5 31.21,124.72 31.28,124.72 31.62,125.06
DGND on TOP (solid shape): 10.35,112.78 10.63,112.53 10.96,112.7 11.04,112.75 11.12,112.72 11.52,112.32 11.54,112.21 11.45,112.15 11.39,112.15 11.38,112.19 11.05,112.45 10.73,112.19 10.72,112.15 10.04,112.15 10.04,112.24 9.79,112.49 10.04,112.74 10.04,112.82 10.34,112.82
DGND on TOP (solid shape): 24.35,135.5 24.39,135.59 24.49,135.59 24.6,135.56 24.71,135.57 24.77,135.56 24.82,135.51 24.93,135.51 24.93,134.97 25.38,134.51 25.38,129.02 25.32,128.93 25.21,128.95 24.47,129.26 23.73,128.96 23.62,128.94 23.56,129.04 23.56,134.64 24.25,135.32 24.25,135.48 24.35,135.48
DGND on TOP (solid shape): 27.17,99.5 27.24,99.47 27.27,99.39 27.29,99.18 27.42,99.02 27.46,98.94 27.42,98.86 27.39,98.83 27.37,98.8 24.61,98.8 23.5,97.7 23.39,97.68 23.33,97.77 23.33,98.03 23.48,98.03 23.77,98.32 23.78,98.32 24.01,98.56 23.92,98.87 23.9,98.98 23.99,99.05 24.55,99.05 25,99.5
DGND on TOP (solid shape): 22.54,104.16 22.62,104.11 22.72,103.99 22.85,103.93 22.87,103.92 24.2,102.59 24.2,101.62 23.97,101.62 23.97,101.78 23.21,101.78 23.21,102.34 23.11,102.34 23.11,102.59 22.74,102.96 21.82,102.96 21.82,103.17 20.73,103.17 20.73,103.78 20.92,103.97 21,104 21.08,103.95 21.47,103.74 21.84,103.98 21.85,104.01 21.97,104.01 21.98,104.01 22.24,103.96 22.44,104.11
DGND on TOP (solid shape): 27.84,127.45 27.9,127.36 27.9,127.11 27.42,126.63 27.42,123.03 28.81,121.63 28.81,121.32 28.7,121.32 28.7,120.59 28.79,120.59 28.79,120.35 28.69,120.35 28.69,119.36 28.64,119.28 28.55,119.27 28.34,119.28 28.17,119.16 28.1,119.12 28.02,119.15 27.78,119.39 27.78,122.33 27.12,122.99 27.12,126.73 26.87,126.98 26.85,127.09 26.95,127.15 27.37,127.21 27.73,127.43
DGND on TOP (solid shape): 47.32,21.99 48.06,21.99 48.14,21.94 48.15,21.85 48.12,21.67 48.2,21.51 48.21,21.4 48.12,21.34 47.07,21.34 46.95,21.45 46.95,21.47 46.39,21.64 46.56,21.08 46.58,21.08 46.65,21 46.67,20.9 46.59,20.83 46.18,20.42 45.85,20.42 45.28,20.99 45.28,22.04 45.33,22.09 47.22,22.09
DGND on TOP (solid shape): 77.07,19.68 77.14,19.78 77.25,19.75 77.87,19.14 79.75,19.14 79.76,19.1 80.09,18.64 80.65,18.57 80.74,18.56 80.79,18.48 80.79,15.03 80.74,14.95 80.65,14.94 80.55,14.96 80.44,14.97 80.36,14.99 80.33,15.07 80.33,16.02 80.2,16.02 80.2,17.84 78.5,17.84 78.5,17.67 77.36,17.67 76.13,16.45 75.86,16.45 75.8,16.48 75.74,16.5 75.66,16.57 75.69,16.67 76.13,17.11 76.13,17.93 77.07,18.87
DGND on TOP (solid shape): 55.79,28.57 55.87,28.52 55.89,28.43 56.2,27.98 56.51,28.43 56.52,28.52 56.6,28.57 56.82,28.57 56.9,28.53 56.92,28.44 56.91,28.4 56.41,27.9 56.41,26.66 56.31,26.66 56.31,25.7 56.25,25.6 56.15,25.62 55.98,25.69 55.8,25.67 55.79,25.66 55.73,25.66 55.73,25.73 54.99,25.73 54.99,25.21 54.84,25.21 54.84,26.55 54.74,26.55 54.74,26.81 55.06,26.81 55.06,28.57
DGND on TOP (solid shape): 32.16,46.33 33.68,46.33 33.78,46.27 33.75,46.16 33.58,45.98 32.69,45.98 30.75,44.04 30.66,43.75 30.91,43.43 30.88,43.34 30.78,43.23 30.78,42.76 31.24,42.76 33.22,44.74 33.81,44.74 33.91,44.67 33.89,44.56 31.78,42.46 27.95,42.46 27.9,42.49 27.91,42.54 27.93,42.56 28.01,42.59 28.06,42.62 28.38,42.62 29.74,43.98 29.74,44.88 31.44,46.57 32.16,46.57
DGND on TOP (solid shape): 66.69,42.23 65.54,41.08 64.35,41.08 64.35,41.18 64.33,41.18 64.24,41.24 64.25,41.35 64.33,41.55 64.27,41.76 64.27,41.95 64.36,41.95 64.36,42.42 64.56,42.42 64.56,42.38 64.61,42.38 64.61,42.21 64.94,41.88 65.27,42.21 65.27,42.38 65.32,42.38 65.32,43.12 64.92,43.12 64.87,43.15 64.89,43.21 64.95,43.27 65.88,43.27 65.88,43.31 66.06,43.31 66.32,43.44 66.4,43.82 66.48,43.86 66.69,43.86
DGND on TOP (solid shape): 19.13,86.13 19.22,86.06 19.2,85.95 18.42,85.18 18.42,84.31 17.9,83.79 17.82,83.76 17.74,83.82 17.33,83.97 17.13,83.58 17.11,83.49 17.03,83.45 16.93,83.45 16.93,83.79 16.88,83.79 16.88,84.47 16.56,84.79 16.53,84.86 16.55,84.93 16.54,85.52 15.95,85.55 15.84,85.53 15.78,85.62 15.78,85.78 17.84,85.78 18.18,86.13
DGND on TOP (solid shape): 57.52,38.58 57.62,38.55 57.85,38.32 58.32,38.32 58.33,38.31 59.6,38.31 59.69,38.26 59.69,38.16 59.68,37.85 59.94,37.67 59.98,37.61 59.93,37.57 59.53,37.57 58.85,36.89 58.85,36.83 58.79,36.74 58.69,36.75 58.34,36.78 58.15,36.48 58.09,36.38 57.98,36.41 56.89,37.5 56.87,37.61 56.96,37.67 57.39,37.67 57.39,38.41 57.43,38.46 57.45,38.51
DGND on TOP (solid shape): 62.31,140.5 62.95,140.5 63.09,140.53 63.21,140.62 63.28,140.65 63.36,140.62 63.7,140.28 63.73,140.19 63.68,140.12 63.5,139.86 63.62,139.57 63.62,138.96 63.47,138.96 63.47,139.12 62.39,139.12 62.29,139.18 62.31,139.29 62.07,139.85 61.83,139.29 61.85,139.18 61.76,139.12 61.57,139.12 61.57,137.72 60.56,137.72 60.01,138.26 60.01,139.48 61.14,139.48 61.14,140.75 62.06,140.75
DGND on TOP (solid shape): 12.63,68.1 4.4,68.1 4.31,68.15 4.31,68.26 4.31,68.59 5.44,68.59 5.44,68.84 5.77,68.84 5.77,68.31 7.26,68.31 7.26,69.81 7.87,69.81 7.87,68.31 9.36,68.31 9.36,69.46 9.73,69.46 9.8,69.43 9.83,69.35 10.16,68.98 10.49,69.35 10.51,69.43 10.59,69.46 11.3,69.46 11.38,69.42 11.4,69.34 11.73,68.96 12.05,69.34 12.08,69.42 12.15,69.46 12.48,69.46 12.48,69.96 12.63,69.96
DGND on TOP (solid shape): 71.07,16.32 71.07,16.23 72.24,16.23 72.24,14.81 71.86,14.42 71.53,14.75 71.29,14.75 71.13,14.81 70.96,14.79 70.87,14.79 70.82,14.88 70.82,15.73 68.8,15.73 68.71,15.75 68.6,15.73 68.58,15.72 68.4,15.31 68.79,15.09 68.88,15.08 68.91,15 68.91,13.34 68.85,13.25 68.74,13.27 68.68,13.33 68.68,14.67 68.25,15.1 68.25,15.86 68.3,15.95 68.41,15.95 68.59,15.9 68.77,15.95 68.78,15.96 68.91,15.96 68.91,15.92 70.82,15.92 70.82,16.36 71,16.36
DGND on TOP (solid shape): 25.07,97.47 25.16,97.41 25.15,97.31 25.31,96.8 25.75,97.11 25.75,97.13 25.87,97.26 26.84,97.26 27.01,97.09 27.16,97.09 27.24,97.05 27.27,96.98 27.26,96.91 27.27,96.85 27.25,96.77 27.17,96.73 26.94,96.64 26.83,96.42 26.77,96.34 26.67,96.34 25.48,96.63 24.41,96.04 24.3,96.01 24.23,96.1 24.23,96.78 24.44,96.98 24.46,97.01 24.92,97.47
DGND on TOP (solid shape): outline of 102 points within 44.12,17.04 46.32,21.92
DGND on TOP (solid shape): 26.56,40.67 26.67,40.69 26.73,40.6 26.73,38.01 27.87,36.86 27.87,35.48 27.68,35.48 27.68,35.52 26.35,35.52 26.35,35.42 25.42,35.42 24.72,34.72 24.61,34.69 24.54,34.79 24.54,35.82 24.65,35.82 24.65,35.87 24.84,35.87 25.17,36.2 24.84,36.53 24.65,36.53 24.65,37.07 24.69,37.15 24.77,37.17 25.02,37.77 24.57,37.3 24.58,37.19 24.49,37.14 23.91,37.14 23.91,37.09 19.87,37.09 19.87,37.98 19.9,38.02 19.96,38.01 20.02,37.95 23.84,37.95
DGND on TOP (solid shape): 15.03,101.26 15.13,101.29 15.2,101.21 15.23,101.13 15.29,101.06 15.81,100.54 16.08,100.54 16.08,100.49 16.81,100.49 16.81,101.13 17.64,101.13 17.77,101.25 17.88,101.27 17.94,101.18 17.94,100.66 18.23,100.66 18.23,100.58 18.51,100.3 18.94,100.3 18.94,99.51 17.63,99.51 17.24,99.12 17.21,99.12 16.79,98.76 17.3,98.53 17.31,98.54 17.42,98.54 17.86,98.98 18.08,98.98 18.08,98.4 17.64,98.4 17.64,98.3 17.53,98.3 17.51,98.28 17.49,98.28 17.23,98.07 17.29,97.73 17.31,97.67 17.29,97.61 17.28,97.58 17.27,97.55 17.27,97.48 17.21,97.48 17.2,97.49 17.15,97.49 17.11,97.47 17.09,97.46 16.91,97.46 16.91,97.35 16.54,97.35 16.05,96.85 15.91,96.85 15.91,96.72 15.67,96.72 15.65,96.71 15.63,96.7 15.59,96.67 15.45,96.81 14.79,96.81 14.62,96.99 14.62,97.53 15.96,97.53 16.17,97.74 16.17,98.09 15.91,98.09 15.91,98.02 14.62,98.02 14.62,98.56 13.83,99.35 13.83,100.07
DGND on TOP (solid shape): outline of 126 points within 54.24,48.28 64.4,51.96
DGND on TOP (solid shape): 61.6,27.67 61.86,27.67 61.86,26.31 61.96,26.31 61.96,25.67 62.13,25.5 62.15,25.41 62.08,25.33 61.86,25.13 61.89,24.84 61.89,24.73 61.8,24.68 61.28,24.68 61.19,24.73 61.18,24.82 60.88,25.29 60.58,24.82 60.58,24.73 60.49,24.68 59.43,24.68 59.43,25.13 59.48,25.18 59.86,25.18 59.86,25.92 59.44,25.92 59.18,26.18 59.18,27.25 60.18,27.25 60.18,28.36 59.01,28.36 59.01,28.07 58.95,28.07 58.65,27.77 58.65,27.36 57.66,27.36 57.66,26.54 57.62,26.46 57.53,26.44 57.36,26.44 57.22,26.37 57.11,26.35 57.05,26.44 57.05,26.66 56.95,26.66 56.95,27.68 57.29,28.02 57.3,28.02 57.55,28.22 57.51,28.54 57.48,28.57 57.73,28.82 60.45,28.82
DGND on TOP (solid shape): 62.69,43.06 62.76,42.98 63.05,42.98 63.05,42.95 63.65,42.95 63.65,42.56 63.05,42.56 63.05,42.52 62.92,42.52 62.61,42.21 62.61,41.76 62.59,41.4 62.91,41.24 62.99,41.21 63.02,41.13 63.02,40.45 63.7,40.45 63.7,39.8 64.28,39.22 64.28,39.21 64.84,39.04 64.67,39.6 64.66,39.6 64.23,40.03 64.23,40.45 64.35,40.45 64.35,40.54 65.65,40.54 65.74,40.48 65.72,40.37 65.16,39.81 65.16,38.04 63.75,38.04 63.75,37.3 63.86,37.3 63.86,37.02 63.63,37.02 63.63,35.07 63.99,35.07 64.08,35 64.06,34.89 63.86,34.69 63.71,34.69 63.43,34.53 63.42,34.2 63.43,34.19 63.43,34.13 63.33,34.13 63.09,34.36 63.13,34.4 63.13,35.07 63.37,35.07 63.37,37.02 63.13,37.02 63.13,38.71 62.07,39.78 60.33,39.78 60.24,39.84 60.26,39.95 60.86,40.55 60.86,42.64 61.27,43.06 62.01,43.06
DGND on TOP (solid shape): outline of 139 points within 23.98,141.13 41.68,150.41
DGND on TOP (solid shape): 61.32,38.01 61.32,37.02 61.09,37.02 61.09,35.07 61.32,35.07 61.32,34.4 61.42,34.31 61.42,34.29 61.51,34.13 61.68,34.04 61.69,34.04 62.26,33.46 62.29,33.35 62.19,33.29 60.03,33.29 59.18,34.14 59.15,34.23 59.19,34.3 59.25,34.81 58.74,34.76 58.66,34.71 58.58,34.74 58.45,34.87 58.45,35.93 58.4,35.99 58.38,36.1 58.48,36.16 58.52,36.16 58.56,36.17 58.62,36.16 58.67,36.11 58.69,36.09 58.81,35.96 58.81,35.66 59.11,35.66 59.2,35.58 59.3,35.55 59.37,35.62 59.38,35.66 59.55,35.66 59.55,35.71 59.82,35.71 59.82,35.07 60.5,35.07 60.65,34.92 60.76,34.9 60.82,34.99 60.82,35.07 60.83,35.07 60.83,37.02 60.34,37.02 60.26,37.06 60.24,37.15 60.23,37.36 60.1,37.52 60.05,37.61 60.11,37.69 60.29,37.89 60.26,38.16 60.26,38.26 60.35,38.31 61.03,38.31
DGND on TOP (solid shape): 54.9,39.65 54.9,39.64 55.17,39.18 55.52,39.58 55.54,39.67 55.62,39.71 56.46,39.71 57.07,39.1 57.1,39 57.03,38.93 57,38.92 56.79,38.92 56.05,38.81 56.51,38.22 56.6,38.2 56.63,38.12 56.63,38 56.57,37.91 56.46,37.93 56.26,38.12 55.46,38.12 55.37,38.18 55.38,38.28 55.24,38.78 54.78,38.54 54.78,38.53 54.7,38.45 54.63,38.45 54.56,38.49 54.53,38.57 54.47,38.79 54.27,38.92 54.26,38.92 54.17,39.01 54.15,39.11 54.23,39.18 54.42,39.26 54.52,39.44 54.53,39.46 54.78,39.71 54.9,39.71
DGND on TOP (solid shape): 36.39,88.87 36.56,88.82 36.74,88.87 36.95,88.87 37.21,88.61 37.22,88.61 37.28,88.56 37.28,88.54 37.31,88.43 37.38,88.33 37.4,88.26 37.38,88.19 37.29,88.03 37.29,87.85 37.27,87.76 37.19,87.72 37.01,87.72 36.5,87.44 37.01,87.16 37.29,87.16 37.31,87.13 37.34,87.08 37.38,87.03 37.4,86.96 37.38,86.89 37.28,86.67 37.34,86.43 37.35,86.32 37.26,86.27 36.91,86.27 36.71,86.06 36.68,86.06 36.66,86.04 36.5,86.04 36.49,86.05 36.34,86.09 36.19,86.06 36.18,86.06 36,86.06 35.79,86.27 35.63,86.27 35.54,86.32 35.55,86.43 35.61,86.64 35.55,86.85 35.54,86.95 35.63,87.01 35.78,87.01 36,87.23 36.02,87.23 36.23,87.68 35.76,87.84 35.66,87.84 35.61,87.93 35.59,88.07 35.51,88.19 35.48,88.26 35.51,88.33 35.58,88.43 35.61,88.54 35.61,88.56 35.93,88.87
DGND on TOP (solid shape): 40.02,145.28 41.85,145.28 41.85,143.53 42.01,143.53 42.01,143.24 42.16,143.1 42.16,143.1 42.02,142.96 40.9,142.96 38.79,140.85 37.32,140.85 37.22,140.94 37.3,141.05 36.49,146.65 35.68,141.05 35.75,140.94 35.65,140.85 32.72,140.85 32.62,140.91 32.64,141.03 32.71,141.09 32.71,141.15 32.75,141.23 32.84,141.25 33.26,141.56 32.84,141.88 32.75,141.9 32.71,141.98 32.71,144.67 34.86,146.82 38.48,146.82
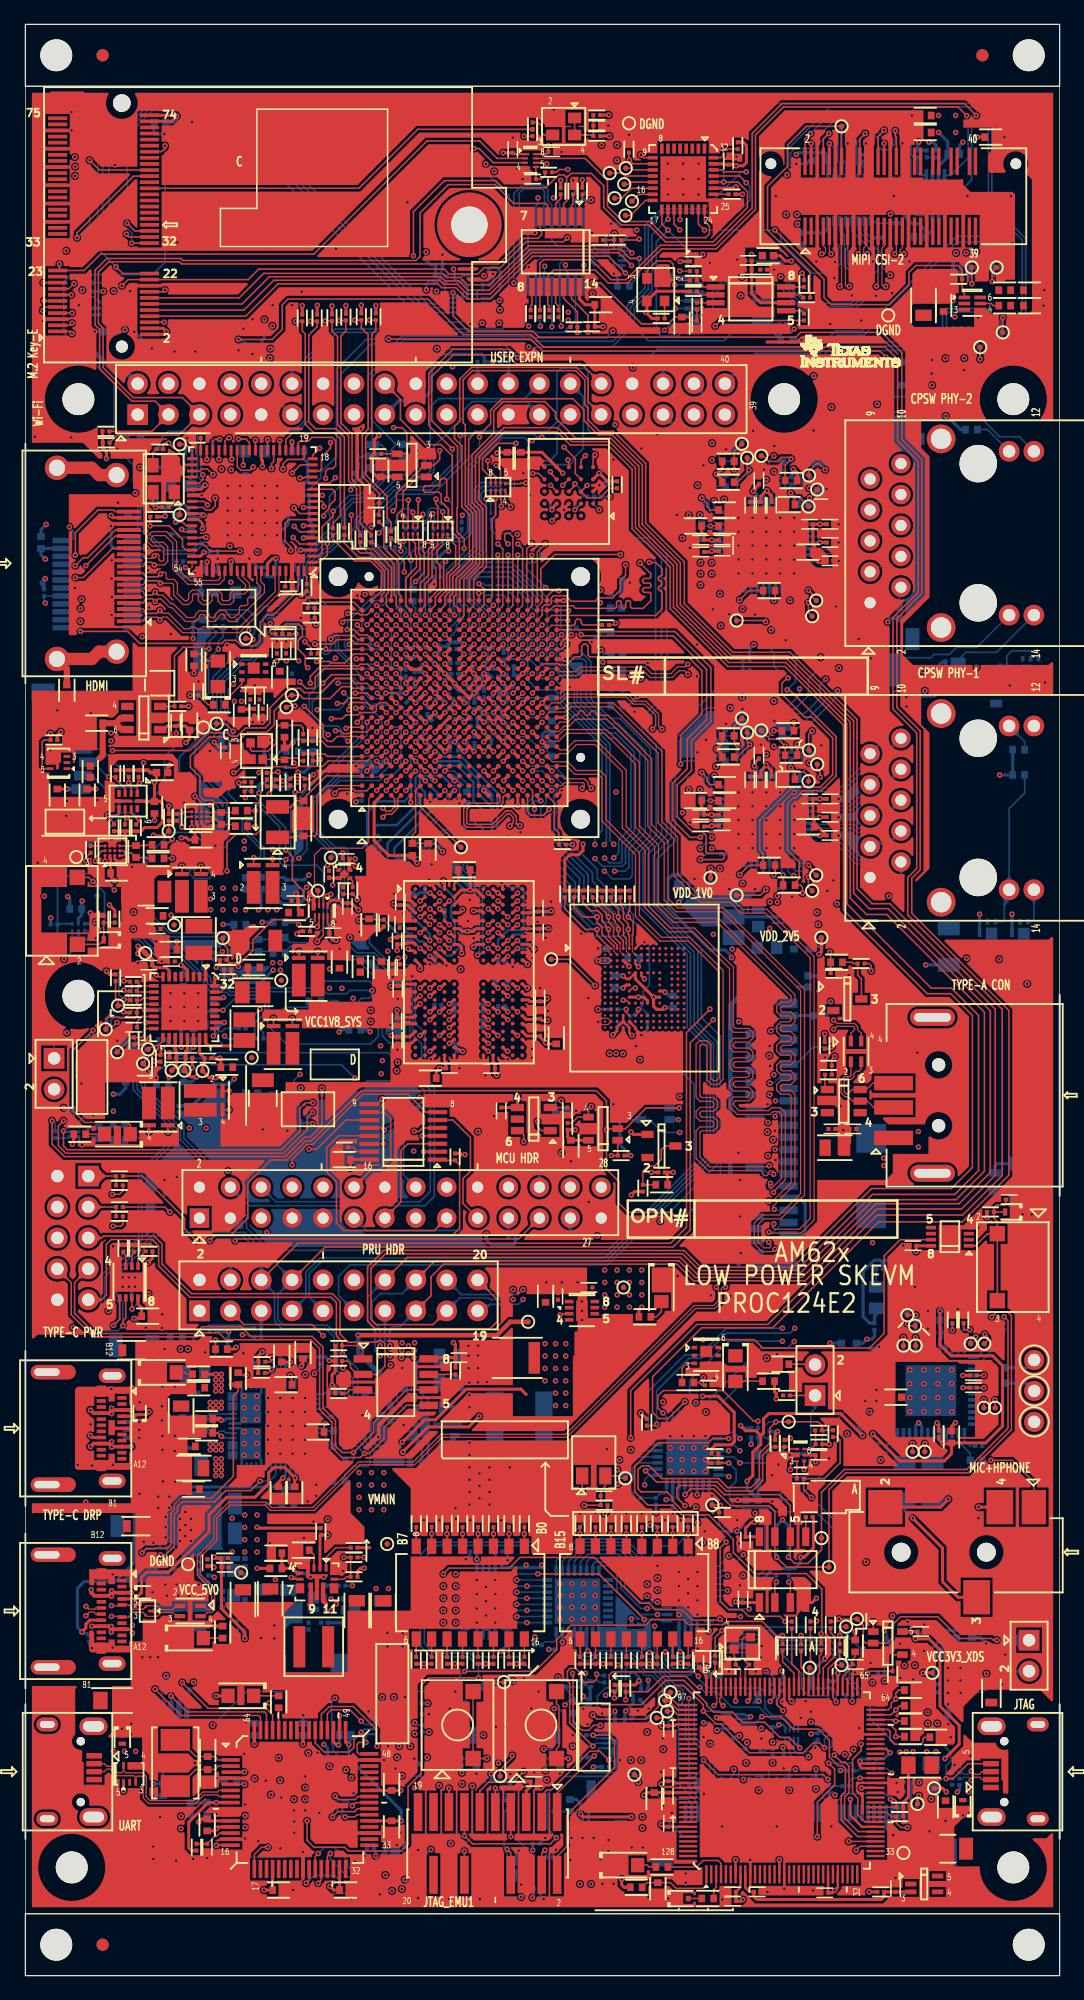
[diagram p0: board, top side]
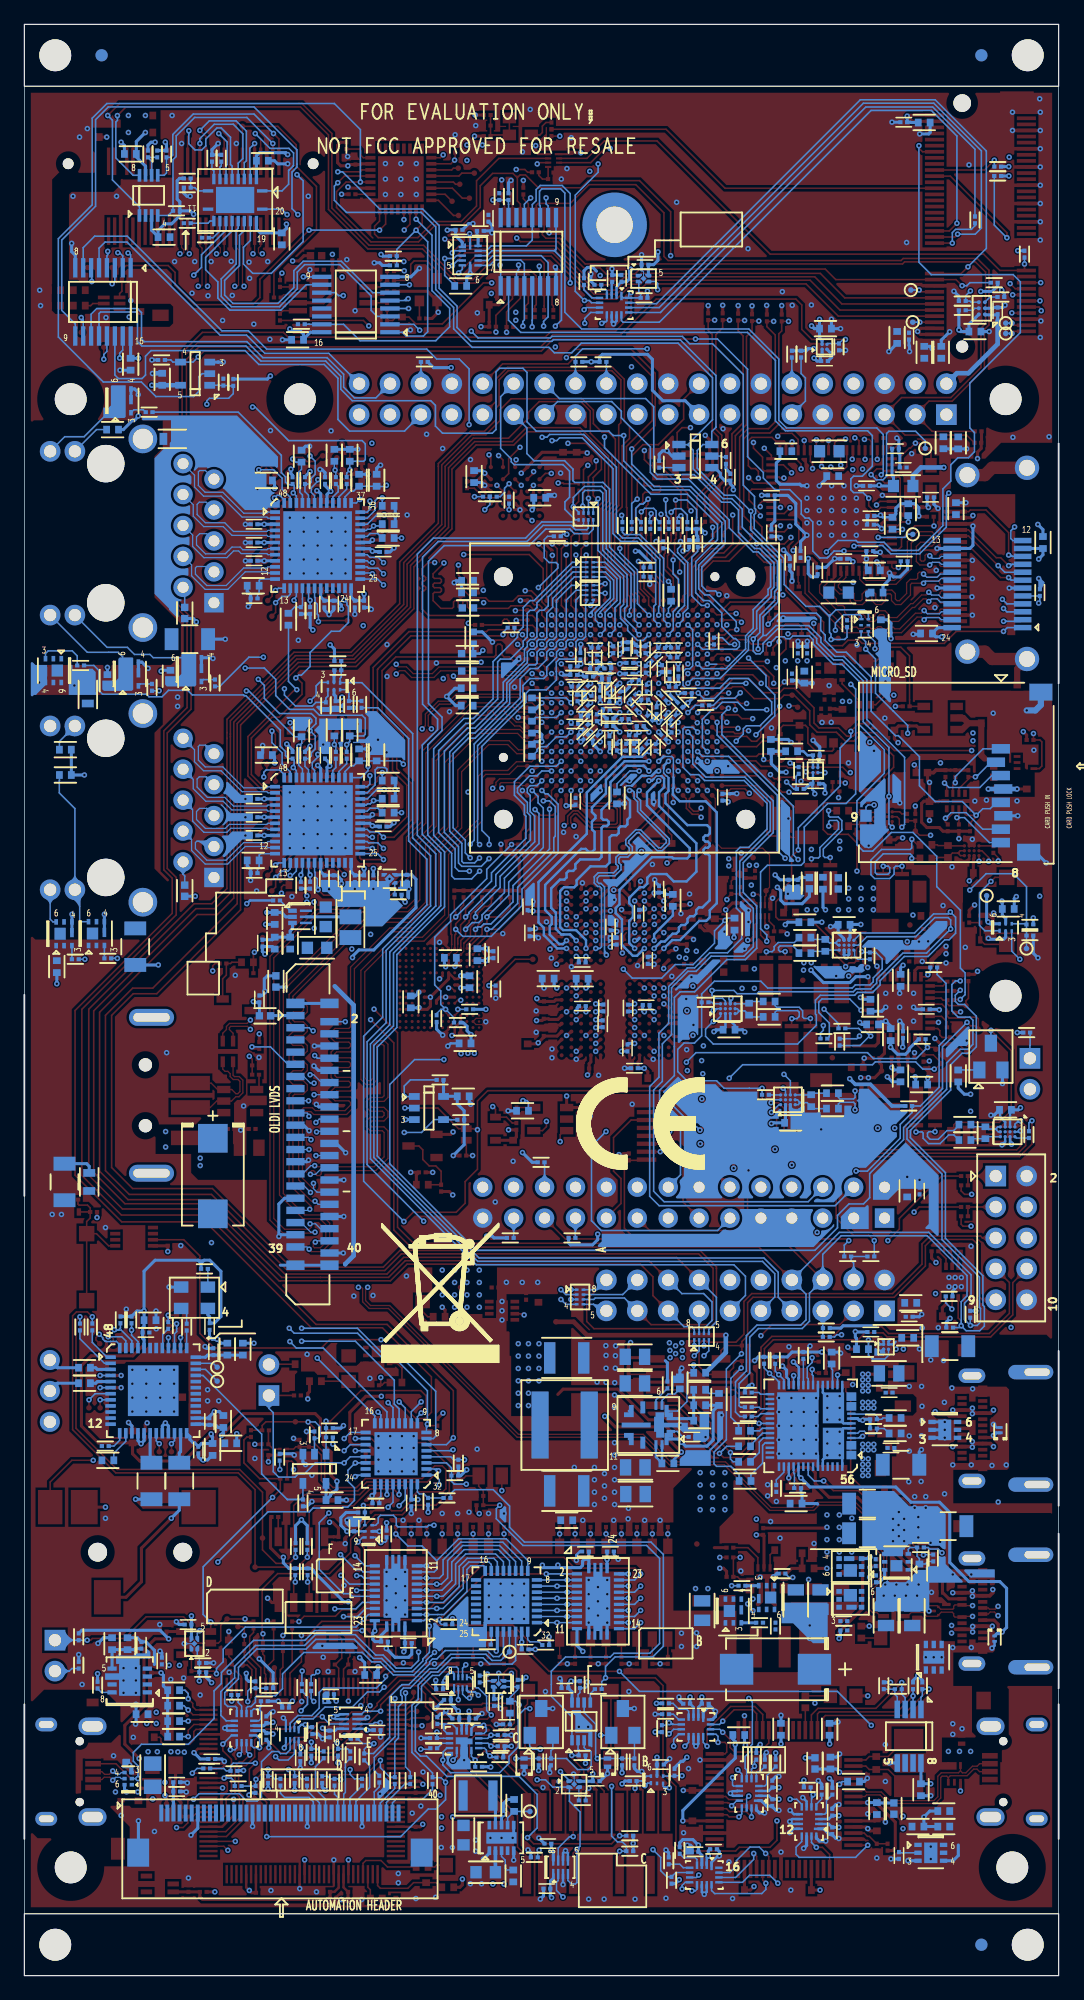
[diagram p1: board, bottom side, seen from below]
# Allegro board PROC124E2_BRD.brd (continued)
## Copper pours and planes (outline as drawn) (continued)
DGND on TOP (solid shape): 47.26,146.89 47.26,145.11 48.85,143.52 48.88,143.52 48.88,143.51 49.81,143.51 49.89,143.48 49.91,143.4 49.97,143.17 50.17,143.04 50.24,142.96 50.21,142.86 50.17,142.81 49.33,142.81 49.33,142.91 48.83,142.91 48.76,142.95 48.73,143.03 48.41,143.4 48.08,143.03 48.06,142.96 48,142.92 48,142.81 47.86,142.81 47.86,142.91 47.1,142.91 47.1,142.33 44.87,142.33 44.78,142.39 44.79,142.5 44.68,143 44.21,142.78 44.21,142.76 44.13,142.68 42.75,142.68 42.66,142.74 42.68,142.85 42.7,142.87 42.7,143.32 42.67,143.35 42.64,143.47 42.74,143.53 45.96,143.53 45.96,145.43 45.94,145.43 45.91,145.5 46.04,145.63 46.04,145.9 46.16,145.9 46.16,145.85 46.78,145.67 46.3,146.1 46.19,146.09 46.14,146.18 46.14,147.23 46.1,147.23 46.1,147.48 46.09,147.54 46.08,147.6 46.09,147.7 46.17,147.74 46.41,147.74
DGND on TOP (solid shape): 47.06,139.47 47.09,139.36 46.99,139.29 46.78,139.29 46.26,139.02 46.78,138.75 47.17,138.75 50.53,135.39 52.11,135.39 52.19,135.34 52.2,135.25 52.18,135.12 52.22,134.99 52.21,134.89 52.13,134.84 48.68,134.84 48.6,134.88 48.59,134.97 48.27,135.39 47.95,134.97 47.94,134.88 47.85,134.84 46.67,134.84 46.6,134.87 46.57,134.95 46.57,134.96 46.6,135.03 46.67,135.06 47.18,135.06 47.18,135.1 47.47,135.1 47.8,135.43 47.47,135.76 47.18,135.76 47.18,135.8 47.13,135.8 47.13,135.96 47.13,135.97 47.13,136.71 47.28,136.71 47.28,137.75 46.92,137.75 46.83,137.81 46.85,137.92 46.62,138.49 46.39,137.92 46.41,137.81 46.31,137.75 46.31,137.75 46.31,137.56 46.14,137.56 45.96,137.74 45.96,139.63 43.47,139.63 43.43,139.67 43.44,139.72 43.54,139.82 46.71,139.82
DGND on TOP (solid shape): outline of 82 points within 6.81,95.53 14.21,100.35
DGND on TOP (solid shape): 44.55,110.2 44.87,109.8 45.19,110.2 45.19,110.27 45.35,110.27 45.35,110.2 45.39,109.96 45.6,109.81 45.62,109.81 45.66,109.76 53.13,109.76 54.14,108.75 54.16,108.64 54.07,108.58 47.72,108.58 47.64,108.62 47.63,108.72 47.32,109.17 47.01,108.72 47,108.62 46.92,108.58 46.51,108.58 46.51,109.31 46.28,109.54 46.2,109.6 46.09,109.62 45.88,109.62 45.78,109.6 45.69,109.54 45.46,109.31 45.46,108.58 45.02,108.58 44.36,107.91 44.16,107.91 44.08,107.95 44.07,108.04 44.06,108.27 43.92,108.45 43.88,108.53 43.92,108.61 43.97,108.66 44.01,108.72 44.15,108.72 44.44,109 44.46,109 44.69,109.57 44.13,109.33 44.13,109.31 44,109.18 43.92,109.26 43.88,109.34 43.92,109.42 44.04,109.57 44.08,109.76 44.09,109.79 44.12,109.81 44.34,109.95 44.39,110.2 44.39,110.27 44.55,110.27
DGND on TOP (solid shape): 58.83,20.54 60.07,20.54 60.15,20.5 60.17,20.41 60.38,20.02 60.8,20.2 60.87,20.26 60.96,20.23 61.51,19.69 61.53,19.57 61.43,19.51 61.24,18.9 61.7,19.36 61.68,19.39 61.74,19.45 61.89,19.3 62.66,19.3 63.21,18.75 63.23,18.64 63.14,18.58 62.69,18.58 62.61,18.61 62.59,18.69 62.26,19.06 61.93,18.69 61.9,18.61 61.83,18.58 59.62,18.58 59.48,18.72 59.45,18.8 59.49,18.87 59.52,19.37 59.02,19.34 58.95,19.3 58.87,19.33 58.81,19.38 58.86,19.43 58.92,19.92 58.43,19.92 58.35,19.89 58.28,19.92 57.26,20.94 56.88,20.94 56.61,21.2 56.59,21.31 56.68,21.38 57.99,21.38
DGND on TOP (solid shape): 6.27,78.42 6.33,78.33 6.33,78.06 6.4,77.34 7.04,77.69 7.04,77.74 7.36,77.74 7.58,77.97 7.6,77.97 7.78,78.08 7.86,78.28 7.89,78.35 7.96,78.38 8.91,78.38 8.91,78.25 8.8,78.25 8.8,77.43 8.56,77.43 8.56,77.25 7.59,76.27 7.57,76.28 7.24,75.54 7.98,75.87 7.97,75.89 8.39,76.31 8.5,76.33 8.56,76.24 8.56,76.11 9.3,76.11 9.3,76.16 9.56,76.16 9.63,76.13 9.66,76.06 9.71,75.87 9.85,75.72 9.89,75.65 9.86,75.57 9.63,75.34 9.62,75.34 9.24,74.87 9.7,74.48 9.72,74.48 10.01,74.19 10.03,74.19 10.04,74.18 10.44,74.21 10.52,74.59 10.53,74.69 10.61,74.73 10.74,74.73 10.74,74.68 11.09,74.68 11.19,74.62 11.16,74.51 10.85,74.2 10.85,73.36 6.56,73.36 6.56,70.34 4.98,70.34 4.16,71.16 4.16,75.86 5.62,77.32 5.64,77.32 5.89,77.59 5.74,77.92 5.69,78.01 5.74,78.1 5.96,78.24 6.17,78.4
DGND on TOP (solid shape): outline of 226 points within 57.37,29.78 61.54,35.35
DGND on TOP (solid shape): outline of 109 points within 3.57,116.65 13.08,126.26
DGND on TOP (solid shape): outline of 83 points within 34.08,44.72 56.7,58.17
DGND on TOP (solid shape): 41.97,140.95 42.07,140.89 42.05,140.78 42.01,140.75 42.01,139.63 41.2,139.63 41.2,137.73 41.36,137.73 41.36,137.35 41.34,137.33 41.06,137.33 41.06,135.59 41.03,135.52 41.03,135.45 41,135.37 40.93,135.34 39.29,135.34 39.2,135.4 39.21,135.5 38.95,136.04 38.69,135.5 38.7,135.4 38.61,135.34 37.89,135.34 37.8,135.4 37.81,135.5 37.55,136.04 37.29,135.5 37.3,135.4 37.21,135.34 36.52,135.34 35.41,136.45 35.41,138.04 35.43,138.06 35.44,138.1 35.49,138.15 36.21,137.42 38.29,137.42 38.47,137.61 38.58,137.63 38.64,137.55 38.7,137.39 38.83,137.28 38.88,137.19 38.83,137.1 39.01,136.49 39.14,137.11 39.09,137.2 39.14,137.29 39.3,137.65 39.01,137.91 38.92,137.98 38.94,138.08 39.71,138.85 39.79,138.88 39.87,138.83 40.38,138.79 40.33,139.29 40.28,139.37 40.31,139.45 41.82,140.95
DGND on TOP (solid shape): outline of 288 points within 4.32,53.01 14.26,60.19
DGND on TOP (solid shape): outline of 280 points within 58.17,71.3 62.67,84.44
DGND on TOP (solid shape): outline of 89 points within 21.88,83.35 29.2,88
DGND on TOP (solid shape): outline of 292 points within 55.69,65.93 61.88,73.39
DGND on TOP (solid shape): outline of 302 points within 52.09,134.84 63,148.24
DGND on TOP (solid shape): outline of 87 points within 25.04,61.47 32.86,72.13
DGND on TOP (solid shape): outline of 362 points within 47.2,29.32 58.49,37.58
DGND on TOP (solid shape): outline of 103 points within 20.33,109.51 28.98,115.75
DGND on TOP (solid shape): outline of 157 points within 24.73,43.16 40.06,53.2
DGND on TOP (solid shape): outline of 369 points within 3.57,109.69 13.46,118.71
DGND on TOP (solid shape): outline of 398 points within 55.42,16.42 66.24,20.85
DGND on TOP (solid shape): outline of 829 points within 62.05,17.7 76.41,27.78
DGND on TOP (solid shape): outline of 830 points within 13.29,112.01 22.98,124.66
DGND on TOP (solid shape): outline of 888 points within 0.53,31.55 26.96,52.52
DGND on TOP (solid shape): outline of 1122 points within 32.48,60.42 54.06,72.41
DGND on TOP (solid shape): outline of 1139 points within 64.44,20.81 84.47,85.32
DGND on TOP (solid shape): outline of 1094 points within 30.14,34.62 63.82,56.8
DGND on TOP (solid shape): outline of 1239 points within 60.27,137.51 81.33,153.21
DGND on TOP (solid shape): outline of 1237 points within 38.18,112.89 51.83,125.44
DGND on TOP (solid shape): outline of 1305 points within 62.56,41.84 80.48,63.03
DGND on TOP (solid shape): outline of 1335 points within 53.75,58.46 77.56,98.34
DGND on TOP (solid shape): outline of 1405 points within 6.27,124.91 34.87,140.48
DGND on TOP (solid shape): outline of 1940 points within 43.88,87.84 66.07,115.63
DGND on TOP (solid shape): outline of 2129 points within 0.53,89.87 84.47,154.64
DGND on TOP (solid shape): outline of 2630 points within 0.53,52.32 21.96,109.49
DGND on TOP (solid shape): outline of 3858 points within 16.04,68.1 54.06,98.41
DGND on TOP (solid shape): outline of 4627 points within 28.74,87.36 73.11,137.42
DGND on TOP (solid shape): outline of 6519 points within 0.53,5.61 84.47,34.7
DGND on BOTTOM (solid shape): 63.79,92 58.58,92 58.58,92.03 58.01,92.03 58.01,97.78 63.79,97.78
DGND on BOTTOM (solid shape): 31.82,49.18 31.79,49.18 31.79,48.03 31.67,48.03 31.65,48.04 31.65,48.67 30.81,48.67 30.81,49.28 31.82,49.28
DGND on BOTTOM (solid shape): 76.95,17.76 76.95,17.04 76.38,17.04 76.38,16.54 76.11,16.54 76.11,17.31 76.31,17.51 76.31,17.81 76.9,17.81
DGND on BOTTOM (solid shape): 54.12,89.4 54.29,89.4 54.29,89.15 53.62,89.15 53.62,88.55 53.47,88.41 53.41,88.34 53.3,88.45 53.3,89.93 54.12,89.93
DGND on BOTTOM (solid shape): 7.67,33.37 7.76,33.31 7.74,33.2 7.24,32.7 5.25,32.7 5.25,33.33 5.29,33.37
DGND on BOTTOM (solid shape): 58.66,37.47 58.66,37.13 58.35,36.82 58.26,36.82 58.26,36.87 57.53,36.87 57.53,36.79 57.37,36.79 57.37,37.29 57.28,37.29 57.28,37.67 57.95,37.67 57.95,37.71 58.42,37.71
DGND on BOTTOM (solid shape): 15.62,63.18 15.68,63.27 15.79,63.25 15.93,63.11 17.12,63.11 17.9,62.33 17.9,61.31 15.62,61.31
DGND on BOTTOM (solid shape): 22.61,30.69 22.72,30.71 22.78,30.61 22.78,28.93 21.82,28.93 20.19,27.31 18.98,27.31 18.98,30.63 19.05,30.65 19.06,30.64 22.56,30.64
DGND on BOTTOM (solid shape): 81.36,105.18 79.14,105.18 79.04,105.24 79.07,105.36 79.14,105.43 79.14,107.08 79.39,107.33 79.71,107.33 79.71,107.23 81.04,107.23 81.04,107.65 81.36,107.65
DGND on BOTTOM (solid shape): 58.7,104.42 58.76,104.51 58.87,104.49 59.02,104.34 59.06,104.34 59.06,104.29 59.85,104.29 59.85,104.19 60.59,104.19 60.59,104.3 60.92,104.3 61.04,104.19 60.63,103.78 58.7,103.78
DGND on BOTTOM (solid shape): 13.5,98.66 13.61,98.68 13.68,98.59 13.68,97.04 13.61,96.85 13.67,96.66 13.67,96.31 12.93,96.31 12.93,98.09
DGND on BOTTOM (solid shape): 22.49,89.47 22.58,89.4 22.56,89.29 22.5,89.24 22.5,88.45 22.42,88.37 21.22,88.37 20.92,88.67 20.91,88.72 20.96,88.75 20.99,88.75 20.99,89.47
DGND on BOTTOM (solid shape): 7.32,77.87 7.35,77.95 7.44,77.97 7.47,77.97 9.28,76.16 9.28,75.52 9.21,75.43 9.1,75.45 8.2,76.35 7.56,76.35 7.32,76.6
DGND on BOTTOM (solid shape): 36.08,97.8 36.08,97.7 35.91,97.7 35.62,98 35.31,98 35.18,98.06 35.09,98.08 35.07,98.09 34.65,98.51 34.62,98.59 34.66,98.66 34.69,98.69 34.72,98.72 35.16,98.72
DGND on BOTTOM (solid shape): 84.29,107.84 84.4,107.86 84.47,107.77 84.47,105.18 84.4,105.08 84.29,105.1 84.22,105.18 84.05,105.18 83.13,106.1 83.13,107.65 84.1,107.65
DGND on BOTTOM (solid shape): 39.93,21.81 40.03,21.75 40.01,21.63 39.73,21.35 39.73,19.95 38.64,19.95 38.64,18.82 38.46,18.82 38.4,18.76 38.35,18.75 38.32,18.8 38.32,20.54 39.26,21.49 39.26,21.81
DGND on BOTTOM (solid shape): 55.28,16.25 55.39,16.27 55.46,16.17 55.46,15.48 55.56,15.48 55.56,15.41 55.98,14.98 55.98,14.57 55.92,14.47 55.81,14.5 54.92,15.38 54.92,16.03 55.07,16.03
DGND on BOTTOM (solid shape): 28.06,46.26 28.06,43.85 28.76,43.16 30.58,43.16 30.66,43.12 30.68,43.04 30.72,42.84 30.88,42.7 30.88,42.69 31.14,42.43 31.14,41.87 28.59,41.87 28.59,43.11 27.57,44.12 27.57,46.35 27.97,46.35
DGND on BOTTOM (solid shape): 15.26,65.76 15.26,63.71 14,63.71 13.1,64.62 10.68,64.62 10.68,61.73 10.92,61.49 10.94,61.38 10.85,61.31 10.57,61.31 10.03,60.78 9.92,60.76 9.86,60.85 9.86,65.72 12.58,68.44
DGND on BOTTOM (solid shape): 29.66,46.1 29.51,46.1 29.51,45.06 30.48,45.06 30.48,45.42 32.43,45.42 32.43,46.08 32.42,46.08 32.42,46.26 33.13,46.26 33.13,45.91 33.25,45.91 33.25,44.66 33.08,44.66 33.08,44.18 32.42,44.18 32.42,44.37 32.43,44.37 32.43,45.03 31.31,45.03 31.31,44.96 31.23,44.96 30.85,44.58 30.79,44.61 30.79,44.61 30.02,44.61 30.02,43.82 29.03,43.82 28.72,44.13 28.72,46.33 29.66,46.33
DGND on BOTTOM (solid shape): 74.84,26.78 74.95,26.8 75.01,26.71 75.01,26.48 75.8,26.48 75.84,26.44 76,26.44 76,26.29 77.04,26.29 77.04,26.44 77.27,26.44 77.27,26.29 77.46,26.29 77.46,25.6 77.21,25.6 77.21,24.84 78.37,24.84 78.37,24.3 77.21,24.3 77.21,23.07 75.53,23.07 75.53,26.05 74.64,26.05 74.64,26.58
DGND on BOTTOM (solid shape): 68.87,96.12 68.85,96.1 68.42,95.36 68.71,94.56 68.73,94.55 68.73,94.47 68.59,94.47 68.26,94.81 66.23,94.81 66.23,95.48 68.05,95.48 68.76,96.2 68.87,96.2
DGND on BOTTOM (solid shape): 23.16,111.32 23.18,111.21 23.09,111.15 20.45,111.15 20.43,111.18 20.2,111.38 19.91,111.3 19.85,111.3 19.82,111.34 19.82,111.43 20.02,111.63 22.85,111.63
DGND on BOTTOM (solid shape): 68.25,98.02 68.36,98.04 68.42,97.93 68.45,97.54 68.63,97.19 68.64,97.08 68.55,97.03 68.42,97.03 67.7,96.31 66.23,96.31 66.23,96.98 67.21,96.98
DGND on BOTTOM (solid shape): 16.14,35.23 16.24,35.13 16.26,35.02 16.16,34.96 14.39,34.96 14.39,34.44 12.79,34.44 12.79,34.99 12.62,34.99 12.62,35.13 12.32,35.44 12.02,35.44 12.02,35.54 10.69,35.54 10.69,35.44 10.62,35.44 10.49,35.3 9.78,35.3 9.53,35.06 9.47,35.04 9.43,35.02 9.33,35.03 9.28,35.11 9.28,37.91 9.93,38.55 12.28,38.55 13.52,39.8 16.14,39.8
DGND on BOTTOM (solid shape): 27.16,86.26 27.2,86.34 27.3,86.36 27.37,86.34 28.01,85.69 28.01,84.68 28.24,84.45 28.26,84.34 28.17,84.28 27.32,84.28 26.8,84.8 26.77,84.89 26.82,84.97 26.96,85.09 27.01,85.26 27.01,85.39 27.16,85.39
DGND on BOTTOM (solid shape): 68.25,93.64 68.66,93.64 68.76,93.58 68.73,93.47 68.41,92.76 68.69,92.04 68.71,91.93 68.62,91.87 68.52,91.87 67.08,93.31 66.23,93.31 66.23,93.98 67.92,93.98
DGND on BOTTOM (solid shape): 22.68,96.54 22.79,96.57 22.85,96.47 22.85,92.53 22.42,92.09 22.41,92.09 22.18,91.91 22.18,91.61 22.18,91.51 22.09,91.46 21.83,91.46 21.75,91.5 21.73,91.59 21.74,91.61 22.07,91.95 22.07,95.94
DGND on BOTTOM (solid shape): 56.92,103.74 56.97,103.74 57.01,103.71 57,103.66 56.71,103.37 56.71,101.84 57,101.55 57.73,101.55 57.73,101.33 57.99,101.33 57.99,101.23 56.97,101.23 56.97,101.08 56.79,101.08 56.46,100.75 56.79,100.42 56.97,100.42 56.97,100.04 56.57,100.04 56.57,100.25 55.52,100.25 55.52,100.04 54.02,100.04 53.8,99.82 53.74,99.81 53.69,99.81 53.69,101.49 56.05,103.86 56.92,103.86
DGND on BOTTOM (solid shape): 9.88,34.47 9.93,34.38 9.93,33.64 10.67,33.64 10.73,33.66 10.85,33.54 10.92,33.54 10.92,33.33 11.79,33.33 11.79,33.08 12.56,32.32 13.9,32.32 14.08,32.49 14.6,31.98 14.64,31.98 14.64,31.92 15.02,31.92 15.02,30.77 15.25,30.54 15.25,29.92 10.67,29.92 10.63,29.96 10.63,32.27 7.99,32.27 7.89,32.33 7.92,32.44 9.28,33.81 9.28,34.35 9.33,34.44 9.43,34.44 9.61,34.4 9.77,34.46
DGND on BOTTOM (solid shape): 29.69,82.21 30.35,82.21 31.54,81.02 31.54,80.99 31.48,80.9 31.37,80.92 31.22,81.07 30.48,81.07 30.4,81.11 30.38,81.19 30.2,81.56 29.8,81.46 29.72,81.42 29.65,81.45 27.81,83.28 27.79,83.39 27.88,83.46 28.44,83.46
DGND on BOTTOM (solid shape): 63.41,103.39 63.46,103.36 63.45,103.3 63.39,103.24 63.36,103.24 63.36,103.21 63.3,103.21 63.29,103.21 62.85,103.03 63.05,102.59 63.11,102.52 63.08,102.43 62.83,102.17 62.77,102.16 62.74,102.21 62.74,102.23 61.85,102.23 61.85,102.28 61.83,102.35 61.8,102.42 61.79,102.45 61.31,102.93 61.31,103.16 61.53,103.39
DGND on BOTTOM (solid shape): 14.21,98.23 14.28,98.33 14.39,98.3 16.31,96.38 16.31,95.96 16.1,95.96 16.1,96.09 15.77,96.41 15.36,96.41 14.86,96.27 15.12,95.82 15.16,95.81 15.16,94.56 16.31,94.56 16.31,92.99 15.94,92.63 15.39,92.63 13.92,94.1 13.99,94.21 14.15,94.21 14.15,94.41 14.21,94.48 14.21,96.66 14.28,96.85 14.21,97.04
DGND on BOTTOM (solid shape): 55.31,89.9 58.61,89.9 58.61,89.7 58.94,89.37 59.27,89.7 59.27,89.86 59.39,89.99 60.66,89.99 60.66,89.46 60.55,89.31 60.54,89.11 60.52,89.03 60.44,88.99 60.1,88.99 59.54,88.43 59.52,88.43 59.52,88.41 59.43,88.32 59.43,87.29 59.3,87.29 59.3,87.77 57.09,87.77 57.09,86.17 56.57,86.17 56.57,86.17 55.58,86.17 53.87,87.88 53.94,87.94 54.33,88.33 54.33,88.41 54.94,88.41 54.94,89.15 54.82,89.15 54.82,89.4 54.99,89.4 54.99,89.78 54.77,90 54.99,90.22
DGND on BOTTOM (solid shape): 49.55,19 49.15,19 49.15,17.98 49.19,17.98 49.19,17.9 49.45,17.65 49.45,17.63 50.01,17.47 49.84,18.02 49.82,18.03 49.76,18.09 49.76,18.38 50.2,18.38 50.32,18.26 50.32,17.86 50.31,17.84 50.28,17.68 50.33,17.52 50.34,17.51 50.34,17.42 49.87,16.94 48.33,16.94 48.33,17.52 48.25,17.52 48.25,17.58 48.27,17.65 48.53,17.9 48.53,17.98 48.56,17.98 48.56,19 48.17,19 48.17,19.48 48.56,19.48 48.56,19.58 49.55,19.58
DGND on BOTTOM (solid shape): 11.63,85.06 12.01,85.06 12.08,85.03 12.11,84.95 12.44,84.6 12.77,84.95 12.8,85.03 12.87,85.06 15.65,85.06 16.12,84.59 16.14,84.49 16.08,84.42 16.02,84.39 15.97,84.36 15.91,84.35 15.88,84.4 15.88,84.42 15.15,84.42 15.15,84.3 14.91,84.3 14.23,83.63 14.23,83.17 14.17,83.08 14.06,83.1 12.91,84.25 10.97,84.25 9.2,86.02 9.18,86.1 9.14,86.15 9.14,86.59 9.18,86.62 10.07,86.62
DGND on BOTTOM (solid shape): 60.77,102.71 61.19,102.29 60.83,101.94 60.83,100.63 60.8,100.62 60.64,100.53 60.56,100.37 60.55,100.33 59.92,100.33 59.92,100.05 59.85,99.98 59.8,99.97 59.77,100.02 59.77,100.88 59.85,101.03 59.84,101.2 59.86,101.29 59.94,101.33 60.05,101.33 60.05,102.3 59,102.3 59,101.33 59.11,101.33 59.19,101.29 59.21,101.2 59.2,101.16 59.13,101.09 59.13,100.89 59.03,100.89 59.03,99.57 59.13,99.57 59.13,99.41 59.1,99.36 59.04,99.37 58.87,99.55 58.88,99.57 58.88,100.9 58.83,100.95 58.83,101.02 58.83,101.17 58.78,101.3 58.78,102.3 57.73,102.3 57.73,102.09 57.25,102.09 57.25,103.14 57.35,103.24 60.77,103.24
DGND on BOTTOM (solid shape): 29.62,100.11 29.73,100.13 29.8,100.04 29.8,99.62 28.88,98.7 28.48,98.7 28.4,98.74 28.39,98.84 28.07,99.27 27.76,98.84 27.74,98.74 27.66,98.7 26.31,98.7 26.21,98.77 26.23,98.88 27.23,99.87 28.44,99.87 28.51,99.84 28.54,99.76 28.87,99.4 29.2,99.76 29.23,99.84 29.3,99.87 29.39,99.87
DGND on BOTTOM (solid shape): 47.26,28.64 48.5,28.64 48.5,31.05 48.56,31.14 48.67,31.12 50.41,29.39 50.44,29.39 50.51,29.35 50.54,29.28 50.54,29.22 50.14,29.22 50.14,29.31 49.81,29.64 49.48,29.31 49.48,29.22 49.45,29.22 49.45,28.48 50.77,28.48 50.77,28.58 50.83,28.58 51.14,28.88 51.14,28.99 51.32,28.99 51.4,28.94 51.41,28.84 51.38,28.68 51.44,28.52 51.44,26.98 51.41,26.9 51.33,26.87 51.13,26.84 50.99,26.69 50.92,26.63 50.83,26.66 50.52,26.96 47.06,26.96 47.06,27.56 46.98,27.56 46.98,28.87 43.5,28.87 43.5,32.62 47.26,32.62
DGND on BOTTOM (solid shape): 15.15,110.49 15.28,110.49 15.28,110.12 14.83,109.67 14.83,109.17 14.78,108.88 14.99,108.66 15.06,108.59 15.03,108.5 14.86,108.33 14.8,108.24 14.78,108.14 14.78,105.44 13.95,104.6 13.84,104.58 13.78,104.67 13.78,104.93 13.88,105.16 13.78,105.4 13.78,106.56 13.81,106.63 13.87,106.67 14.19,107 13.87,107.33 13.81,107.36 13.78,107.43 13.78,109.48 13.82,109.49 14.03,109.6 14.11,109.81 14.11,110.13 14.11,110.14 14.11,110.6 15.04,110.6
DGND on BOTTOM (solid shape): outline of 102 points within 29.61,76.6 31.31,80.58
DGND on BOTTOM (solid shape): 16.3,83.07 16.48,82.89 16.56,82.82 16.65,82.85 16.71,82.91 17.17,82.91 17.18,82.87 17.51,82.54 17.84,82.87 17.84,82.91 19.94,82.91 19.97,82.92 20,82.94 20.06,82.96 20.12,82.94 20.14,82.92 20.16,82.88 20.15,82.84 20.12,82.82 19.19,81.89 17.68,81.89 17.6,81.93 17.58,82.02 17.41,82.39 17.01,82.31 16.94,82.28 16.86,82.31 16.8,82.37 16.12,82.37 16.11,82.4 16.09,82.43 16.05,82.45 15.98,82.5 15.92,82.56 16.02,82.76 15.97,82.97 15.97,83.02 16.01,83.05 16.03,83.06
DGND on BOTTOM (solid shape): outline of 118 points within 33.28,87.76 37.45,93.58
DGND on BOTTOM (solid shape): 26.11,62.97 26.2,62.91 26.19,62.8 26.22,61.6 27.38,61.29 27.49,61.28 27.59,61.26 27.91,60.93 37.55,60.93 37.55,60.31 37.84,60.01 37.86,59.9 37.77,59.84 20.14,59.84 18.44,61.54 18.44,61.71 18.52,61.71 18.53,61.69 18.91,61.33 19.42,61.21 19.5,61.18 19.52,61.1 19.97,60.74 20.05,61.3 20.01,61.38 20.05,61.46 20.38,62.1 20.2,62.8 20.19,62.91 20.28,62.97
DGND on BOTTOM (solid shape): outline of 92 points within 64,111.55 75.32,128.14
DGND on BOTTOM (solid shape): outline of 919 points within 12.4,63.5 32.52,73.85
DGND on L03_SIG1 (solid shape): 21.39,104.86 21.49,104.79 21.47,104.68 19.42,102.64 18.46,102.64 18.45,102.63 18.38,102.65 18.38,102.91 18.58,103.1 19.6,103.1 21.35,104.86
DGND on L03_SIG1 (solid shape): 24.65,102.61 24.12,102.08 23.03,102.08 21.94,100.99 21.5,100.99 21.4,101.06 21.43,101.17 22.55,102.29 23.15,102.29 23.59,102.72 24.54,102.72
DGND on L03_SIG1 (solid shape): 12,81.07 12.11,81.09 12.17,80.99 12.17,75.5 11.88,75.21 11.77,75.19 11.71,75.28 11.71,80.77
DGND on L03_SIG1 (solid shape): 14.91,112.57 15.01,112.51 14.99,112.4 11.87,109.29 11.76,109.26 11.7,109.36 11.7,110.09 14.19,112.57
DGND on L03_SIG1 (solid shape): 53.73,44.71 53.79,44.8 53.9,44.78 54.1,44.58 54.1,41.04 54.01,40.96 53.96,40.95 53.93,41 53.93,41.03 53.73,41.23
DGND on L03_SIG1 (solid shape): 10.15,56.52 10.17,56.41 10.09,56.34 9.91,56.27 9.81,56.12 9.79,56.09 7.85,56.09 7.39,56.55 7.39,58.43 7.81,58.85
DGND on L03_SIG1 (solid shape): 43.03,113.33 43.14,113.35 43.2,113.26 43.2,112.68 41.77,111.25 41.71,111.26 41.67,111.27 41.6,111.3 41.57,111.37 41.57,111.87
DGND on L03_SIG1 (solid shape): 47.03,102.92 47.05,102.81 46.96,102.75 42.9,102.75 42.82,102.79 42.8,102.87 42.8,102.91 42.85,102.96 43.6,102.96 44.08,103.45 46.5,103.45
DGND on L03_SIG1 (solid shape): 67.96,110.78 68.03,110.88 68.14,110.85 68.78,110.21 68.78,108.69 68.48,108.39 68.48,105.78 68.14,105.43 68.03,105.41 67.96,105.5
DGND on L03_SIG1 (solid shape): 69.52,109.94 69.59,110.03 69.7,110.01 69.79,109.92 69.79,106.37 69.39,105.98 69.28,105.95 69.22,106.05 69.22,108.08 69.52,108.39
DGND on L03_SIG1 (solid shape): 17.2,14.84 17.23,14.89 17.28,14.88 17.92,14.24 19.17,14.24 20.5,12.91 22.73,12.91 22.81,12.87 22.83,12.78 22.82,12.74 22.61,12.53 19.79,12.53 18.49,13.83 18.11,13.83 17.2,14.74
DGND on L03_SIG1 (solid shape): 59.61,98.96 59.66,99.05 59.75,99.05 59.8,99.03 59.86,99.02 59.9,99.01 59.9,90.66 59.84,90.57 59.73,90.59 59.63,90.69 59.63,94.84 59.61,94.86
DGND on L03_SIG1 (solid shape): 13.12,81.86 13.23,81.88 13.29,81.79 13.29,76.65 13.16,76.52 13.1,76.49 13.03,76.51 12.92,76.57 12.8,76.59 12.72,76.62 12.69,76.69 12.69,81.43
DGND on L03_SIG1 (solid shape): 18.79,50.69 18.79,50.32 18.73,50.22 18.62,50.25 18.44,50.42 18.29,50.42 17.52,51.2 17.49,51.28 17.53,51.35 17.64,51.51 17.64,51.7 17.64,51.7 17.64,51.76 17.72,51.76
DGND on L03_SIG1 (solid shape): 20.52,49.51 20.57,49.42 20.57,48.41 21.07,47.9 21.07,41.7 20.97,41.6 20.86,41.57 20.8,41.67 20.8,47.88 19.94,48.73 19.94,49.41 19.99,49.5 20.09,49.5 20.26,49.46 20.42,49.51
DGND on L03_SIG1 (solid shape): 48.08,111.22 48.16,111.19 48.19,111.11 48.25,110.87 48.46,110.75 48.48,110.74 48.53,110.69 48.56,110.58 48.46,110.52 47.85,110.52 46.17,108.84 45.62,108.84 45.53,108.9 45.55,109.02 47.76,111.22
DGND on L03_SIG1 (solid shape): 45.99,70.81 46.01,70.7 45.91,70.64 45.01,70.64 44.21,71.44 44.18,71.52 44.22,71.6 44.35,71.94 44.08,72.19 44.06,72.19 43.17,73.09 43.15,73.2 43.24,73.26 43.54,73.26
DGND on L03_SIG1 (solid shape): 70.22,114.58 70.28,114.49 70.28,112.4 69.69,111.82 69.69,110.99 69.63,110.89 69.52,110.91 68.56,111.88 68.56,114.49 68.62,114.58 68.73,114.56 69.42,114.29 70.11,114.56
DGND on L03_SIG1 (solid shape): 10.81,74.12 10.92,74.14 10.98,74.04 10.98,68.62 10.19,67.83 10.08,67.81 10.02,67.9 10.02,68.88 10.05,68.96 10.13,68.98 10.49,69.31 10.13,69.64 10.05,69.67 10.02,69.74 10.02,73.32
DGND on L03_SIG1 (solid shape): 20.02,24.59 20.08,24.68 20.19,24.66 25.92,18.93 25.92,18.39 25.89,18.34 25.84,18.35 25.81,18.38 24.95,18.38 24.74,18.59 24.71,18.66 24.74,18.74 24.76,19.22 24.28,19.2 24.2,19.17 24.13,19.2 20.02,23.31
DGND on L03_SIG1 (solid shape): 23.31,104.21 23.4,104.19 23.66,103.93 23.67,103.82 23.27,103.82 22.71,103.26 22.16,103.26 19.94,101.04 19.56,101.04 17.52,99.01 17.45,98.98 17.37,99.02 17.16,99.13 16.92,99.07 16.81,99.06 16.76,99.15 16.76,99.88 18.78,101.9 19.74,101.9 21.4,103.56 22.6,103.56 22.96,103.92 22.97,103.92 23.13,104 23.23,104.15
DGND on L03_SIG1 (solid shape): 28.95,68.34 29.05,68.36 29.12,68.28 29.21,68.09 29.4,68 29.42,67.99 30.51,66.9 30.51,62.91 30.44,62.81 30.33,62.84 29.62,63.22 28.86,62.95 28.75,62.93 28.69,63.02 28.69,68.08
DGND on L03_SIG1 (solid shape): 30.14,98.1 30.14,98.08 30.22,97.92 30.37,97.82 30.38,97.82 30.71,97.49 30.77,97.49 30.86,97.43 30.84,97.32 30.71,97.18 30.13,97.18 29.91,96.96 29.86,96.91 29.78,97 29.82,97.04 29.82,97.04 30,97.36 29.77,97.65 29.76,97.65 29.66,97.76 29.71,97.81 29.72,97.81 29.88,97.88 29.98,98.03 29.99,98.04 30.09,98.15
DGND on L03_SIG1 (solid shape): 20.98,53.81 21.05,53.9 21.16,53.88 21.91,53.54 22.67,53.85 22.78,53.87 22.84,53.77 22.84,51.14 22.25,50.54 22.16,50.51 22.09,50.56 21.93,50.71 21.72,50.73 21.63,50.74 21.59,50.82 21.59,52.31 20.98,52.92
DGND on L03_SIG1 (solid shape): 50.48,23.12 50.57,23.06 50.55,22.95 50.54,22.93 50.54,20.45 50.35,20.27 50.35,17.91 50.29,17.64 50.45,17.41 50.51,17.34 50.48,17.25 50.44,17.21 49.83,17.21 49.67,17.05 49.56,17.03 49.5,17.12 49.5,17.3 49.54,17.39 49.64,17.4 50.04,17.5 50.03,17.91 50.03,23.12
DGND on L03_SIG1 (solid shape): 66.03,80.44 66.06,80.36 66.01,80.28 65.95,79.77 66.46,79.83 66.54,79.88 66.62,79.85 66.75,79.73 66.75,78.85 66.7,78.76 66.59,78.76 66.27,78.77 66.09,78.51 66.07,78.48 65.43,78.48 62.91,81 62.89,81.11 62.99,81.18 65.3,81.18
DGND on L03_SIG1 (solid shape): 42.84,107.08 42.92,107.05 42.94,106.97 42.98,106.77 43.13,106.64 43.14,106.63 43.17,106.6 43.19,106.51 43.14,106.44 42.98,106.29 42.95,106.07 42.92,105.99 42.85,105.95 42.43,105.95 42.1,106.28 41.49,106.28 41.44,106.31 41.45,106.37 41.49,106.41 41.49,106.51 41.53,106.59 41.61,106.61 41.9,106.69 42,106.97 42.02,107.05 42.1,107.08
DGND on L03_SIG1 (solid shape): 12.46,90.91 12.54,90.94 12.61,90.91 12.65,90.87 12.69,90.84 12.73,90.77 12.7,90.69 12.21,90.2 12.21,87.51 12.17,87.43 12.08,87.42 11.64,87.11 12.08,86.79 12.17,86.78 12.21,86.7 12.21,85.91 11.66,85.35 11.66,84.23 11.48,84.05 11.48,82.66 11.19,82.37 11.11,82.34 11.03,82.38 10.88,82.51 10.69,82.53 10.61,82.55 10.57,82.63 10.57,89.02
DGND on L03_SIG1 (solid shape): 32.3,87.32 32.42,87.28 32.54,87.3 32.55,87.3 32.61,87.3 32.61,87.23 32.92,86.92 32.92,86.91 32.95,86.81 33.01,86.73 33.04,86.66 33,86.59 33.04,86.06 33.53,86.23 33.54,86.24 33.56,86.26 33.65,86.29 33.73,86.22 33.76,86.14 33.83,86.06 33.86,85.99 33.83,85.91 33.78,85.86 33.75,85.81 33.73,85.78 32.75,85.78 32.74,85.81 32.55,85.98 32.3,85.96 32.28,85.95 32.07,85.95 31.98,86.02 32,86.13 32.21,86.33 32.21,87.32 32.28,87.32
DGND on L03_SIG1 (solid shape): outline of 102 points within 19.22,18.12 24.34,31.34
DGND on L03_SIG1 (solid shape): 62.71,87.65 62.77,87.75 62.88,87.72 66.06,84.54 66.09,84.44 66.02,84.37 65.86,83.81 66.41,83.97 66.48,84.05 66.58,84.02 68.96,81.65 68.96,80.9 68.9,80.81 68.78,80.83 65.99,83.62 65.62,83.62 65.54,83.67 65.53,83.76 65.37,84.2 64.93,84.04 64.86,83.99 64.77,84.01 62.71,86.07
DGND on L03_SIG1 (solid shape): 29.4,46.92 29.47,47.01 29.58,46.99 31.27,45.29 31.27,44.2 31.23,44.11 31.13,44.11 30.65,43.81 31.13,43.51 31.23,43.51 31.27,43.42 31.27,43.4 31.23,43.31 31.13,43.3 30.68,43 31.13,42.69 31.23,42.68 31.27,42.6 31.27,42.37 30.55,41.64 30.44,41.62 30.37,41.71 30.37,45.85 29.4,46.82
DGND on L03_SIG1 (solid shape): 44.86,112.69 44.87,112.63 44.82,112.6 44.79,112.6 44.62,112.44 44.6,112.43 44.41,111.88 44.97,112.05 44.98,112.09 45.39,112.09 45.48,112.02 45.46,111.91 45.01,111.47 44.93,111.44 44.86,111.48 44.48,111.62 44.25,111.3 44.22,111.23 44.15,111.2 42.88,111.2 42.85,111.17 42.78,111.14 42.7,111.17 42.67,111.19 42.64,111.22 42.6,111.29 42.62,111.37 43.72,112.47 43.72,113.31 43.75,113.38 43.82,113.41 43.93,113.42 44.02,113.47 44.06,113.49
DGND on L03_SIG1 (solid shape): 22.2,91.13 22.31,91.15 22.38,91.06 22.38,88.41 24.15,86.63 24.15,86.57 24.12,86.49 24.04,86.47 23.79,86.41 23.66,86.19 23.66,86.17 22.95,85.47 22.95,83.55 22.89,83.45 22.78,83.48 22.6,83.65 22.57,83.74 22.62,83.81 22.77,84.26 22.33,84.41 22.23,84.41 22.18,84.5 22.18,85.12 22.22,85.2 22.29,85.23 22.64,85.56 22.29,85.89 22.22,85.91 22.18,85.99 22.18,88.74 21.97,88.95 21.97,90.9
DGND on L03_SIG1 (solid shape): 27.58,88.19 27.66,88.16 30.3,85.52 30.32,85.4 30.23,85.34 29.68,85.34 28.96,84.62 28.96,84.3 28.9,84.21 28.79,84.23 27.12,85.9 27.12,86.28 27.17,86.36 27.27,86.37 27.75,86.66 27.27,86.96 27.17,86.96 27.12,87.05 27.12,87.13 27.16,87.21 27.26,87.22 27.69,87.57 27.2,87.82 27.15,87.82 27.12,87.87 27.12,87.94 27.16,88.02 27.23,88.05 27.38,88.07 27.51,88.15
DGND on L03_SIG1 (solid shape): 33.85,53.66 33.9,53.75 34.01,53.74 34.2,53.63 34.42,53.56 34.5,53.49 34.47,53.39 32.38,51.3 32.38,41.34 31.06,40.01 30.94,39.99 30.88,40.08 30.88,40.93 32.12,42.17 32.12,45.78 30.65,47.25 30.65,50.36 30.69,50.44 30.79,50.45 31.07,50.47 31.24,50.7 31.29,50.77 31.37,50.78 31.44,50.76 31.5,50.76 31.57,50.74 31.61,50.68 32.08,50.47 32.18,50.98 32.15,51.05 32.18,51.12 32.28,51.34 32.19,51.57 32.16,51.65 32.2,51.72 32.31,51.92 32.27,52.15 32.27,52.25 32.36,52.3 33.01,52.3 33.85,53.14
DGND on L03_SIG1 (solid shape): outline of 153 points within 12.26,97.93 14.91,104.99
DGND on L03_SIG1 (solid shape): 16.44,65.82 16.49,65.78 16.51,65.74 16.48,65.69 16,64.22 17.53,64.02 17.64,64.04 17.7,63.95 17.7,61.19 17.21,60.7 17.19,60.7 16.98,60.57 16.91,60.34 16.89,60.26 16.81,60.23 15.66,60.23 15.48,60.4 15.48,60.42 15.17,60.7 14.83,60.46 14.83,60.45 14.78,60.4 14.69,60.49 14.69,60.67 14.32,61.04 14.3,61.15 14.38,61.22 15.2,62.67 13.55,62.88 13.44,62.85 13.37,62.94 13.37,65.36 13.83,65.82
DGND on L03_SIG1 (solid shape): outline of 170 points within 39.07,66.72 52.33,72.81
DGND on L03_SIG1 (solid shape): 32.44,109.47 32.51,109.44 32.54,109.36 32.87,109 33.2,109.36 33.23,109.44 33.3,109.47 33.76,109.47 34.28,108.95 34.31,108.87 34.27,108.8 34.16,108.66 34.14,108.48 34.15,108.42 34,108.42 34,108.48 33.67,108.87 33.34,108.48 33.35,108.42 33.2,108.42 33.2,108.48 32.87,108.87 32.54,108.48 32.55,108.42 32.4,108.42 32.4,108.48 32.09,108.86 31.74,108.52 31.71,108.45 31.64,108.42 31.09,108.42 31.09,108.79 31.08,108.8 31.08,108.91 31.11,108.99 31.2,109.01 31.49,109.09 31.6,109.36 31.63,109.44 31.7,109.47
DGND on L03_SIG1 (solid shape): outline of 161 points within 8.73,81.66 9.71,90.1
DGND on L03_SIG1 (solid shape): 61.14,101.29 61.23,101.24 61.23,101.14 61.52,100.64 61.81,101.14 61.81,101.24 61.89,101.29 62.08,101.29 62.17,101.24 62.16,101.13 62.16,100.79 62.48,100.63 62.55,100.6 62.59,100.53 62.59,100.26 60.59,98.26 60.48,98.24 60.41,98.33 60.41,98.95 60.61,99.15 60.64,99.16 60.68,99.15 61.2,99.27 60.91,99.73 60.82,99.79 60.84,99.9 60.92,99.98 60.93,99.98 61.12,100.54 60.56,100.36 60.56,100.34 60.13,99.91 60.13,99.76 60.09,99.68 60,99.66 59.87,99.68 59.75,99.64 59.66,99.65 59.61,99.73 59.61,99.78 60.31,100.49 60.31,101.16 60.44,101.29
DGND on L03_SIG1 (solid shape): 24.07,94.08 24.14,94.18 24.26,94.13 25.69,93.3 27.14,94.1 27.25,94.14 27.33,94.04 27.33,92.14 27.29,92.06 27.2,92.05 26.83,91.9 26.87,91.5 26.89,91.44 26.87,91.37 26.83,90.97 27.2,90.83 27.29,90.81 27.33,90.73 27.33,88.81 27.3,88.74 27.23,88.7 27.16,88.69 25.05,90.8 25.02,90.87 25.06,90.95 25.06,90.95 25.13,90.98 25.2,90.95 25.75,91.19 25.2,91.44 25.13,91.41 25.06,91.44 24.82,91.52 24.59,91.41 24.52,91.38 24.44,91.41 24.07,91.78
DGND on L03_SIG1 (solid shape): outline of 182 points within 55.11,97.53 58.45,102.95
DGND on L03_SIG1 (solid shape): outline of 188 points within 10.75,93.8 14.38,105.64
DGND on L03_SIG1 (solid shape): 66.63,102.03 66.74,102.05 66.8,101.95 66.8,97.87 66.09,97.16 66.09,90.54 67.01,89.62 67.01,88.43 66.96,88.34 66.87,88.34 66.61,88.35 66.42,88.18 66.35,88.13 66.26,88.16 65.49,88.92 65.49,92.58 65.14,92.93 65.14,93.21 65.17,93.29 65.25,93.31 65.62,93.64 65.25,93.97 65.17,94 65.14,94.07 65.14,94.71 65.17,94.79 65.25,94.81 65.62,95.14 65.25,95.47 65.17,95.5 65.14,95.57 65.14,96.21 65.17,96.29 65.25,96.31 65.62,96.64 65.25,96.97 65.17,97 65.14,97.07 65.14,98.02 65.18,98.09 65.26,98.12 65.65,98.44 65.26,98.77 65.18,98.79 65.14,98.87 65.14,99.32 66.18,100.36 66.18,101.58
DGND on L03_SIG1 (solid shape): outline of 196 points within 55.81,43.98 65.37,49.64
DGND on L03_SIG1 (solid shape): outline of 192 points within 41.7,16.24 51.5,26.37
DGND on L03_SIG1 (solid shape): 27.66,46.37 27.77,46.39 27.83,46.3 27.83,43.22 27.79,43.21 27.56,42.78 28,42.58 28.1,42.58 28.14,42.49 28.14,42.19 27.64,41.69 27.64,41.61 27.58,41.61 27.57,41.61 27.1,41.34 27.51,40.99 27.6,40.98 27.64,40.9 27.64,40.71 27.6,40.63 27.51,40.62 27.1,40.3 27.51,39.98 27.6,39.96 27.64,39.88 27.64,39.7 27.6,39.62 27.51,39.6 27.1,39.28 27.51,38.96 27.6,38.94 27.64,38.86 27.64,38.68 27.6,38.6 27.51,38.58 27.1,38.27 27.51,37.95 27.6,37.93 27.64,37.85 27.64,35.75 27.58,35.65 27.47,35.68 26.75,36.4 26.75,42.55 26.79,42.63 26.88,42.65 27.3,42.97 26.88,43.28 26.79,43.3 26.75,43.38 26.75,45.46
DGND on L03_SIG1 (solid shape): outline of 324 points within 30.39,6.55 41.32,12.23
DGND on L03_SIG1 (solid shape): outline of 484 points within 57.92,40.45 73.41,56.17
DGND on L03_SIG1 (solid shape): outline of 554 points within 35.42,107.61 41.4,111.12
DGND on L03_SIG1 (solid shape): outline of 774 points within 17.87,6.55 41.5,27.38
DGND on L06_SIG2 (solid shape): 66.72,105.18 67.19,104.71 67.19,91.22 67.75,90.66 67.75,90.62 67.72,90.57 67.66,90.58 66.62,91.62 66.62,105.19
DGND on L06_SIG2 (solid shape): 37.14,47.58 37.16,47.47 37.07,47.41 31.92,47.41 31.59,47.74 31.57,47.85 31.66,47.91 36.81,47.91
DGND on L06_SIG2 (solid shape): 45.67,91.02 45.78,91.04 45.84,90.95 45.84,82.48 45.62,82.25 45.51,82.23 45.44,82.32 45.44,90.79
DGND on L06_SIG2 (solid shape): 61.37,23.83 61.46,23.77 61.44,23.66 60.57,22.79 60.57,22.47 60.12,22.02 60.05,22.02 59.95,22.08 59.97,22.19 60.1,22.32 60.1,22.65 61.28,23.83
DGND on L06_SIG2 (solid shape): 67.13,27.61 67.17,27.53 67.17,27.22 64.72,24.77 64.72,22.76 64.17,22.21 64.06,22.19 64,22.29 64,24.65 66.96,27.61 67.03,27.63
DGND on L06_SIG2 (solid shape): 32.87,97.8 32.91,97.81 32.99,97.79 33.03,97.72 33.41,97.34 33.41,92.75 33.34,92.65 33.23,92.67 32.71,93.2 32.71,97.71 32.75,97.78 32.83,97.81
DGND on L06_SIG2 (solid shape): 67.04,87.86 67.11,87.83 68.08,86.86 68.08,81.47 68.02,81.37 67.91,81.39 67.31,81.99 67.31,87.12 66.84,87.58 66.81,87.67 66.87,87.75 66.92,87.78 66.97,87.82
DGND on L06_SIG2 (solid shape): 24.27,83.8 24.32,83.71 24.32,80.75 26.03,79.04 26.03,74.93 26.86,74.1 26.89,74.03 26.85,73.95 26.78,73.87 26.75,73.76 26.74,73.74 25.18,72.18 25.07,72.16 25.01,72.25 25.01,78.11 23.85,79.27 23.85,83.67 23.89,83.75 23.97,83.77 24.07,83.77 24.17,83.8
DGND on L06_SIG2 (solid shape): 49.53,44.57 49.56,44.49 49.52,44.42 49.44,44.04 49.78,43.85 49.86,43.82 49.89,43.74 49.89,43.62 49.86,43.55 49.78,43.52 49.56,43.45 49.44,43.24 49.43,43.23 49.27,43.06 46.79,43.06 44.86,44.99 44.84,45.1 44.93,45.16 48.93,45.16
DGND on L06_SIG2 (solid shape): 38.05,45.85 38.08,45.74 37.98,45.68 37.71,45.68 37.62,45.72 37.61,45.82 37.3,46.26 36.99,45.82 36.98,45.72 36.9,45.68 33.18,45.68 32.14,46.72 32.12,46.83 32.21,46.89 37.01,46.89
DGND on L06_SIG2 (solid shape): 35.29,101.01 35.37,100.98 35.4,100.9 35.4,99.92 35.97,99.34 35.97,95.06 35.91,94.97 35.8,94.99 35.14,95.65 35.14,96.9 35.17,96.98 35.25,97.01 35.6,97.34 35.25,97.67 35.17,97.69 35.14,97.77 35.14,100.9 35.17,100.98 35.25,101.01
DGND on L06_SIG2 (solid shape): 16.75,102.12 16.96,101.88 17.27,101.93 17.29,101.94 17.43,101.94 17.57,101.8 17.59,101.69 17.49,101.63 15.52,101.63 15.19,101.3 15.52,100.96 16.31,100.96 16.4,100.9 16.38,100.79 16,100.41 15.1,100.41 14.53,100.98 14.53,101.42 13.96,101.99 13.94,102.1 14.04,102.16 16.75,102.16
DGND on L06_SIG2 (solid shape): 27.39,73.52 27.47,73.49 28.99,71.97 28.99,71.95 29.03,71.85 29.1,71.76 29.14,71.68 29.11,71.61 25.76,68.26 25.76,66.08 25.45,65.77 25.45,65.42 25.38,65.32 25.27,65.36 24.49,65.76 23.69,65.39 23.58,65.36 23.51,65.45 23.51,66.4 25.36,68.25 25.36,71.63 27.11,73.38 27.12,73.38 27.23,73.42 27.32,73.49
DGND on L06_SIG2 (solid shape): 56.28,104.06 56.28,101.27 55.12,100.11 55.01,100.09 54.94,100.18 54.94,100.38 55.71,101.14 55.32,101.53 55.39,101.59 55.53,101.73 55.58,101.82 55.6,101.92 55.6,102.12 55.58,102.22 55.53,102.3 55.36,102.46 55.34,102.5 55.36,102.54 55.53,102.71 55.58,102.79 55.6,102.89 55.6,103.09 55.58,103.19 55.53,103.28 55.36,103.44 55.34,103.48 55.36,103.52 55.53,103.69 55.58,103.77 55.6,103.87 55.6,104.35 55.84,104.35 55.9,104.36 55.96,104.38 55.96,104.38
DGND on L06_SIG2 (solid shape): 42.15,103.8 42.45,103.41 42.8,103.75 42.83,103.83 42.9,103.86 48.5,103.86 50.95,101.42 50.95,100.82 50.89,100.72 50.78,100.75 48.73,102.79 42.9,102.79 42.83,102.83 42.8,102.91 42.52,103.26 42.15,103.01 42.15,102.99 42.1,102.95 42,103.04 42,103.74 42,103.77 41.99,103.86 42.15,103.86
DGND on L06_SIG2 (solid shape): 14.18,100.49 14.21,100.54 14.26,100.52 14.89,99.9 16.21,99.9 16.85,100.53 17.6,100.53 18.69,99.44 19.23,99.44 19.32,99.38 19.3,99.26 19.17,99.14 19.15,99.13 18.93,98.99 18.88,98.73 18.86,98.64 18.78,98.61 17.54,98.61 17.46,98.64 17.44,98.73 17.12,99.14 16.8,98.73 16.78,98.64 16.7,98.61 16.01,98.61 14.18,100.44
DGND on L06_SIG2 (solid shape): 32.79,74.17 32.86,74.27 32.97,74.24 36.94,70.27 36.94,69.53 37.2,68.99 37.45,69.53 37.45,69.98 37.51,70.07 37.63,70.05 40.46,67.22 40.46,65.65 40.4,65.56 40.29,65.57 40.2,65.63 40.1,65.68 40.02,65.77 39.96,65.86 39.96,65.93 34.41,71.49 32.78,71.49 32.56,71.71 32.53,71.79 32.58,71.87 32.67,71.97 32.72,72.09 32.72,72.11 32.79,72.18
DGND on L06_SIG2 (solid shape): 50.57,18.07 50.53,18.02 50.52,18.02 50.34,17.89 50.28,17.68 50.25,17.61 50.18,17.57 50.1,17.57 50.1,17.63 49.8,18.03 49.44,17.68 49.41,17.61 49.34,17.57 48.38,17.57 48.3,17.61 48.27,17.68 48.01,18.03 47.63,17.8 47.62,17.77 47.14,17.77 47.06,17.81 47.05,17.91 47.07,17.98 47.08,18.06 47.1,18.14 47.18,18.17 50.47,18.17
DGND on L06_SIG2 (solid shape): 51.42,72.46 51.53,72.48 51.59,72.39 51.59,62.87 52.05,62.41 52.08,62.33 52.03,62.25 51.95,61.73 52.47,61.81 52.55,61.86 52.64,61.83 54.53,59.93 54.53,54.79 60.72,48.6 60.72,47.26 60.66,47.17 60.55,47.19 55.9,51.84 55.87,51.91 55.91,51.98 55.92,52.46 55.44,52.45 55.37,52.42 55.29,52.45 52.53,55.21 52.53,58.81 51.29,60.05 51.29,72.33
DGND on L06_SIG2 (solid shape): 65.25,24.58 65.36,24.6 65.42,24.5 65.42,19.99 65.09,19.65 64.99,19.65 64.91,19.69 64.89,19.78 64.57,20.18 64.24,19.78 64.22,19.69 64.15,19.65 63.62,19.65 63.38,19.41 63.27,19.39 63.21,19.48 63.21,19.6 64.19,20.58 64.26,20.61 64.33,20.58 64.88,20.72 64.5,21.14 64.42,21.16 64.38,21.24 64.38,21.7 65.23,22.55 65.23,24.56
DGND on L06_SIG2 (solid shape): 61.55,48.24 61.62,48.33 61.73,48.31 63.02,47.02 63.02,44.56 62.99,44.48 62.91,44.46 62.55,44.13 62.91,43.8 62.99,43.77 63.02,43.7 63.02,41.99 62.99,41.92 62.91,41.89 62.55,41.56 62.91,41.24 62.99,41.21 63.02,41.13 63.02,36.91 62.24,36.12 62.13,36.1 62.06,36.19 62.06,37.01 62.1,37.09 62.18,37.11 62.56,37.44 62.18,37.77 62.1,37.79 62.06,37.87 62.06,41.42 61.55,41.93 61.55,45.04 61.59,45.12 61.66,45.14 62.01,45.47 61.66,45.8 61.59,45.83 61.55,45.91 61.55,46.94 61.59,47.01 61.67,47.04 62.04,47.37 61.67,47.69 61.59,47.72 61.55,47.79
DGND on L06_SIG2 (solid shape): outline of 394 points within 62.67,89.51 66.97,103.34
DGND on L06_SIG2 (solid shape): outline of 591 points within 33.92,79.49 40.57,95.64
DGND on TOP: 17.15,103.54 17.15,102.68 19.54,102.68 19.78,102.91 19.78,103.54
DGND on TOP: 31.84,43.01 31.84,38.39 39.54,38.39 39.54,44.26 33.08,44.26
DGND on TOP: 17.59,29.18 17.59,23.78 31.42,23.78 31.42,29.8 26.52,29.8 26.52,24.9 21.29,24.9 21.29,30.67 17.26,30.67 17.12,30.53 17.12,29.65
DGND on TOP: 12.5,48.75 14.03,48.75 14.03,47.93 13.92,47.82 13.44,47.82 13.29,47.68 13.29,46.03 14.77,46.03 14.77,44.24 13.31,44.24 13.31,42.84 13.5,42.65 13.5,40.49 13.59,40.4 13.59,39.62 13.56,39.6 12.47,39.6 11.89,39.01 10.64,39.01 10.46,39.19 10.46,46.6 9.14,47.93 9.14,51.98 9.28,52.13 11.81,52.13 12.5,51.44
DGND on TOP: 18.17,106.63 18.17,105.3 18.3,105.17 19.48,105.17 19.63,105.31 19.63,105.66 19.79,105.82 21.25,105.82 21.33,105.9 21.33,106.47 21.14,106.66 18.2,106.66
DGND on TOP: 68.72,48.37 68.72,46.9 71.34,46.9 71.34,48.37
DGND on TOP: 81.75,54.69 81.67,54.77 81.67,61.3 81.01,61.96 81.01,63.23 83.21,63.23 83.21,54.69
DGND on TOP: 7.46,20.97 7.46,19.52 9.36,19.52 9.36,20.97
DGND on TOP: 42.02,55.87 42.02,57.54 46.32,57.54 46.32,55.87
DGND on BOTTOM: 21.77,37.77 21.77,39.42 22.45,39.42 22.95,39.91 23.65,39.91 23.65,40.59 24.21,40.59 24.21,37.36 23.93,37.08 22.45,37.08
DGND on BOTTOM: 28.6,29.74 28.6,26.47 31.72,26.47 31.72,29.74
DGND on BOTTOM: 16.14,39.7 16.14,35.97 15.66,35.48 14.88,35.48 14.52,35.12 14.52,34.51 14.47,34.46 12.74,34.46 12.74,35.26 12.42,35.57 12.42,39.52 12.6,39.7
DGND on BOTTOM: 9.36,55.61 12.26,55.61 12.26,51.24 13.09,51.24 13.73,50.61 13.73,47 13.3,46.57 13.3,44.13 13.57,43.85 13.57,42.98 13.45,42.86 13.45,40.3 13.07,39.91 10.68,39.91 9.31,41.29 9.31,43.58 8.83,44.05 8.83,45.63 9.13,45.93 9.13,47.16 9.01,47.28 7.01,47.28 6.9,47.39 6.9,47.77 6.96,47.84 8.34,47.84 9.36,48.85
DGND on BOTTOM: 35.04,52.03 35.04,36.86 40.62,36.86 40.62,52.03
DGND on BOTTOM: 77.84,64.99 77.84,63.75 77.98,63.62 80.23,63.62 80.35,63.5 80.35,62.33 80.48,62.19 81.46,62.19 81.69,61.97 81.69,54.74 81.82,54.61 83.19,54.61 83.19,60.33 83.19,60.33 83.19,64.59 82.66,65.12 77.98,65.12
DGND on BOTTOM: 16.04,111.21 16.04,110.8 16.06,110.78 16.55,110.78 16.8,111.03 17.76,111.03 17.76,111.46 17.66,111.57 16.39,111.57
DGND on BOTTOM: 61.25,83.78 61.25,85.23 61.02,85.46 59.65,85.46 59.65,86.55 59.72,86.63 60.99,86.63 61.07,86.55 62.26,86.55 62.31,86.5 62.31,84.74 63.39,84.74 63.54,84.59 63.54,84.04 63.4,83.91 62.47,83.91 62.35,83.78
DGND on BOTTOM: 47.16,9.94 47.16,7 49.7,7 51.02,8.32 51.02,10.73 50.36,11.39 47.56,11.39 47.18,11.01 47.18,9.94
DGND on BOTTOM: 11.25,32.34 11.25,29.86 14.82,29.86 14.91,29.95 14.91,32.19 14.76,32.34
DGND on BOTTOM: 24.43,31.45 24.43,29.62 26.26,29.62 26.26,31.45
DGND on BOTTOM: 9.28,26.73 9.28,24.82 9.43,24.67 11.08,24.67 11.31,24.9 11.31,26.65 11.21,26.75 9.31,26.75
DGND on BOTTOM: 9.51,38.01 9.51,35.37 11.9,35.37 11.9,38.01
DGND on BOTTOM: 73.89,54.88 73.89,51.13 73.97,51.04 74.79,51.04 74.84,51.09 74.84,54.88
DGND on L02GND01: 0.51,154.67 84.49,154.67 84.49,5.59 0.51,5.59
DGND on L04_PWR01: 0.51,154.67 84.49,154.67 84.49,5.59 0.51,5.59 ; 14 cut-outs
DGND on L07_GND02: 0.53,154.64 84.47,154.64 84.47,5.61 0.53,5.61 ; 2 cut-outs
VBUS_5V0_TYPEA1 on TOP: 68.07,71.28 68.07,67.79 73.91,67.79 73.91,69.6 70.79,69.6 69.1,71.28
VBUS_5V0_TYPEA1 on BOTTOM: 68.17,83.01 68.17,67.56 74,67.56 74,70.87 73.97,70.9 70.28,70.9 70.28,83.01
VBUS_TYPEC1 on TOP: 8.31,43.61 7.43,43.61 7.35,43.68 7.35,43.98 7.24,44.09 6.92,44.09 6.83,44 6.83,43.85 5.91,43.85 5.91,43.55 6.83,43.55 6.83,43.28 6.93,43.18 7.23,43.18 7.34,43.29 8.31,43.29
VBUS_TYPEC1 on TOP: 14.34,49.77 16.4,49.77 16.4,47.67 16.29,47.56 15.43,47.56 15.18,47.81 14.59,47.81 14.34,48.06
VBUS_TYPEC1 on TOP: 5.87,46.36 6.75,46.36 6.83,46.43 6.83,46.73 6.94,46.84 7.26,46.84 7.35,46.75 7.35,46.6 8.27,46.6 8.27,46.3 7.35,46.3 7.35,46.03 7.25,45.93 6.95,45.93 6.84,46.04 5.87,46.04
VBUS_TYPEC1 on BOTTOM: 14.01,50.18 15.93,50.18 17.36,48.75 17.36,47.23 16.56,47.23 16.23,47.57 14.01,47.57
VBUS_TYPEC1 on BOTTOM: 5.11,46.74 9.04,46.74 9.04,46.05 8.56,46.05 8.56,43.7 8.94,43.7 8.94,43.03 5.11,43.03
VBUS_TYPEC1 on L04_PWR01: 16.62,49.89 16.62,47.66 14.46,47.66 14.46,45.88 12.18,45.88 10.78,44.48 10.78,42.2 4.84,42.2 4.84,47.43 7.3,49.89
VBUS_TYPEC1 on L05_PWR02: 16.62,49.89 16.62,47.91 16.37,47.66 14.46,47.66 14.46,45.88 12.18,45.88 10.78,44.48 10.78,42.2 4.84,42.2 4.84,47.46 7.27,49.89
VBUS_TYPEC2 on TOP: 8.11,27.77 8.11,28.29 7.42,28.29 7.32,28.2 7.32,28 7.25,27.92 6.89,27.92 6.83,27.98 6.83,28.55 5.91,28.55 5.91,28.85 6.83,28.85 6.83,29 6.92,29.09 7.24,29.09 7.35,28.98 7.35,28.68 7.43,28.61 8.11,28.61 8.11,29.02 9.33,29.02 9.33,27.77
VBUS_TYPEC2 on TOP: 5.87,31.36 6.75,31.36 6.83,31.43 6.83,31.73 6.94,31.84 7.26,31.84 7.35,31.75 7.35,31.6 8.27,31.6 8.27,31.3 7.35,31.3 7.35,31.03 7.25,30.93 6.95,30.93 6.84,31.04 5.87,31.04
VBUS_TYPEC2 on TOP: 13.64,43.89 16.35,43.89 16.35,42.95 13.64,42.95
VBUS_TYPEC2 on BOTTOM: 16.48,43.23 17.39,43.23 17.39,43.95 13.83,43.95 13.83,41.08 15.08,41.08 15.08,42.66 15.38,42.96 16.2,42.96
VBUS_TYPEC2 on BOTTOM: 15.56,30.44 15.56,29.62 10.54,29.62 10.33,29.83 10.33,31.96 5.2,31.96 5.2,27.33 5.6,26.92 11.28,26.92 13.59,24.61 14.66,24.61 15.72,23.55 23.98,23.55 23.98,28.63 21.95,28.63 20.32,27 17.78,27 17.55,27.23 17.55,30.44
VBUS_TYPEC2 on L04_PWR01: 14.87,44.5 14.87,40.06 24.5,40.06 25.32,40.89 25.32,42.68 25.93,43.29 50.17,43.29 50.17,64.68 47.91,64.68 47.91,48.61 46.32,47.02 23.28,47.02 23.28,44.5
VBUS_TYPEC2 on L05_PWR02: 4.94,27.72 16.24,27.72 17.26,28.74 17.26,31.53 16.11,32.67 16.11,39.15 14.46,40.8 14.46,42.83 16.37,42.83 16.37,45.37 12.43,45.37 11.54,44.48 11.54,33.94 9.89,32.29 4.94,32.29
VCC1V1 on TOP: 16.75,72.81 21.07,72.81 21.07,77.5 16.75,77.5
VCC1V8_CLKBUF on TOP: 59.46,141.62 59.46,139.79 60.84,139.79 60.84,141.62
VCC1V8_CLKBUF on L04_PWR01: 50.45,136.36 51.83,136.36 52.31,136.84 52.31,139.81 52.38,139.89 60.46,139.89 60.46,141.77 60.33,141.89 50.71,141.89 50.45,141.64
VCC1V8_SYS on TOP: 18.91,84.84 18.91,79.66 22.97,79.66 22.97,83.09 21.57,83.09 21.57,84.74 21.88,85.05 22.95,85.05 23,85.1 23,86.08 22.95,86.14 21.4,86.14 21.14,85.89 19.95,85.89
VCC1V8_SYS on BOTTOM: 44.59,69.6 44.59,68.61 47.94,68.61 47.94,72.75 47.99,72.81 48.9,72.81 49.01,72.91 49.01,74.84 49.69,75.52 49.69,75.98 49.49,76.18 48.93,76.18 48.83,76.28 48.83,77.5 49.21,77.89 49.21,78.88 49.08,79 48.42,79 48.22,79.21 48.22,79.66 48.07,79.82 46.09,79.82 46.09,71.1
VCC1V8_SYS on BOTTOM: 30.34,119.08 30.34,118.56 35.32,118.56 35.32,119.08
VCC1V8_SYS on L04_PWR01: 22.35,140.64 36.99,140.64 36.99,135.69 31.14,135.69 31.14,125.96 28.08,125.96 28.08,135.97 22.35,135.97
VCC1V8_SYS on L05_PWR02: outline of 94 points within 3.02,36.03 70.74,151.59
VCC1V8_SYS on L06_SIG2: 12.56,76.82 12.56,76.06 14.08,74.54 18.17,74.54 18.58,74.94 18.58,79.31 21.24,81.97 21.24,83.6 19.72,83.6 18.91,82.79 18.91,81.77 17.59,80.45 17.59,76.66 17.26,76.34 16.04,76.34 15.41,76.97 12.71,76.97
VCC3V3_EXP on BOTTOM: 7.53,129.17 10.32,129.17 10.32,126.09 7.53,126.09
VCC3V3_EXP on BOTTOM: 19.29,132.37 19.29,133.26 19.8,133.26 19.8,133.89 22.16,133.89 22.23,133.82 22.23,133.31 22.2,133.27 20.43,133.27 20.43,132.37
VCC3V3_EXP on L05_PWR02: 8.32,131.14 8.32,127.85 9.77,126.4 28.88,126.4 31.18,128.7 33.96,128.7 37.83,132.57 37.83,133.88 37.82,133.87 37.57,134.12 19.01,134.12 17.25,132.36 9.54,132.36
VCC3V3_PRU on BOTTOM: 12.41,55.56 15.28,55.56 15.28,52.26 14.74,51.71 14.29,51.71 14.29,52.14 14.29,53.6 12.41,53.6
VCC3V3_TA on BOTTOM: 75.24,14.1 75.24,16.11 73.34,16.11 73.19,15.96 73.18,15.96 73.18,14.55 73.32,14.41 74.06,14.41 74.18,14.28 74.18,14.1
VCC3V3_TA on BOTTOM: 48.12,16.04 48.12,13.5 47.36,12.74 46.64,12.74 46.64,12.01 47.32,12.01 47.49,11.85 50.97,11.85 50.97,13.4 50.13,13.4 49.8,13.73 49.8,16.04
VCC3V3_TA on L05_PWR02: 73.31,16.3 74.6,16.3 75.05,15.86 75.05,11.09 73.57,9.62 63.63,9.62 62.72,10.53 57.69,10.53 57,9.83 47.92,9.83 47.33,10.42 47.33,13.07 48.06,13.81 51.03,13.81 51.59,13.25 51.59,12.17 52.11,11.64 54.69,11.64 56.33,13.28 63,13.28 64.29,11.99 71.44,11.99 72.95,13.5 72.95,15.95
VCC3V3_XDS on TOP: 71.38,18.64 71.38,16.54 73.33,16.54 73.33,18.64
VCC3V3_XDS on BOTTOM: 71.97,25.74 75.22,25.74 75.22,24.39 72.76,24.39 71.97,25.18
VCC3V3_XDS on L05_PWR02: outline of 91 points within 43.9,5.93 79.18,28.74
VCC3V3_XDS_TA on TOP: 73.76,18.4 73.76,16.54 75.12,16.54 75.82,17.24 75.82,18.68 74.03,18.68
VCC3V3_XDS_TA on TOP: 40.86,27.34 42.68,27.34 43.16,27.82 43.16,34.08 40.74,34.08 40.74,27.46
VCC3V3_XDS_TA on BOTTOM: 38.39,35.01 38.39,33.08 38.49,32.98 38.74,32.98 39.1,33.33 42.86,33.33 43.01,33.49 43.01,34.68 42.71,34.98 38.41,34.98
VCC3V3_XDS_TA on BOTTOM: 72.63,12.45 72.55,12.53 72.55,13.98 72.61,14.04 72.61,15.95 72.6,15.96 72.6,17.48 73.26,18.14 73.26,18.65 73.34,18.73 74.25,18.73 74.26,18.72 75.81,18.72 75.81,16.76 73.22,16.76 72.87,16.42 72.87,16.11 72.96,16.11 73.03,16.04 73.03,14.05 73.89,14.05 74,13.94 74,12.58 73.87,12.45
VCC3V3_XDS_TA on L05_PWR02: 73.8,18.8 75.96,18.8 76.46,18.3 76.46,17.62 75.55,16.71 73.1,16.71 72.52,16.13 72.52,13.57 71.04,12.09 64.68,12.09 62.37,14.41 57.08,14.41 53.5,17.99 53.5,21.19 52.85,21.84 52.85,23.92 51.75,25.03 45.15,25.03 44.46,25.71 41.69,25.71 41.03,25.05 39.05,25.05 38.82,25.28 37.32,25.28 36.94,24.9 32.95,24.9 32.65,25.21 32.65,25.97 33.33,26.65 38.57,26.65 39.91,28 44.18,28 44.21,27.97 47.96,27.97 49.6,29.61 51,29.61 52.38,30.99 62.18,30.99 62.18,28.85 55.51,28.85 55.51,20.44 55.69,20.26 55.7,20.26 56.42,19.53 57.53,19.53 58.3,20.3 59.7,20.3 59.93,20.07 59.93,18.42 61.25,18.42 62.59,17.09 67.3,17.09 67.8,16.58 67.8,13.39 69.65,13.39 70.25,14 70.25,16.74 70.37,16.86 71.95,16.86 72.37,17.27 72.86,17.77 73.33,17.77 73.64,18.08 73.64,18.65
VCC5V0_EXP on BOTTOM: 7.86,133.05 7.86,129.73 12.94,129.73 12.94,133.05
VCC_0V85 on TOP: 12.18,77.12 12.18,75.09 11.16,74.08 11.16,70.27 12.56,70.27 12.56,77.12
VCC_3V3_AUD on BOTTOM: 68.19,45.37 69.94,45.37 69.94,43.44 68.19,43.44
VCC_3V3_FT4232 on BOTTOM: 11.82,13.52 11.82,11.44 11.27,11.44 11.27,10.55 13.04,10.55 13.91,11.41 13.91,13.52
VCC_3V3_FT4232 on L05_PWR02: 10.37,24.9 11.19,24.9 11.36,25.08 14.67,25.08 17.71,22.03 24.85,22.03 26.1,23.28 29.27,23.28 29.58,22.97 29.58,22.18 26.81,19.41 23.86,19.41 21.9,17.46 17.71,17.46 16.72,16.47 16.72,13.24 17.43,12.53 20.63,12.53 22.82,14.72 28.23,14.72 29.09,15.58 30.62,15.58 31.07,15.12 31.07,13.75 29.02,11.69 29.02,9.94 26.22,7.15 25.79,7.15 24.55,5.9 14.11,5.9 9.69,10.32 9.69,24.21
VCC_3V3_MAIN on TOP: 40.37,55.66 40.37,46.26 44.69,46.26 44.69,51.8 44.81,51.67 44.81,52.97 45.07,53.22 45.07,53.22 45.07,55.66
VCC_3V3_MAIN on TOP: 1.63,85.98 1.63,89.1 7.58,89.1 7.58,86.87 6.88,86.87 6.88,87.4 6.68,87.6 5.11,87.6 4.95,87.45 4.95,85.98
VCC_3V3_MAIN on TOP: 12.18,85.38 12.18,81.82 13.57,81.82 13.57,82.58 13.07,83.09 13.07,85.38
VCC_3V3_MAIN on BOTTOM: 40.64,52.36 40.64,37.16 43.79,37.16 44.66,38.03 44.66,51.99 44.29,52.36
VCC_3V3_MAIN on L05_PWR02: 12.8,83.61 15.73,80.68 16.37,80.68 21.3,75.74 34.88,75.74 46.09,64.54 46.09,46.39 41.51,46.39 41.51,58.45 29.36,70.61 18.05,70.61 9.3,79.37 9.3,83.13 6.68,85.75 6.68,88.54 9.32,88.54 12.8,85.06
VCC_3V3_SYS on TOP: 17.64,90.71 17.64,86.98 15.6,86.98 15.6,86.09 17.71,86.09 18.06,86.43 19.42,86.43 19.42,90.71
VCC_3V3_SYS on TOP: 74.11,153.15 74.11,147.82 76.77,147.82 76.77,147.83 76.77,153.15
VCC_3V3_SYS on TOP: 61.25,49.26 61.25,47.12 61.35,47.02 62.33,47.02 62.45,47.15 62.45,49.23 62.38,49.31 61.3,49.31
VCC_3V3_SYS on TOP: 46.47,54.64 46.47,58.17 51.17,58.17 51.17,54.64
VCC_3V3_SYS on TOP: 41.36,137.02 41.36,135.75 44.26,135.75 44.28,135.72 44.28,135.17 45.1,135.17 45.1,137.02
VCC_3V3_SYS on TOP: 27.71,92.05 26.47,92.05 26.47,90.81 26.65,90.63 27.71,90.63
VCC_3V3_SYS on BOTTOM: 36.48,139.33 36.48,138.95 36.53,138.9 37.2,138.9 37.2,139.23 37.32,139.35 37.98,139.35 38.16,139.53 38.16,140.19 37.02,140.19 37.02,139.33
VCC_3V3_SYS on BOTTOM: 10.98,64.32 10.98,61.86 11.57,61.27 15.31,61.27 15.31,63.41 13.88,63.41 12.97,64.32
VCC_3V3_SYS on BOTTOM: 14.25,110.95 14.29,110.91 15.17,110.91 15.28,110.8 15.83,110.8 15.86,110.84 15.86,111.04 15.82,111.09 15.09,111.09 15.02,111.16 15.02,111.78 14.25,111.78
